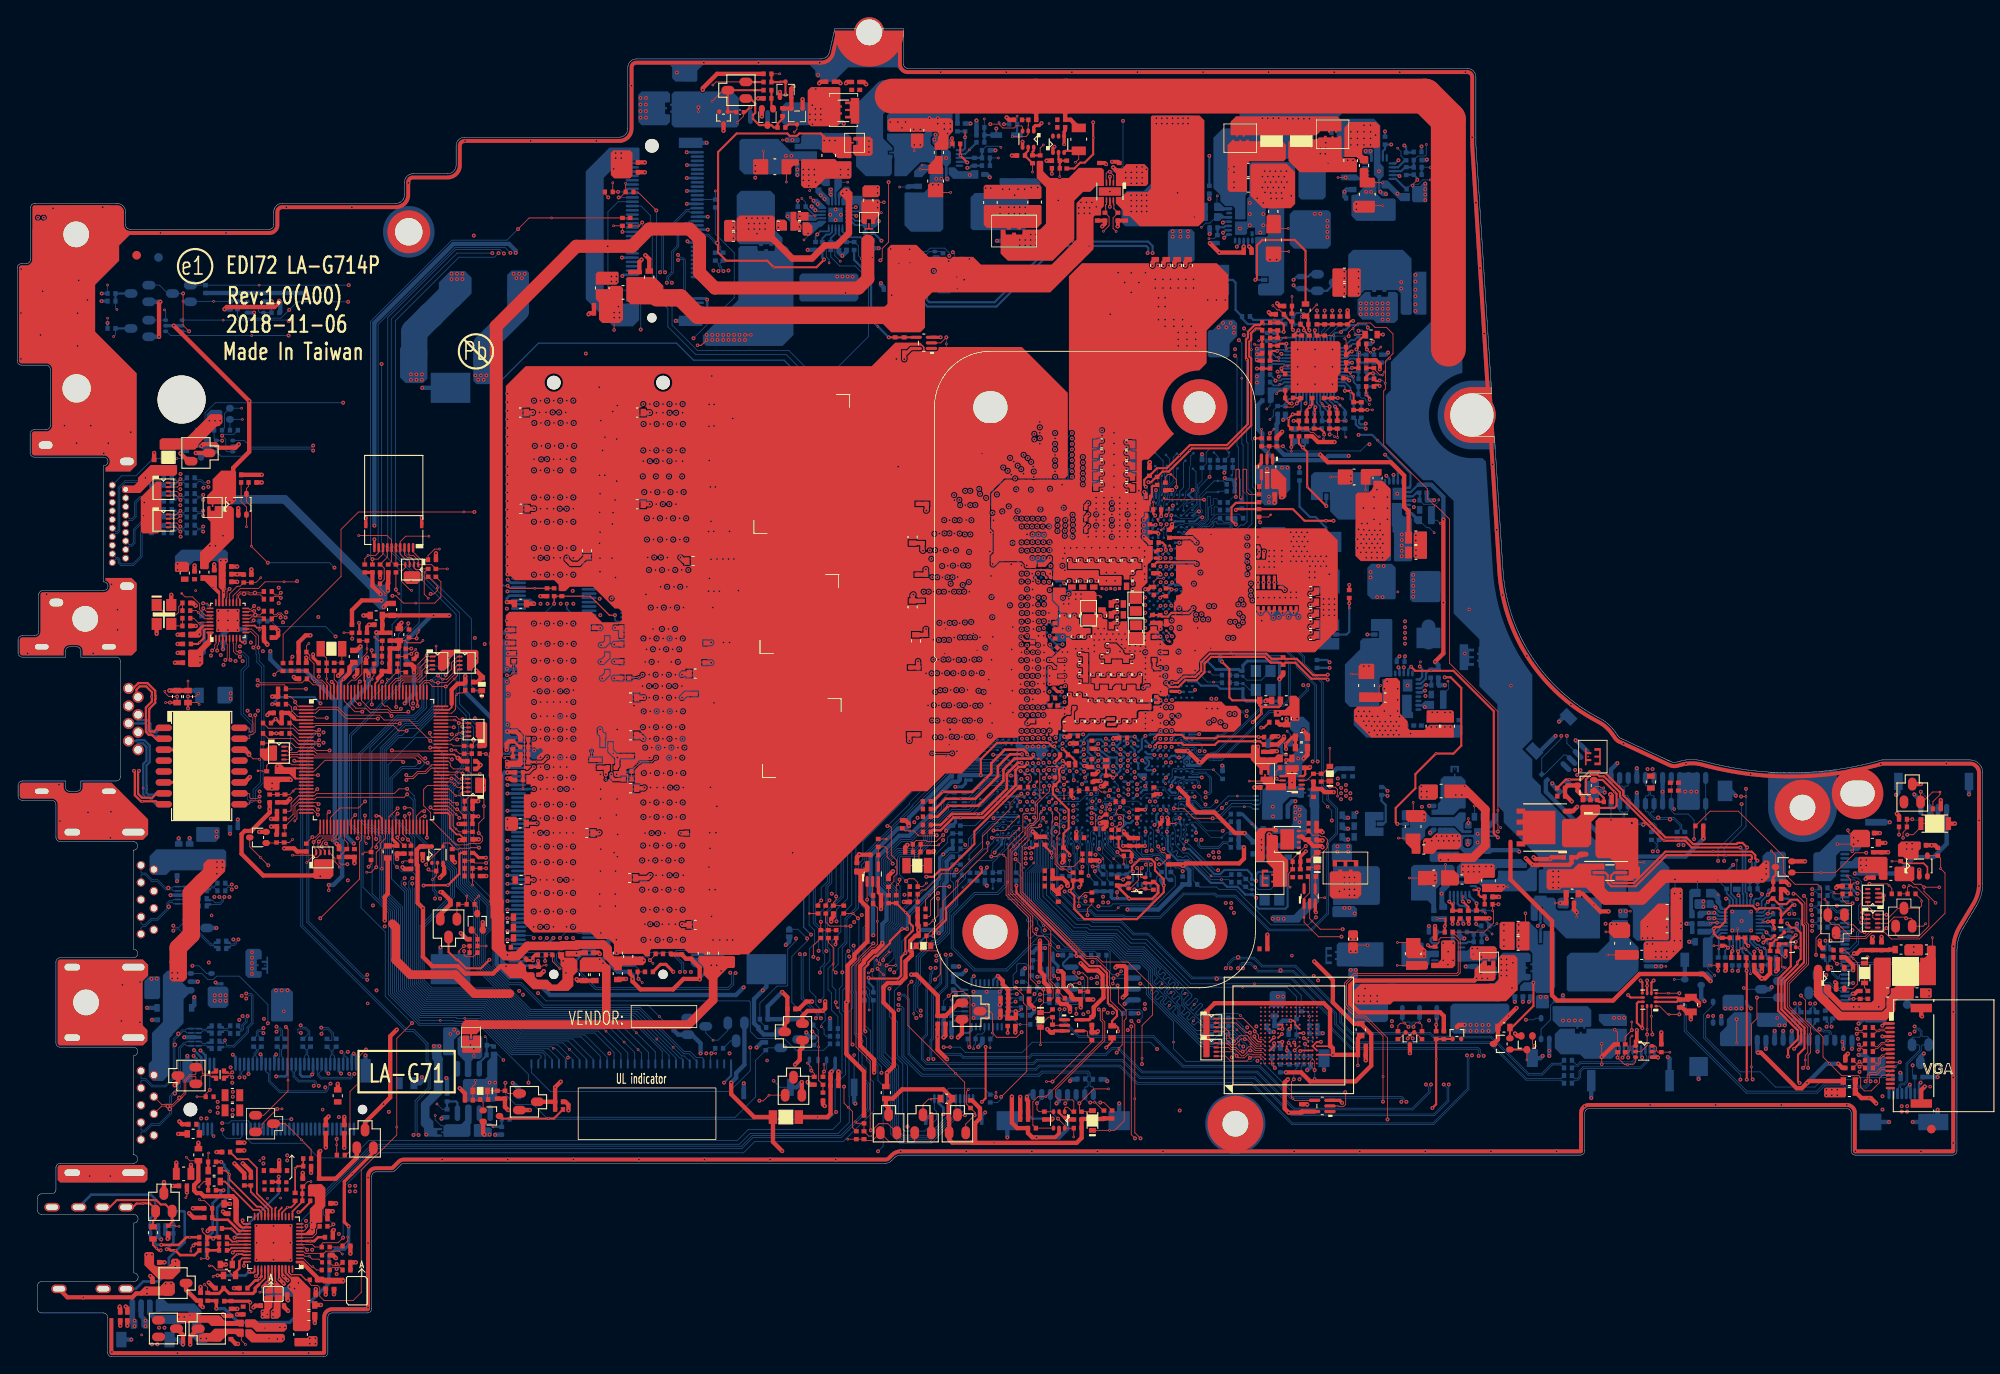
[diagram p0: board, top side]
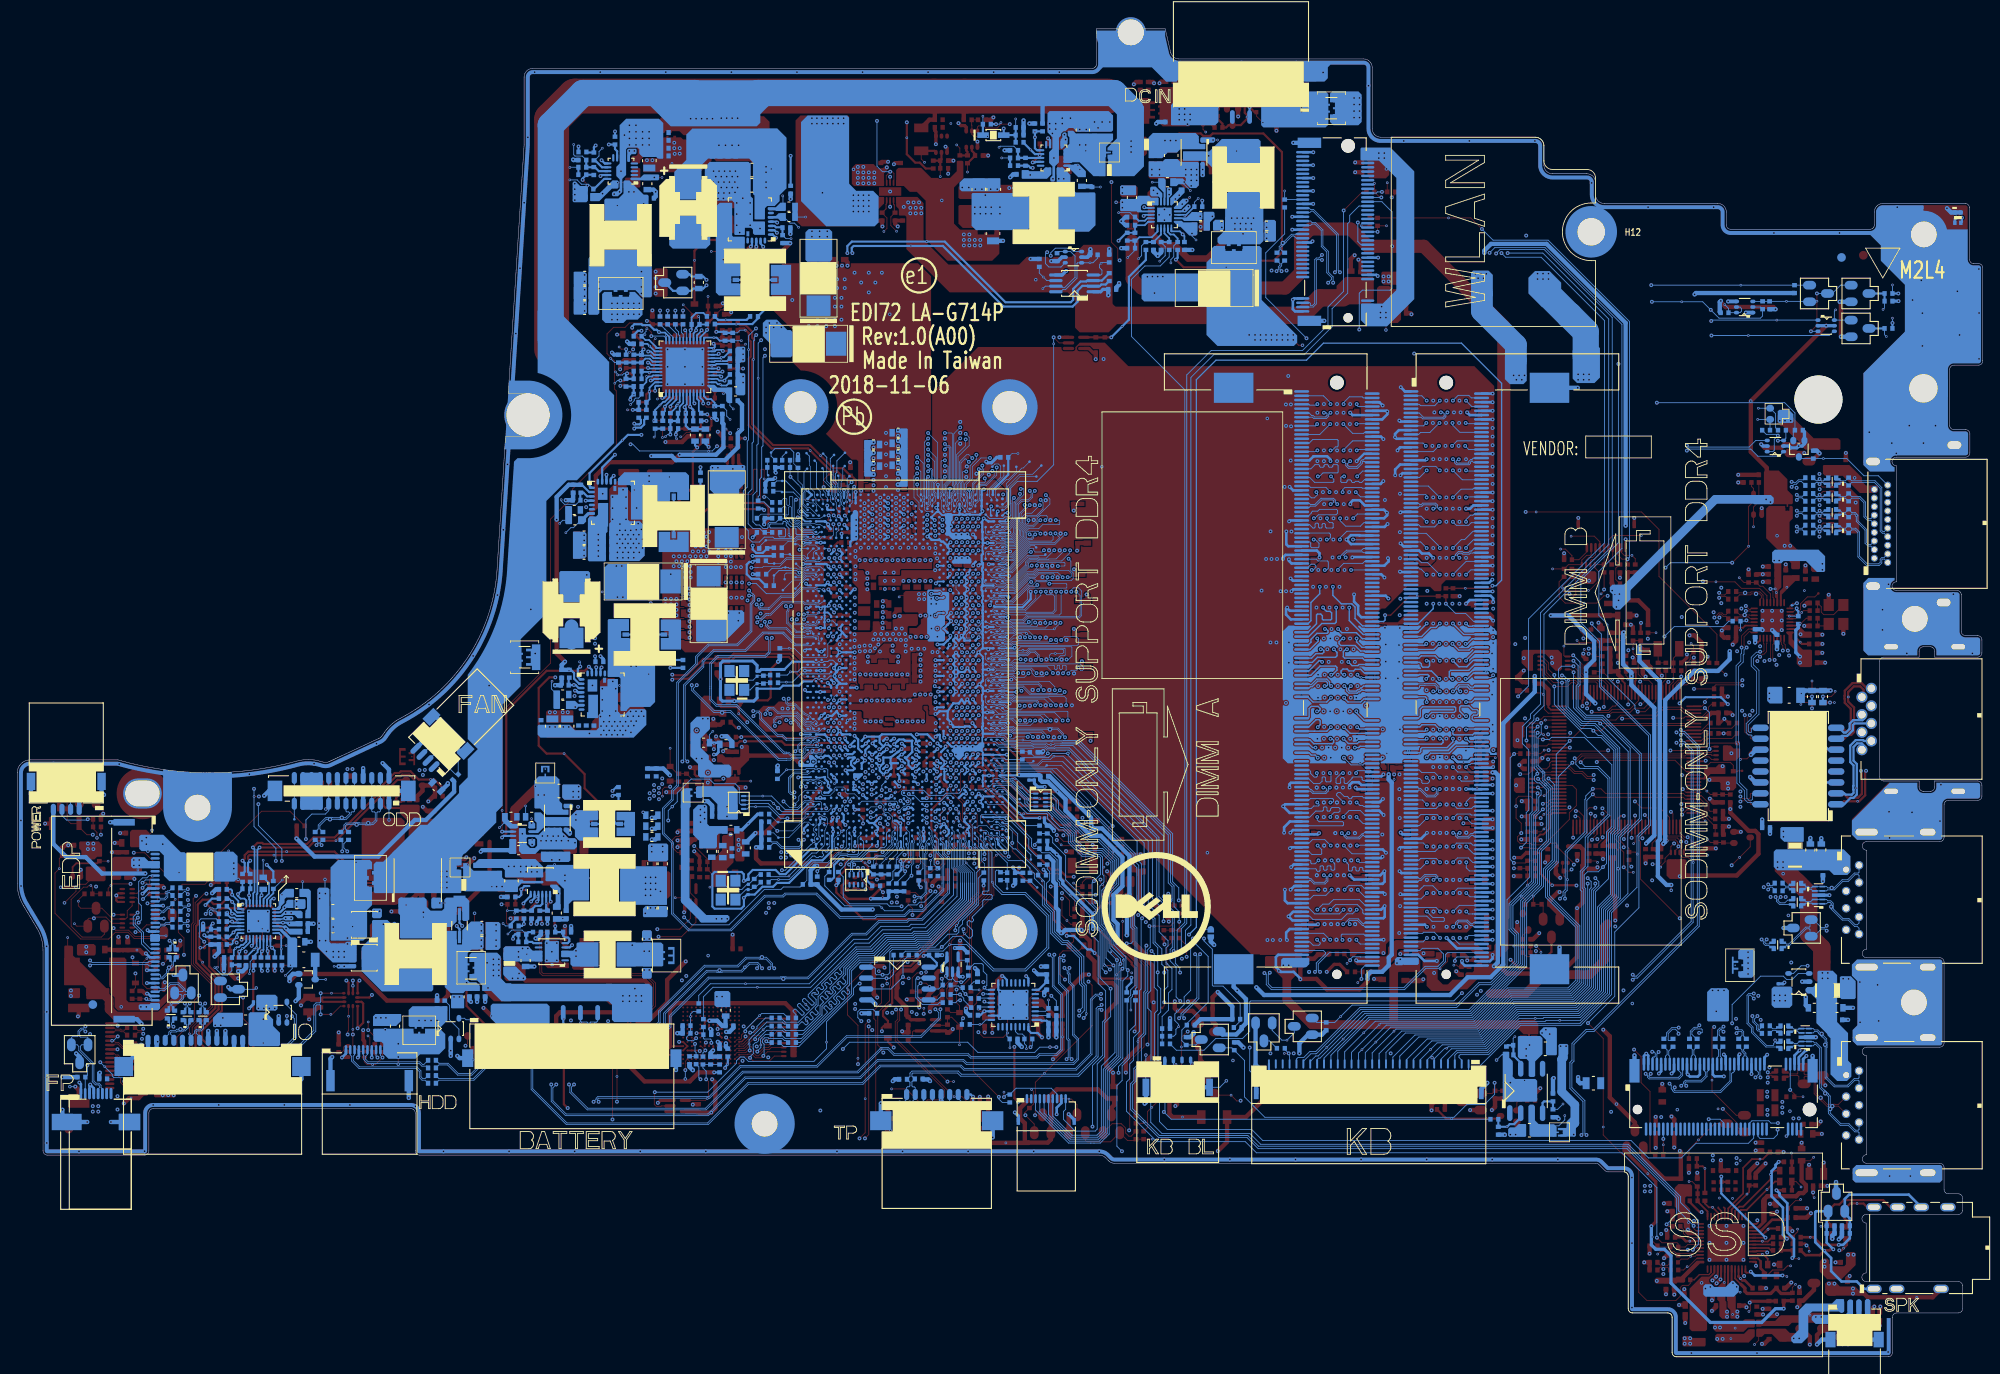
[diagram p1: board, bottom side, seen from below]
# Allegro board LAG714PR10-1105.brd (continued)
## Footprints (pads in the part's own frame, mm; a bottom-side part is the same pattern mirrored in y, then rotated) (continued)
SN74AHC1G08DCKR_SC70-5
  oval 0.381x1.295 smd: 1(0,0.15) 2(0.65,0.15) 3(1.3,0.15) 4(1.3,1.89) 5(0,1.89)
SOLDER_PREFORMS_0603-NPM
  rect 1.118x1.397 smd: 1(0,0) 2(1.422,0)
SW_TST71-N-220-T170-S017_2P
  rect 0.61x1.499 smd: 1(0,0) 2(3.2,0)
SY6288C20AAC_SOT23-5
  oval 0.559x0.787 smd: 1(0,0) 2(0.95,0) 3(1.9,0) 4(1.9,2.4) 5(0,2.4)
SY6288D20AAC_SOT23-5
  oval 0.559x0.787 smd: 1(0,0) 2(0.95,0) 3(1.9,0) 4(1.9,2.4) 5(0,2.4)
SY8286BRAC_QFN20_3X3
  oval 0.889x0.254 smd: 1(0,0) 2(0,-0.45) 3(0,-0.9) 4(0,-1.35) 5(0,-1.8) 11(3.1,-1.8) 12(3.1,-1.35) 13(3.1,-0.9) 14(3.1,-0.45) 15(3.1,0)
  oval 0.254x0.889 smd: 6(0.65,-2.45) 7(1.1,-2.45) 8(1.55,-2.45) 9(2,-2.45) 10(2.45,-2.45) 16(2.45,0.65) 17(2,0.65) 18(1.55,0.65) 19(1.1,0.65) 20(0.65,0.65)
  rect 0.991x0.991 smd: 21(1.55,-0.9)
SY8288CRAC_QFN20_3X3
  oval 0.889x0.254 smd: 1(0,0) 2(0,-0.45) 3(0,-0.9) 4(0,-1.35) 5(0,-1.8) 11(3.1,-1.8) 12(3.1,-1.35) 13(3.1,-0.9) 14(3.1,-0.45) 15(3.1,0)
  oval 0.254x0.889 smd: 6(0.65,-2.45) 7(1.1,-2.45) 8(1.55,-2.45) 9(2,-2.45) 10(2.45,-2.45) 16(2.45,0.65) 17(2,0.65) 18(1.55,0.65) 19(1.1,0.65) 20(0.65,0.65)
  rect 0.991x0.991 smd: 21(1.55,-0.9)
TAI-T_HCB2012KF-121T50_2P
  rect 0.813x1.397 smd: 1(0,0) 2(1.702,0)
THGBMBG8D4KBAIRNHDI_VFBGA_153P
  round 0.229 smd: A1(0,0) A2(0.5,0) A3(1,0) A4(1.5,0) A5(2.001,0) A6(2.501,0) A7(3.001,0) A8(3.501,0) A9(4.001,0) A10(4.501,0) A11(5.001,0) A12(5.501,0) A13(6.002,0) A14(6.502,0) B1(0,-0.5) B2(0.5,-0.5) B3(1,-0.5) B4(1.5,-0.5) B5(2.001,-0.5) B6(2.501,-0.5) B7(3.001,-0.5) B8(3.501,-0.5) B9(4.001,-0.5) B10(4.501,-0.5) B11(5.001,-0.5) B12(5.501,-0.5) B13(6.002,-0.5) B14(6.502,-0.5) C1(0,-1) C2(0.5,-1) C3(1,-1) C4(1.5,-1) C5(2.001,-1) C6(2.501,-1) C7(3.001,-1) C8(3.501,-1) C9(4.001,-1) C10(4.501,-1) C11(5.001,-1) C12(5.501,-1) C13(6.002,-1) C14(6.502,-1) D1(0,-1.5) D2(0.5,-1.5) D3(1,-1.5) D4(1.5,-1.5) D12(5.501,-1.5) D13(6.002,-1.5) D14(6.502,-1.5) E1(0,-2.001) E2(0.5,-2.001) E3(1,-2.001) E5(2.001,-2.001) E6(2.501,-2.001) E7(3.001,-2.001) E8(3.501,-2.001) E9(4.001,-2.001) E10(4.501,-2.001) E12(5.501,-2.001) E13(6.002,-2.001) E14(6.502,-2.001) F1(0,-2.501) F2(0.5,-2.501) F3(1,-2.501) F5(2.001,-2.501) F10(4.501,-2.501) F12(5.501,-2.501) F13(6.002,-2.501) F14(6.502,-2.501) G1(0,-3.001) G2(0.5,-3.001) G3(1,-3.001) G5(2.001,-3.001) G10(4.501,-3.001) G12(5.501,-3.001) G13(6.002,-3.001) G14(6.502,-3.001) H1(0,-3.501) H2(0.5,-3.501) H3(1,-3.501) H5(2.001,-3.501) H10(4.501,-3.501) H12(5.501,-3.501) H13(6.002,-3.501) H14(6.502,-3.501) J1(0,-4.001) J2(0.5,-4.001) J3(1,-4.001) J5(2.001,-4.001) J10(4.501,-4.001) J12(5.501,-4.001) J13(6.002,-4.001) J14(6.502,-4.001) K1(0,-4.501) K2(0.5,-4.501) K3(1,-4.501) K5(2.001,-4.501) K6(2.501,-4.501) K7(3.001,-4.501) K8(3.501,-4.501) K9(4.001,-4.501) K10(4.501,-4.501) K12(5.501,-4.501) K13(6.002,-4.501) K14(6.502,-4.501) L1(0,-5.001) L2(0.5,-5.001) L3(1,-5.001) L12(5.501,-5.001) L13(6.002,-5.001) L14(6.502,-5.001) M1(0,-5.501) M2(0.5,-5.501) M3(1,-5.501) M4(1.5,-5.501) M5(2.001,-5.501) M6(2.501,-5.501) M7(3.001,-5.501) M8(3.501,-5.501) M9(4.001,-5.501) M10(4.501,-5.501) M11(5.001,-5.501) M12(5.501,-5.501) M13(6.002,-5.501) M14(6.502,-5.501) N1(0,-6.002) N2(0.5,-6.002) N3(1,-6.002) N4(1.5,-6.002) N5(2.001,-6.002) N6(2.501,-6.002) N7(3.001,-6.002) N8(3.501,-6.002) N9(4.001,-6.002) N10(4.501,-6.002) N11(5.001,-6.002) N12(5.501,-6.002) N13(6.002,-6.002) N14(6.502,-6.002) P1(0,-6.502) P2(0.5,-6.502) P3(1,-6.502) P4(1.5,-6.502) P5(2.001,-6.502) P6(2.501,-6.502) P7(3.001,-6.502) P8(3.501,-6.502) P9(4.001,-6.502) P10(4.501,-6.502) P11(5.001,-6.502) P12(5.501,-6.502) P13(6.002,-6.502) P14(6.502,-6.502)
TPC12
  round 0.305 smd: 1(0,0)
TPCA8059-H_PPAK56-8-5
  oval 0.61x1.27 smd: 1(0,0) 2(1.27,0) 3(2.54,0) 4(3.81,0)
  custom 1.105x1.105 smd: 5(1.905,3.715)
TPS22961DNYR_WSON8
  oval 0.305x0.508 smd: 1(0,0) 2(0.65,0) 3(1.3,0) 4(1.95,0) 5(1.95,2.7)
  oval 1.6x0.508 smd: 6(0.65,2.7)
  rect 2.388x1.6 smd: 7(0.975,1.35)
TPS22967DSGR_SON8_2X2-S
  oval 0.254x0.787 smd: 1(0,0) 2(0.5,0) 3(1,0) 4(1.5,0) 5(1.5,2.2) 6(1,2.2) 7(0.5,2.2) 8(0,2.2)
  rect 1.6x0.889 smd: 9(0.75,1.1)
TVNST52302AB0_SOT523-3
  oval 0.508x0.559 smd: 1(0,0) 2(-0.5,-1.4) 3(0.5,-1.4)
W25Q128FVSIQ_SO8
  oval 0.635x1.676 smd: 1(0,0) 2(1.27,0) 3(2.54,0) 4(3.81,0) 5(3.81,7.25) 6(2.54,7.25) 7(1.27,7.25) 8(0,7.25)
Y_7V25000014_4P
  rect 1.397x1.194 smd: 1(0,0) 2(2.2,0) 3(2.2,1.7) 4(0,1.7)
Y_X1A000141000200_2P
  rect 0.991x1.803 smd: 1(0,0) 2(2.5,0)
Y_X3G024000DC1H_4P
  rect 1.397x1.194 smd: 1(0,0) 2(2.2,0) 3(2.2,1.7) 4(0,1.7)
YUQIU_PJ753-F07J1BE-B_7P-T
  oval 0.991x1.803 hole 0.61x1.397: 1(0,0) 2(9.5,-5.5) 3(9.5,-8.6) 4(0,-7.8) 5(9.5,0) 6(9.5,-2.75) 7(0,-2.65)

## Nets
0.6V_DDR_VTT_ON: CC90.1 PRM09.1 RC9.2 UC2.4
1.0V_VCCST_EN: CZ1.1 DZ5.2 RZ1.2 UZ1.3
1.2V_VTT_PWRGD: PRM06.2 PUM01.10 RC106.1
2.5V_VIN: PC2501.1 PJP2501.2 PU2501.3
3.3V_TS_EN: R72.1 U3.4 UC1.AP5
3V_FB: PC315.1 PR307.2 PR308.1 PU301.13
3V_SN: PC309.1 PR305.2
3V_VIN: PC301.1 PC302.1 PC303.1 PC304.1 PC305.1 PC306.1 PJP301.2 PL311.2 PU301.2 PU301.3 PU301.4 PU301.5
5V_FB: PC517.1 PR510.2 PR511.1 PU501.13
5V_SN: PC509.1 PR505.2
5V_VIN: PC501.1 PC502.1 PC503.1 PC504.1 PC505.1 PC506.1 PJP501.2 PL511.2 PU501.2 PU501.3 PU501.4 PU501.5
+0.6V_DDR_VTT: CD5.1 CD6.1 CD7.1 CD8.1 CD31.1 CD32.1 CD33.1 CD34.1 JDIMM1.258 JDIMM2.258 PJPM03.2
+0.6VSP: PCM20.1 PCM21.1 PJPM03.1 PUM01.2 PUM01.20
+1.0V_AMPHYPLL: CC75.1 RC169.2 UC1.K15 UC1.L15
+1.0V_APLL: CC82.1 L1.2 UC1.V15
+1.0V_CLK2: CC76.1 RC170.2 UC1.K19
+1.0V_CLK4: CC84.1 RC173.2 UC1.N20
+1.0V_CLK5: CC77.1 RC76.2 RC171.2 UC1.L19
+1.0V_MPHYGT: CC59.1 CC60.1 CC73.1 RC169.1 RC174.2 UC1.N15 UC1.N16 UC1.N17 UC1.P15 UC1.P16
+1.0V_PRIM: CC55.1 CC57.1 CC58.1 CC62.1 CC63.1 CC72.1 CC83.1 CC87.1 CE17.1 CZ4.1 CZ21.1 L1.1 PJPH02.2 RC149.1 RC170.1 RC171.1 RC173.1 RC174.1 UC1.A10 UC1.A14 UC1.AB17 UC1.AB19 UC1.AB20 UC1.AF18 UC1.AF19 UC1.AF20 UC1.AF21 UC1.AK20 UC1.K17 UC1.L1 UC1.L21 UC1.N18 UC1.P18 UC1.T1 UC1.T19 UC1.T20 UC1.V20 UC1.V21 UC1.Y18 UE1.95 UZ1.1 UZ1.2 UZ2.1 UZ2.2 UZ2.7
+1.0V_VCCST: CC41.1 CC44.1 JP2.1 PCZ24.1 PRZ40.1 PRZ41.1 PRZ42.1 PRZ43.1 RC104.2 RC111.1 RC112.1 RC138.2 RC152.1 RC154.1 RZ4.2 UC1.A18 UC1.K20 UC1.K21
+1.0V_VCCST_C: CZ2.1 JP2.2 UZ1.7 UZ1.8
+1.0V_VCCSTG: CC42.1 CZ6.1 JP1.1 RC113.1 RC140.2 RC141.2 RC142.2 RZ4.1 UC1.A22 UC1.G20 UZ2.6
+1.0V_XDP: RC143.1 RC149.2
+1.0VS_VCCIO: CC45.1 CC46.1 CC47.1 CC48.1 CC49.1 CC50.1 CC51.1 CC52.1 CC53.1 CC54.1 CZ8.1 JP1.2 RC4.1 UC1.AK28 UC1.AK30 UC1.AL30 UC1.AL42 UC1.AM28 UC1.AM30 UC1.AM42
+1.2V_DDR: CC1.1 CC26.1 CC27.1 CC28.1 CC29.1 CC30.1 CC31.1 CC32.1 CC33.1 CC34.1 CC35.1 CC36.1 CC37.1 CC38.1 CC39.1 CC40.1 CC43.1 CD11.1 CD12.1 CD13.1 CD14.1 CD15.1 CD16.1 CD17.1 CD18.1 CD19.1 CD20.1 CD21.1 CD22.1 CD23.1 CD24.1 CD25.1 CD26.1 CD27.1 CD41.1 CD42.1 CD43.1 CD44.1 CD45.1 CD46.1 CD47.1 CD48.1 CD49.1 CD50.1 CD51.1 CD52.1 CD53.1 CD54.1 CD55.1 CD56.1 JDIMM1.12 JDIMM1.33 JDIMM1.54 JDIMM1.75 JDIMM1.96 JDIMM1.111 JDIMM1.112 JDIMM1.117 JDIMM1.118 JDIMM1.123 JDIMM1.124 JDIMM1.129 JDIMM1.130 JDIMM1.135 JDIMM1.136 JDIMM1.141 JDIMM1.142 JDIMM1.147 JDIMM1.148 JDIMM1.153 JDIMM1.154 JDIMM1.159 JDIMM1.160 JDIMM1.163 JDIMM1.178 JDIMM1.199 JDIMM1.220 JDIMM1.241 JDIMM2.12 JDIMM2.33 JDIMM2.54 JDIMM2.75 JDIMM2.96 JDIMM2.111 JDIMM2.112 JDIMM2.117 JDIMM2.118 JDIMM2.123 JDIMM2.124 JDIMM2.129 JDIMM2.130 JDIMM2.135 JDIMM2.136 JDIMM2.141 JDIMM2.142 JDIMM2.147 JDIMM2.148 JDIMM2.153 JDIMM2.154 JDIMM2.159 JDIMM2.160 JDIMM2.163 JDIMM2.178 JDIMM2.199 JDIMM2.220 JDIMM2.241 PJPM02.2 RD7.1 RD10.1 RD20.1 RD23.1 RD24.1 UC1.AL23 UC1.AM40 UC1.AU23 UC1.AU28 UC1.AU35 UC1.AU42 UC1.BB23 UC1.BB32 UC1.BB41 UC1.BB47 UC1.BB51 UC2.5
+1.2VP: PCM05.1 PCM06.1 PCM07.1 PCM08.1 PCM09.1 PCM10.1 PCM17.2 PCM18.1 PJPM02.1 PLM01.1 PRM10.2 PUM01.5 PUM01.19
+1.8V_AVDD: CA12.1 RA5.2 UA1.40
+1.8V_CPVDD: CA14.1 RA6.2 UA1.36
+1.8V_EMMC: CM3.1 CM4.1 RM2.2 RM3.1 RPM1.1 RPM1.2 RPM1.3 RPM1.4 RPM2.1 RPM2.2 RPM2.3 RPM2.4 UM1.C6 UM1.M4 UM1.N4 UM1.P3 UM1.P5
+1.8V_PRIM: CC68.1 CC86.1 PJP1802.2 QA1.1 R23.1 RC14.1 RC51.1 RC53.1 RC137.1 RE66.1 RM2.1 RM27.1 UC1.AA1 UC1.AF16 UC1.AK15
+1.8VALW_EC: CE15.1 RE66.2 UE1.54
+1.8VALWP: PC1802.1 PC1803.1 PC1804.1 PC1807.1 PJP1802.1 PL1801.2 PR1807.1
+1VALWP: PCH05.1 PCH06.1 PCH07.1 PCH08.1 PCH14.1 PJPH02.1 PLH01.2 PRH08.2
+2.5V_MEM: CD1.1 CD2.1 CD3.1 CD4.1 CD35.1 CD36.1 CD37.1 CD38.1 JDIMM1.257 JDIMM1.259 JDIMM2.257 JDIMM2.259 PJP2502.2
+2.5VP: PC2502.1 PC2505.1 PJP2502.1 PR2502.1 PU2501.6
+3.3V_ALW_DSW: Q15.1 RC85.1 RC89.2 RC90.2 RC93.1 RC163.2 RE12.1 UC1.AD17 UC1.AD18 UC1.AJ17
+3.3V_HDA: CC61.1 L2.2 UC1.AJ19
+3.3V_SPI: CC3.1 RC17.2 RC18.1 RC19.1 RC20.1 RC139.1 RX4.1 RX7.1 UC1.AJ16 UC3.8
+3.3V_WLAN: CW6.1 CW7.1 CW8.1 CW9.1 JWLAN1.2 JWLAN1.4 JWLAN1.72 JWLAN1.74 RW3.1 RW5.2
+3V_DVDD: CA5.1 CA6.1 CA15.1 CA16.1 CA17.1 RA2.2 RA3.2 RA8.1 UA1.1 UA1.9
+3V_EMMC: CM1.1 CM2.1 CM7.1 RM1.2 UM1.E6 UM1.F5 UM1.J10 UM1.K9 UM2.5
+3VALW: CC11.1 CC12.1 CC13.1 CC85.1 CL9.1 CX1.1 CX2.1 CZ25.1 JP4.1 JP11.2 JPWR1.4 PJP302.2 PJP1801.1 PJP2501.1 PL1811.1 PR5.2 PR33.1 PR41.2 PR1803.1 PRB30.1 PRB42.2 PRH03.1 PRH05.1 PRM06.1 Q15.3 Q17.2 Q17.5 R35.1 R43.1 R65.1 R66.1 RA11.2 RC63.1 RC88.2 RC92.2 RC163.1 RE2.1 RE15.2 RE17.2 RE18.2 RE21.2 RE25.1 RE40.2 RE46.1 RE49.1 RE55.1 RE56.1 RE57.1 RE58.1 RE59.1 RL7.1 RM1.1 RPE1.5 RPE1.6 RPE1.7 RPE1.8 RPE2.5 RPE2.6 RPE2.7 RPE2.8 RPE3.1 RPE3.2 RPE3.3 RPE3.4 RPE4.1 RPE4.2 RPE4.3 RPE4.4 RPE5.1 RPE5.2 RPE5.3 RPE5.4 RPE6.1 RPE6.2 RPE6.3 RPE6.4 RPE7.5 RPE7.6 RPE7.7 RPE7.8 RW5.1 UC5.5 UC6.5 UC7.5 UC9.5 UL2.5 UX1.1 UZ3.6 UZ3.7
+3VALW_EC: CE5.1 CE6.1 CE7.2 CE8.2 CE9.1 CE10.1 CE11.1 CE12.1 CE13.1 CE20.1 CE21.1 JESPI1.1 JESPI1.2 RE1.1 RE2.2 RE3.1 RE8.2 RE9.2 RE10.2 RE11.2 RE14.2 UE1.5 UE1.19 UE1.22 UE1.43 UE1.65 UE1.82 UE1.103 UE1.115
+3VALW_PCH: CC67.1 CC78.1 CC79.1 JP4.2 L2.1 RC17.1 RC33.2 RC34.2 RC37.2 RC38.2 RC39.2 RC44.1 RC45.2 RC46.2 RC47.2 RC128.1 RC129.1 RPC1.5 RPC1.6 RPC1.7 RPC1.8 RPC3.5 RPC3.6 RPC3.7 RPC3.8 UC1.AD15 UC1.AG15 UC1.AJ21 UC1.AK17 UC1.T16 UC1.V19 UC1.Y15 UC1.Y16
+3VALWP: PC310.1 PC311.1 PC312.1 PC313.1 PC314.1 PJP302.1 PL301.2 PR304.1 PR306.2 PR307.1 PR504.1 PU301.14
+3VLP: D1.2 PC308.1 PU301.16 PU301.17 R42.1 RE29.2
+3VS: C17.1 C21.1 CD9.1 CD10.1 CD39.1 CD40.1 CE22.1 CS29.1 CS30.1 CW3.1 CW4.1 CW5.1 CX3.1 CX4.1 CZ12.1 JDIMM1.255 JDIMM2.255 JIOB1.12 JP10.2 JVGA.14 JVGA.15 PRZ16.1 Q6.2 Q10.2 Q10.5 Q11.2 Q11.5 QA1.2 QC1.2 QC1.5 QI2.2 QI2.5 QI3.2 R5.1 R7.1 R11.1 R16.1 R24.1 R28.1 R29.1 R33.1 R34.1 R36.1 R48.1 R49.1 R50.2 R57.1 R79.1 R80.1 RA2.1 RC1.2 RC2.2 RC3.2 RC9.1 RC27.1 RC28.1 RC35.1 RC36.1 RC42.1 RC55.1 RC57.1 RC69.2 RC72.1 RC73.1 RC86.1 RC105.1 RC114.1 RC115.1 RC181.1 RC188.1 RC194.2 RC195.1 RC205.2 RC207.2 RC209.1 RC212.2 RC213.2 RD1.1 RD2.1 RD3.1 RD13.1 RD14.1 RD15.1 RE13.2 RI15.1 RL3.1 RS3.1 RW3.2 RX6.1 U1.5 U2.1 UC4.5 UE2.5 US1.2 US1.3 US1.9 US1.10 UX1.8 UZ3.8 UZ3.9
+3VS_CAM: C14.1 C15.1 JEDP1.29 R16.2
+3VS_SSD: CS24.1 CS25.1 CS26.1 CS27.1 CS33.1 CS34.1 CS35.1 CS36.1 JP10.1 JSSD1.2 JSSD1.4 JSSD1.12 JSSD1.14 JSSD1.16 JSSD1.18 JSSD1.70 JSSD1.72 JSSD1.74 RS2.2
+5V_AVDD: CA10.1 CA11.1 RA4.2 UA1.26
+5V_HDD: CS5.1 CS6.1 CS7.1 JHDD1.10 JHDD1.11 JHDD1.12 JP5.2 RS4.1 US2.1
+5V_HDMI: CI9.1 FI1.1 JHDMI1.18
+5V_KB_BL: C34.1 EC3002.1 F3.1 JKBBL1.1
+5V_PVDD: CA1.1 CA2.1 CA3.1 CA4.1 RA1.2 UA1.41 UA1.46
+5VALW: CU5.1 CU16.1 CZ5.1 CZ22.1 CZ23.1 PCA08.1 PCG11.1 PCI11.1 PCI31.1 PD2.3 PD3.3 PJP502.2 PR4.1 PR2504.1 PRG02.1 PRH11.1 PRI02.1 PRI22.1 PRM04.1 PRM05.2 PRZ39.1 PRZ57.1 PUA01.4 PUG01.15 PUI01.2 PUI01.15 PUI02.2 PUI02.15 Q18.3 Q19.3 UU1.5 UU3.5 UZ1.4 UZ2.3 UZ3.1 UZ3.2 UZ3.4
+5VALWP: PC510.1 PC511.1 PC512.1 PC513.1 PC514.1 PJP502.1 PL501.2 PR509.2 PR510.1 PU501.14
+5VS: C30.1 CS8.1 CZ9.1 DI1.1 F3.2 FI1.2 JFAN1.1 JP5.1 JP6.1 JVGA.16 Q7.3 QI1.2 R4.1 R12.1 RA1.1 RA4.1 RS5.2 US2.5 UZ3.13 UZ3.14
+5VS_ODD: CS13.1 CS14.1 CS15.1 JODD1.17 JODD1.18 JODD1.19 JODD1.20 JODD1.21 JODD1.22 JP6.2
+17.4V_BATT+: PC11.1 PCB19.1 PCB20.1 PCB21.1 PCB22.1 PCB23.1 PCB24.1 PJP3.1 PL4.1 PQB08.3 PRB01.4 PRB10.1 PRB28.2
+17.4V_BATT++: PBATT1.8 PBATT1.9 PBATT1.10 PC12.1 PJP3.2 PL4.2
+19V_ADPIN: PC1.1 PC2.1 PC15.1 PJP1.1 PJPDC1.5 PJPDC1.6 PL1.1
+19VB: F1.1 PJP301.1 PJP501.1 PJPB01.1 PJPG01.1 PJPH01.1 PJPI01.1 PJPM01.1 PL311.1 PL511.1 PLB02.1 PLG11.1 PLH11.1 PLI11.1 PLM11.1 PQB13.5 PR302.2 PRB02.4
+19VB_1.2V: PCM01.1 PCM02.1 PCM03.1 PCM04.1 PCM22.1 PCM23.1 PJPM01.2 PLM11.2 PQM01.2 PQM01.3 PQM01.4 PQM01.10 PRM07.1
+19VB_+1VALW: PCH01.1 PCH02.1 PCH03.1 PCH04.1 PCH15.1 PCH16.1 PJPH01.2 PLH11.2 PUH01.5
+19VB_CPU: PCI01.1 PCI02.1 PCI03.1 PCI04.1 PCI05.1 PCI06.1 PCI07.1 PCI08.1 PCI13.1 PCI14.1 PCI21.1 PCI22.1 PCI23.1 PCI24.1 PCI25.1 PCI26.1 PCI27.1 PCI28.1 PJPA01.1 PJPI01.2 PLI11.2 PRZ35.1 PUI01.8 PUI01.9 PUI02.8 PUI02.9
+VCC_CORE: PCI101.1 PCI102.1 PCI103.1 PCI104.1 PCI105.1 PCI106.1 PCI107.1 PCI108.1 PCI109.1 PCI110.1 PCI111.1 PCI112.1 PCI113.1 PCI114.1 PCI115.1 PCI116.1 PCI117.1 PCI118.1 PCI119.1 PCI120.1 PCI121.1 PCI122.1 PCI123.1 PCI124.1 PCI125.1 PCI126.1 PCI127.1 PCI128.1 PCI129.1 PCI130.1 PCI131.1 PCI132.1 PCI133.1 PCI134.1 PCI135.1 PCI136.1 PCI137.1 PCI138.1 PCI139.1 PCI140.1 PCI141.1 PCI142.1 PCI143.1 PCI144.1 PCI145.1 PCI146.1 PCI147.1 PCI148.1 PCI149.1 PCI150.1 PCI151.1 PCI152.1 PCI153.1 PCI154.1 PCI155.1 PCI156.1 PCI157.1 PCI158.1 PCI159.1 PCI160.1 PCI161.1 PCI162.1 PCI163.1 PCI164.1 PCI165.1 PCI171.1 PCI172.1 PCI173.1 PLI01.4 PLI02.4 PRC01.1 PRC03.1 PRC04.1 PRC06.1 RC150.1 UC1.A30 UC1.A34 UC1.A39 UC1.A44 UC1.AK33 UC1.AK35 UC1.AK37 UC1.AK38 UC1.AK40 UC1.AL33 UC1.AL37 UC1.AL40 UC1.AM32 UC1.AM33 UC1.AM35 UC1.AM37 UC1.AM38 UC1.G30 UC1.G32 UC1.G33 UC1.G35 UC1.G37 UC1.G38 UC1.G40 UC1.G42 UC1.J30 UC1.J33 UC1.J37 UC1.J40 UC1.K33 UC1.K35 UC1.K37 UC1.K38 UC1.K40 UC1.K42 UC1.K43
+VCC_CORE_42: PCC01.1 PCC02.1 PRC01.2 PRC04.2 PRC7.2 UC1.AK42 UC1.AK43 UC1.AK45 UC1.AK46 UC1.AK48 UC1.AK50 UC1.AL43 UC1.AL46 UC1.AL50 UC1.AM48 UC1.AM50 UC1.AM52
+VCC_CORE_G0: TP32.1(TP-1) UC1.K32
+VCC_CORE_G1: TP33.1(TP-1) UC1.AK32
+VCC_GT: PCG101.1 PCG102.1 PCG103.1 PCG104.1 PCG105.1 PCG106.1 PCG107.1 PCG108.1 PCG109.1 PCG110.1 PCG111.1 PCG112.1 PCG113.1 PCG114.1 PCG115.1 PCG116.1 PCG117.1 PCG118.1 PCG119.1 PCG120.1 PCG121.1 PCG122.1 PCG123.1 PCG124.1 PCG125.1 PCG126.1 PCG127.1 PCG128.1 PCG129.1 PCG130.1 PCG131.1 PCG132.1 PCG133.1 PCG134.1 PCG135.1 PCG136.1 PCG137.1 PCG138.1 PCG139.1 PCG140.1 PCG141.1 PCG142.1 PCG143.1 PCG144.1 PCG145.1 PCG146.1 PCG147.1 PCG148.1 PCG171.1 PCG172.1 PLG01.4 PRC02.1 PRC05.1 PRC7.1 RC155.1 RC443.1 UC1.A58 UC1.A62 UC1.A66 UC1.AA63 UC1.AA64 UC1.AA66 UC1.AA67 UC1.AA69 UC1.AA70 UC1.AA71 UC1.AC64 UC1.AC65 UC1.AC66 UC1.AC67 UC1.AC68 UC1.AC69 UC1.AC70 UC1.AC71 UC1.AK53 UC1.AK55 UC1.AK56 UC1.AK58 UC1.AK60 UC1.AK70 UC1.AL53 UC1.AL56 UC1.AL60 UC1.AM53 UC1.AM56 UC1.AM58 UC1.AU58 UC1.AU63 UC1.BB57 UC1.BB66 UC1.J53 UC1.J55 UC1.J56 UC1.J58 UC1.J60 UC1.K53 UC1.K55 UC1.K56 UC1.K58 UC1.K60 UC1.L62 UC1.L63 UC1.L64 UC1.L65 UC1.L66 UC1.L67 UC1.L68 UC1.L69 UC1.L70 UC1.L71 UC1.M62 UC1.N63 UC1.N64 UC1.N66 UC1.N67 UC1.N69 UC1.N70 UC1.N71 UC1.R63 UC1.R64 UC1.R65 UC1.R66 UC1.R67 UC1.R68 UC1.R69 UC1.R70 UC1.R71 UC1.T62 UC1.U65 UC1.U68 UC1.U71 UC1.W63 UC1.W64 UC1.W65 UC1.W66 UC1.W67 UC1.W68 UC1.W69 UC1.W70 UC1.W71 UC1.Y62
+VCC_GT_42: PCC03.1 PCC04.1 PCC05.1 PCC6.1 PRC02.2 PRC03.2 PRC05.2 PRC06.2 RC157.1 UC1.A48 UC1.A53 UC1.J43 UC1.J45 UC1.J46 UC1.J48 UC1.J50 UC1.J52 UC1.K48 UC1.K50
+VCC_GT_AK52: RC443.2 UC1.AK52
+VCC_GT_K52: RC157.2 UC1.K52
+VCC_SA: PCA101.1 PCA102.1 PCA103.1 PCA104.1 PCA105.1 PCA106.1 PCA107.1 PCA108.1 PCA109.1 PCA110.1 PCA111.1 PCA112.1 PCA113.1 PCA114.1 PCA115.1 PCA116.1 PCA117.1 PCA118.1 PLA01.4 RC159.1 UC1.AK23 UC1.AK25 UC1.G23 UC1.G25 UC1.G27 UC1.G28 UC1.J22 UC1.J23 UC1.J27 UC1.K23 UC1.K25 UC1.K27 UC1.K28 UC1.K30
GND: C1.2 C2.2 C3.2 C4.2 C5.2 C12.2 C14.2 C15.2 C16.2 C17.2 C19.2 C21.2 C26.2 C27.2 C30.2 C31.2 C34.2 C35.2 C36.2 C37.2 C38.2 C39.2 C40.2 C41.2 CA1.2 CA2.2 CA3.2 CA4.2 CA5.2 CA6.2 CA9.2 CA13.2 CA14.2 CA15.2 CA16.2 CA17.2 CA22.1 CA25.1 CA27.2 CA28.2 CA29.2 CA30.2 CA38.1 CA40.2 CC1.2 CC2.1 CC3.2 CC4.2 CC5.2 CC6.2 CC7.2 CC8.2 CC9.2 CC10.2 CC11.2 CC12.2 CC13.2 CC14.2 CC15.2 CC17.2 CC18.2 CC26.2 CC27.2 CC28.2 CC29.2 CC30.2 CC31.2 CC32.2 CC33.2 CC34.2 CC35.2 CC36.2 CC37.2 CC38.2 CC39.2 CC40.2 CC41.2 CC42.2 CC43.2 CC44.2 CC45.2 CC46.2 CC47.2 CC48.2 CC49.2 CC50.2 CC51.2 CC52.2 CC53.2 CC54.2 CC55.2 CC56.2 CC57.2 CC58.2 CC59.2 CC60.2 CC61.2 CC62.2 CC63.2 CC67.2 CC68.2 CC69.2 CC70.2 CC71.2 CC72.2 CC73.2 CC75.2 CC76.2 CC77.2 CC78.2 CC79.2 CC82.2 CC83.2 CC84.2 CC85.2 CC86.2 CC87.2 CC88.2 CC90.2 CC91.2 CD1.2 CD2.2 CD3.2 CD4.2 CD5.2 CD6.2 CD7.2 CD8.2 CD9.2 CD10.2 CD11.2 CD12.2 CD13.2 CD14.2 CD15.2 CD16.2 CD17.2 CD18.2 CD19.2 CD20.2 CD21.2 CD22.2 CD23.2 CD24.2 CD25.2 CD26.2 CD27.2 CD28.2 CD29.2 CD31.2 CD32.2 CD33.2 CD34.2 CD35.2 CD36.2 CD37.2 CD38.2 CD39.2 CD40.2 CD41.2 CD42.2 CD43.2 CD44.2 CD45.2 CD46.2 CD47.2 CD48.2 CD49.2 CD50.2 CD51.2 CD52.2 CD53.2 CD54.2 CD55.2 CD56.2 CD58.2 CE3.2 CE4.2 CE5.2 CE6.2 CE7.1 CE8.1 CE9.2 CE10.2 CE11.2 CE12.2 CE13.2 CE14.2 CE15.2 CE16.2 CE17.2 CE19.2 CE20.2 CE22.2 CE23.2 CE24.2 CE26.2 CE28.2 CE31.2 CE32.1 CE33.2 CE35.1 CI9.2 CL5.2 CL6.2 CL7.2 CL8.2 CL9.2 CL10.2 CL11.2 CL12.2 CL13.2 CL15.2 CL18.2 CL19.2 CL20.2 CL22.2 CL23.2 CL24.2 CL25.2 CM1.2 CM2.2 CM3.2 CM4.2 CM5.2 CM6.2 CM7.2 CM8.1 CS5.2 CS6.2 CS7.2 CS8.2 CS13.2 CS14.2 CS15.2 CS24.2 CS25.2 CS26.2 CS27.2 CS29.2 CS30.2 CS33.2 CS34.2 CS35.2 CS36.2 CU5.2 CU6.2 CU8.2 CU9.2 CU10.2 CU11.2 CU13.2 CU14.2 CU15.2 CU16.2 CU17.2 CW3.2 CW4.2 CW5.2 CW6.2 CW7.2 CW8.2 CW9.2 CX1.2 CX2.2 CX3.2 CX4.2 CX5.2 CX6.2 CX7.2 CZ1.2 CZ2.2 CZ3.2 CZ4.2 CZ5.2 CZ6.2 CZ7.2 CZ8.2 CZ9.2 CZ10.2 CZ11.2 CZ12.2 CZ21.2 CZ22.2 CZ23.2 CZ25.2 DA1.1 DA2.1 DA4.1 DA5.1 DA6.1 DA7.1 DE1.2 EC2301.2 EC2302.2 EC2901.2 EC2902.2 EC3001.2 EC3002.2 EC3003.2 ED2901.1 EU2601.3 EU2602.1 EU2603.3 EU2604.1 EU2701.1 EU4012.1 H1.1(TP-1) H2.1(TP-1) H3.1(TP-1) H4.1(TP-1) H5.1(TP-1) H6.1(TP-1) H7.1(TP-1) H8.1(TP-1) H12.1(TP-1) H13.1(TP-1) HCPU1.1(TP-1) HCPU2.1(TP-1) HCPU3.1(TP-1) HCPU4.1(TP-1) JCMOS1.2 JDEG1.10 JDEG1.11 JDEG1.12 JDIMM1.1 JDIMM1.2 JDIMM1.5 JDIMM1.6 JDIMM1.9 JDIMM1.10 JDIMM1.14 JDIMM1.15 JDIMM1.18 JDIMM1.19 JDIMM1.22 JDIMM1.23 JDIMM1.26 JDIMM1.27 JDIMM1.30 JDIMM1.31 JDIMM1.35 JDIMM1.36 JDIMM1.39 JDIMM1.40 JDIMM1.43 JDIMM1.44 JDIMM1.47 JDIMM1.48 JDIMM1.51 JDIMM1.52 JDIMM1.56 JDIMM1.57 JDIMM1.60 JDIMM1.61 JDIMM1.64 JDIMM1.65 JDIMM1.68 JDIMM1.69 JDIMM1.72 JDIMM1.73 JDIMM1.77 JDIMM1.78 JDIMM1.81 JDIMM1.82 JDIMM1.85 JDIMM1.86 JDIMM1.89 JDIMM1.90 JDIMM1.93 JDIMM1.94 JDIMM1.98 JDIMM1.99 JDIMM1.102 JDIMM1.103 JDIMM1.106 JDIMM1.107 JDIMM1.167 JDIMM1.168 JDIMM1.171 JDIMM1.172 JDIMM1.175 JDIMM1.176 JDIMM1.180 JDIMM1.181 JDIMM1.184 JDIMM1.185 JDIMM1.188 JDIMM1.189 JDIMM1.192 JDIMM1.193 JDIMM1.196 JDIMM1.197 JDIMM1.201 JDIMM1.202 JDIMM1.205 JDIMM1.206 JDIMM1.209 JDIMM1.210 JDIMM1.213 JDIMM1.214 JDIMM1.217 JDIMM1.218 JDIMM1.222 JDIMM1.223 JDIMM1.226 JDIMM1.227 JDIMM1.230 JDIMM1.231 JDIMM1.234 JDIMM1.235 JDIMM1.238 JDIMM1.239 JDIMM1.243 JDIMM1.244 JDIMM1.247 JDIMM1.248 JDIMM1.251 JDIMM1.252 JDIMM1.261 JDIMM1.262 JDIMM2.1 JDIMM2.2 JDIMM2.5 JDIMM2.6 JDIMM2.9 JDIMM2.10 JDIMM2.14 JDIMM2.15 JDIMM2.18 JDIMM2.19 JDIMM2.22 JDIMM2.23 JDIMM2.26 JDIMM2.27 JDIMM2.30 JDIMM2.31 JDIMM2.35 JDIMM2.36 JDIMM2.39 JDIMM2.40 JDIMM2.43 JDIMM2.44 JDIMM2.47 JDIMM2.48 JDIMM2.51 JDIMM2.52 JDIMM2.56 JDIMM2.57 JDIMM2.60 JDIMM2.61 JDIMM2.64 JDIMM2.65 JDIMM2.68 JDIMM2.69 JDIMM2.72 JDIMM2.73 JDIMM2.77 JDIMM2.78 JDIMM2.81 JDIMM2.82 JDIMM2.85 JDIMM2.86 JDIMM2.89 JDIMM2.90 JDIMM2.93 JDIMM2.94 JDIMM2.98 JDIMM2.99 JDIMM2.102 JDIMM2.103 JDIMM2.106 JDIMM2.107 JDIMM2.167 JDIMM2.168 JDIMM2.171 JDIMM2.172 JDIMM2.175 JDIMM2.176 JDIMM2.180 JDIMM2.181 JDIMM2.184 JDIMM2.185 JDIMM2.188 JDIMM2.189 JDIMM2.192 JDIMM2.193 JDIMM2.196 JDIMM2.197 JDIMM2.201 JDIMM2.202 JDIMM2.205 JDIMM2.206 JDIMM2.209 JDIMM2.210 JDIMM2.213 JDIMM2.214 JDIMM2.217 JDIMM2.218 JDIMM2.222 JDIMM2.223 JDIMM2.226 JDIMM2.227 JDIMM2.230 JDIMM2.231 JDIMM2.234 JDIMM2.235 JDIMM2.238 JDIMM2.239 JDIMM2.243 JDIMM2.244 JDIMM2.247 JDIMM2.248 JDIMM2.251 JDIMM2.252 JDIMM2.261 JDIMM2.262 JEDP1.13 JEDP1.17 JEDP1.20 JEDP1.23 JEDP1.32 JEDP1.35 JEDP1.38 JEDP1.41 JEDP1.42 JESPI1.9 JESPI1.11 JESPI1.12 JFAN1.4 JFAN1.5 JFAN1.6 JFP.1 JFP.2 JFP.7 JFP.8 JFP1.1 JFP1.3 JFP1.4 JFP1.9 JFP1.10 JHDD1.1 JHDD1.4 JHDD1.7 JHDD1.13 JHDD1.14 JHDMI1.2 JHDMI1.5 JHDMI1.8 JHDMI1.11 JHDMI1.17 JHDMI1.20 JHDMI1.21 JHDMI1.22 JHDMI1.23 JIOB1.1 JIOB1.2 JIOB1.5 JIOB1.8 JIOB1.9 JIOB1.10 JIOB1.17 JIOB1.18 JKB1.30 JKB1.31 JKB1.32 JKBBL1.5 JKBBL1.6 JLAN1.9 JLAN1.10 JLAN1.11 JLAN1.12 JODD1.1 JODD1.2 JODD1.7 JODD1.8 JODD1.13 JODD1.14 JODD1.25 JODD1.26 JPWR1.1 JPWR1.5 JPWR1.6 JSPK1.5 JSPK1.6 JSSD1.1 JSSD1.3 JSSD1.9 JSSD1.15 JSSD1.21 JSSD1.27 JSSD1.33 JSSD1.39 JSSD1.45 JSSD1.51 JSSD1.57 JSSD1.71 JSSD1.73 JSSD1.75 JSSD1.76 JSSD1.77 JTP1.5 JTP1.9 JTP1.10 JUSB1.4 JUSB1.7 JUSB1.10 JUSB1.11 JUSB1.12 JUSB1.13 JUSB2.4 JUSB2.7 JUSB2.10 JUSB2.11 JUSB2.12 JUSB2.13 JVGA.1 JVGA.4 JVGA.7 JVGA.17 JVGA.18 JWLAN1.1 JWLAN1.7 JWLAN1.18 JWLAN1.26 JWLAN1.33 JWLAN1.39 JWLAN1.45 JWLAN1.51 JWLAN1.57 JWLAN1.63 JWLAN1.69 JWLAN1.75 JWLAN1.76 JWLAN1.77 LED1.1 LED1.3 PBATT1.1 PBATT1.2 PBATT1.3 PBATT1.4 PBATT1.11 PBATT1.12 PC1.2 PC2.2 PC3.2 PC4.2 PC11.2 PC12.2 PC15.2 PC301.2 PC302.2 PC303.2 PC304.2 PC305.2 PC306.2 PC308.2 PC309.2 PC310.2 PC311.2 PC312.2 PC313.2 PC314.2 PC501.2 PC502.2 PC503.2 PC504.2 PC505.2 PC506.2 PC508.2 PC509.2 PC510.2 PC511.2 PC512.2 PC513.2 PC514.2 PC515.2 PC516.2 PC1801.2 PC1802.2 PC1803.2 PC1804.2 PC1805.2 PC1806.2 PC2501.2 PC2502.2 PC2503.2 PC2504.2 PCA01.2 PCA02.2 PCA03.2 PCA04.2 PCA05.2 PCA06.2 PCA08.2 PCA09.2 PCA101.2 PCA102.2 PCA103.2 PCA104.2 PCA105.2 PCA106.2 PCA107.2 PCA108.2 PCA109.2 PCA110.2 PCA111.2 PCA112.2 PCA113.2 PCA114.2 PCA115.2 PCA116.2 PCA117.2 PCA118.2 PCB03.2 PCB04.2 PCB05.2 PCB06.2 PCB07.2 PCB08.2 PCB09.2 PCB10.2 PCB12.2 PCB16.2 PCB17.2 PCB18.2 PCB19.2 PCB20.2 PCB21.2 PCB22.2 PCB23.2 PCB24.2 PCB25.2 PCB26.2 PCB27.2 PCB28.2 PCB29.2 PCB30.2 PCB31.2 PCC01.2 PCC02.2 PCC03.2 PCC04.2 PCC05.2 PCC6.2 PCG01.2 PCG02.2 PCG03.2 PCG04.2 PCG05.2 PCG06.2 PCG07.2 PCG08.2 PCG10.2 PCG11.2 PCG12.2 PCG13.2 PCG14.2 PCG101.2 PCG102.2 PCG103.2 PCG104.2 PCG105.2 PCG106.2 PCG107.2 PCG108.2 PCG109.2 PCG110.2 PCG111.2 PCG112.2 PCG113.2 PCG114.2 PCG115.2 PCG116.2 PCG117.2 PCG118.2 PCG119.2 PCG120.2 PCG121.2 PCG122.2 PCG123.2 PCG124.2 PCG125.2 PCG126.2 PCG127.2 PCG128.2 PCG129.2 PCG130.2 PCG131.2 PCG132.2 PCG133.2 PCG134.2 PCG135.2 PCG136.2 PCG137.2 PCG138.2 PCG139.2 PCG140.2 PCG141.2 PCG142.2 PCG143.2 PCG144.2 PCG145.2 PCG146.2 PCG147.2 PCG148.2 PCG171.2 PCG172.2 PCH01.2 PCH02.2 PCH03.2 PCH04.2 PCH05.2 PCH06.2 PCH07.2 PCH08.2 PCH09.2 PCH10.2 PCH11.2 PCH13.2 PCH15.2 PCH16.2 PCI01.2 PCI02.2 PCI03.2 PCI04.2 PCI05.2 PCI06.2 PCI07.2 PCI08.2 PCI10.2 PCI11.2 PCI12.2 PCI13.2 PCI14.2 PCI21.2 PCI22.2 PCI23.2 PCI24.2 PCI25.2 PCI26.2 PCI27.2 PCI28.2 PCI30.2 PCI31.2 PCI32.2 PCI101.2 PCI102.2 PCI103.2 PCI104.2 PCI105.2 PCI106.2 PCI107.2 PCI108.2 PCI109.2 PCI110.2 PCI111.2 PCI112.2 PCI113.2 PCI114.2 PCI115.2 PCI116.2 PCI117.2 PCI118.2 PCI119.2 PCI120.2 PCI121.2 PCI122.2 PCI123.2 PCI124.2 PCI125.2 PCI126.2 PCI127.2 PCI128.2 PCI129.2 PCI130.2 PCI131.2 PCI132.2 PCI133.2 PCI134.2 PCI135.2 PCI136.2 PCI137.2 PCI138.2 PCI139.2 PCI140.2 PCI141.2 PCI142.2 PCI143.2 PCI144.2 PCI145.2 PCI146.2 PCI147.2 PCI148.2 PCI149.2 PCI150.2 PCI151.2 PCI152.2 PCI153.2 PCI154.2 PCI155.2 PCI156.2 PCI157.2 PCI158.2 PCI159.2 PCI160.2 PCI161.2 PCI162.2 PCI163.2 PCI164.2 PCI165.2 PCI171.2 PCI172.2 PCI173.2 PCM01.2 PCM02.2 PCM03.2 PCM04.2 PCM05.2 PCM06.2 PCM07.2 PCM08.2 PCM09.2 PCM10.2 PCM11.2 PCM13.2 PCM14.2 PCM15.2 PCM16.2 PCM18.2 PCM19.2 PCM20.2 PCM21.2 PCM22.2 PCM23.2 PCZ02.2 PCZ03.2 PCZ05.2 PCZ12.2 PCZ14.2 PCZ19.2 PCZ22.2 PCZ23.2 PCZ24.2 PCZ25.2 PCZ30.2 PCZ32.2 PCZ33.2 PCZ34.2 PCZ36.2 PD1.1 PD2.2 PD3.2 PD5.1 PD6.1 PHZ04.2 PHZ05.2 PJP2.2 PJPDC1.7 PJPDC1.8 PL2.2 PQ2.3 PQ11.3 PQ12.1 PQ12.4 PQ13.1 PQ13.4 PQA01.5 PQA01.6 PQA01.7 PQB02.1 PQB02.2 PQB02.3 PQB04.3 PQB05.3 PQB06.3 PQB07.3 PQM01.5 PQM01.6 PQM01.7 PR6.2 PR38.2 PR40.2 PR43.2 PR44.1 PR45.2 PR303.2 PR308.2 PR508.2 PR511.2 PR1802.2 PR1805.2 PR2503.2 PRB11.2 PRB14.2 PRB24.2 PRB26.2 PRB35.2 PRB36.2 PRB37.2 PRB39.2 PRB43.2 PRH02.2 PRH04.2 PRH09.2 PRM11.2 PRZ01.2 PRZ05.2 PRZ11.1 PRZ15.2 PRZ23.2 PRZ36.2 PRZ50.2 PRZ55.2 PRZ56.2 PRZ60.2 PRZ64.2 PRZ65.2 PRZ66.2 PRZ67.2 PRZ68.2 PRZ69.2 PU301.7 PU301.8 PU301.18 PU301.21 PU501.7 PU501.8 PU501.18 PU501.21 PU1801.11 PU2501.8 PU2501.9 PUA01.6 PUA01.9 PUB01.33 PUG01.2 PUG01.4 PUG01.10 PUG01.14 PUG01.18 PUH01.4 PUH01.8 PUI01.4 PUI01.10 PUI01.14 PUI01.18 PUI02.4 PUI02.10 PUI02.14 PUI02.18 PUM01.1 PUM01.3 PUM01.14 PUM01.21 PUZ01.49 Q1.3 Q4.3 Q8.3 Q13.3 Q24.3 Q25.1 Q25.4 QC2.3 QI1.3 QS1.1 QS1.4 R2.2 R10.2 R27.2 R40.2 R45.2 R72.2 R75.2 RA9.2 RA17.2 RA18.2 RA22.2 RA24.2 RC5.1 RC6.1 RC7.2 RC8.2 RC10.2 RC11.2 RC12.2 RC52.2 RC54.2 RC56.2 RC58.2 RC64.2 RC66.2 RC67.2 RC68.2 RC87.2 RC94.1 RC102.2 RC109.2 RC110.2 RC119.2 RC120.2 RC121.2 RC122.2 RC130.2 RC131.1 RC132.1 RC133.1 RC134.2 RC136.1 RC144.2 RC145.2 RC146.2 RC147.2 RC151.2 RC156.2 RC160.2 RC164.2 RC182.2 RC196.1 RC197.2 RC198.2 RC211.2 RC224.1 RD4.2 RD5.2 RD6.2 RD11.2 RD12.2 RD16.2 RD17.2 RD18.2 RD21.2 RD22.2 RE16.2 RE19.2 RE20.2 RE32.2 RE48.2 RE50.1 RE53.1 RE62.2 RE68.2 RI16.2 RL2.1 RL4.2 RL6.1 RM12.1 RM13.1 RP1.1 RP1.2 RP1.3 RX5.2 RX8.2 SW1.2 U1.2 U2.5 U3.2 UA1.49 UC1.A5 UC1.A67 UC1.A70 UC1.AA2 UC1.AA4 UC1.AA65 UC1.AA68 UC1.AB8 UC1.AB15 UC1.AB16 UC1.AB18 UC1.AB21 UC1.AD8 UC1.AD13 UC1.AD16 UC1.AD19 UC1.AD20 UC1.AD21 UC1.AD62 UC1.AE64 UC1.AE65 UC1.AE66 UC1.AE67 UC1.AE68 UC1.AE69 UC1.AF1 UC1.AF2 UC1.AF4 UC1.AF10 UC1.AF15 UC1.AF17 UC1.AF63 UC1.AG16 UC1.AG17 UC1.AG18 UC1.AG19 UC1.AG20 UC1.AG21 UC1.AG71 UC1.AH6 UC1.AH13 UC1.AH63 UC1.AH64 UC1.AH67 UC1.AJ4 UC1.AJ15 UC1.AJ18 UC1.AJ20 UC1.AK8 UC1.AK11 UC1.AK16 UC1.AK18 UC1.AK21 UC1.AK22 UC1.AK27 UC1.AK63 UC1.AK68 UC1.AK69 UC1.AL2 UC1.AL4 UC1.AL28 UC1.AL32 UC1.AL35 UC1.AL38 UC1.AL45 UC1.AL48 UC1.AL52 UC1.AL55 UC1.AL58 UC1.AL64 UC1.AL65 UC1.AL66 UC1.AM8 UC1.AM13 UC1.AM21 UC1.AM25 UC1.AM27 UC1.AM43 UC1.AM45 UC1.AM46 UC1.AM55 UC1.AM60 UC1.AM61 UC1.AM68 UC1.AM71 UC1.AN20 UC1.AN23 UC1.AN28 UC1.AN30 UC1.AN32 UC1.AN33 UC1.AN35 UC1.AN37 UC1.AN38 UC1.AN40 UC1.AN42 UC1.AN58 UC1.AN63 UC1.AP10 UC1.AP18 UC1.AP20 UC1.AP23 UC1.AP28 UC1.AP32 UC1.AP35 UC1.AP38 UC1.AP42 UC1.AP58 UC1.AP63 UC1.AP68 UC1.AP70 UC1.AR5 UC1.AR8 UC1.AR11 UC1.AR15 UC1.AR16 UC1.AR20 UC1.AR23 UC1.AR28 UC1.AR35 UC1.AR42 UC1.AR43 UC1.AR45 UC1.AR46 UC1.AR48 UC1.AR50 UC1.AR52 UC1.AR53 UC1.AR55 UC1.AR58 UC1.AR63 UC1.AT2 UC1.AT4 UC1.AT20 UC1.AT23 UC1.AT28 UC1.AT35 UC1.AT42 UC1.AT56 UC1.AT58 UC1.AT63 UC1.AT68 UC1.AT71 UC1.AU10 UC1.AU15 UC1.AU20 UC1.AU32 UC1.AU38 UC1.AV1 UC1.AV68 UC1.AV69 UC1.AV70 UC1.AV71 UC1.AW6 UC1.AW8 UC1.AW10 UC1.AW12 UC1.AW14 UC1.AW16 UC1.AW18 UC1.AW21 UC1.AW23 UC1.AW26 UC1.AW28 UC1.AW30 UC1.AW32 UC1.AW34 UC1.AW36 UC1.AW38 UC1.AW41 UC1.AW43 UC1.AW45 UC1.AW47 UC1.AW49 UC1.AW51 UC1.AW53 UC1.AW55 UC1.AW57 UC1.AW60 UC1.AW62 UC1.AW64 UC1.AW66 UC1.AY66 UC1.B10 UC1.B14 UC1.B18 UC1.B22 UC1.B30 UC1.B34 UC1.B39 UC1.B44 UC1.B48 UC1.B53 UC1.B58 UC1.B62 UC1.B66 UC1.B71 UC1.BA1 UC1.BA2 UC1.BA6 UC1.BA10 UC1.BA14 UC1.BA18 UC1.BA23 UC1.BA28 UC1.BA32 UC1.BA36 UC1.BA41 UC1.BA45 UC1.BA49 UC1.BA53 UC1.BA57 UC1.BA62 UC1.BA66 UC1.BA71 UC1.BB6 UC1.BB18 UC1.BB26 UC1.BB30 UC1.BB34 UC1.BB38 UC1.BB43 UC1.BB55 UC1.BB60 UC1.BB64 UC1.BB67 UC1.BB70 UC1.C1 UC1.C5 UC1.C25 UC1.D6 UC1.D10 UC1.D11 UC1.D14 UC1.D18 UC1.D22 UC1.D25 UC1.D26 UC1.D30 UC1.D34 UC1.D39 UC1.D44 UC1.D45 UC1.D47 UC1.D48 UC1.D53 UC1.D58 UC1.D62 UC1.D66 UC1.D69 UC1.E6 UC1.E11 UC1.E15 UC1.E18 UC1.E21 UC1.E46 UC1.E50 UC1.E53 UC1.E56 UC1.E65 UC1.E71 UC1.F1 UC1.F2 UC1.F4 UC1.F8 UC1.F13 UC1.F22 UC1.F23 UC1.F27 UC1.F28 UC1.F32 UC1.F33 UC1.F35 UC1.F37 UC1.F38 UC1.F40 UC1.F42 UC1.F68 UC1.G5 UC1.G6 UC1.G10 UC1.G22 UC1.G43 UC1.G45 UC1.G48 UC1.G52 UC1.G55 UC1.G58 UC1.G60 UC1.G63 UC1.G66 UC1.H15 UC1.H18 UC1.H71 UC1.J8 UC1.J11 UC1.J13 UC1.J25 UC1.J28 UC1.J32 UC1.J35 UC1.J38 UC1.J42 UC1.K16 UC1.K18 UC1.K22 UC1.K61 UC1.K63 UC1.K64 UC1.K65 UC1.K66 UC1.K67 UC1.K68 UC1.K70 UC1.K71 UC1.L2 UC1.L4 UC1.L8 UC1.L11 UC1.L16 UC1.L17 UC1.L18 UC1.L20 UC1.N6 UC1.N10 UC1.N13 UC1.N19 UC1.N21 UC1.N65 UC1.N68 UC1.P17 UC1.P19 UC1.P20 UC1.P21 UC1.R6 UC1.R13 UC1.T2 UC1.T4 UC1.T15 UC1.T17 UC1.T18 UC1.T21 UC1.U10 UC1.U63 UC1.U64 UC1.U66 UC1.U67 UC1.U69 UC1.U70 UC1.V16 UC1.V17 UC1.V18 UC1.W6 UC1.W9 UC1.W13 UC1.Y17 UC1.Y19 UC1.Y20 UC1.Y21 UC2.3 UC3.4 UC4.3 UC5.3 UC6.3 UC7.3 UC9.3 UE1.17 UE1.51 UE1.64 UE1.84 UE1.100 UE1.124 UE2.3 UL1.33 UL2.2 UM1.A6 UM1.C4 UM1.E7 UM1.E9 UM1.E10 UM1.F10 UM1.G5 UM1.H10 UM1.J5 UM1.K8 UM1.N2 UM1.N5 UM1.P4 UM1.P6 UM2.3 US1.5 US1.6 US1.7 US1.8 US2.2 UU1.2 UU3.2 UX1.9 UX1.16 UX1.23 UX1.32 UX1.33 UZ1.5 UZ1.9 UZ2.5 UZ3.11 UZ3.15 YL1.2 YL1.4
V3D3_STB: RA11.1 RA12.1 UA1.20
VCC_CPU: PCZ34.1 PRZ57.2 PUZ01.13
VCC_GT_SENSE: PRZ59.1 RC155.2 UC1.J70
VCC_VCORE1: PCI10.1 PRI02.2 PUI01.3
VCC_VCORE2: PCI30.1 PRI22.2 PUI02.3
VCC_VGT1: PCG10.1 PRG02.2 PUG01.3
VCCDSW_ON: Q4.2 R66.2 RE91.1
VCCGT_B+: PCG01.1 PCG02.1 PCG03.1 PCG04.1 PCG05.1 PCG06.1 PCG07.1 PCG08.1 PCG13.1 PCG14.1 PJPG01.2 PLG11.2 PUG01.8 PUG01.9
VCCIO_SENSE: TP38.1(TP-1) UC1.AM23
VCCSA_B+: PCA01.1 PCA02.1 PCA03.1 PCA04.1 PCA05.1 PCA06.1 PJPA01.2 PQA01.2 PQA01.3 PQA01.4 PQA01.10
VCCSENSE: PRZ14.1 RC150.2 UC1.E32
VCCST_PWRGD: RC96.2 UC1.B65
VCCSTG_EN: DZ2.1 RZ2.2 RZ3.1 UC9.4
VCCSTG_EN_R: CZ7.1 DZ2.2 RZ3.2 UZ2.4
VDD10: CL5.1 CL6.1 CL18.1 CL19.1 CL22.1 CL23.1 RL1.2 UL1.3 UL1.8 UL1.22 UL1.30
VDD_1.2V: PCM14.1 PRM03.2 PRM04.2 PUM01.11
VDD_CHG: PCB16.1 PRB13.1 PRB21.1 PRB29.1 PRB32.1 PRB33.1 PUB01.19
VDDP_CHG: PCB17.1 PRB21.2 PUB01.20
VDDREG: CL8.1 RL5.2 UL1.23
VSS_GT_SENSE: PRZ53.2 RC156.1 UC1.J69
VSSIO_SENSE: TP39.1(TP-1) UC1.AM22
VSSSENSE: PRZ18.1 RC151.1 UC1.E33
+DC_IN: PC3.1 PC4.1 PCB01.1 PDB01.2 PJP1.2 PL1.2 PQB11.5 PR32.1 PR34.1 PR36.1 PRB09.1
+DCBAT_LCD: C4.1 C5.1 F1.2 JEDP1.1 JEDP1.2 JEDP1.3 JEDP1.4
+EMMC_VDDI: CM5.1 UM1.C2
+FP_VCC: C37.1 JFP.5 JFP.6 JFP1.7 JFP1.8 R4.2 R7.2
+LAN_VDD33: CL7.1 CL20.1 CL24.1 CL25.1 JP11.1 RL5.1 RL17.1 UL1.11 UL1.32 UL2.1
+LCDVDD: R3.2 U1.1
+LCDVDD_LCD: C2.1 C3.1 C12.1 JEDP1.7 JEDP1.8 R3.1
+LINE1_VREFO_L: RA29.1 UA1.31
+LINE1_VREFO_R: RA33.1 UA1.30
+MIC2-VREFO: RA25.1 RA26.1 UA1.29
+RTC_CELL: C1.1 D1.1 Q23.3 RA12.2 RC77.2 RC78.2 RC91.2 RC199.2 RE7.1 RE41.1 RE70.2
+RTC_CELL_PCH: C38.1 CC70.1 CC71.1 Q23.1 R74.1 RC199.1 UC1.AK19 UC1.BB14
+RTC_CELL_VBAT: CE14.1 RE7.2 UE1.122
+RTC_VCC: JIOB1.11 R1.2
+TP_VDD: C19.1 JTP1.8 Q9.2 Q12.1 R31.1 R32.1 R36.2 R37.2 R39.1 R40.1 R41.1 R46.1 R47.1
+TPAN_VDD: F2.2 JEDP1.40 R13.2 U3.1
+TPAN_VDD_F: C31.1 F2.1 R11.2 R12.2 R13.1 R30.2 U3.5
+V_DDR_REFA: CD28.1 JDIMM1.164 RD9.2 RD10.2 RD12.1
+V_DDR_REFA_R: CD30.1 RD9.1 UC1.AY67
+V_DDR_REFB: CD58.1 JDIMM2.164 RD19.2 RD20.2 RD21.1
+V_DDR_REFB_R: CD59.1 RD19.1 UC1.BA67
AC_DIS: PQB04.2 UE1.69
AC_PRESENT: RC90.1 RC211.1 UC1.AY15
ACIN_CHG: PCB12.1 PQB04.1 PRB09.2 PRB11.1 PUB01.1
ACLIM: PRB32.2 PRB35.1 PUB01.16
ADDR_VBOOT_CPU: PRZ69.1 PUZ01.21
ADJ_2.5V: PC2505.2 PR2502.2 PR2503.1 PU2501.7
ALERT#: R28.2 U2.6
ALERT#_CPU: PRZ47.1 PUZ01.33
ALL_SYS_PWRGD: C35.1 RC105.2 RC106.2 RC107.1 RE42.1 UC6.4 UC7.2
ALWON: PR506.1 UE1.121
AMBER_LED_BAT: Q18.1 R68.2
ASGATE: PRB07.2 PUB01.30
AUD_AGND: CA7.2 CA10.2 CA11.2 CA12.2 CA20.1 CA21.1 CA23.2 CA26.2 CA34.2 CA35.2 CA36.2 CA37.2 CA41.2 CA42.2 EC2301.1 EC2302.1 EC3003.1 JHP1.7 RA17.1 RA18.1 RA22.1 RA30.2 RA34.2 RA40.2 RA41.1 UA1.25 UA1.38
AUD_HP1_JACK_L: RA27.1 UA1.32
AUD_HP1_JACK_L1: RA27.2 RA28.2 RA29.2 RA36.1
AUD_HP1_JACK_R: RA31.1 UA1.33
AUD_HP1_JACK_R1: RA31.2 RA32.2 RA33.2 RA37.1
AUD_PC_BEEP: CA31.2 UA1.16
AUD_PC_BEEP_C: DA3.1 RA23.1
AUD_SENSE: RA10.1 RA39.1
AUD_SENSE_A: CA7.1 RA3.1 RA10.2 UA1.13
AUD_SPK_L+: RA15.1 UA1.42
AUD_SPK_L+_C: CA28.1 DA1.2 JSPK1.3 RA15.2
AUD_SPK_L-: RA16.1 UA1.43
AUD_SPK_L-_C: CA27.1 DA1.3 JSPK1.4 RA16.2
AUD_SPK_R+: RA13.1 UA1.45
AUD_SPK_R+_C: CA30.1 DA2.2 JSPK1.1 RA13.2
AUD_SPK_R-: RA14.1 UA1.44
AUD_SPK_R-_C: CA29.1 DA2.3 JSPK1.2 RA14.2
AUD_VREF: CA23.1 UA1.28
AUX_ON: RL6.2 UE1.3 UL2.4
BA: PDB01.3 PQB08.1 PRB28.1
BAT1_LED#: Q17.1 RE18.1 UE1.106
BAT2_LED#: Q17.4 RE21.1 UE1.1
BATT_WHITE_LED_R#: Q17.3 Q19.2 Q22.1
BEEP: DA3.2 UE1.45
BKLT_CTRL: D3.1 R9.1 RP1.8 RP2.7
BKLT_IN_EC: RC6.2 UC1.R12 UE1.67
BLON_OUT_C: JEDP1.28 RP1.7 RP2.1
BLUETOOTH_EN: RC42.2 RW12.1 UC1.AB2
BOARD_ID: CE2.1 RE1.2 RE6.2 UE1.111
BOARD_ID1: RC57.2 RC58.1 UC1.AC1
BOARD_ID2: RC55.2 RC56.1 UC1.AB3
BST_1.2V: PRM02.1 PUM01.18
BST_1.2V_R: PCM12.1 PRM02.2
BST_3V: PR301.1 PU301.1
BST_5V: PR501.1 PU501.1
BST_+1VALW: PRH06.1 PUH01.1
BST_+1VALW_R: PCH12.1 PRH06.2
BST_VCCSA: PRA01.1 PUA01.1
BST_VCCSA_R: PCA07.1 PRA01.2
BST_VCORE1: PRI01.1 PUI01.5
BST_VCORE1_R: PCI09.1 PRI01.2
BST_VCORE2: PRI21.1 PUI02.5
BST_VCORE2_R: PCI29.1 PRI21.2
BST_VGT1: PRG01.1 PUG01.5
BST_VGT1_R: PCG09.1 PRG01.2
CAP_LED: JKB1.27 R25.2
CAP_LED#: Q6.3 R24.2 UE1.93
CAP_LED_Q: Q7.1 R25.1
CAP_LED_R#: Q6.1 Q7.2
CBN: CA24.1 UA1.35
CBP: CA24.2 UA1.37
CCLIM: PRB33.2 PRB36.1 PUB01.11
CFG0: RC131.2 TPC10.1(TP-1) UC1.E68
CFG1: RC132.2 TPC11.1(TP-1) UC1.B67
CFG2: TPC12.1(TP-1) UC1.D65
CFG3: RC133.2 RC175.1 TPC13.1(TP-1) UC1.D67
CFG4: RC136.2 TPC14.1(TP-1) UC1.E70
CFG5: TPC15.1(TP-1) UC1.C68
CFG6: TPC16.1(TP-1) UC1.D68
CFG7: TPC17.1(TP-1) UC1.C67
CFG8: TPC20.1(TP-1) UC1.F71
CFG9: TPC21.1(TP-1) UC1.G69
CFG10: TPC22.1(TP-1) UC1.F70
CFG11: TPC23.1(TP-1) UC1.G68
CFG12: TPC24.1(TP-1) UC1.H70
CFG13: TPC25.1(TP-1) UC1.G71
CFG14: TPC26.1(TP-1) UC1.H69
CFG15: TPC27.1(TP-1) UC1.G70
CFG16: TPC19.1(TP-1) UC1.E63
CFG17: TPC18.1(TP-1) UC1.F63
CFG18: TPC29.1(TP-1) UC1.E66
CFG19: TPC28.1(TP-1) UC1.F66
CFG_RCOMP: RC134.1 UC1.E60
CHG_AMBER_LED_R#: Q17.6 Q18.2
CLK_ITPXDP_N: TP8.1(TP-1) UC1.F43
CLK_ITPXDP_P: TP9.1(TP-1) UC1.E43
CLK_PCIE_LAN_N2: UC1.D41 UL1.16
CLK_PCIE_LAN_P2: UC1.C41 UL1.15
CLK_PCIE_LAN_REQ#: RC73.2 RL13.1 UC1.AT8
CLK_PCIE_LAN_REQ#_R: RL13.2 UL1.12
CLK_PCIE_NVME_N4: JSSD1.53 UC1.B40
CLK_PCIE_NVME_P4: JSSD1.55 UC1.A40
CLK_PCIE_NVME_REQ#: JSSD1.52 RC188.2 UC1.AU8
CLK_PCIE_WLAN_N1: JWLAN1.49 UC1.B42
CLK_PCIE_WLAN_P1: JWLAN1.47 UC1.A42
CLK_PCIE_WLAN_REQ#: RC72.2 RW9.1 UC1.AT7
CLK_PCIE_WLAN_REQ#_R: JWLAN1.53 RW9.2
CLK_SMB: PBATT1.7 PR42.1
CLK_TP_SIO: C27.1 JTP1.1 R32.2 UE1.78
CMP_STRAP0: RE40.1 UE1.118
CMP_VIN0: RE37.1 RE52.1 UE1.20
CMP_VOUT0: PR507.1 RE49.2 RE52.2 UE1.85
CMSRC: PRB08.2 PUB01.29
COMP: PCB29.1 PRB38.1 PUB01.10
COMP_1A_CPU: PCZ30.1 PCZ31.1 PUZ01.26
COMP_1B_CPU: PCZ01.1 PCZ03.1 PUZ01.43
COMP_2PH_CPU: PCZ15.2 PCZ16.2 PUZ01.4
CPU_DP1_CTRL_CLK: QI2.1 RC1.1 UC1.L13
CPU_DP1_CTRL_DATA: QI2.4 RC2.1 UC1.L12
CPU_DP1_HPD: QI3.3 RI15.2 UC1.L9
CPU_DP2_AUXN: CT60.1 RC195.2 UC1.E48
CPU_DP2_AUXN_C: CT60.2 JVGA.9
CPU_DP2_AUXP: CT59.1 RC196.2 UC1.F48
CPU_DP2_AUXP_C: CT59.2 JVGA.8
CPU_DP2_CTRL_DATA: RC212.1 UC1.N8
CPU_DP2_HPD: JVGA.13 RC5.2 UC1.L7
CPU_DP2_N0: CT56.1 UC1.C50
CPU_DP2_N0_C: CT56.2 JVGA.3
CPU_DP2_N1: CT58.1 UC1.C52
CPU_DP2_N1_C: CT58.2 JVGA.6
CPU_DP2_P0: CT55.1 UC1.D50
CPU_DP2_P0_C: CT55.2 JVGA.2
CPU_DP2_P1: CT57.1 UC1.D52
CPU_DP2_P1_C: CT57.2 JVGA.5
CPU_POPIRCOMP: RC119.1 UC1.AT16
CPU_XDP_TCK0: RC146.1 TPC2.1(TP-1) UC1.A59 UC1.B61
CPVEE: CA25.2 UA1.34
CS_1.2V: PRM03.1 PUM01.13
CSCOMP_2PH_CPU: PCZ17.1 PCZ18.1 PHZ02.2 PRZ27.2 PRZ28.1 PUZ01.6
CSCOMP_2PH_CPU_R: PHZ02.1 PRZ26.2 PRZ27.1
CSI2_COMP: RC7.1 UC1.E13
CSN1_VCORE1: PLI01.3 PRZ31.1
CSN2_VCORE2: PLI02.3 PRZ30.1
CSN_1A_VGT: PHZ03.2 PLG01.3 PRZ51.1
CSN_1A_VGT_NTC: PHZ03.1 PRZ45.1
CSN_1B_VCCSA: PHZ01.1 PLA01.3 PRZ06.1
CSP1_2PH_CPU: PCZ20.2 PRZ32.2 PRZ37.2 PUZ01.10
CSP1_VCORE1: PLI01.2 PRZ25.1 PRZ37.1
CSP2_2PH_CPU: PCZ21.2 PRZ33.2 PRZ38.2 PRZ39.2 PUZ01.9
CSP2_VCORE2: PLI02.2 PRZ29.1 PRZ38.1
CSP_1A_VCORE: PCZ26.1 PCZ27.1 PRZ44.2 PRZ45.2 PUZ01.29
CSP_1A_VGT_R: PLG01.2 PRZ44.1
CSP_1B_VCCSA: PCZ08.2 PCZ09.2 PRZ10.2 PRZ13.2 PUZ01.40
CSP_1B_VCCSA_R: PLA01.2 PRZ13.1
CSREF_2PH_CPU: PCZ19.1 PCZ20.1 PCZ21.1 PRZ30.2 PRZ31.2 PRZ32.1 PRZ33.1 PUZ01.8
CSSUM_2PH_CPU: PCZ17.2 PCZ18.2 PRZ25.2 PRZ26.1 PRZ29.2 PUZ01.7
DAT_SMB: PBATT1.6 PR37.1
DAT_TP_SIO: C26.1 JTP1.2 R31.2 UE1.79
DBC_PANEL_EN: R6.2 UC1.AM5
DBC_PANEL_EN_R: JEDP1.11 R5.2 R6.1
DCPDSW_1P0: CC56.1 UC1.AL1
DCPRTC: CC69.1 UC1.BB10
DDC_CLK_HDMI: JHDMI1.15 QI2.6 RI13.1
DDC_DATA_HDMI: JHDMI1.16 QI2.3 RI14.1
DDR4_DRAMRST#: CD29.1 JDIMM1.108 JDIMM2.108 RD8.2
DDR_A_ACT#: JDIMM1.114 UC1.BA55
DDR_A_ALERT#: JDIMM1.116 UC1.AW50
DDR_A_BG0: JDIMM1.115 UC1.AY55
DDR_A_BG1: JDIMM1.113 UC1.AY54
DDR_A_BS0: JDIMM1.150 UC1.AU52
DDR_A_BS1: JDIMM1.145 UC1.AT48
DDR_A_CAS#: JDIMM1.156 UC1.AU48
DDR_A_CKE0: JDIMM1.109 UC1.BA56
DDR_A_CKE1: JDIMM1.110 UC1.BB56
DDR_A_CKE2: TP3.1(TP-1) UC1.AW56
DDR_A_CKE3: TP4.1(TP-1) UC1.AY56
DDR_A_CLK0: JDIMM1.137 UC1.AT53
DDR_A_CLK1: JDIMM1.138 UC1.AT55
DDR_A_CLK#0: JDIMM1.139 UC1.AU53
DDR_A_CLK#1: JDIMM1.140 UC1.AU55
DDR_A_CS#0: JDIMM1.149 UC1.AU45
DDR_A_CS#1: JDIMM1.157 UC1.AU43
DDR_A_D0: JDIMM1.4 UC1.AL71
DDR_A_D1: JDIMM1.3 UC1.AL68
DDR_A_D2: JDIMM1.20 UC1.AN68
DDR_A_D3: JDIMM1.21 UC1.AN69
DDR_A_D4: JDIMM1.8 UC1.AL70
DDR_A_D5: JDIMM1.7 UC1.AL69
DDR_A_D6: JDIMM1.16 UC1.AN70
DDR_A_D7: JDIMM1.17 UC1.AN71
DDR_A_D8: JDIMM1.29 UC1.AR70
DDR_A_D9: JDIMM1.25 UC1.AR68
DDR_A_D10: JDIMM1.37 UC1.AU71
DDR_A_D11: JDIMM1.41 UC1.AU68
DDR_A_D12: JDIMM1.24 UC1.AR71
DDR_A_D13: JDIMM1.28 UC1.AR69
DDR_A_D14: JDIMM1.42 UC1.AU70
DDR_A_D15: JDIMM1.38 UC1.AU69
DDR_A_D16: JDIMM1.45 UC1.BB65
DDR_A_D17: JDIMM1.49 UC1.AW65
DDR_A_D18: JDIMM1.63 UC1.AW63
DDR_A_D19: JDIMM1.58 UC1.AY63
DDR_A_D20: JDIMM1.50 UC1.BA65
DDR_A_D21: JDIMM1.46 UC1.AY65
DDR_A_D22: JDIMM1.59 UC1.BA63
DDR_A_D23: JDIMM1.62 UC1.BB63
DDR_A_D24: JDIMM1.67 UC1.BA61
DDR_A_D25: JDIMM1.70 UC1.AW61
DDR_A_D26: JDIMM1.79 UC1.BB59
DDR_A_D27: JDIMM1.84 UC1.AW59
DDR_A_D28: JDIMM1.66 UC1.BB61
DDR_A_D29: JDIMM1.71 UC1.AY61
DDR_A_D30: JDIMM1.83 UC1.BA59
DDR_A_D31: JDIMM1.80 UC1.AY59
DDR_A_D32: JDIMM1.174 UC1.AY39
DDR_A_D33: JDIMM1.170 UC1.AW39
DDR_A_D34: JDIMM1.187 UC1.AY37
DDR_A_D35: JDIMM1.186 UC1.AW37
DDR_A_D36: JDIMM1.169 UC1.BB39
DDR_A_D37: JDIMM1.173 UC1.BA39
DDR_A_D38: JDIMM1.182 UC1.BA37
DDR_A_D39: JDIMM1.183 UC1.BB37
DDR_A_D40: JDIMM1.195 UC1.AY35
DDR_A_D41: JDIMM1.191 UC1.AW35
DDR_A_D42: JDIMM1.207 UC1.AY33
DDR_A_D43: JDIMM1.203 UC1.AW33
DDR_A_D44: JDIMM1.194 UC1.BB35
DDR_A_D45: JDIMM1.190 UC1.BA35
DDR_A_D46: JDIMM1.208 UC1.BA33
DDR_A_D47: JDIMM1.204 UC1.BB33
DDR_A_D48: JDIMM1.211 UC1.AY31
DDR_A_D49: JDIMM1.216 UC1.AW31
DDR_A_D50: JDIMM1.229 UC1.AY29
DDR_A_D51: JDIMM1.228 UC1.AW29
DDR_A_D52: JDIMM1.215 UC1.BB31
DDR_A_D53: JDIMM1.212 UC1.BA31
DDR_A_D54: JDIMM1.224 UC1.BA29
DDR_A_D55: JDIMM1.225 UC1.BB29
DDR_A_D56: JDIMM1.237 UC1.AY27
DDR_A_D57: JDIMM1.233 UC1.AW27
DDR_A_D58: JDIMM1.236 UC1.AY25
DDR_A_D59: JDIMM1.232 UC1.AW25
DDR_A_D60: JDIMM1.245 UC1.BB27
DDR_A_D61: JDIMM1.249 UC1.BA27
DDR_A_D62: JDIMM1.246 UC1.BA25
DDR_A_D63: JDIMM1.250 UC1.BB25
DDR_A_DQS0: JDIMM1.13 UC1.AM69
DDR_A_DQS1: JDIMM1.34 UC1.AT70
DDR_A_DQS2: JDIMM1.55 UC1.AY64
DDR_A_DQS3: JDIMM1.76 UC1.BA60
DDR_A_DQS4: JDIMM1.179 UC1.AY38
DDR_A_DQS5: JDIMM1.200 UC1.BA34
DDR_A_DQS6: JDIMM1.221 UC1.AY30
DDR_A_DQS7: JDIMM1.242 UC1.BA26
DDR_A_DQS#0: JDIMM1.11 UC1.AM70
DDR_A_DQS#1: JDIMM1.32 UC1.AT69
DDR_A_DQS#2: JDIMM1.53 UC1.BA64
DDR_A_DQS#3: JDIMM1.74 UC1.AY60
DDR_A_DQS#4: JDIMM1.177 UC1.BA38
DDR_A_DQS#5: JDIMM1.198 UC1.AY34
DDR_A_DQS#6: JDIMM1.219 UC1.BA30
DDR_A_DQS#7: JDIMM1.240 UC1.AY26
DDR_A_MA0: JDIMM1.144 UC1.AY50
DDR_A_MA1: JDIMM1.133 UC1.BB50
DDR_A_MA2: JDIMM1.132 UC1.AY51
DDR_A_MA3: JDIMM1.131 UC1.BA50
DDR_A_MA4: JDIMM1.128 UC1.BB52
DDR_A_MA5: JDIMM1.126 UC1.BA51
DDR_A_MA6: JDIMM1.127 UC1.BA52
DDR_A_MA7: JDIMM1.122 UC1.AW52
DDR_A_MA8: JDIMM1.125 UC1.AY52
DDR_A_MA9: JDIMM1.121 UC1.BB54
DDR_A_MA10: JDIMM1.146 UC1.AT50
DDR_A_MA11: JDIMM1.120 UC1.BA54
DDR_A_MA12: JDIMM1.119 UC1.AW54
DDR_A_MA13: JDIMM1.158 UC1.AU46
DDR_A_ODT0: JDIMM1.155 UC1.AT45
DDR_A_ODT1: JDIMM1.161 UC1.AT43
DDR_A_PAR: JDIMM1.143 UC1.AT52
DDR_A_RAS#: JDIMM1.152 UC1.AU50
DDR_A_WE#: JDIMM1.151 UC1.AT46
DDR_B_ACT#: JDIMM2.114 UC1.AN53
DDR_B_ALERT#: JDIMM2.116 UC1.AN43
DDR_B_BG0: JDIMM2.115 UC1.AP52
DDR_B_BG1: JDIMM2.113 UC1.AN52
DDR_B_BS0: JDIMM2.150 UC1.BB44
DDR_B_BS1: JDIMM2.145 UC1.BA44
DDR_B_CAS#: JDIMM2.156 UC1.AY43
DDR_B_CKE0: JDIMM2.109 UC1.AN56
DDR_B_CKE1: JDIMM2.110 UC1.AP55
DDR_B_CKE2: TP5.1(TP-1) UC1.AN55
DDR_B_CKE3: TP6.1(TP-1) UC1.AP53
DDR_B_CLK0: JDIMM2.137 UC1.AP45
DDR_B_CLK1: JDIMM2.138 UC1.AP46
DDR_B_CLK#0: JDIMM2.139 UC1.AN45
DDR_B_CLK#1: JDIMM2.140 UC1.AN46
DDR_B_CS#0: JDIMM2.149 UC1.BB42
DDR_B_CS#1: JDIMM2.157 UC1.AY42
DDR_B_D0: JDIMM2.28 UC1.AF65
DDR_B_D1: JDIMM2.25 UC1.AF64
DDR_B_D2: JDIMM2.42 UC1.AK65
DDR_B_D3: JDIMM2.38 UC1.AK64
DDR_B_D4: JDIMM2.24 UC1.AF66
DDR_B_D5: JDIMM2.29 UC1.AF67
DDR_B_D6: JDIMM2.41 UC1.AK67
DDR_B_D7: JDIMM2.37 UC1.AK66
DDR_B_D8: JDIMM2.8 UC1.AF70
DDR_B_D9: JDIMM2.4 UC1.AF68
DDR_B_D10: JDIMM2.21 UC1.AH71
DDR_B_D11: JDIMM2.20 UC1.AH68
DDR_B_D12: JDIMM2.7 UC1.AF71
DDR_B_D13: JDIMM2.3 UC1.AF69
DDR_B_D14: JDIMM2.16 UC1.AH70
DDR_B_D15: JDIMM2.17 UC1.AH69
DDR_B_D16: JDIMM2.45 UC1.AT66
DDR_B_D17: JDIMM2.49 UC1.AU66
DDR_B_D18: JDIMM2.62 UC1.AP65
DDR_B_D19: JDIMM2.59 UC1.AN65
DDR_B_D20: JDIMM2.50 UC1.AN66
DDR_B_D21: JDIMM2.46 UC1.AP66
DDR_B_D22: JDIMM2.63 UC1.AT65
DDR_B_D23: JDIMM2.58 UC1.AU65
DDR_B_D24: JDIMM2.71 UC1.AT61
DDR_B_D25: JDIMM2.66 UC1.AU61
DDR_B_D26: JDIMM2.79 UC1.AP60
DDR_B_D27: JDIMM2.84 UC1.AN60
DDR_B_D28: JDIMM2.70 UC1.AN61
DDR_B_D29: JDIMM2.67 UC1.AP61
DDR_B_D30: JDIMM2.83 UC1.AT60
DDR_B_D31: JDIMM2.80 UC1.AU60
DDR_B_D32: JDIMM2.169 UC1.AU40
DDR_B_D33: JDIMM2.173 UC1.AT40
DDR_B_D34: JDIMM2.183 UC1.AT37
DDR_B_D35: JDIMM2.187 UC1.AU37
DDR_B_D36: JDIMM2.170 UC1.AR40
DDR_B_D37: JDIMM2.174 UC1.AP40
DDR_B_D38: JDIMM2.186 UC1.AP37
DDR_B_D39: JDIMM2.182 UC1.AR37
DDR_B_D40: JDIMM2.190 UC1.AT33
DDR_B_D41: JDIMM2.194 UC1.AU33
DDR_B_D42: JDIMM2.207 UC1.AU30
DDR_B_D43: JDIMM2.203 UC1.AT30
DDR_B_D44: JDIMM2.191 UC1.AR33
DDR_B_D45: JDIMM2.195 UC1.AP33
DDR_B_D46: JDIMM2.204 UC1.AR30
DDR_B_D47: JDIMM2.208 UC1.AP30
DDR_B_D48: JDIMM2.216 UC1.AU27
DDR_B_D49: JDIMM2.212 UC1.AT27
DDR_B_D50: JDIMM2.225 UC1.AT25
DDR_B_D51: JDIMM2.229 UC1.AU25
DDR_B_D52: JDIMM2.211 UC1.AP27
DDR_B_D53: JDIMM2.215 UC1.AN27
DDR_B_D54: JDIMM2.228 UC1.AN25
DDR_B_D55: JDIMM2.224 UC1.AP25
DDR_B_D56: JDIMM2.232 UC1.AT22
DDR_B_D57: JDIMM2.236 UC1.AU22
DDR_B_D58: JDIMM2.249 UC1.AU21
DDR_B_D59: JDIMM2.245 UC1.AT21
DDR_B_D60: JDIMM2.237 UC1.AN22
DDR_B_D61: JDIMM2.233 UC1.AP22
DDR_B_D62: JDIMM2.250 UC1.AP21
DDR_B_D63: JDIMM2.246 UC1.AN21
DDR_B_DQS0: JDIMM2.34 UC1.AH65
DDR_B_DQS1: JDIMM2.13 UC1.AG70
DDR_B_DQS2: JDIMM2.55 UC1.AR65
DDR_B_DQS3: JDIMM2.76 UC1.AR60
DDR_B_DQS4: JDIMM2.179 UC1.AR38
DDR_B_DQS5: JDIMM2.200 UC1.AR32
DDR_B_DQS6: JDIMM2.221 UC1.AR27
DDR_B_DQS7: JDIMM2.242 UC1.AR21
DDR_B_DQS#0: JDIMM2.32 UC1.AH66
DDR_B_DQS#1: JDIMM2.11 UC1.AG69
DDR_B_DQS#2: JDIMM2.53 UC1.AR66
DDR_B_DQS#3: JDIMM2.74 UC1.AR61
DDR_B_DQS#4: JDIMM2.177 UC1.AT38
DDR_B_DQS#5: JDIMM2.198 UC1.AT32
DDR_B_DQS#6: JDIMM2.219 UC1.AR25
DDR_B_DQS#7: JDIMM2.240 UC1.AR22
DDR_B_MA0: JDIMM2.144 UC1.BA46
DDR_B_MA1: JDIMM2.133 UC1.AY46
DDR_B_MA2: JDIMM2.132 UC1.AY47
DDR_B_MA3: JDIMM2.131 UC1.BB46
DDR_B_MA4: JDIMM2.128 UC1.BA47
DDR_B_MA5: JDIMM2.126 UC1.AY48
DDR_B_MA6: JDIMM2.127 UC1.BA48
DDR_B_MA7: JDIMM2.122 UC1.AP48
DDR_B_MA8: JDIMM2.125 UC1.BB48
DDR_B_MA9: JDIMM2.121 UC1.AP50
DDR_B_MA10: JDIMM2.146 UC1.AW46
DDR_B_MA11: JDIMM2.120 UC1.AN48
DDR_B_MA12: JDIMM2.119 UC1.AN50
DDR_B_MA13: JDIMM2.158 UC1.BA43
DDR_B_ODT0: JDIMM2.155 UC1.BA42
DDR_B_ODT1: JDIMM2.161 UC1.AW42
DDR_B_PAR: JDIMM2.143 UC1.AP43
DDR_B_RAS#: JDIMM2.152 UC1.AW44
DDR_B_WE#: JDIMM2.151 UC1.AY44
DDR_VTT_CNTL: UC1.AW67 UC2.2
DIFFOUT_2PH_CPU: PRZ20.1 PRZ21.1 PUZ01.2
DIMM_CHA_SA0: JDIMM1.256 RD1.2 RD4.1
DIMM_CHA_SA1: JDIMM1.260 RD2.2 RD5.1
DIMM_CHA_SA2: JDIMM1.166 RD3.2 RD6.1
DIMM_CHB_SA0: JDIMM2.256 RD13.2 RD16.1
DIMM_CHB_SA1: JDIMM2.260 RD14.2 RD17.1
DIMM_CHB_SA2: JDIMM2.166 RD15.2 RD18.1
DMIC_CLK: L5.2 UA1.3
DMIC_CLK_EDP: CA9.1 JEDP1.31 L5.1
DMIC_DATA: RA42.2 UA1.2
DMIC_DATA_EDP: CA40.1 JEDP1.30 RA42.1
DRVON: PUA01.3 PUG01.16 PUI01.16 PUI02.16 PUZ01.35
EC_AGND: CE1.2 CE2.2 CE21.2 CE25.2 CE30.2 RE4.1 RE6.1 RE50.2 UE1.112
EC_MUTE#: RA8.2 RE28.2 UA1.47
EDP_AUX: C11.2 JEDP1.15
EDP_AUX#: C10.2 JEDP1.16
EDP_AUX_DN: C10.1 UC1.E45
EDP_AUX_DP: C11.1 UC1.F45
EDP_BKLT_CTRL: D3.2 R8.2 R9.2
EDP_COMP: RC4.2 UC1.E52
EDP_HPD: JEDP1.12 RP1.6 UC1.L10
EDP_TX0: C7.2 JEDP1.19
EDP_TX0#: C6.2 JEDP1.18
EDP_TX0_DN: C6.1 UC1.C47
EDP_TX0_DP: C7.1 UC1.C46
EDP_TX1: C9.2 JEDP1.22
EDP_TX1#: C8.2 JEDP1.21
EDP_TX1_DN: C8.1 UC1.D46
EDP_TX1_DP: C9.1 UC1.C45
EDP_VDD_EN: D4.2 UC1.U13
EDRAM_OPIO_RCOMP: RC121.1 UC1.H66
EMMC_CLK: RM14.1 UC1.AM3
EMMC_CLK_R: CM8.2 RM13.2 RM14.2 UM1.M6
EMMC_CMD: RM15.1 UC1.AP4
EMMC_CMD_R: RM3.2 RM15.2 UM1.M5
EMMC_D0_R: RM16.2 RPM1.6 UM1.A3
EMMC_D1_R: RM17.2 RPM1.8 UM1.A4
EMMC_D2_R: RM18.2 RPM2.6 UM1.A5
EMMC_D3_R: RM19.2 RPM1.5 UM1.B2
EMMC_D4_R: RM20.2 RPM1.7 UM1.B3
EMMC_D5_R: RM21.2 RPM2.5 UM1.B4
EMMC_D6_R: RM22.2 RPM2.7 UM1.B5
EMMC_D7_R: RM23.2 RPM2.8 UM1.B6
EMMC_DATA0: RM16.1 UC1.AP2
EMMC_DATA1: RM17.1 UC1.AP1
EMMC_DATA2: RM18.1 UC1.AP3
EMMC_DATA3: RM19.1 UC1.AN3
EMMC_DATA4: RM20.1 UC1.AN1
EMMC_DATA5: RM21.1 UC1.AN2
EMMC_DATA6: RM22.1 UC1.AM4
EMMC_DATA7: RM23.1 UC1.AM1
EMMC_RCLK: RM24.1 UC1.AM2
EMMC_RCLK_R: RM12.2 RM24.2 UM1.H5
EMMC_RCOMP: RC8.1 UC1.AT1
EMMC_RST#: CM6.1 RM25.1 RM27.2 UM2.4
EMMC_RST#_R: RM25.2 UM1.K5
EN_0.6VSP: PCM16.1 PRM09.2 PUM01.7
EN_1.2V: PCM15.1 PRM08.2 PUM01.8
EN_1.8VALW: PC1805.1 PR1801.2 PR1802.1 PU1801.5
EN_2.5V: PC2503.1 PR2501.2 PU2501.2
EN_3V: PR502.1 PU301.12
EN_5V: PR503.1 PU501.12
EN_+1VALW: PCH09.1 PRH01.2 PRH02.1 PUH01.6
EN_CPU: PRZ22.1 PUZ01.37
ENLDO_3V5V: PR302.1 PR303.1 PU301.11 PU501.11
EOPIO_RCOMP: RC122.1 UC1.H65
ESPI_ALERT#: RC14.2 UC1.AY11 UE1.55
ESPI_CLK: CC88.1 JESPI1.10 RC15.2 RE67.2 UE1.57
ESPI_CS#: JESPI1.7 UC1.BA12 UE1.58
ESPI_IO0: JESPI1.3 RPC2.8 UE1.59
ESPI_IO1: JESPI1.4 RPC2.7 UE1.60
ESPI_IO2: JESPI1.5 RPC2.6 UE1.61
ESPI_IO3: JESPI1.6 RPC2.5 UE1.62
ESPI_RESET#: UC1.BA11 UE1.53
EXT_PWR_GATE#: TP13.1(TP-1) UC1.AM10
FAN1_PWM: JFAN1.2 R50.1 UE1.47
FAN1_TACH: CE28.1 JFAN1.3 RE13.1 UE1.40
FB_1.2V: PCM17.1 PRM10.1 PRM11.1 PUM01.6
FB_1.8VALW: PC1807.2 PR1805.1 PR1807.2 PU1801.6
FB_2PH_CPU: PCZ13.2 PCZ15.1 PRZ21.2 PRZ24.1 PUZ01.3
FB_+1VALW: PRH08.1 PRH09.1 PRH12.2 PUH01.10
FFS_INT1: RC35.2 UC1.M3 US1.12
FFS_INT2: QS1.2 RC36.2 UC1.AC2 US1.11
FFS_INT2_Q: JHDD1.9 QS1.3 RS4.2
FPR_SCAN#: EU4012.3 JFP1.2 RC213.1 UE1.42
GPP_B23: RC39.1 UC1.AM7
GPP_C5: RC38.1 UC1.W1
H_CATERR#: RC111.2 UC1.D63
H_CPU_SVIDALRT#: RC153.1 UC1.B63
H_CPUPWRGD: CC15.1 RC95.2 UC1.A68
H_CPUPWRGD_R: RC95.1 TP7.1(TP-1)
H_DRAMRST#: RD7.2 RD8.1 UC1.AT13
H_PECI: RE23.1 UE1.94
H_PROCHOT#: CE26.1 PQ11.1 PQ12.3 PQB06.1 PRB19.1 PRZ43.2 PRZ49.2 RC113.2 RC117.1 UE2.4
H_PROCHOT#_R: RC117.2 UC1.C65
H_THERMTRIP#: RC112.2 TP14.1(TP-1) UC1.C63
H_VCCST_PWRGD: C36.1 RC96.1 RC104.1 UC7.4
HDA_BIT_CLK: CC91.1 RC124.2 UC1.AY22
HDA_CODEC_BITCLK: RA43.2 RC124.1 UA1.6
HDA_CODEC_RST#: RC127.1 TP74.1(TP-1)
HDA_CODEC_SDIN0: RA7.2 UA1.8
HDA_CODEC_SDOUT: RC125.1 UA1.5
HDA_CODEC_SYNC: RC123.1 UA1.10
HDA_RST#: RC127.2 UC1.AW22
HDA_SDIN0: RA7.1 UC1.BA21
HDA_SDOUT: RC125.2 RC126.2 RC129.2 UC1.BB22
HDA_SYNC: RC123.2 UC1.BA22
HDD_DEVSLP: RS1.2 UC1.J1
HDD_DEVSLP_R: JHDD1.8 RS1.1
HDD_EN_PCH: RC209.2 UC1.J4 US2.4
HDMI_CLK: CI2.1 UC1.G56
HDMI_CLK#: CI1.1 UC1.F56
HDMI_CLK#_R: CI1.2 LI1.3 RI2.1 RPI2.6
HDMI_CLK#_R_C: JHDMI1.12 LI1.4 RI2.2 RI3.1
HDMI_CLK_R: CI2.2 LI1.2 RI1.1 RPI2.5
HDMI_CLK_R_C: JHDMI1.10 LI1.1 RI1.2 RI3.2
HDMI_DATA0: CI4.1 UC1.G53
HDMI_DATA0#: CI3.1 UC1.F53
HDMI_DATA0#_R: CI3.2 LI2.3 RI4.1 RPI2.8
HDMI_DATA0#_R_C: JHDMI1.9 LI2.4 RI4.2 RI6.1
HDMI_DATA0_R: CI4.2 LI2.2 RI5.1 RPI2.7
HDMI_DATA0_R_C: JHDMI1.7 LI2.1 RI5.2 RI6.2
HDMI_DATA1: CI6.1 UC1.F58
HDMI_DATA1#: CI5.1 UC1.E58
HDMI_DATA1#_R: CI5.2 LI4.3 RI11.1 RPI1.8
HDMI_DATA1#_R_C: JHDMI1.6 LI4.4 RI11.2 RI12.1
HDMI_DATA1_R: CI6.2 LI4.2 RI10.1 RPI1.7
HDMI_DATA1_R_C: JHDMI1.4 LI4.1 RI10.2 RI12.2
HDMI_DATA2: CI8.1 UC1.F55
HDMI_DATA2#: CI7.1 UC1.E55
HDMI_DATA2#_R: CI7.2 LI3.3 RI8.1 RPI1.6
HDMI_DATA2#_R_C: JHDMI1.3 LI3.4 RI8.2 RI9.1
HDMI_DATA2_R: CI8.2 LI3.2 RI7.1 RPI1.5
HDMI_DATA2_R_C: JHDMI1.1 LI3.1 RI7.2 RI9.2
HDMI_HPD_B: JHDMI1.19 QI3.1 RI16.1
HDMI_PLL_GND: QI1.1 RPI1.1 RPI1.2 RPI1.3 RPI1.4 RPI2.1 RPI2.2 RPI2.3 RPI2.4
HOST_DEBUG_TX: JDEG1.8 RE57.2 RW6.1 RW10.1 UE1.81
HPOUT_L: CA35.1 DA4.2 JHP1.1 RA30.1 RA36.2
HPOUT_R: CA34.1 DA4.3 JHP1.2 RA34.1 RA37.2
HW_ACAV_IN: CE32.2 PR31.1 PRB13.2 PRB14.1 PUB01.2 UE1.128
I2C0_SCL_TCH_PAD: Q10.1 R34.2 UC1.U6
I2C0_SDA_TCH_PAD: Q10.4 R33.2 UC1.U7
I2C_SCL_TP: JTP1.6 Q10.6 R46.2
I2C_SDA_TP: JTP1.7 Q10.3 R47.2
I_ADP: CE25.1 RE51.1 UE1.110
I_ADP_R: PCB25.1 PRB20.1 RE51.2
I_BATT: CE30.1 RE54.1 UE1.114
I_BATT_R: PCB26.1 PRB23.1 RE54.2
I_SYS: PRB24.1 PRZ11.2 PUB01.8 PUZ01.46
ICCMAX_1A_CPU: PRZ67.1 PUZ01.19
ICCMAX_1B_CPU: PRZ68.1 PUZ01.20
ICCMAX_2PH_CPU: PRZ66.1 PUZ01.18
ICSP_CLK: RE60.2 UE1.101
ICSP_CLR: RE61.2 UE1.87
ICSP_DAT: RE63.2 UE1.102
ILIM_1A_CPU: PCZ32.1 PRZ56.1 PUZ01.27
ILIM_1B_CPU: PCZ05.1 PRZ05.1 PUZ01.42
ILIM_2PH_CPU: PRZ28.2 PUZ01.5
ILMT_+1VALW: PRH03.2 PRH04.1 PUH01.12
IMVP_VR_ON: PRZ22.2 RC107.2
INT_TP#: JTP1.4 Q9.3 R39.2
INTRUDER#: RC91.1 UC1.AP16
IOUT_1A_CPU: PCZ25.1 PRZ50.1 PUZ01.30
IOUT_1B_CPU: PCZ12.1 PRZ15.1 PUZ01.39
IOUT_2PH_CPU: PCZ14.1 PRZ23.1 PUZ01.1
IR_GND: JEDP1.24 JEDP1.25
ISOLATE#: RL3.2 RL4.1 UL1.20
JACK_PLUG: DA7.2 JHP1.5 RA39.2
JACK_PLUG_DET: DA7.3 JHP1.6 RA40.1
JTAG_CLK: JDEG1.4 RPE7.3
JTAG_TDI: JDEG1.2 RE60.1 RPE7.1
JTAG_TDO: JDEG1.5 RE63.1 RPE7.4
JTAG_TMS: JDEG1.3 RE61.1 RPE7.2
KB_BL_CTRL#: EC3001.1 JKBBL1.4 Q8.1
KB_DET#: JKB1.1 RC45.1 UC1.AD4
KB_LED_BL_DET: R26.1 R27.1 UC1.W8
KB_LED_DET_C: JKBBL1.2 R26.2
KB_LED_PWM: Q8.2 UE1.44
KBLR_XTAL_IN: RC25.1 UC1.E3
KBLR_XTAL_IN_R: CC17.1 RC22.2 RC25.2 YC3.3
KBLR_XTAL_OUT: RC26.1 UC1.C7
KBLR_XTAL_OUT_R: CC18.1 RC22.1 RC26.2 YC3.1
KSI0: JKB1.9 RPE1.4 UE1.98
KSI1: JKB1.7 RPE1.3 UE1.99
KSI2: JKB1.5 RPE1.2 UE1.6
KSI3: JKB1.8 RPE1.1 UE1.7
KSI4: JKB1.4 RPE2.4 UE1.104
KSI5: JKB1.6 RPE2.3 UE1.105
KSI6: JKB1.3 RPE2.2 UE1.107
KSI7: JKB1.2 RPE2.1 UE1.108
KSO0: JKB1.18 RPE3.8 UE1.2
KSO1: JKB1.16 RPE3.7 UE1.14
KSO2: JKB1.17 RPE3.6 UE1.15
KSO3: JKB1.15 RPE3.5 UE1.16
KSO4: JKB1.11 RPE4.8 UE1.37
KSO5: JKB1.10 RPE4.7 UE1.38
KSO6: JKB1.13 RPE4.6 UE1.39
KSO7: JKB1.12 RPE4.5 UE1.50
KSO8: JKB1.14 RPE6.8 UE1.46
KSO9: JKB1.24 RE15.1 UE1.68
KSO10: JKB1.26 RPE5.8 UE1.72
KSO11: JKB1.25 RPE5.7 UE1.74
KSO12: JKB1.19 RPE5.6 UE1.75
KSO13: JKB1.22 RPE5.5 UE1.76
KSO14: JKB1.23 RPE6.6 UE1.77
KSO15: JKB1.21 RPE6.7 UE1.86
KSO16: JKB1.20 RPE6.5 UE1.92
L_BKLT_CTRL: R8.1 UC1.R11
LAN_MDI0N: TL1.15 UL1.2
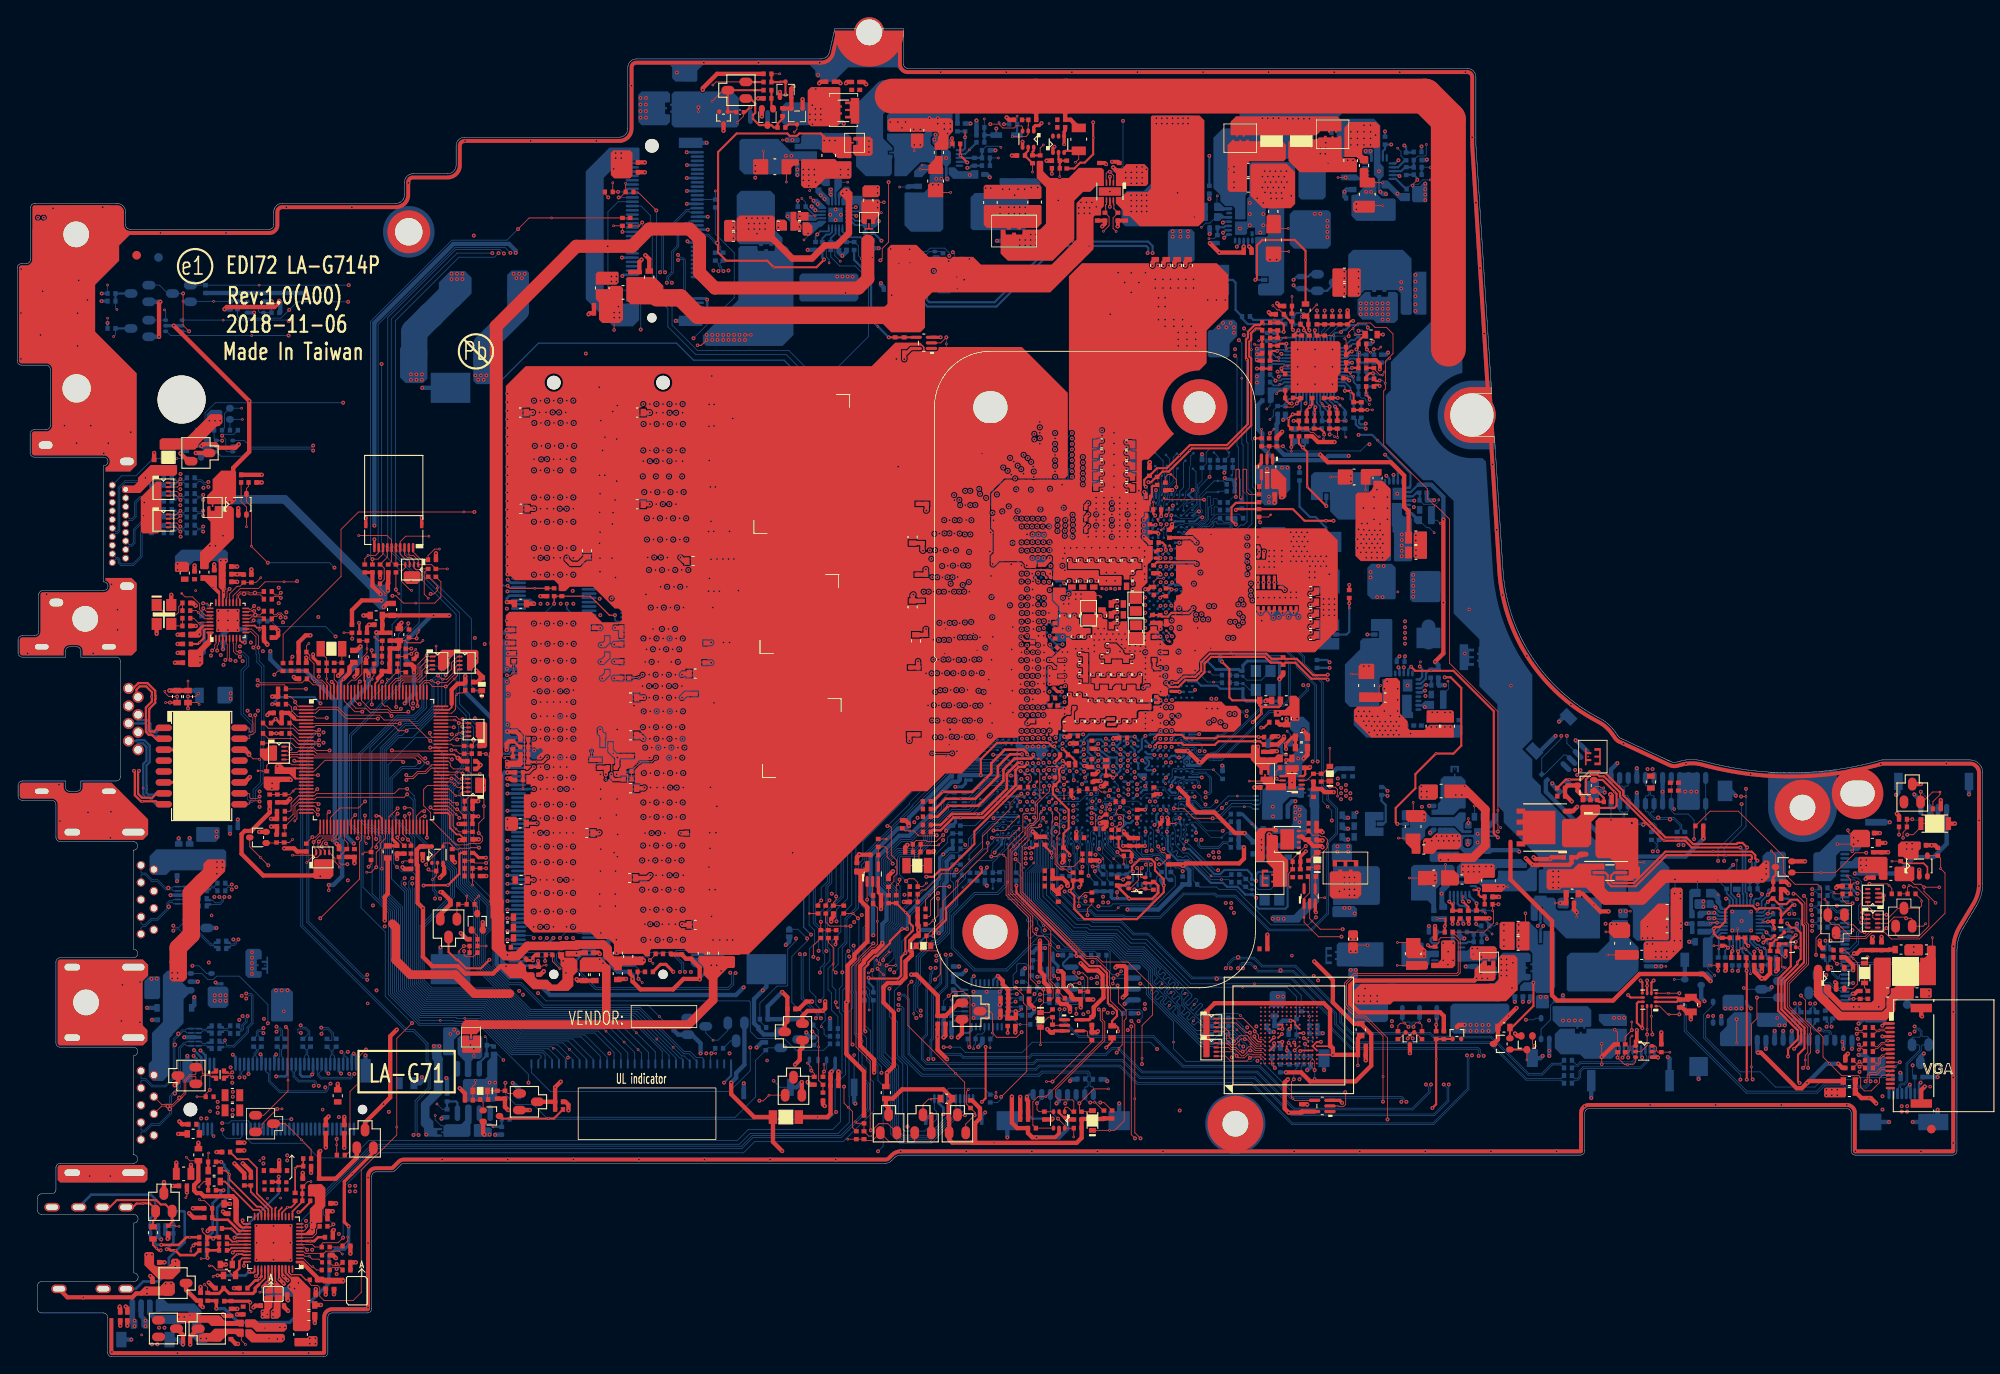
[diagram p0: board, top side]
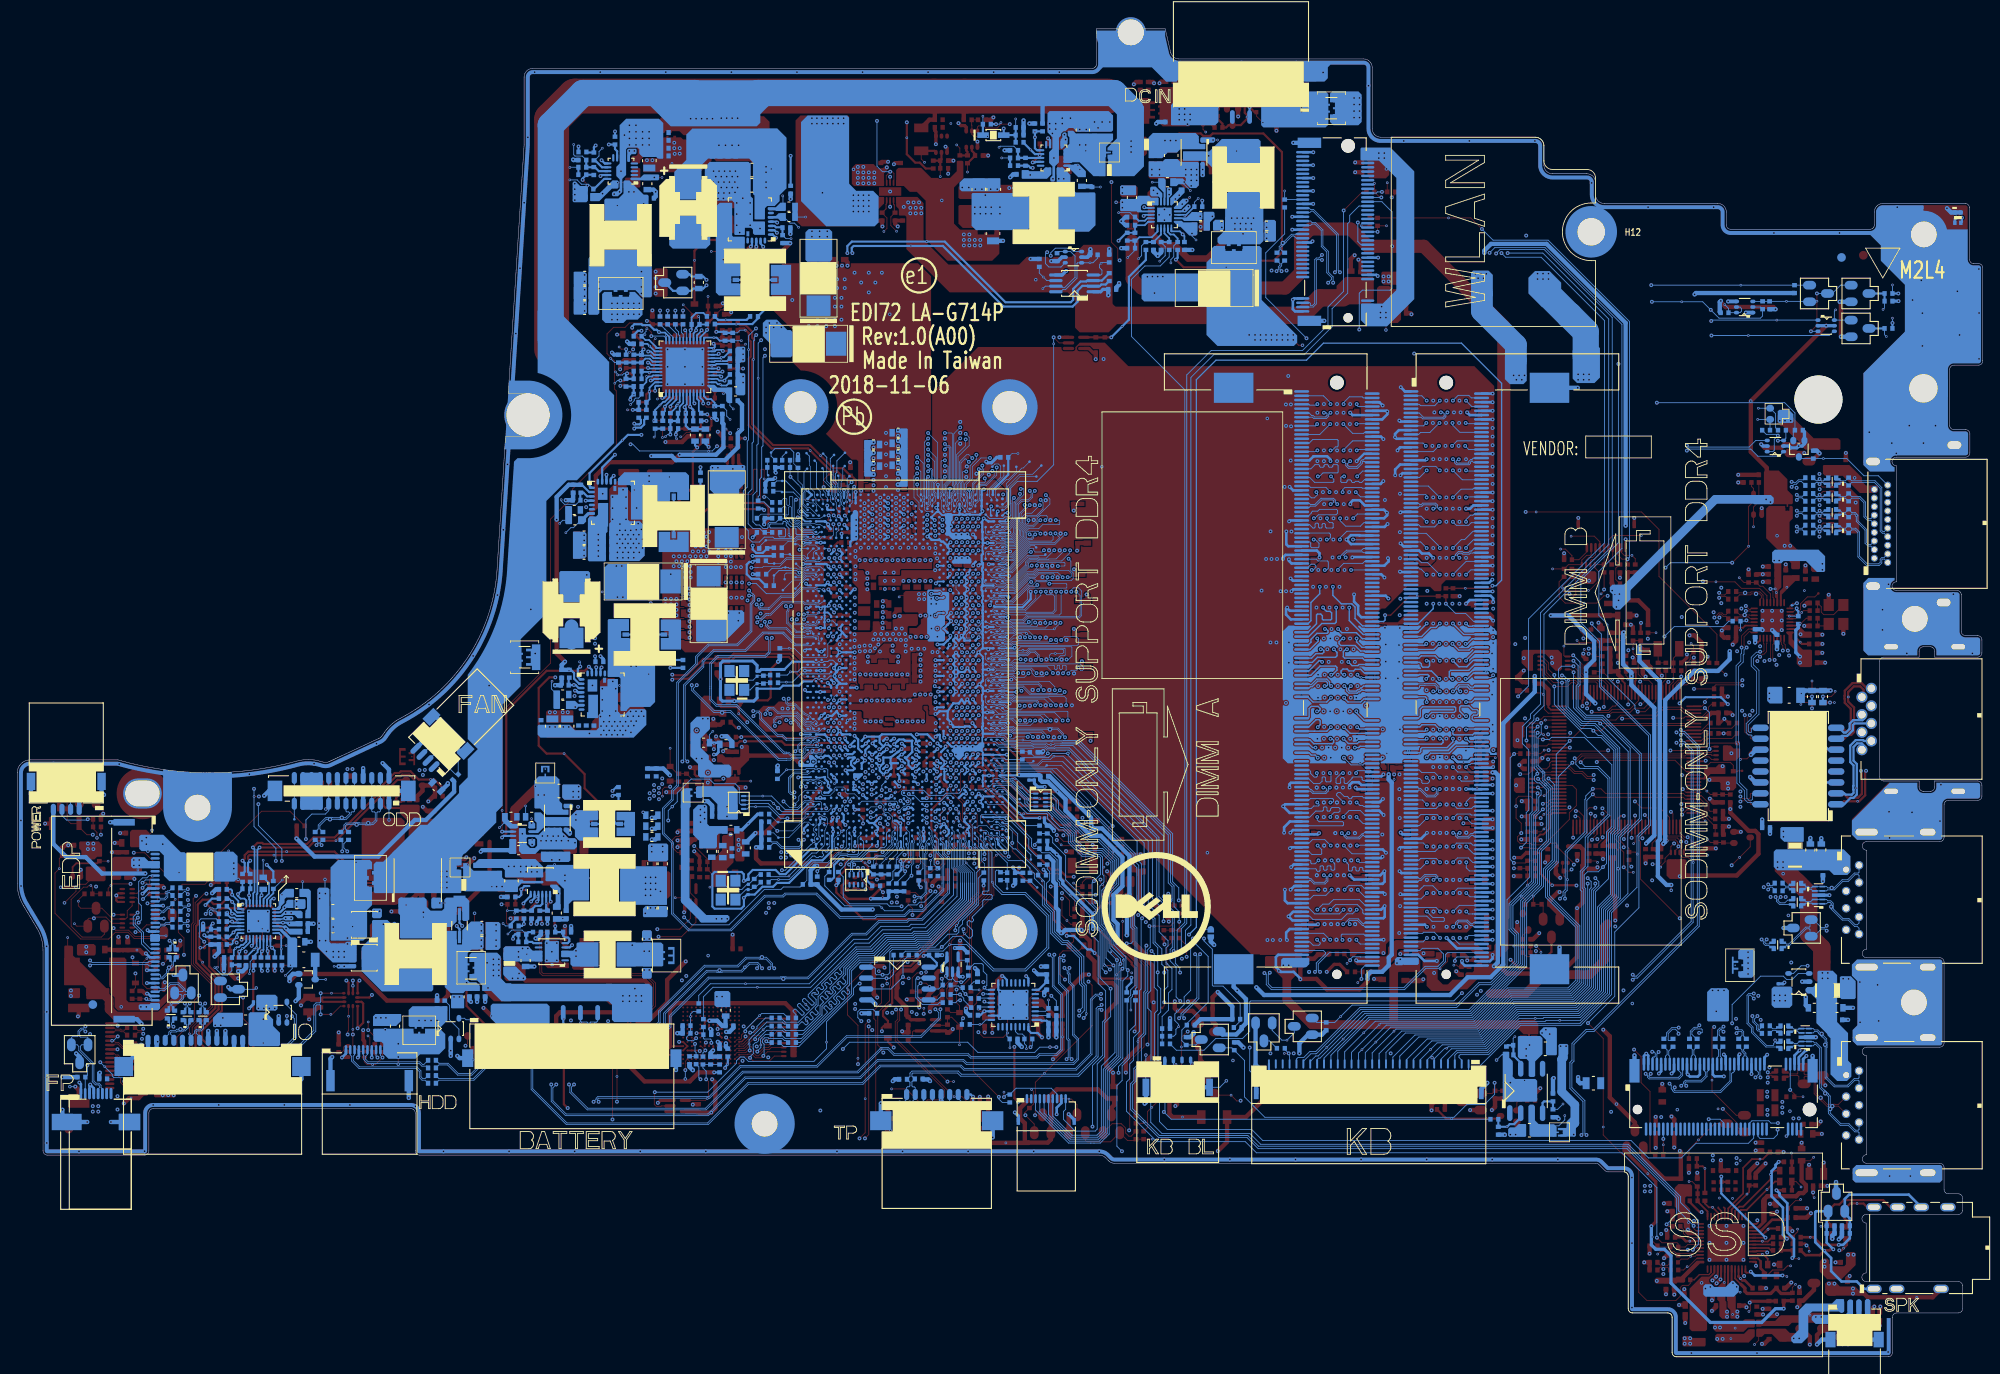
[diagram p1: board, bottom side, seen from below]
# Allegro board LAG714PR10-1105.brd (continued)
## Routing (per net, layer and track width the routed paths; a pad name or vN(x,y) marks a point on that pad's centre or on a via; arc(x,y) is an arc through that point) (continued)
V3D3_STB: length 5.2
  TOP w0.203: UA1.20 29.18,17.14 v1(27.4,18.92) 27.15,19.17 RA11.1 RA12.1
VCC_CPU: length 1.1
  BOTTOM w0.102: v1(145.2,110.21) 145.59,110.6 PRZ57.2
VCC_GT_SENSE: length 29.6
  TOP w0.254: v2(131.45,101.69) 131.75,101.69 132.36,102.3 RC155.2 133.1,102.93 133.81,102.93 v1(136.25,105.37) 136.5,105.62 140.72,105.62 143.39,108.29 143.39,116.07 143.16,116.29 143.16,118.04 143.39,118.27 143.39,119.03 143.93,119.57 144.47,119.57 PRZ59.1
  BOTTOM w0.076: v2(131.45,101.69) 131.76,101.37 131.76,100.58 131.79,100.55 131.79,100.54 131.93,100.41 131.93,100.12 131.88,99.98 131.88,99.8 UC1.J70
VCC_VCORE1: length 2.6
  BOTTOM w0.254: PRI02.2 164.32,78.88 PCI10.1 163.74,78.09 v2(163.71,78.11) 163.52,78.11 163.16,77.75 PUI01.3
VCC_VCORE2: length 5.1
  BOTTOM w0.102: PCI30.1 163.43,99.12 164.8,99.12 165.18,99.5 v1(165.18,99.65)
  BOTTOM w0.254: PUI02.3 162.17,100.04 162.6,100.47 PRI22.2 162.98,100.41 162.98,99.62 PCI30.1
VCC_VGT1: length 3.5
  BOTTOM w0.102: PRG02.2 139.06,130.01 v1(138.48,130.01)
  BOTTOM w0.254: PRG02.2 139.47,130.42 PCG10.1 139.52,131.33 140.24,131.33 140.4,131.48 PUG01.3
VCCDSW_ON: length 3.2
  TOP w0.102: v1(54.49,47.76) RE91.1 R66.2 53.48,48.95 Q4.2
VCCGT_B+:
  vias: v1(140.78,138.11) v2(141.39,138.36) v2(141.39,137.73) v2(141.39,136.58) v2(141.39,135.95) v2(144.57,140.86) v2(145.33,140.86) v2(146.1,140.86) v2(146.86,140.86)
VCCIO_SENSE: length 1.2
  TOP w0.102: v2(119.96,72.81) 119.66,72.51 TP38.1
  BOTTOM w0.076: UC1.AM23 120.29,73.14 v2(119.96,72.81)
VCCSA_B+: length 10.7
  TOP w1.016: 167.23,58.03 169.17,58.03 170.6,59.46 170.6,63.62 168.75,65.46
  vias: v1(168.19,66.33) v2(165.39,57.78) v2(166.28,57.78) v2(167.17,65.32) v2(167.86,65.32)
VCCSENSE: length 89.3
  TOP w0.254: v2(134.21,78.36) 134.85,78.36 135.57,79.08 136.91,79.08 137.58,79.75 137.58,80.75 138.59,81.76 145.14,81.76 145.75,81.15 146.92,81.15 RC150.2 147.28,81.15 148.69,81.15 150.59,79.24 152.22,79.24 v2(152.28,79.31)
  IN1 w0.254: v2(156.7,107.92) 159.77,107.92 167.46,100.22 167.46,72.36 166.09,70.99 154.11,70.99 153.2,71.91 153.2,78.77 152.77,79.19 152.4,79.19 v2(152.28,79.31)
  BOTTOM w0.254: v2(156.7,107.92) 156.59,108.03 155.92,108.03 155.55,108.41 155.55,108.93 PRZ14.1 ; UC1.E32 133.82,77.97 v2(134.21,78.36)
VCCST_PWRGD: length 8.7
  BOTTOM w0.076: RC96.2 139.36,99.8 139.05,99.8 138.97,99.73 138.97,99.08 138.9,99 138.74,99 138.67,99.08 138.67,99.97 138.59,100.04 138.37,100.04 138.27,99.95 138.27,97.4 137.93,97.06 137.57,97.06 137.22,96.71 136.18,96.71 135.92,96.46 UC1.B65
VCCSTG_EN: length 5.6
  TOP w0.102: RZ3.1 150.19,56.92 DZ2.1 151.07,56.02 RZ2.2 150.83,55.78 UC9.4 150.83,53.77 151.23,53.37 v1(151.94,53.37)
VCCSTG_EN_R: length 7.5
  TOP w0.102: RZ3.2 150.98,58.62 DZ2.2 151.67,58.62 152.25,59.2 v1(152.25,59.61) 152.25,60.12 151.87,60.5 151.51,60.5 151.37,60.64 150.57,60.64 CZ7.1 150.06,61.14 UZ2.4
VDD10: length 3.6
  TOP w0.203: UL1.3 23.88,82.32 ; v2(26.45,83.05) 26.13,83.05 25.88,83.3 UL1.8
  TOP w0.254: 23.88,82.32 v2(23.92,82.28)
  BOTTOM w0.508: v2(23.92,82.28) 23.91,82.29 CL18.1 ; CL6.1 v2(26.45,83.05)
  vias: v1(24,88.86) v2(18.64,92.2) v2(18.64,91.5) v2(21.18,84.01) v2(23.66,92.58) v2(24.24,92.58)
VDD_1.2V: length 6
  IN1 w0.254: v2(91.89,130.6) 91.89,133.23 v2(90.7,134.42)
  BOTTOM w0.102: v1(91.42,129.85) 91.89,130.32 v2(91.89,130.6)
  BOTTOM w0.254: PRM03.2 v2(90.7,134.42)
VDD_CHG: length 18
  TOP w0.254: v2(206.52,52.52) 206.26,52.52 204.96,51.22 ; PRB33.1 PRB32.1 197.63,48.71 197.14,49.21 197.14,49.77 v2(197.16,49.79) 197.32,49.94 197.81,49.94 198.47,50.6 198.47,51.93 198.99,52.45 201.65,52.45 v1(202.17,51.93) 202.4,52.16 204.68,52.16 204.96,51.87 204.96,51.22 ; 204.96,51.22 PRB29.1
  BOTTOM w0.254: v2(206.52,52.52) 205.77,53.27 PRB13.1
VDDP_CHG: length 0.8
  TOP w0.102: v2(197.52,50.48) 196.83,50.48 v1(196.76,50.4)
VDDREG:
  vias: v1(22.77,89.47)
VSS_GT_SENSE: length 31.1
  TOP w0.254: PRZ53.2 144.37,119.95 143.77,119.95 143.01,119.19 143.01,118.5 142.78,118.27 142.78,116.14 143.01,115.91 143.01,108.45 140.56,106 136.26,106 v1(135.04,104.78) 133.58,103.32 132.45,103.32 RC156.1 131.45,102.44 130.96,101.95 130.96,101.36 131.14,101.18 v2(131.14,101.16)
  BOTTOM w0.076: UC1.J69 131.66,99.01 131.37,99.3 131.37,100.93 v2(131.14,101.16)
VSSIO_SENSE: length 1.5
  TOP w0.102: v2(119.96,71.87) 120.38,71.45 TP39.1
  BOTTOM w0.076: UC1.AM22 119.96,71.99 v2(119.96,71.87)
VSSSENSE: length 90.8
  TOP w0.254: v2(152.28,78.72) 152.17,78.84 150.37,78.84 148.5,80.7 147.34,80.7 RC151.1 146.86,80.7 145.66,80.7 144.99,81.38 138.75,81.38 137.96,80.59 137.96,79.59 137.05,78.67 135.73,78.67 134.94,77.87 133.97,77.87 v2(133.5,78.34)
  IN1 w0.254: v2(156.7,108.5) 159.72,108.5 167.84,100.38 167.84,72.2 166.25,70.61 153.95,70.61 152.82,71.75 152.82,78.61 152.61,78.81 152.37,78.81 v2(152.28,78.72)
  BOTTOM w0.254: PRZ18.1 155.93,108.93 155.93,108.56 156.08,108.41 156.61,108.41 v2(156.7,108.5) ; UC1.E33 133.5,78.39 v2(133.5,78.34)
+DC_IN: length 160.7
  TOP w0.508: 118.31,146.57 118.41,146.47 PR36.1 ; v2(196.76,43.68) 195.93,44.51 188.53,44.51 185.44,41.42 178.95,41.42 178.34,42.03 178.34,50.67 173.52,55.49 173.52,59.88 ; PR32.1 122.4,143.84 PR34.1 121.78,146.5 121.85,146.57 ; v2(205.9,54.86) 205.52,55.24 PRB09.1
  TOP w4.064: 166.3,117.16 166.3,143.86 163.58,146.57 101.68,146.57
  IN1 w0.508: v2(205.9,54.86) 205.55,54.86 205.04,54.35 205.04,48.09 202.12,45.17 202.12,44.58 201.22,43.68 v2(196.76,43.68)
  BOTTOM w0.508: v2(196.76,43.68) 196.76,44.13 196.36,44.52 PDB01.2
  vias: v4(168.21,81.77) v4(168.72,86.9) v4(173.57,78.04)
+DCBAT_LCD: length 3.9
  TOP w0.102: v2(213.39,60.37) 212.73,61.03 v4(212.73,61.22) ; v4(211.49,59.6) v2(213.39,59.6) 213.39,58.96 v4(213.22,58.78)
  vias: v2(213.9,59.99)
+EMMC_VDDI: length 2.7
  TOP w0.076: 145.77,33.96 145.77,34.36 UM1.C2
  TOP w0.102: 145.77,33.96 v2(146.14,33.58)
  BOTTOM w0.254: v2(146.14,33.58) 146.14,33.7 v1(145.83,34.02) CM5.1
+FP_VCC: length 4.2
  TOP w0.508: R7.2 R4.2 214.3,30.08 v1(215.17,30.08) 215.39,30.08 v2(216.01,29.46)
+LAN_VDD33: length 17.3
  TOP w0.203: CL20.1 27.85,84.77 27.6,85.01 UL1.11
  TOP w0.508: v2(29.05,82.8) 29.05,82.86 28.67,83.24 CL25.1 28.67,84.76 CL20.1
  IN2 w0.762: v2(29.05,82.8) 27.85,84.01 26.32,84.01 26.04,83.73 22.93,83.73 21.43,82.23
  BOTTOM w0.381: RL17.1 21.43,84.77 21.73,84.48 21.73,81.89 v2(21.24,81.4)
  vias: v2(21.24,80.7) v2(22.39,94.29) v2(23.02,94.29) v4(23.91,95.46)
+LCDVDD: length 6.5
  TOP w0.102: v4(222.91,52.78) 221.57,54.11 v4(221.57,54.59) ; v4(221.57,54.59) v4(223.35,54.59) ; v4(221.57,54.59) 221.23,54.94 220.44,54.94 220.06,55.31 U1.1
+LCDVDD_LCD:
  vias: v1(214.37,56.61) v2(214.22,57.76) v2(214.22,57.13) v2(214.85,57.76) v2(214.85,57.13)
+LINE1_VREFO_L: length 2.4
  TOP w0.203: UA1.31 24.46,13.05 RA29.1
+LINE1_VREFO_R: length 2.6
  TOP w0.203: UA1.30 25.62,13.45 v1(25.61,13.44) 25.56,13.39 24.99,13.39 24.48,13.9 RA33.1
+MIC2-VREFO: length 12.1
  TOP w0.203: UA1.29 v2(25.25,13.85)
  TOP w0.254: v2(30.39,20.95) RA25.1 RA26.1
  BOTTOM w0.254: v2(30.39,20.95) 30.39,18.99 v2(25.25,13.85)
+RTC_CELL: length 277.9
  TOP w0.127: v2(36.2,54.86) v4(36.2,54.24)
  TOP w0.508: v2(34.07,83.88) 33.51,83.88 32.69,83.06 RE70.2 32.7,81.93 RE41.1 ; RA12.2 26.39,21.33 v2(25.24,22.47) ; Q23.3 v2(59.57,28.68) ; v2(39.89,82.59) 39.43,82.13 RE7.1 ; RC91.2 103.21,62.37 103.62,61.96 v2(103.62,61.73) ; D1.1 89.16,38.67 89.49,39 C1.1 89.49,41.81 v2(88.89,42.41)
  IN1 w0.508: v2(99.48,49.02) 98.21,47.75 98.21,46.65 97.24,45.68 92.15,45.68 v2(88.89,42.41) 88.79,42.41 88.22,41.84 67.92,41.84 67.66,42.1 61.57,42.1 57.65,46.02 56.8,46.02 55.92,46.91 55.92,58.32 55.07,59.17 55.07,70.35 54.68,70.73 54.68,80.75 53.18,82.25 v2(53.18,83.58) ; v2(59.57,28.68) 58.81,28.68 56.91,30.59 54.36,30.59 49.66,35.29 45.23,35.29 38.97,41.55 38.97,52.1 v2(36.2,54.86)
  IN2 w0.508: v2(34.07,83.88) 34.83,84.64 38.77,84.64 39.53,83.88 39.53,82.95 v2(39.89,82.59) 40.16,82.86 41.26,82.86 42.73,84.34 52.43,84.34 v2(53.18,83.58) ; v2(36.2,54.86) 34.71,54.86 33.96,55.6 22.82,55.6 20.82,53.6 20.82,47.03 20.96,46.88 20.96,44.46 18.8,42.29 18.8,34.67 21.31,32.16 22.36,32.16 24.42,30.1 24.42,26.99 25.12,26.29 25.12,22.6 v2(25.24,22.47)
  BOTTOM w0.508: v2(36.2,54.86) 36.74,54.86 37.76,55.88 37.76,59.92 37.54,60.14 37.54,78.54 39.89,80.89 v2(39.89,82.59) ; RC199.2 108.43,67.5 103.62,62.68 v2(103.62,61.73) 103.32,61.43 102.35,61.43 99.16,58.24 99.16,53.74 99.44,53.46 99.44,49.05 v2(99.48,49.02) ; RC78.2 90.89,39.25 RC77.2 87.21,40.73 v2(88.89,42.41)
+RTC_CELL_PCH: length 102.3
  TOP w0.254: v2(120.52,70.97) 120.26,70.97 119.84,71.38 119.56,71.38 119.52,71.42 119.12,71.42 119.08,71.38 118.92,71.38 118.87,71.43 118.47,71.43 118.42,71.38 118.23,71.38 118.2,71.41 117.82,71.41 117.8,71.38 113.86,71.38 111.97,69.49 v2(111.97,67.64)
  TOP w0.508: v2(100.54,48.11) 100.54,47.94 99.73,47.13 99.47,47.13 98.39,46.04 98.39,45.84 97.94,45.39 97.94,36.18 99.58,34.54 v2(99.58,33.05) ; Q23.1 C38.1 ; C38.1 v1(62.51,31.34) v2(63.15,31.99) ; C38.1 R74.1
  IN1 w0.508: v2(99.58,33.05) 99.04,32.52 96.39,32.52 95.91,32.04 92.87,32.04 92.06,31.22 85.2,31.22 85.05,31.07 65.95,31.07 65.03,31.99 v2(63.15,31.99)
  BOTTOM w0.254: v2(111.97,67.64) 112,67.6 114.1,67.6 114.13,67.59 114.22,67.59 UC1.BB14 ; v2(120.52,70.97) 120.52,70.85 UC1.AK19
  BOTTOM w0.508: v2(111.97,67.64) CC71.1 CC70.1 109.66,67.64 RC199.1 109.52,67.08 109.3,66.86 108.64,66.86 106.58,64.81 106.58,63.51 103.66,60.58 102.49,60.58 99.97,58.06 99.97,54.73 101.02,53.68 101.02,50.79 100.54,50.31 v2(100.54,48.11)
+RTC_CELL_VBAT: length 4.1
  TOP w0.203: v1(37.91,78.79) 37.6,78.48 UE1.122
  TOP w0.457: v1(37.91,78.79) 38.6,79.48 CE14.1 38.6,80.21 RE7.2
+RTC_VCC: length 107.7
  TOP w0.508: R1.2 106.97,38.08 106.94,38.06 v1(106.94,37.19) 106.94,35.7 v2(108.05,34.6)
  IN1 w0.508: v2(108.05,34.6) 108.23,34.41 129.15,34.41 134.99,40.25 150.74,40.25 154.42,36.58 157.9,36.58 161.44,33.03 179.62,33.03 180.77,34.18 192.19,34.18 193.84,35.83 201.64,35.83 202.04,36.24 202.76,36.24 v2(203.2,35.8)
  BOTTOM w0.508: JIOB1.11 v2(203.2,35.8)
+TP_VDD: length 58.1
  TOP w0.508: R32.1 R31.1 126.21,27.65 v2(124.91,27.65) 123.73,27.65 R41.1 123.68,27.58 R46.1 123.68,25.45 123.1,24.87 v1(113.52,24.87) 110.92,24.87 110.89,24.9 ; R39.1 110.94,29.84 111.87,28.9 111.87,27.72 111.31,27.16 111.31,24.9 110.89,24.9 ; Q12.1 101.25,28.95 100.94,29.27 R36.2 101.76,30.03 102.82,31.09 107.6,31.09 R37.2 108.24,29.57 108.24,27.73 108.29,27.68 Q9.2 108.29,25.26 108.65,24.9 110.89,24.9 ; R47.1 120.2,27.59 v2(120.3,27.69) ; R40.1 C19.1 117.46,29.75 117.33,29.88 v2(117.33,30.24)
  IN1 w0.254: v2(124.91,27.65) 124.53,27.65 124.02,27.15 120.67,27.15 120.3,27.52 v2(120.3,27.69)
  BOTTOM w0.254: JTP1.8 117.6,30.5 v2(117.33,30.24) 117.33,28.32 117.96,27.69 v2(120.3,27.69)
+TPAN_VDD:
  vias: v2(213.39,40.68) v2(214.03,40.68) v4(216.32,40.69)
+TPAN_VDD_F: length 14.8
  TOP w0.102: R11.2 v1(222.54,48.74)
  TOP w1.016: 209.27,45.08 209.27,42.16 211.81,39.62 216.95,39.62 217.72,40.39 217.72,41.08
+V_DDR_REFA: length 6.1
  TOP w0.508: CD28.1 RD12.1 69.91,69.85 v2(69.73,69.67) ; RD9.2 69.73,68.69 v2(69.73,69.67) ; v2(69.73,69.67) v1(69.25,70.15) 68.94,70.46 RD10.2
  BOTTOM w0.305: v2(69.73,69.67) 69.92,69.49 JDIMM1.164
+V_DDR_REFA_R: length 135.8
  TOP w0.102: v2(68.4,67.72) v1(68.4,67.13)
  TOP w0.508: v2(68.4,67.72) 68.4,68.08 68.63,68.3 RD9.1 68.62,68.49 CD30.1
  VCC w0.508: v2(66.07,116.64) 66.07,70.67 68.4,68.34 v2(68.4,67.72)
  IN1 w0.381: v2(115.22,98.88) 116.54,100.2 121.77,100.2 123.16,101.6 123.16,105.28 123.29,105.41
  IN1 w0.508: 123.29,105.41 123.29,113.41 117,119.69 73.25,119.69 72.87,120.07 69.5,120.07 v2(66.07,116.64)
  BOTTOM w0.152: UC1.AY67 115.29,97.88 115.29,98.81 v2(115.22,98.88)
+V_DDR_REFB: length 8.8
  TOP w0.305: RD20.2 RD19.2 RD21.1 CD58.1 59.39,69.15 v1(60.35,69.15) 61.02,69.15 v2(61.57,69.7)
  BOTTOM w0.305: JDIMM2.164 59.41,69.49 59.72,69.18 61.05,69.18 v2(61.57,69.7)
+V_DDR_REFB_R: length 147.5
  TOP w0.305: RD19.1 58.36,70.92 57.71,71.57 CD59.1
  TOP w0.508: v2(56.87,70.54) 56.87,71.28 57.15,71.57 CD59.1
  IN1 w0.381: v2(114.46,98.3) 115.43,98.3 116.55,99.41 122.67,99.41 124.47,101.21 124.47,107.42
  IN1 w0.508: 124.47,107.42 124.47,113.49 116.85,121.12 77.22,121.12 75.6,122.74 63.03,122.74 56.04,115.76 56.04,71.37 v2(56.87,70.54)
  BOTTOM w0.254: UC1.BA67 114.57,98.19 v2(114.46,98.3)
AC_DIS: length 224.4
  TOP w0.102: v2(51.12,64.29) 50.99,64.42 50.6,64.42 50.2,64.83 UE1.69 ; PQB04.2 v1(209.6,56.3) 211.28,56.3 213.58,58.61 v2(214.85,58.61)
  IN1 w0.127: v2(51.12,64.29) 52.43,62.98 52.43,55.88 51.05,54.5 51.05,45.86 58.71,38.2 62.01,38.2 62.39,37.82 89.85,37.82 90.77,38.74 95.93,38.74 96.25,39.06 102.48,39.06 103.81,40.39 103.81,41.24 104.85,42.29 107.01,42.29 108.34,40.95 110.12,40.95 110.57,41.4 114.72,41.4 115.35,40.76 116.43,40.76 116.62,40.95 119.47,40.95 119.85,41.34 124.23,41.34 125.13,40.44 125.13,39.81 125.51,39.43 128.84,39.43 130.86,41.45 133.76,41.45 134.86,42.55 147.4,42.55 147.98,41.97 151.53,41.97 155.2,38.29 158.61,38.29 161,35.9 171.12,35.9 171.52,35.49 176.23,35.49 176.64,35.9 182.77,35.9 183.42,36.55 191.86,36.55 192.87,37.55 200.93,37.55 208.19,44.81 212.6,44.81 213.98,46.19 213.98,49.51 213.61,49.88 213.61,51.8 214.26,52.45 214.26,55.72 215.36,56.83 215.36,58.1 v2(214.85,58.61)
AC_PRESENT: length 26.2
  TOP w0.102: RC90.1 RC211.1 101.25,54.67 101.88,55.29 101.88,55.84 102.21,56.17 102.21,56.85 v1(102.13,56.93) 102.21,57.01 102.21,57.72 101.57,58.35 101.57,61.53 101.39,61.7 v2(101.11,61.7)
  BOTTOM w0.076: UC1.AY15 114.91,68.2 114.7,68.41 107.63,68.41 103.67,64.45
  BOTTOM w0.102: v2(101.11,61.7) 101.61,62.21 101.61,62.21 103.67,64.27 103.67,64.45
ACIN_CHG: length 9
  TOP w0.102: PQB04.1 204.32,58.34 v1(203.83,58.82)
  TOP w0.254: v2(203.42,53.72) 203.42,53.73 PCB12.1 PRB09.2 204.05,55.74 204.32,56 PQB04.1
  BOTTOM w0.203: PUB01.1 202.53,52.06 202.7,52.23 202.7,52.99 v2(203.42,53.72) 203.42,54.21 203.56,54.35 PCB12.1
ACLIM: length 4.1
  TOP w0.102: PRB32.2 v1(197.15,47.8)
  TOP w0.254: PRB32.2 198.55,47.8 v2(198.79,47.56)
  BOTTOM w0.203: PUB01.16 198.98,47.75 v2(198.79,47.56) 198.47,47.24 PRB35.1
ADDR_VBOOT_CPU: length 2.5
  BOTTOM w0.203: PUZ01.21 146.68,116.1 v1(146.57,116.21) 146.29,116.21 145.59,116.91 PRZ69.1
ADJ_2.5V: length 5
  BOTTOM w0.102: v1(54.38,37.22) 54.57,37.03 PR2502.2
  BOTTOM w0.254: PR2503.1 55.2,36.22 PR2502.2 54.54,36.2 PC2505.2 54.54,35.03 53.69,34.18 PU2501.7
ALERT#: length 3
  BOTTOM w0.102: R28.2 109.64,126 v1(109.17,125.54) 108.76,125.13 U2.6
ALERT#_CPU: length 2.3
  BOTTOM w0.102: PUZ01.33 151.81,118.99 152.82,119.99 PRZ47.1
ALL_SYS_PWRGD: length 338.1
  TOP w0.102: RC106.2 RC107.1 ; RC107.1 145.48,105.37 145.23,105.12 UC7.2 ; RC107.1 RC105.2 v2(147.08,105.87) ; v1(119.59,32) v2(120.3,32) 124.88,36.57 C35.1 124.37,37.32 124.37,37.78 124.26,37.89 UC6.4 ; v2(40.83,56.99) 41.12,57.27 RE42.1
  IN1 w0.127: v2(40.83,56.99) 40.83,55.42 45.11,51.14 45.11,44.8 56.03,33.88 60.04,33.88 62.82,31.1 64.93,31.1 65.97,30.06 85.28,30.06 85.69,30.46 92.32,30.46 92.85,30.99 96.25,30.99 97.26,32 v2(120.3,32) 120.9,31.4 135.13,31.4 136.33,32.6 143.9,32.6 146.01,30.49 153.22,30.49 154.05,31.32 161.93,31.32 162.52,30.74 179.91,30.74 181.59,32.41 192.95,32.41 194.22,33.68 206.29,33.68 209.18,36.57 209.18,38.15 210.78,39.75 215.29,39.75 218.79,43.26 218.79,54.22 v2(219.24,54.67)
  IN2 w0.127: v2(157.13,106.1) 160.42,106.1 166.14,100.38 166.14,81.83 165.2,80.89 165.2,77.82 170.15,72.87 180.91,72.87 187.17,66.61 199.49,66.61 200.69,65.4 201.89,65.4 206.47,60.83 213.97,60.83 216.63,58.16 216.63,57.27 v2(219.24,54.67)
  BOTTOM w0.102: v2(147.08,105.87) 147.63,105.32 156.09,105.32 156.87,106.1 v2(157.13,106.1)
ALWON: length 188.9
  TOP w0.102: v2(40.09,75.01) 39.23,75.01 38,76.24 UE1.121
  IN1 w0.127: v2(163.18,140.72) 163.15,140.72 158.56,145.32 152.79,145.32 150.36,142.9 119.93,142.9 114.49,142.9 111.53,145.85 92.21,145.85 91.25,144.89 82,144.89 70.36,133.25 62.14,133.25 57.31,128.43 v2(57.31,128.35)
  BOTTOM w0.102: v2(40.09,75.01) 40.42,75.33 40.42,75.75 43.56,78.89 43.56,85.15 44.61,86.2 44.61,91.31 41.93,93.99 41.93,120.03 50.86,128.96 56.7,128.96 v2(57.31,128.35)
  BOTTOM w0.254: PR506.1 v2(163.18,140.72)
AMBER_LED_BAT: length 2.8
  BOTTOM w0.102: R68.2 11.41,118.83 v1(11.21,118.63)
  BOTTOM w0.254: Q18.1 R68.2
ASGATE: length 33.6
  TOP w0.254: PRB07.2 179.93,67.11 v1(180.36,67.11) 181.74,67.11 182.69,68.07 183.82,68.07 184.01,67.88 184.54,67.88 186.62,65.79 186.62,65.28 191.52,60.38 193.96,60.38 194.73,59.62 199.81,59.62 199.93,59.75 200.48,59.75 v2(201.01,59.22)
  BOTTOM w0.203: PUB01.30 200.98,53.88 200.82,54.03 200.82,59.03 v2(201.01,59.22)
AUD_AGND: length 32
  TOP w0.102: v1(19.59,18.5) 19.72,18.63 v2(19.72,19.11)
  TOP w0.203: v2(26.2,15.87) 26.13,15.81 26.13,15.62 26.3,15.45 UA1.25 ; v2(27.73,9.39) 27.98,9.64 UA1.38
  TOP w0.508: v2(22.13,14.61) 22.44,14.92 CA23.2 ; v2(11.91,5.84) 11.91,5.65 11.97,5.58 RA18.1 ; CA26.2 v2(23.15,23.81) ; RA40.2 17.56,13.79 v2(17.48,13.71) ; EC2302.1 v2(26.39,23.99) ; v2(22.26,8.63) 22.91,7.98 CA12.2 ; RA22.1 v2(20.19,22.32) ; CA37.2 v2(17.12,10.98) ; EC3003.1 v2(21.31,8.12) ; CA7.2 v2(33.18,21.39) ; RA41.1 v2(20.42,17.27) ; CA20.1 20.48,16.19 v2(19.97,16.7) ; CA11.2 v2(24.74,17.78) ; CA41.2 CA42.2 v2(30.44,22.86) ; EC2301.1 v2(19.72,19.11) ; CA10.2 24.16,16.63 v2(23.91,16.89) ; RA17.1 12.8,5.65 v2(12.61,5.84) ; v2(25.18,7.98) CA21.1 ; CA36.2 15.73,9.13 v2(15.47,9.39)
  VCC w0.203: JHP1.7 11.08,7.23 ; JHP1.7 8.92,7.23 ; JHP1.7 10,7.23
  GND w0.203: JHP1.7 11.08,7.23 ; JHP1.7 8.92,7.23 ; JHP1.7 11.08,7.9 ; JHP1.7 8.92,7.9 ; JHP1.7 10,7.23
  BOTTOM w0.508: v2(16.73,13.65) 16.37,14.02 RA34.2 CA34.2 ; CA35.2 RA30.2 17.48,14.09 v2(17.48,13.71)
AUD_HP1_JACK_L: length 2.5
  TOP w0.203: RA27.1 24.61,12.38 24.88,12.65 UA1.32
AUD_HP1_JACK_L1: length 13.5
  TOP w0.102: v2(22.13,11.49) 22.06,11.41 v1(21.37,11.41)
  TOP w0.305: RA29.2 RA27.2 RA36.1 22.08,11.54 v2(22.13,11.49) ; RA28.2 v2(23.97,19.36)
  BOTTOM w0.305: v2(23.97,19.36) 23.61,19 23.61,18.75 22.72,17.85 22.72,14.46 21.94,13.69 21.94,11.68 v2(22.13,11.49)
AUD_HP1_JACK_R: length 8.3
  TOP w0.127: v2(20.48,12.95) 20.18,12.64 v1(20.18,12.28)
  TOP w0.203: v2(25.05,12.12) 25.23,12.3 26.25,12.3 26.3,12.25 UA1.33
  TOP w0.305: RA31.1 20.67,13.14 v2(20.48,12.95)
  IN2 w0.305: v2(20.48,12.95) 21.31,12.12 v2(25.05,12.12)
AUD_HP1_JACK_R1: length 14.1
  TOP w0.127: v1(21.52,14.84) 21.52,14.54 22.08,13.98 RA37.1
  TOP w0.305: RA33.2 22.94,13.9 v2(22.77,13.72) 22.59,13.9 RA37.1 RA31.2 ; RA32.2 v2(23.72,22.66)
  BOTTOM w0.305: v2(22.77,13.72) 23.22,14.18 23.22,17.34 24.55,18.66 24.55,21.59 24.08,22.05 24.08,22.31 v2(23.72,22.66)
AUD_PC_BEEP: length 2.7
  TOP w0.203: UA1.16 30.78,16.76 v1(31.4,17.38) 31.83,17.38 32.29,17.84 CA31.2
AUD_PC_BEEP_C: length 6.7
  TOP w0.102: DA3.1 31.15,27.11 v1(33.04,25.22) 34.15,24.11 RA23.1
AUD_SENSE: length 22.1
  TOP w0.254: v2(32.67,16.82) 32.89,16.82 34.05,17.99 RA10.1 ; RA39.1 15.78,13.01 v1(16.17,12.63) 16.42,12.38 v2(16.67,12.38)
  IN1 w0.381: v2(16.67,12.38) 17.09,11.96 17.65,11.96 22.03,16.34 24.7,16.34 25.18,16.82 v2(32.67,16.82)
AUD_SENSE_A: length 5.2
  TOP w0.102: CA7.1 33.77,20.38 v1(34.13,20.38)
  TOP w0.203: CA7.1 33.14,19.75 RA3.1 RA10.2 33.14,18.05 31.98,16.9 UA1.13
AUD_SPK_L+: length 1.1
  TOP w0.102: v1(28.19,7.51) 29.11,7.51 RA15.1
AUD_SPK_L+_C: length 10.3
  IN2 w1.016: 27.59,4.63 27.02,4.06 23.47,4.06 23.02,4.5 20.51,4.5 19.7,3.7 18.07,3.7
  vias: v1(29.07,4.92) v2(14.9,4.2) v2(14.9,3.56) v2(16.48,3.38) v2(17.12,3.38) v2(28.53,5.25) v2(28.53,4.66)
AUD_SPK_L-:
  vias: v1(30.04,8.64)
AUD_SPK_L-_C: length 13.9
  IN2 w1.016: 29.43,3.42 28.48,2.47 23.07,2.47 22.44,3.11 21.09,3.11 20.28,2.3 16.54,2.3
  vias: v1(14.46,2.55) v2(13.63,4.21) v2(13.63,3.57) v2(15.66,1.45) v2(16.29,1.45) v2(29.72,5.24) v2(29.72,4.65)
AUD_SPK_R+: length 7.7
  IN2 w1.016: 32.27,9.16 33.09,8.34 33.09,3.34 31.97,2.22
  vias: v1(29.27,2.12) v2(30.23,2.07) v2(30.86,2.07) v2(30.99,9.31) v2(31.41,8.88)
AUD_SPK_R+_C: length 1.5
  TOP w0.102: v1(26.53,1.43) 26.04,1.91 RA13.2
  vias: v2(21.34,2.14) v2(21.97,2.14)
AUD_SPK_R-: length 3.5
  IN2 w1.016: 30.61,7.73 30.61,4.27
  vias: v1(28.77,3.34) v2(30.48,9) v2(30.53,3.41) v2(30.93,8.55) v2(31.12,3.41)
AUD_SPK_R-_C:
  vias: v1(20.07,4.83) v2(18.77,4.63) v2(19.4,4.63)
AUD_VREF: length 3.2
  TOP w0.203: UA1.28 25.53,14.25 25.26,14.52
  TOP w0.254: 25.26,14.52 v1(24.96,14.82) 24.86,14.92 CA23.1
AUX_ON: length 47.1
  TOP w0.102: v2(29.12,92.32) 27.21,94.23 v1(27.21,94.24) 27.21,98.86 26.64,99.44 UL2.4 26.64,100.96 26.88,101.2 RL6.2 ; UE1.3 34.68,74.83 35.12,75.27 37.15,75.27 38.23,74.19 v2(41.91,74.19)
  IN1 w0.127: v2(41.91,74.19) 41.91,82.51 36.86,87.56 v2(36.86,91.75)
  BOTTOM w0.102: v2(36.86,91.75) 36.29,92.32 v2(29.12,92.32)
BA: length 30.3
  TOP w0.508: PQB08.1 172.06,36.89 PRB28.1 172.06,38.4 v1(173.29,39.63) v2(174.21,40.56)
  IN1 w0.508: v2(174.21,40.56) 176.35,40.56 176.5,40.41 188.16,40.41 188.28,40.53 193.9,40.53 194.24,40.19 195.68,40.19 196.06,40.57 v2(196.06,41.35)
  BOTTOM w0.508: v2(196.06,41.35) 195.67,41.73 PDB01.3
BAT1_LED#: length 77.3
  TOP w0.102: UE1.106 44,75.59 v2(44.04,75.56) ; v2(27.94,78.06) 28.01,78.13 31.02,78.13 31.23,77.93 RE18.1 v2(33.56,77.66)
  IN1 w0.127: v2(31.56,120.43) 28,116.87 28,92.45 28.36,92.1 28.36,89.66 29.83,88.18 29.83,84.2 30.36,83.66 30.36,80.5 27.94,78.08 v2(27.94,78.06)
  IN2 w0.127: v2(33.56,77.66) 34.39,76.82 41.31,76.82 42.58,75.56 v2(44.04,75.56)
  BOTTOM w0.102: v2(31.56,120.43) 31.45,120.53 v1(23.94,120.53) Q17.1
BAT2_LED#: length 62.4
  TOP w0.102: RE21.1 31.78,76.77 32.29,76.26 v2(32.29,76.13) 32.29,76 32.67,75.63 UE1.1
  IN1 w0.127: v2(32.29,76.13) 32.29,76.32 30.62,78 30.62,83.73 33.03,86.14 33.03,117.24 v2(31.53,118.74)
  BOTTOM w0.102: Q17.4 17.34,119.23 17.83,118.74 v1(27.25,118.74) v2(31.53,118.74)
BATT_WHITE_LED_R#: length 9.9
  TOP w0.102: v2(19.27,123.63) v1(19.27,122.73) 19.27,119.93 v2(19.97,119.23)
  BOTTOM w0.102: Q17.3 v2(19.97,119.23) ; Q19.2 16.53,124.6 17.5,123.63 Q22.1 v2(19.27,123.63)
BEEP: length 39.4
  TOP w0.102: DA3.2 28.64,28.08 31.47,30.9 v1(31.47,32.16) 31.47,38.1 v2(31.21,38.35) ; UE1.45 40,60.09 39.77,59.86 39.77,55.55 v2(35.21,50.99)
  IN1 w0.127: v2(35.21,50.99) 35.21,42.35 v2(31.21,38.35)
BKLT_CTRL: length 10.1
  TOP w0.102: RP1.8 215.04,52.43 215.62,51.86 215.62,51.1 215.81,50.9 RP2.7 217.31,50.9 218.56,52.15 D3.1 221.01,52.15 221.29,52.43 v1(221.29,52.97) 221.29,53.12 R9.1
BKLT_IN_EC: length 144.5
  TOP w0.102: UE1.67 50.04,64.03 v1(51,63.08) 51.37,62.7 v2(51.37,62.64)
  IN1 w0.127: v2(130.31,39.02) 129.87,39.47 129.28,39.47 128.99,39.17 125.38,39.17 124.88,39.68 124.88,40.34 124.13,41.09 120.03,41.09 118.73,39.78 118.32,39.78 118.29,39.75 115.43,39.75 114.68,40.5 108.44,40.5 106.9,42.03 104.96,42.03 104.06,41.14 104.06,40.28 102.59,38.81 96.36,38.81 96.04,38.49 90.88,38.49 89.96,37.57 62.28,37.57 61.9,37.94 58.61,37.94 50.8,45.75 50.8,54.61 52.17,55.99 52.17,61.9 51.44,62.64 v2(51.37,62.64)
  IN2 w0.127: v2(129.11,65.95) 129.57,65.49 129.57,65.21 130.74,64.04 131.23,64.04 131.48,63.8 131.48,63.18 131.74,62.92 131.74,61.66 132.41,61 132.77,61 134.32,59.45 134.32,54.82 131.49,51.99 131.49,40.2 130.31,39.02 v2(130.31,39.02)
  BOTTOM w0.102: UC1.R12 128.84,65.95 v2(129.11,65.95) ; v2(130.31,39.02) 130.72,39.44 130.72,40.12 130.45,40.39 128.94,40.39 RC6.2
BLON_OUT_C: length 9.4
  TOP w0.102: RP1.7 214.54,53.39 214.3,53.14 214.3,51.76 v2(214.41,51.65) 214.66,51.4 RP2.1
  BOTTOM w0.102: v2(214.41,51.65) 214.92,51.14 214.92,50.22 213.96,49.26 213.96,48.02 212.89,46.95 JEDP1.28
BLUETOOTH_EN: length 148
  TOP w0.102: v2(74.27,133.28) 72.11,135.44 RW12.1
  IN1 w0.127: v2(93.13,47.2) 94.3,48.37 97.47,48.37 101.49,52.38 101.49,53.87 102.01,54.39 106.21,54.39 107.88,56.07 114.24,56.07 115.93,54.37 118.16,54.37 120.36,56.57 123.03,56.57 123.05,56.55 123.92,56.55 123.99,56.61 124.78,56.61 124.93,56.46 v2(125.22,56.46)
  BOTTOM w0.076: UC1.AB2 124.82,59.68 124.82,58.06
  BOTTOM w0.102: RC42.2 126.24,55.12 125.22,56.14 v2(125.22,56.46) 125.4,56.63 125.4,57.48 124.82,58.06 ; v2(93.13,47.2) 93.13,49.78 92.5,50.4 92.5,114.16 89.66,117 79.05,117 76.09,119.96 76.09,122.06 74.28,123.87 74.28,133.27 v2(74.27,133.28)
BOARD_ID: length 7.3
  TOP w0.102: UE1.111 42,78.11 v2(42.41,78.51) ; v2(42.41,80.68) 42.38,80.71 CE2.1 RE6.2 42.42,82.39 RE1.2 41.95,83.26 v1(41.54,83.68)
  IN1 w0.127: v2(42.41,80.68) v2(42.41,78.51)
BOARD_ID1: length 21.6
  TOP w0.102: v2(124.98,57.01) v1(125.61,57.01) ; v2(123.35,44.64) 123.83,44.64 124.4,44.07 RC58.1 123.57,42.46 RC57.2
  IN2 w0.127: v2(123.35,44.64) 122.39,45.59 122.39,50.14 124.92,52.66 124.92,56.15 124.75,56.32 124.75,56.78 v2(124.98,57.01)
  BOTTOM w0.076: v2(124.98,57.01) 124.97,57.01 124.81,57.01 124.42,57.39 124.42,58.01 124.42,58.02 UC1.AC1
BOARD_ID2: length 6.8
  BOTTOM w0.102: RC55.2 126.65,55.51 126.65,56.42 126.18,56.89 RC56.1 126.25,57.07 126.25,57.82 v1(126.15,57.92) 126.15,58.08 125.34,58.89 125.34,59.25 125.42,59.33 125.42,60.55 UC1.AB3
BST_1.2V: length 1
  BOTTOM w0.102: PRM02.1 v1(96.51,136.57)
BST_1.2V_R: length 1.5
  BOTTOM w0.102: PCM12.1 93.09,136.6 v1(92.08,135.59)
BST_3V:
  vias: v1(105.15,138.55)
BST_5V: length 0.9
  TOP w0.102: v2(154.36,137.12) v1(153.48,137.12)
BST_+1VALW:
  vias: v2(165.52,53.86)
BST_VCCSA: length 1
  BOTTOM w0.102: 171.66,62.24 v1(172.37,61.53)
BST_VCCSA_R: length 1.3
  BOTTOM w0.102: PCA07.1 v1(169.33,64.04)
BST_VCORE1:
  vias: v2(163.64,76.83)
BST_VCORE1_R: length 1.8
  BOTTOM w0.102: v1(166.25,78.54) 166.33,78.47 166.33,77.66 165.71,77.03 PRI01.2
BST_VCORE2:
  vias: v2(162.29,98.79)
BST_VCORE2_R: length 1.2
  BOTTOM w0.102: PCI29.1 165.01,97.26 v1(165.36,96.91)
BST_VGT1: length 2.3
  BOTTOM w0.102: PRG01.1 139.3,132.52 138.59,131.81 138.08,131.81 v1(137.6,131.33)
BST_VGT1_R: length 1.2
  BOTTOM w0.102: PRG01.2 v1(136.79,132.52)
CAP_LED: length 2.6
  TOP w0.102: v2(80.65,35.28) v1(81.16,35.28)
  BOTTOM w0.102: R25.2 81.11,35.74 v2(80.65,35.28) 80.55,35.18 JKB1.27
CAP_LED#: length 58.4
  TOP w0.102: v2(51.75,74.13) 51.31,74.13 51.01,74.43 UE1.93
  BOTTOM w0.102: v2(51.75,74.13) 52.36,73.52 52.36,63.38 52.64,63.1 52.64,55.79 55.29,53.14 55.29,45.42 57.21,43.49 58.58,43.49 61.18,40.9 73.28,40.9 v1(74.61,39.56) 75.3,38.88 R24.2 77.42,38.88 Q6.3
CAP_LED_Q: length 1.9
  BOTTOM w0.102: R25.1 82.89,36.73 Q7.1
CAP_LED_R#: length 5
  BOTTOM w0.102: Q6.1 80.01,37.66 v1(80.86,36.81) 81.44,36.81 82.57,37.94 Q7.2
CBN: length 6.4
  TOP w0.127: CA24.1 25.05,9.46 24.42,10.09 23.17,10.09 22.69,10.57 v1(22.34,10.57)
  TOP w0.203: 25.82,11.12 26.14,11.45 UA1.35
  TOP w0.305: 25.82,11.12 25.82,10.28 25.37,9.84 CA24.1
CBP: length 6.2
  TOP w0.102: v2(23.28,9.46) 22.89,9.46 v1(22.77,9.33)
  TOP w0.203: v2(26.96,9.9) 27.09,9.77 27.47,9.77 27.58,9.89 UA1.37
  TOP w0.305: CA24.2 v2(23.28,9.46)
  BOTTOM w0.305: v2(26.96,9.9) 26.51,9.46 v2(23.28,9.46)
CCLIM: length 3.9
  TOP w0.102: PRB33.2 v1(199.92,49.77)
  TOP w0.254: v2(201.15,47.78) 200.77,48.16 PRB36.1 PRB33.2
  BOTTOM w0.203: PUB01.11 200.98,47.95 v2(201.15,47.78)
CFG0: length 8.6
  BOTTOM w0.076: 138.05,100.36 137.52,99.84 137.52,98.79 137.5,98.76 137.5,98.63 137.69,98.44 137.69,98.14 137.4,97.85 137,97.85 136.6,97.46 135.16,97.46 134.87,97.62 UC1.E68
  BOTTOM w0.102: RC131.2 139.63,100.64 TPC10.1 138.23,100.54 138.05,100.36
CFG1: length 7.2
  BOTTOM w0.076: UC1.B67 136.22,98.14 136.64,98.14 137.36,98.86 137.36,100.11 138.08,100.83
  BOTTOM w0.102: RC132.2 140.14,101.84 TPC11.1 139.09,101.84 138.08,100.83
CFG2: length 10.9
  TOP w0.102: v2(137.91,99.65) 133.43,99.65 TPC12.1
  BOTTOM w0.076: v2(137.91,99.65) 138.11,99.45 138.11,97.47 137.86,97.22 137.5,97.22 137.16,96.88 135.79,96.88 135.48,96.77 135.11,96.77 UC1.D65
CFG3: length 12.9
  BOTTOM w0.076: 138.17,104.1 138.17,103.85 RC133.2 137.68,101.89 137.16,101.37 137.16,101.04 137.14,101.03 137.14,100.59 137.03,100.47 137.03,99.18 136.62,98.77 136.34,98.77 135.38,97.81 UC1.D67
  BOTTOM w0.102: 138.17,104.1 138.17,105.17 138.59,105.6 140.34,105.6 TPC13.1 140.8,104.72 RC175.1
CFG4: length 4.9
  TOP w0.102: v2(134.69,101.12) 134.69,101.98 TPC14.1 133.73,102.6 133.42,102.29 RC136.2
  BOTTOM w0.076: v2(134.69,101.12) 134.74,101.08 134.74,100.7 134.44,100.4 134.44,100.05 134.24,99.85 UC1.E70
CFG5: length 7.3
  BOTTOM w0.076: 136.36,104.1 136.36,103.64 136.24,103.53 136.24,101.02 135.77,100.55 135.77,99.97 135.58,99.78 135.58,99.26 UC1.C68
  BOTTOM w0.102: TPC15.1 136.36,104.73 136.36,104.1
CFG6: length 5.4
  BOTTOM w0.076: UC1.D68 134.77,99.68 135.09,100 135.09,100.09
  BOTTOM w0.102: TPC16.1 135.52,103.97 135.52,101.06 135.09,100.63 135.09,100.09
CFG7: length 6
  BOTTOM w0.076: 136.98,101.12 136.96,101.1 136.96,100.64 136.86,100.54 136.86,99.61 136.69,99.44 136.44,99.44 136.28,99.28 135.84,99.28 135.53,98.97 UC1.C67
  BOTTOM w0.102: 136.98,101.12 136.98,102.89 TPC17.1
CFG8: length 5.8
  BOTTOM w0.076: UC1.F71 133.68,99.84 133.68,100.1 133.63,100.15 133.63,101.14 134.33,101.83 134.33,104.1
  BOTTOM w0.102: TPC20.1 134.33,104.59 134.33,104.1
CFG9: length 3.7
  BOTTOM w0.076: 132.92,101.07 132.92,102.37 TPC21.1 ; UC1.G69 132.79,99.02 132.79,99.28 132.72,99.49 132.72,99.63 132.78,99.86 132.78,99.99 132.72,100.11 132.72,100.38 132.92,100.58 132.92,100.92
  BOTTOM w0.089: 132.92,100.92 132.92,101.07
CFG10: length 4.8
  BOTTOM w0.076: 133.55,99.12 133.88,99.45 133.88,99.92 133.87,99.94 133.87,100.15 133.8,100.22 133.8,100.98 134.72,101.9 134.72,103.19 TPC22.1
CFG11: length 7.2
  BOTTOM w0.076: UC1.G68 133.23,98.6 133.23,99.33 133.35,99.45 133.35,99.92 133.47,100.04 133.47,101.22 133.92,101.67 133.92,104.1
  BOTTOM w0.102: 133.92,104.1 133.92,104.43 TPC23.1
CFG12: length 3.4
  BOTTOM w0.076: TPC24.1 131.96,102.12 131.96,100.61 132.1,100.48 132.1,100.09 132.04,99.95 132.04,99.84 132.1,99.71 132.1,99.48 UC1.H70
CFG13: length 5.5
  BOTTOM w0.076: UC1.G71 132.99,100.29 133.14,100.43 133.14,101.15 133.1,101.19 133.1,101.56
  BOTTOM w0.102: 133.1,101.56 133.33,101.79 133.33,102.65 133.16,102.83 133.16,104.17 TPC25.1
CFG14: length 5.4
  BOTTOM w0.076: UC1.H69 132.33,98.8 132.6,99.07 132.6,99.33 132.54,99.49 132.54,99.63 132.6,99.85 132.6,99.97 132.57,100.05 132.56,100.08 132.56,100.44 132.72,100.61 132.72,101.03 132.66,101.09 132.66,101.75 132.47,101.94 132.47,103.34 TPC26.1
CFG15: length 4.3
  BOTTOM w0.076: UC1.G70 133.18,99.76 133.18,99.99 133.3,100.11 133.3,101.26 133.29,101.28 133.29,101.42
  BOTTOM w0.102: 133.29,101.42 133.59,101.72 TPC27.1
CFG16: length 2.7
  TOP w0.102: TPC19.1 133.56,96.76 v2(133.56,96.8)
  BOTTOM w0.076: v2(133.56,96.8) 133.56,95.55 UC1.E63
CFG17: length 2.5
  TOP w0.102: v2(132.9,96.8) 132.52,97.18 TPC18.1
  BOTTOM w0.076: UC1.F63 133.24,95.82 132.94,96.12 132.94,96.76 v2(132.9,96.8)
CFG18: length 1.2
  TOP w0.102: v2(134.11,97.83) 134.12,97.82 TPC29.1
  BOTTOM w0.076: v2(134.11,97.83) 133.89,97.61 UC1.E66
CFG19: length 1.7
  TOP w0.102: TPC28.1 133.84,98.15 v2(133.53,97.83)
  BOTTOM w0.076: v2(133.53,97.83) 133.24,97.54 UC1.F66
CFG_RCOMP: length 2.8
  TOP w0.102: v1(133.1,93.3) 133.49,93.68 v2(133.49,93.82)
  TOP w0.254: v2(133.49,93.82) 133.42,93.88 133.42,94.32 133.07,94.67 RC134.1
  BOTTOM w0.254: v2(133.49,93.82) 133.49,93.68 UC1.E60
CHG_AMBER_LED_R#: length 3.2
  BOTTOM w0.102: v1(17.1,121.72) 17.25,121.58 Q17.6 15.3,120.53 Q18.2
CLK_ITPXDP_N: length 1.5
  TOP w0.097: v2(133.6,83.74) 133.51,83.65 133.51,83.37 133.73,83.16 TP8.1
  BOTTOM w0.097: UC1.F43 133.17,84.17 v2(133.6,83.74)
CLK_ITPXDP_P: length 1.5
  TOP w0.097: v2(134.18,83.77) 133.87,84.09 133.87,84.1 TP9.1
  BOTTOM w0.097: v2(134.18,83.77) 134.12,83.77 133.82,84.08 UC1.E43
CLK_PCIE_LAN_N2: length 194.9
  TOP w0.097: v2(27.53,87.3) 27.12,86.89 27.02,86.89 26.89,87.01 UL1.16
  IN2 w0.122: v2(27.53,87.3) 27.47,87.24 27.15,87.24 26.07,88.32 24.77,88.32 21.68,91.41 21.68,92.01 19.72,93.98 19.72,100.89 23.23,104.4 23.72,104.4 25.26,105.94 25.26,106.2 42.87,123.81 62.7,123.81 65.79,126.9 73.84,126.9 74.27,127.33 76.04,127.33 76.51,126.86 87.16,126.86 89.2,124.83 99.76,124.83 100.4,125.47 104.86,125.47 105.5,124.83 112.69,124.83 113.33,125.47 119.86,125.47 130.84,114.48 139.07,114.48 141.48,112.07 141.48,101.84 142.12,101.21 142.12,96.62 141.52,96.02 141.52,89.86 141.2,89.54 141.2,85.71 v2(140.95,85.45)
  BOTTOM w0.076: 141.1,84.92 140.96,84.79 138.99,84.79 138.03,83.82 136.89,83.82 136.81,83.75 135.92,83.75 135.86,83.81 135.4,83.81 135.29,83.7 135.29,83.27 135.24,83.22 135,83.22 134.92,83.3 UC1.D41
  BOTTOM w0.097: v2(140.95,85.45) 140.96,85.45 141.25,85.17 141.25,85.07 141.1,84.92
CLK_PCIE_LAN_P2: length 194.9
  TOP w0.097: v2(27.53,86.71) 27.46,86.79 27.29,86.79 27.2,86.7 26.96,86.7 26.88,86.61 UL1.15
  IN2 w0.122: v2(27.53,86.71) 27.5,86.71 27.22,86.99 27.05,86.99 25.97,88.07 24.67,88.07 21.43,91.3 21.43,91.91 19.47,93.87 19.47,100.99 23.13,104.65 23.61,104.65 25.01,106.05 25.01,106.31 42.77,124.06 62.6,124.06 65.68,127.15 73.74,127.15 74.17,127.58 76.15,127.58 76.61,127.11 87.27,127.11 89.3,125.08 99.65,125.08 100.29,125.72 104.96,125.72 105.6,125.08 112.59,125.08 113.23,125.72 119.96,125.72 130.94,114.73 139.17,114.73 141.73,112.17 141.73,101.94 142.37,101.31 142.37,96.51 141.77,95.92 141.77,89.76 141.45,89.43 141.45,85.54 v2(141.53,85.45)
  BOTTOM w0.076: UC1.C41 135.57,83.57 135.65,83.64 135.8,83.64 135.86,83.59 136.88,83.59 136.95,83.66 138.1,83.66 139.06,84.62 141.06,84.62 141.1,84.66
  BOTTOM w0.097: v2(141.53,85.45) 141.44,85.36 141.44,85 141.1,84.66
CLK_PCIE_LAN_REQ#: length 137.6
  TOP w0.102: v2(107,53.92) 106.13,53.05 106.13,51.33 105.98,51.18 RC73.2
  IN2 w0.127: v2(36.99,83.75) 38.08,83.75 38.45,83.38 38.45,81.33 39.51,80.27 44.84,80.27 45.93,79.17 47.52,79.17 49.17,77.52 50.38,77.52 50.83,77.97 53.85,77.97 57.38,74.44 57.38,55.51 58.45,54.44 58.45,47.95 58.89,47.51 58.89,46.5 61.9,43.48 83.28,43.48 83.79,43.99 83.79,44 84.16,44.37 89.3,44.37 90.66,45.73 91.48,45.73 91.96,46.21 91.96,47.16 92.43,47.62 93.37,47.62 94.3,48.55 96.06,48.55 96.66,49.15 97.4,49.15 98.45,50.19 102.8,50.19 106.52,53.92 v2(107,53.92) 107,54.8 108.61,56.42 108.61,56.7 109.21,57.3 109.67,57.3 111.01,58.63 111.54,58.63 112.23,59.32 112.23,59.91 113.08,60.76 113.68,60.76 114.34,61.43 114.34,62.04 116.4,64.1 116.9,64.1 v2(117.34,64.54)
  BOTTOM w0.097: UC1.AT8 117.68,64.19 v2(117.34,64.54)
  BOTTOM w0.102: RL13.1 29.5,85.53 30.13,84.89 35.85,84.89 v2(36.99,83.75)
CLK_PCIE_LAN_REQ#_R: length 2.8
  TOP w0.102: v2(27.47,85.62) 27.26,85.41 UL1.12
  BOTTOM w0.102: v1(28.15,84.49) RL13.2 27.56,85.53 v2(27.47,85.62)
CLK_PCIE_NVME_N4: length 194.3
  IN2 w0.122: v2(150.52,69.22) 150.69,69.05 150.69,67.03 151.58,66.14 151.58,61.78 152.31,61.05 152.31,58.61 152.79,58.12 152.79,50.12 149.46,46.79 149.46,42.37 146.24,39.15 142.82,39.15 141.82,38.15 141.82,36.56 140.85,35.59 140.61,35.59 131.96,26.94 127.12,26.94 126.61,26.44 119.9,26.44 119.4,26.94 113.93,26.94 113.19,26.2 100.99,26.2 100.7,25.9 88.13,25.9 87.47,25.25 49.76,25.25 48.27,26.74 45.41,26.74 45.07,26.39 30.9,26.39 26.08,31.21 26.08,32.15 26.42,32.48 v2(26.42,32.49)
  BOTTOM w0.097: UC1.B40 136.16,82.68 138.03,82.68 139.43,84.07 141.1,84.07 141.1,84.07 141.69,84.07 143.75,82.01 147.43,82.01 148.63,80.82 148.63,80.19 150.78,78.04 150.78,69.48 v2(150.52,69.22) ; JSSD1.53 26.37,33.39 26.08,33.09 26.08,32.82 v2(26.42,32.49)
CLK_PCIE_NVME_P4: length 194.3
  IN2 w0.122: v2(151.11,69.22) 150.94,69.05 150.94,67.13 151.83,66.24 151.83,61.88 152.56,61.15 152.56,58.71 153.04,58.23 153.04,50.02 149.71,46.69 149.71,42.27 146.34,38.9 142.92,38.9 142.07,38.05 142.07,36.46 140.96,35.34 140.71,35.34 132.06,26.69 127.22,26.69 126.72,26.19 119.8,26.19 119.3,26.69 114.04,26.69 113.29,25.95 101.09,25.95 100.8,25.66 88.23,25.66 87.57,25 49.66,25 48.17,26.49 45.52,26.49 45.17,26.14 30.8,26.14 25.83,31.11 v2(25.83,32.49)
  BOTTOM w0.097: UC1.A40 136.62,82.86 137.95,82.86 139.35,84.26 141.77,84.26 143.83,82.2 147.51,82.2 148.81,80.89 148.81,80.27 150.97,78.12 150.97,69.35 v2(151.11,69.22) ; v2(25.83,32.49) 25.89,32.55 25.89,33.35 25.87,33.37 JSSD1.55
CLK_PCIE_NVME_REQ#: length 125.8
  TOP w0.102: v2(107,53.27) 107,51.3 v1(106.42,50.73) 105.98,50.29 RC188.2
  IN2 w0.127: v2(96.59,47.18) 97.28,47.18 98.7,48.6 103.04,48.6 104.95,50.5 104.95,51.22 v2(107,53.27) 107.52,53.79 107.52,54.6 109.08,56.16 109.26,56.16 111.22,58.12 111.75,58.12 115.67,62.04 115.67,62.36 116.66,63.36 v2(116.66,63.59)
  BOTTOM w0.076: v2(116.66,63.59) 117.03,63.96 UC1.AU8
  BOTTOM w0.102: JSSD1.52 26.62,25.43 27.24,24.82 33.33,24.82 35.03,23.12 38.85,23.12 40.86,25.14 83.66,25.14 84.96,26.44 94.76,26.44 95.67,27.35 95.67,32.25 96.25,32.83 96.25,39.94 95.93,40.25 95.93,42.63 96.28,42.97 96.28,46.86 v2(96.59,47.18)
CLK_PCIE_WLAN_N1: length 105.6
  IN2 w0.122: v2(138.49,87.28) 138.65,87.45 138.65,90.07 139.29,90.71 139.29,100.39 133.74,105.93 133.74,107.96 119.05,122.65 88.29,122.65 86.91,124.03 80.73,124.03 79.47,125.29 75.2,125.29 74.84,125.65 74.84,125.95 v2(74.7,126.1)
  BOTTOM w0.076: v2(138.49,87.28) 138.73,87.04 138.73,86.72 138.83,86.62 138.83,85.37 137.82,84.36 136.99,84.36 136.65,84.53 136.5,84.53 136.31,84.48 136.17,84.48 136.03,84.33 136.03,84.2 135.9,84.07 UC1.B42
  BOTTOM w0.097: JWLAN1.49 78.27,133.55 78.12,133.39 77.76,133.39 74.9,130.53 74.9,126.3 v2(74.7,126.1)
CLK_PCIE_WLAN_P1: length 105.6
  IN2 w0.122: v2(139.08,87.28) 138.9,87.46 138.9,89.97 139.54,90.6 139.54,100.49 133.99,106.04 133.99,108.06 119.15,122.9 88.4,122.9 87.01,124.28 80.84,124.28 79.58,125.54 75.3,125.54 75.09,125.75 75.09,125.91 v2(75.28,126.1)
  BOTTOM w0.076: UC1.A42 136.23,84.07 136.19,84.1 136.19,84.26 136.24,84.31 136.33,84.31 136.52,84.37 136.61,84.37 136.95,84.2 137.89,84.2 139,85.3 139,86.69 138.9,86.79 138.9,87.1 v2(139.08,87.28)
  BOTTOM w0.097: v2(75.28,126.1) 75.09,126.29 75.09,130.46 77.84,133.21 78.03,133.21 78.19,133.05 JWLAN1.47
CLK_PCIE_WLAN_REQ#: length 223.6
  TOP w0.102: v2(108.31,54.67) 107.04,54.67 v1(106.04,53.68) 105.55,53.18 RC72.2
  IN2 w0.127: v2(117.35,63.59) 117.35,63.39 116.43,62.47 116.43,62.08 111.96,57.62 111.43,57.62 109.47,55.65 109.29,55.65 v2(108.31,54.67) 108.31,53.77 106.51,51.98 106.51,50.97 105.19,49.65 105.19,49.49 104.45,48.75 103.81,48.75 102.63,47.56 98.53,47.56 97.08,46.11 94.12,46.11 93.87,45.86 92.38,45.86 91.82,45.3 90.84,45.3 89.4,43.86 84.41,43.86 83.6,43.05 61.72,43.05 58.38,46.39 58.38,47.3 57.95,47.73 57.95,53.78 57.32,54.41 56.9,54.41 56.36,54.95 56.36,74.56 54.73,76.19 54,76.19 52.72,77.47 51.04,77.47 50.59,77.01 48.96,77.01 47.31,78.66 45.72,78.66 44.63,79.76 38.39,79.76 37.36,80.79 33.5,80.79 33.16,81.12 33.16,85.05 35.42,87.3 35.42,106.05 46.33,116.96 64.74,116.96 66.65,118.87 78.14,118.87 v2(78.58,118.42)
  BOTTOM w0.076: v2(117.35,63.59) 117.35,63.5 UC1.AT7
  BOTTOM w0.102: RW9.1 81.12,130.55 83.32,128.36 83.32,123.16 v2(78.58,118.42)
CLK_PCIE_WLAN_REQ#_R: length 3.1
  BOTTOM w0.102: JWLAN1.53 RW9.2 v1(81.12,135.56)
CLK_SMB: length 4.7
  TOP w0.102: v2(161.66,38.36) v1(161.24,38.78) 160.71,38.78 160.44,38.5 PR42.1
  BOTTOM w0.102: PBATT1.7 160.95,39.04 161.07,38.92 161.78,38.92 161.84,38.86 161.84,38.54 v2(161.66,38.36)
CLK_TP_SIO: length 123.4
  TOP w0.102: UE1.78 48.09,68.43 47.47,67.81 46.59,67.81 46.02,67.24 45.39,67.24 v2(45.21,67.06) ; R32.2 126.29,29.56 v2(125.86,29.56)
  IN2 w0.127: v2(45.21,67.06) 45.05,67.23 44.17,67.23 43.4,66.46 43.4,60.57 44.74,59.24 47.23,59.24 49.31,57.16 49.31,56.87 49.95,56.23 49.95,45.4 56.43,38.92 89.72,38.92 91.59,40.79 101.92,40.79 101.95,40.76 102.24,40.76 v2(102.4,40.91)
  BOTTOM w0.102: v2(125.86,29.56) 125.42,29.56 125.05,29.94 JTP1.1 125.05,31.3 124.95,31.4 124.77,31.4 124.66,31.5 124.66,31.93 C27.1 124.66,32.61 124.66,32.98 124.43,33.22 119.04,33.22 118.67,32.85 105.15,32.85 103.03,34.97 103.03,40.51 102.8,40.74 102.57,40.74 v2(102.4,40.91)
CMP_STRAP0: length 12.4
  TOP w0.102: v1(37.97,84.18) RE40.1 38.9,83.51 v2(38.92,83.49) ; v2(39.79,75.88) 39.61,75.88 39.2,76.29 UE1.118
  IN1 w0.127: v2(39.79,75.88) 39.79,76.89 40.26,77.36 40.26,78.77 39.98,79.05 39.98,81.55 40.33,81.91 40.33,82.78 39.62,83.49 v2(38.92,83.49)
CMP_VIN0: length 20.6
  TOP w0.102: RE37.1 52.81,70.12 RE52.1 51.39,70.12 v1(50.97,70.54) v2(50.45,70.54) ; UE1.20 34.44,68.03 35.77,69.36 44.66,69.36 v2(44.86,69.15)
  IN2 w0.127: v2(50.45,70.54) 50.21,70.3 46,70.3 v2(44.86,69.15)
CMP_VOUT0: length 142.6
  TOP w0.102: v2(53.02,71.65) 53.02,71.22 RE49.2 51.96,71.02 RE52.2 50.66,71.03 50.46,71.23 UE1.85
  IN1 w0.127: v2(56.55,128.28) 56.57,128.28 61.8,133.51 70.23,133.51 82.52,145.79 91.79,145.79 92.11,146.11 111.87,146.11 v2(114.66,143.31)
  BOTTOM w0.102: v2(56.55,128.28) 56.1,128.73 50.96,128.73 43.06,120.84 43.06,94.26 50.99,86.33 50.99,75.71 52.16,74.54 52.16,74.05 53.02,73.18 v2(53.02,71.65) ; v1(114.09,143.51) 114.28,143.31 v2(114.66,143.31)
  BOTTOM w0.254: PR507.1 v2(114.66,143.31)
CMSRC: length 31.3
  TOP w0.254: v2(200.24,59.22) 194.59,59.22 193.81,60 v1(191.36,60) 186.24,65.12 186.24,65.63 184.38,67.5 183.85,67.5 183.66,67.69 182.85,67.69 182.28,67.11 182.28,65.59 182.81,65.05 PRB08.2
  BOTTOM w0.203: v2(200.24,59.22) 200.49,58.96 200.49,53.86 200.58,53.77 PUB01.29
COMP: length 4
  TOP w0.102: v2(202.6,47.11) v1(202.23,47.48)
  TOP w0.254: PCB29.1 202.73,46.99 v2(202.6,47.11)
  BOTTOM w0.203: PRB38.1 v2(202.6,47.11) 202.18,47.53 202.05,47.53 201.38,48.2 PUB01.10
COMP_1A_CPU: length 5.6
  TOP w0.102: v1(145.91,122.23) 146.41,121.72 146.67,121.72 PCZ30.1
  TOP w0.254: v2(148.24,119.4) 148.12,119.53 PCZ31.1 147.94,120.38 147.18,121.14 PCZ30.1
  BOTTOM w0.203: v2(148.24,119.4) 148.24,119.33 149.01,118.56 PUZ01.26
COMP_1B_CPU: length 3.9
  TOP w0.102: PCZ03.1 155.85,116.63 v1(155.99,116.77)
  TOP w0.254: PCZ03.1 PCZ01.1 v2(155.1,114.98)
  BOTTOM w0.203: PUZ01.43 155.03,114.9 v2(155.1,114.98)
COMP_2PH_CPU: length 4.3
  TOP w0.102: v1(151.72,110.6) 151.85,110.47 v2(152.5,110.47)
  TOP w0.254: PCZ16.2 152.48,108.84 PCZ15.2 152.48,110.46 v2(152.5,110.47)
  BOTTOM w0.203: v2(152.5,110.47) 152.5,110.6 151.81,111.28 PUZ01.4
CPU_DP1_CTRL_CLK: length 201.7
  IN2 w0.076: 132.72,66.23 132.71,66.23 132.68,66.2 132.11,66.2 131.91,66 130.91,66 130.86,66.05 130.84,66.05 130.53,66.36 130.36,66.36 v2(130.13,66.59) 129.95,66.59 129.37,67.17 128.83,67.17 128.22,66.56 126.72,66.56 126.1,65.94 125.67,65.94 125.4,66.21 124.06,66.21 123.09,65.23 123.09,61.89 122.25,61.06 122.25,60.71 122.08,60.54
  IN2 w0.127: 122.08,60.54 120.88,59.34 119.77,59.34 119.17,58.74 119.17,57.61 117.24,55.68 116.05,55.68 113.49,53.13 111.57,53.13 109.27,50.83 109.27,46.74 107.33,44.79 105.71,44.79 104.4,46.1 103.43,46.1 102.48,47.05 98.74,47.05 97.29,45.6 94.35,45.6 94.09,45.35 92.63,45.35 92.07,44.79 91.05,44.79 89.62,43.35 86.17,43.35 85.36,42.54 61.41,42.54 57.63,46.31 57.63,47.22 56.22,48.64 56.22,54.34 55.85,54.71 55.85,74.35 54.52,75.68 53.79,75.68 53.28,76.19 49.06,76.19 47.16,78.09 39.34,78.09 37.42,80.01 33.55,80.01 32.65,80.91 32.65,85.26 33.92,86.52 33.92,105.4 34.04,105.53 34.22,105.53 v2(34.39,105.36) ; 132.72,66.23 133.49,66.23 134,65.72 135.35,65.72 136.11,64.96 136.11,63.96 137.65,62.43 137.65,60.15 v2(137.61,60.11)
  BOTTOM w0.076: UC1.L13 130.29,66.59 v2(130.13,66.59)
  BOTTOM w0.102: v2(34.39,105.36) 34.21,105.54 26.97,105.54 26.13,104.71 23.68,104.71 QI2.1 ; v2(137.61,60.11) 137.38,59.88 137.38,59.5 137.58,59.3 139.54,59.3 140.11,59.87 140.77,59.87 RC1.1
CPU_DP1_CTRL_DATA: length 200.8
  IN2 w0.076: 132.72,65.97 132.72,65.97 132.69,66 132.2,66 132,65.8 130.82,65.8 130.78,65.84 130.76,65.84 130.45,66.16 130.31,66.16 v2(130.13,65.98) 129.74,66.37 129.74,66.51 129.28,66.97 128.92,66.97 128.3,66.35 126.8,66.35 126.18,65.73 125.59,65.73 125.3,66.03 124.12,66.03 123.29,65.2 123.29,61.81 122.45,60.97 122.45,60.58
  IN2 w0.127: v2(34.39,105.95) 34.22,105.78 33.94,105.78 33.66,105.5 33.66,86.63 32.4,85.36 32.4,80.8 33.45,79.76 37.31,79.76 39.23,77.84 47.05,77.84 48.96,75.93 53.18,75.93 53.69,75.43 54.41,75.43 55.6,74.24 55.6,54.6 55.96,54.23 55.96,48.53 57.38,47.12 57.38,46.2 61.3,42.28 85.46,42.28 86.28,43.1 89.72,43.1 91.16,44.53 92.18,44.53 92.74,45.1 94.2,45.1 94.45,45.35 97.4,45.35 98.84,46.8 102.37,46.8 103.32,45.84 104.3,45.84 105.6,44.54 107.43,44.54 109.53,46.63 109.53,50.72 111.68,52.87 113.59,52.87 116.15,55.43 117.35,55.43 119.42,57.5 119.42,58.63 119.87,59.09 120.99,59.09 122.45,60.55 122.45,60.58 ; v2(136.99,60.12) 137.4,60.53 137.4,62.32 135.86,63.86 135.86,64.85 135.25,65.46 133.89,65.46 133.38,65.97 132.72,65.97
  BOTTOM w0.076: v2(130.13,65.98) 130.32,65.98 UC1.L12
  BOTTOM w0.102: v2(34.39,105.95) 34.21,105.77 27.15,105.77 26.38,106.54 QI2.4 ; v2(136.99,60.12) 137.19,59.91 137.19,59.42 137.5,59.11 139.62,59.11 140.19,59.68 140.58,59.68 RC2.1
CPU_DP1_HPD: length 196
  IN2 w0.127: v2(126.07,63.95) 126.21,64.08 126.21,64.83 125.89,65.15 125.13,65.15 125,65.02 124.62,65.02 124.49,65.15 124.01,65.15 123.6,64.73 123.6,60.96 123.29,60.66 122.97,60.66 114.93,52.62 111.78,52.62 109.78,50.61 109.78,46.42 107.64,44.29 105.49,44.29 104.88,44.9 103.04,44.9 101.4,46.54 99.08,46.54 96.8,44.26 91.24,44.26 89.81,42.83 88.46,42.83 87.34,41.71 60.24,41.71 58.08,43.86 56.22,43.86 53.68,46.4 53.68,54.3 53.25,54.73 53.25,58.92 48.63,63.54 48.63,66.57 47,68.2 44.39,68.2 37.2,75.39 35.21,75.39 31.4,79.21 31.4,84.72 32.97,86.29 32.97,106.02 v2(37.87,110.93)
  BOTTOM w0.089: UC1.L9 130.25,64.6 126.23,64.6 126.08,64.45 126.08,63.95 v2(126.07,63.95)
  BOTTOM w0.102: QI3.3 22.02,107.54 RI15.2 21.83,109.74 23.02,110.93 v2(37.87,110.93)
CPU_DP2_AUXN: length 120.7
  TOP w0.097: RC195.2 213.69,33.94 213.87,33.94 v2(214.08,33.73) 214.28,33.92 214.38,33.92 CT60.1
  IN2 w0.076: v2(133.48,86.55) 133.48,86.64 133.57,86.74 134.04,86.74 134.44,86.34 134.98,86.34 135.01,86.31
  IN2 w0.122: v2(214.08,33.73) 213.88,33.92 213.1,33.92 211.47,35.55 211.47,40.46 210.66,41.26 210.66,41.97 210.34,42.3 210.34,43.85 210.66,44.18 210.66,46.41 211.19,46.94 211.19,50.08 210.67,50.6 210.67,54.8 209.33,56.14 208.21,56.14 202.8,61.54 199.63,61.54 198.27,62.9 183.84,62.9 177,69.74 156.84,69.74 148.52,78.06 148.52,80.61 147,82.13 139.93,82.13 138.85,83.2 138.85,85.96 137.31,87.5 136.54,87.5 135.33,86.3 135.02,86.3 135.01,86.31
  BOTTOM w0.097: v2(133.48,86.55) 133.48,86.6 UC1.E48
CPU_DP2_AUXN_C: length 2.9
  TOP w0.097: JVGA.9 217.08,34.75 216.93,34.91 216.76,34.91 216.49,34.64 216.49,34.15 216.25,33.91 215.95,33.91 CT60.2
CPU_DP2_AUXP: length 120.7
  TOP w0.097: CT59.1 214.35,34.11 214.28,34.11 v2(214.08,34.31) 213.89,34.13 213.69,34.13 RC196.2
  IN2 w0.076: 135.01,86.54 134.98,86.5 134.51,86.5 134.11,86.9 133.85,86.9 133.44,87.32 v2(133.44,87.35)
  IN2 w0.122: 135.01,86.54 135.02,86.55 135.23,86.55 136.43,87.75 137.41,87.75 139.1,86.06 139.1,83.3 140.03,82.38 147.11,82.38 147.14,82.35 148.77,80.71 148.77,78.16 156.94,69.99 177.11,69.99 183.95,63.15 198.37,63.15 199.73,61.79 202.9,61.79 208.31,56.39 209.43,56.39 210.92,54.9 210.92,50.7 211.44,50.18 211.44,46.84 210.91,46.31 210.91,44.07 210.59,43.75 210.59,42.4 210.91,42.08 210.91,41.36 211.72,40.56 211.72,35.65 213.2,34.17 213.94,34.17 v2(214.08,34.31)
  BOTTOM w0.097: v2(133.44,87.35) 133.44,87.21 UC1.F48
CPU_DP2_AUXP_C: length 2.9
  TOP w0.097: CT59.2 216.01,34.09 216.18,34.09 216.3,34.22 216.3,34.72 216.68,35.09 216.96,35.09 217.11,35.25 JVGA.8
CPU_DP2_CTRL_DATA: length 5.4
  TOP w0.102: v2(128.15,63.94) 127.72,63.51 v1(127.72,63.1) 127.8,63.03 128.35,63.03 128.56,62.82 128.56,61.86 RC212.1
  BOTTOM w0.076: UC1.N8 129.51,63.62 129.19,63.94 v2(128.15,63.94)
CPU_DP2_HPD: length 133.6
  TOP w0.102: JVGA.13 216.75,32.75 216.39,32.39 216.39,31.89 215.43,30.92 214.64,30.92 214.21,31.35 214.21,32.45 213.98,32.69 212.01,32.69 v1(210.57,34.13) 209.84,34.86 209.84,37.17 207.81,39.2 207.81,41.46 v2(207.27,42) ; RC5.2 130.14,62.03 v2(130.11,62)
  IN1 w0.127: v2(207.27,42) 206.46,42 201.25,36.79 193.19,36.79 192.18,35.78 183.74,35.78 183.09,35.14 180.38,35.14 179.48,34.24 161.58,34.24 158.29,37.53 154.89,37.53 152.79,39.63 151.21,41.21 134.59,41.21 131.36,37.97 129.07,37.97 v2(129.05,37.99)
  IN2 w0.127: v2(130.11,62) 130.11,61.5 130.3,61.31 130.3,58.92 131.45,57.77 131.91,57.77 132.24,57.44 132.24,55.68 131.92,55.37 131.92,54.22 130.22,52.52 130.22,49.96 129.2,48.94 129.2,40.14 128.81,39.75 128.81,38.22 v2(129.05,37.99)
  BOTTOM w0.102: UC1.L7 130.11,62.51 v2(130.11,62)
CPU_DP2_N0: length 113.5
  TOP w0.097: v2(213.76,37.55) 213.96,37.75 214.36,37.75 CT56.1
  IN2 w0.122: v2(213.76,37.55) 213.93,37.73 214.5,37.73 214.98,38.2 214.98,41.88 214.18,42.68 214.18,48.04 212.12,50.1 212.12,54.73 208.57,58.27 207.46,58.27 203.26,62.47 200.12,62.47 198.71,63.88 184.18,63.88 177.39,70.67 157.22,70.67 150.73,77.16 150.73,80.9 147.22,84.42 144.47,84.42 143.04,85.85 142.54,85.85 v2(142.41,85.98)
  BOTTOM w0.076: UC1.C50 135.25,87.74 135.29,87.7 135.62,87.7 135.62,87.69 135.63,87.69 135.79,87.64 136.83,87.64 137.01,87.82 139.48,87.82 140.9,86.39 141.07,86.39 141.08,86.41 141.1,86.41
  BOTTOM w0.097: 141.1,86.41 141.42,86.41 141.98,85.85 142.28,85.85 v2(142.41,85.98)
CPU_DP2_N0_C: length 2.3
  TOP w0.097: JVGA.3 217.17,37.75 217.02,37.91 216.45,37.91 216.34,37.79 216.03,37.79 CT56.2
CPU_DP2_N1: length 117.8
  TOP w0.097: CT58.1 214.3,35.91 214.2,35.91 v2(214,35.71)
  IN2 w0.122: v2(214,35.71) 214.17,35.88 215.29,35.88 215.67,36.26 215.67,47.5 213.98,49.19 213.98,49.86 212.79,51.04 212.79,55.01 208.85,58.95 207.74,58.95 203.54,63.14 200.4,63.14 198.95,64.6 187.52,64.6 182.03,70.08 180.17,70.08 178.91,71.34 157.5,71.34 151.41,77.44 151.41,81.18 147.89,84.7 147.5,85.09 144.84,85.09 142.99,86.94 142.61,86.94 142.35,87.2 142.35,87.35 v2(142.48,87.48)
  BOTTOM w0.076: 141.1,86.88 141.08,86.88 141.07,86.89 141,86.89 139.59,88.3 138.07,88.3 137.09,89.28 135.76,89.28 135.5,89.15 135.37,89.15 135.32,89.1 135.32,89.1 135.25,89.02 UC1.C52
  BOTTOM w0.097: v2(142.48,87.48) 142.28,87.29 142.28,87.09 142.07,86.88 141.1,86.88
CPU_DP2_N1_C: length 2.4
  TOP w0.097: CT58.2 216,35.86 216.2,35.86 216.7,36.36 217.04,36.36 217.16,36.25 JVGA.6
CPU_DP2_P0: length 113.4
  TOP w0.097: CT55.1 214.37,37.94 213.96,37.94 v2(213.76,38.14)
  IN2 w0.122: v2(213.76,38.14) 213.92,37.98 214.4,37.98 214.73,38.31 214.73,41.78 213.93,42.58 213.93,47.93 211.87,49.99 211.87,54.63 208.47,58.02 207.36,58.02 203.16,62.22 200.02,62.22 198.61,63.63 184.08,63.63 177.28,70.42 157.12,70.42 150.48,77.05 150.48,80.8 147.11,84.17 144.36,84.17 142.93,85.6 142.61,85.6 v2(142.41,85.4)
  BOTTOM w0.076: UC1.D50 135.15,87.53 135.22,87.53 135.59,87.53 135.59,87.53 135.6,87.53 135.76,87.47 136.9,87.47 137.08,87.65 139.41,87.65 140.83,86.23 141.07,86.23 141.08,86.22 141.1,86.22
  BOTTOM w0.097: 141.1,86.22 141.34,86.22 141.9,85.66 142.15,85.66 v2(142.41,85.4)
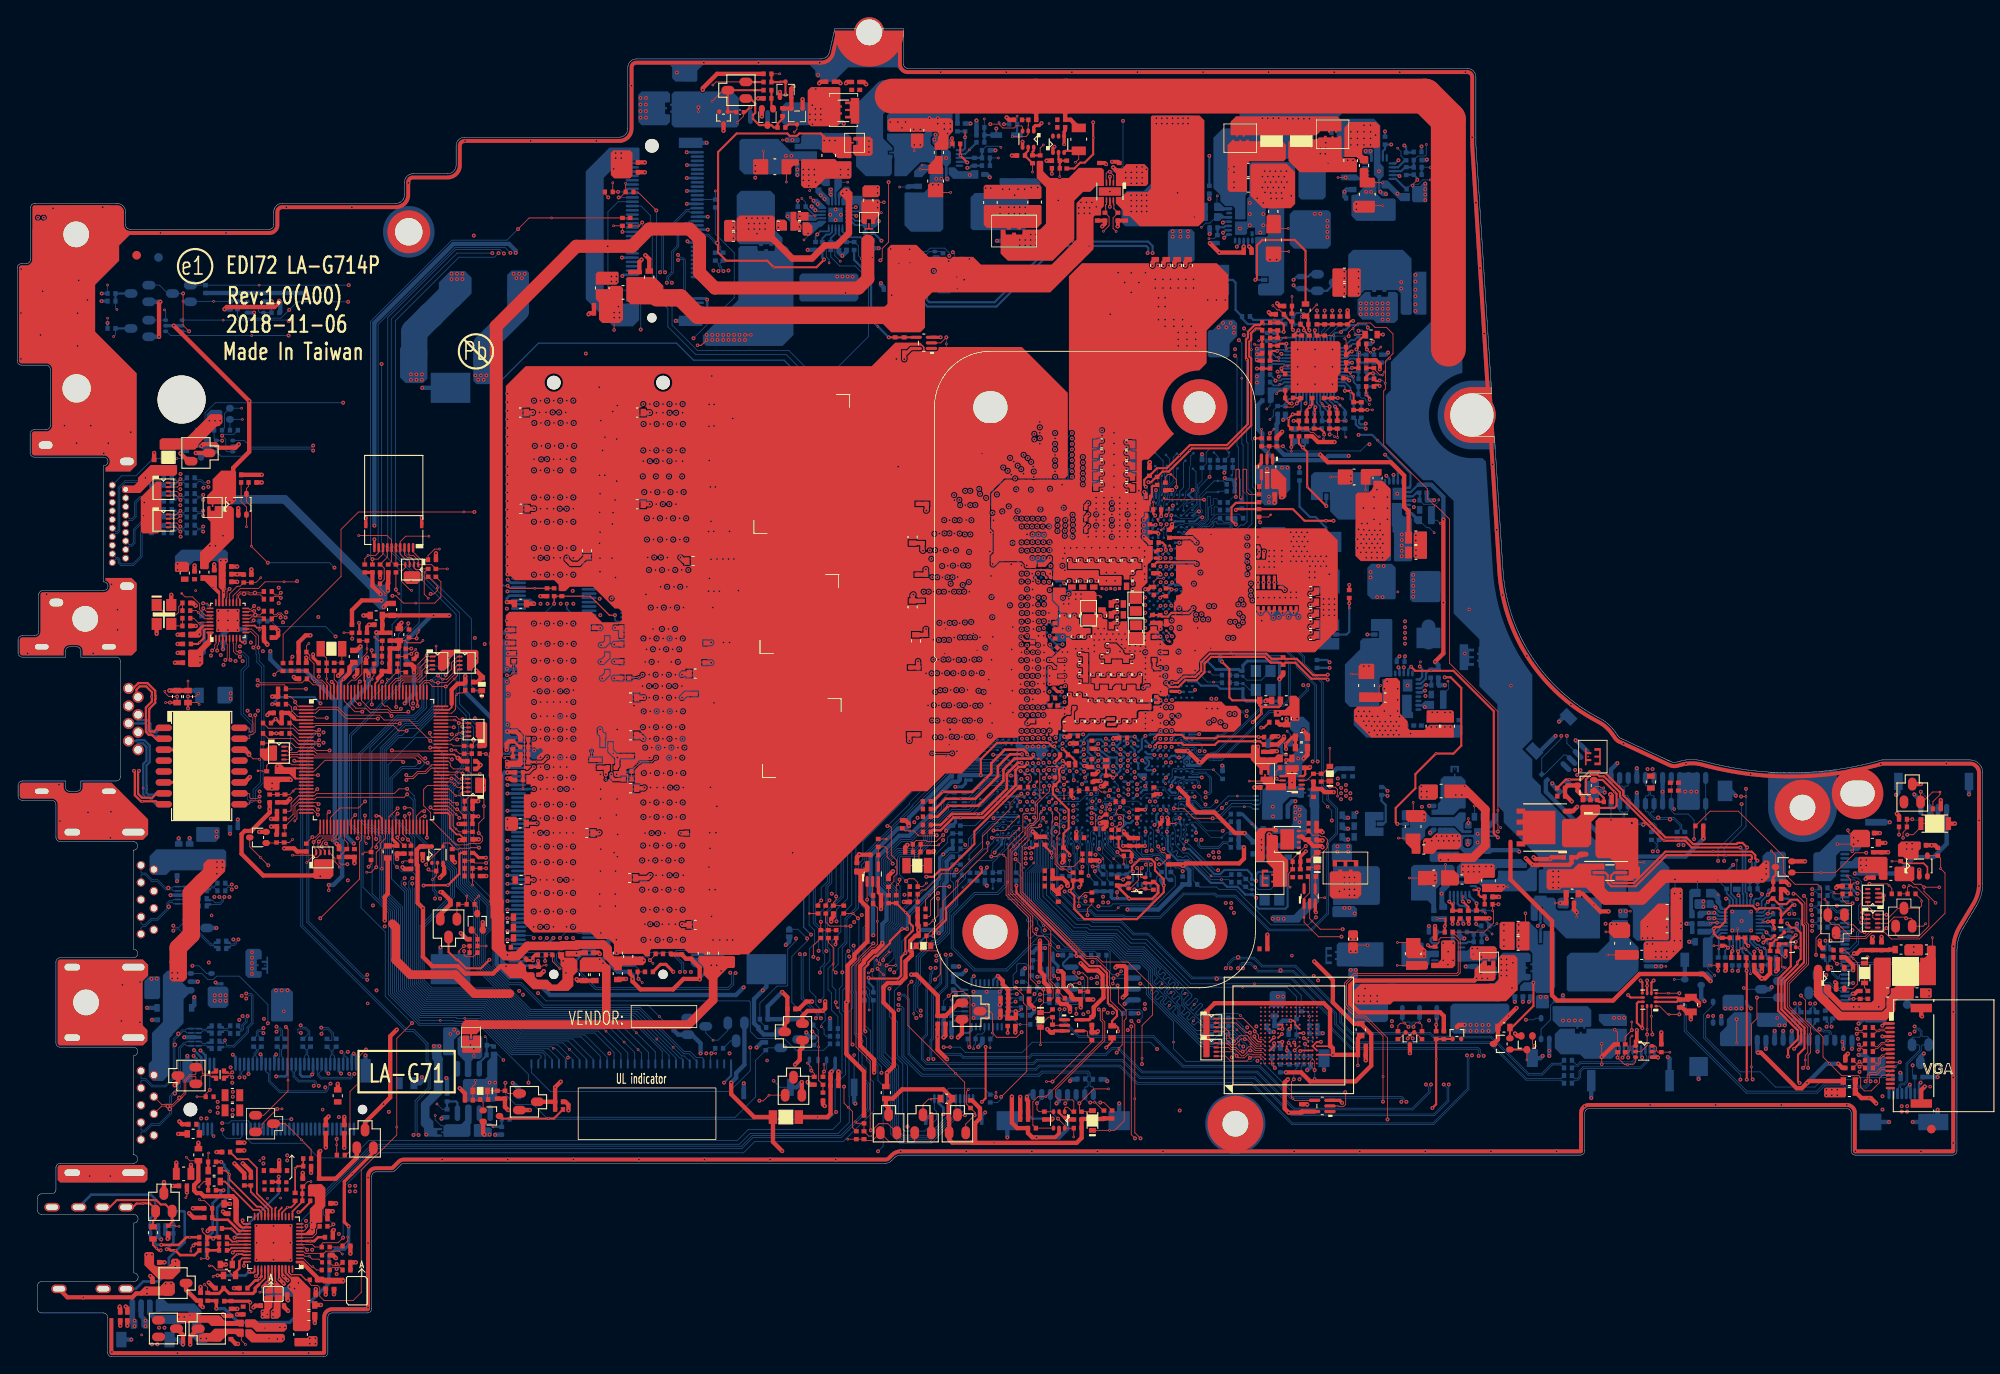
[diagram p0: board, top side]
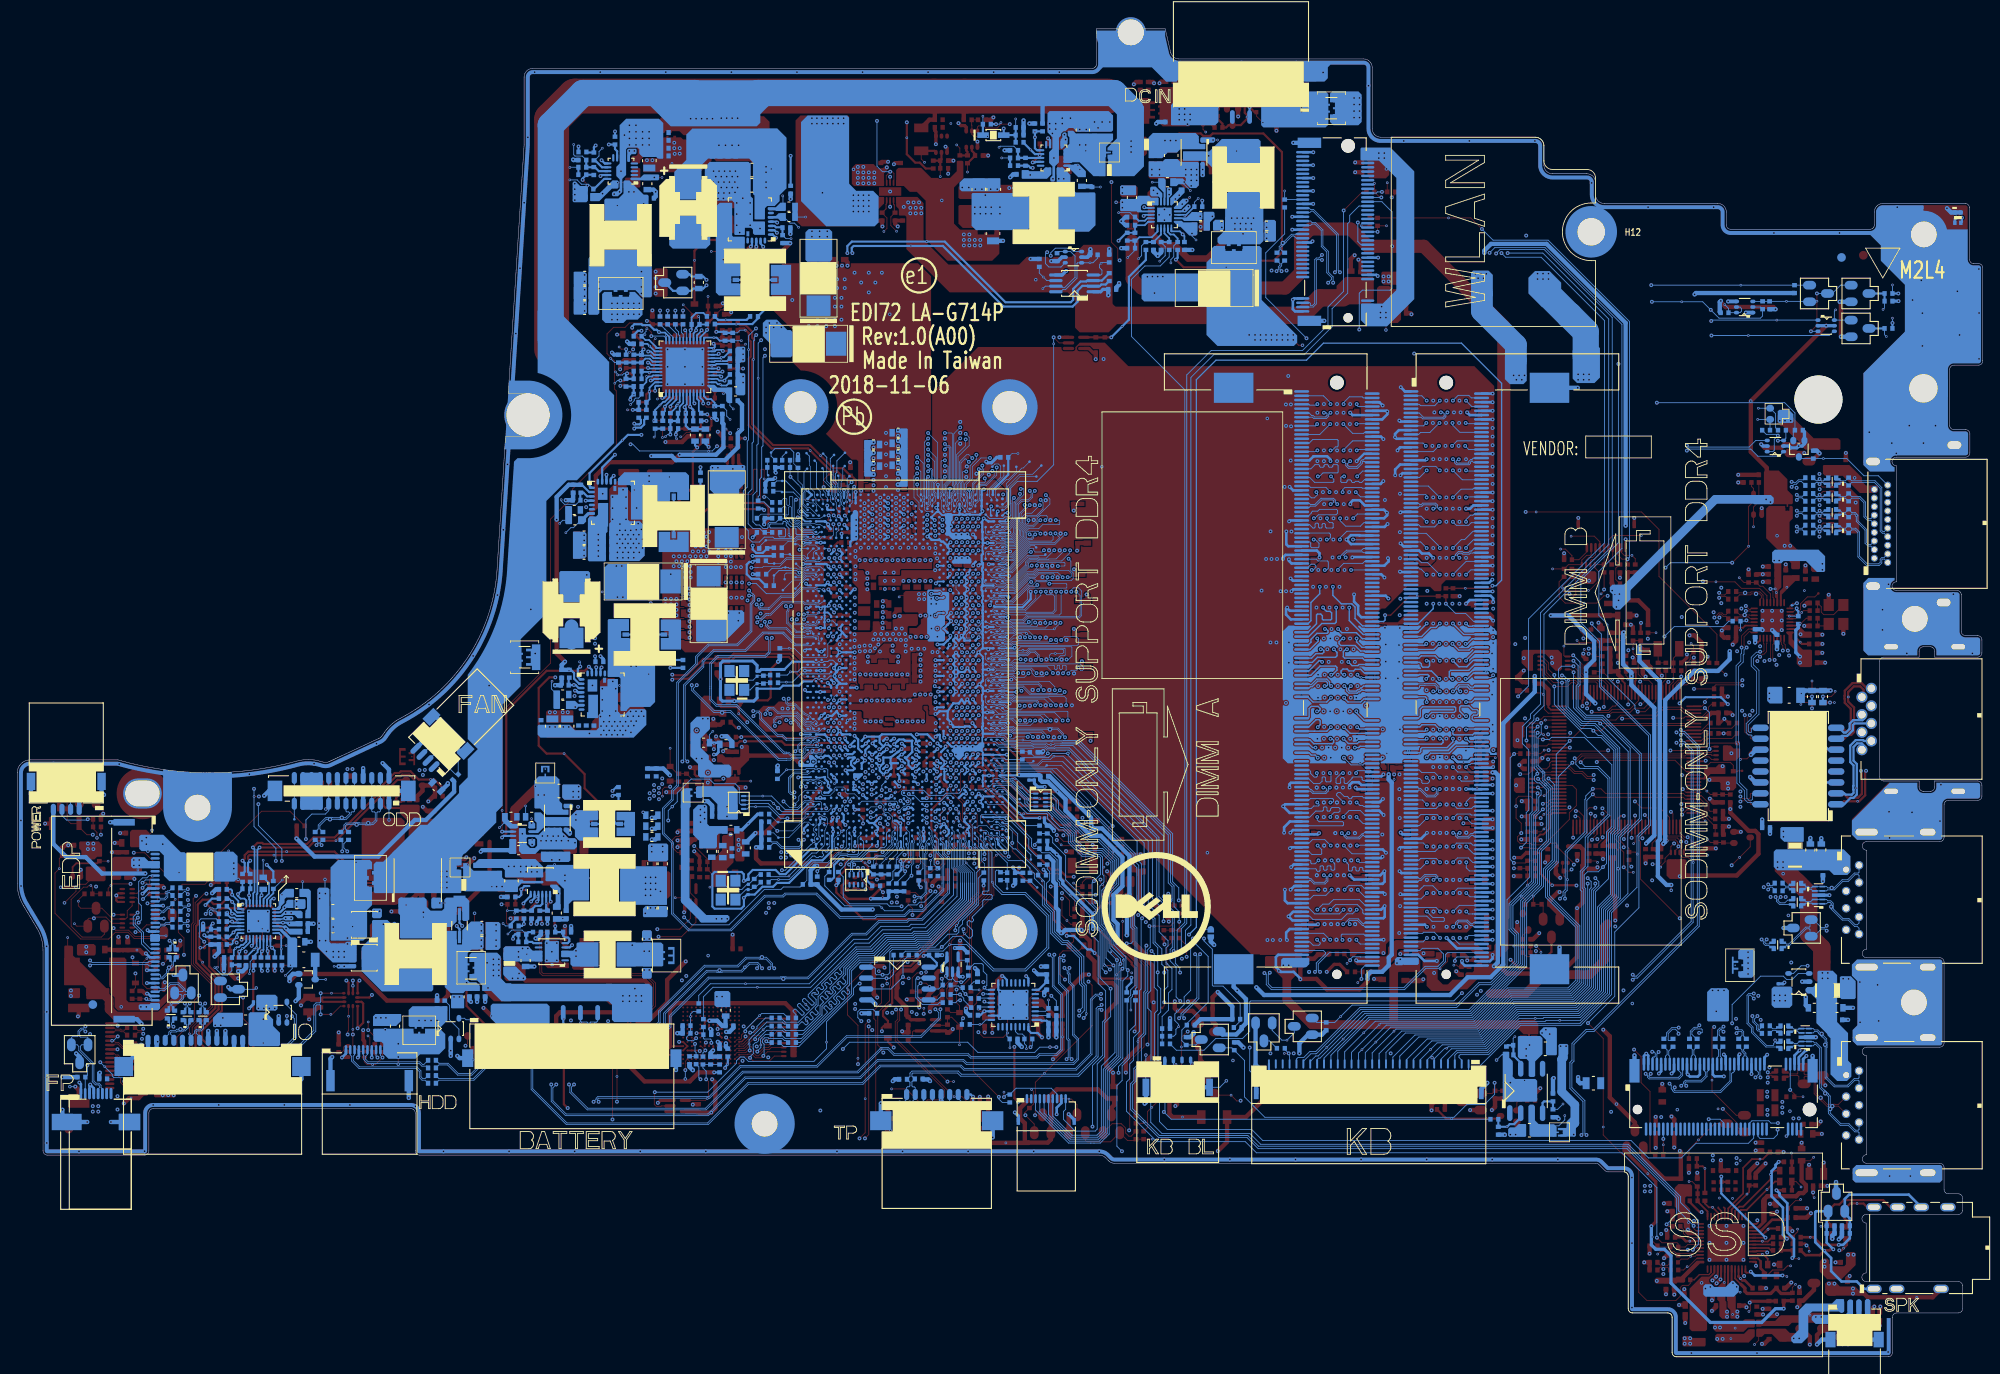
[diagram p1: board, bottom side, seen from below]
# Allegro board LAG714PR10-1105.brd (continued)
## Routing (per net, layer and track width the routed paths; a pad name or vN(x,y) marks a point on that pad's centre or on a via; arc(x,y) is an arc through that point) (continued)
CPU_DP2_P0_C: length 2.3
  TOP w0.097: CT55.2 215.93,37.98 216.26,37.98 216.37,38.09 216.99,38.09 217.15,38.25 JVGA.2
CPU_DP2_P1: length 117.8
  TOP w0.097: CT57.1 214.43,36.09 214.2,36.09 v2(214,36.29)
  IN2 w0.122: v2(214,36.29) 214.17,36.12 215.18,36.12 215.42,36.36 215.42,47.4 213.73,49.09 213.73,49.76 212.54,50.94 212.54,54.91 208.75,58.7 207.64,58.7 203.44,62.9 200.3,62.9 198.84,64.35 187.41,64.35 181.93,69.83 180.07,69.83 178.81,71.1 157.4,71.1 151.16,77.33 151.16,81.08 147.79,84.45 147.39,84.84 144.74,84.84 142.89,86.69 142.51,86.69 142.1,87.1 142.1,87.28 v2(141.9,87.48)
  BOTTOM w0.076: 141.1,87.07 141.08,87.07 141.07,87.05 139.66,88.46 138.14,88.46 137.16,89.44 135.76,89.44 135.75,89.44 135.69,89.44 135.43,89.32 135.06,89.32 134.76,89.02 UC1.D52
  BOTTOM w0.097: v2(141.9,87.48) 142.1,87.29 142.1,87.17 141.99,87.07 141.1,87.07
CPU_DP2_P1_C: length 2.4
  TOP w0.097: CT57.2 215.96,36.05 216.13,36.05 216.63,36.55 216.99,36.55 217.19,36.75 JVGA.5
CPU_POPIRCOMP: length 16.1
  TOP w0.305: RC119.1 106.36,61.22 107.3,61.22 108.78,62.7 v1(109.58,62.7) 112.25,62.7 116,66.45 116,68.21 116.38,68.59 117.02,68.59 117.38,68.94 v2(117.38,69.03)
  BOTTOM w0.254: v2(117.38,69.03) 117.38,69.03 117.38,68.96 UC1.AT16
CPU_XDP_TCK0: length 4.7
  BOTTOM w0.076: RC146.1 139.44,93.31 TPC2.1 138.46,93.15 136.94,93.15 136.64,92.85 UC1.A59 136.55,93.33 UC1.B61
CPVEE: length 2.7
  TOP w0.203: CA25.2 24.99,11.4 25.51,11.92 v1(25.61,11.92) 25.64,11.95 26.15,11.95 26.24,11.85 UA1.34
CS_1.2V: length 3.5
  BOTTOM w0.102: PRM03.1 91.61,134.23 v1(91.17,134.68)
  BOTTOM w0.203: PUM01.13 92.57,132.77 PRM03.1
CSCOMP_2PH_CPU: length 39
  IN1 w0.254: v2(152.5,80.1) 152.64,80.24 153.39,80.24 156.4,83.25 156.4,89.36 154.49,91.27 154.49,103.7 152.37,105.82 152.37,107.09 v2(152.51,107.23)
  BOTTOM w0.102: v1(153.08,106.98) 152.83,107.23 v2(152.51,107.23)
  BOTTOM w0.203: PUZ01.6 151.01,110.89 151.42,110.49 151.42,109.91 PCZ17.1
  BOTTOM w0.254: PCZ17.1 PCZ18.1 151.63,108.8 PRZ28.1 152.5,107.94 PRZ27.2 v2(152.51,107.23) ; PHZ02.2 v2(152.5,80.1)
CSCOMP_2PH_CPU_R: length 34.8
  TOP w0.254: PRZ26.2 151.43,107.92 151.86,107.48 v2(151.86,107.23)
  IN1 w0.254: v2(151.86,107.23) 151.99,107.1 151.99,105.66 154.11,103.54 154.11,91.11 156.02,89.21 156.02,83.41 153.23,80.62 152.62,80.62 v2(152.5,80.75)
  BOTTOM w0.102: v2(151.86,107.23) 151.86,106.82 v1(151.77,106.73)
  BOTTOM w0.254: v2(152.5,80.75) 152.23,81.02 PHZ02.1 ; v2(151.86,107.23) 151.86,107.48 151.6,107.75 PRZ27.1
CSI2_COMP: length 8.1
  BOTTOM w0.102: RC7.1 v1(139,68.26) 136.84,68.26 136.71,68.38 135.77,68.38 135.71,68.32 135.43,68.32 135.37,68.38 135.12,68.38 135.06,68.32 134.78,68.32 134.72,68.38 134.36,68.38 134.21,68.24 134.21,67.39 133.82,67.01 UC1.E13
CSN1_VCORE1: length 6.2
  TOP w0.102: v2(154.78,87.61) v1(154.78,87.05)
  TOP w0.254: PRZ31.1 v2(154.78,87.61)
  BOTTOM w0.254: v2(154.78,87.61) 154.78,84.29 154.47,83.98 PLI01.3
CSN2_VCORE2: length 8
  BOTTOM w0.254: PLI02.3 152.12,96.39 150.86,97.64 150.21,97.64 149.01,98.85 PRZ30.1
CSN_1A_VGT: length 11
  BOTTOM w0.254: PRZ51.1 v1(144.86,120.07) 142.99,120.07 142.32,120.73 PHZ03.2 141.58,121.71 141.58,124.89 141.26,125.21 PLG01.3
CSN_1A_VGT_NTC: length 4.4
  BOTTOM w0.254: PRZ45.1 146.93,120.56 v1(146.07,120.56) 143.65,120.56 PHZ03.1
CSN_1B_VCCSA: length 71.4
  TOP w0.102: v2(157.64,117.15) 158.2,117.15 v1(158.45,117.41)
  IN1 w0.254: v2(157.64,117.15) 157.64,116.85 159.93,114.56 159.93,110.54 169.58,100.88 169.58,71.43 166.85,68.7 161.39,68.7 160.82,68.13 160.82,65.72 160.31,65.21 v2(159.23,65.21)
  BOTTOM w0.254: PLA01.3 158.77,61.95 159.02,62.21 159.02,64.15 158.53,64.64 PHZ01.1 159.11,65.32 v2(159.23,65.21) ; PRZ06.1 v2(157.64,117.15)
CSP1_2PH_CPU: length 6
  TOP w0.254: PRZ37.2 147.74,108.26 v1(147.74,109.1) v2(148.22,109.58) 148.8,109.58 PCZ20.2
  BOTTOM w0.203: PCZ20.2 149.2,109.97 149.2,111.17 149.41,111.38 PUZ01.10
  BOTTOM w0.254: v2(148.22,109.58) 148.8,109.58 PCZ20.2
CSP1_VCORE1: length 30.1
  TOP w0.102: v2(148.05,105.79) v1(148.05,105.28)
  TOP w0.254: v2(148.05,105.79) PRZ37.1
  IN2 w0.254: v2(148.05,105.79) 150.91,102.93 153.07,102.93 154.97,101.02 154.97,91.63 156.88,89.72 v2(156.88,83.98)
  BOTTOM w0.254: PRZ25.1 148.43,106.17 v2(148.05,105.79) ; v2(156.88,83.98) PLI01.2
CSP2_2PH_CPU: length 9.1
  TOP w0.102: PRZ39.2 150.29,107.48 150.64,107.48 151.15,106.97 v1(151.3,106.97)
  TOP w0.254: v2(148.31,108.82) PRZ33.2 148.94,108.8 PRZ38.2 PRZ39.2
  IN1 w0.254: v2(149.7,110.85) 149.68,110.85 149.39,110.56 149.39,109.29 148.92,108.82 v2(148.31,108.82)
  BOTTOM w0.203: PUZ01.9 149.81,110.95 v2(149.7,110.85)
  BOTTOM w0.254: PRZ33.2 v2(148.31,108.82)
CSP2_VCORE2: length 11.4
  TOP w0.254: PRZ38.1 148.94,106.17 v2(149.39,105.72) 149.89,105.21 v1(149.89,101.13) v2(152.12,98.91)
  BOTTOM w0.254: v2(149.39,105.72) 149.64,105.98 PRZ29.1 ; PLI02.2 v2(152.12,98.91)
CSP_1A_VCORE: length 8.6
  TOP w0.102: v1(151.01,122.31) PRZ44.2
  TOP w0.254: PRZ44.2 150.03,120.68 PCZ26.1 150.03,119.47 v2(150.15,119.36)
  BOTTOM w0.203: PUZ01.29 150.21,119.3 v2(150.15,119.36) 150.03,119.47 PCZ27.1 150.03,120.85 149.51,121.37 148.66,121.37 PRZ45.2
CSP_1A_VGT_R: length 17.7
  TOP w0.254: PRZ44.1 v1(149.7,127.49) 149.7,128.58 148.43,129.85 144.69,129.85 144.05,129.22 144.05,125.4 v2(143.86,125.21)
  BOTTOM w0.254: PLG01.2 v2(143.86,125.21)
CSP_1B_VCCSA: length 7.1
  TOP w0.102: v1(155.46,118.85) 156.63,118.85
  TOP w0.254: 156.63,118.85 155.85,118.08 PRZ10.2 155.77,117.69 155.77,117.29 v2(155.61,117.13)
  BOTTOM w0.203: PUZ01.40 154.48,116.1 154.8,116.42 155.77,116.42 PCZ08.2
  BOTTOM w0.254: v2(155.61,117.13) 155.77,116.96 155.77,116.6 PCZ08.2 PCZ09.2
CSP_1B_VCCSA_R: length 67.6
  TOP w0.254: v2(160.37,61.95) 160.18,62.14 160.18,63.81 162.47,66.1 162.47,67.75 v1(164.85,70.14) 166.88,70.14 167.8,71.05 167.8,77.77 166.57,79 v2(165.88,79) ; PRZ13.1 v2(158.7,118.85)
  IN2 w0.254: v2(158.7,118.85) 160.69,116.86 160.69,106.62 166.45,100.86 166.45,81.42 165.88,80.85 v2(165.88,79)
  BOTTOM w0.254: PLA01.2 v2(160.37,61.95)
CSREF_2PH_CPU: length 35.6
  TOP w0.254: PRZ33.1 PCZ20.1 149.84,110.1 v2(150.21,110.47) 150.47,110.72 PCZ19.1 ; PRZ31.2 v2(154.78,89.75)
  IN1 w0.254: v2(150.21,110.47) 150.21,110.23 150.62,109.83 150.62,105.05 v2(149.01,103.44)
  IN2 w0.254: v2(154.78,89.75) 154.56,89.97 149.64,89.97 147.48,92.13 147.48,101.91 v2(149.01,103.44)
  BOTTOM w0.203: v2(150.21,110.47) 150.21,110.47 PUZ01.8
  BOTTOM w0.254: PRZ33.1 PCZ20.1 149.84,110.1 v2(150.21,110.47) ; PRZ30.2 v2(149.01,103.44)
CSSUM_2PH_CPU: length 8
  TOP w0.254: v2(150.85,110.4) 150.77,110.33 v1(150.77,109.76) 150.77,108.88 PRZ26.1
  BOTTOM w0.203: v2(150.85,110.4) 150.85,110.51 150.61,110.75 PUZ01.7
  BOTTOM w0.254: PRZ25.2 PRZ29.2 150.34,107.86 150.71,108.23 PCZ18.2 PCZ17.2 150.71,110.2 150.85,110.34 v2(150.85,110.4)
DAT_SMB: length 4.6
  TOP w0.102: v2(162.25,38.36) 162.25,38.54 162.54,38.84 v1(162.97,38.84) 163.23,38.58 PR37.1
  BOTTOM w0.102: PBATT1.6 162.95,39.03 162.85,38.92 162.19,38.92 162.07,38.79 162.07,38.54 v2(162.25,38.36)
DAT_TP_SIO: length 123.9
  TOP w0.102: v2(124.68,29.56) 124.71,29.59 v1(125.19,29.59) 125.24,29.59 126.2,28.63 R31.2 ; UE1.79 48.17,68.83 47.38,68.04 46.5,68.04 45.92,67.47 45.39,67.47 v2(45.21,67.65)
  IN2 w0.127: v2(102.4,40.33) 102.22,40.51 101.85,40.51 101.82,40.54 91.7,40.54 89.82,38.66 56.32,38.66 49.69,45.29 49.69,56.13 49.06,56.76 49.06,57.06 47.13,58.99 44.63,58.99 43.15,60.47 43.15,66.57 44.07,67.48 45.05,67.48 v2(45.21,67.65)
  BOTTOM w0.102: v2(124.68,29.56) 124.53,29.56 124.05,30.04 JTP1.2 124.05,31.28 124.15,31.38 124.31,31.38 124.44,31.5 124.44,31.97 C26.1 124.43,32.63 124.43,32.89 124.33,32.99 119.13,32.99 118.77,32.62 105.05,32.62 102.8,34.88 102.8,40.41 102.71,40.51 102.57,40.51 v2(102.4,40.33)
DBC_PANEL_EN: length 122.7
  TOP w0.102: v2(213.27,52.72) 212.53,52.72 212.11,53.14 R6.2 211.26,53.83 v1(211.11,53.98)
  IN1 w0.127: v2(120.73,62.61) 120.24,62.13 120.24,60.89 120.77,60.36 134.29,60.36 135.37,61.44 137.75,61.44 139.14,60.05 140.87,60.05 143.42,57.5 148.69,57.5 149.98,56.21 149.98,48.43 151.9,46.51 151.9,46.14 154.72,43.32 158.63,43.32 160.28,41.68 170.04,41.68 172.95,38.77 174.42,38.77 175.08,38.11 178.16,38.11 178.47,38.41 186.68,38.41 187.46,39.2 191.59,39.2 192.22,38.57 200.51,38.57 207.81,45.86 207.81,46.83 208.68,47.7 211.42,47.7 212.44,48.72 212.44,51.9 v2(213.27,52.72)
  BOTTOM w0.076: UC1.AM5 120.65,62.61 v2(120.73,62.61)
DBC_PANEL_EN_R: length 4.8
  TOP w0.102: v2(213.84,55.11) 213.42,55.11 R5.2 ; R6.1 R5.2 ; R5.2 213.03,55.51 v1(212.64,55.89)
  BOTTOM w0.102: v2(213.84,55.11) 213.5,55.45 JEDP1.11
DCPDSW_1P0: length 3.2
  TOP w0.102: v2(120.19,58.6) v1(120.19,58.06)
  TOP w0.254: CC56.1 119.41,59.38 v2(120.19,58.6)
  BOTTOM w0.203: UC1.AL1 120.44,59 120.19,58.75 v2(120.19,58.6)
DCPRTC: length 5.7
  BOTTOM w0.203: UC1.BB10 113.9,65.15 v1(111.91,63.17) 111.38,62.64 CC69.1
DDC_CLK_HDMI: length 21.6
  IN2 w0.127: JHDMI1.15 11.7,100 11.7,101.4 12.25,101.95 13.56,101.95 18.53,106.93 23.64,106.93 v2(23.81,107.1)
  BOTTOM w0.102: RI13.1 25.15,107.25 23.96,107.25 v2(23.81,107.1) 24.23,106.68 24.23,105.41 24.39,105.24 QI2.6
DDC_DATA_HDMI: length 18.1
  IN2 w0.127: JHDMI1.16 12.2,99.85 11.95,100.09 11.95,101.29 12.36,101.7 13.66,101.7 18.64,106.68 23.65,106.68 v2(23.81,106.51)
  BOTTOM w0.102: RI14.1 22.88,106.81 QI2.3 23.78,106.54 v2(23.81,106.51)
DDR4_DRAMRST#: length 16
  TOP w0.15: v2(69.46,86.23) 68.8,86.23 66.59,88.44 v1(65.73,88.44) CD29.1 RD8.2 v2(62.39,87.56)
  BOTTOM w0.102: JDIMM2.108 59.15,85.49 60.09,86.43 61.26,86.43 v2(62.39,87.56)
  BOTTOM w0.163: JDIMM1.108 69.63,85.49 69.46,85.66 v2(69.46,86.23)
DDR_A_ACT#: length 51.5
  VCC w0.076: 104.73,94.72 104.86,94.59 107.09,94.59 v2(107.9,93.78)
  VCC w0.102: v2(73.62,87.11) 73.62,87.92 74.28,88.58 84.15,88.58 90.29,94.72 104.73,94.72
  BOTTOM w0.076: UC1.BA55 114.67,91.07 114.45,91.07 114.44,91.07 114.43,91.08 114.43,91.08 114.34,91.11 114.14,91.11 114.05,91.08 114.05,91.08 113.69,91.08 113.62,91.15 112.8,91.15 110.95,93.01 109.75,93.01 109.6,92.86 108.82,92.86 v2(107.9,93.78)
  BOTTOM w0.163: JDIMM1.114 72,83.99 73.62,85.61 v2(73.62,87.11)
DDR_A_ALERT#: length 54.1
  VCC w0.076: v2(106.23,92.78) 103.15,92.78 103,92.93 102.24,92.93
  VCC w0.102: 102.24,92.93 91.27,92.93 84.52,86.19 75.22,86.19 74.92,85.89 v2(74.92,84.62)
  BOTTOM w0.076: v2(106.23,92.78) 105.97,92.52 105.97,91.41 105.7,91.14 105.7,90.47 105.91,90.26 108.17,90.26 108.18,90.27 108.61,90.27 108.77,90.11 110.04,90.11 110.43,89.72 110.86,89.72 112.78,87.8 113.48,87.8 113.67,87.98 113.77,88.08 113.93,88.08 113.94,88.1 114.03,88.1 114.1,88.06 114.11,88.05 114.14,88.04 114.28,88.04 114.44,88.08 114.68,88.08 114.72,88.06 115.01,88.06 115.17,88.11 115.2,88.14 115.39,88.14 115.64,87.89 UC1.AW50
  BOTTOM w0.163: JDIMM1.116 72.09,83.49 72.79,84.19 74.48,84.19 v2(74.92,84.62)
DDR_A_BG0: length 52.5
  VCC w0.076: 104.42,94.34 106.12,94.34 v2(106.67,93.78)
  VCC w0.102: v2(75.14,87.11) 75.14,87.88 75.23,87.97 84.22,87.97 90.59,94.34 104.42,94.34
  BOTTOM w0.076: UC1.AY55 115.44,90.95 115.15,90.65 115,90.58 114.81,90.58 114.65,90.63 114.51,90.63 114.29,90.57 114.17,90.57 114.09,90.6 114.06,90.62 113.71,90.62 113.51,90.42 112.88,90.42 111.23,92.06 111.23,92.41 110.8,92.84 109.82,92.84 109.67,92.7 108.59,92.7 108.52,92.76 107.69,92.76 v2(106.67,93.78)
  BOTTOM w0.163: v2(75.14,87.11) 75.13,87.1 75.13,85.42 75.3,85.26 76.81,85.26 78.33,83.74 JDIMM1.115
DDR_A_BG1: length 53.2
  VCC w0.076: 102.24,93.7 103.72,93.7 104.16,94.14 105.96,94.14 106.05,94.05 v2(106.05,93.77)
  VCC w0.102: v2(76.67,87.11) 76.67,87.42 76.83,87.59 77.81,87.59 77.94,87.46 77.94,87.14 78.04,87.04 78.25,87.04 78.35,87.14 78.35,87.46 78.45,87.56 78.68,87.56 78.78,87.46 78.78,87.14 78.88,87.04 79.08,87.04 79.19,87.14 79.19,87.46 79.29,87.56 84.35,87.56 90.49,93.7 102.24,93.7
  BOTTOM w0.076: UC1.AY54 115.12,90.38 114.86,90.38 114.65,90.46 114.51,90.46 114.28,90.39 114.14,90.39 114.03,90.45 113.78,90.45 113.56,90.23 112.82,90.23 111.06,91.99 111.06,92.35 110.73,92.68 109.89,92.68 109.74,92.53 107.04,92.53 106.15,93.42 106.15,93.67 v2(106.05,93.77)
  BOTTOM w0.163: v2(76.67,87.11) 76.53,86.98 76.53,86.94 76.27,86.67 75.85,86.67 75.66,86.49 75.66,85.79 75.78,85.68 76.65,85.68 76.74,85.77 76.74,86.16 76.93,86.35 77.32,86.35 77.42,86.25 77.42,85.23 78.42,84.24 JDIMM1.113
DDR_A_BS0: length 53.5
  VCC w0.076: v2(116.68,88.28) 116.18,87.77 116.18,87.2 115.12,86.15 113.98,86.15 112.39,84.55 108.21,84.55
  VCC w0.102: v2(72.71,73.21) 74.14,74.64 82.61,74.64 83.79,75.82 86.11,75.82 95.35,85.06 106.34,85.06 106.85,84.55 108.21,84.55
  BOTTOM w0.076: UC1.AU52 116.68,88.42 v2(116.68,88.28)
  BOTTOM w0.163: v2(72.71,73.21) 72.64,73.21 72.42,72.99 JDIMM1.150
DDR_A_BS1: length 54
  VCC w0.076: v2(117.36,87.38) 117.07,87.67 117.07,88.42 116.84,88.65 116.53,88.65 116.01,88.13 116.01,87.27 115.14,86.4 112.75,86.4 111.28,84.93 108.21,84.93
  VCC w0.102: v2(77.36,75.05) 81.59,75.05 81.77,75.22 81.77,75.65 81.88,75.77 82.11,75.77 82.2,75.68 82.2,75.18 82.3,75.07 82.5,75.07 82.61,75.18 82.61,75.91 82.89,76.2 85.95,76.2 95.2,85.44 106.49,85.44 107,84.93 108.21,84.93
  BOTTOM w0.076: UC1.AT48 117.61,86.87 117.5,86.87 117.19,87.18 117.19,87.29 117.28,87.38 v2(117.36,87.38)
  BOTTOM w0.163: v2(77.36,75.05) 77.18,75.05 77,75.23 77,75.37 77.25,75.62 78.02,75.62 78.28,75.37 78.28,74.4 78.44,74.24 JDIMM1.145
DDR_A_CAS#: length 54.6
  VCC w0.076: v2(116.74,86.47) 117.06,86.15 117.06,85.32 116.85,85.11 115.96,85.11 115.84,85.22 115.53,85.22 115.32,85.01 115.32,84.89 113.34,82.91 112.3,82.91 112.03,82.64 104.6,82.64 104.15,83.08 102.93,83.08
  VCC w0.102: v2(74.27,71.86) 74.68,72.26 77.49,72.26 77.73,72.03 83.32,72.03 85.13,73.83 86.93,73.83 96.18,83.08 102.93,83.08
  BOTTOM w0.076: v2(116.74,86.47) 117.03,86.77 UC1.AU48
  BOTTOM w0.163: JDIMM1.156 72.49,71.49 72.68,71.31 73.72,71.31 v2(74.27,71.86)
DDR_A_CKE0: length 54.8
  VCC w0.076: 104.35,95.33 105.06,95.33 105.48,94.91 107.96,94.91 v2(109.09,93.78)
  VCC w0.102: 104.35,95.33 90.04,95.33 84.78,90.07 84.41,90.07 84.31,89.97 84.31,89.6 84.18,89.47 83.98,89.47 83.9,89.55 83.9,89.97 83.8,90.07 83.57,90.07 83.45,89.95 83.45,89.3 83.34,89.19 83.15,89.19 83.05,89.29 83.05,89.97 82.95,90.07 82.75,90.07 82.64,89.97 82.64,89.29 82.54,89.19 82.34,89.19 82.24,89.29 82.24,89.97 82.14,90.07 81.93,90.07 81.83,89.97 81.83,89.84 81.71,89.72 80,89.72 79.94,89.78 79.94,89.89 79.81,90.01 79.6,90.01 79.49,89.9 79.49,89.32 79.36,89.19 79.14,89.19 79.04,89.29 79.04,89.97 78.93,90.07 78.73,90.07 78.63,89.97 78.63,89.29 78.53,89.19 78.3,89.19 78.22,89.27 78.22,89.73 78.03,89.93 77.45,89.93 v2(77.04,89.52)
  BOTTOM w0.076: v2(109.09,93.78) 109.3,93.57 110.11,93.57 110.27,93.74 110.27,93.92 110.36,94.01 110.69,94.01 113.05,91.65 113.65,91.65 113.71,91.71 113.71,91.71 113.78,91.77 114.06,91.77 114.21,91.67 114.41,91.67 UC1.BA56
  BOTTOM w0.163: JDIMM1.109 78.42,85.24 78.07,85.59 78.07,87.7 77.04,88.72 v2(77.04,89.52)
DDR_A_CKE1: length 52.4
  VCC w0.076: 105.22,95.71 105.7,95.23 108.95,95.23 v2(110.6,93.58)
  VCC w0.102: v2(75.52,89.52) 75.32,89.73 75.32,90.35 75.42,90.45 75.64,90.45 75.73,90.36 75.73,90.02 75.83,89.92 76.04,89.92 76.14,90.02 76.14,90.36 76.23,90.45 79.91,90.45 80.27,90.1 81.42,90.1 81.77,90.45 84.62,90.45 89.88,95.71 105.22,95.71
  BOTTOM w0.076: UC1.BB56 113.89,91.48 112.98,91.48 110.93,93.54 110.64,93.54 v2(110.6,93.58)
  BOTTOM w0.163: JDIMM1.110 72.09,84.99 72.94,85.85 72.94,87.17 73.32,87.55 74.54,87.55 75.52,88.52 v2(75.52,89.52)
DDR_A_CKE2: length 7.9
  BOTTOM w0.076: UC1.AW56 115.6,91.24 114.46,91.24 114.37,91.28 114.11,91.28 114.01,91.24 113.76,91.24 113.69,91.32 112.87,91.32 111.02,93.17 109.03,93.17 TP3.1
DDR_A_CKE3: length 6.5
  BOTTOM w0.076: TP4.1 110.2,94.31 110.62,94.31 113.12,91.81 113.58,91.81 113.7,91.93 114.12,91.93 114.24,91.84 114.77,91.84 UC1.AY56
DDR_A_CLK0: length 55.1
  VCC w0.076: 106.32,87.2 106.34,87.2 106.36,87.22 113.29,87.22 115.55,89.48 116.94,89.48 117.25,89.79 117.25,89.94 v2(117.45,90.14)
  VCC w0.109: 106.32,87.2 94.47,87.2 85.22,77.95 80.16,77.95 80.05,77.84 80.05,77.09 79.8,76.84 79.41,76.84 79.21,77.04 79.21,77.84 79.1,77.95 78.79,77.95 78.67,77.83 78.67,77.08 78.43,76.84 77.93,76.84 77.73,77.04 77.73,77.13 77.65,77.2 76.2,77.2 75.92,77.49 75.92,77.79 v2(75.73,77.98)
  BOTTOM w0.076: UC1.AT53 v2(117.45,90.14)
  BOTTOM w0.15: JDIMM1.137 78.25,78.24 78.17,78.15 78.02,78.15 77.38,78.8 76.23,78.8 75.9,78.47 75.9,78.16 v2(75.73,77.98)
DDR_A_CLK1: length 54.2
  VCC w0.076: v2(117.32,91.06) 117.12,91.26 117.12,91.44 116.96,91.6 115.98,91.6 113.62,89.24 111.44,89.24 110.46,88.26 106.39,88.26
  VCC w0.109: v2(73.43,77.98) 73.62,78.18 73.62,78.38 74.1,78.86 84.84,78.86 94.09,88.11 104.28,88.11 104.42,88.26 106.39,88.26
  BOTTOM w0.076: UC1.AT55 117.32,91 v2(117.32,91.06)
  BOTTOM w0.15: v2(73.43,77.98) 73.69,77.72 73.69,77.55 73.54,77.4 72.81,77.4 72.65,77.55 72.49,77.55 72.26,77.78 72.17,77.78 71.96,77.99 JDIMM1.138
DDR_A_CLK#0: length 54.9
  VCC w0.076: v2(116.69,90.14) 116.78,90.23 116.96,90.23 117.09,90.1 117.09,89.86 116.87,89.64 115.48,89.64 113.22,87.39 106.36,87.39 106.35,87.4 106.31,87.4
  VCC w0.109: 106.31,87.4 94.39,87.4 85.14,78.15 80.07,78.15 79.85,77.93 79.85,77.17 79.71,77.04 79.5,77.04 79.41,77.12 79.41,77.93 79.19,78.15 78.71,78.15 78.47,77.91 78.47,77.16 78.35,77.04 78.01,77.04 77.92,77.12 77.92,77.21 77.73,77.4 76.29,77.4 76.11,77.57 76.11,77.86 76.3,78.04 76.42,78.04 v2(76.47,77.98)
  BOTTOM w0.076: v2(116.69,90.14) 116.7,90.14 UC1.AU53
  BOTTOM w0.15: JDIMM1.139 78.31,77.74 78.14,77.91 77.92,77.91 77.28,78.56 76.33,78.56 76.14,78.37 76.14,78.09 76.25,77.98 v2(76.47,77.98)
DDR_A_CLK#1: length 54.3
  VCC w0.076: 106.39,88.06 106.4,88.06 106.41,88.08 106.46,88.08 106.48,88.09 110.53,88.09 111.51,89.07 113.69,89.07 116.05,91.44 116.89,91.44 116.95,91.38 116.95,91.11 116.9,91.06 v2(116.72,91.06)
  VCC w0.109: v2(74.19,77.98) 74.14,77.94 73.98,77.94 73.82,78.1 73.82,78.3 74.18,78.67 84.93,78.67 94.17,87.91 104.36,87.91 104.51,88.06 106.39,88.06
  BOTTOM w0.076: UC1.AU55 117.03,90.76 v2(116.72,91.06)
  BOTTOM w0.15: v2(74.19,77.98) 73.93,77.73 73.93,77.45 73.64,77.16 72.71,77.16 72.55,77.32 72.39,77.32 72.16,77.54 72.06,77.54 72,77.49 JDIMM1.140
DDR_A_CS#0: length 58
  VCC w0.076: v2(116.69,85.48) 116.31,85.86 115.94,85.86 114.2,84.13 114.2,84.01 113.45,83.26 112.24,83.26 111.78,82.8 105.25,82.8 104.48,83.58
  VCC w0.102: 104.48,83.58 104.37,83.69 95.92,83.69 86.68,74.44 84.88,74.44 84.29,73.86 84.2,73.86 84.05,74 83.91,74 83.76,73.85 83.76,73.71 83.88,73.6 83.88,73.45 83.73,73.3 83.6,73.3 83.48,73.42 83.33,73.42 83.18,73.27 83.18,72.75 83.07,72.63 82.88,72.63 82.79,72.72 82.79,73.17 82.69,73.27 82.48,73.27 82.38,73.17 82.38,72.75 82.26,72.63 82.06,72.63 81.97,72.72 81.97,73.17 81.87,73.27 81.67,73.27 81.57,73.17 81.57,72.75 81.45,72.63 81.25,72.63 81.16,72.72 81.16,73.17 81.06,73.27 80.85,73.27 80.75,73.17 80.75,72.75 80.64,72.63 80.44,72.63 80.35,72.72 80.35,73.17 80.24,73.27 80.04,73.27 79.94,73.17 79.94,72.75 79.83,72.63 79.62,72.63 79.53,72.72 79.53,73.17 79.43,73.27 79.23,73.27 79.13,73.17 79.13,72.75 79.01,72.63 78.81,72.63 78.72,72.72 78.72,73.17 78.62,73.27 78.42,73.27 78.31,73.17 78.31,72.75 78.2,72.63 78,72.63 77.91,72.72 77.91,73.14 77.84,73.21 v2(77.28,73.21)
  BOTTOM w0.076: UC1.AU45 116.86,84.94 116.66,84.94 116.49,85.11 116.49,85.27 v2(116.69,85.48)
  BOTTOM w0.163: JDIMM1.149 78.3,73.24 77.47,74.07 77.12,74.07 77,73.94 77,73.49 v2(77.28,73.21)
DDR_A_CS#1: length 58.6
  VCC w0.102: v2(116.72,84.57) 116.27,84.57 113.47,81.77 112.14,81.77 111.83,82.09 96.68,82.09 86.75,72.15 86.25,72.15 85.75,71.65 85.59,71.65 85.09,72.16 84.89,72.16 84.77,72.04 84.77,71.89 85.32,71.34 85.32,71.22 85.17,71.08 85.03,71.08 84.46,71.65 84.35,71.65 84.19,71.49 84.19,71.35 84.77,70.77 84.77,70.67 84.58,70.48 84.48,70.48 83.9,71.06 83.76,71.06 83.65,70.95 83.65,70.42 83.54,70.31 83.36,70.31 83.26,70.41 83.26,70.85 83.16,70.95 82.93,70.95 82.83,70.85 82.83,70.41 82.72,70.31 82.52,70.31 82.42,70.41 82.42,70.85 82.32,70.95 82.11,70.95 82.01,70.85 82.01,70.41 81.91,70.31 81.71,70.31 81.61,70.41 81.61,70.85 81.5,70.95 81.28,70.95 81.17,70.85 81.17,70.41 81.07,70.31 80.87,70.31 80.77,70.41 80.77,70.85 80.67,70.95 80.44,70.95 80.34,70.85 80.34,70.41 80.23,70.31 80.03,70.31 79.93,70.41 79.93,70.85 79.83,70.95 79.63,70.95 79.52,70.85 79.52,70.41 79.42,70.31 79.22,70.31 79.12,70.41 79.12,70.85 79.02,70.95 77.66,70.95 v2(77.54,70.83)
  BOTTOM w0.076: UC1.AU43 117.03,84.12 116.96,84.04 116.57,84.04 116.49,84.12 116.49,84.53 116.57,84.61 116.69,84.61 v2(116.72,84.57)
  BOTTOM w0.163: v2(77.54,70.83) 77.88,70.83 78.28,71.24 JDIMM1.157
DDR_A_D0: length 67.1
  VCC w0.102: v2(74.27,110.77) 75.1,111.59 82.69,111.59 82.72,111.57 102.81,111.57 107.65,116.4 116.02,116.4 121.33,111.1 121.33,104.32 v2(120.6,103.59)
  BOTTOM w0.076: UC1.AL71 120.71,100.26 120.71,101.42 120.23,101.89 120.23,103.52 120.31,103.59 v2(120.6,103.59)
  BOTTOM w0.102: v2(74.27,110.77) 74.27,110.94 73.6,111.61 72.11,111.61 71.99,111.49 JDIMM1.4
DDR_A_D1: length 68.2
  VCC w0.102: v2(120.6,104.23) 121.01,104.64 121.01,110.93 115.85,116.09 107.78,116.09 105.65,113.95 105.65,113.82 106.08,113.38 106.08,113.24 105.94,113.09 105.8,113.09 105.36,113.53 105.22,113.53 102.92,111.23 82.86,111.23 82.84,111.25 76.28,111.25 v2(75.8,110.77)
  BOTTOM w0.076: UC1.AL68 120.74,98.29 120.99,98.55 120.99,99.53 121.08,99.75 121.12,99.88 121.15,100.03 121.16,100.07 121.16,100.46 121.05,100.57 121.05,104.11 120.93,104.23 v2(120.6,104.23)
  BOTTOM w0.102: v2(75.8,110.77) 75.8,110.91 76.62,111.74 JDIMM1.3
DDR_A_D2: length 69.4
  VCC w0.102: v2(74.3,108.45) 74.3,107.55 74.4,107.46 74.62,107.46 74.73,107.56 74.73,107.96 74.81,108.05 75.02,108.05 75.13,107.93 75.13,107.56 75.23,107.46 83.96,107.46 85.38,108.88 104.87,108.88 106.21,110.22 106.39,110.22 107.03,109.58 107.18,109.58 107.34,109.75 107.34,109.89 106.67,110.56 106.67,110.71 106.81,110.85 106.95,110.85 107.63,110.18 107.77,110.18 111.51,113.91 114.71,113.91 117.01,111.61 117.01,108.48 v2(118.19,107.3)
  BOTTOM w0.076: UC1.AN68 119.23,98.79 119.19,98.99 119.22,99.09 119.24,99.21 119.19,99.38 118.98,99.58 118.98,100.36 118.98,100.37 118.98,101.51 119.07,101.61 119.07,104.66 117.78,105.96 117.78,106.9 v2(118.19,107.3)
  BOTTOM w0.102: JDIMM1.20 71.83,107.49 71.95,107.37 73.22,107.37 v2(74.3,108.45)
DDR_A_D3: length 68.1
  VCC w0.102: v2(75.83,108.45) 76.01,108.45 76.69,107.78 83.83,107.78 85.28,109.22 104.73,109.22 106.79,111.29 107.01,111.29 107.65,110.64 107.78,110.64 107.95,110.8 107.95,110.94 107.25,111.64 107.25,111.78 107.4,111.92 107.54,111.92 108.23,111.23 108.38,111.23 108.52,111.38 108.52,111.52 107.83,112.21 107.83,112.36 107.97,112.5 108.12,112.5 108.81,111.81 108.95,111.81 111.38,114.23 114.88,114.23 117.32,111.78 117.32,109.56 v2(118.82,108.07)
  BOTTOM w0.076: UC1.AN69 119.61,99.02 119.61,99.28 119.69,99.49 119.69,99.63 119.62,99.86 119.62,100.02 119.68,100.14 119.68,100.38 119.47,100.58 119.47,101.3 119.57,101.4 119.57,107.32 v2(118.82,108.07)
  BOTTOM w0.102: JDIMM1.21 77.04,107.24 v2(75.83,108.45)
DDR_A_D4: length 68
  VCC w0.102: v2(120.6,102.32) 121.67,103.39 121.67,111.24 116.19,116.72 107.48,116.72 102.67,111.91 82.58,111.91 82.55,111.94 73.91,111.94 v2(72.75,110.77)
  BOTTOM w0.076: UC1.AL70 120.74,99.72 120.91,99.89 120.97,100.02 120.99,100.09 120.99,100.38 120.87,100.5 120.87,102.05 v2(120.6,102.32)
  BOTTOM w0.102: JDIMM1.8 72.59,110.49 72.75,110.65 v2(72.75,110.77)
DDR_A_D5: length 68.9
  VCC w0.102: v2(120.6,107.4) 120.62,107.43 120.62,110.83 115.68,115.77 109.06,115.77 105.94,112.64 105.8,112.64 105.36,113.08 105.22,113.08 105.08,112.93 105.08,112.79 105.51,112.36 105.51,112.21 105.35,112.05 105.2,112.05 104.77,112.48 104.63,112.48 104.48,112.34 104.48,112.19 104.91,111.76 104.91,111.62 104.77,111.48 104.63,111.48 104.2,111.91 104.05,111.91 103.91,111.76 103.91,111.62 104.34,111.19 104.34,111.04 104.18,110.88 104.06,110.88 103.64,111.3 103.44,111.3 103.03,110.88 81.71,110.88 81.15,110.32 77.77,110.32 v2(77.32,110.77)
  BOTTOM w0.076: UC1.AL69 120.74,98.67 120.38,98.32 120.01,98.32 119.86,98.46 119.85,98.59 119.85,99.06 119.81,99.14 119.81,99.33 119.86,99.49 119.86,99.63 119.8,99.85 119.8,99.97 119.83,100.05 119.85,100.08 119.85,100.44 119.64,100.65 119.64,101.24 119.74,101.33 119.74,107.33 119.81,107.4 v2(120.6,107.4)
  BOTTOM w0.102: JDIMM1.7 78.29,110.74 78.2,110.65 77.45,110.65 v2(77.32,110.77)
DDR_A_D6: length 66.7
  VCC w0.102: v2(72.78,108.45) 74.09,107.14 84.1,107.14 85.49,108.54 104.98,108.54 105.62,109.18 105.78,109.18 106.59,108.37 106.74,108.37 106.9,108.53 106.9,108.69 106.09,109.5 106.09,109.64 106.23,109.79 106.38,109.79 107.33,108.83 107.51,108.83 107.65,108.97 107.65,109.11 107.48,109.29 107.48,109.43 111.64,113.59 114.54,113.59 116.69,111.45 116.69,108.17 v2(118.19,106.67)
  BOTTOM w0.076: UC1.AN70 119.15,99.84 119.15,100.39 119.14,100.4 119.14,101.44 119.24,101.54 119.24,104.88 118.19,105.93 v2(118.19,106.67)
  BOTTOM w0.102: v2(72.78,108.45) 72.74,108.49 JDIMM1.16
DDR_A_D7: length 65.9
  VCC w0.102: v2(118.82,106.8) 119.23,107.2 119.23,110.36 115.04,114.55 111.24,114.55 110.77,114.07 110.6,114.07 110.12,114.55 109.98,114.55 109.83,114.4 109.83,114.26 110.31,113.78 110.31,113.61 110.18,113.48 110,113.48 109.33,114.16 109.18,114.16 109.05,114.03 109.05,113.88 109.74,113.19 109.74,113.05 109.6,112.9 109.46,112.9 108.76,113.6 108.62,113.6 108.48,113.45 108.48,113.31 109.17,112.62 109.17,112.47 109.03,112.33 108.88,112.33 108.19,113.02 108.04,113.02 104.59,109.57 85.17,109.57 84.25,108.64 78.59,108.64 78.49,108.54 78.49,108.2 78.38,108.1 78.18,108.1 78.08,108.2 78.08,108.54 77.98,108.64 77.54,108.64 v2(77.35,108.45)
  BOTTOM w0.076: UC1.AN71 119.41,100.32 119.31,100.43 119.31,101.37 119.4,101.47 119.4,106.21 v2(118.82,106.8)
  BOTTOM w0.102: JDIMM1.17 77.57,108.24 77.56,108.25 77.55,108.25 v2(77.35,108.45)
DDR_A_D8: length 56.7
  VCC w0.102: v2(117.82,104.05) 117.87,104.1 117.87,105.02 116.05,106.83 110.95,106.83 110.83,106.95 110.83,107.45 110.74,107.54 110.53,107.54 110.43,107.44 110.43,106.95 110.33,106.85 110.12,106.85 110.03,106.93 110.03,107.44 109.93,107.54 109.72,107.54 109.62,107.44 109.62,106.93 109.52,106.83 109.32,106.83 109.21,106.93 109.21,107.44 109.11,107.54 108.91,107.54 108.81,107.44 108.81,106.93 108.71,106.83 108.48,106.83 108.38,106.93 108.38,107.39 108.25,107.52 85.64,107.52 84.03,105.91 83.57,105.91 83.46,105.8 83.46,105.51 83.34,105.39 83.16,105.39 83.06,105.49 83.06,105.81 82.96,105.91 82.75,105.91 82.65,105.81 82.65,105.49 82.55,105.39 82.32,105.39 82.22,105.49 82.22,105.81 82.12,105.91 81.92,105.91 81.81,105.81 81.81,105.49 81.71,105.39 v2(77.32,105.39)
  BOTTOM w0.076: v2(117.82,104.05) 117.83,104.05 118.17,104.4 118.28,104.4 118.74,103.93 118.74,101.74 118.65,101.65 118.65,100.31 118.65,100.3 118.65,99.99 118.39,99.72 UC1.AR70
  BOTTOM w0.102: v2(77.32,105.39) 77.47,105.24 JDIMM1.29
DDR_A_D9: length 58.4
  VCC w0.102: v2(75.8,105.39) 76.22,104.97 83.54,104.97 85.74,107.17 107.69,107.17 108.37,106.49 115.91,106.49 117.42,104.98 v2(117.42,104.49)
  BOTTOM w0.076: UC1.AR68 118.29,98.47 118.62,98.8 118.62,98.83 118.62,98.92 118.61,98.98 118.56,99.08 118.55,99.15 118.58,99.3 118.82,99.58 118.82,100.33 118.81,100.34 118.81,101.58 118.91,101.67 118.91,104.04 118.04,104.92 117.84,104.92 117.42,104.49 v2(117.42,104.49)
  BOTTOM w0.102: JDIMM1.25 78.26,106.24 77.84,106.65 75.01,106.65 74.91,106.55 74.91,105.9 75.01,105.79 75.2,105.79 75.61,105.39 v2(75.8,105.39)
DDR_A_D10: length 55.3
  VCC w0.102: v2(77.26,102.36) 83.59,102.36 86.41,105.17 102.21,105.17 102.31,105.08 102.31,104.63 102.38,104.55 102.61,104.55 102.71,104.66 102.71,105.1 102.81,105.2 103.01,105.2 103.11,105.1 103.11,104.66 103.22,104.55 103.44,104.55 103.55,104.66 103.55,105.1 103.65,105.2 103.85,105.2 103.95,105.1 103.95,104.66 104.05,104.55 114.51,104.55 115.97,103.1 v2(115.97,102.13)
  BOTTOM w0.076: UC1.AU71 117.03,100.22 116.95,100.31 116.95,101.23 116.56,101.62 116.04,101.62 115.89,101.76 115.89,102.05 v2(115.97,102.13)
  BOTTOM w0.102: JDIMM1.37 78.08,103.24 77.59,103.73 77.16,103.73 77.06,103.63 77.06,103.53 76.96,103.43 76.65,103.43 76.55,103.53 76.55,103.63 76.45,103.73 76.14,103.73 76.04,103.63 76.04,103.53 75.94,103.43 75.63,103.43 75.53,103.53 75.53,103.63 75.43,103.73 75.01,103.73 74.91,103.63 74.91,102.87 75.01,102.77 76.67,102.77 77.08,102.36 v2(77.26,102.36)
DDR_A_D11: length 57.4
  VCC w0.102: v2(115.37,104.51) 115.14,104.51 114.78,104.87 106,104.87 105.9,104.97 105.9,105.39 105.8,105.49 105.59,105.49 105.49,105.39 105.49,104.97 105.39,104.87 105.19,104.87 105.08,104.97 105.08,105.39 104.98,105.49 104.78,105.49 104.68,105.39 104.68,104.97 104.58,104.87 104.36,104.87 104.27,104.96 104.27,105.43 104.19,105.52 86.26,105.52 83.53,102.78 76.16,102.78 v2(75.74,102.36)
  BOTTOM w0.076: UC1.AU68 117.14,98.21 117.4,98.21 117.83,98.23 117.94,98.35 118.06,98.54 118.06,98.62 117.99,98.81 118.01,99.27 117.94,99.49 117.94,99.63 118,99.85 118,99.97 117.97,100.05 117.95,100.08 117.95,100.45 118.15,100.64 118.15,101.01 118.09,101.08 118.09,101.44 117.41,102.11 117.41,103.51 116.41,104.51 v2(115.37,104.51)
  BOTTOM w0.102: JDIMM1.41 78.21,102.24 77.64,101.67 75.51,101.67 75.41,101.77 75.41,102.03 v2(75.74,102.36)
DDR_A_D12: length 55.6
  VCC w0.102: v2(74.27,105.39) 75.12,106.23 83.9,106.23 85.53,107.86 110.98,107.86 111.66,107.18 116.18,107.18 118.53,104.82 118.53,103.34 v2(118.12,102.93)
  BOTTOM w0.076: UC1.AR71 118.48,100.32 118.48,101.72 118.58,101.81 118.58,102.85 118.49,102.93 v2(118.12,102.93)
  BOTTOM w0.102: v2(74.27,105.39) 74.27,105.44 73.22,106.49 JDIMM1.24
DDR_A_D13: length 56.4
  VCC w0.102: v2(116.94,104.86) 115.72,106.09 107.76,106.09 107.66,106.19 107.66,106.75 107.56,106.86 107.35,106.86 107.25,106.75 107.25,106.19 107.15,106.09 106.92,106.09 106.82,106.2 106.82,106.74 106.72,106.83 85.85,106.83 83.64,104.63 75.11,104.63 74.86,104.87 73.26,104.87 v2(72.75,105.39)
  BOTTOM w0.076: UC1.AR69 118.18,99.02 118.18,99.28 118.11,99.49 118.11,99.63 118.17,99.86 118.17,99.96 118.18,99.97 118.12,100.11 118.12,100.38 118.32,100.58 118.32,101.48 117.67,102.13 117.67,103.63 116.94,104.36 v2(116.94,104.86)
  BOTTOM w0.102: v2(72.75,105.39) 72.65,105.49 JDIMM1.28
DDR_A_D14: length 55.6
  VCC w0.102: v2(74.22,102.36) 74.64,101.94 83.66,101.94 86.55,104.83 100.28,104.83 100.38,104.73 100.38,104.32 100.47,104.24 100.67,104.24 100.77,104.34 100.77,104.72 100.86,104.8 101.06,104.8 101.18,104.69 101.18,104.34 101.28,104.24 101.48,104.24 101.58,104.34 101.58,104.72 101.67,104.8 101.87,104.8 101.99,104.69 101.99,104.34 102.09,104.24 114.33,104.24 115.09,103.47 v2(115.09,103.01)
  BOTTOM w0.076: v2(115.09,103.01) 114.95,103.01 114.88,102.93 114.88,102.45 115.87,101.45 116.49,101.45 116.78,101.16 116.78,99.64 116.9,99.52 117.01,99.52 UC1.AU70
  BOTTOM w0.102: JDIMM1.42 71.84,101.99 72.18,101.65 72.41,101.65 72.55,101.79 72.9,101.79 73.04,101.65 73.27,101.65 73.37,101.76 73.37,101.85 73.47,101.95 73.77,101.95 73.88,101.85 73.88,101.76 73.98,101.65 74.49,101.65 74.59,101.76 74.59,102.23 74.46,102.36 v2(74.22,102.36)
DDR_A_D15: length 55.4
  VCC w0.102: v2(72.69,102.36) 73.45,101.6 83.8,101.6 86.69,104.49 99.77,104.49 100.36,103.89 111.11,103.89 111.21,103.79 111.21,103.32 111.31,103.22 111.52,103.22 111.62,103.32 111.62,103.79 111.72,103.89 111.92,103.89 112.03,103.79 112.03,103.32 112.13,103.22 112.33,103.22 112.43,103.32 112.43,103.79 112.53,103.89 112.74,103.89 112.84,103.79 112.84,103.32 112.94,103.22 113.14,103.22 113.24,103.32 113.24,103.79 113.35,103.89 113.55,103.89 113.64,103.8 113.64,103.4 113.72,103.31 114.49,103.31 v2(114.58,103.4)
  BOTTOM w0.076: v2(114.58,103.4) 114.58,102.51 115.81,101.29 116.42,101.29 116.6,101.11 116.6,99.77 116.61,99.76 116.61,99.57 117.06,99.12 UC1.AU69
  BOTTOM w0.102: JDIMM1.38 72.06,102.99 v2(72.69,102.36)
DDR_A_D16: length 50.8
  VCC w0.102: v2(75.91,100.54) 76.4,100.05 77.22,100.05 77.33,99.94 77.33,99.57 77.43,99.46 77.63,99.46 77.73,99.57 77.73,99.92 77.82,100.01 78.02,100.01 78.14,99.9 78.14,99.57 78.24,99.46 78.44,99.46 78.55,99.57 78.55,99.92 78.63,100.01 78.84,100.01 78.95,99.9 78.95,99.57 79.05,99.46 83.29,99.46 87.16,103.34 99.29,103.34 99.88,102.75 110.1,102.75 111.76,101.09 111.76,100.92 v2(111.78,100.9)
  BOTTOM w0.076: UC1.BB65 113.83,96.55 113.16,96.55 112.4,97.31 112.4,99.27 111.44,100.24 111.44,100.9 111.48,100.94 111.74,100.94 v2(111.78,100.9)
  BOTTOM w0.102: JDIMM1.45 78.27,101.24 78.11,101.09 76.33,101.09 75.91,100.67 v2(75.91,100.54)
DDR_A_D17: length 52.2
  VCC w0.102: v2(111.33,99.04) 111.33,99.19 112.29,100.14 112.29,101.05 110.26,103.07 100.02,103.07 99.42,103.66 87.03,103.66 83.76,100.39 80.69,100.39 80.59,100.29 80.59,99.88 80.49,99.78 80.29,99.78 80.18,99.88 80.18,100.29 80.08,100.39 79.88,100.39 79.78,100.29 79.78,99.88 79.68,99.78 79.47,99.78 79.37,99.88 79.37,100.29 79.27,100.39 77.58,100.39 v2(77.43,100.54)
  BOTTOM w0.076: UC1.AW65 115.87,95.75 115.68,95.57 115.08,95.57 115.05,95.53 114.81,95.53 114.65,95.59 114.51,95.59 114.29,95.52 114.17,95.52 114.09,95.56 113.59,95.56 113.52,95.49 112.95,95.49 112.62,95.82 112.62,96.39 111.91,97.1 111.91,98.08 111.33,98.66 v2(111.33,99.04)
  BOTTOM w0.102: JDIMM1.49 78.39,100.24 78.02,99.87 77.66,99.87 77.3,100.23 77.3,100.4 v2(77.43,100.54)
DDR_A_D18: length 53.8
  VCC w0.102: v2(108.87,100.19) 108.48,100.58 98.98,100.58 98.39,101.17 88.07,101.17 83.63,96.73 80.3,96.73 79.95,97.07 76.63,97.07 v2(76.21,97.49)
  BOTTOM w0.076: v2(108.87,100.19) 108.86,100.19 108.4,99.73 108.4,99.15 109.89,97.66 111.01,97.66 111.25,97.42 111.25,96.83 111.96,96.12 111.96,95.55 112.68,94.83 113.59,94.83 113.7,94.72 114.59,94.72 114.8,94.93 114.93,94.94 115.06,94.94 115.19,94.92 115.3,94.92 115.69,95.31 115.8,95.31 UC1.AW63
  BOTTOM w0.102: JDIMM1.63 78.21,96.74 77.83,96.36 77.69,96.36 77.59,96.46 77.59,96.82 77.48,96.92 77.28,96.92 77.18,96.82 77.18,96.46 77.08,96.36 76.88,96.36 76.77,96.46 76.77,96.79 76.67,96.89 76.5,96.89 76.4,96.79 76.4,96.49 76.27,96.36 75.56,96.36 75.48,96.43 75.48,96.89 75.59,96.99 75.9,96.99 76.21,97.29 v2(76.21,97.49)
DDR_A_D19: length 51.9
  VCC w0.102: v2(110.75,99.02) 110.73,99.02 110.73,99.48 109.01,101.21 99.25,101.21 98.65,101.8 87.8,101.8 83.92,97.93 82.65,97.93 82.55,97.82 82.55,97.49 82.45,97.39 82.25,97.39 82.15,97.49 82.15,97.82 82.04,97.93 81.84,97.93 81.74,97.82 81.74,97.49 81.64,97.39 81.43,97.39 81.33,97.49 81.33,97.82 81.23,97.93 73.59,97.93 v2(73.16,97.49)
  BOTTOM w0.076: UC1.AY63 115.12,95.34 114.86,95.34 114.65,95.41 114.51,95.41 114.28,95.35 114.14,95.35 114.05,95.39 113.66,95.39 113.59,95.32 112.88,95.32 112.45,95.75 112.45,96.33 111.74,97.03 111.74,98.01 110.73,99.02 v2(110.75,99.02)
  BOTTOM w0.102: JDIMM1.58 72.67,97.99 v2(73.16,97.49)
DDR_A_D20: length 51
  VCC w0.102: v2(72.86,100.54) 72.86,99.79 72.94,99.71 76.93,99.71 77.01,99.63 77.01,99.24 77.11,99.15 83.42,99.15 87.3,103.03 99.16,103.03 99.75,102.43 109.93,102.43 111.38,100.99 111.38,100.54 111.59,100.33 v2(111.88,100.33)
  BOTTOM w0.076: UC1.BA65 114.42,96.46 114.28,96.61 114.27,96.61 114.27,96.61 114.05,96.72 113.23,96.72 112.57,97.38 112.57,99.34 111.88,100.03 v2(111.88,100.33)
  BOTTOM w0.102: v2(72.86,100.54) 72.32,99.99 JDIMM1.50
DDR_A_D21: length 51.7
  VCC w0.102: v2(112.58,99.86) 112.82,100.11 112.82,101 110.43,103.39 100.15,103.39 99.55,103.98 86.9,103.98 83.66,100.74 77.81,100.74 77.57,100.98 74.83,100.98 v2(74.39,100.54)
  BOTTOM w0.076: v2(112.58,99.86) 112.73,99.71 112.73,97.45 113.3,96.88 114.09,96.88 114.3,96.78 114.33,96.78 114.47,96.73 114.75,96.73 115.01,96.46 UC1.AY65
  BOTTOM w0.102: JDIMM1.46 72.1,100.99 72.18,101.07 74.12,101.07 74.39,100.8 v2(74.39,100.54)
DDR_A_D22: length 52.2
  VCC w0.102: v2(109.48,99.63) 109.62,99.78 109.62,100.15 108.88,100.89 99.11,100.89 98.52,101.49 87.93,101.49 83.52,97.07 81.14,97.07 81.01,97.2 81.01,97.53 80.93,97.61 79.18,97.61 78.96,97.39 77.83,97.39 v2(77.73,97.49)
  BOTTOM w0.076: UC1.BA63 114.36,95.14 114.1,94.88 113.77,94.88 113.66,94.99 112.75,94.99 112.12,95.62 112.12,96.19 111.41,96.9 111.41,97.55 111.14,97.83 109.96,97.83 109.2,98.58 109.2,99.36 v2(109.48,99.63)
  BOTTOM w0.102: JDIMM1.59 78.38,97.74 78.02,98.09 78.02,98.19 77.89,98.32 77.29,98.32 77.08,98.53 75.09,98.53 74.98,98.41 74.98,98.08 75.15,97.9 77.2,97.9 77.61,97.49 v2(77.73,97.49)
DDR_A_D23: length 50.7
  VCC w0.102: v2(74.69,97.49) 74.69,96.81 74.76,96.73 79.81,96.73 80.15,96.39 83.73,96.39 88.2,100.85 97.44,100.85 97.53,100.76 97.53,100.35 97.62,100.26 97.85,100.26 97.95,100.36 97.95,100.75 98.06,100.85 98.26,100.85 98.36,100.75 98.36,100.36 98.46,100.26 107.65,100.26 108.89,99.02 v2(109.57,99.02)
  BOTTOM w0.076: v2(109.57,99.02) 110.51,98.08 111.2,98.08 111.58,97.7 111.58,96.97 112.29,96.26 112.29,95.68 112.82,95.16 113.9,95.16 UC1.BB63
  BOTTOM w0.102: v2(74.69,97.49) 74.69,97.23 74.03,96.57 72.32,96.57 71.91,96.99 JDIMM1.62
DDR_A_D24: length 49.9
  VCC w0.102: v2(76.23,95.02) 76.23,95.44 76.32,95.54 78.59,95.54 79.27,94.86 83.9,94.86 88.74,99.71 96.32,99.71 96.42,99.61 96.42,98.96 96.57,98.81 105.03,98.81 105.33,99.12 107.09,99.12 v2(108.93,97.27)
  BOTTOM w0.076: v2(108.93,97.27) 108.9,97.27 108.72,97.45 108.72,97.73 108.82,97.83 109.48,97.83 109.89,97.43 109.89,97.14 110.34,96.69 110.92,96.69 111.63,95.98 111.63,95.41 112.54,94.5 113.46,94.5 113.56,94.39 114.07,94.39 114.35,94.11 UC1.BA61
  BOTTOM w0.102: JDIMM1.67 78.28,95.74 78.25,95.78 75.95,95.78 75.81,95.64 75.81,95.24 76.03,95.02 v2(76.23,95.02)
DDR_A_D25: length 50.9
  VCC w0.102: v2(73.18,95.02) 74.38,96.22 78.88,96.22 79.55,95.55 83.61,95.55 88.41,100.34 96.82,100.34 97.41,99.75 107.44,99.75 108.8,98.39 108.85,98.39 109.55,97.69 110.51,97.69 110.88,97.31 v2(110.88,97.27)
  BOTTOM w0.076: v2(110.88,97.27) 110.88,96.96 111.79,96.05 111.79,95.48 112.61,94.66 113.52,94.66 113.63,94.55 114.59,94.55 114.83,94.31 114.84,94.31 114.84,94.31 115.06,94.31 115.19,94.33 115.42,94.33 115.74,94.01 UC1.AW61
  BOTTOM w0.102: JDIMM1.70 73.15,94.99 v2(73.18,95.02)
DDR_A_D26: length 50.3
  VCC w0.076: v2(108.33,95.74) 107.76,96.31 106.46,96.31 105.92,96.85
  VCC w0.102: 105.92,96.85 105.81,96.95 93.16,96.95 93.06,97.06 93.06,97.57 92.94,97.69 92.74,97.69 92.65,97.6 92.65,97.06 92.55,96.95 92.35,96.95 92.24,97.06 92.24,97.57 92.13,97.69 91.93,97.69 91.84,97.6 91.84,97.06 91.74,96.95 91.51,96.95 91.42,97.04 91.42,97.71 91.31,97.83 89.52,97.83 83.67,91.97 76.94,91.97 v2(76.46,91.48)
  BOTTOM w0.076: v2(108.33,95.74) 108.02,95.43 108.02,95.04 108.22,94.84 110.8,94.84 112.75,92.89 113.81,92.89 UC1.BB59
  BOTTOM w0.102: v2(76.46,91.48) 76.24,91.48 76.05,91.67 76.05,92.43 76.16,92.53 77.25,92.53 77.45,92.74 JDIMM1.79
DDR_A_D27: length 52.5
  VCC w0.076: 106.16,97.09 106.75,96.5 108.71,96.5 v2(109.5,95.71)
  VCC w0.102: 106.16,97.09 105.98,97.27 94.35,97.27 94.24,97.37 94.24,97.89 94.14,97.99 93.94,97.99 93.84,97.89 93.84,97.37 93.74,97.27 93.51,97.27 93.42,97.36 93.42,98 93.27,98.14 89.39,98.14 83.56,92.31 74.24,92.31 v2(73.41,91.48)
  BOTTOM w0.076: UC1.AW59 115.87,93.49 115.73,93.63 115.12,93.63 115.02,93.7 114.76,93.7 114.67,93.67 114.45,93.67 114.44,93.68 114.43,93.68 114.43,93.68 114.34,93.71 114.15,93.71 114.06,93.68 114.05,93.68 113.71,93.68 113.5,93.89 113.36,93.89 113.25,94 112.34,94 111.13,95.2 111.13,95.78 110.92,95.99 109.78,95.99 v2(109.5,95.71)
  BOTTOM w0.102: JDIMM1.84 70.96,91.48 v2(73.41,91.48)
DDR_A_D28: length 49.1
  VCC w0.102: v2(74.7,95.02) 75.56,95.88 78.74,95.88 79.41,95.21 83.76,95.21 88.58,100.03 96.69,100.03 97.59,99.13 104.89,99.13 105.2,99.43 107.26,99.43 108.64,98.05 108.74,98.05 v2(109.52,97.27)
  BOTTOM w0.076: v2(109.52,97.27) 110.29,96.5 110.88,96.5 111.46,95.91 111.46,95.34 112.47,94.33 113.39,94.33 113.49,94.22 113.8,94.22 UC1.BB61
  BOTTOM w0.102: v2(74.7,95.02) 74.7,95.18 73.89,95.99 JDIMM1.66
DDR_A_D29: length 51.3
  VCC w0.102: v2(107.72,97.27) 107.72,97.34 106.26,98.8 105.46,98.8 105.16,98.49 96.21,98.49 96.11,98.59 96.11,99.29 96,99.39 95.8,99.39 95.7,99.29 95.7,98.59 95.6,98.49 95.37,98.49 95.28,98.58 95.28,99.28 95.2,99.37 88.89,99.37 83.93,94.41 78.67,94.41 78.56,94.51 78.56,95.12 78.46,95.22 78.26,95.22 78.16,95.12 78.16,94.51 78.06,94.41 77.87,94.41 77.75,94.53 v2(77.75,95.02)
  BOTTOM w0.076: UC1.AY61 115.09,93.88 114.77,93.88 114.67,93.84 114.46,93.84 114.37,93.88 114.13,93.88 114.02,93.84 113.78,93.84 113.56,94.06 113.42,94.06 113.32,94.17 112.4,94.17 111.3,95.27 111.3,95.85 110.84,96.31 109.67,96.31 109.23,96.75 107.34,96.75 107.26,96.83 107.26,97.2 107.34,97.27 v2(107.72,97.27)
  BOTTOM w0.102: JDIMM1.71 78.23,94.74 78.1,94.61 78.1,94.17 77.99,94.07 77.24,94.07 77.13,94.17 77.13,94.59 77.56,95.02 v2(77.75,95.02)
DDR_A_D30: length 51.2
  VCC w0.076: 105.67,96.61 106.16,96.12 107.37,96.12 v2(107.75,95.74)
  VCC w0.102: v2(77.98,91.48) 83.63,91.48 85.65,93.51 85.8,93.51 86.02,93.28 86.14,93.28 86.3,93.44 86.3,93.58 86.09,93.8 86.09,93.94 86.23,94.08 86.37,94.08 86.59,93.87 86.73,93.87 86.87,94.01 86.87,94.16 86.66,94.37 86.66,94.51 86.8,94.66 86.95,94.66 87.16,94.45 87.3,94.45 87.45,94.59 87.45,94.73 87.24,94.95 87.24,95.09 87.38,95.23 87.52,95.23 87.74,95.02 87.88,95.02 88.02,95.16 88.02,95.31 87.81,95.52 87.81,95.66 87.95,95.81 88.1,95.81 88.31,95.6 88.45,95.6 88.6,95.74 88.6,95.88 88.39,96.1 88.39,96.24 88.53,96.38 88.67,96.38 88.89,96.17 89.03,96.17 89.5,96.64 89.72,96.64 89.83,96.74 89.83,97.41 89.93,97.51 90.13,97.51 90.23,97.41 90.23,96.74 90.33,96.64 90.54,96.64 90.64,96.74 90.64,97.41 90.74,97.51 90.94,97.51 91.04,97.41 91.04,96.74 91.15,96.64 105.64,96.64 105.67,96.61
  BOTTOM w0.076: v2(107.75,95.74) 107.31,95.3 107.31,95.19 107.85,94.64 110.76,94.64 112.68,92.72 113.58,92.72 113.77,92.53 114.05,92.53 114.55,92.74 114.55,92.74 UC1.BA59
  BOTTOM w0.102: v2(77.98,91.48) 77.79,91.48 77.49,91.79 77.49,91.95 77.69,92.15 78.04,92.15 78.46,91.74 JDIMM1.83
DDR_A_D31: length 52
  VCC w0.076: 105.48,96.32 106.11,95.69 v2(106.58,95.69)
  VCC w0.102: v2(74.93,91.48) 74.73,91.48 74.65,91.4 74.65,91.14 74.73,91.06 83.76,91.06 83.97,91.27 84.12,91.27 84.27,91.11 84.42,91.11 84.55,91.24 84.55,91.39 84.34,91.6 84.34,91.74 84.48,91.89 84.63,91.89 84.84,91.68 84.98,91.68 85.13,91.82 85.13,91.96 84.91,92.18 84.91,92.32 85.06,92.46 85.2,92.46 85.41,92.25 85.56,92.25 85.72,92.41 85.72,92.56 85.51,92.77 85.51,92.91 85.65,93.06 85.8,93.06 86.01,92.84 86.15,92.84 89.63,96.32 105.48,96.32
  BOTTOM w0.076: v2(106.58,95.69) 107.79,94.48 110.69,94.48 112.61,92.56 113.51,92.56 113.7,92.37 114.08,92.37 114.12,92.38 114.55,92.52 114.75,92.52 115.01,92.78 UC1.AY59
  BOTTOM w0.102: JDIMM1.80 71.82,92.49 72.06,92.25 74.26,92.25 74.93,91.58 v2(74.93,91.48)
DDR_A_D32: length 57.8
  VCC w0.076: 102.8,79.94 104.1,81.25 106.28,81.25 v2(106.46,81.07)
  VCC w0.102: v2(74.34,67.87) 74.75,68.27 75.49,68.27 75.81,68.59 77.69,68.59 78.12,68.16 78.13,68.16 78.81,67.49 85.13,67.49 97.58,79.94 102.8,79.94
  BOTTOM w0.076: v2(106.46,81.07) 106.23,81.07 105.84,81.46 105.84,82.48 105.92,82.55 111.8,82.55 112.29,82.07 113.55,82.07 113.66,82.17 114.06,82.17 114.47,82.01 114.75,82.01 115.01,81.74 UC1.AY39
  BOTTOM w0.102: JDIMM1.174 71.99,66.99 72.12,67.12 72.12,67.33 72.21,67.41 73.19,67.41 73.29,67.31 73.29,67.23 73.88,66.65 74.11,66.65 74.21,66.75 74.21,67.24 74.31,67.34 74.51,67.34 74.62,67.24 74.62,66.75 74.72,66.65 75.05,66.65 75.15,66.75 75.15,67.24 74.53,67.87 v2(74.34,67.87)
DDR_A_D33: length 54
  VCC w0.076: v2(111.8,81.1) 111.45,81.45 103.99,81.45 102.8,80.26
  VCC w0.102: 102.8,80.26 97.45,80.26 86.64,69.45 86.51,69.45 86.39,69.57 86.26,69.57 86.12,69.44 86.12,69.29 86.23,69.18 86.23,69.04 86.09,68.89 85.94,68.89 85.83,69.01 85.69,69.01 85.53,68.85 85.53,68.7 85.64,68.59 85.64,68.45 85.5,68.3 85.35,68.3 85.27,68.38 85.18,68.38 84.6,67.81 78.94,67.81 78.26,68.48 78.25,68.48 77.68,69.04 74,69.04 v2(72.82,67.87)
  BOTTOM w0.076: v2(111.8,81.1) 112.52,81.1 112.95,80.67 113.51,80.67 113.67,80.83 114.01,80.83 114.13,80.81 114.34,80.81 114.41,80.83 114.74,80.83 114.79,80.81 115.08,80.8 115.58,80.8 115.87,81.09 UC1.AW39
  BOTTOM w0.102: v2(72.82,67.87) 72.82,68.01 72.69,68.14 71.1,68.14 JDIMM1.170
DDR_A_D34: length 56.3
  VCC w0.076: v2(111.22,81.06) 111.22,80.04 111.1,79.92 108.72,79.92 108.42,79.62 108.42,79.35 107.99,78.92 105.64,78.92 103.85,77.13 103.78,77.13
  VCC w0.102: v2(77.33,64.45) 77.68,64.1 78.12,64.1 78.22,64 78.22,63.63 78.32,63.53 78.53,63.53 78.63,63.63 78.63,64 78.73,64.1 78.94,64.1 79.03,64.01 79.03,63.61 79.11,63.53 79.34,63.53 79.44,63.63 79.44,64 79.54,64.1 79.75,64.1 79.85,64 79.85,63.63 79.95,63.53 80.18,63.53 80.29,63.64 80.29,63.99 80.4,64.1 80.63,64.1 80.73,64 80.73,63.63 80.83,63.53 81.75,63.53 81.81,63.59 81.81,63.96 81.95,64.1 86.21,64.1 97.42,75.31 97.42,75.4 97.27,75.54 97.27,75.66 97.43,75.82 97.58,75.82 97.69,75.71 97.83,75.71 97.98,75.85 97.98,75.99 97.87,76.11 97.87,76.25 98.01,76.39 98.15,76.39 98.27,76.28 98.41,76.28 98.55,76.42 98.55,76.57 98.44,76.68 98.44,76.82 98.59,76.97 98.71,76.97 98.87,76.81 99,76.81 99.32,77.13 99.55,77.13 99.65,77.03 99.65,76.95 99.75,76.85 99.95,76.85 100.05,76.95 100.05,77.03 100.16,77.13 100.36,77.13 100.46,77.03 100.46,76.95 100.56,76.85 100.77,76.85 100.87,76.95 100.87,77.03 100.97,77.13 101.17,77.13 101.27,77.03 101.27,76.95 101.38,76.85 101.58,76.85 101.68,76.95 101.68,77.03 101.78,77.13 101.99,77.13 102.09,77.03 102.09,76.95 102.19,76.85 102.39,76.85 102.49,76.95 102.49,77.03 102.59,77.13 102.78,77.13 102.88,77.03 102.88,76.68 102.98,76.58 103.18,76.58 103.28,76.68 103.28,77.03 103.39,77.13 103.78,77.13
  BOTTOM w0.076: v2(111.22,81.06) 111.22,80.85 111.34,80.73 112.65,80.73 112.88,80.5 113.58,80.5 113.74,80.67 113.99,80.67 114.19,80.63 114.31,80.63 114.47,80.67 114.71,80.67 114.86,80.61 115.12,80.61 UC1.AY37
  BOTTOM w0.102: v2(77.33,64.45) 77.13,64.25 77.13,64.14 77.23,64.04 77.75,64.04 78.05,63.74 JDIMM1.187
DDR_A_D35: length 57
  VCC w0.076: 102.8,78.09 103.47,78.09 105.38,79.99 107.96,79.99 108.05,79.9 v2(108.05,79.5)
  VCC w0.102: 102.8,78.09 98.35,78.09 96.32,76.05 96.32,75.56 86.39,65.63 85.71,65.63 85.61,65.53 85.61,65.17 85.49,65.05 85.31,65.05 85.2,65.17 85.2,65.52 85.09,65.63 84.88,65.63 84.79,65.54 84.79,65.17 84.68,65.05 78.36,65.05 77.64,65.78 73.66,65.78 73.58,65.7 73.58,64.96 73.48,64.86 73.28,64.86 73.18,64.96 73.18,65.66 73.08,65.76 72.85,65.76 72.76,65.67 v2(72.76,64.45)
  BOTTOM w0.076: v2(108.05,79.5) 108.05,79.57 108.71,80.23 112.45,80.23 112.71,79.97 114.63,79.97 114.85,80.19 115.33,80.19 115.65,80.51 UC1.AW37
  BOTTOM w0.102: v2(72.76,64.45) 72.73,64.45 72.36,64.09 72.05,64.09 71.95,63.99 JDIMM1.186
DDR_A_D36: length 55.3
  VCC w0.076: 102.8,79.31 103.91,79.31 105.13,80.54 107.67,80.54 v2(108.21,81.08)
  VCC w0.102: 102.8,79.31 97.85,79.31 95,76.46 95,76.31 95.1,76.21 95.1,76.07 94.95,75.93 94.81,75.93 94.71,76.03 94.57,76.03 94.4,75.86 94.4,75.72 94.5,75.62 94.5,75.48 94.36,75.33 94.22,75.33 94.12,75.43 93.97,75.43 93.83,75.29 93.83,75.15 93.93,75.05 93.93,74.9 93.79,74.76 93.64,74.76 93.54,74.86 93.4,74.86 93.25,74.71 93.25,74.57 93.35,74.47 93.35,74.33 93.21,74.18 93.07,74.18 92.97,74.28 92.82,74.28 92.68,74.14 92.68,74 92.78,73.9 92.78,73.75 92.64,73.61 92.49,73.61 92.39,73.71 92.25,73.71 92.1,73.56 92.1,73.42 92.2,73.32 92.2,73.18 92.06,73.03 91.92,73.03 91.82,73.13 91.67,73.13 91.53,72.99 91.53,72.85 91.63,72.75 91.63,72.6 91.48,72.46 91.34,72.46 91.24,72.56 91.1,72.56 90.95,72.41 90.95,72.27 91.05,72.17 91.05,72.03 90.91,71.88 90.77,71.88 90.67,71.98 90.52,71.98 90.38,71.84 90.38,71.7 90.48,71.59 90.48,71.45 90.33,71.31 90.19,71.31 90.09,71.41 89.95,71.41 89.8,71.26 89.8,71.12 89.9,71.02 89.9,70.88 89.76,70.73 89.62,70.73 89.52,70.83 89.37,70.83 89.23,70.69 89.23,70.55 89.33,70.44 89.33,70.3 89.18,70.16 89.04,70.16 88.94,70.26 88.8,70.26 88.64,70.1 88.64,69.97 88.76,69.85 88.76,69.73 85.88,66.85 78.48,66.85 77.46,67.87 v2(77.39,67.87)
  BOTTOM w0.076: UC1.BB39 113.91,81.74 112.15,81.74 112.04,81.85 111.14,81.85 110.77,82.22 106.87,82.22 106.79,82.15 106.79,81.89 106.92,81.76 v1(107.78,81.76) 108.26,81.76 108.47,81.56 108.47,81.34 v2(108.21,81.08)
  BOTTOM w0.102: v2(77.39,67.87) 77.32,67.8 77.32,67.52 77.44,67.4 77.68,67.4 78.11,67.83 78.11,68.08 78.27,68.24 JDIMM1.169
DDR_A_D37: length 55.9
  VCC w0.076: 102.8,79.63 103.99,79.63 105.06,80.7 107.26,80.7 v2(107.63,81.07)
  VCC w0.102: 102.8,79.63 97.72,79.63 88.23,70.14 88.23,69.99 88.33,69.89 88.33,69.75 88.18,69.61 88.04,69.61 87.94,69.71 87.8,69.71 87.63,69.54 87.63,69.4 87.73,69.3 87.73,69.16 87.59,69.01 87.45,69.01 87.35,69.11 87.2,69.11 87.04,68.95 87.04,68.81 87.09,68.75 87.09,68.61 86.95,68.46 86.81,68.46 86.75,68.52 86.61,68.52 86.47,68.37 86.47,68.23 86.52,68.18 86.52,68.03 86.37,67.89 86.23,67.89 86.18,67.94 86.03,67.94 85.89,67.8 85.89,67.66 85.94,67.6 85.94,67.46 85.8,67.31 85.66,67.31 85.6,67.37 85.46,67.37 85.26,67.17 78.66,67.17 77.99,67.84 77.56,68.27 76.27,68.27 v2(75.87,67.87)
  BOTTOM w0.076: UC1.BA39 114.42,81.74 114.28,81.88 114.27,81.88 114.27,81.89 114.02,82.01 113.73,82.01 113.62,81.9 112.22,81.9 111.98,82.14 v1(111.54,82.14) 111.09,82.14 110.84,82.39 106.7,82.39 106.63,82.31 106.63,81.59 106.7,81.51 107.19,81.51 v2(107.63,81.07)
  BOTTOM w0.102: v2(75.87,67.87) 75.74,67.74 75.74,66.95 75.84,66.85 76.27,66.85 76.37,66.95 76.37,67.32 76.47,67.42 76.67,67.42 76.78,67.32 76.78,66.92 77.04,66.65 77.76,66.65 78.35,67.24 JDIMM1.173
DDR_A_D38: length 57.3
  VCC w0.076: v2(106.88,79.48) 106.54,79.82 105.44,79.82 103.39,77.77 102.8,77.77
  VCC w0.102: v2(74.28,64.45) 74.28,65.16 74.58,65.46 77.5,65.46 78.23,64.74 85.94,64.74 96.64,75.43 96.64,75.92 98.49,77.77 102.8,77.77
  BOTTOM w0.076: v2(106.88,79.48) 106.51,79.85 106.51,80.32 106.59,80.4 106.88,80.4 106.95,80.32 106.95,80 107.03,79.92 107.18,79.92 107.26,80 107.26,80.32 107.33,80.4 107.49,80.4 107.56,80.32 107.56,80 107.66,79.9 107.77,79.9 107.87,80 107.87,80.32 107.94,80.4 112.51,80.4 112.78,80.13 114.08,80.13 114.36,80.41 UC1.BA37
  BOTTOM w0.102: JDIMM1.182 71.95,64.99 72.1,65.14 73.21,65.14 73.31,65.04 73.31,64.99 73.41,64.89 73.62,64.89 73.72,64.99 73.72,65.04 73.82,65.14 74.2,65.14 74.65,65.6 74.92,65.6 75.08,65.44 75.08,65.29 74.28,64.49 v2(74.28,64.45)
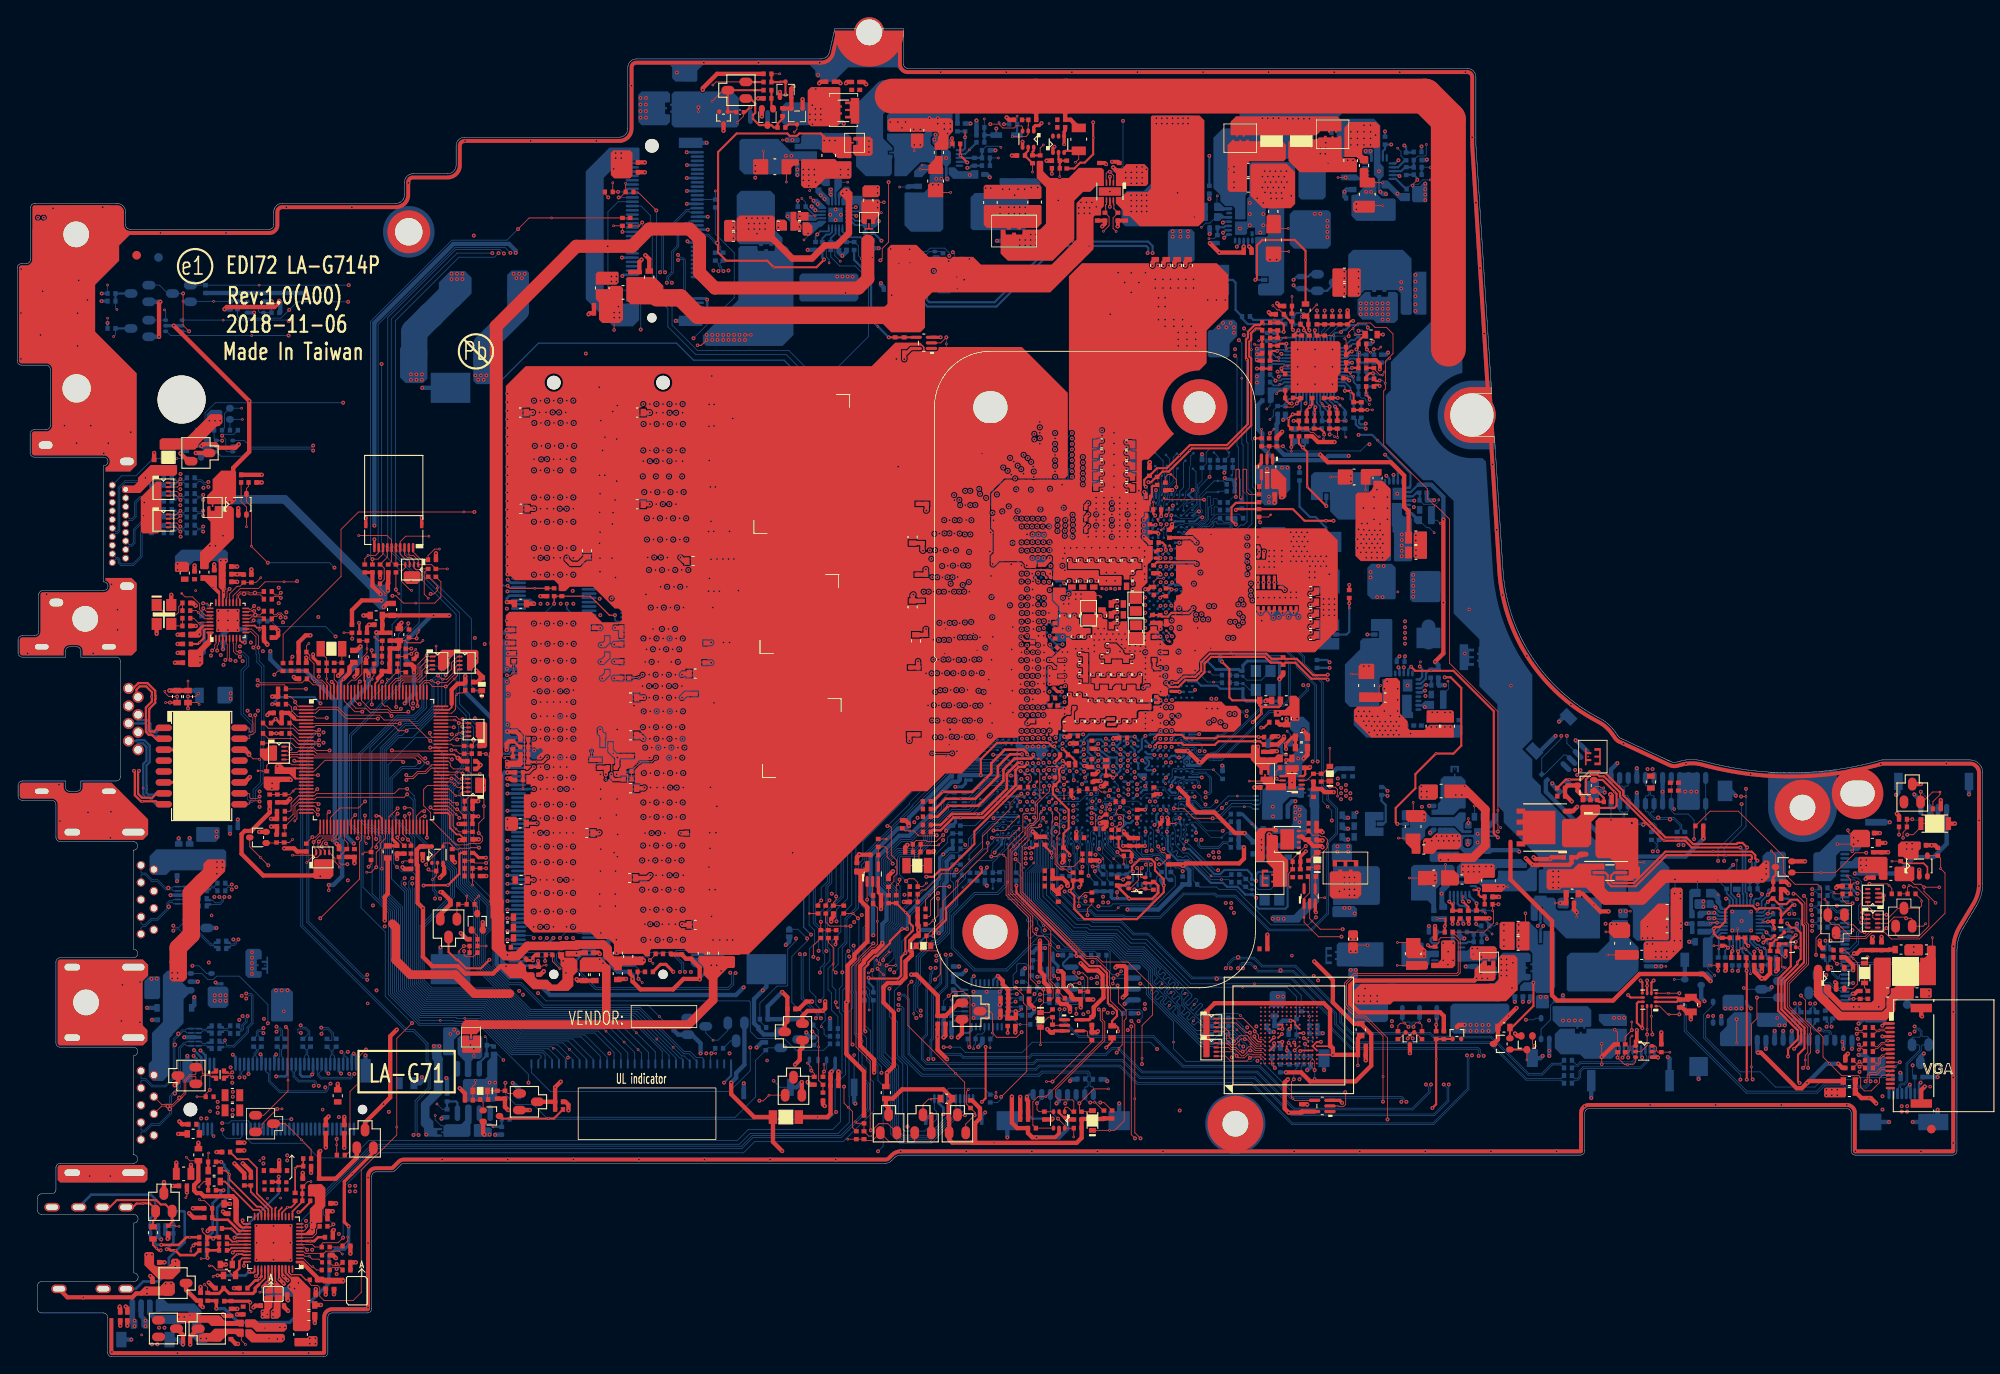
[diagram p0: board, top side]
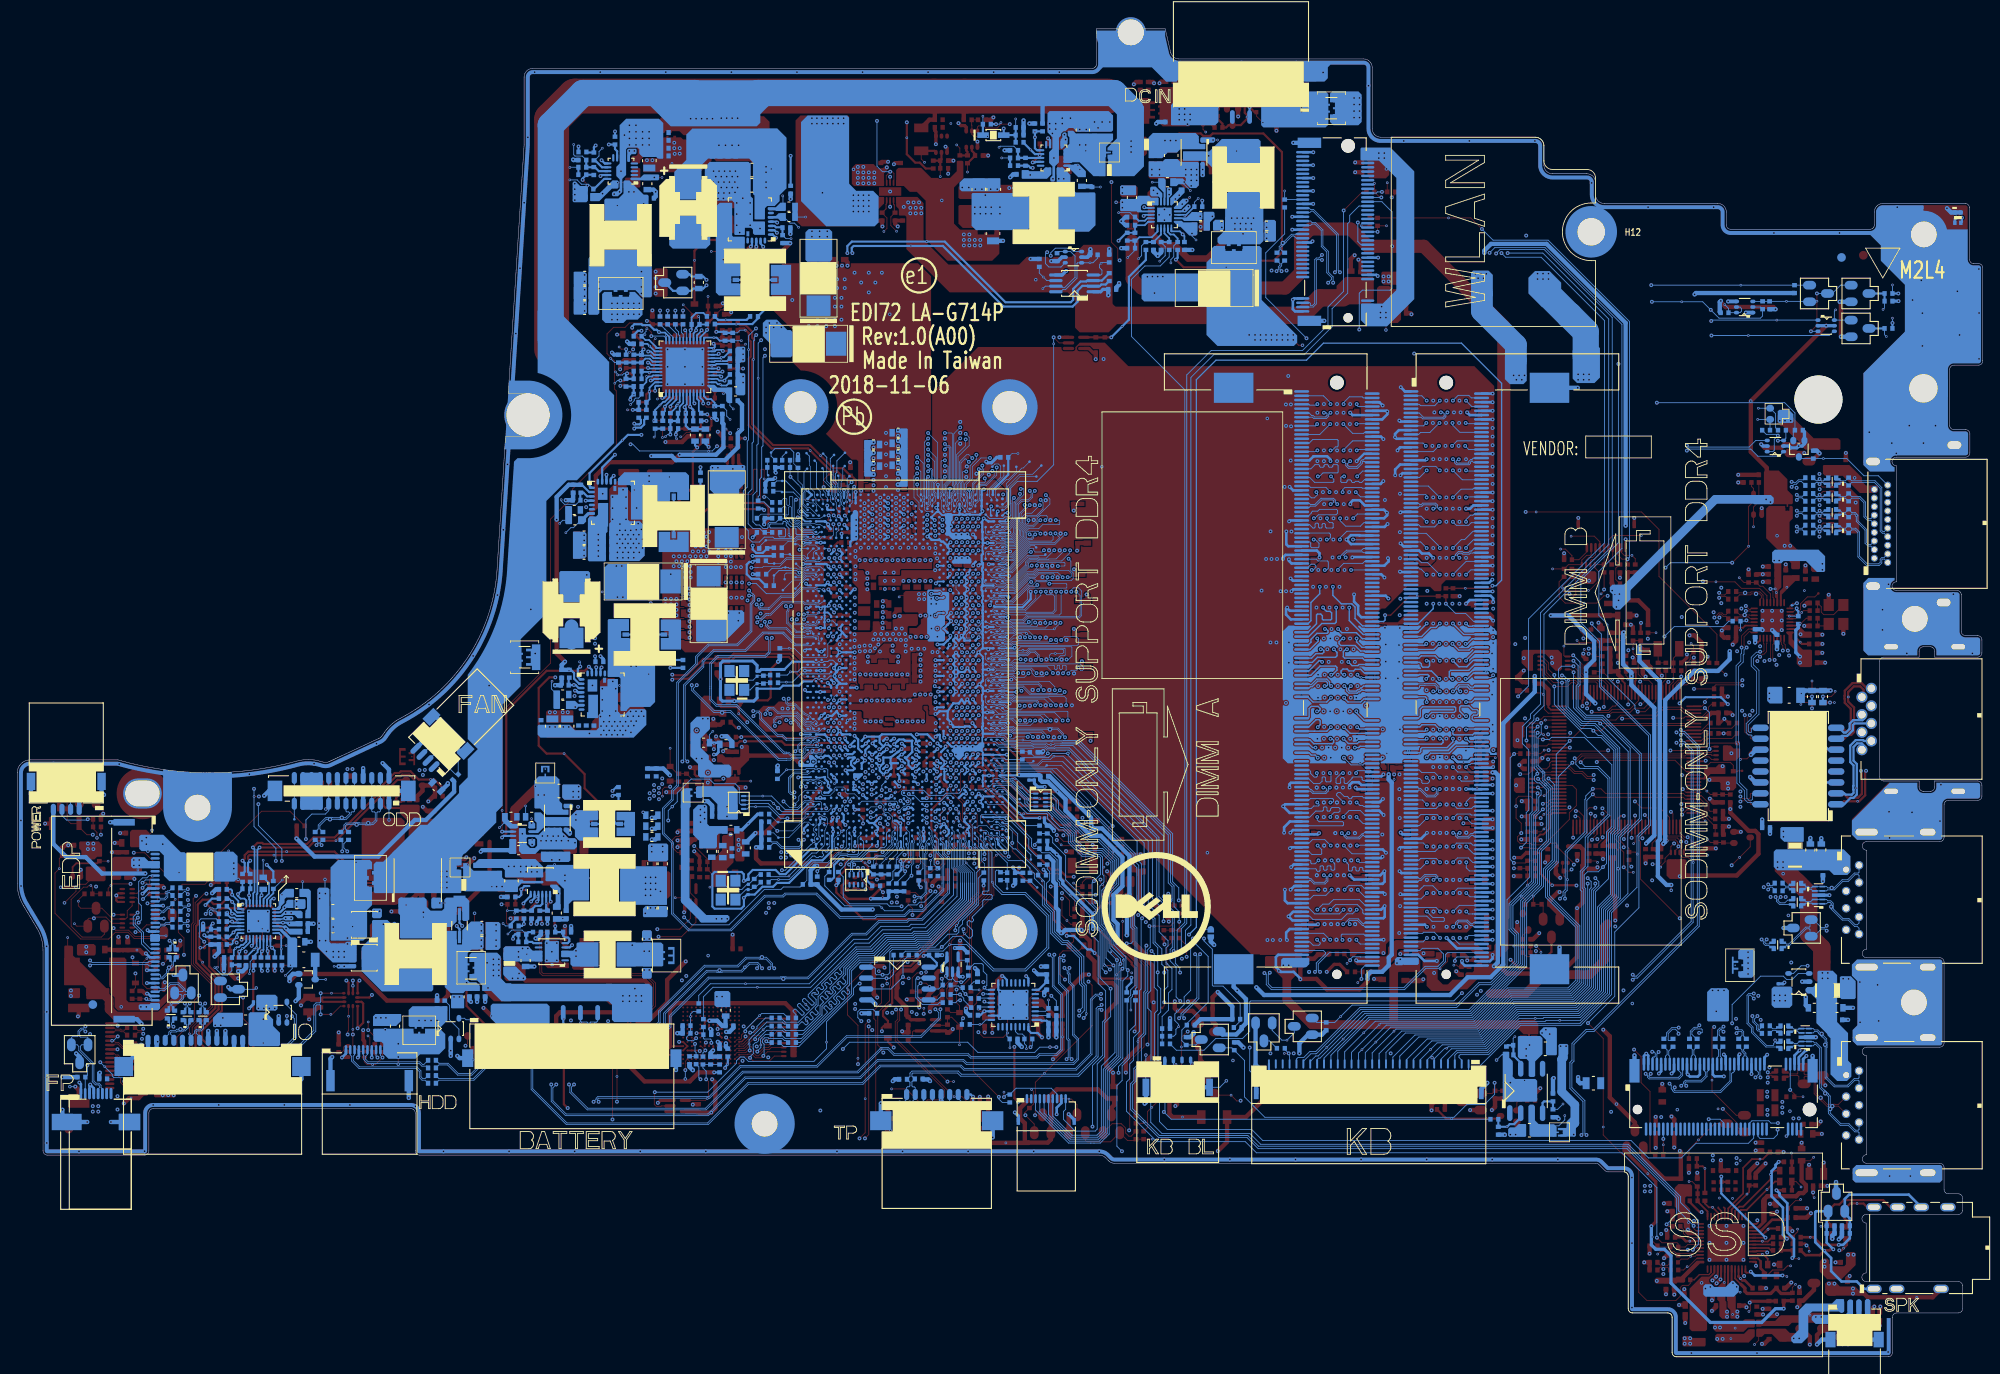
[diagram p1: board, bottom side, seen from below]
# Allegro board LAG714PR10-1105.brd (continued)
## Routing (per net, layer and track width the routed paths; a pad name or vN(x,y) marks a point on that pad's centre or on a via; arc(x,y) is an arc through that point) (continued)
DDR_A_D39: length 55.6
  VCC w0.076: 102.8,77.45 103.82,77.45 105.45,79.09 105.89,79.09 v2(106.26,79.46)
  VCC w0.102: v2(75.81,64.45) 75.57,64.45 75.43,64.59 75.43,64.96 75.61,65.14 77.37,65.14 78.09,64.42 86.07,64.42 96.95,75.3 96.95,75.79 98.62,77.45 102.8,77.45
  BOTTOM w0.076: UC1.BB37 113.72,80.41 113.65,80.34 112.81,80.34 112.58,80.56 104.89,80.56 104.52,80.19 104.52,79.9 104.62,79.8 104.82,79.8 104.92,79.9 104.92,80.16 105,80.24 105.15,80.24 105.23,80.16 105.23,79.9 105.31,79.82 105.92,79.82 106.26,79.48 v2(106.26,79.46)
  BOTTOM w0.102: JDIMM1.183 78.29,64.74 78.13,64.9 75.54,64.9 75.44,64.8 75.44,64.59 75.54,64.48 75.77,64.48 v2(75.81,64.45)
DDR_A_D40: length 55
  VCC w0.076: v2(110.9,79.47) 110.9,78.59 110.74,78.43 105.85,78.43 103.13,75.71 102.29,75.71
  VCC w0.102: v2(77.34,62.76) 77.34,62.48 77.44,62.38 83.29,62.38 83.87,62.96 86.71,62.96 99.45,75.71 102.29,75.71
  BOTTOM w0.076: UC1.AY35 115.12,79.19 114.85,79.19 114.67,79.12 114.46,79.12 114.37,79.15 114.11,79.15 114.02,79.12 113.45,79.12 113.27,79.3 112.7,79.3 112.4,79 111.37,79 v2(110.9,79.47)
  BOTTOM w0.102: v2(77.34,62.76) 77.34,62.43 77.12,62.21 74.38,62.21 74.28,62.11 74.28,61.84 74.38,61.74 JDIMM1.195
DDR_A_D41: length 55.5
  VCC w0.076: 102.29,76.03 103.21,76.03 105.78,78.59 109.06,78.59 v2(109.95,79.49)
  VCC w0.102: 102.29,76.03 99.32,76.03 86.57,63.28 83.73,63.28 83.16,62.7 77.98,62.7 77.47,63.2 76.25,63.2 v2(75.81,62.76)
  BOTTOM w0.076: UC1.AW35 115.63,79.29 115.31,79.61 114.81,79.61 114.61,79.8 112.64,79.8 112.38,80.07 110.53,80.07 v2(109.95,79.49)
  BOTTOM w0.102: JDIMM1.191 78.22,62.74 77.51,63.45 76.73,63.45 76.63,63.55 76.63,63.84 76.52,63.94 76.31,63.94 76.21,63.84 76.21,63.54 76.11,63.44 75.9,63.44 75.8,63.54 75.8,63.69 75.62,63.87 74.84,63.87 74.69,63.72 74.69,63.45 74.84,63.3 75.37,63.3 75.81,62.86 v2(75.81,62.76)
DDR_A_D42: length 54.4
  VCC w0.076: v2(111.7,77.44) 111.7,76.64 111.55,76.48 105.59,76.48 104.72,75.62 104.72,74.97 102.97,73.22
  VCC w0.102: 102.97,73.22 100.49,73.22 87.74,60.47 86.51,60.47 86.41,60.37 86.41,59.63 86.31,59.53 86.11,59.53 86,59.63 86,60.37 85.9,60.47 85.67,60.47 85.57,60.37 85.57,59.63 85.47,59.53 85.27,59.53 85.17,59.63 85.17,60.32 85.04,60.44 84.87,60.44 84.72,60.29 84.72,59.69 84.56,59.53 77.38,59.53 v2(77.29,59.44)
  BOTTOM w0.076: UC1.AY33 115.4,78.06 115.48,77.98 115.48,77.82 115.36,77.7 114.22,77.7 114.06,77.63 113.69,77.63 113.66,77.66 111.93,77.66 v2(111.7,77.44)
  BOTTOM w0.102: v2(77.29,59.44) 76.82,58.96 76.82,58.5 76.92,58.39 77.95,58.39 78.29,58.74 JDIMM1.207
DDR_A_D43: length 53.6
  VCC w0.076: v2(107.83,77.51) 107.03,76.71 105.58,76.71 104.28,75.41 104.28,74.91 102.9,73.53
  VCC w0.102: 102.9,73.53 100.36,73.53 87.61,60.79 84.77,60.79 83.83,59.85 75.87,59.85 75.77,59.74 v2(75.77,59.44)
  BOTTOM w0.076: v2(107.83,77.51) 107.83,77.91 108.45,78.53 112.16,78.53 112.77,79.13 113.2,79.13 113.38,78.95 114.05,78.95 114.05,78.95 114.14,78.99 114.34,78.99 114.43,78.95 114.43,78.95 114.44,78.95 114.45,78.95 114.67,78.95 114.8,78.99 115.05,78.99 115.15,78.92 115.66,78.92 115.87,78.71 UC1.AW33
  BOTTOM w0.102: JDIMM1.203 78.28,59.74 77.89,60.13 76.46,60.13 v2(75.77,59.44)
DDR_A_D44: length 52.5
  VCC w0.076: 102.29,75.39 103.04,75.39 105.91,78.25 110.84,78.25 v2(112.09,79.51)
  VCC w0.102: 102.29,75.39 99.59,75.39 86.84,62.64 84,62.64 83.42,62.06 73.29,62.06 73.17,61.95 73.17,61.45 73.06,61.34 72.88,61.34 72.77,61.45 v2(72.77,62.76)
  BOTTOM w0.076: v2(112.09,79.51) 112.14,79.46 113.84,79.46 UC1.BB35
  BOTTOM w0.102: v2(72.77,62.76) 71.99,61.99 JDIMM1.194
DDR_A_D45: length 53.8
  VCC w0.076: v2(108.78,79.47) 108.07,78.76 105.71,78.76 103.3,76.34 102.29,76.34
  VCC w0.102: v2(74.29,62.76) 74.29,63.32 74.49,63.52 77.6,63.52 78.11,63.02 82.22,63.02 82.3,63.1 82.3,63.47 82.43,63.59 82.62,63.59 82.72,63.49 82.72,63.12 82.82,63.02 83.03,63.02 83.13,63.12 83.13,63.49 83.23,63.59 86.44,63.59 99.19,76.34 102.29,76.34
  BOTTOM w0.076: UC1.BA35 114.35,79.39 114.09,79.64 112.57,79.64 112.31,79.9 110.67,79.9 110.5,79.73 110.5,79.51 110.06,79.07 109.18,79.07 v2(108.78,79.47)
  BOTTOM w0.102: JDIMM1.190 71.81,62.99 72.33,63.51 73.64,63.51 74.29,62.86 v2(74.29,62.76)
DDR_A_D46: length 53.9
  VCC w0.076: v2(106.69,77.3) 105.93,77.3 103.83,75.2 103.83,74.81 102.87,73.85
  VCC w0.102: v2(74.25,59.44) 74.08,59.61 74.08,59.9 74.23,60.06 74.82,60.06 74.92,60.16 81.79,60.16 81.88,60.25 81.88,60.42 81.98,60.53 82.18,60.53 82.29,60.42 82.29,60.23 82.35,60.16 82.6,60.16 82.69,60.25 82.69,60.42 82.79,60.53 83,60.53 83.1,60.42 83.1,60.25 83.18,60.16 83.39,60.16 83.47,60.24 83.47,60.43 83.56,60.53 84.06,60.53 84.64,61.1 87.48,61.1 100.22,73.85 102.87,73.85
  BOTTOM w0.076: UC1.BA33 114.42,78.06 114.28,77.92 114.02,77.79 113.76,77.79 113.73,77.83 111.56,77.83 110.71,76.98 108.46,76.98 108.46,76.97 107.01,76.97 v2(106.69,77.3)
  BOTTOM w0.102: v2(74.25,59.44) 73.29,58.49 JDIMM1.208
DDR_A_D47: length 52.9
  VCC w0.076: v2(107.25,77.5) 107.02,77.73 106.13,77.73 103.45,75.05 103.45,74.77 102.85,74.17
  VCC w0.102: 102.85,74.17 100.09,74.17 87.34,61.42 84.5,61.42 83.93,60.84 81.67,60.84 81.31,60.48 79.92,60.48 79.82,60.58 79.82,60.74 79.72,60.84 79.52,60.84 79.42,60.74 79.42,60.58 79.31,60.48 79.11,60.48 79.01,60.58 79.01,60.74 78.91,60.84 78.7,60.84 78.6,60.74 78.6,60.58 78.5,60.48 78.3,60.48 78.2,60.58 78.2,60.74 78.1,60.84 77.89,60.84 77.79,60.74 77.79,60.58 77.69,60.48 74.79,60.48 74.69,60.38 73.56,60.38 72.72,59.54 v2(72.72,59.44)
  BOTTOM w0.076: UC1.BB33 113.85,78 111.46,78 110.61,77.14 108.39,77.14 107.61,77.14 v2(107.25,77.5)
  BOTTOM w0.102: JDIMM1.204 72.4,59.49 72.45,59.44 v2(72.72,59.44)
DDR_A_D48: length 55.6
  VCC w0.076: v2(106.51,75.76) 106.13,75.38 105.89,75.38 103.51,73.01 103.51,72.95
  VCC w0.102: 103.51,72.95 102.64,72.07 100.96,72.07 87.27,58.39 84.01,58.39 83.91,58.28 83.91,57.84 83.81,57.74 83.61,57.74 83.51,57.84 83.51,58.28 83.4,58.39 83.17,58.39 83.07,58.28 83.07,57.84 82.97,57.74 82.77,57.74 82.67,57.84 82.67,58.28 82.57,58.39 82.35,58.39 82.25,58.28 82.25,57.84 82.15,57.74 81.94,57.74 81.84,57.84 81.84,58.28 81.74,58.39 81.53,58.39 81.43,58.29 81.43,57.84 81.33,57.74 81.12,57.74 81.02,57.84 81.02,57.98 80.91,58.08 80.71,58.08 80.61,57.98 80.61,57.84 80.51,57.74 80.3,57.74 80.2,57.84 80.2,57.98 80.1,58.08 79.87,58.08 79.77,57.98 79.77,57.73 79.67,57.63 79.47,57.63 79.36,57.73 79.36,57.98 79.26,58.08 79.06,58.08 78.96,57.98 78.96,57.73 78.86,57.63 78.65,57.63 78.55,57.73 78.55,57.98 78.45,58.08 78.25,58.08 78.14,57.98 78.14,57.73 78.04,57.63 77.84,57.63 77.74,57.73 77.74,57.98 77.64,58.08 77.3,58.08 77.19,57.98 v2(77.19,57.72)
  BOTTOM w0.076: v2(106.51,75.76) 106.51,76.57 106.75,76.81 108.53,76.81 112.43,76.81 112.64,77.02 113.54,77.02 113.71,77.19 114.05,77.19 114.47,77.03 114.75,77.03 115.01,76.76 UC1.AY31
  BOTTOM w0.102: v2(77.19,57.72) 77.59,57.32 77.99,57.32 78.09,57.42 78.09,57.64 78.19,57.74 JDIMM1.211
DDR_A_D49: length 56.6
  VCC w0.076: 103.13,73.11 103.13,73.15 104.98,74.99 104.98,75.64 105.63,76.29 111.35,76.29 v2(111.92,75.72)
  VCC w0.102: 103.13,73.11 102.73,72.71 100.7,72.71 87.01,59.02 81.13,59.02 80.83,58.72 75.15,58.72 v2(74.15,57.72)
  BOTTOM w0.076: UC1.AW31 115.87,76.07 115.65,75.85 115.09,75.85 115.07,75.83 114.8,75.83 114.65,75.88 114.51,75.88 114.29,75.82 114.17,75.82 114.09,75.85 114.06,75.87 113.68,75.87 113.48,75.66 113.35,75.66 113.07,75.38 112.26,75.38 v2(111.92,75.72)
  BOTTOM w0.102: JDIMM1.216 71.94,56.49 72.04,56.59 72.04,56.8 72.14,56.9 72.34,56.9 72.44,56.8 72.44,56.59 72.55,56.49 72.75,56.49 72.85,56.59 72.85,56.85 72.95,56.95 73.16,56.95 73.26,56.85 73.26,56.59 73.36,56.49 73.61,56.49 73.71,56.59 73.71,57.24 73.86,57.39 73.86,57.43 v2(74.15,57.72)
DDR_A_D50: length 55.2
  VCC w0.076: 102.29,70.53 103.17,70.53 104.34,71.7 104.34,72.63 106.08,74.36 110,74.36 v2(111.33,75.69)
  VCC w0.102: 102.29,70.53 101.6,70.53 87.91,56.85 86.62,56.85 85.34,55.57 77.22,55.57 77.13,55.48 76.63,55.48 76.51,55.36 76.51,54.81 76.41,54.71 76.2,54.71 76.1,54.81 76.1,55.36 75.98,55.48 75.77,55.48 75.67,55.38 v2(75.67,54.31)
  BOTTOM w0.076: v2(111.33,75.69) 111.8,75.22 113.14,75.22 113.42,75.5 113.55,75.5 113.75,75.7 114.03,75.7 114.14,75.64 114.28,75.64 114.51,75.71 114.65,75.71 114.86,75.63 115.12,75.63 UC1.AY29
  BOTTOM w0.102: JDIMM1.229 78.17,53.24 77.76,53.65 76.32,53.65 v2(75.67,54.31)
DDR_A_D51: length 55.6
  VCC w0.076: 103.76,69.73 104.91,70.89 104.91,72.36 106.01,73.46 107.81,73.46 v2(108.33,73.98)
  VCC w0.102: 103.76,69.73 103.61,69.58 101.99,69.58 88.31,55.89 87.02,55.89 85.74,54.61 83.02,54.61 81.86,53.45 73.48,53.45 v2(72.63,54.31)
  BOTTOM w0.076: v2(108.33,73.98) 109.07,74.72 113.34,74.72 113.45,74.82 114.4,74.82 114.77,75.2 115.07,75.2 115.09,75.17 115.37,75.17 115.49,75.29 115.63,75.29 115.87,75.53 UC1.AW29
  BOTTOM w0.102: v2(72.63,54.31) 71.81,53.49 JDIMM1.228
DDR_A_D52: length 54.1
  VCC w0.076: 103.32,73.03 103.32,73.1 105.36,75.13 105.36,75.79 105.7,76.13 107.91,76.13 v2(108.29,75.75)
  VCC w0.102: 103.32,73.03 102.68,72.39 100.83,72.39 87.14,58.7 81.27,58.7 80.96,58.4 75.86,58.4 75.67,58.21 v2(75.67,57.72)
  BOTTOM w0.076: v2(108.29,75.75) 109.02,76.48 112.57,76.48 112.77,76.69 113.85,76.69 UC1.BB31
  BOTTOM w0.102: v2(75.67,57.72) 75.38,57.43 75.38,57.39 75.3,57.31 75.3,56.69 75.41,56.57 75.62,56.57 75.74,56.69 75.74,56.98 75.84,57.08 76.09,57.08 76.19,56.98 76.19,56.68 76.3,56.57 76.5,56.57 76.6,56.68 76.6,56.98 76.7,57.08 76.91,57.08 77.01,56.98 77.01,56.55 77.11,56.45 77.31,56.45 77.41,56.55 77.41,56.64 77.52,56.74 JDIMM1.215
DDR_A_D53: length 54.4
  VCC w0.076: v2(107.7,75.75) 107.17,75.22 105.95,75.22 103.71,72.97 103.71,72.82
  VCC w0.102: v2(72.62,57.72) 72.6,57.7 72.6,57.38 72.68,57.31 79.82,57.31 79.92,57.42 84.09,57.42 84.23,57.56 84.23,57.95 84.35,58.07 84.58,58.07 84.68,57.97 84.68,57.22 84.78,57.11 84.99,57.11 85.09,57.22 85.09,57.97 85.19,58.07 87.41,58.07 101.09,71.76 102.64,71.76 103.71,72.82
  BOTTOM w0.076: v2(107.7,75.75) 108.6,76.65 112.5,76.65 112.71,76.85 113.61,76.85 113.78,77.03 114.02,77.03 114.28,76.9 114.42,76.76 UC1.BA31
  BOTTOM w0.102: v2(72.62,57.72) 72.62,57.68 72.43,57.49 JDIMM1.212
DDR_A_D54: length 54.5
  VCC w0.076: 102.51,69.9 103.62,69.9 104.72,71 104.72,72.41 105.94,73.63 106.57,73.63 v2(106.92,73.98)
  VCC w0.102: v2(74.15,54.31) 74.69,53.77 81.73,53.77 81.92,53.97 81.92,54.83 82.02,54.93 85.61,54.93 86.89,56.21 88.18,56.21 101.86,69.9 102.51,69.9
  BOTTOM w0.076: UC1.BA29 114.34,75.43 113.89,74.99 113.38,74.99 113.28,74.89 107.83,74.89 v2(106.92,73.98)
  BOTTOM w0.102: v2(74.15,54.31) 73.64,54.81 72.21,54.81 71.88,54.49 JDIMM1.224
DDR_A_D55: length 53.3
  VCC w0.076: 102.29,70.22 103.42,70.22 104.53,71.32 104.53,72.58 105.94,73.99 v2(106.31,73.99)
  VCC w0.102: 102.29,70.22 101.73,70.22 88.04,56.53 86.76,56.53 85.48,55.25 81.67,55.25 81.55,55.13 81.55,54.87 81.41,54.73 79.94,54.73 79.83,54.62 79.43,54.62 79.33,54.73 79.33,55.15 79.22,55.25 79.02,55.25 78.92,55.15 78.92,54.72 78.82,54.61 78.61,54.61 78.53,54.69 78.53,55.19 78.47,55.25 78.21,55.25 78.11,55.15 78.11,54.19 78.01,54.09 77.81,54.09 77.71,54.19 77.71,55.15 77.6,55.25 77.35,55.25 77.2,55.09 v2(77.2,54.31)
  BOTTOM w0.076: v2(106.31,73.99) 106.31,74.97 106.39,75.05 113.21,75.05 113.31,75.15 113.64,75.15 UC1.BB29
  BOTTOM w0.102: v2(77.2,54.31) 77.26,54.24 JDIMM1.225
DDR_A_D56: length 60.2
  VCC w0.076: 105.2,72.38 105.2,72.41 106.04,73.26 108.19,73.26 v2(108.91,73.98)
  VCC w0.102: v2(72.75,51.99) 73.71,52.94 82.07,52.94 83.23,54.11 85.95,54.11 87.23,55.39 88.52,55.39 102.21,69.07 103.82,69.07 105.25,70.5 105.25,71.07 105.2,71.12 105.2,72.38
  BOTTOM w0.076: v2(108.91,73.98) 109.49,74.56 113.41,74.56 113.52,74.66 114.8,74.66 115.15,74.31 UC1.AY27
  BOTTOM w0.102: JDIMM1.237 78.22,51.24 77.84,50.86 74.52,50.86 73.87,51.51 73.23,51.51 v2(72.75,51.99)
DDR_A_D57: length 60.5
  VCC w0.076: 105.71,72.65 106.12,73.07 109.2,73.07 v2(110.11,73.98)
  VCC w0.102: 105.71,72.65 105.54,72.48 105.54,71.26 105.59,71.22 105.59,70.4 103.95,68.76 102.34,68.76 88.65,55.07 87.36,55.07 86.08,53.79 84.2,53.79 84.1,53.69 84.1,52.81 84,52.7 83.79,52.7 83.69,52.81 83.69,53.69 83.59,53.79 83.36,53.79 83.24,53.67 83.24,52.76 83.11,52.63 74.92,52.63 v2(74.27,51.99)
  BOTTOM w0.076: UC1.AW27 115.59,74.03 114.18,74.03 114.14,73.99 114.13,73.99 114.13,73.99 113.5,73.99 113.43,74.06 112.81,74.06 112.17,73.42 110.66,73.42 v2(110.11,73.98)
  BOTTOM w0.102: JDIMM1.233 78.38,52.24 77.63,51.49 74.77,51.49 v2(74.27,51.99)
DDR_A_D58: length 59
  VCC w0.102: v2(75.8,51.99) 75.8,51.69 75.91,51.58 79.51,51.58 79.63,51.69 79.63,51.89 79.73,51.99 79.93,51.99 80.03,51.89 80.03,51.64 80.14,51.53 80.33,51.53 80.43,51.62 80.43,51.93 80.49,51.99 80.93,51.99 81.03,51.89 81.03,51.51 81.13,51.41 81.34,51.41 81.44,51.51 81.44,51.89 81.54,51.99 81.77,51.99 81.87,51.89 81.87,51.41 81.97,51.31 82.2,51.31 82.28,51.39 82.28,51.89 82.38,51.99 85.19,51.99 87.63,54.43 88.91,54.43 102.6,68.12 104.21,68.12 106.28,70.18 106.28,71.5 106.23,71.55 106.23,72.2 106.55,72.53 110.07,72.53 110.37,72.23 v2(110.37,72.06)
  BOTTOM w0.076: UC1.AY25 114.97,73.08 114.72,72.82 114.44,72.82 114.04,72.64 112.91,72.64 112.72,72.44 110.75,72.44 v2(110.37,72.06)
  BOTTOM w0.102: v2(75.8,51.99) 75.21,52.57 72.68,52.57 72.04,51.94 72.04,51.62 71.92,51.49 JDIMM1.236
DDR_A_D59: length 60.4
  VCC w0.102: v2(77.32,51.99) 77.41,51.9 77.6,51.9 77.7,52 77.7,52.21 77.8,52.31 78.01,52.31 78.11,52.21 78.11,52 78.21,51.9 78.41,51.9 78.51,52 78.51,52.21 78.62,52.31 78.82,52.31 78.92,52.21 78.92,52 79.02,51.9 79.23,51.9 79.33,52 79.33,52.21 79.43,52.31 84.31,52.31 84.42,52.41 84.42,53.36 84.53,53.47 84.76,53.47 84.86,53.37 84.86,52.52 84.96,52.42 85.16,52.42 85.28,52.54 85.28,53.34 85.41,53.47 86.21,53.47 87.49,54.75 88.78,54.75 102.47,68.44 104.08,68.44 105.93,70.29 105.93,71.36 105.89,71.4 105.89,72.34 106.28,72.74 110.3,72.74 v2(110.97,72.08)
  BOTTOM w0.076: UC1.AW25 115.69,73.08 115.43,72.82 114.95,72.82 114.68,72.55 114.68,72.29 114.57,72.18 114.17,72.18 114.13,72.22 113.68,72.22 113.31,71.84 112.61,71.84 112.38,72.08 v2(110.97,72.08)
  BOTTOM w0.102: v2(77.32,51.99) 76.67,52.64 75.97,52.64 75.46,53.15 72.43,53.15 71.77,52.49 JDIMM1.232
DDR_A_D60: length 57.5
  VCC w0.076: v2(111.87,73.98) 111.87,71.99 111.17,71.29
  VCC w0.102: 111.17,71.29 109.01,69.13 108.32,69.13 105.13,65.95 103.5,65.95 89.81,52.26 88.54,52.26 86.09,49.82 85.62,49.82 85.52,49.72 85.52,48.59 85.42,48.48 85.21,48.48 85.11,48.59 85.11,49.72 85.01,49.82 84.83,49.82 84.72,49.7 84.72,48.66 83.87,47.81 76.02,47.81 75.83,48 v2(75.83,48.49)
  BOTTOM w0.076: UC1.BB27 113.5,74.4 113.48,74.39 112.34,74.39 111.93,73.98 v2(111.87,73.98)
  BOTTOM w0.102: v2(75.83,48.49) 75.88,48.54 75.91,48.54 76.6,49.24 JDIMM1.245
DDR_A_D61: length 58
  VCC w0.076: 111.34,71.92 111.34,73.34 v2(110.69,73.98)
  VCC w0.102: 111.34,71.92 111.34,71.9 108.98,69.55 108.28,69.55 105,66.26 103.37,66.26 89.68,52.58 88.4,52.58 85.96,50.14 84.5,50.14 84.4,50.03 84.4,48.89 84.3,48.79 84.09,48.79 83.99,48.89 83.99,50.03 83.89,50.14 83.66,50.14 83.56,50.04 83.56,49.54 83.43,49.41 80.8,49.41 80.6,49.21 80.6,48.81 80.53,48.74 80.19,48.74 80.09,48.64 80.09,48.3 79.99,48.19 79.79,48.19 79.69,48.3 79.69,48.64 79.59,48.74 79.4,48.74 79.28,48.62 79.28,48.27 79.14,48.13 77.48,48.13 77.35,48.25 v2(77.35,48.49)
  BOTTOM w0.076: v2(110.69,73.98) 111.09,73.59 112.06,73.59 112.7,74.22 113.5,74.22 113.58,74.15 114.07,74.15 114.11,74.19 114.25,74.19 114.46,74.4 UC1.BA27
  BOTTOM w0.102: v2(77.35,48.49) 77,48.13 77,48 77.15,47.85 77.82,47.85 78.21,48.24 JDIMM1.249
DDR_A_D62: length 58.3
  VCC w0.102: v2(109.19,72.07) 109.19,72.04 108.24,71.09 108.24,69.97 104.85,66.58 103.24,66.58 89.55,52.89 88.27,52.89 85.83,50.45 83.52,50.45 82.79,49.73 80.67,49.73 80,49.06 79.06,49.06 78.96,48.96 78.96,48.61 78.86,48.51 78.66,48.51 78.56,48.61 78.56,48.96 78.45,49.06 78.25,49.06 78.15,48.96 78.15,48.61 78.05,48.51 77.84,48.51 77.74,48.61 77.74,48.96 77.64,49.06 74.11,49.06 73.97,48.92 73.97,48.58 74.09,48.47 v2(74.4,48.47)
  BOTTOM w0.076: v2(109.19,72.07) 109.19,72.39 109.41,72.61 112.65,72.61 112.84,72.8 113.65,72.8 114,72.8 114.27,72.93 114.42,73.08 UC1.BA25
  BOTTOM w0.102: JDIMM1.246 71.78,48.99 71.93,49.14 74.45,49.14 74.55,49.04 74.55,48.66 74.4,48.52 v2(74.4,48.47)
DDR_A_D63: length 57
  VCC w0.102: v2(72.78,48.49) 72.78,49.77 72.9,49.9 73.17,49.9 73.25,49.82 73.25,49.54 73.36,49.43 78.99,49.43 79.11,49.54 79.11,50.06 79.22,50.17 79.42,50.17 79.51,50.07 79.51,49.54 79.63,49.43 79.83,49.43 79.93,49.53 79.93,49.97 80.01,50.05 82.66,50.05 83.39,50.77 85.7,50.77 88.14,53.21 89.42,53.21 103.11,66.9 104.72,66.9 107.9,70.08 107.9,71.37 108.59,72.07 v2(108.59,72.1)
  BOTTOM w0.076: UC1.BB25 113.7,73.08 113.58,72.97 112.78,72.97 112.58,72.77 109.27,72.77 v2(108.59,72.1)
  BOTTOM w0.102: v2(72.78,48.49) 72.78,48.44 72.33,47.99 JDIMM1.250
DDR_A_DQS0: length 68.4
  VCC w0.109: v2(75.8,109.76) 76.03,109.53 76.03,109.39 76.26,109.15 81.88,109.15 82.1,109.38 82.1,110.08 82.2,110.17 82.55,110.17 82.65,110.08 82.65,109.38 82.87,109.15 83.35,109.15 83.61,109.41 83.61,110.02 83.71,110.12 104.42,110.12 109.36,115.06 115.29,115.06 119.74,110.61 119.74,105.89 120.03,105.61 120.5,105.61 v2(120.6,105.5)
  BOTTOM w0.076: v2(120.6,105.5) 120.6,105.63 120.47,105.76 120.4,105.76 120.4,105.77 120.16,105.77 120.07,105.67 120.07,101.83 120.54,101.35 120.54,100.44 120.47,100.38 120.47,100.12 120.53,100 120.53,99.79 120.47,99.68 120.47,99.47 120.51,99.39 120.51,99.1 120.41,98.89 120.35,98.83 120.22,98.83 120.18,98.79 UC1.AM69
  BOTTOM w0.102: v2(75.8,109.76) 75.83,109.76 76,109.58 76,109.37 76.28,109.09 77.73,109.09 77.89,109.24 JDIMM1.13
DDR_A_DQS1: length 56.5
  VCC w0.109: v2(116.67,103.2) 116.7,103.23 116.7,104.39 115.5,105.58 106.71,105.58 106.03,106.26 86.01,106.26 83.23,103.49 75.71,103.49 75.36,103.14 74.45,103.14 74.19,103.4 74.19,104.05 v2(74.27,104.14)
  BOTTOM w0.076: v2(116.67,103.2) 116.37,103.2 116.3,103.13 116.3,102.66 117.41,101.55 117.41,100.86 117.4,100.86 117.4,100.66 117.49,100.57 117.49,100.09 117.44,99.95 117.44,99.84 117.49,99.71 117.49,99.43 117.46,99.35 117.46,99.14 117.55,98.95 117.66,98.95 117.72,99.01 117.72,99.04 UC1.AT70
  BOTTOM w0.102: JDIMM1.34 71.73,103.99 71.83,104.09 72.06,104.09 72.1,104.04 72.1,103.87 72.67,103.3 73.71,103.3 74.01,103.61 74.01,103.83 74.02,103.84 74.02,103.89 v2(74.27,104.14)
DDR_A_DQS2: length 51.7
  VCC w0.109: v2(110.74,100.68) 110.58,100.84 110.58,101.05 109.72,101.92 99.54,101.92 98.95,102.51 87.51,102.51 83.63,98.64 75.59,98.64 75.43,98.79 75.43,98.94 75.63,99.14 v2(75.78,99.14)
  BOTTOM w0.076: UC1.AY64 115.33,95.9 115,96.23 114.75,96.23 114.67,96.2 114.46,96.2 114.35,96.25 114.14,96.25 114.02,96.2 113.78,96.2 113.59,96.39 113.09,96.39 112.24,97.24 112.24,99.15 111.75,99.64 110.94,99.64 110.59,99.99 110.59,100.54 v2(110.74,100.68)
  BOTTOM w0.102: JDIMM1.55 78.3,98.74 78.13,98.91 77.53,98.91 76.81,99.63 75.52,99.63 75.42,99.53 75.42,99.39 75.67,99.14 v2(75.78,99.14)
DDR_A_DQS3: length 51.1
  VCC w0.076: v2(110.76,95.62) 110.6,95.62 110.45,95.78 110.45,96.14 109.72,96.86 107.45,96.86 107.09,97.22 107.09,97.24 106.88,97.45
  VCC w0.109: v2(74.03,92.94) 74.28,92.94 74.4,93.06 74.4,93.57 74.58,93.76 84,93.76 89.1,98.85 94.28,98.85 95.16,97.98 106.35,97.98 106.88,97.45
  BOTTOM w0.076: UC1.BA60 114.94,93.4 114.94,93.28 114.87,93.2 114.36,93.2 114.34,93.18 114.32,93.17 114.31,93.16 114.2,93.16 114.05,93.23 112.87,93.23 110.93,95.17 110.56,95.17 110.47,95.26 110.47,95.47 110.62,95.63 110.73,95.63 110.73,95.62 v2(110.76,95.62)
  BOTTOM w0.102: JDIMM1.76 71.97,93.49 72.07,93.59 73.87,93.59 74.27,93.18 v2(74.03,92.94)
DDR_A_DQS4: length 56.1
  VCC w0.076: v2(109.39,81.02) 109.56,80.86 109.56,80.42 109.45,80.32 109.09,80.32 108.86,80.55 108.33,80.55 108.09,80.32 105.15,80.32 103.61,78.78 102.83,78.78 102.82,78.8 102.8,78.8
  VCC w0.109: v2(75.87,66.18) 76.21,66.53 76.21,67.06 76.54,67.38 77.01,67.38 77.22,67.17 77.22,66.9 77.33,66.79 77.65,66.79 78.1,66.34 78.3,66.34 78.53,66.11 78.53,65.88 78.65,65.76 79.02,65.76 79.13,65.87 79.13,66.12 79.36,66.34 79.85,66.34 80.08,66.12 80.08,65.87 80.19,65.76 81.05,65.76 81.16,65.87 81.16,66.12 81.39,66.34 81.88,66.34 82.1,66.12 82.1,65.87 82.21,65.76 82.54,65.76 82.65,65.87 82.65,66.12 82.88,66.34 83.37,66.34 83.59,66.12 83.59,65.87 83.7,65.76 84.05,65.76 84.14,65.86 84.14,66.1 84.38,66.34 86.09,66.34 95.61,75.86 95.61,76.35 98.06,78.8 102.8,78.8
  BOTTOM w0.076: UC1.AY38 115.28,81.38 115.14,81.47 115.03,81.51 114.75,81.51 114.67,81.47 114.46,81.47 114.35,81.53 114.14,81.53 114.02,81.47 113.61,81.47 113.52,81.57 112.08,81.57 111.97,81.68 111.08,81.68 110.7,82.06 110.12,82.06 109.66,81.6 109.66,81.29 v2(109.39,81.02)
  BOTTOM w0.102: v2(75.87,66.18) 75.93,66.18 76.05,66.07 76.05,65.78 76.34,65.48 77.84,65.48 78.12,65.77 78.33,65.77 78.36,65.74 JDIMM1.179
DDR_A_DQS5: length 54.6
  VCC w0.076: v2(109.12,77.51) 109.28,77.51 109.41,77.63 109.41,77.75 109.23,77.92 106.09,77.92 102.88,74.71 102.39,74.71 102.37,74.7 102.32,74.7 102.3,74.68 102.29,74.68
  VCC w0.109: 102.29,74.68 99.88,74.68 87.13,61.93 84.29,61.93 83.72,61.35 74.15,61.35 74.1,61.3 74.1,61.04 74.25,60.89 v2(74.48,60.89)
  BOTTOM w0.076: v2(109.12,77.51) 109.36,77.74 109.36,78.01 109.71,78.36 113.58,78.36 113.7,78.48 114.09,78.48 114.17,78.44 114.3,78.44 114.43,78.49 114.7,78.49 114.78,78.46 115,78.46 115.06,78.48 115.15,78.53 115.17,78.58 115.17,78.66 115.1,78.72 UC1.BA34
  BOTTOM w0.102: v2(74.48,60.89) 74.21,60.62 74.21,60.59 74.21,60.59 74.21,60.5 73.93,60.23 72.43,60.23 72.05,60.6 71.93,60.6 71.82,60.49 JDIMM1.200
DDR_A_DQS6: length 55.2
  VCC w0.076: v2(109.48,75.75) 109.48,74.78 109.4,74.69 105.71,74.69 103.92,72.9 103.92,72.65 102.52,71.24 102.5,71.24
  VCC w0.109: v2(75.8,55.99) 76,56.19 76,56.59 76.21,56.8 79.81,56.8 80.05,56.56 80.05,56.41 80.18,56.28 80.8,56.28 80.91,56.39 80.91,56.69 81.13,56.91 81.67,56.91 81.86,56.71 81.86,56.58 81.92,56.52 85.3,56.52 85.6,56.83 85.6,57.33 85.83,57.56 87.62,57.56 101.31,71.24 102.5,71.24
  BOTTOM w0.076: UC1.AY30 115.34,76.4 115.06,76.53 114.75,76.53 114.67,76.49 114.46,76.49 114.35,76.55 114.14,76.55 114.02,76.49 113.41,76.49 113.38,76.52 112.84,76.52 112.64,76.31 109.87,76.31 109.7,76.14 109.7,75.96 v2(109.48,75.75)
  BOTTOM w0.102: JDIMM1.221 78.39,55.24 78.23,55.39 78.13,55.39 77.71,54.98 76.43,54.98 76.1,55.31 76.1,55.84 75.95,55.99 v2(75.8,55.99)
DDR_A_DQS7: length 59.2
  VCC w0.109: v2(106.65,72.03) 106.98,71.7 106.98,70.16 104.42,67.61 102.81,67.61 89.12,53.92 87.85,53.92 85.4,51.48 83.09,51.48 82.4,50.79 80.19,50.79 79.91,51.07 78.6,51.07 78.4,50.87 78.4,50.22 78.32,50.14 77.99,50.14 77.86,50.27 77.86,50.93 77.72,51.07 75.64,51.07 75.29,51.43 74.39,51.43 74.04,51.08 74.04,50.6 73.74,50.3 v2(73.56,50.3)
  BOTTOM w0.076: v2(106.65,72.03) 106.8,72.18 106.8,72.44 107.46,73.1 108.09,73.1 108.12,73.13 108.66,73.13 108.69,73.1 112.45,73.1 112.64,73.3 113.45,73.3 113.66,73.51 114.05,73.51 114.19,73.46 114.3,73.46 114.43,73.51 114.7,73.51 114.78,73.48 115,73.48 115.06,73.5 115.15,73.55 115.17,73.6 115.17,73.68 115.1,73.74 UC1.BA26
  BOTTOM w0.102: JDIMM1.242 71.81,49.99 71.96,50.14 72.07,50.14 72.66,50.73 73.55,50.73 73.69,50.59 73.69,50.43 v2(73.56,50.3)
DDR_A_DQS#0: length 68.4
  VCC w0.109: v2(76.56,109.76) 76.37,109.76 76.23,109.61 76.23,109.47 76.34,109.35 81.79,109.35 81.9,109.46 81.9,110.16 82.12,110.37 82.64,110.37 82.85,110.16 82.85,109.46 82.95,109.35 83.27,109.35 83.41,109.49 83.41,110.1 83.62,110.32 104.34,110.32 109.28,115.26 115.37,115.26 119.94,110.69 119.94,105.97 120.11,105.8 120.27,105.8 v2(120.6,106.13)
  BOTTOM w0.076: UC1.AM70 120.07,99.08 120.16,98.99 120.28,98.99 120.34,99.14 120.34,99.35 120.31,99.43 120.31,99.71 120.36,99.84 120.36,99.95 120.31,100.09 120.31,100.44 120.38,100.51 120.38,101.28 119.9,101.76 119.9,105.74 120.09,105.93 120.4,105.93 v2(120.6,106.13)
  BOTTOM w0.102: JDIMM1.11 78.28,109.74 77.98,109.43 77.81,109.43 77.65,109.28 76.36,109.28 76.2,109.44 76.2,109.66 76.3,109.76 v2(76.56,109.76)
DDR_A_DQS#1: length 56.4
  VCC w0.109: v2(73.51,104.14) 73.58,104.14 73.99,103.73 73.99,103.32 74.36,102.94 75.44,102.94 75.79,103.29 83.32,103.29 86.09,106.07 105.94,106.07 106.63,105.38 115.42,105.38 116.5,104.31 116.5,103.88 116.25,103.63 v2(116.25,103.62)
  BOTTOM w0.076: v2(116.25,103.62) 116.25,103.32 116.13,103.2 116.13,102.59 117.24,101.48 117.24,100.93 117.24,100.93 117.24,100.59 117.33,100.5 117.33,100.12 117.27,100 117.27,99.79 117.33,99.68 117.33,99.47 117.29,99.39 117.29,99.1 117.51,98.63 117.54,98.6 UC1.AT69
  BOTTOM w0.102: JDIMM1.32 71.76,104.49 71.96,104.28 72.14,104.28 72.3,104.12 72.3,103.95 72.75,103.49 73.63,103.49 73.82,103.69 73.82,103.83 v2(73.51,104.14)
DDR_A_DQS#2: length 51.8
  VCC w0.109: v2(75.01,99.14) 75.24,98.92 75.24,98.71 75.51,98.44 83.71,98.44 87.59,102.32 98.87,102.32 99.46,101.72 109.64,101.72 110.39,100.97 110.39,100.92 v2(110.15,100.68)
  BOTTOM w0.076: UC1.BA64 115,95.8 115.07,95.87 115.07,95.93 114.93,96.07 114.78,96.07 114.7,96.03 114.43,96.03 114.3,96.09 114.17,96.09 114.06,96.03 113.71,96.03 113.52,96.22 113.02,96.22 112.07,97.17 112.07,99.08 111.68,99.47 110.87,99.47 110.43,99.92 110.43,100.41 v2(110.15,100.68)
  BOTTOM w0.102: JDIMM1.53 78.27,99.24 78.13,99.1 77.61,99.1 76.89,99.82 75.44,99.82 75.23,99.61 75.23,99.36 v2(75.01,99.14)
DDR_A_DQS#3: length 51.1
  VCC w0.076: v2(110.11,95.62) 110.28,95.79 110.28,96.07 109.65,96.7 107.38,96.7 106.63,97.44 106.61,97.44
  VCC w0.109: v2(74.79,92.94) 74.6,93.13 74.6,93.49 74.66,93.56 84.09,93.56 89.18,98.66 94.2,98.66 95.07,97.78 106.27,97.78 106.61,97.44
  BOTTOM w0.076: v2(110.11,95.62) 110.3,95.44 110.3,95.19 110.49,95 110.87,95 112.8,93.06 114.02,93.06 114.16,93 114.33,93 114.33,93 114.38,93 114.41,93.03 114.43,93.04 114.94,93.04 115.25,93.35 UC1.AY60
  BOTTOM w0.102: v2(74.79,92.94) 73.95,93.78 72.19,93.78 71.97,93.99 JDIMM1.74
DDR_A_DQS#4: length 56
  VCC w0.076: v2(110.04,81.02) 109.89,81.02 109.72,80.86 109.72,80.36 109.52,80.15 109.02,80.15 108.79,80.39 108.4,80.39 108.16,80.15 105.22,80.15 103.68,78.61 102.84,78.61 102.82,78.6 102.8,78.6
  VCC w0.109: v2(76.63,66.18) 76.41,66.41 76.41,66.97 76.62,67.19 76.93,67.19 77.02,67.09 77.02,66.82 77.25,66.59 77.57,66.59 78.02,66.14 78.22,66.14 78.33,66.03 78.33,65.8 78.57,65.57 79.11,65.57 79.33,65.79 79.33,66.03 79.44,66.14 79.77,66.14 79.88,66.03 79.88,65.79 80.1,65.57 81.14,65.57 81.36,65.79 81.36,66.03 81.47,66.14 81.8,66.14 81.91,66.03 81.91,65.79 82.13,65.57 82.62,65.57 82.85,65.79 82.85,66.03 82.96,66.14 83.29,66.14 83.39,66.03 83.39,65.79 83.62,65.57 84.13,65.57 84.34,65.78 84.34,66.02 84.46,66.14 86.18,66.14 95.81,75.78 95.81,76.26 98.14,78.6 102.8,78.6
  BOTTOM w0.076: UC1.BA38 115.07,80.99 115.18,80.99 115.25,81.03 115.25,81.11 115.25,81.11 115.25,81.18 115.22,81.21 115.15,81.27 115.06,81.32 115,81.34 114.78,81.34 114.7,81.31 114.43,81.31 114.3,81.36 114.19,81.36 114.05,81.31 113.54,81.31 113.45,81.41 112.02,81.41 111.9,81.52 111.01,81.52 110.63,81.89 110.19,81.89 109.82,81.53 109.82,81.24 v2(110.04,81.02)
  BOTTOM w0.102: JDIMM1.177 78.39,66.24 78.12,65.96 78.05,65.96 77.76,65.68 76.42,65.68 76.24,65.86 76.24,66.01 76.41,66.18 v2(76.63,66.18)
DDR_A_DQS#5: length 54.4
  VCC w0.076: 102.29,74.88 102.81,74.88 106.02,78.09 109.3,78.09 109.57,77.81 109.57,77.71 v2(109.77,77.51)
  VCC w0.109: 102.29,74.88 99.8,74.88 87.05,62.13 84.21,62.13 83.63,61.55 74.07,61.55 73.9,61.38 73.9,61.07 v2(73.72,60.89)
  BOTTOM w0.076: UC1.AY34 115.41,78.62 115.33,78.54 115.28,78.42 115.14,78.33 115.03,78.29 114.75,78.29 114.67,78.33 114.46,78.33 114.35,78.27 114.14,78.27 114.05,78.31 113.77,78.31 113.65,78.2 109.78,78.2 109.52,77.94 109.52,77.76 v2(109.77,77.51)
  BOTTOM w0.102: JDIMM1.198 71.82,60.99 72.02,60.79 72.03,60.79 72.04,60.79 72.13,60.79 72.51,60.42 73.85,60.42 74.02,60.58 74.02,60.73 73.86,60.89 v2(73.72,60.89)
DDR_A_DQS#6: length 55.2
  VCC w0.076: v2(110.14,75.75) 110.01,75.75 109.65,75.39 109.65,74.71 109.47,74.53 105.78,74.53 104.09,72.83 104.09,72.58 102.56,71.05
  VCC w0.109: 102.56,71.05 101.39,71.05 87.7,57.36 85.91,57.36 85.8,57.25 85.8,56.75 85.38,56.33 81.84,56.33 81.67,56.5 81.67,56.63 81.58,56.71 81.21,56.71 81.11,56.61 81.11,56.31 80.88,56.08 80.1,56.08 79.82,56.36 79.82,56.51 79.73,56.6 76.29,56.6 76.2,56.51 76.2,56.09 76.3,55.99 v2(76.56,55.99)
  BOTTOM w0.076: v2(110.14,75.75) 110,75.75 109.86,75.89 109.86,76.07 109.94,76.15 112.7,76.15 112.91,76.36 113.31,76.36 113.34,76.33 114.06,76.33 114.17,76.38 114.19,76.38 114.3,76.38 114.43,76.33 114.7,76.33 114.78,76.36 115,76.36 115.06,76.34 115.18,76.26 115.23,76.22 115.23,76.14 115.14,76.05 115.07,76.05 UC1.BA30
  BOTTOM w0.102: JDIMM1.219 78.37,55.74 78.22,55.58 78.18,55.58 78.17,55.59 78.05,55.59 77.63,55.17 76.51,55.17 76.29,55.39 76.29,55.62 76.29,55.62 76.29,55.85 76.43,55.99 v2(76.56,55.99)
DDR_A_DQS#7: length 59.3
  VCC w0.109: v2(107.3,72.03) 107.17,71.9 107.17,70.08 104.51,67.41 102.89,67.41 89.21,53.72 87.93,53.72 85.49,51.28 83.17,51.28 82.49,50.59 80.11,50.59 79.83,50.87 78.68,50.87 78.6,50.79 78.6,50.14 78.4,49.94 77.91,49.94 77.66,50.19 77.66,50.85 77.64,50.87 75.56,50.87 75.2,51.23 74.47,51.23 74.24,51 74.24,50.38 v2(74.32,50.3)
  BOTTOM w0.076: UC1.AY26 115.35,73.64 115.33,73.62 115.33,73.56 115.28,73.44 115.28,73.44 115.14,73.35 115.03,73.31 114.75,73.31 114.67,73.35 114.46,73.35 114.35,73.29 114.14,73.29 114.02,73.35 113.73,73.35 113.51,73.13 112.71,73.13 112.51,72.94 v3(108.39,72.94) 107.53,72.94 106.97,72.38 106.97,72.26 107.2,72.03 v2(107.3,72.03)
  BOTTOM w0.102: v2(74.32,50.3) 74.25,50.3 73.63,50.92 72.58,50.92 71.99,50.33 71.93,50.33 71.78,50.49 JDIMM1.240
DDR_A_MA0: length 50.4
  VCC w0.076: 107.54,86.74 107.56,86.76 114.74,86.76 v2(115.36,87.38)
  VCC w0.102: v2(74.21,76.63) 75,75.85 80.21,75.85 81.32,76.96 85.63,76.96 94.88,86.2 107.01,86.2 107.54,86.74
  BOTTOM w0.076: UC1.AY50 115.22,87.57 115.36,87.43 v2(115.36,87.38)
  BOTTOM w0.163: JDIMM1.144 71.92,76.49 72.28,76.13 73.76,76.13 74.21,76.59 v2(74.21,76.63)
DDR_A_MA1: length 51.3
  VCC w0.076: v2(109.87,89.74) 109.46,89.33 104.18,89.33 104.1,89.24
  VCC w0.102: v2(75.71,79.3) 75.71,79.55 75.9,79.74 81.37,79.74 81.47,79.84 81.47,80.21 81.57,80.31 81.77,80.31 81.87,80.21 81.87,79.84 81.98,79.74 82.18,79.74 82.28,79.84 82.28,80.21 82.38,80.31 82.59,80.31 82.69,80.21 82.69,79.84 82.79,79.74 84.85,79.74 93.9,88.79 103.35,88.79 103.81,89.24 104.1,89.24
  BOTTOM w0.076: UC1.BB50 113.93,87.82 113.93,87.71 113.85,87.63 112.71,87.63 110.79,89.55 110.05,89.55 v2(109.87,89.74)
  BOTTOM w0.163: JDIMM1.133 78.08,79.24 77.01,80.31 75.21,80.31 75.04,80.15 75.04,79.83 75.57,79.3 v2(75.71,79.3)
DDR_A_MA2: length 52.8
  VCC w0.076: v2(110.58,90.09) 110.56,90.11 109.72,90.11 109.13,89.52 103.11,89.52
  VCC w0.102: v2(74.19,79.3) 75.01,80.12 80.97,80.12 81.09,80.25 81.09,80.5 81.31,80.72 82.98,80.72 83.08,80.62 83.08,80.22 83.18,80.12 83.4,80.12 83.49,80.21 83.49,80.62 83.59,80.72 85.29,80.72 93.91,89.34 102.93,89.34 103.11,89.52
  BOTTOM w0.076: UC1.AY51 115.4,88.31 115.13,88.31 115.08,88.25 114.99,88.22 114.77,88.22 114.73,88.25 114.37,88.25 114.35,88.23 114.33,88.22 114.15,88.22 114.06,88.26 113.71,88.26 113.42,87.96 112.85,87.96 110.73,90.09 v2(110.58,90.09)
  BOTTOM w0.163: v2(74.19,79.3) 74.36,79.3 74.57,79.51 74.57,79.74 74.34,79.97 73.87,79.97 73.64,79.74 73.11,79.74 72.92,79.94 72.29,79.94 71.84,79.49 JDIMM1.132
DDR_A_MA3: length 52.1
  VCC w0.076: 102.74,89.89 v2(108.47,89.89)
  VCC w0.102: 102.74,89.89 102.57,89.72 93.6,89.72 84.98,81.1 80.47,81.1 79.88,80.5 78.65,80.5 78.55,80.61 78.55,80.72 78.45,80.82 78.24,80.82 78.14,80.72 78.14,80.61 78.04,80.5 77.84,80.5 77.73,80.61 77.73,80.72 77.63,80.82 77.43,80.82 77.33,80.72 77.33,80.61 77.23,80.5 76.83,80.5 76.77,80.56 v2(76.77,80.79)
  BOTTOM w0.076: v2(108.47,89.89) 106.51,89.89 106.44,89.81 106.44,89.44 106.51,89.37 110.74,89.37 111.01,89.11 111.01,88.07 111.62,87.46 114.63,87.46 114.71,87.53 114.71,87.75 114.63,87.83 UC1.BA50
  BOTTOM w0.163: v2(76.77,80.79) 76.9,80.92 77.13,80.92 78.31,79.74 JDIMM1.131
DDR_A_MA4: length 51.6
  VCC w0.076: 102.37,90.26 106.54,90.26 v2(106.92,90.63)
  VCC w0.102: v2(73.72,80.79) 73.2,80.27 72.83,80.27 72.42,80.68 72.42,80.91 72.71,81.2 79.95,81.2 80.24,81.48 84.67,81.48 93.44,90.26 102.37,90.26
  BOTTOM w0.076: UC1.BB52 113.87,89.11 112.55,89.11 110.87,90.78 110.16,90.78 109.75,91.2 107.48,91.2 v2(106.92,90.63)
  BOTTOM w0.163: JDIMM1.128 72.49,80.49 72.62,80.36 73.29,80.36 v2(73.72,80.79)
DDR_A_MA5: length 53
  VCC w0.076: 105.23,91.41 105.44,91.2 108.13,91.2 v2(108.68,90.64)
  VCC w0.102: v2(73.88,82.26) 74.6,82.98 77.37,82.98 77.94,83.55 80.23,83.55 80.33,83.65 80.33,84.57 80.43,84.67 80.63,84.67 80.73,84.56 80.73,83.65 80.84,83.55 84.65,83.55 92.51,91.41 105.23,91.41
  BOTTOM w0.076: UC1.BA51 114.89,88.64 114.82,88.72 114.45,88.72 114.44,88.72 114.43,88.72 114.43,88.72 114.34,88.76 114.14,88.76 114.05,88.72 114.04,88.72 112.47,88.72 110.73,90.45 110.17,90.45 109.99,90.27 108.84,90.27 108.68,90.43 v2(108.68,90.64)
  BOTTOM w0.163: v2(73.88,82.26) 74.03,82.26 74.31,81.98 74.31,81.39 74.15,81.23 72.07,81.23 71.83,80.99 JDIMM1.126
DDR_A_MA6: length 52.1
  VCC w0.076: 102.34,90.65 v2(106.33,90.65)
  VCC w0.102: 102.34,90.65 93.14,90.65 84.35,81.86 80.08,81.86 79.8,81.58 75.09,81.58 74.96,81.71 74.96,82.01 75.22,82.26 v2(75.41,82.26)
  BOTTOM w0.076: v2(106.33,90.65) 106,90.65 105.93,90.72 105.93,91.14 106.2,91.42 109.76,91.42 110.23,90.95 110.94,90.95 112.62,89.27 113.62,89.27 113.76,89.41 114.41,89.41 114.57,89.25 UC1.BA52
  BOTTOM w0.163: JDIMM1.127 77.9,80.74 77.3,81.34 75.2,81.34 75.04,81.5 75.04,81.9 v2(75.41,82.26)
DDR_A_MA7: length 53.7
  VCC w0.076: v2(108.73,91.99) 108.73,92.42 108.56,92.6 107.63,92.6 107.19,92.17 102.24,92.17
  VCC w0.102: 102.24,92.17 91.89,92.17 85.15,85.43 77.87,85.43 77.73,85.29 77.73,84.45 77.41,84.13 74.41,84.13 74.29,84.02 v2(74.29,83.52)
  BOTTOM w0.076: v2(108.73,91.99) 108.54,91.79 108.53,91.79 108.53,91.66 108.61,91.58 109.83,91.58 110.3,91.11 111.01,91.11 112.68,89.44 113.55,89.44 113.69,89.57 114.67,89.57 114.86,89.39 115.79,89.39 115.87,89.31 UC1.AW52
  BOTTOM w0.163: v2(74.29,83.52) 74.29,83.49 74.43,83.49 74.81,83.12 74.81,82.91 74.59,82.7 72.94,82.7 72.3,82.06 71.86,82.06 71.78,81.99 JDIMM1.122
DDR_A_MA8: length 52.4
  VCC w0.076: 103.37,91.02 107.98,91.02 108.1,90.9 v2(108.1,90.63)
  VCC w0.102: 103.37,91.02 103.36,91.03 92.83,91.03 84.04,82.24 79.36,82.24 79.26,82.34 79.26,83.05 79.14,83.17 78.93,83.17 78.8,83.04 78.8,82.02 78.74,81.96 78.48,81.96 78.4,82.04 78.4,83.07 78.3,83.17 78.1,83.17 78,83.07 78,82.09 77.86,81.96 77.67,81.96 77.56,82.08 77.56,82.53 77.49,82.6 77.05,82.6 76.93,82.48 v2(76.93,82.26)
  BOTTOM w0.076: v2(108.1,90.63) 107.88,90.85 107.88,90.96 107.96,91.03 109.68,91.03 110.09,90.62 110.8,90.62 112.54,88.89 114.01,88.89 114.11,88.92 114.13,88.92 114.37,88.92 114.47,88.88 114.94,88.88 115.01,88.81 115.19,88.81 115.26,88.89 115.26,89.01 UC1.AY52
  BOTTOM w0.163: JDIMM1.125 77.99,81.24 77.48,81.76 76.74,81.76 76.58,81.92 76.58,82.11 76.73,82.26 v2(76.93,82.26)
DDR_A_MA9: length 51
  VCC w0.076: 102.24,91.79 104.99,91.79 105.13,91.94 105.81,91.94 106.29,91.45 106.99,91.45 v2(107.48,91.94)
  VCC w0.102: v2(77.34,83.52) 77.75,83.93 78.11,83.93 78.23,84.04 78.23,84.95 78.33,85.05 78.53,85.05 78.63,84.95 78.63,84.04 78.75,83.93 78.99,83.93 79.08,84.02 79.08,84.93 79.2,85.05 79.42,85.05 79.53,84.95 79.53,84.03 79.63,83.93 79.83,83.93 79.93,84.03 79.93,84.95 80.03,85.05 85.46,85.05 92.2,91.79 102.24,91.79
  BOTTOM w0.076: v2(107.48,91.94) 106.73,91.94 106.65,92.01 106.65,92.27 106.75,92.37 109.81,92.37 109.95,92.51 110.67,92.51 110.9,92.28 110.9,91.92 112.75,90.07 113.84,90.07 113.92,90.15 UC1.BB54
  BOTTOM w0.163: v2(77.34,83.52) 77.34,83.49 77.23,83.39 77.23,83.19 78.18,82.24 JDIMM1.121
DDR_A_MA10: length 54
  VCC w0.076: 108.13,86.13 112.24,86.13 112.7,86.59 115.1,86.59 115.85,87.34 115.85,88.2 116.46,88.82 116.91,88.82 v2(117.44,88.28)
  VCC w0.102: v2(72.79,75.05) 73.2,75.45 80.98,75.45 82.1,76.58 85.79,76.58 95.04,85.82 107.24,85.82 107.54,86.13 108.13,86.13
  BOTTOM w0.076: v2(117.44,88.28) 117.48,88.28 117.68,88.07 UC1.AT50
  BOTTOM w0.163: JDIMM1.146 71.87,73.99 72.79,74.91 v2(72.79,75.05)
DDR_A_MA11: length 51.4
  VCC w0.076: v2(110.51,91.99) 109.17,93.33 104.03,93.33 104.02,93.32
  VCC w0.102: v2(72.76,83.52) 72.76,85.83 73.59,86.66 84.3,86.66 90.95,93.32 104.02,93.32
  BOTTOM w0.076: v2(110.51,91.99) 110.6,91.99 112.82,89.77 113.42,89.77 113.55,89.9 114.08,89.9 114.36,90.18 UC1.BA54
  BOTTOM w0.163: v2(72.76,83.52) 72.76,83.12 72.14,82.49 JDIMM1.120
DDR_A_MA12: length 52.8
  VCC w0.076: v2(109.92,92.01) 109.92,92.35 109.28,92.98 106.95,92.98 106.38,92.41 103.03,92.41 102.89,92.55 102.24,92.55
  VCC w0.102: 102.24,92.55 91.58,92.55 84.84,85.81 77.18,85.81 77.07,85.7 77.07,84.97 76.97,84.87 76.77,84.87 76.66,84.97 76.66,85.7 76.55,85.81 76.19,85.81 76.12,85.75 76.12,84.72 76.21,84.62 v2(76.44,84.62)
  BOTTOM w0.076: v2(109.92,92.01) 109.92,91.73 110.37,91.28 111.08,91.28 112.75,89.6 113.49,89.6 113.62,89.74 114.56,89.74 114.77,89.95 115.91,89.95 115.98,90.02 115.98,90.21 115.91,90.28 UC1.AW54
  BOTTOM w0.163: v2(76.44,84.62) 76.3,84.62 76.08,84.4 76.08,84.23 76.19,84.12 77.36,84.12 78.07,83.41 78.07,83.09 78.42,82.74 JDIMM1.119
DDR_A_MA13: length 55.4
  VCC w0.076: 102.8,81.48 102.93,81.48 103.23,81.78 111.88,81.78 112.07,81.58 113.6,81.58 116.22,84.21 117.43,84.21 117.69,84.46 117.69,85.28 v2(117.43,85.54)
  VCC w0.102: 102.8,81.48 96.94,81.48 87,71.55 86.51,71.55 84.66,69.7 78.75,69.7 78.19,70.26 73.54,70.26 v2(72.97,70.83)
  BOTTOM w0.076: v2(117.43,85.54) 117.43,85.63 UC1.AU46
  BOTTOM w0.163: v2(72.97,70.83) 72.52,70.83 72.36,70.99 JDIMM1.158
DDR_A_ODT0: length 57.5
  VCC w0.076: 103.07,82.47 103.07,82.47 111.7,82.47 112.17,82 112.66,82 115.15,84.49 115.87,84.49 116.32,84.94 117.05,84.94 117.09,84.98 117.32,84.98 117.45,84.86 117.45,84.74 v2(117.32,84.61)
  VCC w0.102: 103.07,82.47 96.43,82.47 87.18,73.22 87.04,73.22 86.94,73.12 86.94,72.88 86.83,72.78 86.63,72.78 86.53,72.87 86.53,73.12 86.43,73.22 86.23,73.22 86.12,73.12 86.12,72.64 86.02,72.54 85.82,72.54 85.72,72.64 85.72,73.12 85.62,73.22 85.38,73.22 85.28,73.12 85.28,72.65 85.16,72.54 84.7,72.54 83.57,71.42 77.11,71.42 76.93,71.24 75.35,71.24 75.27,71.32 75.27,71.51 75.36,71.61 75.75,71.61 75.8,71.65 v2(75.8,71.86)
  BOTTOM w0.076: UC1.AT45 117.68,85.11 117.79,85.11 117.88,85.03 117.88,84.92 117.72,84.77 117.72,84.65 117.59,84.51 117.39,84.51 117.32,84.59 v2(117.32,84.61)
  BOTTOM w0.163: v2(75.8,71.86) 75.62,71.86 75.43,71.66 75.43,71.43 75.58,71.28 77.74,71.28 78.19,71.74 JDIMM1.155
DDR_A_ODT1: length 59.3
  VCC w0.076: v2(117.36,83.81) 117.13,84.04 116.31,84.04 114.8,82.53 114.8,82.15 114.07,81.42 111.99,81.42 111.8,81.62 103.82,81.62 103.07,80.87 102.8,80.87
  VCC w0.102: v2(77.28,69.65) 77.94,69.65 78.5,69.09 79.02,69.09 79.12,68.99 79.12,68.5 79.21,68.41 79.41,68.41 79.53,68.53 79.53,68.99 79.63,69.09 79.86,69.09 79.96,68.99 79.96,68.52 80.06,68.41 80.26,68.41 80.36,68.52 80.36,68.99 80.47,69.09 80.67,69.09 80.77,68.99 80.77,68.52 80.87,68.41 81.08,68.41 81.18,68.52 81.18,68.99 81.28,69.09 81.48,69.09 81.58,68.99 81.58,68.52 81.69,68.41 81.89,68.41 81.99,68.52 81.99,68.99 82.09,69.09 82.32,69.09 82.42,68.99 82.42,68.52 82.52,68.42 82.73,68.42 82.83,68.52 82.83,68.99 82.93,69.09 83.13,69.09 83.23,68.99 83.23,68.52 83.34,68.41 83.54,68.41 83.64,68.52 83.64,68.99 83.74,69.09 83.95,69.09 84.05,68.99 84.05,68.52 84.15,68.41 84.35,68.41 84.45,68.52 84.45,68.99 84.56,69.09 84.91,69.09 86.17,70.34 86.31,70.34 86.42,70.23 86.56,70.23 86.71,70.38 86.71,70.52 86.6,70.63 86.6,70.77 86.73,70.91 86.9,70.91 87,70.81 87.13,70.81 97.19,80.87 102.8,80.87
  BOTTOM w0.076: UC1.AT43 117.72,84.24 117.83,84.24 118.13,83.94 118.13,83.64 118.05,83.56 117.42,83.56 117.34,83.64 117.34,83.8 v2(117.36,83.81)
  BOTTOM w0.163: JDIMM1.161 78.3,70.24 78.03,69.96 77.59,69.96 v2(77.28,69.65)
DDR_A_PAR: length 51.6
  VCC w0.076: v2(117.34,89.23) 115.53,89.23 113.3,87 107.27,87
  VCC w0.102: 107.27,87 106.85,86.59 94.72,86.59 85.48,77.34 81.16,77.34 80.05,76.23 76.14,76.23 v2(75.74,76.63)
  BOTTOM w0.076: UC1.AT52 v2(117.34,89.23)
  BOTTOM w0.163: JDIMM1.143 78.44,76.74 77.84,76.13 76.24,76.13 v2(75.74,76.63)
DDR_A_RAS#: length 52.9
  VCC w0.076: v2(116.66,87.38) 116.59,87.38 115.1,85.89 114.81,85.89 113.09,84.17 108.21,84.17
  VCC w0.102: v2(74.23,73.21) 75.28,74.26 82.77,74.26 83.94,75.43 86.27,75.43 95.51,84.68 104.97,84.68 105.48,84.17 108.21,84.17
  BOTTOM w0.076: UC1.AU50 116.66,87.49 v2(116.66,87.38)
  BOTTOM w0.163: v2(74.23,73.21) 73.51,72.49 JDIMM1.152
DDR_A_WE#: length 52.6
  VCC w0.076: v2(117.35,86.47) 116.98,86.84 116.28,86.84 115.08,85.64 114.79,85.64 112.8,83.65 112.39,83.65 111.71,82.97 106.15,82.97 105.53,83.58
  VCC w0.102: v2(75.75,73.21) 76.43,73.88 82.93,73.88 84.1,75.05 86.42,75.05 95.67,84.3 104.82,84.3 105.53,83.58
  BOTTOM w0.076: UC1.AT46 v2(117.35,86.47)
  BOTTOM w0.163: JDIMM1.151 77.69,72.74 77.69,72.74 76.22,72.74 v2(75.75,73.21)
DDR_B_ACT#: length 70.1
  IN2 w0.076: v2(119.9,90.1) 119.33,90.67 118.99,90.67 118.97,90.69 115.41,90.69 113.45,92.65 112.55,92.65 110.7,94.51 103.32,94.51 102.88,94.95
  IN2 w0.18: v2(61.57,85.26) 61.57,86.25 61.73,86.41 65.17,86.41 67.37,88.61 69.79,88.61 72.14,90.96 78.68,90.96 80,92.29 85.04,92.29 88.74,95.98 101.85,95.98 102.88,94.95
  BOTTOM w0.076: v2(119.9,90.1) 119.9,89.95 UC1.AN53
  BOTTOM w0.163: JDIMM2.114 60.3,83.99 v2(61.57,85.26)
DDR_B_ALERT#: length 74.8
  IN2 w0.076: 101.9,93.98 102.52,93.36 108.94,93.36 109.09,93.21 111.3,93.21 114.91,89.6 118.14,89.6 118.97,88.76 119.51,88.76 119.85,88.43 119.85,87.27 120.27,86.85 120.27,85.4 119.6,84.73 v2(119.29,84.73)
  IN2 w0.18: 101.9,93.98 101.28,94.6 89.31,94.6 84.26,89.55 80.04,89.55 79.5,89.01 74.63,89.01 74.09,89.55 72.68,89.55 69.86,86.74 67.45,86.74 65.51,84.8 62,84.8 v2(60.1,82.9)
  BOTTOM w0.102: v2(119.29,84.73) UC1.AN43
  BOTTOM w0.163: v2(60.1,82.9) 59.91,82.9 59.32,83.49 JDIMM2.116
DDR_B_BG0: length 70
  IN2 w0.076: 102.55,94.63 102.83,94.35 110.63,94.35 115,89.97 115.92,89.97 116.47,90.52 118.91,90.52 118.96,90.47 119.29,90.47 119.35,90.41 119.35,90.15 v2(119.31,90.11)
  IN2 w0.18: v2(63.1,85.26) 62.86,85.49 62.86,85.8 63.01,85.95 65.36,85.95 67.07,87.66 69.48,87.66 72.33,90.5 79.85,90.5 80.02,90.67 80.02,91.55 80.3,91.83 85.24,91.83 88.93,95.52 101.66,95.52 102.55,94.63
  BOTTOM w0.076: v2(119.31,90.11) 119.31,89.24 118.98,88.91 UC1.AP52
  BOTTOM w0.163: v2(63.1,85.26) 63.56,84.8 64.15,84.8 65.21,83.74 JDIMM2.115
DDR_B_BG1: length 70
  IN2 w0.076: 104.93,94 105.11,94.18 110.56,94.18 114.98,89.76 118.87,89.76 119.48,89.14 v2(119.98,89.14)
  IN2 w0.18: 104.93,94 104.62,93.7 102.83,93.7 101.47,95.06 89.12,95.06 85.31,91.24 84.43,91.24 84.26,91.08 84.26,90.2 84.1,90.04 83.71,90.04 83.53,90.22 83.53,91.13 83.34,91.31 82.98,91.31 82.8,91.13 82.8,90.22 82.62,90.04 82.25,90.04 82.13,90.16 82.13,91.19 81.95,91.37 81.59,91.37 81.41,91.19 81.41,90.2 81.25,90.04 72.52,90.04 69.67,87.2 67.26,87.2 65.32,85.26 v2(64.62,85.26)
  BOTTOM w0.076: v2(119.98,89.14) 119.64,88.8 UC1.AN52
  BOTTOM w0.163: JDIMM2.113 65.92,84.24 65.91,84.24 65.62,84.24 64.62,85.23 v2(64.62,85.26)
DDR_B_BS0: length 69
  IN2 w0.18: v2(60.05,72.93) 60.05,72.94 59.94,73.05 59.94,73.78 60.18,74.02 65.26,74.02 65.44,74.2 66.44,74.2 66.84,74.6 81.55,74.6 81.7,74.75 81.7,75.47 81.88,75.66 82.26,75.66 82.44,75.48 82.44,74.78 82.62,74.6 82.93,74.6 83.11,74.78 83.11,75.01 83.21,75.11 83.56,75.11 83.94,74.73 84.2,74.73 84.49,75.02 84.49,75.18 83.94,75.73 83.94,75.92 84.2,76.17 84.45,76.17 84.92,75.7 85.17,75.7 85.43,75.96 85.43,76.22 84.96,76.68 84.96,76.94 85.22,77.19 85.47,77.19 85.94,76.73 86.19,76.73 86.45,76.98 86.45,77.24 85.98,77.7 85.98,77.96 86.25,78.23 86.46,78.23 86.97,77.72 87.19,77.72 94.55,85.08 106.91,85.08 v2(107.17,85.34)
  BOTTOM w0.076: v2(107.17,85.34) v1(107.88,84.63) 107.94,84.57 112.5,84.57 112.67,84.4 113.86,84.4 UC1.BB44
  BOTTOM w0.163: v2(60.05,72.93) 59.99,72.99 JDIMM2.150
DDR_B_BS1: length 70
  IN2 w0.18: v2(108.34,85.32) 108.34,85.37 107.94,85.78 106.76,85.78 106.52,85.54 94.36,85.54 89.27,80.45 89.06,80.45 88.58,80.93 88.3,80.93 88.08,80.71 88.08,80.46 88.55,79.99 88.55,79.73 88.3,79.48 88.04,79.48 87.57,79.95 87.32,79.95 87.09,79.72 87.09,79.46 87.56,78.99 87.56,78.74 87.3,78.48 87.05,78.48 86.58,78.95 86.33,78.95 83.49,76.12 81.69,76.12 81.24,75.66 81.24,75.21 81.08,75.06 78.33,75.06 77.66,75.73 72.31,75.73 71.75,75.17 66.76,75.17 66.25,74.66 64.8,74.66 v2(64.62,74.49)
  BOTTOM w0.076: v2(108.34,85.32) 108.53,85.13 108.53,85.13 108.93,84.74 112.57,84.74 112.7,84.61 114.07,84.61 114.34,84.34 UC1.BA44
  BOTTOM w0.163: v2(64.62,74.49) 64.48,74.49 64.04,74.92 61.42,74.92 61.26,75.09 61.26,75.45 61.37,75.57 65.1,75.57 65.36,75.3 65.36,74.48 65.6,74.24 66.45,74.24 JDIMM2.145
DDR_B_CAS#: length 70.3
  IN2 w0.18: v2(60.05,71.87) 60.05,72.37 59.93,72.5 58.67,72.5 58.5,72.32 58.5,71.37 58.67,71.19 60.24,71.19 60.51,70.92 60.51,70.4 60.64,70.27 66.21,70.27 66.32,70.16 69.88,70.16 70.34,69.7 72,69.7 72.49,69.21 77.51,69.21 78.13,69.83 86.64,69.83 98.22,81.4 101.06,81.4 101.33,81.67 109.4,81.67 110.71,82.98 v2(110.71,83.65)
  BOTTOM w0.076: v2(110.71,83.65) 110.71,83.7 v1(111.12,84.1) 111.26,84.24 112.36,84.24 112.53,84.07 113.53,84.07 113.69,83.91 114.06,83.91 114.17,83.96 114.29,83.96 114.51,83.89 114.65,83.89 114.81,83.95 115,83.95 115.15,83.87 115.25,83.87 UC1.AY43
  BOTTOM w0.163: JDIMM2.156 59.63,71.49 60.01,71.87 v2(60.05,71.87)
DDR_B_CKE0: length 66.8
  IN2 w0.076: v2(120.08,91.96) 119.54,92.5 117.56,92.5 117.29,92.77 113.97,92.77 113.56,93.18 112.71,93.18 110.99,94.91 104.54,94.91 104.24,95.21
  IN2 w0.18: 104.24,95.21 102.33,97.12 88.26,97.12 84.8,93.67 79.76,93.67 78.48,92.39 71.94,92.39 69.31,89.76 66.9,89.76 65.43,88.3 64.59,88.3 63.86,87.57 v2(63.86,87.56)
  BOTTOM w0.076: UC1.AN56 v2(120.08,91.96)
  BOTTOM w0.163: JDIMM2.109 65.61,85.24 63.86,86.99 v2(63.86,87.56)
DDR_B_CKE1: length 68.7
  IN2 w0.076: v2(118.62,91.07) 118.55,91.07 118.1,91.51 114.84,91.51 113.51,92.85 112.6,92.85 110.76,94.68 104.13,94.68 103.59,95.21
  IN2 w0.18: v2(60.05,85.26) 60.05,86.22 60.92,87.1 64.88,87.1 67.09,89.3 69.5,89.3 72.13,91.93 78.67,91.93 79.95,93.21 84.99,93.21 88.45,96.66 102.14,96.66 103.59,95.21
  BOTTOM w0.076: v2(118.62,91.07) 118.62,90.97 UC1.AP55
  BOTTOM w0.163: JDIMM2.110 59.26,84.99 59.31,84.94 59.73,84.94 v2(60.05,85.26)
DDR_B_CKE2: length 1.2
  TOP w0.163: TP5.1 v2(119.2,91.04)
  BOTTOM w0.076: v2(119.2,91.04) 119.22,91.04 119.3,90.96 119.3,90.94 UC1.AN55
DDR_B_CKE3: length 1.1
  TOP w0.163: TP6.1 v2(118.65,90.14)
  BOTTOM w0.076: UC1.AP53 v2(118.65,90.14)
DDR_B_CLK0: length 71.4
  IN2 w0.076: v2(118.71,85.51) 118.71,85.53 118.93,85.74 118.93,85.84 118.85,85.92 116.39,85.92 116.26,86.05 116.26,86.22 116.12,86.36 115.9,86.36 115.8,86.26 115.8,85.95 115.81,85.95
  IN2 w0.168: 115.81,85.95 115.81,85.53 115.5,85.23 114.88,85.23 114.63,85.47 114.63,86.11 114.48,86.27 114.13,86.27 113.98,86.12 113.98,84.93 113.63,84.59 112.31,84.59 111.96,84.94 111.96,87.1 111.46,87.6 93.5,87.6 88.9,82.99 87.36,82.99 83.98,79.61 81.71,79.61 81.25,79.14 78.1,79.14 77.56,78.61 71.65,78.61 70.28,77.23 65.9,77.23 65.46,76.78 63.82,76.78 63.54,77.07 63.24,77.37 v2(63.1,77.37)
  BOTTOM w0.076: v2(118.71,85.51) 118.98,85.24 UC1.AP45
  BOTTOM w0.102: v2(63.1,77.37) 63.31,77.58 63.31,77.96 63.63,78.28 64.88,78.28 64.92,78.24 JDIMM2.137
DDR_B_CLK1: length 70.4
  IN2 w0.076: 103.52,88.61 103.92,89.01 104.47,89.01 105.13,88.35 111.22,88.35 111.39,88.51 111.39,89.09 111.46,89.16 111.7,89.16 111.78,89.08 111.78,88.29 113.22,86.84 116.59,86.84 116.59,86.85 118.24,86.85 118.3,86.91 118.85,86.91 118.9,86.87 118.9,86.61 118.78,86.5 v2(118.66,86.5)
  IN2 w0.168: v2(61.57,77.37) 61.43,77.37 61.25,77.55 61.25,77.89 61.42,78.06 69.93,78.06 71.87,80 80.93,80 81.37,80.44 83.63,80.44 87.01,83.82 88.55,83.82 93.24,88.51 103.42,88.51 103.52,88.61
  BOTTOM w0.076: v2(118.66,86.5) 118.98,86.17 UC1.AP46
  BOTTOM w0.15: v2(61.57,77.37) 61.48,77.37 61.2,77.66 61.2,77.81 60.88,78.13 59.79,78.13 59.52,77.86 59.17,77.86 59.04,77.99 JDIMM2.138
DDR_B_CLK#0: length 71.3
  IN2 w0.076: 115.55,85.95 115.55,86.03 115.64,86.12 115.64,86.33 115.83,86.52 116.19,86.52 116.42,86.29 116.42,86.12 116.46,86.09 118.92,86.09 119.09,85.91 119.09,85.74 v2(119.3,85.53)
  IN2 w0.168: v2(63.86,77.37) 63.8,77.31 63.8,77.17 63.93,77.04 65.35,77.04 65.8,77.49 70.17,77.49 70.41,77.73 71.54,78.86 77.46,78.86 77.99,79.4 81.14,79.4 81.61,79.86 83.87,79.86 87.25,83.25 88.79,83.25 93.39,87.85 111.57,87.85 112.21,87.21 112.21,85.04 112.41,84.84 113.53,84.84 113.72,85.04 113.72,86.22 114.02,86.53 114.58,86.53 114.89,86.22 114.89,85.58 114.99,85.48 115.39,85.48 115.55,85.64 115.55,85.95
  BOTTOM w0.076: UC1.AN45 119.35,85.11 119.24,85.22 119.24,85.47 v2(119.3,85.53)
  BOTTOM w0.102: v2(63.86,77.37) 63.79,77.3 63.65,77.3 63.5,77.45 63.5,77.88 63.7,78.09 64.8,78.09 64.84,78.05 65.39,78.05 65.46,77.97 65.46,77.81 65.54,77.74 JDIMM2.139
DDR_B_CLK#1: length 70.5
  IN2 w0.076: v2(119.24,86.48) 119.06,86.67 119.06,86.94 118.92,87.08 118.24,87.08 118.17,87.01 116.53,87.01 116.52,87.01 113.29,87.01 111.95,88.35 111.95,89.15 111.77,89.33 111.4,89.33 111.22,89.15 111.22,88.58 111.15,88.51 105.2,88.51 104.54,89.17 103.85,89.17 103.5,88.82 103.37,88.82
  IN2 w0.168: 103.37,88.82 103.31,88.77 93.13,88.77 88.44,84.08 86.91,84.08 83.52,80.7 81.26,80.7 80.82,80.25 71.76,80.25 69.83,78.32 61.31,78.32 60.99,78 60.99,77.66 v2(60.71,77.37)
  BOTTOM w0.076: UC1.AN46 119.64,86.09 v2(119.24,86.48)
  BOTTOM w0.15: JDIMM2.140 59.11,77.49 59.24,77.62 59.62,77.62 59.89,77.89 60.78,77.89 60.96,77.71 60.96,77.56 60.77,77.37 v2(60.71,77.37)
DDR_B_CS#0: length 68
  IN2 w0.076: v2(108.28,83.35) 108.34,83.35 108.51,83.51 108.51,84.07 108.44,84.13 106.42,84.13 105.76,83.47 105.62,83.47
  IN2 w0.18: 105.62,83.47 97.36,83.47 90.26,76.37 88.12,76.37 84.74,72.99 83.73,72.99 83.55,72.81 83.55,72.05 83.4,71.89 83.03,71.89 82.83,72.1 82.83,72.81 82.65,72.99 82.29,72.99 82.11,72.81 82.11,72.05 81.95,71.89 81.59,71.89 81.39,72.1 81.39,72.81 81.21,72.99 80.85,72.99 80.67,72.81 80.67,72.05 80.51,71.89 80.15,71.89 79.94,72.1 79.94,72.81 79.76,72.99 79.4,72.99 79.22,72.81 79.22,72.05 79.07,71.89 78.71,71.89 78.5,72.1 78.5,72.6 78.33,72.76 70.17,72.76 69.84,72.44 66.02,72.44 65.92,72.33 63.27,72.33 63.1,72.5 v2(63.1,72.93)
  BOTTOM w0.076: UC1.BB42 113.86,82.96 112.98,82.96 112.77,83.18 112.17,83.18 112.09,83.1 108.52,83.1 v2(108.28,83.35)
  BOTTOM w0.163: JDIMM2.149 65.4,73.24 65.16,73.48 63.66,73.48 v2(63.1,72.93)
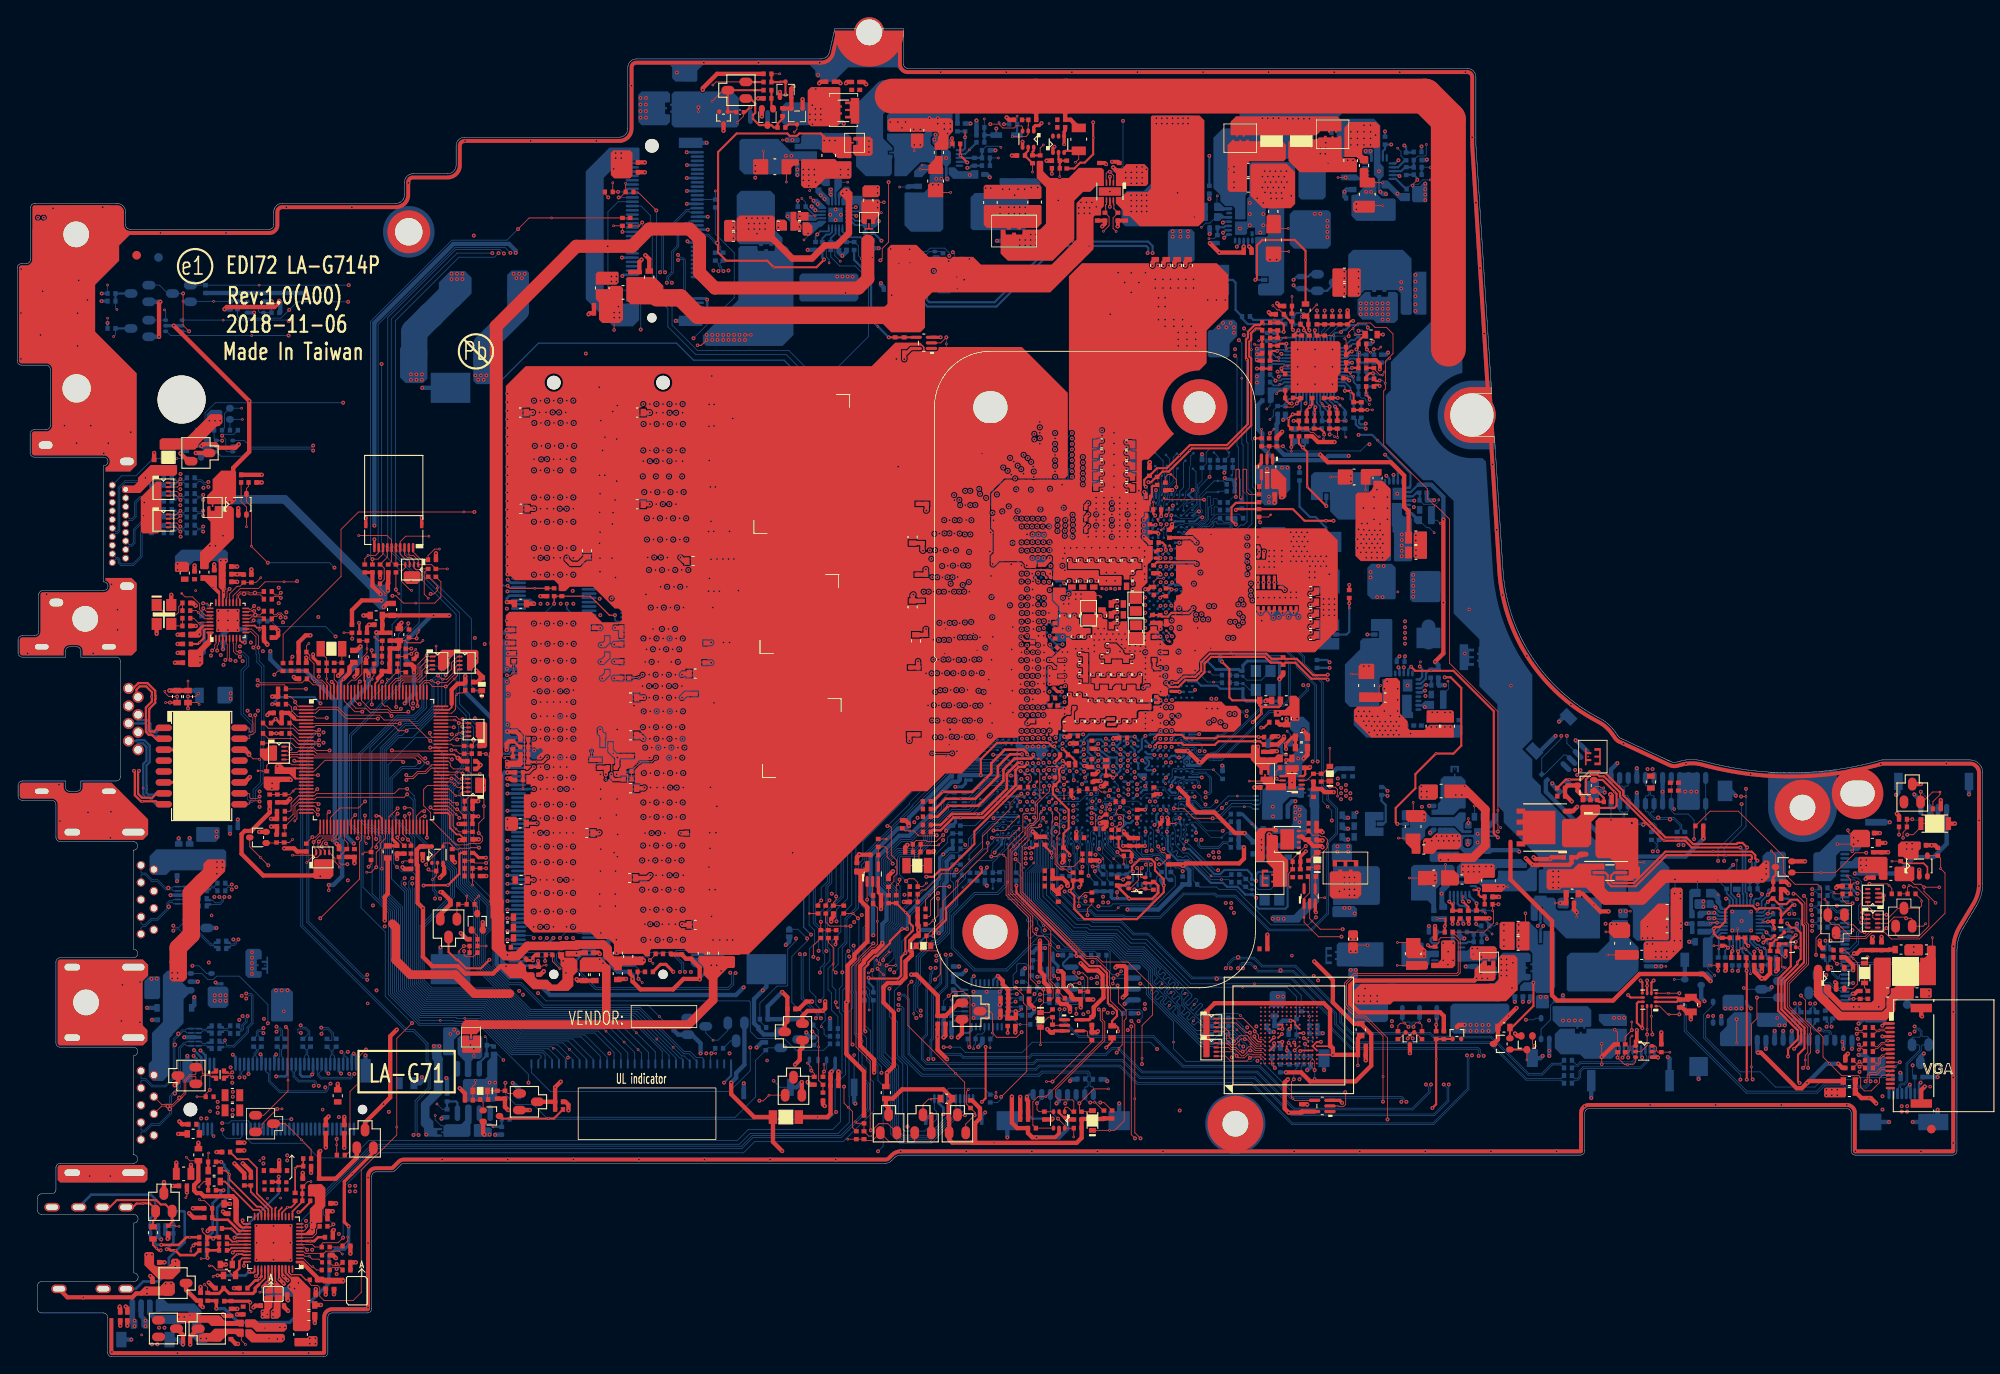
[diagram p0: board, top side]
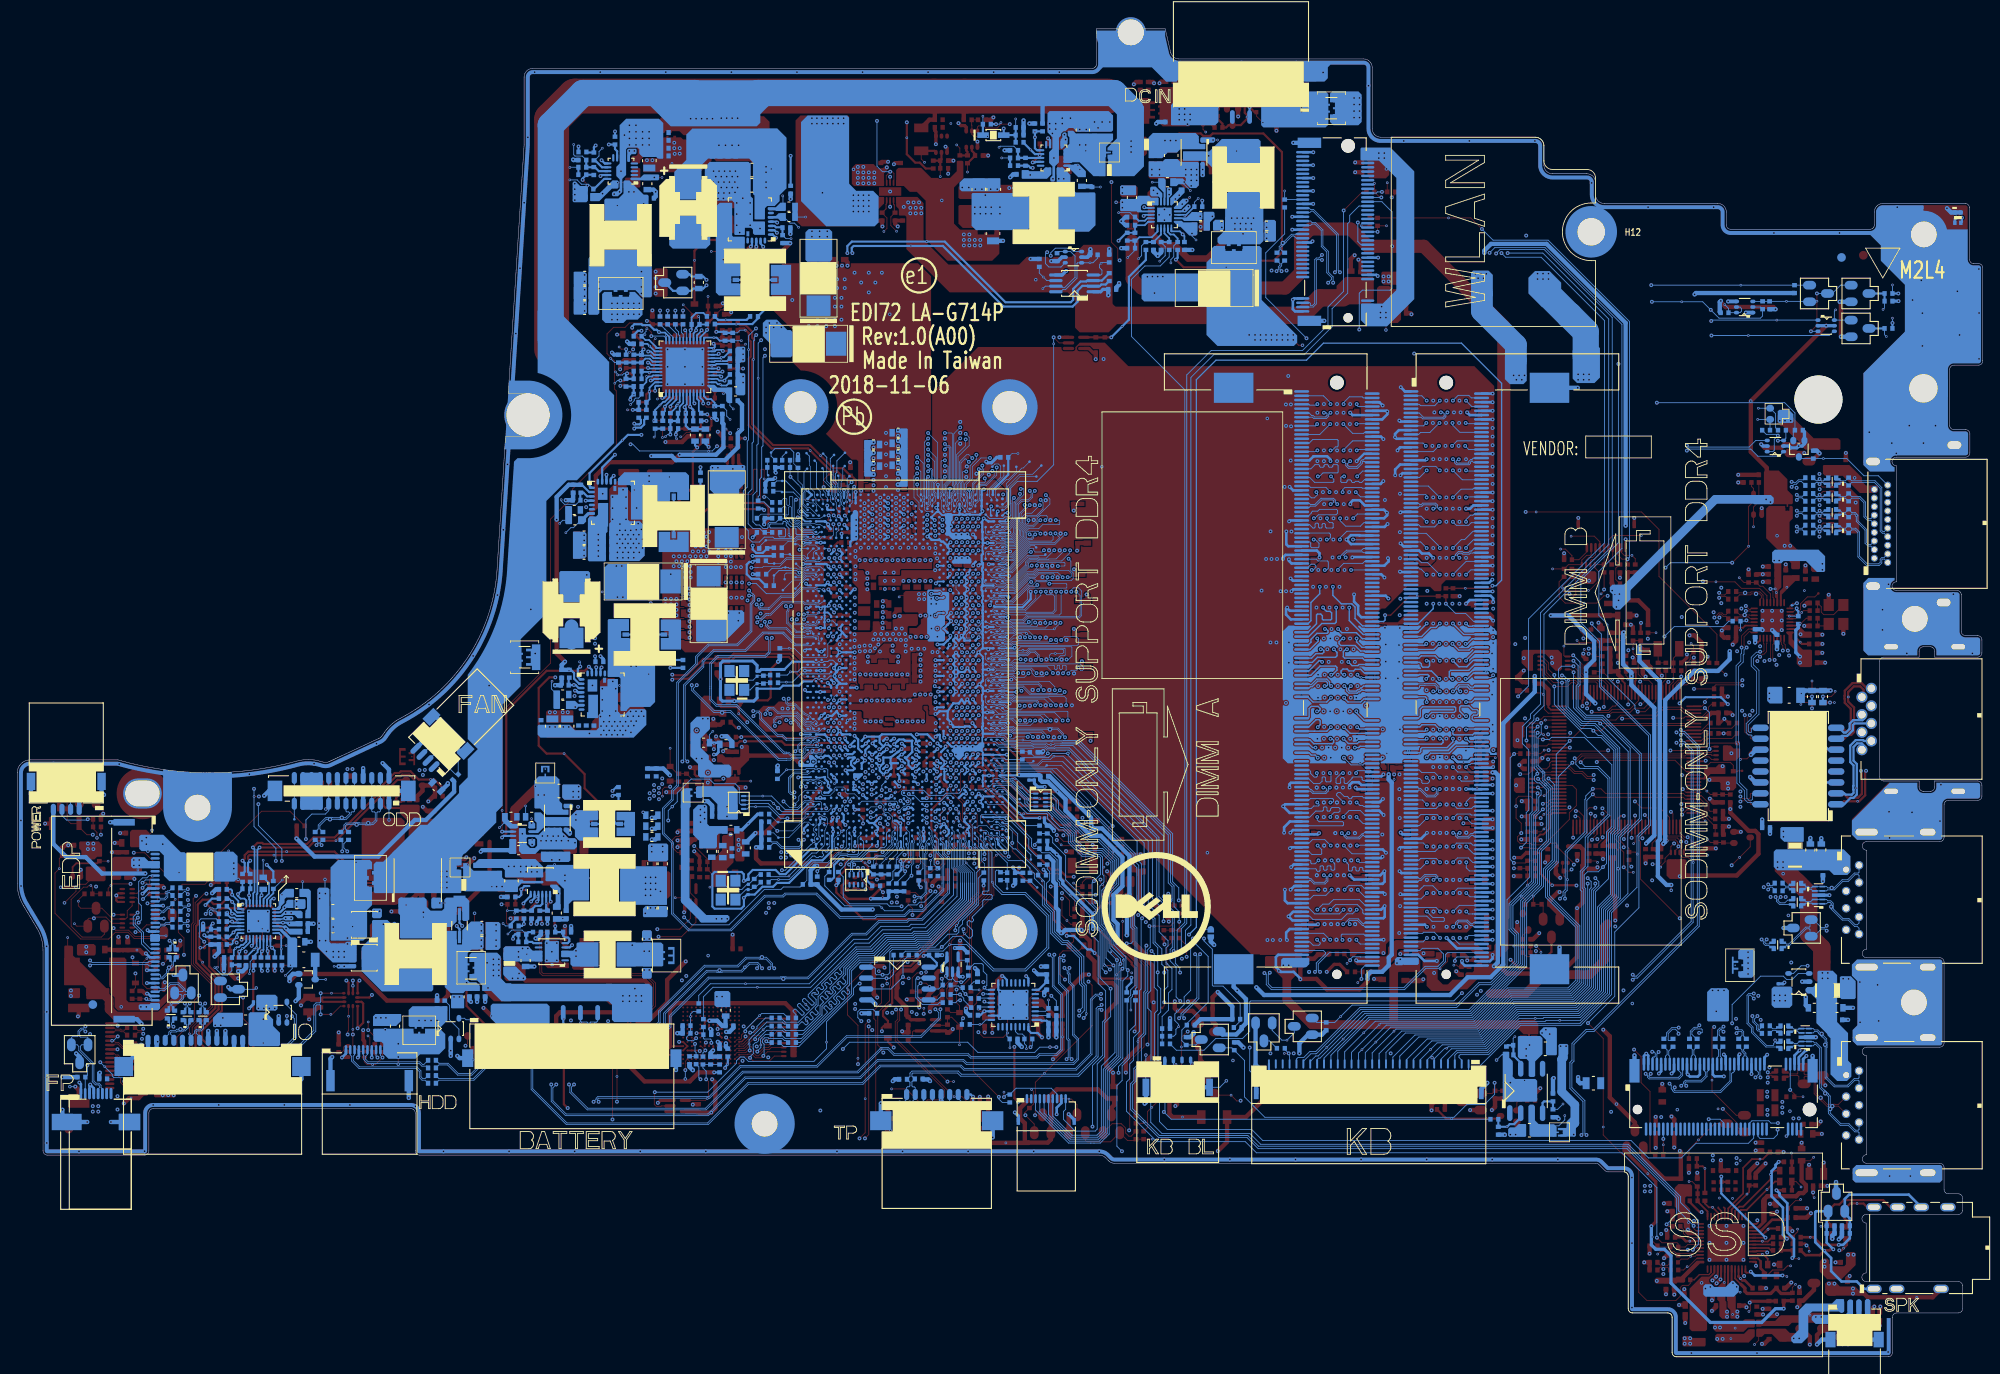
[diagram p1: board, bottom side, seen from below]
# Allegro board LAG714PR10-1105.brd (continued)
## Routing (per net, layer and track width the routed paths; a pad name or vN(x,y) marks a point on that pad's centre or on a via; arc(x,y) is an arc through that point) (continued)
DDR_B_CS#1: length 70.6
  IN2 w0.18: v2(107.09,83.34) 107.12,83.34 107.48,82.97 107.48,82.73 107.29,82.55 97.74,82.55 86.16,70.97 78.03,70.97 77.7,71.31 72.61,71.31 72.49,71.18 72.49,70.98 72.35,70.85 72.05,70.85 71.87,71.03 71.87,71.66 71.69,71.84 71.33,71.84 71.15,71.66 71.15,71.03 70.97,70.85 70.81,70.85 70.35,71.31 66.8,71.31 66.69,71.41 63.2,71.41 63.1,71.51 v2(63.1,71.87)
  BOTTOM w0.076: v2(107.09,83.34) 106.68,83.75 105.32,83.75 105.06,83.5 105.06,82.86 105.21,82.72 112.25,82.72 112.35,82.82 112.66,82.82 112.85,82.63 113.52,82.63 113.57,82.58 114.06,82.58 114.09,82.6 114.47,82.75 114.95,82.75 UC1.AY42
  BOTTOM w0.163: v2(63.1,71.87) 62.93,71.87 62.72,71.66 62.72,71.42 62.9,71.24 JDIMM2.157
DDR_B_D0: length 77.4
  IN2 w0.076: v2(122.67,96.72) 123.17,97.22 123.17,99.09 119.93,102.33 119.93,103.34
  IN2 w0.18: v2(60.15,105.91) 61.39,107.15 65.25,107.15 70.17,112.07 81.68,112.07 81.79,111.96 106.85,111.96 111.61,107.19 117.03,107.19 119.93,104.3 119.93,103.34
  BOTTOM w0.076: UC1.AF65 122.93,96.35 v2(122.67,96.72)
  BOTTOM w0.102: v2(60.15,105.91) 59.73,105.49 JDIMM2.28
DDR_B_D1: length 75.6
  IN2 w0.076: 118.74,103.34 118.74,101.64 120.57,99.81 121.15,99.81 122.16,98.8 122.16,96.58 v2(122.66,96.08)
  IN2 w0.18: 118.74,103.34 118.74,103.8 116.54,106 111.12,106 106.35,110.77 92.49,110.77 92.38,110.65 92.38,110.45 92.19,110.26 91.83,110.26 91.65,110.44 91.65,110.59 91.47,110.77 91.11,110.77 90.93,110.59 90.93,110.44 90.75,110.26 90.39,110.26 90.21,110.44 90.21,110.59 90.03,110.77 89.67,110.77 89.48,110.59 89.48,110.44 89.3,110.26 88.85,110.26 88.67,110.44 88.67,110.59 88.49,110.77 88.13,110.77 87.95,110.59 87.95,110.44 87.77,110.26 87.41,110.26 87.23,110.44 87.23,110.59 87.05,110.77 86.69,110.77 86.5,110.59 86.5,110.44 86.32,110.26 85.96,110.26 85.78,110.44 85.78,110.59 85.6,110.77 85.24,110.77 85.06,110.59 85.06,110.44 84.88,110.26 84.52,110.26 84.34,110.44 84.34,110.59 84.16,110.77 83.8,110.77 83.62,110.59 83.62,110.44 83.44,110.26 72.79,110.26 72.61,110.08 72.61,109.91 72.43,109.73 72.07,109.73 71.89,109.91 71.89,110.08 71.71,110.26 71.3,110.26 71.14,110.09 71.14,109.84 71.02,109.72 70.77,109.72 68.41,107.37 67.15,107.37 65.7,105.91 v2(64.72,105.91)
  BOTTOM w0.076: UC1.AF64 122.91,95.71 v2(122.66,96.08)
  BOTTOM w0.102: v2(64.72,105.91) 65.05,106.24 JDIMM2.25
DDR_B_D2: length 75.8
  IN2 w0.076: 115.06,101.05 115.06,100.83 115.72,100.17 116.59,100.17 117.53,99.24 118.93,99.24 120.35,97.83 120.35,96.87 120.51,96.7 120.51,96.38 v2(120.88,96.01)
  IN2 w0.18: 115.06,101.05 115.06,101.54 113.16,103.44 110.53,103.44 108.49,105.49 105.93,108.05 86.6,108.05 86.46,107.91 86.46,107.36 86.31,107.21 85.95,107.21 85.77,107.39 85.77,107.87 85.59,108.05 85.23,108.05 85.05,107.87 85.05,107.39 84.87,107.21 84.51,107.21 84.33,107.39 84.33,107.87 84.15,108.05 83.79,108.05 83.61,107.87 83.61,107.39 83.43,107.21 71.91,107.21 68.63,103.93 66.84,103.93 65.06,102.14 61.72,102.14 61.57,102.29 v2(61.57,103.07)
  BOTTOM w0.076: v2(120.88,96.01) 121.18,96.32 UC1.AK65
  BOTTOM w0.102: v2(61.57,103.07) 60.48,101.97 58.82,101.97 58.8,101.99 JDIMM2.42
DDR_B_D3: length 76.8
  IN2 w0.076: 114.66,101.05 114.66,100.77 115.51,99.92 116.33,99.92 117.18,99.07 118.87,99.07 120.18,97.76 120.18,96.8 120.35,96.63 120.35,96.02 120.91,95.46 v2(121.72,95.46)
  IN2 w0.18: v2(60.05,103.07) 60.05,102.01 60.31,101.74 65.22,101.74 67,103.53 68.79,103.53 72.08,106.82 86.68,106.82 86.86,107 86.86,107.47 87.04,107.65 87.4,107.65 87.58,107.47 87.58,107 87.76,106.82 88.12,106.82 88.3,107 88.3,107.47 88.48,107.65 88.84,107.65 89.02,107.47 89.02,107 89.2,106.82 89.56,106.82 89.72,106.98 89.72,107.48 89.9,107.65 105.76,107.65 108.32,105.09 110.37,103.05 112.99,103.05 114.66,101.38 114.66,101.05
  BOTTOM w0.076: UC1.AK64 121.51,95.67 v2(121.72,95.46)
  BOTTOM w0.102: v2(60.05,103.07) 59.97,102.99 JDIMM2.38
DDR_B_D4: length 76.9
  IN2 w0.076: 119.53,103.34 119.53,102.4 123,98.94 123,97.65 v2(122.66,97.32)
  IN2 w0.18: 119.53,103.34 119.53,104.13 116.87,106.8 111.45,106.8 106.68,111.56 81.63,111.56 81.52,111.67 70.82,111.67 70.18,111.03 70.18,110.25 68.08,108.16 66.83,108.16 65.42,106.75 61.83,106.75 61.67,106.59 v2(61.67,105.91)
  BOTTOM w0.076: UC1.AF66 123.08,97 122.76,97.32 v2(122.66,97.32)
  BOTTOM w0.102: v2(61.67,105.91) 61.09,106.49 JDIMM2.24
DDR_B_D5: length 75.7
  IN2 w0.076: 119.13,103.34 119.13,102.39 122.63,98.9 v2(122.63,97.9)
  IN2 w0.18: 119.13,103.34 119.13,103.97 116.7,106.4 111.28,106.4 106.52,111.16 82.88,111.16 82.7,110.98 82.7,110.84 82.52,110.66 82.16,110.66 81.98,110.84 81.98,110.98 81.8,111.16 81.46,111.16 81.35,111.27 80.14,111.27 79.96,111.09 79.96,110.84 79.78,110.66 79.41,110.66 79.23,110.84 79.23,111.09 79.05,111.27 78.64,111.27 78.48,111.12 78.48,110.86 78.3,110.68 77.94,110.68 77.76,110.86 77.76,111.12 77.6,111.27 70.98,111.27 70.57,110.87 70.57,110.09 68.25,107.76 66.99,107.76 65.58,106.35 63.31,106.35 63.2,106.24 v2(63.2,105.91)
  BOTTOM w0.076: v2(122.63,97.9) 122.8,97.9 UC1.AF67
  BOTTOM w0.102: v2(63.2,105.91) 63.86,105.24 JDIMM2.29
DDR_B_D6: length 74.5
  IN2 w0.076: 117.22,101.05 117.22,100.85 118.39,99.68 118.96,99.68 120.88,97.76 v2(120.88,97.32)
  IN2 w0.18: v2(64.62,103.07) 64.59,103.09 64.18,103.09 64.06,103.21 64.06,103.59 64.2,103.73 65.53,103.73 66.51,104.72 66.79,104.72 66.9,104.83 66.9,105.11 67.06,105.27 67.36,105.27 67.56,105.07 67.56,104.83 67.68,104.72 68.3,104.72 71.58,108 78.64,108 78.82,108.19 78.82,108.7 78.96,108.84 93,108.84 93.18,109.02 93.18,109.17 93.36,109.35 93.72,109.35 93.9,109.17 93.9,109.02 94.08,108.84 94.44,108.84 94.62,109.02 94.62,109.17 94.8,109.35 95.16,109.35 95.34,109.17 95.34,109.02 95.52,108.84 95.89,108.84 96.07,109.02 96.07,109.17 96.25,109.35 96.61,109.35 96.79,109.17 96.79,109.02 96.97,108.84 97.29,108.84 97.47,109.02 97.47,109.17 97.65,109.35 98.01,109.35 98.19,109.17 98.19,109.02 98.37,108.84 98.73,108.84 98.91,109.02 98.91,109.17 99.09,109.35 99.45,109.35 99.63,109.17 99.63,109.02 99.81,108.84 100.17,108.84 100.35,109.02 100.35,109.17 100.53,109.35 100.89,109.35 101.07,109.17 101.07,109.02 101.26,108.84 101.62,108.84 101.8,109.02 101.8,109.17 101.98,109.35 102.34,109.35 102.52,109.17 102.52,109.02 102.7,108.84 103.06,108.84 103.24,109.02 103.24,109.17 103.42,109.35 103.78,109.35 103.96,109.17 103.96,109.02 104.14,108.84 104.5,108.84 104.68,109.02 104.68,109.17 104.86,109.35 105.22,109.35 105.4,109.17 105.4,109.02 105.58,108.84 106.25,108.84 110.86,104.23 113.49,104.23 113.87,103.85 114.88,103.85 116.59,102.13 116.59,101.68 117.22,101.05
  BOTTOM w0.076: UC1.AK67 121.18,97.62 v2(120.88,97.32)
  BOTTOM w0.102: JDIMM2.41 66.45,102.24 65.45,102.24 v2(64.62,103.07)
DDR_B_D7: length 75
  IN2 w0.076: v2(120.88,96.65) 120.79,96.65 120.51,96.94 120.51,97.89 118.89,99.52 118.02,99.52 116.49,101.05
  IN2 w0.18: 116.49,101.05 116.25,101.28 115.87,101.28 113.32,103.84 110.7,103.84 106.09,108.45 83.34,108.45 83.21,108.32 83.21,107.79 83.03,107.61 83.03,107.61 82.67,107.61 82.5,107.78 82.5,108.25 82.32,108.43 81.96,108.43 81.78,108.25 81.78,107.78 81.61,107.61 80.14,107.61 79.94,107.81 79.94,108.16 79.75,108.35 79.39,108.35 79.22,108.17 79.22,107.81 79.01,107.61 71.75,107.61 68.46,104.32 66.68,104.32 64.89,102.54 63.8,102.54 63.66,102.67 63.66,103.77 63.51,103.92 62.87,103.92 62.76,103.81 62.76,103.2 62.9,103.07 v2(63.1,103.07)
  BOTTOM w0.076: UC1.AK66 121.25,96.92 v2(120.88,96.65)
  BOTTOM w0.102: JDIMM2.37 65.35,103.24 65.06,103.53 63.56,103.53 v2(63.1,103.07)
DDR_B_D8: length 84.9
  IN2 w0.18: v2(123.83,101.44) 125.61,103.22 125.61,108.76 116.85,117.52 110.14,117.52 109.71,117.09 100.19,117.09 99.57,117.71 77.59,117.71 77.1,118.2 68.91,118.2 62.82,112.12 61,112.12 v2(60.05,111.17)
  BOTTOM w0.076: v2(123.83,101.44) 123.83,100.22 123.39,99.79 UC1.AF70
  BOTTOM w0.102: v2(60.05,111.17) 59.37,110.49 JDIMM2.8
DDR_B_D9: length 87
  IN2 w0.18: v2(61.57,111.17) 62.13,111.72 62.99,111.72 69.07,117.81 76.93,117.81 77.43,117.31 89.2,117.31 89.38,117.13 89.38,116.87 89.56,116.69 89.92,116.69 90.1,116.87 90.1,117.13 90.28,117.31 99.41,117.31 100.03,116.69 109.87,116.69 110.3,117.12 116.69,117.12 125.21,108.6 125.21,103.2 124.72,102.71 v2(123.83,102.71)
  BOTTOM w0.076: UC1.AF68 123.61,98.59 123.61,99.33 124.2,99.91 124.2,102.34 v2(123.83,102.71)
  BOTTOM w0.102: JDIMM2.4 59.43,111.49 59.72,111.78 60.96,111.78 v2(61.57,111.17)
DDR_B_D10: length 84.2
  IN2 w0.18: v2(63.14,108.58) 63.14,109.1 63.4,109.36 64.89,109.36 71.12,115.6 76.02,115.6 77.13,114.48 77.9,114.48 78.08,114.3 78.08,114.08 78.26,113.9 78.62,113.9 78.8,114.08 78.8,114.3 78.98,114.48 79.37,114.48 79.55,114.3 79.55,114.08 79.73,113.9 80.09,113.9 80.27,114.08 80.27,114.3 80.45,114.48 100.49,114.48 101.24,113.73 104.01,113.73 104.76,114.48 105.9,114.48 106.08,114.3 106.08,113.91 106.26,113.73 106.62,113.73 106.8,113.91 106.8,114.3 106.98,114.48 107.34,114.48 107.52,114.3 107.52,113.91 107.7,113.73 108.06,113.73 108.24,113.91 108.24,114.3 108.42,114.48 108.78,114.48 108.96,114.3 108.96,113.91 109.14,113.73 109.5,113.73 109.68,113.91 109.68,114.3 109.86,114.48 110.79,114.48 111.22,114.91 115.68,114.91 123,107.59 123,105.04 122.82,104.86 v2(122.56,104.86)
  BOTTOM w0.076: v2(122.56,104.86) 121.79,104.1 121.79,102.05 122.12,101.72 122.12,100.27 UC1.AH71
  BOTTOM w0.102: JDIMM2.21 65.56,107.24 65.32,107.47 64.24,107.47 v2(63.14,108.58)
DDR_B_D11: length 86.9
  IN2 w0.18: v2(122.56,106.77) 115.31,114.02 111.45,114.02 110.37,112.94 100.21,112.94 100.03,113.12 100.03,113.52 99.86,113.69 99.5,113.69 99.31,113.5 99.31,113.12 99.13,112.94 98.77,112.94 98.59,113.12 98.59,113.52 98.42,113.69 98.06,113.69 97.87,113.5 97.87,113.12 97.68,112.94 97.32,112.94 97.14,113.12 97.14,113.52 96.97,113.69 96.61,113.69 96.42,113.5 96.42,113.12 96.24,112.94 95.88,112.94 95.7,113.12 95.7,113.52 95.53,113.69 95.17,113.69 94.98,113.5 94.98,113.12 94.8,112.94 94.49,112.94 94.31,113.12 94.31,113.51 94.13,113.69 93.77,113.69 93.59,113.51 93.59,113.12 93.41,112.94 82.2,112.94 82.09,113.05 77.44,113.05 75.69,114.8 71.52,114.8 64.85,108.13 62.06,108.13 v2(61.61,108.58)
  BOTTOM w0.076: UC1.AH68 122.75,98.27 122.95,98.46 122.95,98.72 122.96,98.73 122.96,98.99 122.98,99 122.98,99.05 123,99.07 123,99.34 122.95,99.46 122.95,99.69 122.96,99.7 122.96,99.71 122.96,99.71 123,99.8 123,100 122.96,100.09 122.96,100.09 122.96,106.37 v2(122.56,106.77)
  BOTTOM w0.102: JDIMM2.20 60.76,107.49 61.61,108.34 v2(61.61,108.58)
DDR_B_D12: length 84.6
  IN2 w0.18: v2(123.83,103.34) 124.82,104.33 124.82,108.43 116.52,116.73 110.47,116.73 110.04,116.3 104.01,116.3 103.26,115.55 102,115.55 101.25,116.3 99.86,116.3 99.24,116.92 95.33,116.92 95.12,116.7 95.12,116.44 94.97,116.3 94.54,116.3 94.36,116.48 94.36,116.74 94.18,116.92 93.82,116.92 93.64,116.74 93.64,116.48 93.46,116.3 93.09,116.3 92.91,116.48 92.91,116.74 92.73,116.92 92.37,116.92 92.19,116.74 92.19,116.48 92.01,116.3 91.65,116.3 91.47,116.48 91.47,116.74 91.29,116.92 90.93,116.92 90.75,116.74 90.75,116.48 90.57,116.3 77.88,116.3 76.77,117.41 69.34,117.41 v2(63.1,111.17)
  BOTTOM w0.076: UC1.AF71 123.39,102.93 123.42,102.93 v2(123.83,103.34)
  BOTTOM w0.102: JDIMM2.7 65.47,110.74 65.32,110.59 63.68,110.59 v2(63.1,111.17)
DDR_B_D13: length 85.7
  IN2 w0.18: v2(64.62,111.17) 65.17,111.72 65.17,111.88 64.9,112.15 64.9,112.42 65.16,112.67 65.42,112.67 65.7,112.39 65.91,112.39 66.19,112.67 66.19,112.96 65.91,113.24 65.91,113.42 67.43,114.94 67.69,114.94 67.94,114.69 68.21,114.69 68.47,114.95 68.47,115.2 68.21,115.46 68.21,115.72 68.46,115.97 68.72,115.97 68.98,115.71 69.23,115.71 69.45,115.93 69.45,116.19 69.17,116.46 69.17,116.69 69.45,116.96 69.69,116.96 69.96,116.7 70.21,116.7 70.53,117.01 76.61,117.01 77.72,115.9 95.32,115.9 95.5,116.08 95.5,116.34 95.68,116.52 96.04,116.52 96.22,116.34 96.22,116.08 96.4,115.9 96.76,115.9 96.94,116.08 96.94,116.37 97.09,116.52 97.47,116.52 97.66,116.32 97.66,116.08 97.84,115.9 98.2,115.9 98.38,116.08 98.38,116.36 98.54,116.52 98.9,116.52 99.1,116.31 99.1,116.08 99.28,115.9 101.08,115.9 101.83,115.15 103.43,115.15 104.18,115.9 110.2,115.9 110.63,116.33 116.36,116.33 124.42,108.27 124.42,104.81 124.22,104.61 v2(123.83,104.61)
  BOTTOM w0.076: UC1.AF69 123.19,99.02 123.19,99.28 123.12,99.47 123.12,99.68 123.16,99.76 123.16,100.01 123.16,100.03 123.12,100.12 123.12,103.91 v2(123.83,104.61)
  BOTTOM w0.102: JDIMM2.3 65.19,111.74 v2(64.62,111.17)
DDR_B_D14: length 85.2
  IN2 w0.18: v2(122.56,105.5) 121.74,106.31 121.74,107.02 115.15,113.62 111.61,113.62 110.53,112.54 82.04,112.54 81.92,112.65 77.28,112.65 75.52,114.41 74.04,114.41 73.86,114.23 73.86,112.85 73.67,112.65 73.31,112.65 73.14,112.82 73.14,114.2 72.93,114.41 72.59,114.41 72.41,114.23 72.41,112.87 72.19,112.65 71.86,112.65 71.68,112.83 71.68,113.66 71.49,113.85 71.13,113.85 70.96,113.68 70.96,112.83 70.78,112.65 69.93,112.65 65.01,107.73 60.49,107.73 60.09,108.13 v2(60.09,108.58)
  BOTTOM w0.076: v2(122.56,105.5) 121.62,104.57 121.62,101.97 121.95,101.65 121.95,100.51 121.8,100.36 121.8,100.12 121.92,99.87 121.92,99.87 121.92,99.86 122.07,99.72 UC1.AH70
  BOTTOM w0.102: v2(60.09,108.58) 60,108.49 JDIMM2.16
DDR_B_D15: length 86.3
  IN2 w0.18: v2(122.56,107.4) 115.5,114.47 111.33,114.47 110.2,113.34 105.63,113.34 105.42,113.54 105.42,113.86 105.24,114.04 104.88,114.04 104.7,113.86 104.7,113.54 104.5,113.34 101.08,113.34 100.33,114.09 93.25,114.09 93.11,113.95 93.11,113.51 92.94,113.34 92.54,113.34 92.36,113.52 92.36,113.91 92.18,114.09 91.82,114.09 91.64,113.91 91.64,113.52 91.46,113.34 91.1,113.34 90.92,113.52 90.92,113.91 90.74,114.09 90.38,114.09 90.2,113.91 90.2,113.52 90.02,113.34 89.71,113.34 89.53,113.52 89.53,113.91 89.35,114.09 88.99,114.09 88.81,113.91 88.81,113.52 88.63,113.34 88.27,113.34 88.09,113.52 88.09,113.91 87.91,114.09 87.55,114.09 87.37,113.91 87.37,113.52 87.19,113.34 86.83,113.34 86.64,113.52 86.64,113.91 86.46,114.09 86.1,114.09 85.92,113.91 85.92,113.52 85.74,113.34 85.38,113.34 85.2,113.52 85.2,113.91 85.02,114.09 84.66,114.09 84.48,113.91 84.48,113.52 84.3,113.34 83.94,113.34 83.76,113.52 83.76,113.91 83.58,114.09 83.22,114.09 83.04,113.91 83.04,113.52 82.85,113.34 82.5,113.34 82.32,113.52 82.32,113.91 82.14,114.09 81.78,114.09 81.6,113.91 81.6,113.68 81.42,113.5 77.55,113.5 75.85,115.2 71.36,115.2 64.73,108.58 v2(64.66,108.58)
  BOTTOM w0.076: UC1.AH69 122.07,99.12 121.67,99.52 121.67,100 121.63,100.08 121.63,100.43 121.79,100.58 121.79,101.56 121.46,101.89 121.46,106.31 v2(122.56,107.4)
  BOTTOM w0.102: JDIMM2.17 65.99,108.24 65.99,108.24 65,108.24 v2(64.66,108.58)
DDR_B_D16: length 66.9
  IN2 w0.076: v2(117.34,97.46) 117.34,98.03 115.95,99.41 114.77,99.41 114.34,99.84 113.73,99.84 111.91,101.67 111.39,101.67
  IN2 w0.18: 111.39,101.67 109.8,101.67 105.19,106.27 92.4,106.27 92.22,106.09 92.22,105.61 92.05,105.44 91.67,105.44 91.5,105.6 91.5,106.08 91.32,106.26 90.96,106.26 90.78,106.08 90.78,105.6 90.61,105.44 78,105.44 77.15,104.58 72.05,104.58 70,102.53 69.74,102.53 68.87,101.65 67.08,101.65 65.79,100.37 63.54,100.37 v2(63.1,99.92)
  BOTTOM w0.076: v2(117.34,97.46) 117.68,97.11 UC1.AT66
  BOTTOM w0.102: v2(63.1,99.92) 64.42,101.24 JDIMM2.45
DDR_B_D17: length 65.9
  IN2 w0.076: 111.39,101.27 111.93,101.27 113.53,99.68 114.27,99.68 114.7,99.25 115.88,99.25 116.95,98.18 116.95,97.7 v2(116.71,97.46)
  IN2 w0.18: 111.39,101.27 109.63,101.27 105.03,105.88 97.08,105.88 96.9,105.7 96.9,105.23 96.71,105.04 96.41,105.04 96.22,105.22 96.22,105.7 96.04,105.88 95.68,105.88 95.5,105.7 95.5,105.22 95.32,105.04 94.96,105.04 94.78,105.22 94.78,105.7 94.6,105.88 94.24,105.88 94.06,105.7 94.06,105.22 93.88,105.04 93.52,105.04 93.34,105.22 93.34,105.7 93.16,105.88 92.8,105.88 92.62,105.7 92.62,105.22 92.44,105.04 78.17,105.04 77.77,104.64 77.77,103.95 77.45,103.64 72.11,103.64 69.73,101.26 67.24,101.26 65.91,99.92 v2(64.62,99.92)
  BOTTOM w0.076: v2(116.71,97.46) 117.03,97.14 UC1.AU66
  BOTTOM w0.102: JDIMM2.49 65.74,100.24 65.74,100.24 64.73,100.24 64.62,100.13 v2(64.62,99.92)
DDR_B_D18: length 69.6
  IN2 w0.076: v2(118.51,96.55) 118.87,96.91 119.3,96.91 119.52,96.69 119.52,96.39 119.12,95.98 117.16,95.98 117.02,95.84 114.57,95.84 113.53,96.88 113.13,96.88 111.86,98.16 108.45,98.16 107.24,99.37 107.24,99.91
  IN2 w0.18: v2(61.57,97.08) 62.14,96.52 66.9,96.52 67.33,96.94 68.5,96.94 68.87,97.3 69.59,97.3 70.72,98.43 72.07,98.43 73.23,99.58 77.11,99.58 78.53,101 79.77,101 80.36,101.59 81.34,101.59 81.95,102.19 104.97,102.19 107.24,99.93 107.24,99.91
  BOTTOM w0.076: UC1.AP65 118.9,96.09 118.52,96.47 118.52,96.55 v2(118.51,96.55)
  BOTTOM w0.102: v2(61.57,97.08) 61.17,96.68 59.74,96.68 59.44,96.98 58.85,96.98 58.84,96.99 JDIMM2.62
DDR_B_D19: length 69.8
  IN2 w0.076: v2(119.15,96.54) 119.15,96.37 118.93,96.15 117.09,96.15 116.95,96.01 115.54,96.01 113.69,97.86 113.69,98.28 113.3,98.67 112.18,98.67 111.83,98.32 108.52,98.32 107.64,99.21 107.64,99.91
  IN2 w0.18: v2(64.62,97.08) 64.79,96.91 66.74,96.91 67.16,97.34 68.34,97.34 68.7,97.7 69.42,97.7 70.55,98.82 71.91,98.82 72.42,99.33 72.42,100.72 72.82,101.12 78.09,101.12 78.36,101.4 79.61,101.4 80.19,101.98 81.18,101.98 81.78,102.59 99.82,102.59 100,102.77 100,103.5 100.17,103.67 100.53,103.67 100.73,103.47 100.73,102.77 100.91,102.59 101.27,102.59 101.45,102.77 101.45,103.5 101.62,103.67 101.98,103.67 102.17,103.47 102.17,102.77 102.35,102.59 102.71,102.59 102.89,102.77 102.89,103.5 103.06,103.67 103.42,103.67 103.61,103.47 103.61,102.77 103.79,102.59 105.14,102.59 107.64,100.09 107.64,99.91
  BOTTOM w0.076: UC1.AN65 119.6,96.09 v2(119.15,96.54)
  BOTTOM w0.102: v2(64.62,97.08) 65.28,97.74 JDIMM2.59
DDR_B_D20: length 69.1
  IN2 w0.076: 110.87,102.46 112.23,102.46 113.9,100.79 114.33,100.79 115.37,99.76 116.26,99.76 117.86,98.16 118.14,98.16 118.49,97.81 118.77,97.81 119.14,97.44 v2(119.26,97.44)
  IN2 w0.18: 110.87,102.46 110.13,102.46 108.08,104.51 105.52,107.07 90.64,107.07 89.81,106.23 72.32,106.23 69.03,102.94 67.25,102.94 65.46,101.16 60.44,101.16 60.05,100.77 v2(60.05,99.92)
  BOTTOM w0.076: v2(119.26,97.44) 119.64,97.07 UC1.AN66
  BOTTOM w0.102: JDIMM2.50 58.97,99.99 58.98,99.98 59.99,99.98 v2(60.05,99.92)
DDR_B_D21: length 68.4
  IN2 w0.076: 111.27,102.06 112.2,102.06 113.63,100.63 113.99,100.63 115.03,99.59 116.12,99.59 117.77,97.94 118.12,97.94 v2(118.62,97.44)
  IN2 w0.18: 111.27,102.06 109.96,102.06 105.35,106.67 90.81,106.67 89.97,105.83 72.48,105.83 68.7,102.05 66.92,102.05 65.63,100.76 61.67,100.76 61.57,100.66 v2(61.57,99.92)
  BOTTOM w0.076: UC1.AP66 v2(118.62,97.44)
  BOTTOM w0.102: JDIMM2.46 59.15,100.99 59.27,100.88 60.62,100.88 v2(61.57,99.92)
DDR_B_D22: length 68.3
  IN2 w0.076: 108.03,99.91 108.03,99.04 108.59,98.49 111.76,98.49 112.15,98.87 113.37,98.87 113.85,98.38 113.85,97.97 115.65,96.17 116.88,96.17 117.25,96.54 v2(117.34,96.54)
  IN2 w0.18: v2(63.1,97.08) 63.54,97.53 66.8,97.53 67,97.73 68.06,97.73 68.92,98.59 69.73,98.59 72.65,101.52 77.93,101.52 78.2,101.79 79.44,101.79 80.03,102.38 81.01,102.38 81.62,102.99 98.04,102.99 98.22,103.17 98.22,103.88 98.4,104.06 98.76,104.06 98.94,103.88 98.94,103.17 99.12,102.99 99.42,102.99 99.61,103.17 99.61,103.89 99.78,104.06 104.22,104.06 108.03,100.26 108.03,99.91
  BOTTOM w0.076: UC1.AT65 117.68,96.19 v2(117.34,96.54)
  BOTTOM w0.102: v2(63.1,97.08) 63.68,96.49 65.31,96.49 65.56,96.74 JDIMM2.63
DDR_B_D23: length 67.4
  IN2 w0.076: v2(116.73,96.54) 115.51,96.54 114.02,98.04 114.02,98.5 113.48,99.04 112.08,99.04 111.69,98.65 108.66,98.65 108.43,98.88 108.43,99.91
  IN2 w0.18: v2(60.05,97.08) 60.89,97.92 66.63,97.92 67.33,98.62 68.39,98.62 68.75,98.99 69.56,98.99 72.49,101.91 77.76,101.91 78.04,102.19 79.28,102.19 79.86,102.78 80.85,102.78 81.45,103.38 97.06,103.38 98.14,104.46 104.43,104.46 108.43,100.46 108.43,99.91
  BOTTOM w0.076: UC1.AU65 117.03,96.24 v2(116.73,96.54)
  BOTTOM w0.102: v2(60.05,97.08) 60.05,97.34 59.54,97.84 59.25,97.84 59.1,97.99 JDIMM2.58
DDR_B_D24: length 66.1
  IN2 w0.076: 106.56,98.65 107.55,97.66 111.65,97.66 112.92,96.39 113.33,96.39 114.56,95.16 116.75,95.16 117.2,94.71 v2(117.34,94.71)
  IN2 w0.18: v2(64.62,94.03) 65.95,94.03 66.94,95.03 69.27,95.03 71.29,97.05 77.92,97.05 78.65,97.78 78.65,99.17 78.85,99.37 79.22,99.37 79.41,99.18 79.41,98.94 79.54,98.81 79.94,98.81 80.11,98.98 80.11,99.44 80.29,99.62 80.71,99.62 80.89,99.44 80.89,98.99 81.07,98.81 81.43,98.81 81.61,98.99 81.61,99.88 81.82,100.08 82.13,100.08 82.33,99.88 82.33,99.12 82.52,98.93 82.84,98.93 83.03,99.12 83.03,100.39 83.45,100.81 104.4,100.81 106.56,98.65
  BOTTOM w0.076: UC1.AT61 117.68,94.37 v2(117.34,94.71)
  BOTTOM w0.102: v2(64.62,94.03) 65.33,94.74 JDIMM2.71
DDR_B_D25: length 65.6
  IN2 w0.076: 106.56,98.09 107.03,97.62 107.03,97.17 107.44,96.76 112.31,96.76 112.86,96.22 113.26,96.22 114.49,94.99 116.4,94.99 v2(116.7,94.69)
  IN2 w0.18: 106.56,98.09 104.24,100.42 84.89,100.42 82.88,98.41 79.84,98.41 78.08,96.65 71.45,96.65 68.94,94.13 66.61,94.13 65.91,93.43 62.18,93.43 v2(61.57,94.03)
  BOTTOM w0.076: UC1.AU61 116.7,94.59 v2(116.7,94.69)
  BOTTOM w0.102: v2(61.57,94.03) 60.6,95.01 60.2,95.01 59.22,95.99 JDIMM2.66
DDR_B_D26: length 68.9
  IN2 w0.076: 105.52,95.46 105.74,95.25 111.86,95.25 112.9,94.21 113.36,94.21 114.34,93.23 117.45,93.23 117.65,93.43 118.23,93.43 v2(118.61,93.8)
  IN2 w0.18: v2(63.1,90.93) 63.1,90.62 62.97,90.49 62.14,90.49 62.01,90.36 62.01,90.04 62.16,89.89 65.49,89.89 66.45,90.84 68.57,90.84 69.18,91.45 69.46,91.45 71.8,93.78 78.34,93.78 79.31,94.75 84.35,94.75 87.81,98.21 102.78,98.21 105.52,95.46
  BOTTOM w0.076: UC1.AP60 118.98,93.42 v2(118.61,93.8)
  BOTTOM w0.102: v2(63.1,90.93) 64.49,92.33 65.24,92.33 65.65,92.74 JDIMM2.79
DDR_B_D27: length 69.5
  IN2 w0.076: v2(119.24,93.8) 118.7,93.25 117.74,93.25 117.55,93.06 114.12,93.06 113.18,94 112.88,94 111.81,95.07 105.35,95.07 104.96,95.46
  IN2 w0.18: v2(60.05,90.93) 60.05,89.97 60.23,89.78 60.54,89.78 60.72,89.96 60.72,90.13 60.9,90.31 61.26,90.31 61.44,90.13 61.44,89.65 61.6,89.5 65.66,89.5 66.61,90.45 68.74,90.45 69.34,91.05 69.63,91.05 71.96,93.38 78.5,93.38 79.47,94.35 84.52,94.35 87.97,97.81 102.61,97.81 104.96,95.46
  BOTTOM w0.076: v2(119.24,93.8) 119.64,93.41 UC1.AN60
  BOTTOM w0.102: v2(60.05,90.93) 59.5,91.49 JDIMM2.84
DDR_B_D28: length 68.1
  IN2 w0.076: 106.75,99.59 108.34,97.99 111.79,97.99 113.06,96.72 113.46,96.72 114.69,95.49 116.89,95.49 117.13,95.25 118.71,95.25 v2(119.24,94.71)
  IN2 w0.18: 106.75,99.59 104.73,101.61 82.22,101.61 81.03,100.41 78.77,100.41 77.05,98.69 73.17,98.69 72.32,97.84 70.96,97.84 69.47,96.35 67.57,96.35 67.04,95.82 64.79,95.82 64.36,95.38 61.4,95.38 v2(60.05,94.03)
  BOTTOM w0.076: UC1.AN61 119.64,94.32 v2(119.24,94.71)
  BOTTOM w0.102: JDIMM2.70 59.19,94.99 60.05,94.13 v2(60.05,94.03)
DDR_B_D29: length 67.6
  IN2 w0.076: 106.56,99.21 107.95,97.83 111.72,97.83 112.99,96.55 113.39,96.55 114.63,95.32 116.82,95.32 117.06,95.08 118.5,95.08 118.61,94.97 v2(118.61,94.71)
  IN2 w0.18: v2(63.1,94.03) 63.1,94.42 63.26,94.57 64.46,94.57 64.6,94.72 64.6,95.07 64.81,95.28 65.17,95.28 65.38,95.08 65.38,94.74 65.54,94.57 65.93,94.57 66.11,94.76 66.11,95.25 66.29,95.42 69.1,95.42 71.12,97.44 72.48,97.44 73.33,98.3 77.22,98.3 78.94,100.02 81.19,100.02 82.39,101.21 104.56,101.21 106.56,99.21
  BOTTOM w0.076: v2(118.61,94.71) 118.98,94.34 UC1.AP61
  BOTTOM w0.102: JDIMM2.67 64.68,95.74 63.1,94.16 v2(63.1,94.03)
DDR_B_D30: length 68.1
  IN2 w0.076: 106.56,96.13 106.59,96.1 111.24,96.1 112.88,94.46 113.42,94.46 114.49,93.39 117.03,93.39 v2(117.35,93.71)
  IN2 w0.18: 106.56,96.13 105.42,96.13 102.94,98.6 87.65,98.6 86.92,97.88 86.62,97.88 85.89,98.6 85.64,98.6 85.38,98.34 85.38,98.09 86.13,97.34 86.13,97.09 85.84,96.8 85.58,96.8 84.83,97.54 84.58,97.54 84.36,97.33 84.36,97.02 85.06,96.32 85.06,96.08 84.6,95.63 84.3,95.63 84,95.92 84,96.42 83.82,96.6 83.46,96.6 83.28,96.42 83.28,95.69 82.73,95.15 79.14,95.15 78.17,94.18 71.63,94.18 69.3,91.84 66.88,91.84 65.33,90.29 64.68,90.29 64.49,90.48 64.49,90.8 v2(64.62,90.93)
  BOTTOM w0.076: UC1.AT60 117.68,93.38 v2(117.35,93.71)
  BOTTOM w0.102: JDIMM2.83 65.58,91.74 65.43,91.59 65.27,91.59 v2(64.62,90.93)
DDR_B_D31: length 67.6
  IN2 w0.076: v2(116.7,93.76) 116.5,93.56 114.77,93.56 113.61,94.72 112.86,94.72 111.31,96.27 106.98,96.27 106.73,96.53 106.56,96.53
  IN2 w0.18: 106.56,96.53 105.58,96.53 103.11,99 85.48,99 83.47,97 82.49,97 82.31,96.82 82.31,96.09 82.13,95.91 81.77,95.91 81.59,96.09 81.59,96.82 81.41,97 81.1,97 80.8,96.69 80.13,96.69 78.01,94.57 72.99,94.57 72.58,94.99 71.89,94.99 69.13,92.24 66.72,92.24 65.86,91.38 61.7,91.38 61.57,91.25 v2(61.57,90.93)
  BOTTOM w0.076: UC1.AU60 117.03,93.4 116.7,93.74 v2(116.7,93.76)
  BOTTOM w0.102: JDIMM2.80 58.72,92.49 58.73,92.48 60.02,92.48 v2(61.57,90.93)
DDR_B_D32: length 67.7
  IN2 w0.076: 104.26,80.12 104.92,80.12 105.17,80.37 113.07,80.37 114.58,81.88 114.58,82.02 115.38,82.81 v2(116.69,82.81)
  IN2 w0.18: 104.26,80.12 104.06,80.32 101.99,80.32 101.52,79.86 98.86,79.86 87.28,68.28 78.99,68.28 77.74,67.03 70.61,67.03 70.36,67.27 67.58,67.27 67.32,67.53 67.32,68.43 67.14,68.61 64.39,68.61 64.31,68.52 64.31,68.38 64.04,68.12 62.71,68.12 62.58,67.99 62.58,67.72 62.97,67.34 v2(63.1,67.34)
  BOTTOM w0.076: v2(116.69,82.81) 116.69,82.6 116.92,82.37 UC1.AU40
  BOTTOM w0.102: v2(63.1,67.34) 63.7,67.94 65.2,67.94 65.5,68.24 JDIMM2.169
DDR_B_D33: length 68.3
  IN2 w0.076: 103.9,79.92 104.04,79.78 104.96,79.78 105.29,80.11 113.05,80.11 114.75,81.81 114.75,81.95 115.41,82.61 116.37,82.61 116.53,82.45 116.84,82.45 117.12,82.73 v2(117.36,82.73)
  IN2 w0.18: 103.9,79.92 102.15,79.92 101.69,79.46 99.02,79.46 87.44,67.89 79.16,67.89 77.9,66.63 70.45,66.63 70.2,66.88 67.11,66.88 66.93,67.06 66.93,68.03 66.75,68.21 66.39,68.21 66.21,68.03 66.21,67.06 66.03,66.88 65.42,66.88 65.31,66.99 65.31,67.37 65.5,67.56 65.5,68.07 65.36,68.21 64.7,68.21 64.32,67.84 64.32,67.63 v2(64.62,67.34)
  BOTTOM w0.076: UC1.AT40 117.68,82.4 v2(117.36,82.73)
  BOTTOM w0.102: JDIMM2.173 66.04,67.24 66.04,67.24 65.44,67.24 65.19,66.99 65.19,66.76 65.09,66.67 64.49,66.67 64.3,66.86 64.3,67.01 v2(64.62,67.34)
DDR_B_D34: length 68.8
  IN2 w0.076: 116.28,80.61 116.82,80.61 117.22,81.01 v2(117.33,81.01)
  IN2 w0.18: 116.28,80.61 115.3,80.61 114.83,80.14 114.83,79.79 115.01,79.61 115.01,79.35 114.76,79.1 114.5,79.1 114.26,79.35 114.04,79.35 113.78,79.08 113.78,78.86 114.03,78.61 114.03,78.37 113.82,78.16 113.56,78.16 113.42,78.3 113.05,78.3 106.1,78.3 105.93,78.13 105.93,77.6 105.73,77.41 105.44,77.41 105.25,77.6 105.25,78.1 105.05,78.29 104.69,78.29 104.53,78.12 104.53,77.6 104.33,77.41 103.57,77.41 103.41,77.25 99.94,77.25 88.36,65.68 81.46,65.68 81.16,65.37 80.62,65.37 80.46,65.22 80.46,63.95 80.12,63.61 79.79,63.61 79.66,63.74 79.66,64.51 79.51,64.66 79.07,64.66 78.9,64.49 78.9,63.75 78.76,63.61 70.2,63.61 69.8,64.01 67.45,64.01 67.25,64.22 v2(64.59,64.22)
  BOTTOM w0.076: UC1.AT37 v2(117.33,81.01)
  BOTTOM w0.102: JDIMM2.183 65.11,64.74 v2(64.59,64.22)
DDR_B_D35: length 68.4
  IN2 w0.076: 103.9,78.11 104.21,78.11 104.7,78.61 112.24,78.61 112.95,79.31 113.7,79.31 115.36,80.98 v2(116.67,80.98)
  IN2 w0.18: v2(63.07,64.22) 62.94,64.22 62.45,64.7 62.14,64.7 62.01,64.83 62.01,65.28 62.19,65.46 62.52,65.46 63.26,64.72 67.3,64.72 67.61,64.41 69.96,64.41 70.37,64.01 77.85,64.01 79.62,65.77 80.99,65.77 81.3,66.07 88.2,66.07 99.77,77.65 102.52,77.65 102.98,78.11 103.9,78.11
  BOTTOM w0.076: UC1.AU37 117.03,80.73 116.78,80.98 v2(116.67,80.98)
  BOTTOM w0.102: v2(63.07,64.22) 63.54,63.74 JDIMM2.187
DDR_B_D36: length 68.9
  IN2 w0.076: v2(118.63,82.75) 118.2,83.18 114.84,83.18 112.29,80.63 104.99,80.63 104.82,80.46 104.48,80.46
  IN2 w0.18: 104.48,80.46 104.19,80.75 101.94,80.75 101.44,80.25 98.69,80.25 87.12,68.68 78.83,68.68 77.57,67.42 70.78,67.42 69.66,68.54 69.26,68.54 68.8,69 64.95,69 64.94,69.01 62.02,69.01 v2(61.57,68.57)
  BOTTOM w0.076: UC1.AR40 118.33,82.42 118.63,82.72 v2(118.63,82.75)
  BOTTOM w0.102: v2(61.57,68.57) 61,67.99 JDIMM2.170
DDR_B_D37: length 69.3
  IN2 w0.076: 103.9,79.53 105.09,79.53 105.43,79.87 113.39,79.87 115.39,81.88 115.72,81.88 116.12,82.28 116.91,82.28 116.97,82.34 118.18,82.34 v2(118.61,81.91)
  IN2 w0.18: v2(60.81,67.34) 60.81,66.79 61.01,66.59 64.69,66.59 64.8,66.48 70.04,66.48 70.28,66.23 72.2,66.23 72.71,65.73 77.57,65.73 79.33,67.49 87.61,67.49 99.18,79.06 101.85,79.06 102.32,79.53 103.9,79.53
  BOTTOM w0.076: UC1.AP40 v2(118.61,81.91)
  BOTTOM w0.102: v2(60.81,67.34) 60.81,67.16 60.58,66.93 59.21,66.93 59.15,66.99 JDIMM2.174
DDR_B_D38: length 70.4
  IN2 w0.076: v2(118.61,81) 118.22,80.61 117.09,80.61 116.82,80.34 115.47,80.34 115.11,79.98 115.11,79.82 115.4,79.53 115.4,79.43 113.78,77.81 112.49,77.81 112.22,78.08 106.72,78.08 105.64,77.01 103.9,77.01
  IN2 w0.18: 103.9,77.01 103.73,77.01 103.58,76.85 100.1,76.85 88.53,65.28 81.63,65.28 80.86,64.51 80.86,63.79 80.28,63.21 70.04,63.21 69.63,63.62 67.28,63.62 67.28,63.62 62.13,63.62 v2(61.54,64.22)
  BOTTOM w0.076: UC1.AP37 v2(118.61,81)
  BOTTOM w0.102: JDIMM2.186 59.17,63.99 59.39,63.77 61.09,63.77 v2(61.54,64.22)
DDR_B_D39: length 70.3
  IN2 w0.076: v2(118.64,80.09) 118.29,80.45 117.16,80.45 116.83,80.12 116.33,80.12 113.85,77.64 112.43,77.64 112.16,77.91 106.78,77.91 105.46,76.59 103.9,76.59
  IN2 w0.18: v2(60.02,64.22) 61.01,63.23 67.11,63.23 67.12,63.22 68.77,63.22 69.44,62.55 69.81,62.55 70,62.75 71.89,62.75 72.32,62.32 78.54,62.32 78.98,62.76 80.69,62.76 82.81,64.88 88.69,64.88 100.26,76.46 103.74,76.46 103.87,76.59 103.9,76.59
  BOTTOM w0.076: UC1.AR37 v2(118.64,80.09)
  BOTTOM w0.102: JDIMM2.182 59.57,64.99 60.02,64.55 v2(60.02,64.22)
DDR_B_D40: length 70.9
  IN2 w0.076: 104.4,75.28 104.74,75.62 105.19,75.62 105.9,76.33 113.49,76.33 114.38,77.22 114.38,77.47 116.44,79.52 116.85,79.52 117.2,79.17 v2(117.34,79.17)
  IN2 w0.18: v2(61.54,62.64) 61.39,62.64 61.16,62.41 61.16,61.91 61.31,61.76 61.91,61.76 62.09,61.94 62.09,62.01 62.27,62.19 62.63,62.19 62.81,62.01 62.81,61.94 62.99,61.76 64.93,61.76 65.29,61.4 68.08,61.4 68.31,61.17 69.16,61.17 69.31,61.02 69.31,60.56 69.59,60.28 71.06,60.28 71.06,60.28 77.15,60.28 77.81,60.94 79.11,60.94 79.55,61.38 84.22,61.38 86.34,63.5 89.26,63.5 100.84,75.08 104.2,75.08 104.4,75.28
  BOTTOM w0.076: v2(117.34,79.17) 117.47,78.99 UC1.AT33
  BOTTOM w0.102: JDIMM2.190 59.44,62.99 59.56,63.11 61.08,63.11 v2(61.54,62.64)
DDR_B_D41: length 70.1
  IN2 w0.076: v2(116.69,79.16) 116.3,79.16 114.54,77.4 114.54,76.91 113.23,75.6 112.63,75.6 112.35,75.32 105,75.32 104.68,75
  IN2 w0.18: 104.68,75 104.36,74.68 101,74.68 89.43,63.11 86.51,63.11 84.38,60.98 81.89,60.98 81.39,60.49 77.91,60.49 77.31,59.89 71.23,59.89 71.22,59.88 69.43,59.88 69.03,60.28 68.93,60.38 67.4,60.38 66.78,61 65.13,61 64.77,61.36 61.12,61.36 60.97,61.51 59.75,61.51 59.51,61.76 59.51,62.35 59.8,62.64 v2(60.02,62.64)
  BOTTOM w0.076: UC1.AU33 117.03,78.81 v2(116.69,79.16)
  BOTTOM w0.102: JDIMM2.194 59.37,61.99 v2(60.02,62.64)
DDR_B_D42: length 69.5
  IN2 w0.076: v2(116.73,77.37) 116.73,76.85 116.62,76.74 115.54,76.74 113.42,74.63 113,74.63 112.42,74.05 112.42,73.78 111.95,73.31 111.13,73.31
  IN2 w0.18: v2(63.07,59.32) 63.07,59.01 63.2,58.88 66.34,58.88 67.12,58.1 67.12,57.94 67.35,57.7 67.58,57.7 67.73,57.84 67.73,58.03 67.85,58.16 68.17,58.16 68.3,58.03 68.3,57.84 68.44,57.7 68.9,57.7 69.29,57.3 70.53,57.3 70.71,57.48 70.71,57.88 70.91,58.07 71.27,58.07 71.44,57.9 71.44,57.43 71.6,57.27 77.52,57.27 78.02,57.78 83.98,57.78 87.49,61.29 90.18,61.29 101.75,72.87 105.12,72.87 105.56,73.31 111.13,73.31
  BOTTOM w0.076: v2(116.73,77.37) 116.73,77.3 UC1.AU30
  BOTTOM w0.102: JDIMM2.207 63.65,58.74 v2(63.07,59.32)
DDR_B_D43: length 70
  IN2 w0.076: v2(117.34,77.37) 116.97,77.73 116.44,77.73 115.61,76.9 115.47,76.9 113.36,74.79 112.93,74.79 112.62,74.48 106.17,74.48 106.07,74.38
  IN2 w0.18: 106.07,74.38 104.95,73.27 101.59,73.27 90.01,61.69 87.1,61.69 84.97,59.56 84.55,59.56 84.4,59.41 84.4,58.76 84.24,58.61 83.88,58.61 83.68,58.81 83.68,59.37 83.49,59.56 83.17,59.56 82.99,59.38 82.99,58.4 82.81,58.22 82.45,58.22 82.27,58.4 82.27,58.8 82.09,58.98 81.65,58.98 81.49,58.82 81.49,58.37 81.34,58.22 80.83,58.22 80.7,58.34 80.7,58.5 80.52,58.68 80.16,58.68 79.98,58.5 79.98,58.34 79.81,58.17 79.43,58.17 79.26,58.34 79.26,58.8 79.08,58.98 78.72,58.98 78.54,58.8 78.54,58.29 78.43,58.17 77.83,58.17 77.82,58.16 72.19,58.16 71.89,58.47 70.37,58.47 70.19,58.29 70.19,57.88 70.01,57.7 69.46,57.7 68.58,58.58 67.2,58.58 66.45,59.32 v2(64.59,59.32)
  BOTTOM w0.076: v2(117.34,77.37) 117.68,76.91 UC1.AT30
  BOTTOM w0.102: v2(64.59,59.32) 65.01,59.74 JDIMM2.203
DDR_B_D44: length 72.1
  IN2 w0.076: v2(117.97,79.17) 117.6,79.54 117.06,79.54 116.91,79.69 116.37,79.69 113.32,76.64 105.98,76.64 105.35,76.02 104.86,76.02 104.4,75.56 104.12,75.56
  IN2 w0.18: v2(63.07,62.64) 63.07,62.35 63.26,62.16 65.1,62.16 65.46,61.8 68.24,61.8 68.47,61.57 69.6,61.57 69.69,61.47 69.69,61.34 69.88,61.16 70.2,61.16 70.35,61.32 70.35,61.68 70.44,61.76 70.87,61.76 71.05,61.59 71.05,60.78 71.15,60.68 72.26,60.68 72.51,60.93 72.51,61.22 72.63,61.33 75.69,61.33 75.87,61.15 75.87,60.85 76.04,60.68 76.4,60.68 76.59,60.87 76.59,61.15 76.77,61.33 78.94,61.33 79.38,61.77 84.05,61.77 84.9,62.62 84.9,62.87 84.47,63.31 84.47,63.56 84.72,63.82 84.98,63.82 85.41,63.38 85.66,63.38 86.18,63.9 89.1,63.9 100.67,75.48 104.03,75.48 104.12,75.56
  BOTTOM w0.076: v2(117.97,79.17) 118.11,78.99 UC1.AR33
  BOTTOM w0.102: JDIMM2.191 65.6,62.74 65.3,63.05 63.41,63.05 63.07,62.7 v2(63.07,62.64)
DDR_B_D45: length 72.4
  IN2 w0.076: v2(118.61,79.17) 118.83,79.17 118.92,79.26 118.92,79.57 118.78,79.71 117.13,79.71 116.98,79.85 116.3,79.85 113.37,76.93 106.03,76.93 105.3,76.2 104.44,76.2 104.14,75.89 103.9,75.89
  IN2 w0.18: v2(64.59,62.64) 65.42,62.64 65.53,62.53 65.53,62.35 65.68,62.19 66.09,62.19 66.27,62.37 66.27,62.46 66.45,62.64 66.81,62.64 66.99,62.46 66.99,62.37 67.17,62.19 67.93,62.19 68.25,62.52 68.64,62.52 69.2,61.96 70.05,61.96 70.25,62.16 71.12,62.16 71.45,61.84 71.45,61.42 71.63,61.24 71.99,61.24 72.17,61.42 72.17,61.61 72.28,61.73 78.78,61.73 79.22,62.17 81,62.17 81.18,62.35 81.18,62.43 81.36,62.61 81.72,62.61 81.91,62.43 81.91,62.35 82.09,62.17 82.45,62.17 82.63,62.35 82.63,63.87 82.81,64.05 83.17,64.05 83.35,63.87 83.35,62.35 83.53,62.17 83.89,62.17 84.07,62.35 84.07,64.12 84.25,64.3 88.93,64.3 100.51,75.87 103.87,75.87 103.9,75.89
  BOTTOM w0.076: UC1.AP33 118.75,78.99 v2(118.61,79.17)
  BOTTOM w0.102: v2(64.59,62.64) 65.46,61.78 65.55,61.78 65.59,61.74 JDIMM2.195
DDR_B_D46: length 70.6
  IN2 w0.076: v2(117.97,77.37) 117.6,76.99 117.14,76.99 116.72,76.57 115.6,76.57 113.49,74.46 113.06,74.46 112.58,73.98 112.58,73.71 111.79,72.91 111.13,72.91
  IN2 w0.18: v2(61.54,59.32) 61.54,58.68 61.74,58.48 66.01,58.48 67.19,57.3 68.73,57.3 69.13,56.91 71.44,56.91 71.47,56.88 77.68,56.88 78.19,57.38 84.14,57.38 87.66,60.9 90.34,60.9 101.92,72.47 105.28,72.47 105.72,72.91 111.13,72.91
  BOTTOM w0.076: v2(117.97,77.37) 118.33,76.91 UC1.AR30
  BOTTOM w0.102: v2(61.54,59.32) 61.14,59.73 59.5,59.73 59.26,59.49 JDIMM2.204
DDR_B_D47: length 71.7
  IN2 w0.076: v2(118.61,77.37) 118.07,76.83 117.2,76.83 116.78,76.41 115.67,76.41 113.56,74.3 113.13,74.3 112.75,73.91 112.75,73.64 111.62,72.52 110.79,72.52
  IN2 w0.18: 110.79,72.52 105.88,72.52 105.44,72.08 102.08,72.08 90.51,60.5 87.82,60.5 84.31,56.99 81.07,56.99 80.57,56.48 71.31,56.48 71.28,56.51 70.21,56.51 69.72,56.02 69.35,56.02 68.46,56.91 67.02,56.91 65.85,58.09 61.26,58.09 v2(60.02,59.32)
  BOTTOM w0.076: v2(118.61,77.37) 118.98,76.91 UC1.AP30
  BOTTOM w0.102: JDIMM2.208 59.18,58.49 v2(60.02,59.32)
DDR_B_D48: length 70.9
  IN2 w0.076: 108.22,70.32 108.72,70.82 111.83,70.82 112.7,71.69 113.01,71.69 113.39,72.08 113.39,72.81 114.72,74.14 114.72,74.46 115.76,75.5 v2(116.71,75.5)
  IN2 w0.18: v2(60.02,57.5) 60.02,57.46 61.45,56.03 65.39,56.03 67.18,54.24 71.96,54.24 72.34,53.86 77.38,53.86 77.39,53.86 81.33,53.86 82.17,54.7 85.62,54.7 89.64,58.73 91.24,58.73 102.51,69.99 104.75,69.99 105.06,70.3 108.2,70.3 108.22,70.32
  BOTTOM w0.076: UC1.AU27 116.7,75.5 116.7,75.5 v2(116.71,75.5)
  BOTTOM w0.102: JDIMM2.216 58.9,56.49 58.9,56.49 59.66,56.49 60.02,56.85 v2(60.02,57.5)
DDR_B_D49: length 72.4
  IN2 w0.076: 108.21,70.7 108.57,71.05 111.33,71.05 112.98,72.7 113.05,72.7 114.55,74.2 114.55,74.53 115.89,75.87 116.88,75.87 117.24,75.51 v2(117.34,75.51)
  IN2 w0.18: v2(61.54,57.5) 62.61,56.43 65.55,56.43 67.34,54.64 72.33,54.64 72.44,54.75 77.54,54.75 77.72,54.57 77.72,54.44 77.9,54.26 78.26,54.26 78.44,54.44 78.44,54.92 78.62,55.1 78.98,55.1 79.16,54.92 79.16,54.44 79.34,54.26 79.7,54.26 79.88,54.44 79.88,54.87 80.11,55.1 85.45,55.1 89.47,59.12 91.08,59.12 102.34,70.39 104.59,70.39 104.9,70.7 108.21,70.7
  BOTTOM w0.076: v2(117.34,75.51) UC1.AT27
  BOTTOM w0.102: v2(61.54,57.5) 61.04,58 59.77,58 59.27,57.49 58.25,57.49 JDIMM2.212
DDR_B_D50: length 70.1
  IN2 w0.076: v2(117.34,74.59) 117.18,74.59 116.59,74 115.55,74 114.05,72.5 114.05,71.8 113.29,71.03 112.98,71.03 111.94,70 110.68,70 110.53,69.84
  IN2 w0.18: v2(63.07,53.93) 63.07,53.3 63.21,53.15 65.71,53.15 67.31,51.54 71.4,51.54 71.41,51.54 77.63,51.54 78.13,52.05 84.03,52.05 84.87,52.89 86.37,52.89 90.39,56.91 91.99,56.91 103.07,67.99 107.29,67.99 107.78,68.49 109.17,68.49 110.53,69.84
  BOTTOM w0.076: v2(117.34,74.59) 117.34,74.59 UC1.AT25
  BOTTOM w0.102: JDIMM2.225 65.87,54.24 65.86,54.23 65.48,54.23 64.95,54.77 63.9,54.77 v2(63.07,53.93)
DDR_B_D51: length 69.4
  IN2 w0.076: v2(116.66,74.6) 116.23,74.17 115.49,74.17 113.89,72.57 113.89,71.87 113.22,71.2 112.91,71.2 112.04,70.33 110.45,70.33 109.9,69.77
  IN2 w0.18: 109.9,69.77 109.01,68.88 107.09,68.88 106.97,68.77 106.97,68.51 106.84,68.39 106.4,68.39 106.24,68.54 106.24,68.74 106.09,68.88 105.65,68.88 105.49,68.72 105.49,68.5 105.38,68.39 102.91,68.39 91.83,57.31 90.23,57.31 86.2,53.29 84.21,53.29 84.02,53.11 84.02,52.62 83.84,52.44 83.48,52.44 83.3,52.62 83.3,53.11 83.12,53.29 82.76,53.29 82.58,53.11 82.58,52.62 82.4,52.44 72.58,52.44 72.09,51.96 70.85,51.96 70.67,52.14 70.67,52.46 70.49,52.64 70.13,52.64 69.95,52.46 69.95,52.14 69.77,51.96 69.16,51.96 68.98,52.14 68.98,52.34 68.8,52.52 68.44,52.52 68.26,52.34 68.26,52.14 68.08,51.96 67.46,51.96 65.49,53.93 v2(64.59,53.93)
  BOTTOM w0.076: UC1.AU25 117.03,74.2 116.66,74.57 v2(116.66,74.6)
  BOTTOM w0.102: v2(64.59,53.93) 65.28,53.24 JDIMM2.229
DDR_B_D52: length 72.8
  IN2 w0.076: 108.21,71.09 108.43,71.31 111.35,71.31 112.91,72.86 112.98,72.86 114.39,74.27 114.39,74.6 115.83,76.04 116.98,76.04 117.12,75.89 118.23,75.89 v2(118.61,75.51)
  IN2 w0.18: 108.21,71.09 104.73,71.09 104.42,70.78 102.18,70.78 90.91,59.52 89.31,59.52 88.94,59.15 88.69,59.15 88.4,59.44 88.15,59.44 87.89,59.18 87.89,58.93 88.18,58.64 88.18,58.39 87.92,58.13 87.67,58.13 87.38,58.42 87.13,58.42 86.87,58.16 86.87,57.91 87.16,57.62 87.16,57.37 85.29,55.5 78.09,55.5 77.74,55.15 72.28,55.15 72.16,55.03 67.51,55.03 65.72,56.82 62.96,56.82 62.77,57.01 62.77,57.2 v2(63.07,57.5)
  BOTTOM w0.076: v2(118.61,75.51) UC1.AP27
  BOTTOM w0.102: JDIMM2.211 66.09,57.74 66.09,57.74 65.52,57.74 65.31,57.95 63.51,57.95 v2(63.07,57.5)
DDR_B_D53: length 72.6
  IN2 w0.076: v2(119.24,75.51) 118.67,76.08 117.19,76.08 117.07,76.2 115.7,76.2 113.63,74.13 113.2,74.13 112.91,73.84 112.91,73.18
  IN2 w0.18: v2(64.59,57.5) 65.6,57.5 66.78,56.32 67.22,56.32 67.34,56.19 67.34,55.76 67.67,55.43 67.85,55.43 67.98,55.56 67.98,55.78 68.13,55.94 68.49,55.94 68.61,55.81 68.61,55.56 68.74,55.43 70.18,55.43 70.36,55.61 70.36,55.74 70.54,55.93 70.91,55.93 71.09,55.74 71.09,55.61 71.27,55.43 72,55.43 72.11,55.54 77.57,55.54 77.92,55.89 80.81,55.89 81.31,56.4 81.66,56.4 81.84,56.22 81.84,56.07 82.02,55.89 82.38,55.89 82.56,56.07 82.56,56.22 82.74,56.4 83.1,56.4 83.28,56.22 83.28,56.07 83.46,55.89 83.82,55.89 84,56.07 84,56.22 84.18,56.4 84.5,56.4 84.95,55.95 85.18,55.95 85.46,56.23 85.46,56.46 85.16,56.76 85.16,57.01 85.42,57.27 85.67,57.27 85.97,56.97 86.2,56.97 86.48,57.25 86.48,57.48 86.18,57.78 86.18,58.03 88.07,59.92 90.75,59.92 102.01,71.18 104.26,71.18 104.57,71.49 108.12,71.49 108.15,71.52 111.26,71.52 112.91,73.18
  BOTTOM w0.076: v2(119.24,75.51) UC1.AN27
  BOTTOM w0.102: v2(64.59,57.5) 65.35,56.74 JDIMM2.215
DDR_B_D54: length 72.8
  IN2 w0.076: v2(119.24,74.6) 118.53,74.06 117.12,74.06 116.73,73.67 116.37,73.67 114.38,71.68 114.38,71.66 113.42,70.7 113.12,70.7 112.07,69.65 111.72,69.65 110.18,68.11 110.01,68.11
  IN2 w0.18: 110.01,68.11 109.97,68.11 109.55,67.7 108.38,67.7 107.88,67.2 103.4,67.2 92.32,56.12 90.72,56.12 86.7,52.1 85.2,52.1 84.35,51.25 81.84,51.25 81.33,50.75 66.99,50.75 65.38,52.35 62.01,52.35 v2(60.02,53.93)
  BOTTOM w0.076: v2(119.24,74.6) UC1.AN25
  BOTTOM w0.102: JDIMM2.228 59.58,53.49 v2(60.02,53.93)
DDR_B_D55: length 72.1
  IN2 w0.076: v2(118.63,74.62) 118.23,74.23 117.05,74.23 116.66,73.84 116.3,73.84 114.22,71.75 114.22,71.73 113.35,70.87 113.05,70.87 112.01,69.83 111.67,69.83 110.3,68.46 109.76,68.46 109.71,68.41
  IN2 w0.18: v2(61.54,53.93) 62.72,52.75 65.54,52.75 67.15,51.15 71.24,51.15 71.24,51.14 79.57,51.14 80.07,51.65 84.19,51.65 85.03,52.49 86.53,52.49 90.56,56.52 92.16,56.52 103.24,67.6 107.45,67.6 107.94,68.09 109.39,68.09 109.71,68.41
  BOTTOM w0.076: v2(118.63,74.62) 118.98,74.27 UC1.AP25
  BOTTOM w0.102: v2(61.54,53.93) 60.98,54.49 JDIMM2.224
DDR_B_D56: length 75.3
  IN2 w0.076: v2(117.34,72.77) 117.22,72.77 116.85,73.14 116.54,73.14 116.3,72.9 116.3,72.64 115.89,72.23 115.89,71.96 113.4,69.47 112.67,69.47 111.27,68.08 111.27,67.42 110.99,67.13
  IN2 w0.18: v2(61.54,51.77) 61.41,51.77 60.99,51.35 60.99,51.11 61.14,50.97 61.86,50.97 62.22,51.32 62.58,51.32 62.74,51.16 62.74,50.99 62.9,50.83 64.95,50.83 67.24,48.54 68.36,48.54 69.12,47.78 70,47.78 70.3,47.48 70.99,47.48 71.42,47.91 71.42,48.62 71.6,48.8 71.82,48.8 71.96,48.94 77.72,48.94 78.08,49.3 85.85,49.3 91.29,54.74 92.9,54.74 103.97,65.82 109.67,65.82 110.99,67.13
  BOTTOM w0.076: v2(117.34,72.77) 117.34,72.77 UC1.AT22
  BOTTOM w0.102: v2(61.54,51.77) 60.82,52.49 58.83,52.49 58.83,52.49 JDIMM2.232
DDR_B_D57: length 74.4
  IN2 w0.076: 111.01,66.59 111.53,67.11 111.53,68.05 112.79,69.31 113.47,69.31 116.05,71.9 116.05,72.16 116.66,72.77 v2(116.7,72.77)
  IN2 w0.18: 111.01,66.59 109.84,65.42 104.2,65.42 93.12,54.35 91.46,54.35 86.01,48.9 78.4,48.9 77.52,48.02 72.09,48.02 71.15,47.08 70.14,47.08 69.83,47.39 68.95,47.39 68.19,48.15 67.07,48.15 64.79,50.44 62.24,50.44 62.11,50.57 59.5,50.57 59.28,50.8 59.28,51.62 59.43,51.77 v2(60.02,51.77)
  BOTTOM w0.076: v2(116.7,72.77) 116.7,72.75 117.03,72.41 UC1.AU22
  BOTTOM w0.102: JDIMM2.236 59.26,51.49 59.26,51.49 59.74,51.49 v2(60.02,51.77)
DDR_B_D58: length 74
  IN2 w0.076: 109.86,64.01 113.52,67.66 113.52,68.35 116.75,71.58 v2(116.75,71.87)
  IN2 w0.18: 109.86,64.01 106.88,64.01 106.12,63.24 105.76,63.24 105,64.01 104.79,64.01 102.95,62.17 102.95,61.66 95.7,54.41 95.7,53.05 95.24,52.58 91.7,52.58 86.3,47.18 78.68,47.18 78.1,46.6 72.68,46.6 71.74,45.67 68.6,45.67 68.26,45.33 67.89,45.33 67.6,45.62 67.35,45.62 67.06,45.33 66.8,45.33 66.55,45.58 66.55,45.84 66.93,46.22 66.93,46.48 66.68,46.73 66.42,46.73 65.9,46.21 65.64,46.21 65.39,46.46 65.39,46.72 65.82,47.15 65.82,47.4 65.43,47.79 65.17,47.79 64.71,47.33 64.45,47.33 64.2,47.58 64.2,47.84 64.59,48.23 v2(64.59,48.7)
  BOTTOM w0.076: v2(116.75,71.87) 116.75,71.78 UC1.AU21
  BOTTOM w0.102: JDIMM2.249 65.05,48.24 v2(64.59,48.7)
DDR_B_D59: length 75
  IN2 w0.076: v2(117.34,71.87) 117.27,71.87 113.69,68.29 113.69,67.43 109.86,63.61
  IN2 w0.18: 109.86,63.61 107.05,63.61 104.72,61.28 103.14,61.28 98.02,56.16 98.02,55.91 98.13,55.8 98.13,55.54 97.87,55.29 97.62,55.29 97.51,55.4 97.25,55.4 96.99,55.13 96.99,54.88 97.41,54.45 97.41,54.2 97.16,53.94 96.9,53.94 96.61,54.24 96.35,54.24 96.1,53.98 96.1,53.73 96.39,53.43 96.39,53.18 95.4,52.18 91.86,52.18 86.46,46.79 78.85,46.79 78.27,46.21 74.35,46.21 73.41,45.27 68.76,45.27 68.42,44.93 66.29,44.93 64.45,46.77 63.07,48.15 v2(63.07,48.7)
  BOTTOM w0.076: UC1.AT21 117.34,71.85 v2(117.34,71.87)
  BOTTOM w0.102: JDIMM2.245 66.15,49.24 66.14,49.23 65.09,49.23 64.96,49.36 63.74,49.36 v2(63.07,48.7)
DDR_B_D60: length 76.9
  IN2 w0.076: v2(119.24,72.77) 118.69,73.32 117.59,73.32 117.58,73.31 117.15,73.31 116.99,73.47 116.41,73.47 114.55,71.62 114.55,71.6 113.49,70.54 113.18,70.54 110.72,68.07 110.72,67.98
  IN2 w0.18: 110.72,67.98 109.84,67.11 108.62,67.11 108.13,66.61 103.65,66.61 92.57,55.53 90.96,55.53 86.94,51.51 86.45,51.51 86.27,51.33 86.27,50.84 85.9,50.47 85.65,50.47 85.51,50.6 85.51,51.17 85.4,51.28 85.21,51.28 84.79,50.86 84.79,50.27 84.61,50.09 84.25,50.09 84.07,50.27 84.07,50.49 83.89,50.67 83.52,50.67 83.34,50.49 83.34,50.27 83.16,50.09 82.8,50.09 82.62,50.27 82.62,50.49 82.44,50.67 82.08,50.67 81.9,50.49 81.9,50.27 81.72,50.09 77.75,50.09 77.39,49.73 72.87,49.73 72.44,50.16 71.85,50.16 71.67,49.98 71.67,49.77 71.49,49.59 71.13,49.59 70.95,49.77 70.95,49.98 70.77,50.16 66.74,50.16 65.14,51.77 v2(64.59,51.77)
  BOTTOM w0.076: UC1.AN22 v2(119.24,72.77)
  BOTTOM w0.102: JDIMM2.237 64.61,51.24 64,50.63 62.65,50.63 62.57,50.71 62.57,50.97 62.67,51.07 63.89,51.07 v2(64.59,51.77)
DDR_B_D61: length 76.3
  IN2 w0.076: v2(118.61,72.77) 118.22,73.16 117.66,73.16 117.65,73.15 117.08,73.15 116.92,73.31 116.48,73.31 116.11,72.94 116.11,72.69 115.72,72.3 115.72,72.03 114.06,70.37 113.25,70.37 110.93,68.05 110.93,67.64
  IN2 w0.18: 110.93,67.64 110,66.71 108.79,66.71 108.29,66.22 103.81,66.22 92.73,55.14 91.13,55.14 85.69,49.7 77.92,49.7 77.55,49.33 71.8,49.33 71.66,49.19 71.28,49.19 71.03,48.94 71.03,48.08 70.82,47.88 70.47,47.88 70.07,48.27 70.07,48.7 70.27,48.89 70.27,49.65 70.15,49.76 69.67,49.76 69.49,49.58 69.49,48.98 69.31,48.8 68.95,48.8 68.77,48.98 68.77,49.58 68.59,49.76 67.68,49.76 67.25,49.33 67.01,49.33 65.12,51.23 63.23,51.23 63.07,51.39 v2(63.07,51.77)
  BOTTOM w0.076: UC1.AP22 v2(118.61,72.77)
  BOTTOM w0.102: v2(63.07,51.77) 63.54,52.24 66.45,52.24 JDIMM2.233
DDR_B_D62: length 75.9
  IN2 w0.076: 109.86,63.21 110.04,63.21 113.85,67.03 113.85,68.22 117.14,71.5 117.28,71.5 117.82,71.5 117.82,71.51 118.25,71.51 v2(118.66,71.92)
  IN2 w0.18: 109.86,63.21 107.21,63.21 104.89,60.89 103.3,60.89 98.67,56.25 98.67,54.89 95.52,51.75 91.98,51.75 86.63,46.39 79.01,46.39 78.43,45.81 74.51,45.81 73.58,44.87 68.93,44.87 68.59,44.54 66.12,44.54 63.12,47.54 62.7,47.54 v2(61.54,48.7)
  BOTTOM w0.076: UC1.AP21 119,71.52 v2(118.66,71.92)
  BOTTOM w0.102: v2(61.54,48.7) 60.84,47.99 JDIMM2.250
DDR_B_D63: length 76.8
  IN2 w0.076: 109.86,62.82 109.97,62.82 114.02,66.86 114.02,68.15 117.21,71.34 117.88,71.34 117.89,71.34 118.69,71.34 v2(119.28,71.93)
  IN2 w0.18: v2(60.02,48.7) 61.57,47.14 62.95,47.14 65.96,44.14 68.75,44.14 69.09,44.48 73.74,44.48 74.68,45.42 78.6,45.42 79.18,45.99 86.79,45.99 92.1,51.3 95.73,51.3 99.06,54.64 99.06,56.09 103.47,60.49 105.05,60.49 107.38,62.82 109.86,62.82
  BOTTOM w0.076: UC1.AN21 119.27,71.82 v2(119.28,71.93)
  BOTTOM w0.102: JDIMM2.246 59.73,48.99 v2(60.02,48.7)
DDR_B_DQS0: length 75.8
  IN2 w0.076: v2(121.73,96.04) 121.73,96.17 121.55,96.34 121.42,96.34 121.25,96.52 121.25,98.05 118.71,100.6 118.64,100.6 118.63,100.61
  IN2 w0.168: v2(61.57,104.37) 61.44,104.37 61.3,104.5 61.3,104.68 61.43,104.81 65.78,104.81 67.11,106.14 67.56,106.14 67.67,106.03 68.39,106.03 69,106.63 69,106.67 71.22,108.89 77.43,108.89 77.97,109.42 92.61,109.42 93.12,109.93 106.01,109.93 110.77,105.17 113.37,105.17 113.92,104.62 114.5,104.62 115.06,105.17 115.51,105.17 117.38,103.3 117.38,101.86 118.05,101.19 118.63,100.61
  BOTTOM w0.076: v2(121.73,96.04) 122.14,96.33 UC1.AH65
  BOTTOM w0.102: JDIMM2.34 59.17,103.99 59.32,104.14 59.41,104.14 59.53,104.02 59.53,103.87 59.68,103.72 61.16,103.72 61.38,103.93 61.38,104.17 v2(61.57,104.37)
DDR_B_DQS1: length 85.3
  IN2 w0.076: v2(122.56,102.96) 122.73,103.13 123.3,103.13 123.45,103.28 123.45,104.89 123.84,105.28 123.84,106.39
  IN2 w0.168: v2(62.21,109.81) 62.34,109.94 62.34,110.4 62.67,110.73 65.07,110.73 66.93,112.59 66.93,113.25 67.76,114.07 68.41,114.07 70.77,116.43 76.36,116.43 77.48,115.32 100.84,115.32 101.59,114.57 103.67,114.57 104.42,115.32 110.44,115.32 110.87,115.75 116.12,115.75 123.84,108.03 123.84,106.39
  BOTTOM w0.076: UC1.AG70 122.73,99.24 122.73,99.11 122.66,99.04 122.56,99.04 122.46,99.14 122.46,99.35 122.5,99.43 122.5,99.71 122.44,99.84 122.44,99.97 122.52,100.12 122.52,101.82 122.18,102.16 122.18,103.06 122.25,103.13 122.44,103.13 122.56,103.01 v2(122.56,102.96)
  BOTTOM w0.102: v2(62.21,109.81) 62.39,109.62 62.39,109.29 62.63,109.05 65.07,109.05 65.26,109.24 JDIMM2.13
DDR_B_DQS2: length 68.4
  IN2 w0.076: 111.12,99.89 111.13,99.89 111.18,99.94 111.48,99.94 112.13,99.29 114,99.29 114.83,98.46 114.83,97.77 115.69,96.91 117.66,96.91 117.71,96.96 117.95,96.96 118.04,96.87 118.04,96.66 v2(117.92,96.54)
  IN2 w0.168: v2(63.86,98.61) 63.6,98.61 63.47,98.74 63.47,98.85 63.71,99.08 65.04,99.08 65.14,98.97 65.14,98.79 65.43,98.5 66.15,98.5 66.46,98.81 66.46,99.29 66.82,99.65 68.55,99.65 69.09,100.2 69.85,100.2 72.46,102.8 78.36,102.8 78.6,103.04 78.6,104.04 78.77,104.2 79.33,104.2 79.44,104.09 79.44,103.84 79.8,103.49 80.74,103.49 81.45,104.2 97.06,104.2 97.9,105.04 104.67,105.04 109.82,99.89 111.12,99.89
  BOTTOM w0.076: UC1.AR65 118.33,96.13 v2(117.92,96.54)
  BOTTOM w0.102: JDIMM2.55 66.15,98.74 66.14,98.73 65.61,98.73 65.45,98.89 65.18,98.89 65.02,99.05 63.65,99.05 63.54,98.95 63.54,98.7 63.64,98.61 v2(63.86,98.61)
DDR_B_DQS3: length 67.5
  IN2 w0.076: 106.56,97.11 106.63,97.11 107.3,96.43 111.64,96.43 113.08,94.99 113.75,94.99 114.81,93.93 116.13,93.93 116.34,94.14 117.77,94.14 117.97,93.93 v2(117.97,93.8)
  IN2 w0.168: v2(60.81,92.89) 60.99,92.71 60.99,92.44 61.33,92.1 65.75,92.1 66.96,93.3 69.28,93.3 71.58,95.59 78.21,95.59 80.19,97.58 83.23,97.58 85.24,99.58 103.35,99.58 105.82,97.11 106.56,97.11
  BOTTOM w0.076: v2(117.97,93.8) 118.33,93.44 UC1.AR60
  BOTTOM w0.102: JDIMM2.76 59.2,93.49 59.23,93.45 59.53,93.45 59.66,93.32 60.43,93.32 60.55,93.43 60.86,93.43 61.08,93.22 61.08,93.16 v2(60.81,92.89)
DDR_B_DQS4: length 69
  IN2 w0.076: v2(118.02,81.91) 117.81,81.71 117.81,81.55 117.63,81.37 115.42,81.37 113.53,79.48 112.82,79.48 112.25,78.91 104.66,78.91 104.54,78.78 104.03,78.78 103.98,78.74 103.95,78.74 103.91,78.69 103.9,78.69
  IN2 w0.168: v2(63.1,66.01) 63.26,65.85 63.26,65.54 63.5,65.3 64.89,65.3 65.24,65.64 65.97,65.64 66.32,65.3 68.08,65.3 68.18,65.4 70.24,65.4 70.34,65.3 70.34,64.85 70.61,64.59 71.27,64.59 71.54,64.86 71.54,65.14 71.63,65.23 72.02,65.23 72.36,64.89 77.92,64.89 79.68,66.65 87.96,66.65 99.53,78.23 102.28,78.23 102.74,78.69 103.9,78.69
  BOTTOM w0.076: v2(118.02,81.91) 118.02,81.87 118.33,81.55 UC1.AR38
  BOTTOM w0.102: v2(63.1,66.01) 63.21,66.01 63.31,65.91 63.31,65.42 63.63,65.1 64.62,65.1 65.41,65.89 65.56,65.89 65.71,65.74 JDIMM2.179
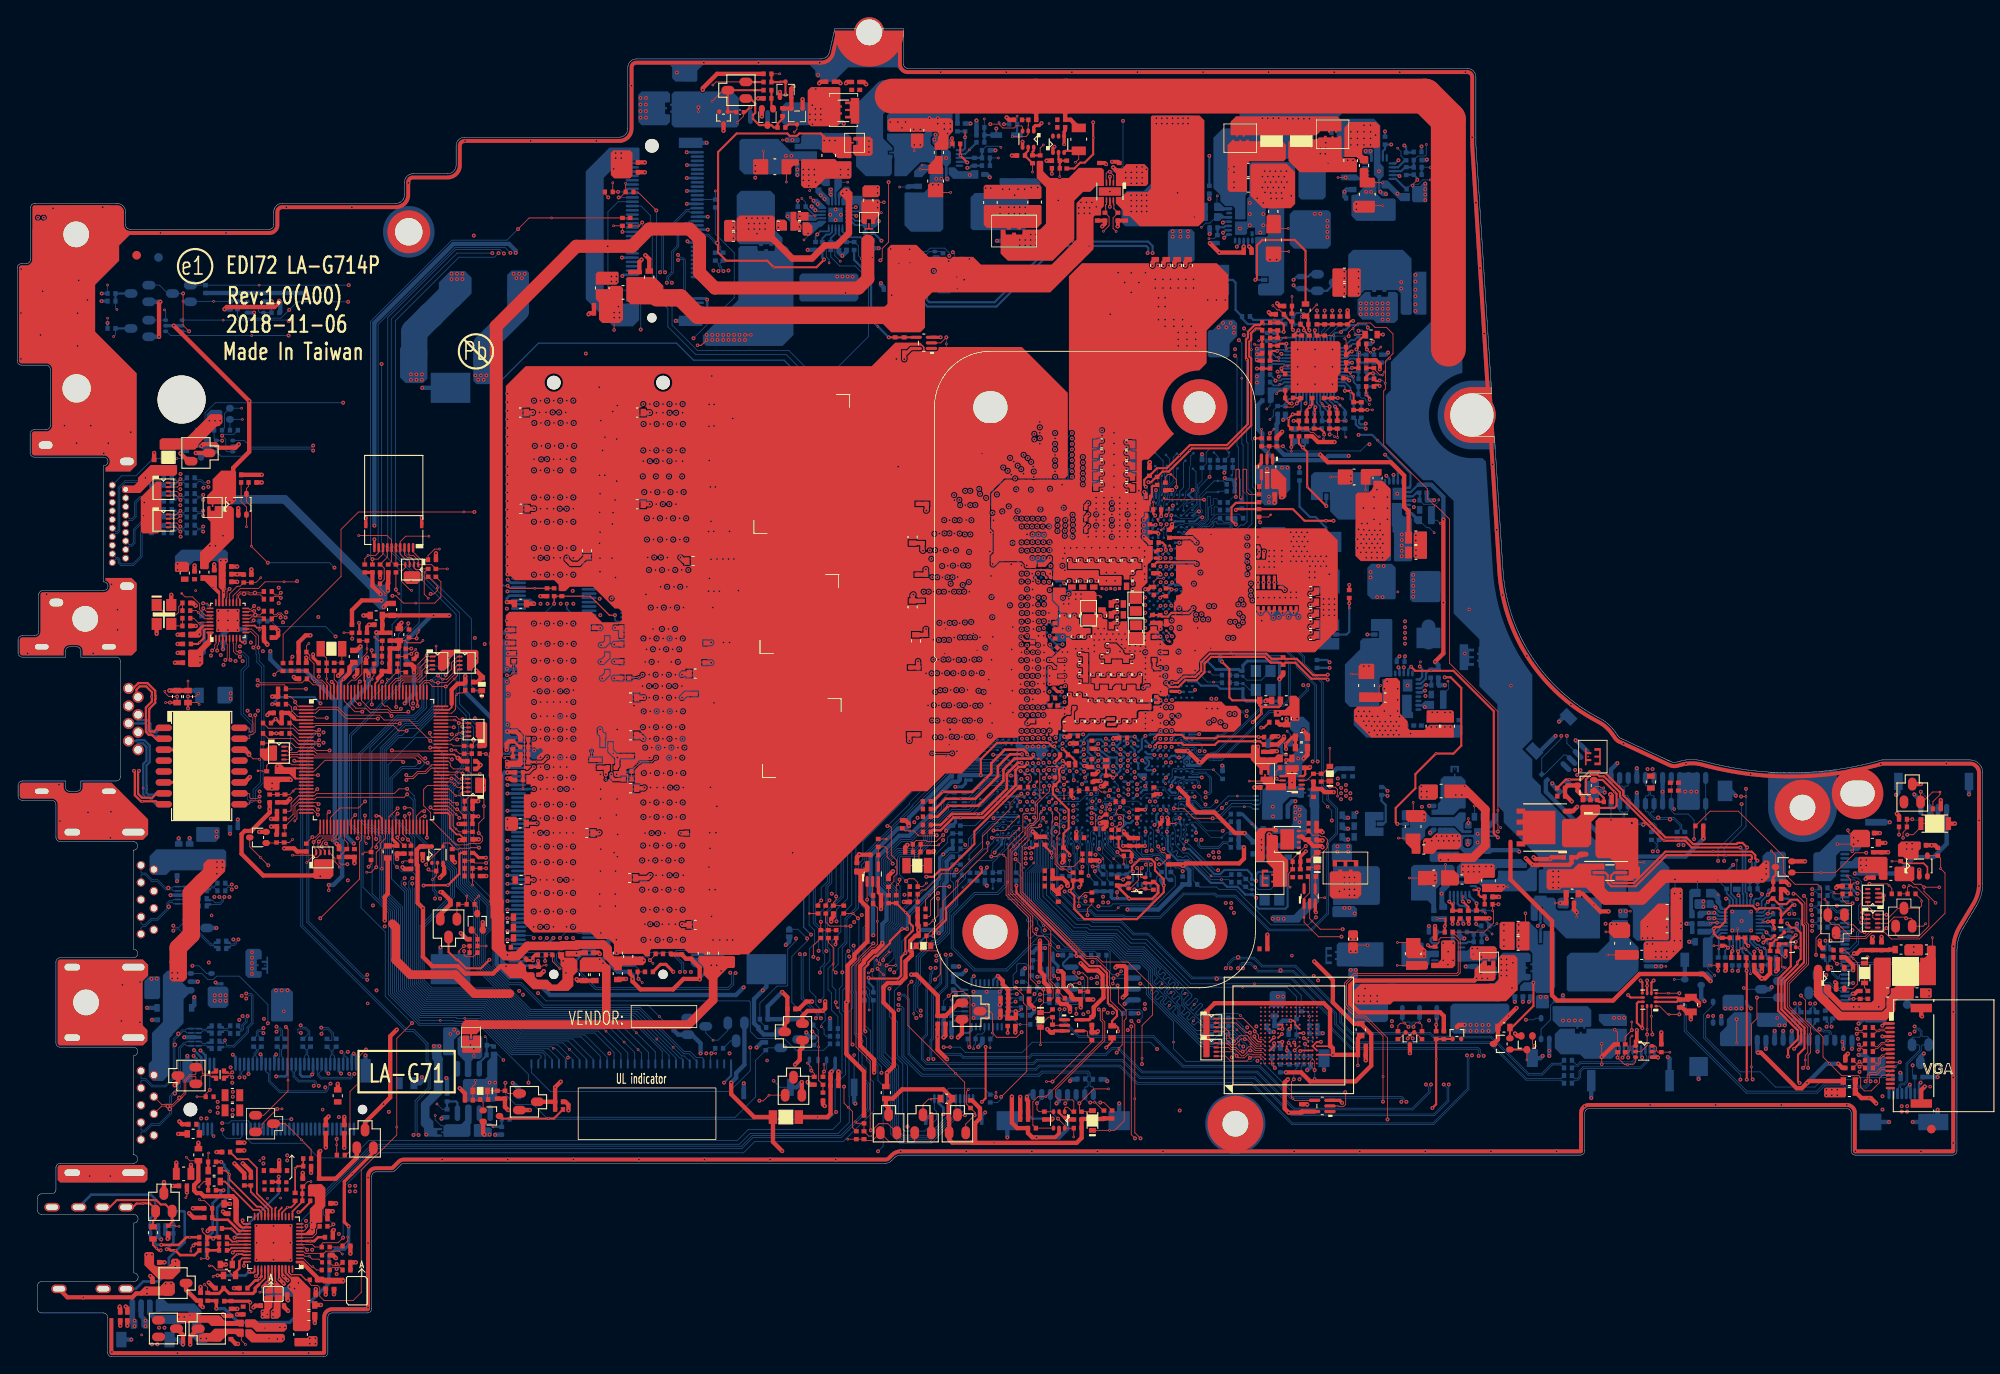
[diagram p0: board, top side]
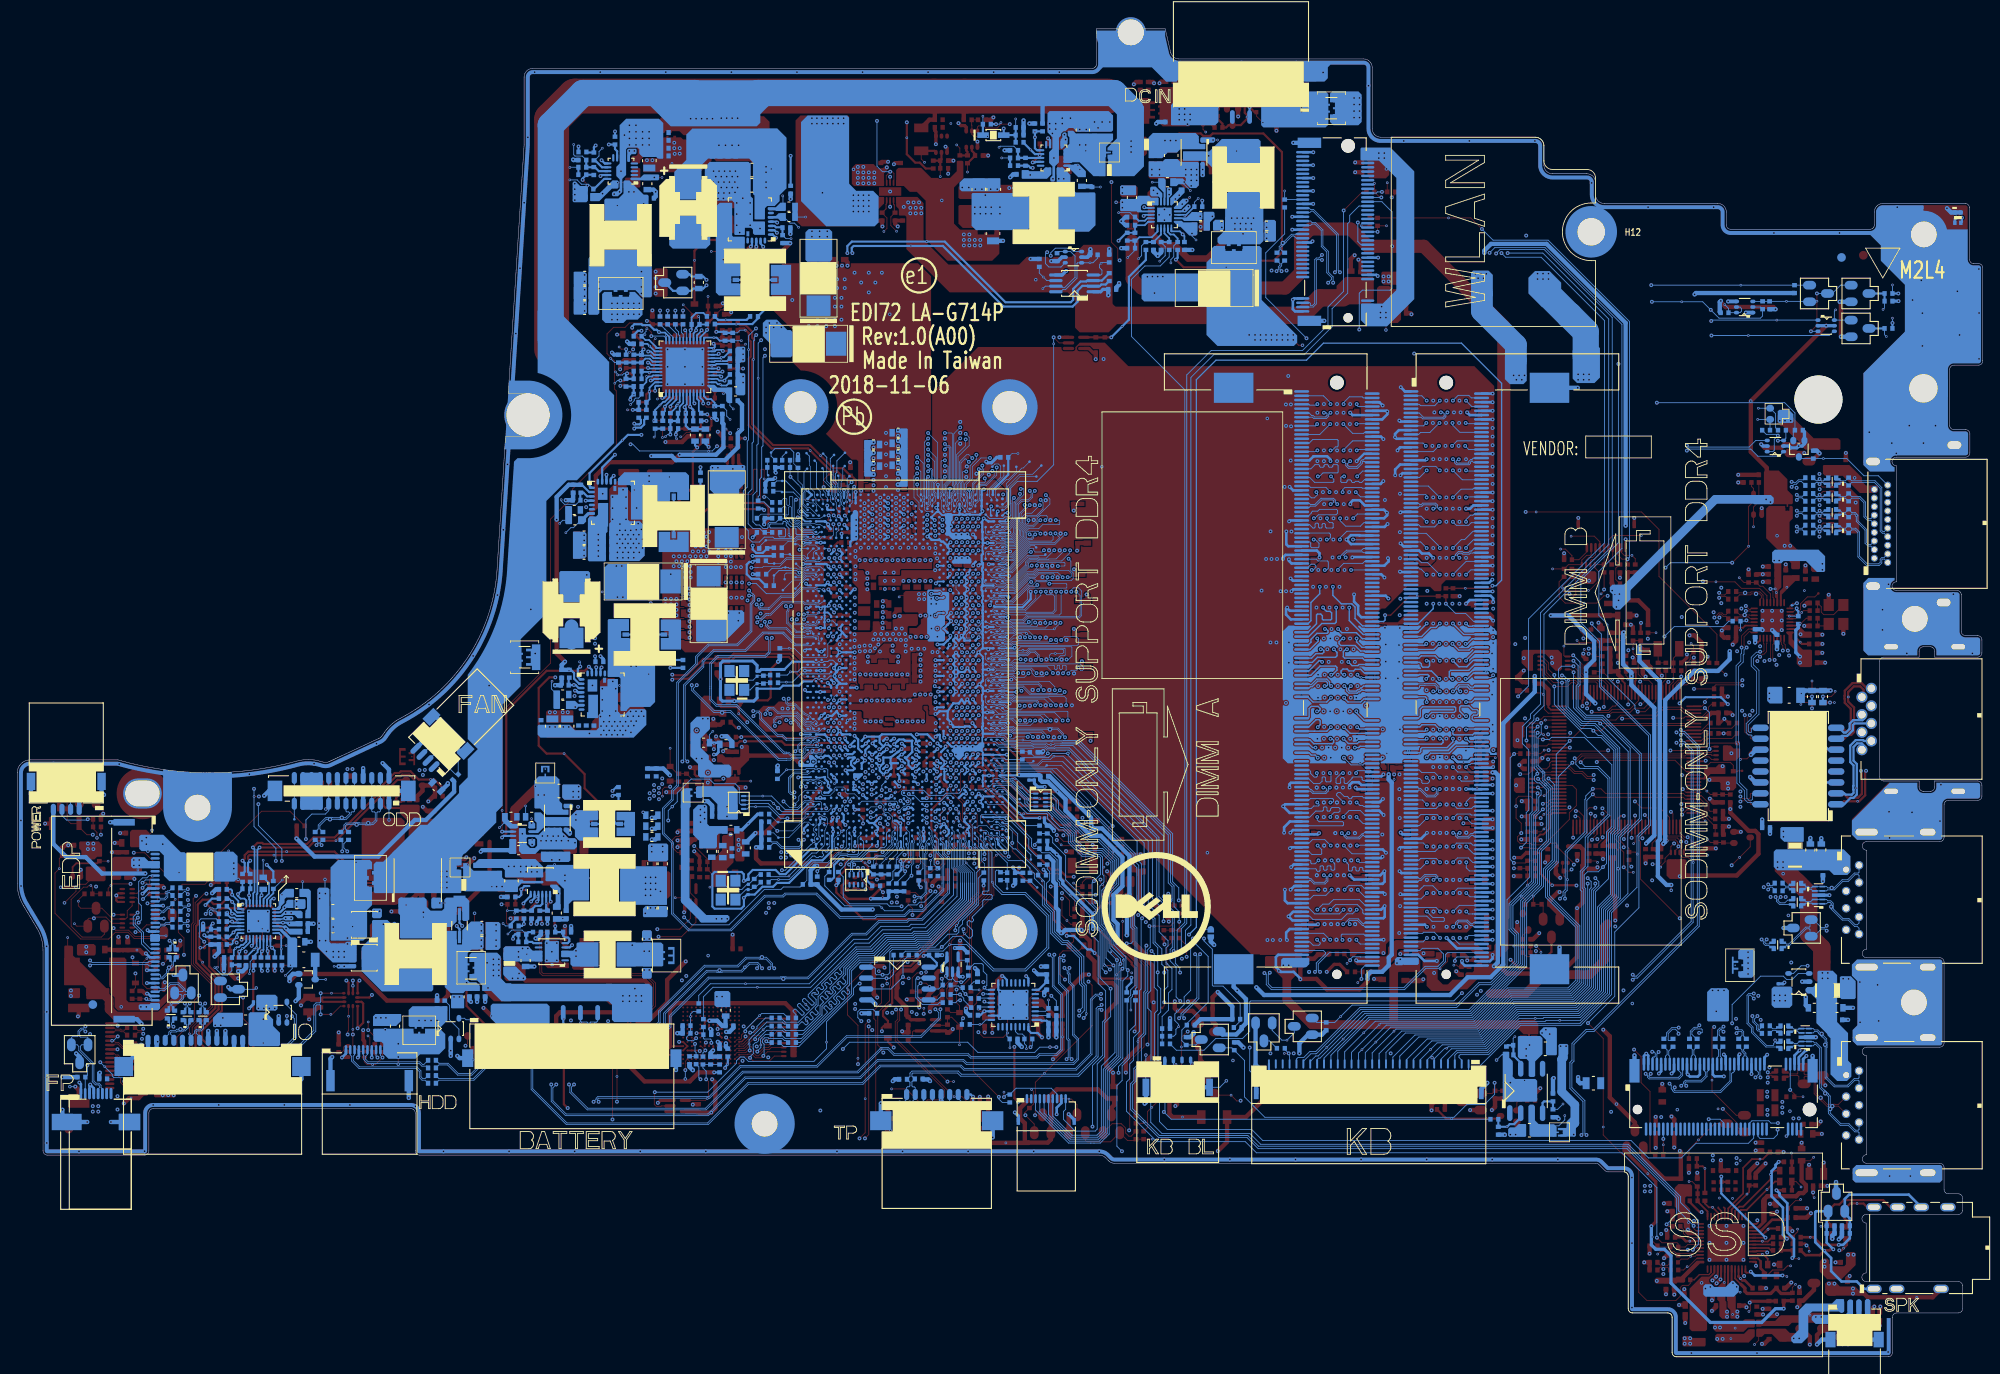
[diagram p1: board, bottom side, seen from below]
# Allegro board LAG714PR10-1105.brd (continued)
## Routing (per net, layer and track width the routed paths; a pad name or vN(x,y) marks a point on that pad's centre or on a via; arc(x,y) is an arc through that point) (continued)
DDR_B_DQS5: length 71
  IN2 w0.076: 105.16,74.66 105.18,74.68 105.25,74.68 105.56,74.99 112.41,74.99 112.81,75.4 113.26,75.4 115.03,77.16 115.03,77.6 116.21,78.79 116.96,78.79 117.49,78.79 117.74,78.54 117.74,78.49 v2(117.97,78.25)
  IN2 w0.168: v2(61.54,60.92) 61.39,60.76 61.39,60.35 61.53,60.21 66.75,60.21 67.16,59.8 68.69,59.8 69.19,59.3 72.24,59.3 72.54,59 77.48,59 78.29,59.82 81.54,59.82 82.13,60.4 84.62,60.4 86.75,62.53 89.67,62.53 101.24,74.1 104.6,74.1 105.16,74.66
  BOTTOM w0.076: v2(117.97,78.25) UC1.AR32
  BOTTOM w0.102: JDIMM2.200 59.11,60.49 59.26,60.64 59.41,60.64 59.73,60.32 61.03,60.32 61.25,60.53 61.25,60.81 61.37,60.94 61.52,60.94 v2(61.54,60.92)
DDR_B_DQS6: length 71.4
  IN2 w0.076: v2(117.97,75.51) 118.18,75.3 118.18,75.15 118.1,75.07 117.6,75.07 117.54,75.13 116.43,75.13 115.84,74.54 115.35,74.54 113.56,72.74 113.56,72.01 113.08,71.53 112.77,71.53 111.9,70.66 109.95,70.66 109.29,69.99 109.2,69.99 108.96,69.75 108.76,69.75 108.73,69.72 108.66,69.72
  IN2 w0.168: v2(63.83,55.45) 63.68,55.45 63.47,55.24 63.47,54.92 63.59,54.8 65.8,54.8 67.24,53.36 69.66,53.36 69.97,53.66 70.96,53.66 71.29,53.34 71.29,53.02 71.48,52.83 71.78,52.83 72.23,53.28 81.57,53.28 82.42,54.12 85.86,54.12 89.88,58.15 91.48,58.15 102.75,69.41 104.99,69.41 105.3,69.72 106.44,69.72 106.5,69.66 106.68,69.66 106.74,69.72 108.66,69.72 108.66,69.72
  BOTTOM w0.076: v2(117.97,75.51) 118.33,75.15 UC1.AR27
  BOTTOM w0.102: JDIMM2.221 66.22,55.24 66.22,55.24 65.65,55.24 65.49,55.39 65.26,55.39 64.77,55.88 63.62,55.88 63.52,55.78 63.52,55.65 63.72,55.45 v2(63.83,55.45)
DDR_B_DQS7: length 75.2
  IN2 w0.076: v2(118,71.94) 118,72.15 117.91,72.24 116.6,72.24 116.38,72.02 116.38,71.45 113.36,68.42 113.36,67.9 110.14,64.68 110,64.68 109.95,64.63 109.92,64.63 109.88,64.59 109.86,64.59
  IN2 w0.168: v2(60.78,49.99) 60.8,49.99 60.95,49.83 60.95,49.55 61.21,49.29 64.74,49.29 66.73,47.31 67.85,47.31 68.91,46.25 71.5,46.25 72.44,47.18 77.86,47.18 78.44,47.76 86.06,47.76 91.8,53.51 93.69,53.51 97.2,57.02 97.49,57.02 102.08,61.61 102.08,62.12 104.55,64.59 109.86,64.59
  BOTTOM w0.076: UC1.AR21 117.99,71.83 117.99,71.94 v2(118,71.94)
  BOTTOM w0.102: v2(60.78,49.99) 61.08,50.29 61.08,50.39 60.9,50.58 59.96,50.58 59.52,50.14 59.28,50.14 59.13,49.99 JDIMM2.242
DDR_B_DQS#0: length 75.9
  IN2 w0.076: v2(121.79,96.66) 121.64,96.51 121.49,96.51 121.42,96.59 121.42,98.12 118.82,100.71 118.82,100.78
  IN2 w0.168: v2(60.89,104.34) 61.04,104.5 61.04,104.78 61.32,105.06 65.67,105.06 67.01,106.4 67.66,106.4 67.77,106.28 68.28,106.28 68.74,106.74 68.74,106.77 71.11,109.15 77.33,109.15 77.86,109.68 92.5,109.68 93.01,110.19 106.11,110.19 110.88,105.42 113.48,105.42 114.03,104.87 114.4,104.87 114.95,105.42 115.62,105.42 117.64,103.41 117.64,101.96 118.82,100.78
  BOTTOM w0.076: v2(121.79,96.66) 122.16,96.92 UC1.AH66
  BOTTOM w0.102: JDIMM2.32 59.21,104.49 59.36,104.33 59.49,104.33 59.72,104.1 59.72,103.94 59.76,103.91 61.08,103.91 61.18,104.01 61.18,104.15 61,104.34 v2(60.89,104.34)
DDR_B_DQS#1: length 85.4
  IN2 w0.076: v2(122.56,103.59) 122.56,103.44 122.7,103.3 123.23,103.3 123.29,103.35 123.29,104.96 123.67,105.35 123.67,106.25 123.63,106.3 123.63,106.33 123.58,106.37 123.58,106.39
  IN2 w0.168: v2(62.97,109.81) 62.8,109.81 62.6,110.01 62.6,110.3 62.77,110.47 65.18,110.47 67.19,112.48 67.19,113.14 67.86,113.81 68.52,113.81 70.88,116.18 76.26,116.18 77.37,115.06 100.73,115.06 101.48,114.31 103.77,114.31 104.52,115.06 110.55,115.06 110.98,115.49 116.01,115.49 123.58,107.92 123.58,106.39
  BOTTOM w0.076: v2(122.56,103.59) 122.56,103.45 122.41,103.3 122.18,103.3 122.01,103.13 122.01,102.1 122.35,101.75 122.35,100.16 122.28,100 122.28,99.81 122.33,99.68 122.33,99.47 122.29,99.38 122.29,99.08 122.49,98.88 122.63,98.88 122.7,98.8 122.7,98.67 UC1.AG69
  BOTTOM w0.102: v2(62.97,109.81) 62.91,109.86 62.8,109.86 62.58,109.65 62.58,109.37 62.71,109.24 64.99,109.24 65.49,109.74 JDIMM2.11
DDR_B_DQS#2: length 68.6
  IN2 w0.076: v2(117.97,97.46) 117.59,97.08 115.75,97.08 115,97.84 115,98.53 114.07,99.45 112.19,99.45 111.55,100.1 111.16,100.1 111.12,100.15
  IN2 w0.168: 111.12,100.15 109.92,100.15 104.77,105.3 97.79,105.3 96.95,104.46 81.35,104.46 80.63,103.74 79.9,103.74 79.7,103.94 79.7,104.2 79.44,104.46 78.67,104.46 78.35,104.14 78.35,103.15 78.25,103.06 72.35,103.06 69.75,100.45 68.99,100.45 68.44,99.91 66.72,99.91 66.2,99.4 66.2,98.92 66.05,98.76 65.54,98.76 65.4,98.9 65.4,99.08 65.14,99.34 63.6,99.34 63.21,98.95 63.21,98.77 v2(63.05,98.61)
  BOTTOM w0.076: UC1.AR66 118.33,97.09 v2(117.97,97.46)
  BOTTOM w0.102: v2(63.05,98.61) 63.25,98.61 63.35,98.7 63.35,99.03 63.57,99.25 65.1,99.25 65.26,99.09 65.41,99.09 65.56,99.24 65.97,99.24 65.97,99.24 JDIMM2.53
DDR_B_DQS#3: length 67.6
  IN2 w0.076: 106.56,97.36 106.57,97.36 106.62,97.32 106.65,97.32 107.37,96.6 111.71,96.6 113.15,95.16 113.82,95.16 114.88,94.09 116.06,94.09 116.27,94.3 117.56,94.3 v2(117.97,94.71)
  IN2 w0.168: 106.56,97.36 105.93,97.36 103.45,99.84 85.13,99.84 83.12,97.83 80.09,97.83 78.1,95.85 71.47,95.85 69.18,93.55 66.85,93.55 65.65,92.35 61.44,92.35 61.25,92.54 61.25,92.67 61.47,92.89 v2(61.57,92.89)
  BOTTOM w0.076: UC1.AR61 118.33,94.35 v2(117.97,94.71)
  BOTTOM w0.102: v2(61.57,92.89) 61.27,93.19 61.27,93.3 60.94,93.63 60.47,93.63 60.35,93.51 59.74,93.51 59.57,93.68 59.42,93.68 59.12,93.99 JDIMM2.74
DDR_B_DQS#4: length 69
  IN2 w0.076: v2(117.31,81.97) 117.37,82.04 117.58,82.04 117.65,81.97 117.65,81.62 117.56,81.54 115.35,81.54 113.46,79.64 112.75,79.64 112.18,79.07 104.59,79.07 104.47,78.95 103.9,78.95
  IN2 w0.168: 103.9,78.95 102.63,78.95 102.17,78.48 99.42,78.48 87.85,66.91 79.57,66.91 77.81,65.15 72.47,65.15 72.13,65.49 71.52,65.49 71.28,65.25 71.28,64.96 71.16,64.84 70.71,64.84 70.59,64.96 70.59,65.4 70.34,65.65 68.08,65.65 67.98,65.55 66.42,65.55 66.08,65.9 65.13,65.9 64.78,65.55 63.61,65.55 63.52,65.64 63.52,65.89 63.64,66.01 v2(63.86,66.01)
  BOTTOM w0.076: UC1.AT38 117.68,81.76 117.44,82 117.33,82 v2(117.31,81.97)
  BOTTOM w0.102: JDIMM2.177 65.68,66.24 65.53,66.09 65.33,66.09 64.54,65.29 63.71,65.29 63.5,65.5 63.5,65.99 63.52,66 63.52,66.01 63.62,66.11 63.76,66.11 v2(63.86,66.01)
DDR_B_DQS#5: length 70.9
  IN2 w0.076: v2(117.34,78.25) 117.51,78.43 117.51,78.49 117.51,78.53 117.42,78.62 117.08,78.62 117.08,78.62 116.28,78.62 115.19,77.53 115.19,77.09 113.33,75.23 112.88,75.23 112.47,74.82 105.62,74.82 105.36,74.56 105.36,74.5 105.27,74.41
  IN2 w0.168: 105.27,74.41 104.71,73.85 101.35,73.85 89.77,62.27 86.86,62.27 84.73,60.14 82.23,60.14 81.65,59.56 78.4,59.56 77.58,58.74 72.43,58.74 72.13,59.05 69.08,59.05 68.59,59.54 67.06,59.54 66.64,59.95 61.42,59.95 61.13,60.25 61.13,60.51 60.78,60.86 v2(60.78,60.92)
  BOTTOM w0.076: v2(117.34,78.25) UC1.AT32
  BOTTOM w0.102: v2(60.78,60.92) 60.8,60.94 60.95,60.94 61.05,60.84 61.05,60.61 60.95,60.51 59.81,60.51 59.49,60.83 59.25,60.83 59.1,60.99 JDIMM2.198
DDR_B_DQS#6: length 71.4
  IN2 w0.076: v2(118.02,74.62) 117.73,74.91 117.53,74.91 117.47,74.96 116.5,74.96 115.91,74.38 115.42,74.38 113.72,72.68 113.72,71.94 113.15,71.36 112.84,71.36 111.97,70.49 110.02,70.49 109.36,69.83 109.26,69.83 109.01,69.58 108.96,69.58 108.92,69.54 108.85,69.54
  IN2 w0.168: v2(63.07,55.45) 63.21,55.3 63.21,54.82 63.49,54.54 65.69,54.54 67.14,53.1 69.77,53.1 70.08,53.4 70.86,53.4 71.03,53.23 71.03,52.92 71.37,52.57 71.89,52.57 72.34,53.02 81.68,53.02 82.52,53.87 85.96,53.87 89.99,57.89 91.59,57.89 102.85,69.15 105.1,69.15 105.41,69.46 106.34,69.46 106.4,69.4 106.78,69.4 106.85,69.46 108.77,69.46 108.85,69.54
  BOTTOM w0.076: UC1.AR25 118.33,74.31 v2(118.02,74.62)
  BOTTOM w0.102: v2(63.07,55.45) 63.13,55.45 63.33,55.65 63.33,55.86 63.54,56.07 64.85,56.07 65.34,55.58 65.48,55.58 65.63,55.74 66.45,55.74 JDIMM2.219
DDR_B_DQS#7: length 75.3
  IN2 w0.076: 109.86,64.84 110.07,64.84 113.19,67.97 113.19,68.49 116.22,71.52 116.22,72.09 116.53,72.41 117.9,72.41 117.97,72.47 v2(117.97,72.79)
  IN2 w0.168: v2(61.54,49.99) 61.37,49.99 61.21,49.83 61.21,49.65 61.31,49.55 64.85,49.55 66.83,47.57 67.95,47.57 69.02,46.5 71.39,46.5 72.33,47.44 77.76,47.44 78.34,48.02 85.95,48.02 91.7,53.76 93.59,53.76 97.09,57.27 97.38,57.27 101.82,61.71 101.82,62.23 104.44,64.84 109.86,64.84
  BOTTOM w0.076: UC1.AR22 117.97,72.77 v2(117.97,72.79)
  BOTTOM w0.102: v2(61.54,49.99) 61.27,50.26 61.27,50.47 60.98,50.77 59.88,50.77 59.44,50.33 59.3,50.33 59.14,50.49 JDIMM2.240
DDR_B_MA0: length 68.1
  IN2 w0.18: v2(110.85,85.44) 110.85,86.37 110.46,86.76 106.44,86.76 106.14,86.46 93.97,86.46 89.37,81.85 87.92,81.85 83.15,77.08 79.41,77.08 79.41,77.08 71.74,77.08 70.75,76.09 66.38,76.09 65.93,75.64 58.38,75.64 58.2,75.83 58.2,76.78 58.35,76.93 59.98,76.93 60.17,76.74 60.17,76.25 v2(60.05,76.13)
  BOTTOM w0.076: v2(110.85,85.44) 111.06,85.23 112.78,85.23 112.91,85.1 114.3,85.1 UC1.BA46
  BOTTOM w0.163: v2(60.05,76.13) 59.4,76.13 59.05,76.48 58.78,76.48 58.77,76.49 JDIMM2.144
DDR_B_MA1: length 70.1
  IN2 w0.18: v2(64.67,78.82) 64.94,79.09 67.22,79.09 67.48,79.36 69.9,79.36 71.83,81.28 80.89,81.28 81.16,81.56 83.43,81.56 87.12,85.26 87.43,85.26 87.93,84.76 88.16,84.76 88.46,85.05 88.46,85.31 87.94,85.82 87.94,86.08 88.23,86.36 88.48,86.36 89,85.85 89.25,85.85 89.5,86.1 89.5,86.36 88.99,86.87 88.99,87.13 89.24,87.38 89.5,87.38 90.01,86.87 90.27,86.87 90.52,87.12 90.52,87.37 90.01,87.89 90.01,88.14 90.29,88.43 90.55,88.43 91.06,87.91 91.31,87.91 91.6,88.2 91.6,88.45 91.07,88.99 91.07,89.2 91.34,89.48 91.64,89.48 92.13,88.98 92.38,88.98 92.85,89.45 104.76,89.45 105.1,89.78 105.37,89.78 105.6,89.56 105.6,89.23 105.33,88.96 v2(105.33,88.95)
  BOTTOM w0.076: v2(105.33,88.95) 104.89,88.51 104.89,86.24 105.04,86.08 110.97,86.08 111.49,85.56 112.92,85.56 113.02,85.46 113.58,85.46 113.76,85.64 114.03,85.64 114.14,85.58 114.28,85.58 114.51,85.65 114.65,85.65 114.86,85.57 114.96,85.47 UC1.AY46
  BOTTOM w0.163: v2(64.67,78.82) 64.33,79.16 64.5,79.32 65.47,79.32 65.57,79.23 66.22,79.23 66.23,79.24 JDIMM2.133
DDR_B_MA2: length 69.7
  IN2 w0.076: 100.34,90.92 105.02,90.92 105.28,90.66 105.57,90.66 106.13,90.09 106.92,90.09 107.69,89.32 v2(107.69,88.95)
  IN2 w0.18: 100.34,90.92 90.83,90.92 83.41,83.5 77.99,83.5 77.52,83.97 72.56,83.97 69.9,81.31 67.4,81.31 66.56,80.47 59.19,80.47 58.9,80.18 58.9,79.05 59.14,78.81 60.09,78.81 v2(60.1,78.82)
  BOTTOM w0.076: v2(107.69,88.95) 107.69,86.74 108.02,86.41 111.11,86.41 111.25,86.26 113.06,86.26 113.15,86.36 113.46,86.36 113.55,86.26 114.05,86.26 114.05,86.26 114.14,86.3 114.34,86.3 114.37,86.29 114.39,86.26 114.43,86.26 114.44,86.26 114.45,86.26 114.58,86.26 114.59,86.26 114.7,86.26 114.78,86.29 115.15,86.29 115.2,86.25 115.37,86.25 115.54,86.08 UC1.AY47
  BOTTOM w0.163: v2(60.1,78.82) 59.87,78.82 59.2,79.49 JDIMM2.132
DDR_B_MA3: length 69.6
  IN2 w0.18: v2(105.92,88.96) 106.14,89.18 106.14,89.4 105.39,90.15 104.97,90.15 104.76,89.94 91.15,89.94 83.24,82.02 80.97,82.02 80.7,81.74 79.7,81.74 79.5,81.95 79.5,82.39 79.31,82.58 78.94,82.58 78.78,82.41 78.78,81.95 78.58,81.74 78.28,81.74 78.1,81.92 78.1,82.4 77.92,82.58 77.56,82.58 77.38,82.4 77.38,81.92 77.2,81.74 71.64,81.74 69.74,79.85 67.32,79.85 67.02,79.55 62.95,79.55 62.81,79.41 62.81,79.16 v2(63.15,78.82)
  BOTTOM w0.076: v2(105.92,88.96) 105.92,89.14 105.64,89.41 105.09,89.41 104.72,89.05 104.72,86.17 104.98,85.91 110.91,85.91 111.42,85.4 112.85,85.4 112.95,85.29 113.84,85.29 UC1.BB46
  BOTTOM w0.163: JDIMM2.131 64.06,79.74 v2(63.15,78.82)
DDR_B_MA4: length 70.5
  IN2 w0.18: v2(107.1,88.95) 107.1,89.16 106.4,89.86 106.06,89.86 105.49,90.43 90.99,90.43 83.05,82.48 80.78,82.48 80.51,82.2 80.21,82.2 80.01,82.41 80.01,82.9 79.87,83.04 72.28,83.04 69.58,80.34 67.12,80.34 66.79,80.01 60.71,80.01 60.56,79.87 60.56,79.47 60.74,79.29 61.48,79.29 61.62,79.15 v2(61.62,78.82)
  BOTTOM w0.076: v2(107.1,88.95) 107.1,86.44 107.29,86.24 111.04,86.24 111.56,85.73 112.98,85.73 113.09,85.62 113.52,85.62 113.69,85.8 114.06,85.8 114.09,85.79 114.17,85.76 114.29,85.76 114.51,85.82 114.68,85.82 UC1.BA47
  BOTTOM w0.163: JDIMM2.128 59.05,80.49 59.73,79.81 61.83,79.81 62,79.65 62,79.05 61.77,78.82 v2(61.62,78.82)
DDR_B_MA5: length 69.6
  IN2 w0.076: v2(110.04,88.95) 110.41,89.32 110.96,89.32 111.06,89.42 111.06,90.13 109.99,91.2 105.44,91.2 104.99,91.65 101.08,91.65 100.43,92.3 100.34,92.3
  IN2 w0.18: 100.34,92.3 90.26,92.3 83.49,85.53 80.91,85.53 80.73,85.35 80.73,85.03 80.58,84.88 80.2,84.88 80.04,85.03 80.04,85.4 79.92,85.53 77.91,85.53 77.37,86.06 72.71,86.06 69.9,83.26 67.27,83.26 65.99,81.99 61.76,81.99 61.36,81.59 61.36,81.14 v2(61.57,80.93)
  BOTTOM w0.076: v2(110.04,88.95) 110.04,88.18 111.34,86.88 113.67,86.88 113.74,86.95 114.96,86.95 UC1.AY48
  BOTTOM w0.163: JDIMM2.126 59.2,80.99 59.96,80.23 60.87,80.23 v2(61.57,80.93)
DDR_B_MA6: length 68.6
  IN2 w0.076: 100.34,91.38 100.43,91.38 100.63,91.18 104.99,91.18 105.35,90.82 105.64,90.82 106.2,90.26 107.7,90.26 107.78,90.18 107.78,89.51 107.87,89.42 108.02,89.42 108.1,89.49 108.1,90.19 108.16,90.26 109.51,90.26 109.58,90.19 109.58,89.96 109.5,89.89 108.98,89.89 108.64,89.55 108.64,89.05 108.73,88.96 v2(108.87,88.96)
  IN2 w0.18: 100.34,91.38 90.64,91.38 83.22,83.96 78.18,83.96 77.05,85.08 73.03,85.08 69.74,81.8 67.19,81.8 66.32,80.93 v2(64.62,80.93)
  BOTTOM w0.076: v2(108.87,88.96) 108.87,88.71 108.76,88.59 108.04,88.59 107.85,88.41 107.85,86.83 108.11,86.57 111.18,86.57 111.2,86.55 113.53,86.55 113.65,86.43 114.02,86.43 114.11,86.46 114.13,86.46 114.37,86.46 114.46,86.43 114.67,86.43 114.75,86.46 114.86,86.5 114.93,86.64 114.87,86.78 114.64,86.78 114.57,86.71 UC1.BA48
  BOTTOM w0.163: v2(64.62,80.93) 64.38,80.93 64.29,80.84 64.29,80.74 64.28,80.74 64.28,80.35 64.45,80.18 65.07,80.18 65.24,80.35 65.24,80.55 65.43,80.74 JDIMM2.127
DDR_B_MA7: length 72.1
  IN2 w0.076: 100.6,92.68 101.16,92.12 105.57,92.12 106.32,91.36 110.06,91.36 112.34,89.08 112.34,88.42 113.01,87.75 118.36,87.75 v2(118.63,87.48)
  IN2 w0.18: v2(60.05,80.93) 59.39,80.93 59.29,81.03 59.29,82.22 59.53,82.45 65.76,82.45 67.06,83.75 69.74,83.75 72.55,86.55 77.53,86.55 78.1,85.99 81.04,85.99 81.21,86.17 81.21,86.88 81.44,87.11 84.42,87.11 90.07,92.76 100.52,92.76 100.6,92.68
  BOTTOM w0.076: UC1.AP48 118.98,86.95 118.62,87.39 118.63,87.48 v2(118.63,87.48)
  BOTTOM w0.163: JDIMM2.122 59.04,81.99 60.05,80.98 v2(60.05,80.93)
DDR_B_MA8: length 66.4
  IN2 w0.076: 100.34,91.84 100.4,91.84 100.82,91.42 104.99,91.42 105.38,91.03 109.92,91.03 110.21,90.74 110.21,89.93 110.32,89.82 110.32,89.47 110.17,89.32 109.54,89.32 109.45,89.24 v2(109.45,88.96)
  IN2 w0.18: v2(63.1,80.93) 62.94,81.09 62.94,81.39 63.08,81.53 66.23,81.53 66.99,82.29 69.58,82.29 72.87,85.57 77.21,85.57 77.72,85.07 78,85.07 78.13,84.95 78.13,84.68 78.32,84.48 78.71,84.48 78.89,84.65 78.89,84.89 79.07,85.07 79.43,85.07 79.61,84.89 79.61,84.57 79.76,84.42 83.03,84.42 90.45,91.84 100.34,91.84
  BOTTOM w0.076: UC1.BB48 113.88,86.66 113.66,86.66 113.6,86.72 111.27,86.72 109.45,88.53 v2(109.45,88.96)
  BOTTOM w0.163: JDIMM2.125 65.5,81.24 65.25,81.49 63.66,81.49 v2(63.1,80.93)
DDR_B_MA9: length 67.5
  IN2 w0.076: v2(118.67,88.28) 118.31,88.65 114.53,88.65 112.28,90.9 112.28,91.4 110.9,92.78 106.82,92.78 106.45,92.41 106.08,92.41 105.65,92.84 101.73,92.84 101.25,93.33
  IN2 w0.18: v2(63.14,82.9) 63.14,83.77 63.25,83.88 65.89,83.88 67.22,85.21 69.9,85.21 72.75,88.06 84.07,88.06 89.69,93.68 100.9,93.68 101.25,93.33
  BOTTOM w0.076: v2(118.67,88.28) 118.67,88.27 118.99,87.89 UC1.AP50
  BOTTOM w0.163: v2(63.14,82.9) 63.8,82.24 65.99,82.24 65.99,82.24 JDIMM2.121
DDR_B_MA10: length 70.4
  IN2 w0.18: v2(60.05,74.49) 60.75,75.18 66.12,75.18 66.57,75.63 70.94,75.63 71.5,76.19 77.43,76.19 77.82,76.58 78.53,76.58 78.71,76.4 78.71,75.7 78.89,75.52 79.25,75.52 79.43,75.7 79.43,76.4 79.61,76.58 83.3,76.58 88.11,81.39 89.56,81.39 94.16,86 106.33,86 106.6,86.27 108.01,86.27 v2(108.94,85.34)
  BOTTOM w0.076: v2(108.94,85.34) 108.94,85.67 109.01,85.75 110.41,85.75 110.48,85.67 110.48,85.2 110.62,85.07 112.71,85.07 112.84,84.94 114.56,84.94 114.8,85.18 115.26,85.18 115.85,85.47 UC1.AW46
  BOTTOM w0.163: v2(60.05,74.49) 60.19,74.49 60.79,75.08 60.79,75.53 60.63,75.69 59.72,75.69 59.28,75.25 58.79,75.25 58.63,75.09 58.63,74.77 58.79,74.6 59.17,74.6 59.33,74.44 59.33,74.15 59.17,73.99 JDIMM2.146
DDR_B_MA11: length 71.8
  IN2 w0.076: 101.58,93.65 102.07,93.16 108.49,93.16 108.68,92.97 110.94,92.97 112.44,91.47 112.44,90.97 114.6,88.82 118.68,88.82 118.9,88.6 119.44,88.6 119.66,88.38 119.66,87.85 v2(119.31,87.5)
  IN2 w0.18: v2(61.62,82.9) 61.62,83.26 62.69,84.34 65.7,84.34 67.03,85.67 69.71,85.67 72.59,88.55 72.59,88.82 72.87,89.09 73.9,89.09 74.44,88.55 83.91,88.55 89.5,94.14 101.09,94.14 101.58,93.65
  BOTTOM w0.076: v2(119.31,87.5) 119.27,87.5 119.26,87.34 119.6,86.94 UC1.AN48
  BOTTOM w0.163: JDIMM2.120 59.38,82.49 59.7,82.17 60.89,82.17 v2(61.62,82.9)
DDR_B_MA12: length 71.1
  IN2 w0.076: v2(119.29,88.23) 119.22,88.3 119.11,88.3 119.04,88.23 119.04,87.88 118.96,87.8 118.8,87.8 118.69,87.91 113.09,87.91 112.65,88.35 112.65,88.78
  IN2 w0.18: 112.65,88.78 112.65,89.88 112.14,90.39 111.36,90.39 111.18,90.57 111.18,90.89 111.35,91.05 111.58,91.05 111.77,91.24 111.77,91.55 111.58,91.74 111.15,91.74 110.93,91.95 110.93,92.27 110.77,92.43 107.38,92.43 106.65,91.7 106.31,91.7 105.51,92.5 101.43,92.5 100.71,93.22 89.88,93.22 84.23,87.57 80.48,87.57 80.3,87.39 80.3,86.63 80.12,86.45 79.81,86.45 79.63,86.63 79.63,87.39 79.45,87.57 79.11,87.57 78.9,87.37 78.9,86.6 78.75,86.45 78.39,86.45 78.2,86.64 78.2,87.43 78.05,87.57 72.91,87.57 69.58,84.24 66.9,84.24 66.08,83.42 64.81,83.42 64.67,83.27 v2(64.67,82.9)
  BOTTOM w0.076: v2(119.29,88.23) 119.61,87.86 UC1.AN50
  BOTTOM w0.163: JDIMM2.119 64.82,82.74 v2(64.67,82.9)
DDR_B_MA13: length 67
  IN2 w0.076: 105.93,81.39 106.17,81.39 106.23,81.45 109.75,81.45 111.3,83 v2(111.3,83.65)
  IN2 w0.18: 105.93,81.39 101.82,81.39 101.38,80.94 98.41,80.94 86.83,69.37 78.32,69.37 77.6,68.65 72.66,68.65 72.54,68.53 72.54,68.26 72.39,68.11 72.05,68.11 71.9,68.26 71.9,69.05 71.72,69.23 71.38,69.23 71.2,69.05 71.2,68.64 71.05,68.49 70.69,68.49 70.48,68.69 70.48,69.05 70.3,69.23 69.55,69.23 69.08,69.69 65.26,69.69 65.26,69.7 v2(64.62,69.7)
  BOTTOM w0.076: v2(111.3,83.65) 111.73,84.08 112.29,84.08 112.47,83.91 112.56,83.91 113.14,83.33 113.58,83.33 113.69,83.45 113.79,83.45 113.8,83.45 114.05,83.45 114.19,83.39 114.3,83.39 114.39,83.43 114.42,83.45 114.66,83.45 UC1.BA43
  BOTTOM w0.163: JDIMM2.158 61.17,70.99 61.99,70.18 64.14,70.18 v2(64.62,69.7)
DDR_B_ODT0: length 69.6
  IN2 w0.076: v2(107.69,83.35) 107.69,83.5 107.37,83.82 106.41,83.82 105.6,83.01
  IN2 w0.18: v2(64.62,71.87) 66.11,71.87 66.21,71.98 70.03,71.98 70.36,72.3 77.83,72.3 77.94,72.19 77.94,71.72 78.22,71.43 83.98,71.43 84.16,71.61 84.16,72.35 84.34,72.54 84.7,72.54 84.88,72.35 84.88,71.61 85.06,71.43 85.63,71.43 85.82,71.62 85.82,71.9 85.49,72.24 85.49,72.49 85.74,72.75 86,72.75 86.52,72.23 86.77,72.23 86.99,72.45 86.99,72.7 86.14,73.55 86.14,73.75 86.43,74.04 86.68,74.04 87.5,73.22 87.76,73.22 88.01,73.47 88.01,73.73 87.19,74.54 87.19,74.8 87.45,75.05 87.7,75.05 88.52,74.24 88.78,74.24 89.03,74.49 89.03,74.75 88.31,75.46 88.31,75.66 88.57,75.91 88.88,75.91 89.54,75.26 89.8,75.26 97.55,83.01 105.6,83.01
  BOTTOM w0.076: v2(107.69,83.35) 107.51,83.17 107.51,83.01 107.58,82.94 112.16,82.94 112.2,82.98 112.73,82.98 112.91,82.8 113.65,82.8 113.69,82.75 114.02,82.75 114.28,82.87 114.42,83.02 UC1.BA42
  BOTTOM w0.163: JDIMM2.155 64.76,71.74 v2(64.62,71.87)
DDR_B_ODT1: length 70.8
  IN2 w0.18: v2(61.57,71.87) 61.37,71.87 61.24,71.74 61.24,71.07 61.35,70.95 66.5,70.95 66.61,70.85 70.16,70.85 70.62,70.39 77.73,70.39 77.86,70.51 86.36,70.51 97.93,82.09 108.42,82.09 108.5,82.17 108.5,82.98 108.68,83.16 108.98,83.16 109.16,82.98 109.16,82.53 109.36,82.33 109.68,82.33 109.83,82.47 109.83,83.12 109.54,83.4 v2(109.54,83.64)
  BOTTOM w0.076: v2(109.54,83.64) 109.54,83.34 109.61,83.27 112.01,83.27 112.3,83.56 112.64,83.56 113.07,83.13 113.61,83.13 113.76,83.28 113.82,83.28 113.82,83.28 114.02,83.28 114.11,83.25 114.13,83.23 114.35,83.23 114.46,83.28 114.67,83.28 114.75,83.25 115.03,83.25 115.06,83.28 115.44,83.28 115.71,83.02 UC1.AW42
  BOTTOM w0.163: JDIMM2.161 65.43,70.24 65.31,70.35 65.31,70.67 65.16,70.82 62.25,70.82 61.57,71.5 v2(61.57,71.87)
DDR_B_PAR: length 72.1
  IN2 w0.076: 117.02,84.18 118.55,84.18 118.72,84.35 v2(118.72,84.63)
  IN2 w0.18: 117.02,84.18 116.98,84.13 113.98,84.13 113.79,83.94 113.79,83.02 113.64,82.86 113.13,82.86 112.95,83.04 112.95,83.88 112.7,84.13 111.67,84.13 111.48,84.32 111.48,86.56 110.88,87.16 106.19,87.16 105.95,86.92 93.78,86.92 89.18,82.31 87.64,82.31 84.26,78.93 83.32,78.93 83.14,78.75 83.14,77.72 82.96,77.54 82.6,77.54 82.42,77.72 82.42,78.63 82.24,78.81 81.88,78.81 81.7,78.63 81.7,77.72 81.52,77.54 81.16,77.54 80.98,77.72 80.98,78.28 80.8,78.46 80.44,78.46 80.26,78.28 80.26,77.72 80.08,77.54 79.71,77.54 79.53,77.72 79.53,78.28 79.35,78.46 78.99,78.46 78.81,78.28 78.81,77.72 78.63,77.54 71.55,77.54 70.56,76.55 66.19,76.55 65.74,76.1 64.65,76.1 v2(64.62,76.13)
  BOTTOM w0.076: v2(118.72,84.63) 118.72,84.62 118.98,84.3 UC1.AP43
  BOTTOM w0.163: JDIMM2.143 64.78,76.74 64.62,76.58 v2(64.62,76.13)
DDR_B_RAS#: length 68.9
  IN2 w0.18: v2(61.57,72.93) 61.44,73.06 61.44,73.46 61.54,73.57 65.45,73.57 65.63,73.74 66.63,73.74 67.03,74.14 84.26,74.14 93.74,83.62 93.99,83.62 94.81,82.8 95.07,82.8 95.32,83.06 95.32,83.31 94.51,84.13 94.51,84.39 94.74,84.62 94.99,84.62 95.79,83.82 96.08,83.82 96.88,84.62 104.99,84.62 105.4,84.2 105.78,84.2 106.3,84.72 109.97,84.72 110.12,84.87 v2(110.12,85.38)
  BOTTOM w0.076: v2(110.12,85.38) 110.09,85.38 109.85,85.14 109.85,84.98 109.93,84.9 112.64,84.9 112.77,84.77 114.14,84.77 114.31,84.61 114.72,84.61 114.8,84.53 115.34,84.53 115.47,84.4 115.54,84.4 115.71,84.24 UC1.AW44
  BOTTOM w0.163: JDIMM2.152 59.1,72.49 59.28,72.31 61.45,72.31 61.57,72.43 v2(61.57,72.93)
DDR_B_WE#: length 72
  IN2 w0.18: v2(64.62,72.93) 64.72,73.02 65.63,73.02 65.74,73.13 66.72,73.13 67.27,73.68 84.45,73.68 88.65,77.88 88.9,77.88 89.72,77.06 89.98,77.06 90.23,77.32 90.23,77.57 89.41,78.39 89.41,78.64 89.67,78.9 89.92,78.9 90.74,78.08 91,78.08 91.25,78.34 91.25,78.59 90.43,79.41 90.43,79.66 90.67,79.9 90.93,79.9 91.74,79.08 92,79.08 92.25,79.34 92.25,79.59 91.44,80.41 91.44,80.67 91.69,80.92 91.95,80.92 92.77,80.1 93.02,80.1 93.28,80.36 93.28,80.62 92.46,81.43 92.46,81.69 92.71,81.94 92.97,81.94 93.79,81.13 94.04,81.13 94.3,81.38 94.3,81.64 93.48,82.45 93.48,82.71 93.7,82.93 94.04,82.93 94.8,82.16 95.08,82.16 97.07,84.16 104.45,84.16 104.68,83.93 105.91,83.93 106.43,84.45 109.33,84.45 110.13,83.65 v2(110.13,83.64)
  BOTTOM w0.076: v2(110.13,83.64) 110.9,84.41 112.43,84.41 112.6,84.24 113.59,84.24 113.75,84.07 114.03,84.07 114.14,84.13 114.28,84.13 114.51,84.07 114.65,84.07 114.86,84.14 114.87,84.14 114.97,84.24 UC1.AY44
  BOTTOM w0.163: v2(64.62,72.93) 64.81,72.74 JDIMM2.151
DDR_VTT_CNTL: length 29.4
  TOP w0.102: v2(107.97,118.53) 107.32,117.88 UC2.2
  BOTTOM w0.102: v2(107.97,118.53) v1(107.97,117.78) 107.97,103.71 109.89,101.79 112.18,101.79 112.96,101 112.96,99.25 112.94,99.22 112.94,97.82 113.1,97.66 113.64,97.66 113.83,97.46 115.4,97.46 UC1.AW67
DIFFOUT_2PH_CPU: length 4
  BOTTOM w0.203: PRZ21.1 154.29,110.07 v1(153.71,110.65) 153.32,111.04 153.13,111.04 152.61,111.56 PUZ01.2
  BOTTOM w0.254: PRZ20.1 154.28,109.69 PRZ21.1
DIMM_CHA_SA0: length 5.2
  TOP w0.102: v1(73.87,45.74) 73.51,46.1 v2(73.51,46.11) 74.18,46.78 RD4.1 RD1.2
  BOTTOM w0.102: JDIMM1.256 72.33,46.49 72.35,46.51 73.22,46.51 73.51,46.22 v2(73.51,46.11)
DIMM_CHA_SA1: length 4.9
  TOP w0.102: RD5.1 RD2.2 72.09,44.05 v2(72.2,43.93) v1(72.63,43.51)
  BOTTOM w0.102: v2(72.2,43.93) 72.2,45.08 71.79,45.49 JDIMM1.260
DIMM_CHA_SA2: length 8.1
  TOP w0.102: v2(74.24,69.65) 73.78,69.19 72.46,69.19 v1(72.35,69.08) 71.39,68.12 RD6.1 RD3.2
  BOTTOM w0.102: v2(74.24,69.65) 73.4,68.82 72.04,68.82 71.87,68.99 JDIMM1.166
DIMM_CHB_SA0: length 6.9
  TOP w0.102: v1(63.06,45.11) 62.19,45.98 RD13.2 RD16.1 61.34,46.65 v2(61.34,46.03)
  BOTTOM w0.102: JDIMM2.256 61.1,46.49 61.34,46.24 v2(61.34,46.03)
DIMM_CHB_SA1: length 5.2
  TOP w0.102: RD17.1 60.94,45.34 61.13,45.54 61.46,45.54 v1(61.46,45.53)
  TOP w0.305: v2(60.52,46.03) 60.58,45.96 RD17.1 RD14.2
  BOTTOM w0.305: JDIMM2.260 60.2,45.49 60.52,45.81 v2(60.52,46.03)
DIMM_CHB_SA2: length 5.4
  TOP w0.102: RD18.1 v1(58.77,66.05)
  TOP w0.305: RD18.1 RD15.2 59.43,67.94 v2(60.05,68.57)
  BOTTOM w0.102: JDIMM2.166 59.44,68.99 59.58,68.85 59.77,68.85 v2(60.05,68.57)
DMIC_CLK: length 2.9
  TOP w0.102: UA1.3 33.26,11.85 33.42,11.69 v1(33.94,11.69) 34.27,11.36 35.04,11.36 L5.2
DMIC_CLK_EDP: length 219.4
  TOP w0.102: CA9.1 37.47,10.65 37.26,10.65 v2(37.12,10.79) 36.97,10.64 36.62,10.64 L5.1
  IN2 w0.127: v2(219.93,45.5) 219.77,45.66 219.61,45.66 218.56,44.62 218.56,36.25 216.9,34.59 216.56,34.59 214.39,32.42 213.56,32.42 212.59,33.4 210.81,33.4 209.97,34.23 207.28,34.23 206.31,33.27 197.31,33.27 195.59,31.55 177.24,31.55 176.52,30.83 157.08,30.83 156.33,30.08 139.7,30.08 134.3,24.68 101.62,24.68 101.32,24.39 88.76,24.39 88.1,23.73 41.79,23.73 39.97,21.91 39.97,14.36 37.86,12.25 37.16,12.25 36.62,11.71 36.62,10.78 36.74,10.66 36.99,10.66 v2(37.12,10.79)
  BOTTOM w0.102: JEDP1.31 213.07,45.45 213.23,45.61 219.82,45.61 v2(219.93,45.5)
DMIC_DATA: length 3.1
  TOP w0.102: RA42.2 34.77,10.09 34.39,10.47 v1(34.35,10.47) 34.19,10.47 33.22,11.45 UA1.2
DMIC_DATA_EDP: length 220.3
  TOP w0.102: CA40.1 37.47,10.42 37.33,10.42 v2(37.12,10.21) 36.91,10.41 36.62,10.41 RA42.1
  IN2 w0.127: v2(37.12,10.21) 36.91,10.41 36.63,10.41 36.36,10.68 36.36,11.81 37.05,12.5 37.75,12.5 39.71,14.47 39.71,22.01 41.69,23.99 87.99,23.99 88.65,24.64 101.22,24.64 101.51,24.94 134.19,24.94 139.59,30.34 156.23,30.34 156.98,31.09 176.41,31.09 177.14,31.81 195.49,31.81 197.2,33.52 206.21,33.52 207.17,34.49 210.08,34.49 210.92,33.65 212.69,33.65 213.67,32.67 214.28,32.67 216.45,34.84 216.79,34.84 218.31,36.36 218.31,44.73 219.5,45.92 219.77,45.92 v2(219.93,46.08)
  BOTTOM w0.102: JEDP1.30 213.1,45.95 213.2,45.84 219.69,45.84 v2(219.93,46.08)
DRVON: length 104.5
  TOP w0.254: v2(161.97,80.23) 162.44,79.76 v1(164.28,79.76) 166.89,79.76 171.57,75.07 171.57,60.86 172.05,60.38 v2(172.06,60.38)
  IN1 w0.254: v2(153.83,119.15) 153.76,119.08 152.92,119.08 149.39,122.61 149.39,128.01 147.61,129.79 142.26,129.79 141.72,129.24 v2(141.72,129.07) ; v2(158.94,104.88) 158.94,106.01 157.58,107.37 156.56,107.37 156.22,107.72 156.22,112.96 154.47,114.71 154.47,117 155.87,118.4 156.35,118.4 156.94,118.99 v2(156.94,119.65)
  IN2 w0.254: v2(158.94,104.88) 163.01,100.81 163.01,81.27 v2(161.97,80.23)
  BOTTOM w0.203: v2(153.83,119.15) 153.76,119.08 153.12,119.08 152.61,118.56 PUZ01.35
  BOTTOM w0.254: v2(153.83,119.15) 154.1,119.41 154.39,119.41 154.92,119.95 155.75,119.95 155.86,120.06 156.69,120.06 156.94,119.8 v2(156.94,119.65) ; v2(141.72,129.07) 141.72,129.12 142.02,129.42 PUG01.16 ; v2(161.97,80.23) 161.62,79.88 161.62,79.73 PUI01.16 ; v2(172.06,60.38) 171.88,60.56 PUA01.3 ; PUI02.16 160.43,103.4 v2(158.94,104.88)
EC_AGND: length 12.3
  TOP w0.127: RE50.2 45.06,83.27 45.32,83.02 46.87,83.02 v1(47.15,83.29)
  TOP w0.203: 41.89,78.87 41.89,78.6 41.6,78.31 UE1.112
  TOP w0.508: 41.89,78.87 42.37,79.35 CE30.2 42.39,79.69 CE1.2 RE4.1 43.3,80.61 CE2.2 RE6.1 44.22,82.35 CE25.2 44.39,82.51 RE50.2 43.32,83.27 CE21.2
EC_MUTE#: length 98.3
  TOP w0.102: v2(45.88,38.79) 44.1,37.02 v1(44.1,26.72) 44.1,25.78 41.67,23.35 41.62,23.35 39.98,21.71 39.98,7.49 39.02,6.54 35.66,6.54 35.15,7.04 35.15,8.06 34.91,8.3 34.21,8.3 33.99,8.52 RA8.2 ; v2(45.44,85.28) 45.44,84.65 RE28.2
  TOP w0.152: RA8.2 33.54,8.95 32.93,9.55 31.83,9.55 31.58,9.8 UA1.47
  BOTTOM w0.102: v2(45.44,85.28) 45.44,85.15 44.33,84.04 44.33,78 38.6,72.28 38.6,61.81 39.96,60.46 39.96,52.21 42.77,49.39 42.77,41.91 v2(45.88,38.79)
EDP_AUX: length 2.9
  BOTTOM w0.097: C11.2 210.71,54.17 210.91,54.17 211.1,53.99 211.1,53.51 211.29,53.31 211.81,53.31 211.95,53.45 JEDP1.15
EDP_AUX#: length 2.9
  BOTTOM w0.097: C10.2 210.71,53.99 210.83,53.99 210.91,53.91 210.91,53.43 211.21,53.13 211.77,53.13 211.95,52.95 JEDP1.16
EDP_AUX_DN: length 92.4
  IN2 w0.122: v2(134.07,84.69) 134.07,84.9 134.33,85.16 135.34,85.16 135.74,84.76 135.74,81.68 138,79.42 141.85,79.42 142.78,78.49 142.78,76.62 143.07,76.33 143.76,76.33 145.02,75.07 146.26,75.07 146.64,74.69 148.83,74.69 155.87,67.64 175.34,67.64 182.11,60.88 197.19,60.88 199.51,58.55 202.87,58.55 207.32,54.1 208.26,54.1 208.57,53.79 v2(208.58,53.79)
  BOTTOM w0.097: C10.1 208.98,54.1 208.87,54.1 208.58,53.8 v2(208.58,53.79) ; UC1.E45 134.07,84.86 134.07,84.7 v2(134.07,84.69)
EDP_AUX_DP: length 92.5
  IN2 w0.122: v2(208.58,54.37) 208.55,54.35 207.42,54.35 202.97,58.8 199.62,58.8 197.29,61.13 182.21,61.13 175.45,67.89 155.98,67.89 148.93,74.94 146.74,74.94 146.36,75.31 145.12,75.31 143.86,76.58 143.18,76.58 143.03,76.72 143.03,78.6 141.96,79.67 138.1,79.67 135.99,81.78 135.99,84.87 135.45,85.41 135.01,85.41 134.97,85.37 134.39,85.37 v2(134.15,85.61)
  BOTTOM w0.097: C11.1 209.21,54.29 208.66,54.29 v2(208.58,54.37) ; UC1.F45 133.62,85.56 134.1,85.56 v2(134.15,85.61)
EDP_BKLT_CTRL: length 13.5
  TOP w0.102: R8.2 R9.2 219.67,54.62 v1(219.85,54.8) 220.07,54.8 220.26,54.61 220.7,54.61 222.13,53.17 222.13,50.07 220.86,48.8 218.6,48.8 218.27,49.13 D3.2
EDP_COMP: length 1.9
  TOP w0.102: v2(134.15,89.22) v1(134.72,89.22)
  TOP w0.254: v2(134.15,89.22) 134.02,89.35 RC4.2
  BOTTOM w0.254: v2(134.15,89.22) 134.15,89.18 133.82,88.86 UC1.E52
EDP_HPD: length 115
  TOP w0.102: v2(213.83,54.53) 214.47,53.89 RP1.6
  IN1 w0.127: v2(213.83,54.53) 212.19,52.88 212.19,48.83 211.32,47.96 208.58,47.96 207.55,46.93 207.55,45.97 201.67,40.09 196.2,40.09 195.86,39.75 194.24,39.75 193.57,39.07 192.43,39.07 191.55,39.96 178.91,39.96 177.56,38.62 175.29,38.62 174.63,39.28 173.16,39.28 170.25,42.18 160.49,42.18 158.84,43.83 154.93,43.83 152.41,46.35 152.41,46.72 150.49,48.64 150.49,56.94 149.21,58.22 144.66,58.22 142.48,60.39 141.9,60.39 v2(138.08,64.21)
  BOTTOM w0.076: UC1.L10 131.1,65.45 131.95,65.45 132.19,65.69 132.19,66.06 132.37,66.24 133.28,66.24 133.47,66.05 133.47,65.73 133.93,65.27 134.76,65.27 134.92,65.44 134.92,65.71 135.09,65.87 136.85,65.87 137.58,65.15 137.58,64.72 v2(138.08,64.21)
  BOTTOM w0.102: v2(213.83,54.53) 213.41,54.95 JEDP1.12
EDP_TX0: length 2.4
  BOTTOM w0.097: C7.2 210.67,52.11 210.9,52.11 211.38,51.63 211.68,51.63 211.86,51.45 JEDP1.19
EDP_TX0#: length 2.4
  BOTTOM w0.097: C6.2 210.75,52.29 210.98,52.29 211.46,51.82 211.68,51.82 211.81,51.95 JEDP1.18
EDP_TX0_DN: length 96.6
  IN2 w0.122: v2(136.98,86.31) 136.77,86.1 136.4,86.1 136.18,85.89 136.18,85.49 136.5,85.17 136.5,83.14 137.77,81.88 137.77,80.72 138.38,80.1 141.92,80.1 142.45,80.63 146.38,80.63 147.1,79.91 147.1,77.47 156.25,68.32 175.73,68.32 182.5,61.55 197.65,61.55 199.01,60.19 202.18,60.19 207.59,54.79 208.77,54.79 209.14,54.41 209.14,52.53 209.06,52.45 208.53,52.45 v2(208.45,52.53)
  BOTTOM w0.076: UC1.C47 135.5,86.29 136.96,86.29 v2(136.98,86.31)
  BOTTOM w0.097: C6.1 209.17,52.41 208.57,52.41 v2(208.45,52.53)
EDP_TX0_DP: length 96.6
  IN2 w0.122: v2(208.45,51.95) 208.7,52.2 209.16,52.2 209.39,52.43 209.39,54.52 208.87,55.04 207.69,55.04 202.29,60.44 199.11,60.44 197.75,61.8 182.6,61.8 175.84,68.57 156.35,68.57 147.35,77.57 147.35,80.01 146.48,80.87 142.35,80.87 141.82,80.35 138.49,80.35 138.01,80.82 138.01,81.98 136.75,83.24 136.75,85.28 136.43,85.59 136.43,85.78 136.5,85.85 136.86,85.85 v2(136.98,85.73)
  BOTTOM w0.076: UC1.C46 135.57,86.07 135.63,86.13 136.59,86.13 136.69,86.02 136.69,86.02 v2(136.98,85.73)
  BOTTOM w0.097: C7.1 209.02,52.22 208.72,52.22 v2(208.45,51.95)
EDP_TX1: length 2.3
  BOTTOM w0.097: JEDP1.22 211.92,49.95 211.76,50.11 211.25,50.11 211.07,50.29 210.69,50.29 C9.2
EDP_TX1#: length 2.3
  BOTTOM w0.097: C8.2 210.73,50.47 211.14,50.47 211.32,50.29 211.76,50.29 211.91,50.45 JEDP1.21
EDP_TX1_DN: length 98.7
  IN2 w0.122: v2(208.58,50.69) 208.7,50.57 209.5,50.57 209.89,50.96 209.89,54.62 209.05,55.46 207.93,55.46 202.52,60.87 199.29,60.87 197.93,62.23 183.56,62.23 176.8,68.99 156.53,68.99 147.77,77.75 147.77,80.3 146.69,81.38 139.33,81.38 138.06,82.65 138.06,85.49 v2(137.8,85.74)
  BOTTOM w0.076: UC1.D46 134.92,85.77 135,85.7 135.36,85.7 135.54,85.51 135.54,85.32 135.64,85.22 135.7,85.2 135.84,85.15 135.98,85.15 136.17,85.21 136.32,85.21 136.45,85.14 136.7,85.14 136.83,85.28 137.94,85.28 138.01,85.35 138.01,85.53 v2(137.8,85.74)
  BOTTOM w0.097: C8.1 209.09,50.49 208.77,50.49 v2(208.58,50.69)
EDP_TX1_DP: length 98.6
  IN2 w0.122: v2(208.58,50.11) 208.79,50.32 209.6,50.32 210.14,50.85 210.14,54.72 209.15,55.71 208.03,55.71 202.62,61.12 199.39,61.12 198.03,62.48 183.67,62.48 176.9,69.24 156.63,69.24 148.02,77.85 148.02,80.4 146.8,81.63 139.43,81.63 138.31,82.75 138.31,85.66 v2(138.39,85.74)
  BOTTOM w0.076: UC1.C45 135.25,85.36 135.52,85.08 135.64,85.04 135.64,85.04 135.81,84.99 136,84.99 136.2,85.04 136.28,85.04 136.41,84.98 136.77,84.98 136.9,85.11 138.01,85.11 138.18,85.28 138.18,85.53 v2(138.39,85.74)
  BOTTOM w0.097: C9.1 209.09,50.3 208.77,50.3 v2(208.58,50.11)
EDP_VDD_EN: length 131
  TOP w0.102: D4.2 212.33,50.64 212.75,50.22 213.37,50.22 214.25,49.34 214.61,49.34 v2(214.66,49.38)
  IN1 w0.127: v2(131.04,40.44) 133.47,40.44 134.49,41.46 151.32,41.46 154.99,37.78 158.4,37.78 161.68,34.5 179.38,34.5 180.27,35.39 182.98,35.39 183.63,36.04 192.08,36.04 193.08,37.04 201.14,37.04 207.68,43.58 210.49,43.58 211.03,44.12 213.47,44.12 214.58,45.24 214.58,49.31 v2(214.66,49.38)
  IN2 w0.127: v2(131.04,40.44) 130.97,40.44 130.61,40.8 130.61,42.31 130.98,42.68 130.98,52.2 132.81,54.02 132.81,55 133.81,56.01 133.81,59.24 132.73,60.32 131.27,60.32 130.71,60.89 130.71,61.23 131.23,61.75 131.23,62.31 129.96,63.58 129.96,63.87 v2(127.94,65.89)
  BOTTOM w0.102: v2(127.94,65.89) 127.94,66.44 UC1.U13
EDRAM_OPIO_RCOMP: length 2.4
  TOP w0.102: RC121.1 v1(132.01,99.39)
  TOP w0.254: v2(132.23,97.81) 132.01,98.03 RC121.1
  BOTTOM w0.076: v2(132.23,97.81) 131.94,97.51 UC1.H66
EMMC_CLK: length 43
  BOTTOM w0.076: UC1.AM3 119.78,60.71 120.12,60.36 120.12,59.96 120.19,59.78 120.19,59.12 119.83,58.75 119.83,56.83 119.6,56.6 119.6,55.08
  BOTTOM w0.102: RM14.1 149.21,42.02 147.86,43.37 v1(143.77,43.37) 136.37,43.37 131.2,48.54 129.54,48.54 128.03,50.05 124.77,50.05 124.53,50.29 123.02,50.29 119.6,53.7 119.6,55.08
EMMC_CLK_R: length 6.3
  TOP w0.102: v2(149.51,37.05) 149.73,37.05 150.02,36.75 UM1.M6
  BOTTOM w0.102: v2(149.51,37.05) 149.81,36.75 150.43,36.75 150.63,36.95 150.63,37.15 CM8.2 RM13.2 v1(150.17,39.56) 150.17,39.84 149.84,40.17 RM14.2
EMMC_CMD: length 60.3
  TOP w0.102: v2(118.87,61.77) 118.65,61.55 117.86,61.55 117.57,61.26 117.57,60.12 116.78,59.32 116.78,54.04 124.27,46.54 125.48,46.54 126.12,45.91 129.07,45.91 131.92,43.05 131.92,39.75 130.71,38.53 v1(130.71,34.7) v2(130.71,34.03)
  IN1 w0.127: v2(149.01,32.27) 148.4,31.66 146.67,31.66 144.66,33.66 131.07,33.66 v2(130.71,34.03)
  BOTTOM w0.076: v2(118.87,61.77) 118.64,61.54 UC1.AP4
  BOTTOM w0.102: RM15.1 149.2,33.7 149.2,32.46 v2(149.01,32.27)
EMMC_CMD_R: length 2.8
  TOP w0.102: v2(149.64,36.38) 149.91,36.11 UM1.M5
  BOTTOM w0.102: v2(149.64,36.38) 149.64,35.49 149.51,35.36 RM15.2 RM3.2
EMMC_D0_R: length 10.9
  TOP w0.102: RPM1.6 141.22,35.46 v2(141.7,34.98) 141.92,34.77 142.62,34.77 143.04,35.19 143.49,35.19 143.57,35.11 UM1.A3
  BOTTOM w0.102: RM16.2 139.05,36.77 139.24,36.77 139.49,37.02 141.05,37.02 141.13,37.09 141.54,37.09 141.79,36.84 141.79,36.53 141.61,36.36 141.61,35.07 v2(141.7,34.98)
EMMC_D1_R: length 9.2
  TOP w0.102: UM1.A4 143.86,35.61 143.42,36.05 143.1,36.05 142.53,35.48 v2(142.4,35.48) 142.1,35.48 141.62,35.97 141.09,35.97 140.59,36.46 RPM1.8
  BOTTOM w0.102: v2(142.4,35.48) 142.4,35.54 141.99,35.96 v1(141.99,36.25) 141.99,36.28 142.02,36.31 142.02,36.94 141.46,37.49 RM17.2
EMMC_D2_R: length 7.8
  TOP w0.102: RPM2.6 140.27,38.32 140.81,37.78 140.81,37.19 141.32,36.69 v2(141.36,36.69) 141.44,36.69 142.08,37.33 142.95,37.33 143.13,37.15 143.13,36.99 144,36.11 UM1.A5
  BOTTOM w0.102: v2(141.36,36.69) 141.36,36.67 141.23,36.54 RM18.2
EMMC_D3_R: length 13
  TOP w0.089: 144.27,34.86 144.77,34.86 UM1.B2
  TOP w0.102: RPM1.5 140.41,34.96 140.99,34.39 142.87,34.39 v2(143.24,34.76) 143.35,34.86 144.27,34.86
  BOTTOM w0.102: v2(143.24,34.76) 143.24,34.88 142.86,35.26 142.86,35.8 142.88,35.82 142.88,36.28 142.64,36.52 142.49,36.52 142.25,36.76 142.25,37.03 141.32,37.96 139.49,37.96 139.24,37.72 139.05,37.72 RM19.2
EMMC_D4_R: length 13.4
  TOP w0.089: UM1.B3 144.77,35.36 144.28,35.36
  TOP w0.102: RPM1.7 140.77,35.96 141,35.74 141.52,35.74 142.26,35 142.52,35 143.14,35.62 v2(143.28,35.62) 143.5,35.62 143.75,35.36 144.28,35.36
  BOTTOM w0.102: v2(143.28,35.62) 143.28,36.28 v1(143.36,36.36) 143.36,36.86 141.29,38.92 139.49,38.92 139.24,38.67 139.05,38.67 RM20.2
EMMC_D5_R: length 10.1
  TOP w0.089: UM1.B4 144.77,35.86 144.28,35.86
  TOP w0.102: RPM2.5 140.13,37.82 140.53,37.43 140.53,36.85 141.1,36.28 141.54,36.28 142.21,36.95 142.63,36.95 v2(142.66,36.93) 142.87,36.93 143.93,35.86 144.28,35.86
  BOTTOM w0.102: RM21.2 141.3,38.44 v1(141.73,38.02) 142.66,37.09 v2(142.66,36.93)
EMMC_D6_R: length 10.4
  TOP w0.089: UM1.B5 144.77,36.36 144.28,36.36
  TOP w0.102: 144.28,36.36 144.08,36.36 143.36,37.08 143.36,37.56 v2(143.23,37.69) 142.78,37.69 141.65,38.82 RPM2.7
  BOTTOM w0.102: RM22.2 141.46,39.4 142.44,38.41 142.44,38.2 142.95,37.69 v2(143.23,37.69)
EMMC_D7_R: length 13.3
  TOP w0.089: 144.41,36.86 144.77,36.86 UM1.B6
  TOP w0.102: 144.41,36.86 144.23,37.04 144.23,37.41 v2(143.8,37.84) 143.8,38.01 142.48,39.32 RPM2.8
  BOTTOM w0.102: v2(143.8,37.84) 143.8,38.01 v1(142.13,39.67) 141.9,39.9 139.33,39.9 RM23.2
EMMC_DATA0: length 39.5
  BOTTOM w0.076: 117.41,55.08 117.41,56.29 118.42,57.29 118.42,59.22 118.19,59.45 118.19,59.71 UC1.AP2
  BOTTOM w0.102: 117.41,55.08 117.41,52.8 122.13,48.08 123.65,48.08 123.89,47.84 126.86,47.84 128.57,46.13 130.52,46.13 131.67,44.98 131.67,43.25 132.01,42.9 132.01,42.82 v1(131.85,42.66) 131.67,42.48 131.67,42.3 131.81,42.16 131.95,42.16 132.32,42.53 132.45,42.53 132.59,42.39 132.59,42.23 132.24,41.88 132.24,41.73 132.4,41.57 132.54,41.57 132.9,41.93 133.05,41.93 133.2,41.78 133.2,41.65 132.83,41.28 132.83,41.14 137.43,36.54 RM16.1
EMMC_DATA1: length 40.4
  BOTTOM w0.076: UC1.AP1 118.58,59.46 118.58,57.22 117.64,56.28 117.64,55.08
  BOTTOM w0.102: 117.64,55.08 117.64,52.89 122.22,48.31 123.74,48.31 123.98,48.07 127.01,48.07 128.7,46.38 130.59,46.38 131.66,45.31 131.9,45.07 131.9,43.4 133.51,41.79 133.51,41.64 133.16,41.29 133.16,41.13 133.31,40.98 133.44,40.98 133.81,41.35 133.95,41.35 134.09,41.22 134.09,41.07 v1(133.89,40.87) 133.72,40.7 133.72,40.58 133.87,40.42 133.99,40.42 134.38,40.81 134.5,40.81 134.65,40.65 134.65,40.52 134.29,40.15 134.29,40.01 137.3,37 139.15,37 139.65,37.49 RM17.1
EMMC_DATA2: length 40.1
  BOTTOM w0.076: 117.18,55.08 117.18,56.48 v1(118.12,57.42) 118.25,57.55 118.25,59.15 118.02,59.39 118.02,59.74 118.17,60.04 118.17,60.48 UC1.AP3
  BOTTOM w0.102: 117.18,55.08 117.18,52.7 122.03,47.85 123.55,47.85 123.79,47.61 126.76,47.61 128.5,45.87 130.45,45.87 131.44,44.88 131.44,42.21 137.56,36.08 139.36,36.08 RM18.1
EMMC_DATA3: length 39.2
  BOTTOM w0.076: UC1.AN3 118.86,60.85 118.86,60.36 118.68,60.07 118.68,59.75 118.75,59.64 118.75,57.15 117.87,56.28 117.87,55.08
  BOTTOM w0.102: 117.87,55.08 117.87,52.99 122.31,48.55 123.83,48.55 124.07,48.3 127.16,48.3 128.83,46.64 130.66,46.64 132.13,45.17 132.13,44.44 132.44,44.12 132.44,43.99 132.13,43.67 132.13,43.5 132.29,43.34 132.43,43.34 132.76,43.66 132.9,43.66 133.03,43.53 v1(133.03,43.36) 132.72,43.05 132.72,42.91 132.86,42.76 133.01,42.76 133.33,43.09 133.48,43.09 133.62,42.94 133.62,42.8 133.29,42.47 133.29,42.33 134.88,40.74 134.88,39.73 137.13,37.49 RM19.1
EMMC_DATA4: length 39.6
  BOTTOM w0.076: 118.33,55.08 118.33,56.27 119.11,57.05 UC1.AN1
  BOTTOM w0.102: 118.33,55.08 118.33,53.18 122.5,49.01 124.02,49.01 124.26,48.77 127.4,48.77 129.02,47.14 130.8,47.14 132.81,45.13 132.81,44.99 132.58,44.76 132.58,44.63 132.75,44.47 132.89,44.47 133.11,44.69 133.25,44.69 133.4,44.54 133.4,44.4 133.18,44.18 133.18,44.04 133.32,43.89 133.46,43.89 133.68,44.11 133.83,44.11 133.97,43.97 133.97,43.82 133.75,43.6 133.75,43.46 133.9,43.32 134.04,43.32 134.26,43.54 134.4,43.54 134.55,43.39 134.55,43.25 134.33,43.03 134.33,42.89 135.34,41.87 135.34,40.86 135.66,40.54 135.66,40.39 135.34,40.06 135.34,39.92 135.5,39.76 135.65,39.76 135.97,40.09 136.11,40.09 136.26,39.94 136.26,39.8 135.93,39.47 135.93,39.33 136.08,39.19 136.22,39.19 136.55,39.51 136.69,39.51 136.83,39.37 136.83,39.22 v1(136.67,39.06) 136.51,38.9 136.51,38.76 136.66,38.6 136.8,38.6 137.13,38.93 137.27,38.93 137.76,38.44 RM20.1
EMMC_DATA5: length 40.1
  BOTTOM w0.076: UC1.AN2 119.03,60.31 118.86,60.03 118.86,59.78 118.91,59.7 118.91,57.08 118.1,56.27 118.1,55.08
  BOTTOM w0.102: RM21.1 139.65,38.44 139.15,37.95 136.99,37.95 135.11,39.83 135.11,40.84 134.74,41.21 134.74,41.32 135.09,41.66 135.09,41.8 134.95,41.94 134.81,41.94 134.48,41.61 134.34,41.61 134.19,41.76 134.19,41.9 134.52,42.23 134.52,42.37 134.38,42.51 134.23,42.51 v1(134.08,42.36) 133.91,42.19 133.76,42.19 133.62,42.33 133.62,42.47 133.94,42.8 133.94,42.94 132.35,44.53 132.35,45.26 130.73,46.89 128.9,46.89 127.25,48.54 124.16,48.54 123.92,48.78 122.4,48.78 118.1,53.08 118.1,55.08
EMMC_DATA6: length 39.2
  BOTTOM w0.076: UC1.AM4 119.78,61.3 119.52,61.04 119.52,59.36 119.29,59.13 119.29,57 118.56,56.26 118.56,55.08
  BOTTOM w0.102: 118.56,55.08 118.56,53.27 122.59,49.24 124.11,49.24 124.35,49 127.55,49 129.15,47.4 130.87,47.4 134.92,43.35 134.92,43.2 134.7,42.98 134.7,42.84 134.84,42.7 134.98,42.7 135.2,42.92 135.35,42.92 135.5,42.76 135.5,42.63 135.29,42.41 135.29,42.25 135.42,42.12 135.57,42.12 v1(135.7,42.25) 135.79,42.34 135.92,42.34 136.06,42.2 136.06,42.03 135.57,41.54 135.57,40.95 137.62,38.9 139.15,38.9 139.65,39.4 RM22.1
EMMC_DATA7: length 39.3
  BOTTOM w0.076: UC1.AM1 119.78,59.36 119.49,59.08 119.49,56.97 118.79,56.26 118.79,55.08
  BOTTOM w0.102: RM23.1 137.91,39.8 138.24,40.13 138.24,40.27 138.09,40.41 137.93,40.41 137.24,39.72 137.13,39.72 136.97,39.88 136.97,40.02 137.73,40.79 137.73,40.93 137.58,41.07 137.44,41.07 136.68,40.31 136.53,40.31 136.39,40.46 136.39,40.6 v1(136.76,40.97) 137.15,41.36 137.15,41.5 137.01,41.65 136.86,41.65 136.1,40.89 135.96,40.89 135.8,41.05 135.8,41.18 136.48,41.87 136.48,42.1 135.08,43.51 135.08,43.51 130.94,47.65 129.28,47.65 127.7,49.23 124.44,49.23 124.2,49.47 122.68,49.47 118.79,53.37 118.79,55.08
EMMC_RCLK: length 44
  BOTTOM w0.076: 119.19,55.08 119.19,56.43 119.66,56.9 119.66,58.89 120.03,59.26 120.03,59.7 UC1.AM2
  BOTTOM w0.102: RM24.1 148.67,41.85 147.55,42.96 v1(142.4,42.96) 136.2,42.96 131.07,48.1 129.41,48.1 127.87,49.64 124.61,49.64 124.36,49.88 122.85,49.88 119.19,53.54 119.19,55.08
EMMC_RCLK_R: length 3.2
  TOP w0.102: v2(147.74,36.5) 148.02,36.23 UM1.H5
  BOTTOM w0.102: RM24.2 RM12.2 148.67,37.03 148.58,36.95 147.85,36.95 147.74,36.83 v2(147.74,36.5)
EMMC_RCOMP: length 2.3
  TOP w0.102: v2(117.65,59.16) 117.18,59.16 v1(117.13,59.11)
  TOP w0.254: v2(117.65,59.16) 118.08,59.16 RC8.1
  BOTTOM w0.203: v2(117.65,59.16) 117.79,59.3 UC1.AT1
EMMC_RST#: length 8.8
  TOP w0.102: UM2.4 148.43,29.82 v1(148.22,30.03) 148.07,30.18 148.07,31.99 v2(148.34,32.27)
  BOTTOM w0.102: v2(148.34,32.27) 148.34,33.21 148.72,33.58 RM25.1 CM6.1 RM27.2
EMMC_RST#_R: length 1.6
  TOP w0.102: v2(148.44,35.63) 148.93,36.11 UM1.K5
  BOTTOM w0.102: RM25.2 148.72,35.34 v2(148.44,35.63)
EN_0.6VSP: length 5.2
  BOTTOM w0.102: PRM09.2 97.3,129.61 97.75,129.17 97.75,128.02 v1(98.1,127.67)
  BOTTOM w0.203: PUM01.7 95.49,130.48 PCM16.1 PRM09.2
EN_1.2V: length 5.5
  BOTTOM w0.102: v1(95.64,127.39) 95,128.02 95,129.09 95.47,129.56 PCM15.1
  BOTTOM w0.203: PCM15.1 PRM08.2 94.53,130.06 95.09,130.61 PUM01.8
EN_1.8VALW: length 6.3
  TOP w0.102: 165.96,50.96 v1(165,50.96)
  TOP w0.254: PR1801.2 v2(165.88,50.07) 165.96,50.14 165.96,50.96
  BOTTOM w0.254: PU1801.5 164.45,48.1 164.25,48.3 164.25,48.59 164.4,48.75 164.75,48.75 164.96,48.95 PC1805.1 PR1801.2 v2(165.88,50.07)
EN_2.5V: length 4.4
  BOTTOM w0.254: 56.3,27.62 PC2503.1 v1(55.29,26.74) 55.28,26.74 54.97,27.05 54.45,27.05 53.69,27.81 PU2501.2
EN_3V: length 2.6
  BOTTOM w0.254: PU301.12 110.14,139.84 v1(110.64,140.33) 111.46,141.16 PR502.1
EN_5V: length 3.7
  BOTTOM w0.102: 161.3,139.11 160.79,139.62 160.79,140.14 v1(160.41,140.52)
  BOTTOM w0.254: PR503.1 161.24,139.11 160.44,138.3 PU501.12
EN_+1VALW: length 5.1
  TOP w0.254: v1(169.26,54.28) 169.76,54.28 v2(169.83,54.35) 169.83,53.72 170.07,53.48 PCH09.1 170.51,52.62 PRH01.2
  BOTTOM w0.254: PUH01.6 169.45,54.73 v2(169.83,54.35) 169.83,53.72 170.09,53.46 PRH02.1
EN_CPU: length 3.7
  BOTTOM w0.102: PRZ22.1 155.85,118.69 155.33,119.21 155.33,119.44 v1(155.23,119.54)
  BOTTOM w0.203: PUZ01.37 154.06,117.3 154.97,118.22 155.41,118.22 PRZ22.1
ENLDO_3V5V: length 60.7
  TOP w0.102: v2(110.14,141.79) v1(110.14,142.43)
  IN1 w0.254: v2(160.5,139.12) 160.5,142.13 157.92,144.71 153.01,144.71 150.53,142.24 110.59,142.24 v2(110.14,141.79)
  BOTTOM w0.254: PU501.11 160.12,138.75 v2(160.5,139.12) ; PR302.1 PR303.1 v2(110.14,141.79) 110.14,140.52 109.91,140.29 PU301.11
EOPIO_RCOMP: length 1.3
  TOP w0.254: RC122.1 131.66,96.73 v2(132.28,96.73)
  BOTTOM w0.254: v2(132.28,96.73) 131.94,96.38 UC1.H65
ESPI_ALERT#: length 112
  TOP w0.102: v2(103.29,55.31) 103.56,55.58 104.21,55.58 104.63,55.16 RC14.2 105.24,54.67 v1(105.65,55.08) ; v2(44.2,63.15) 44,62.96 UE1.55
  IN2 w0.127: v2(44.2,63.15) 44.2,62.77 45.81,61.15 47.49,61.15 50.45,58.2 50.45,57.31 51.11,56.64 51.11,46.45 57.62,39.93 89.43,39.93 91.98,42.48 99.69,42.48 v2(101.91,44.7)
  BOTTOM w0.076: UC1.AY11 114.87,65.43 113.46,65.43
  BOTTOM w0.102: 113.46,65.43 112.08,64.05 111.93,64.05 111.04,63.17 108.79,63.17 108.66,63.04 108.66,62.55 107.37,61.26 106.88,61.26 106.26,60.63 106.26,59.77 104.67,58.19 102.69,58.19 102.52,58.02 102.52,56.07 v2(103.29,55.31) 103.5,55.09 103.5,52.71 102.82,52.03 102.82,50.04 102.34,49.56 102.34,45.13 v2(101.91,44.7)
ESPI_CLK: length 120.7
  TOP w0.102: RE67.2 45.75,59.78 v2(45.41,60.12) 45.41,60.18 44.8,60.79 UE1.57
  IN2 w0.127: v2(101.34,42.8) 100.32,41.78 91.84,41.78 89.49,39.43 57.41,39.43 50.6,46.24 50.6,56.43 49.94,57.09 49.94,57.25 47.08,60.12 v2(45.41,60.12)
  BOTTOM w0.102: JESPI1.10 106.57,28.78 106.83,28.52 106.83,27.62 105.45,26.24 103.14,26.24 102.9,26.48 102.9,34.04 102.04,34.91 102.04,38.85 101.34,39.55 v2(101.34,42.8) 102.57,44.03 102.57,49.47 103.05,49.95 103.05,51.94 106.57,55.46 106.57,58.27 108.08,59.77 108.08,60.35 108.57,60.85 CC88.1 RC15.2
ESPI_CS#: length 136.1
  TOP w0.102: v2(45.04,62.88) 45.04,62.6 45.2,62.43 UE1.58 ; v1(102.07,45.5) 102.05,45.49 101.87,45.49 101.86,45.5 v2(101.02,45.5)
  IN2 w0.127: v2(101.02,45.5) 98.5,42.99 91.77,42.99 89.22,40.44 57.83,40.44 52.41,45.87 52.41,53.78 51.72,54.46 51.72,57.64 47.7,61.66 46.26,61.66 v2(45.04,62.88)
  BOTTOM w0.089: UC1.BA12 114.8,66.43 112.92,66.43
  BOTTOM w0.102: 112.92,66.43 111.32,64.83 111.32,64.35 110.59,63.62 108.6,63.62 105.8,60.82 105.8,59.96 104.49,58.65 102.46,58.65 101.32,57.5 101.32,55.29 102.36,54.24 102.36,50.23 101.88,49.75 101.88,46.37 v2(101.02,45.5) 100.85,45.33 100.85,35.37 102.42,33.79 102.42,26.27 102.94,25.76 105.84,25.76 108.07,27.99 JESPI1.7
ESPI_IO0: length 131.8
  TOP w0.102: v1(98.89,44.64) 99.03,44.64 v2(99.35,44.96) ; UE1.59 45.6,63.1 v2(45.55,63.15)
  IN2 w0.127: v2(45.55,63.15) 45.73,63.15 46.96,61.92 47.81,61.92 51.97,57.75 51.97,54.57 52.66,53.88 52.66,45.97 57.94,40.7 89.11,40.7 91.66,43.24 97.45,43.24 99.17,44.96 v2(99.35,44.96)
  BOTTOM w0.102: RPC2.8 108.19,65.48 107.41,64.7 107.41,63.72 103.84,60.15 102.67,60.15 100.4,57.88 100.4,54.91 101.45,53.86 101.45,50.61 100.97,50.13 100.97,47.89 99.57,46.5 99.57,45.17 v2(99.35,44.96) 99.35,44.29 99.93,43.71 99.93,34.73 101.51,33.15 101.51,25.9 102.56,24.84 103.27,24.84 103.28,24.84 103.65,24.84 103.65,24.85 106.22,24.85 110.07,28.7 JESPI1.3
ESPI_IO1: length 133.8
  TOP w0.102: v1(100.67,44.41) 99.98,45.1 v2(99.98,45.12) ; UE1.60 46,63.56 45.73,63.83 v2(45.02,63.83)
  IN2 w0.127: v2(45.02,63.83) 45.6,63.83 46.19,63.25 46.19,63.04 47.07,62.17 47.91,62.17 52.23,57.86 52.23,54.68 52.92,53.99 52.92,46.08 58.04,40.95 89.01,40.95 91.55,43.5 97.11,43.5 99,45.38 99.72,45.38 v2(99.98,45.12)
  BOTTOM w0.102: JESPI1.4 109.57,28.52 106.13,25.07 102.65,25.07 101.74,25.99 101.74,33.25 100.16,34.82 100.16,43.76 100.15,43.76 100.15,44.95 v2(99.98,45.12) 99.8,45.3 99.8,46.28 101.2,47.68 101.2,50.04 101.68,50.52 101.68,53.96 100.63,55.01 100.63,57.79 102.76,59.92 103.93,59.92 107.68,63.67 107.68,64.65 108.02,64.98 RPC2.7
ESPI_IO2: length 129.9
  TOP w0.102: v1(99.88,46.11) 100.21,45.79 v2(100.21,45.68) ; UE1.61 46.4,62.88 46.98,63.45 v2(47.28,63.45)
  IN2 w0.127: v2(100.21,45.68) 100.2,45.67 98.93,45.67 97.01,43.75 91.45,43.75 88.9,41.2 58.16,41.2 53.17,46.19 53.17,54.09 52.48,54.78 52.48,57.96 48.02,62.42 47.17,62.42 46.93,62.67 46.93,63.09 v2(47.28,63.45)
  BOTTOM w0.102: RPC2.6 108.25,64.48 107.96,64.19 107.96,63.62 105.34,61.01 105.34,60.15 104.3,59.11 102.27,59.11 100.86,57.69 100.86,55.1 101.91,54.05 101.91,50.42 101.42,49.94 101.42,47.51 100.21,46.29 v2(100.21,45.68) 100.38,45.5 100.38,43.86 100.39,43.85 100.39,34.92 101.96,33.34 101.96,26.09 102.75,25.3 106.03,25.3 109.07,28.34 JESPI1.5
ESPI_IO3: length 127.3
  TOP w0.102: UE1.62 46.8,62.62 47.02,62.84 v2(47.35,62.84) ; v2(100.61,46.12) 100.61,46.38 v1(101.32,47.09)
  IN2 w0.127: v2(47.35,62.84) 47.96,62.84 52.74,58.06 52.74,54.88 53.42,54.2 53.42,46.3 56.12,43.61 57.98,43.61 60.13,41.46 88.8,41.46 91.34,44 96.9,44 99.02,46.12 v2(100.61,46.12)
  BOTTOM w0.102: RPC2.5 108.38,63.98 108.19,63.79 108.19,63.53 105.57,60.91 105.57,60.06 104.39,58.88 102.37,58.88 101.09,57.6 101.09,55.2 102.14,54.15 102.14,50.33 101.65,49.85 101.65,47.16 v2(100.61,46.12) 100.61,43.95 100.62,43.95 100.62,35.01 102.19,33.44 102.19,26.18 102.84,25.53 105.94,25.53 108.57,28.17 JESPI1.6
ESPI_RESET#: length 109.2
  TOP w0.102: UE1.53 43.2,62.77 v2(44.2,63.77)
  IN2 w0.127: v2(44.2,63.77) 44.62,63.35 44.62,62.71 45.92,61.41 47.6,61.41 51.47,57.54 51.47,54.36 52.15,53.67 52.15,48.98 51.44,48.27 51.44,46.47 57.73,40.19 89.32,40.19 91.87,42.73 99.13,42.73 v2(101.42,45.03)
  BOTTOM w0.076: UC1.BA11 114.31,65.97 113.73,65.97 113.57,65.81
  BOTTOM w0.102: 113.57,65.81 112.25,64.49 111.83,64.49 110.74,63.39 108.7,63.39 108.14,62.84 v1(108.14,62.67) 108.14,62.52 107.16,61.54 106.85,61.54 106.03,60.72 106.03,59.87 104.58,58.42 102.6,58.42 102.29,58.12 102.29,56.09 102.12,55.92 102.12,55.19 102.59,54.72 102.59,50.14 102.11,49.66 102.11,45.71 v2(101.42,45.03)
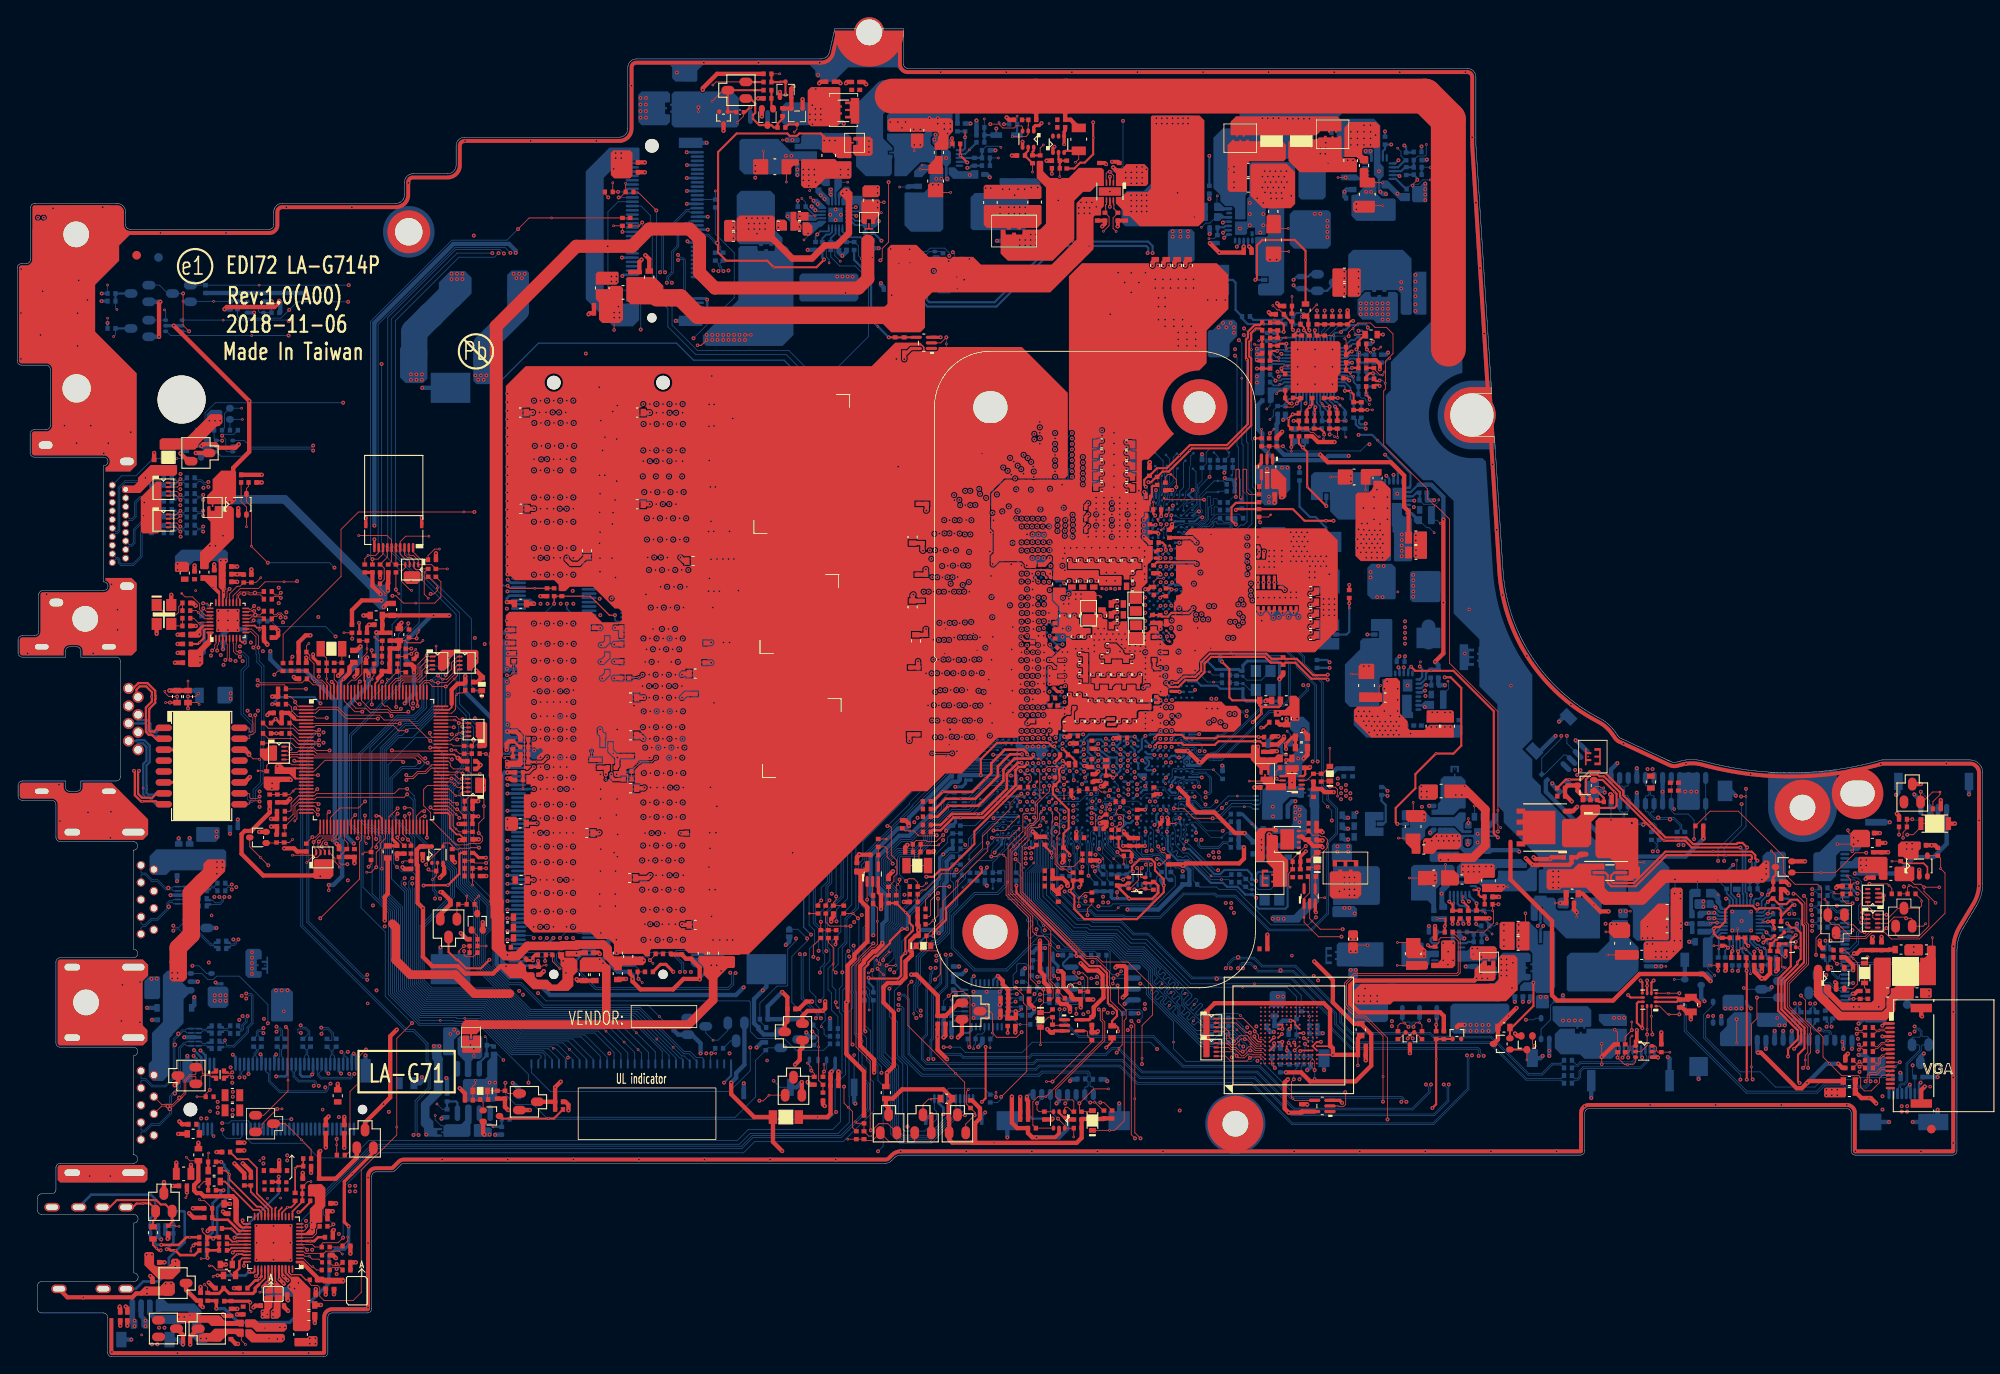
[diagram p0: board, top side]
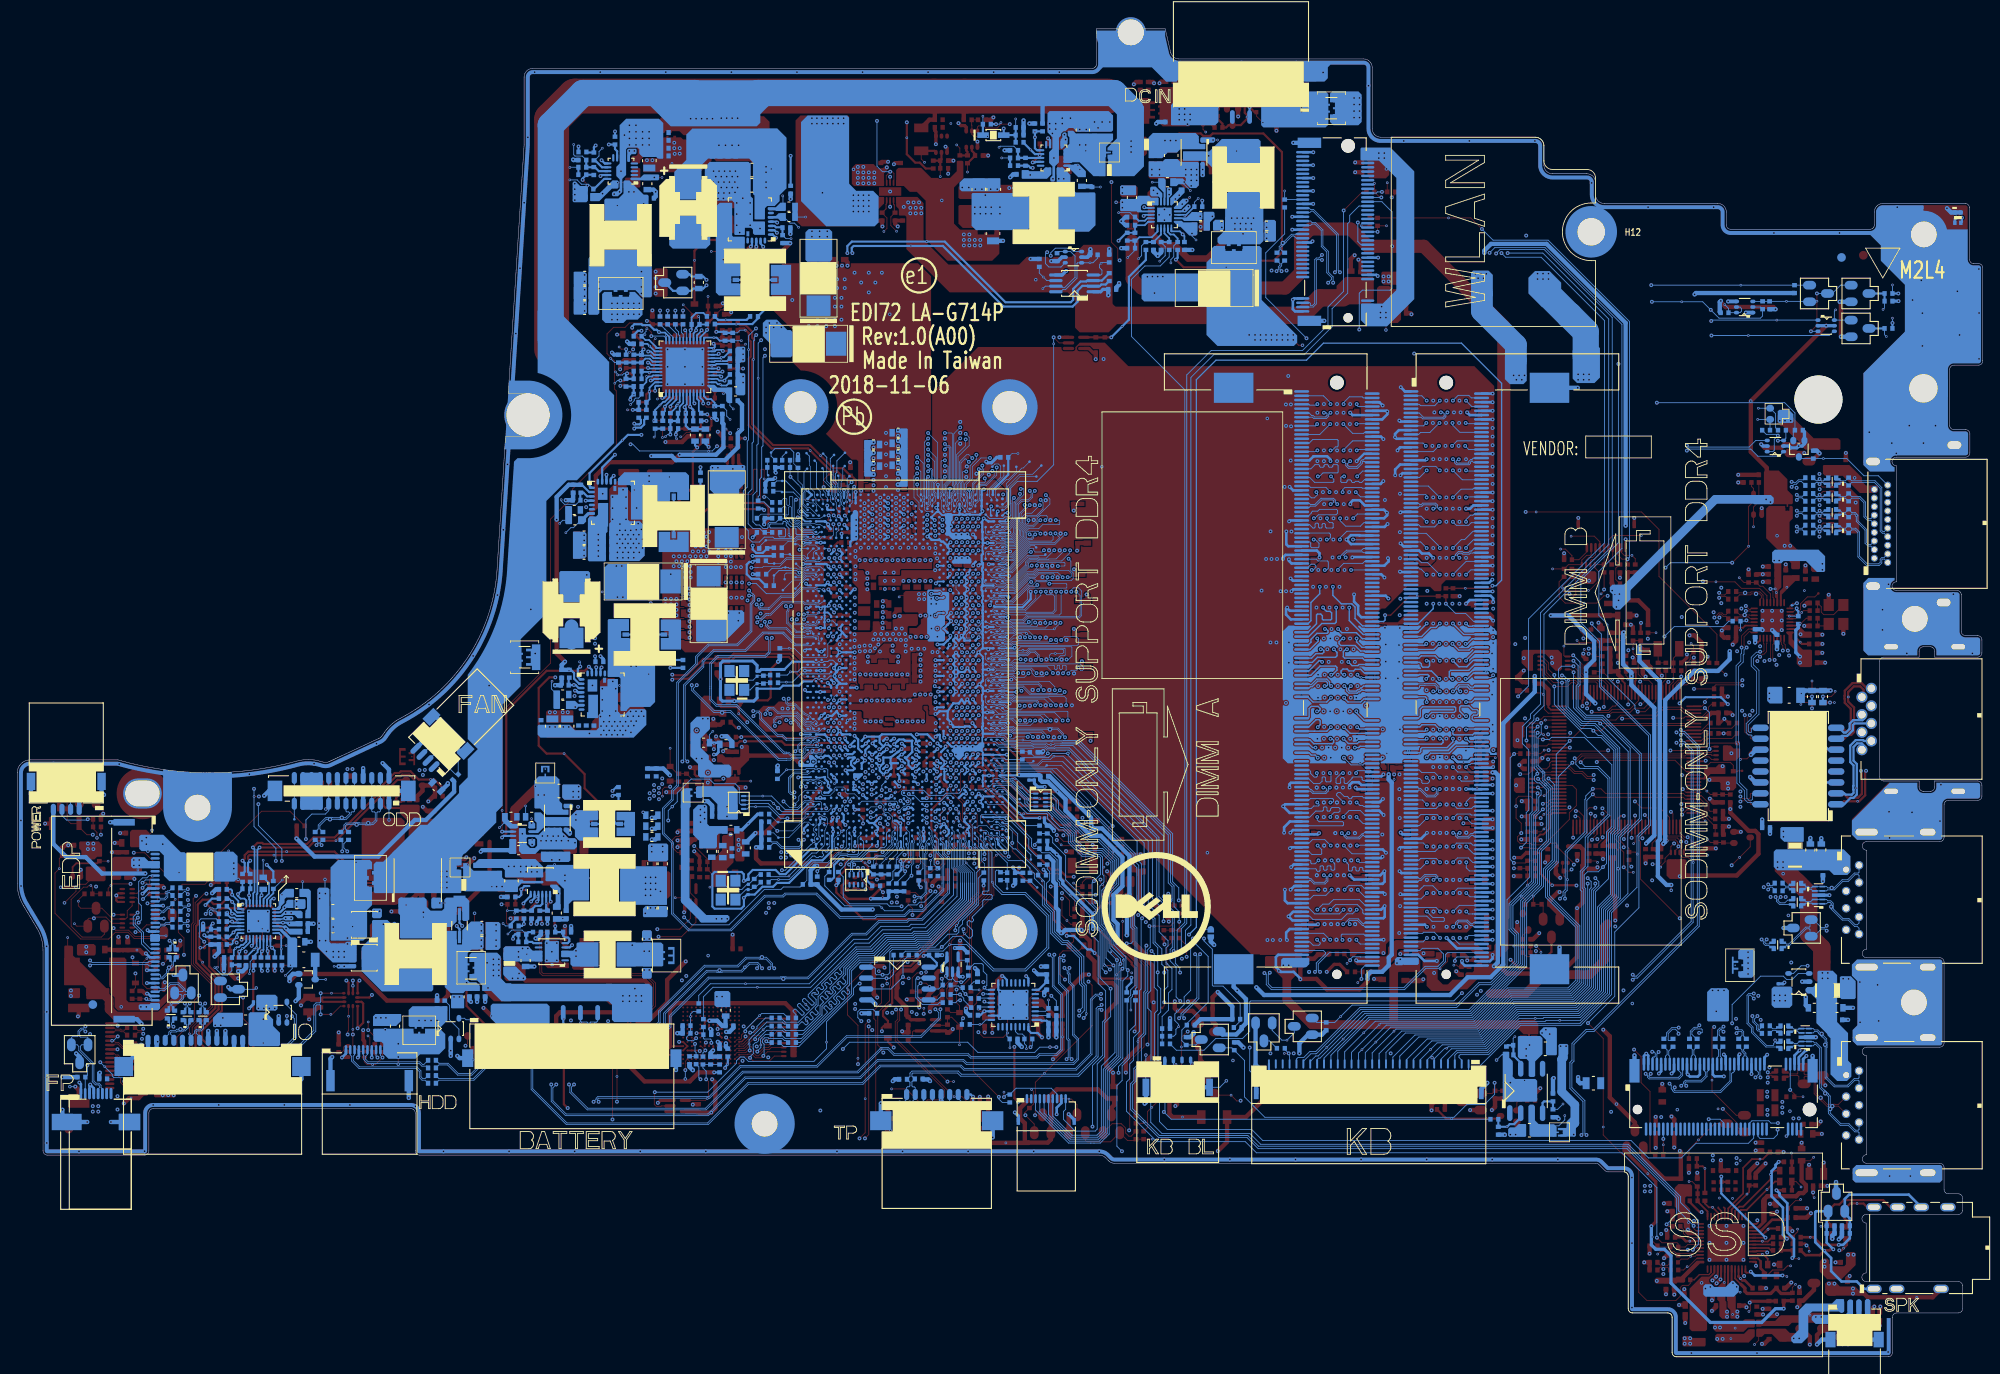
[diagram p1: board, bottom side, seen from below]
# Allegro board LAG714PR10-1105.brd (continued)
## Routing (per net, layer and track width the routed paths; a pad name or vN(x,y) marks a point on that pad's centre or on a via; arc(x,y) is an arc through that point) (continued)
EXT_PWR_GATE#: length 1.2
  TOP w0.076: TP13.1 120.23,64.83 v2(119.9,64.49)
  BOTTOM w0.076: v2(119.9,64.49) 119.9,64.61 UC1.AM10
FAN1_PWM: length 266.4
  TOP w0.102: v2(207.62,53.59) 207.95,53.26 207.95,50.49 208.16,50.28 208.16,45.64 205.91,43.39 205.91,40.77 208.39,38.3 v1(208.39,37.55) 208.39,35.36 208.1,35.07 v2(208.1,33.59) ; UE1.47 v2(40.8,60.34)
  IN1 w0.127: v2(207.62,53.59) 206.73,54.48 206.73,59.69 203.3,63.11 203.3,64.64 201.13,66.8 192.72,66.8 192.07,67.46 188.5,67.46 182.85,73.11 179.7,73.11 179.42,72.83 v2(179.42,72.19) ; v2(40.8,60.34) 40.8,59.5 40.32,59.02 40.32,55.57 44.86,51.04 44.86,44.66 55.89,33.63 59.94,33.63 62.72,30.85 64.82,30.85 65.87,29.8 85.38,29.8 85.79,30.21 92.43,30.21 92.96,30.74 96.36,30.74 97.36,31.75 118.5,31.75 119.09,31.15 135.24,31.15 136.44,32.35 143.79,32.35 145.91,30.23 157.1,30.23 157.91,31.05 161.7,31.05 162.26,30.48 180.02,30.48 181.7,32.16 193.57,32.16 194.57,33.16 206.49,33.16 207.34,34.01 207.69,34.01 208.1,33.6 v2(208.1,33.59)
  BOTTOM w0.102: JFAN1.2 180.03,69.96 179.71,69.96 177.47,67.72 R50.1 177.16,69.61 179.42,71.88 v2(179.42,72.19)
FAN1_TACH: length 260.3
  TOP w0.102: UE1.40 38,60.13 38.43,59.71 38.43,59.17 CE28.1 RE13.1 37.4,57.43 37.56,57.27 v2(38.37,57.27) ; v2(207.51,33.59) 207.77,33.84 v1(207.77,34.5) 207.77,35.06 208.06,35.35 208.06,38.3 205.69,40.68 205.69,43.48 207.92,45.72 207.92,50.2 207.72,50.39 207.72,52.78 206.66,53.84 v2(206.41,53.84)
  IN1 w0.127: v2(180.07,72.19) 180.54,72.66 182.93,72.66 188.39,67.2 191.97,67.2 192.62,66.55 201,66.55 202.98,64.57 202.98,63.07 206.41,59.64 v2(206.41,53.84) ; v2(207.51,33.59) 206.83,32.9 194.67,32.9 193.68,31.9 181.8,31.9 180.12,30.23 162.16,30.23 161.59,30.79 158.01,30.79 157.2,29.98 145.8,29.98 143.69,32.09 136.54,32.09 135.34,30.89 118.99,30.89 118.39,31.49 97.47,31.49 96.46,30.49 93.06,30.49 91.77,29.19 65.76,29.19 64.61,30.34 62.51,30.34 59.73,33.12 54.45,33.12 44.35,43.22 44.35,50.82 38.37,56.8 v2(38.37,57.27)
  BOTTOM w0.102: JFAN1.3 180.07,71.33 v2(180.07,72.19)
FB_1.2V: length 6.7
  BOTTOM w0.102: PRM11.1 98.51,128.66 v1(99.36,127.81)
  BOTTOM w0.203: PCM17.1 PRM10.1 ; PCM17.1 98.52,128.91 PRM11.1 ; PCM17.1 98.4,129.78 98,130.17 96.55,130.17 95.89,130.83 PUM01.6
FB_1.8VALW: length 5.8
  BOTTOM w0.102: PC1807.2 169.74,49.61 170.93,49.61 v1(171.38,49.16)
  BOTTOM w0.254: PR1805.1 168.99,49.38 PC1807.2 PR1807.2 168.56,48.24 168.42,48.1 PU1801.6
FB_2PH_CPU: length 6.5
  TOP w0.102: v1(154.43,108.83) PRZ24.1
  TOP w0.254: PRZ24.1 153.39,109.69 PCZ15.1 153.4,110.2 v2(153.13,110.47)
  BOTTOM w0.203: PUZ01.3 152.21,111.46 153.13,110.53 v2(153.13,110.47) 153.13,109.95 PRZ21.2
  BOTTOM w0.254: PRZ21.2 153.39,109.69 PRZ24.1
FB_+1VALW: length 5.6
  BOTTOM w0.102: v1(171.45,51.87) PRH12.2
  BOTTOM w0.254: PRH12.2 PRH08.1 PRH09.1 168.63,51.98 168.18,52.43 167.61,52.43 167.39,52.65 PUH01.10
FFS_INT1: length 78.3
  TOP w0.102: US1.12 v1(189.89,39.59) 189.89,37.92 190,37.82 v2(190,37.47)
  IN1 w0.127: v2(190,37.47) 189.33,36.8 183.31,36.8 183.1,36.58 176.14,36.58 175.56,36 171.73,36 171.29,36.44 168.16,36.44 164.45,40.15 155.73,40.15 150.84,45.04 150.29,45.04 148.41,46.93 148.41,51.14 147.79,51.76 144.01,51.76 140.39,55.38 138.58,55.38 137.5,56.46 v2(135.43,56.46)
  BOTTOM w0.076: UC1.M3 130.38,60.72 130.71,60.39 130.71,59.57 130.65,59.51 130.65,58.9
  BOTTOM w0.102: RC35.2 v2(135.43,56.46) 135.06,56.83 134.6,56.83 132.97,58.46 131.9,58.46 131.83,58.39 130.82,58.39 130.65,58.56 130.65,58.9
FFS_INT2: length 90.4
  TOP w0.102: US1.11 v1(189.4,38.07) v2(189.4,37.47) 189.4,36.19 188.69,35.49 QS1.2
  IN1 w0.127: v2(189.4,37.47) 188.98,37.05 183.21,37.05 182.99,36.84 176.03,36.84 175.45,36.25 171.84,36.25 171.39,36.7 168.27,36.7 164.56,40.41 155.84,40.41 150.95,45.3 150.4,45.3 148.66,47.03 148.66,51.24 147.89,52.01 144.12,52.01 140.47,55.66 138.9,55.66 137.03,57.53 134.03,57.53 132.16,55.66 129.36,55.66 128.72,55.02 127.76,55.02 127.04,55.74 124.71,55.74 124.51,55.94 v2(124.49,55.94)
  BOTTOM w0.076: 124.49,57.08 124.22,57.35 124.22,59.7 124.16,59.78 124.16,60.01 124.42,60.56 UC1.AC2
  BOTTOM w0.102: RC36.2 124.8,55.58 124.8,55.62 v2(124.49,55.94) 124.49,57.08
FFS_INT2_Q: length 4.8
  TOP w0.102: QS1.3 188.06,34.29 187.74,33.97 v1(187.11,33.97) 186.77,33.97 v2(185.95,34.79) 185.96,34.81 RS4.2
  BOTTOM w0.102: JHDD1.9 186.2,35.04 v2(185.95,34.79)
FPR_SCAN#: length 236
  TOP w0.102: v2(201.66,32.25) 201.52,32.39 v1(201.52,33.71) 201.52,38.69 202.15,39.33 v2(202.15,41.77) ; v2(39.28,62.99) 38.8,62.51 UE1.42
  IN1 w0.127: v2(39.28,62.99) 37.95,61.66 37.95,56.86 44.09,50.71 44.09,43.11 54.37,32.84 59.65,32.84 62.4,30.09 64.51,30.09 65.65,28.94 91.87,28.94 93.17,30.23 96.57,30.23 97.57,31.24 118.29,31.24 118.88,30.64 135.45,30.64 136.65,31.84 143.58,31.84 146.56,28.86 156.44,28.86 158.12,30.54 161.49,30.54 162.05,29.97 180.27,29.97 181.95,31.65 198.89,31.65 199.88,32.65 201.27,32.65 v2(201.66,32.25) 202,32.6 207.7,32.6 209.91,34.81 209.91,36.87 212.54,39.5 217.84,39.5 219.21,38.13 219.21,34.93 v2(220.25,33.89)
  BOTTOM w0.102: JFP1.2 220.5,32.5 RC213.1 220.25,32.75 v2(220.25,33.89) ; EU4012.3 v2(202.15,41.77)
GPP_B23: length 9.9
  TOP w0.102: v2(119.98,63.7) 119.98,63.66 120.29,63.35 120.29,62.12 120.23,62.06 120.23,59.44 120.6,59.07 120.6,57.29 121.2,56.69 v1(121.51,56.69) 121.84,56.69 122.23,56.3 RC39.1
  BOTTOM w0.076: UC1.AM7 119.95,63.51 119.95,63.67 v2(119.98,63.7)
GPP_C5: length 5.3
  BOTTOM w0.076: v1(129.88,57.44) 129.44,57 RC38.1 128.91,57.71 128.48,58.14 127.63,58.14 126.41,59.36 UC1.W1
H_CATERR#: length 5.6
  BOTTOM w0.076: RC111.2 138.84,94.8 137.92,94.8 137.68,95.05 136.9,95.05 136.76,94.91 136.36,94.91 136.34,94.93 136.19,94.93 136.09,94.9 135.81,94.9 135.63,94.96 135.42,95.05 135.13,95.05 134.85,95.33 UC1.D63
H_CPU_SVIDALRT#: length 12.9
  BOTTOM w0.102: UC1.B63 135.9,95.5 136,95.6 137.81,95.6 137.91,95.7 137.91,96.26 138.01,96.36 138.21,96.36 138.31,96.26 138.31,95.43 138.42,95.33 138.62,95.33 138.72,95.43 138.72,95.61 v1(138.72,95.61) 138.72,95.61 138.72,96.33 139.04,96.64 139.04,97.01 139.15,97.13 139.33,97.13 139.42,97.05 139.42,96.91 139.5,96.83 140.85,96.83 140.97,96.71 140.97,96.48 140.86,96.37 139.26,96.37 139.13,96.24 139.13,95.43 139.23,95.33 139.79,95.33 139.9,95.43 139.9,95.71 RC153.1
H_CPUPWRGD: length 6.6
  BOTTOM w0.076: UC1.A68 136.55,98.46 137.19,99.11 137.19,100.4 137.31,100.52 137.31,100.96 137.32,100.97 137.32,101.08 137.64,101.4
  BOTTOM w0.102: 137.64,101.4 v2(138.55,102.31) 138.6,102.36 CC15.1 RC95.2
H_CPUPWRGD_R: length 1.1
  BOTTOM w0.102: TP7.1 139.51,104.68 RC95.1
H_DRAMRST#: length 168.8
  TOP w0.15: v2(56.98,89.65) 57.28,89.35 v1(60.13,89.35) RD7.2 RD8.1
  IN1 w0.193: v2(98.14,51.37) 98.01,51.49 97.06,51.49 95.6,50.03 93.19,50.03 v2(92.24,49.09)
  IN2 w0.076: 114.24,64.35 114.27,64.38 115.52,64.38 115.83,64.69 115.83,65.44 117.38,67 v2(117.38,67.26)
  IN2 w0.193: 114.24,64.35 112.99,63.11 112.99,62.36 110.6,59.96 109.87,59.96 109.39,59.49 109.39,59.15 107.44,57.19 107.44,56.9 104.77,54.24 104.77,53.83 102.31,51.37 v2(98.14,51.37)
  BOTTOM w0.15: v2(56.98,89.65) 56.56,89.65 55.91,90.29 55.91,113.19 60.57,117.85 76.61,117.85 78.59,115.88 89.1,115.88 91.39,113.6 91.39,49.94 v2(92.24,49.09) ; UC1.AT13 117.38,67.13 v2(117.38,67.26)
H_PECI: length 4.9
  TOP w0.102: UE1.94 50.49,74.83 50.93,75.27 50.93,76.86 v1(51.08,77.01) 51.25,77.18 51.74,77.18 RE23.1
H_PROCHOT#: length 406
  TOP w0.102: PQB06.1 v2(206.67,48.26) ; v2(53.66,59.2) 52.64,59.2 52.57,59.12 51.38,59.12 51.29,59.03 CE26.1 50.55,59.4 50.22,59.73 49.59,59.73 49.48,59.63 UE2.4 47.52,57.37 v2(47.52,57.22) ; v2(100.3,127.48) 100.52,127.7 100.52,128.86 101.25,129.6 v2(101.25,136.58) ; PQ12.3 116.82,142.99 116.68,143.12 116.11,143.12 115.86,142.87 114.52,142.87 114.08,143.31 v2(113.06,143.31) ; v2(29.18,57.15) v1(28.26,58.07) 27.02,59.3 PQ11.1 ; PRZ43.2 v2(151.04,121.64)
  IN2 w0.127: v2(141.51,116.39) 141.51,115.5 142.62,114.4 144.78,114.4 144.95,114.22 144.95,111.76 144.33,111.14 144.33,109.27 146.53,107.07 146.53,91.59 149.51,88.6 149.51,83.68 151.84,81.36 151.84,77.62 157.68,71.77 180.34,71.77 181.5,70.61 182.19,70.61 187.77,65.03 199.17,65.03 199.94,64.26 v2(200.38,64.26) ; v2(141.51,116.39) 142.53,116.39 143.76,117.62 145.03,117.62 147.23,119.82 148.43,119.82 150.26,121.64 v2(151.04,121.64) ; v2(141.51,116.39) 141.41,116.5 131.68,116.5 120.57,127.61 112.59,127.61 111.83,126.84 107.33,126.84 106.69,127.48 v2(100.3,127.48) 94.79,127.48 94.15,126.84 90.03,126.84 87.94,128.94 78.88,128.94 78.6,129.22 72.47,129.22 72.04,128.79 63.26,128.79 62.77,129.28 56.16,129.28 v2(55.21,128.33) ; v2(47.52,57.22) 47.14,57.22 46.64,56.72 46.64,54.73 46.33,54.41 43.34,54.41 41.19,56.57 40.29,56.57 40.2,56.66 37.29,56.66 36.41,57.53 29.57,57.53 v2(29.18,57.15) ; v2(101.25,136.58) 100.55,137.28 100.55,144.2 101.32,144.97 111.41,144.97 v2(113.06,143.31) ; v2(206.67,48.26) 206.67,48.26 207.22,48.81 207.22,52.65 206.66,53.21 205.75,53.21 203.54,55.42 201.91,55.42 199.23,58.1 198.18,58.1 197.73,57.65 v2(197.65,57.65)
  BOTTOM w0.102: v2(53.66,59.2) 53.05,59.81 53.05,63.27 52.77,63.55 52.77,70.57 53.5,71.31 53.5,73.28 52.57,74.22 52.57,74.71 51.4,75.88 51.4,86.5 43.47,94.43 43.47,120.67 51.13,128.33 v2(55.21,128.33) ; PRZ43.2 v2(151.04,121.64) ; v2(200.38,64.26) 200.38,61.78 197.65,59.05 v2(197.65,57.65) ; PRB19.1 205.28,50.92 207.04,50.92 207.23,50.73 207.23,48.82 v2(206.67,48.26) ; RC117.1 141.62,99.4 142.17,99.4 RC113.2 142.31,100.01 142.15,100.17 142.15,102.02 141.89,102.27 141.89,105.77 141.74,105.92 141.74,116.16 v2(141.51,116.39)
H_PROCHOT#_R: length 8.4
  BOTTOM w0.076: UC1.C65 135.49,96.46 135.75,96.2 136.95,96.2 137.64,96.89 138,96.89 138.44,97.33 138.44,98.76 138.52,98.84 138.69,98.84 138.77,98.76 138.77,97.95 138.85,97.87 139,97.87 139.07,97.95 139.07,98.76 139.15,98.83 139.37,98.83 RC117.2
H_THERMTRIP#: length 7.7
  BOTTOM w0.076: UC1.C63 135.48,95.33 135.57,95.24 135.57,95.17 135.69,95.11 135.84,95.06 135.98,95.06 136.17,95.12 136.32,95.12 136.41,95.08 136.7,95.08 136.83,95.21 137.74,95.21 137.99,94.96 141.38,94.96 TP14.1 142.17,94.17 RC112.2
H_VCCST_PWRGD: length 18.8
  TOP w0.102: UC7.4 144.58,101.43 C36.1 144.31,101.16 RC104.1 143.15,100.27 142.86,100.57 142.86,103.11 142.77,103.2 142.52,103.2 142.44,103.12 142.44,99.87 142.32,99.75 142.12,99.75 142.03,99.84 142.03,103.11 141.94,103.2 141.69,103.2 141.61,103.11 v1(141.61,102.07) v2(141.61,99.98)
  BOTTOM w0.076: RC96.1 141.29,99.97 v2(141.61,99.98)
HDA_BIT_CLK: length 34.4
  TOP w0.102: RC124.2 CC91.1 94.84,52.83 95.16,53.14 v2(95.16,53.53)
  BOTTOM w0.076: UC1.AY22 114.99,71.52 114.72,71.52 114.37,71.18 112.39,71.18 112.29,71.08 110.47,71.08 110.37,71.18 108.91,71.18 108.6,70.87 107.96,70.87 107.74,71.09 107.17,71.09 107.15,71.07
  BOTTOM w0.102: v2(95.16,53.53) 95.16,60.51 105.72,71.07 107.15,71.07
HDA_CODEC_BITCLK: length 102
  TOP w0.102: UA1.6 34.29,13.05 34.58,12.76 RA43.2 35.39,13.13 35.53,13.27 37.29,13.27 v2(37.87,13.85) ; v2(97.7,50.99) v1(97.14,51.54) RC124.1
  BOTTOM w0.102: v2(37.87,13.85) 37.87,19.67 41.92,23.72 84.4,23.72 85.7,25.01 95.97,25.01 99.5,28.55 99.5,31.95 99.13,32.32 99.13,34.04 98.69,34.48 98.69,37.13 97.98,37.84 97.98,42.59 97.8,42.77 97.8,50.88 v2(97.7,50.99)
HDA_CODEC_RST#: length 1
  TOP w0.102: TP74.1 RC127.1
HDA_CODEC_SDIN0: length 3.1
  TOP w0.102: RA7.2 34.78,14.82 34.78,14.33 34.3,13.85 UA1.8
HDA_CODEC_SDOUT: length 99.9
  TOP w0.102: v2(92.51,46.5) 92.51,47.82 RC125.1
  TOP w0.112: v2(33.69,12.44) 33.48,12.65 UA1.5
  IN2 w0.127: v2(92.51,46.5) 92.77,46.76 96.47,46.76 v2(96.69,46.54)
  BOTTOM w0.102: v2(33.69,12.44) 33.05,13.08 33.05,15.87 35.11,17.93 35.11,18.62 41.21,24.71 83.91,24.71 85.16,25.95 95.37,25.95 96.68,27.26 96.68,30.26 96.66,30.28 96.66,40.16 97.04,40.54 97.04,42.2 96.69,42.56 v2(96.69,46.54)
HDA_CODEC_SYNC: length 99.1
  TOP w0.102: RC123.1 93.95,50.54 94.42,50.07 v1(96.29,50.07) v2(96.83,50.07)
  TOP w0.112: v2(33.6,15.22) 33.6,14.93 33.32,14.65 UA1.10
  BOTTOM w0.102: v2(96.83,50.07) 96.74,49.98 96.74,47.62 97.09,47.27 97.09,42.47 97.27,42.3 97.27,37.54 97.77,37.04 97.77,34.07 98.42,33.42 98.42,32.03 98.79,31.66 98.79,28.84 95.67,25.73 85.4,25.73 84.16,24.48 41.3,24.48 35.34,18.52 35.34,16.96 v2(33.6,15.22)
HDA_RST#: length 35.3
  TOP w0.102: v2(93.43,53.07) 93.06,52.7 RC127.2
  BOTTOM w0.076: 106.84,71.65 106.85,71.66 108.08,71.66 108.1,71.68 111.51,71.68 v1(111.54,71.71) 112.24,71.71 112.28,71.68 113.44,71.68 113.78,72.02 114.09,72.02 114.1,72.01 115.61,72.01 UC1.AW22
  BOTTOM w0.102: v2(93.43,53.07) 93.43,54.53 94.14,55.24 94.14,60.82 104.97,71.65 106.84,71.65
HDA_SDIN0: length 133
  TOP w0.102: v2(36.74,15.4) 36.51,15.17 RA7.1
  IN2 w0.127: v2(94.02,47.18) 94.34,47.49 96.3,47.49 96.43,47.62 97,47.62 v2(97.19,47.81)
  BOTTOM w0.076: 107.86,70.72 107.87,70.71 108.67,70.71 108.97,71.01 110.3,71.01 110.39,70.91 112.36,70.91 112.45,71.01 114.5,71.01 114.68,71.18 UC1.BA21
  BOTTOM w0.102: 107.86,70.72 107.78,70.8 106.13,70.8 96.45,61.12 96.45,61.11 95.73,60.38 95.73,53.52 93.95,51.74 93.95,47.25 v2(94.02,47.18) ; v2(97.19,47.81) 97.32,47.68 97.32,42.57 97.49,42.39 97.49,37.64 98.17,36.97 v1(98.17,36.67) 98.17,34 98.65,33.52 98.65,32.12 99.02,31.75 99.02,28.75 95.77,25.5 85.5,25.5 84.2,24.2 41.34,24.2 35.57,18.43 35.57,16.57 v2(36.74,15.4)
HDA_SDOUT: length 37.5
  TOP w0.102: RC129.2 RC126.2 RC125.2 v2(93.38,50.58)
  BOTTOM w0.076: 106.97,71.45 107.01,71.49 108.15,71.49 108.17,71.51 110.55,71.51 110.66,71.41 112.15,71.41 112.26,71.51 113.68,71.51 UC1.BB22
  BOTTOM w0.102: 106.97,71.45 105.1,71.45 94.4,60.75 94.4,55.17 93.98,54.75 93.98,52.34 93.38,51.75 v2(93.38,50.58)
HDA_SYNC: length 33.3
  TOP w0.102: RC123.2 93.95,52.64 v2(94.38,53.07)
  BOTTOM w0.076: UC1.BA22 114.36,71.75 113.96,71.35 112.33,71.35 112.22,71.24 110.55,71.24 110.45,71.35 108.79,71.35 108.62,71.18 v1(108.29,71.18) 107.95,71.18 107.87,71.26 107.11,71.26
  BOTTOM w0.102: v2(94.38,53.07) 94.2,53.25 94.2,54.66 94.65,55.1 94.65,60.68 105.23,71.26 107.11,71.26
HDD_DEVSLP: length 73.7
  TOP w0.102: v1(187.62,38.93) v2(187.62,37.98) 186.85,37.22 RS1.2
  IN1 w0.127: v2(131.83,58.89) 132.03,58.89 132.15,58.76 132.85,58.76 133.23,58.38 137.73,58.38 138.7,57.41 140.85,57.41 141.55,56.71 148.26,56.71 149.21,55.77 149.21,48.07 151.14,46.14 151.14,45.82 154.42,42.54 158.33,42.54 159.96,40.91 169.72,40.91 173.79,36.85 175.33,36.85 175.82,37.34 182.78,37.34 183,37.56 187.2,37.56 v2(187.62,37.98)
  BOTTOM w0.076: UC1.J1 131.71,59.21 131.83,59.08 v2(131.83,58.89)
HDD_DEVSLP_R: length 4.2
  TOP w0.102: v2(186.53,34.79) 186.85,35.11 RS1.1 187.22,35.42 187.42,35.62 187.42,37.09 v1(187.64,37.31)
  BOTTOM w0.102: v2(186.53,34.79) 186.7,34.96 JHDD1.8
HDD_EN_PCH: length 59
  IN1 w0.127: v2(150.91,51.1) 150.91,48.58 152.66,46.83 152.66,46.46 155.04,44.08 158.95,44.08 160.59,42.44 170.36,42.44 173.26,39.53 174.97,39.53 v2(175.31,39.19)
  BOTTOM w0.076: UC1.J4 132.05,61.2 132.05,59.28 132.66,58.67 133.01,58.67 134.22,57.46 135.92,57.46 136.64,56.75 136.64,55.4 136.84,55.21
  BOTTOM w0.102: US2.4 176.42,39.36 176.25,39.19 v2(175.31,39.19) ; v2(150.91,51.1) 150.89,51.1 v1(150.44,50.65) 150.01,50.22 145.69,50.22 141.57,54.34 139.65,54.34 139.37,54.62 137.42,54.62 RC209.2 136.84,55.21
HDMI_CLK: length 147.4
  IN2 w0.076: 134.83,92.78 134.82,92.77 134.82,92.71 134.57,92.46 133.87,92.46 133.83,92.5 133.36,92.5 133.16,92.3 133.16,91.91 133.04,91.79 132.94,91.79 v2(132.84,91.89)
  IN2 w0.122: v2(21.61,99.63) 21.86,99.88 22.54,99.88 44.14,121.48 63.95,121.48 65.68,123.21 74.74,123.21 75.2,122.75 76.74,122.75 78,121.48 86.16,121.48 87.17,120.47 118.15,120.47 131.57,107.05 131.57,104.94 135.17,101.34 135.17,100.15 135.94,99.37 135.94,95.74 135.71,95.5 135.71,93.66 134.83,92.78
  BOTTOM w0.076: UC1.G56 132.52,91.56 v2(132.84,91.89)
  BOTTOM w0.097: CI2.1 21.01,99.87 21.37,99.87 v2(21.61,99.63)
HDMI_CLK#: length 147.5
  IN2 w0.076: 135.01,92.61 135,92.6 134.94,92.6 134.64,92.3 133.8,92.3 133.77,92.34 133.43,92.34 133.32,92.23 133.32,92.1 v2(133.53,91.89)
  IN2 w0.122: 135.01,92.61 135.95,93.55 135.95,95.4 136.19,95.64 136.19,99.47 135.42,100.25 135.42,101.44 131.81,105.04 131.81,107.15 118.25,120.72 87.27,120.72 86.26,121.73 78.11,121.73 76.84,123 75.31,123 74.85,123.46 65.58,123.46 63.85,121.73 44.04,121.73 22.44,100.13 21.69,100.13 v2(21.61,100.21)
  BOTTOM w0.076: UC1.F56 133.17,91.54 v2(133.53,91.89)
  BOTTOM w0.097: CI1.1 20.93,100.06 21.46,100.06 v2(21.61,100.21)
HDMI_CLK#_R: length 3.8
  TOP w0.097: v2(18.96,100.21) 18.55,100.62 RPI2.6
  BOTTOM w0.097: CI1.2 19.36,100.02 19.16,100.02 v2(18.96,100.21) 18.74,99.99 18.53,99.99 18.35,100.17 LI1.3 17.95,100.34 RI2.1
HDMI_CLK#_R_C: length 7.1
  BOTTOM w0.097: JHDMI1.12 13.01,97.44 13.33,97.44 13.62,97.73 13.62,99.37 14.27,100.02 15.23,100.02 RI3.1 15.96,100.02 16.51,100.02 16.67,100.17 LI1.4 17.04,100.34 RI2.2
HDMI_CLK_R: length 3.8
  TOP w0.097: RPI2.5 18.47,100.12 v2(18.96,99.63)
  BOTTOM w0.097: RI1.1 17.95,99.5 LI1.2 18.44,99.67 18.58,99.8 18.79,99.8 v2(18.96,99.63) 19.16,99.83 19.36,99.83 CI2.2
HDMI_CLK_R_C: length 7.1
  BOTTOM w0.097: RI1.2 17.04,99.5 LI1.1 16.67,99.67 16.51,99.83 15.95,99.83 RI3.2 15.23,99.83 14.34,99.83 13.81,99.29 13.81,97.66 13.41,97.26 13.01,97.26 JHDMI1.10
HDMI_DATA0: length 150.3
  IN2 w0.076: 134.83,91.72 134.82,91.71 134.82,91.65 134.69,91.52 134.69,90.84 134.43,90.57 133.85,90.57 133.81,90.61 133.38,90.61 133.17,90.39 133.17,90.2 133.03,90.07 v2(132.87,90.07)
  IN2 w0.122: v2(22.21,101.14) 22.47,101.4 23.1,101.4 43.86,122.15 63.67,122.15 65.4,123.88 75.15,123.88 75.61,123.42 77.02,123.42 78.28,122.15 86.5,122.15 87.51,121.15 118.43,121.15 132.24,107.33 132.24,105.31 135.93,101.62 135.93,100.34 136.62,99.65 136.62,95.37 136.38,95.13 136.38,93.27 134.83,91.72
  BOTTOM w0.076: v2(132.87,90.07) 132.87,90.03 UC1.G53
  BOTTOM w0.097: v2(22.21,101.14) 21.9,101.45 21.67,101.45 21.35,101.78 21.08,101.78 CI4.1
HDMI_DATA0#: length 150.3
  IN2 w0.076: 135.01,91.55 135,91.53 134.94,91.53 134.85,91.45 134.85,90.77 134.49,90.41 133.78,90.41 133.74,90.44 133.45,90.44 133.33,90.32 133.33,90.23 v2(133.5,90.05)
  IN2 w0.122: 135.01,91.55 136.63,93.17 136.63,95.03 136.87,95.27 136.87,99.75 136.18,100.44 136.18,101.72 132.49,105.41 132.49,107.43 118.53,121.39 87.61,121.39 86.6,122.4 78.39,122.4 77.12,123.67 75.72,123.67 75.25,124.13 65.3,124.13 63.57,122.4 43.76,122.4 23,101.64 22.29,101.64 v2(22.21,101.73)
  BOTTOM w0.076: v2(133.5,90.05) 133.17,89.72 UC1.F53
  BOTTOM w0.097: v2(22.21,101.73) 22.13,101.64 21.74,101.64 21.42,101.96 20.87,101.96 CI3.1
HDMI_DATA0#_R: length 3.8
  TOP w0.097: v2(18.96,102.06) 18.53,101.62 RPI2.8
  BOTTOM w0.097: CI3.2 19.36,101.86 19.16,101.86 v2(18.96,102.06) 18.74,101.83 18.53,101.83 18.35,102.01 LI2.3 17.95,102.18 RI4.1
HDMI_DATA0#_R_C: length 12
  BOTTOM w0.097: RI4.2 17.04,102.18 LI2.4 16.67,102.01 16.51,101.86 15.96,101.86 RI6.1 15.23,101.86 12.52,101.86 11.73,101.07 11.73,96.08 11.59,95.94 11.46,95.94 JHDMI1.9
HDMI_DATA0_R: length 3.7
  TOP w0.097: RPI2.7 18.62,101.12 v2(18.96,101.47)
  BOTTOM w0.097: CI4.2 19.36,101.67 19.16,101.67 v2(18.96,101.47) 18.79,101.65 18.58,101.65 18.44,101.51 LI2.2 17.95,101.35 RI5.1
HDMI_DATA0_R_C: length 12
  BOTTOM w0.097: JHDMI1.7 11.46,95.76 11.67,95.76 11.92,96.01 11.92,100.99 12.6,101.67 15.23,101.67 RI6.2 15.95,101.67 16.51,101.67 16.67,101.51 LI2.1 17.04,101.35 RI5.2
HDMI_DATA1: length 145
  IN2 w0.076: v2(133.42,92.87) 133.61,92.87 133.7,92.96 133.7,93.28 133.87,93.45 134.24,93.45 134.44,93.65 134.44,94.08 134.38,94.13
  IN2 w0.122: 134.38,94.13 134.37,94.14 134.37,95.19 135.27,96.09 135.27,98.78 133.55,100.5 133.55,101.13 130.89,103.79 130.89,106.77 117.87,119.79 86.89,119.79 85.88,120.8 77.71,120.8 76.45,122.07 74.92,122.07 74.46,122.53 65.96,122.53 64.23,120.8 44.42,120.8 22.44,98.83 22.44,98.38 22.19,98.12 21.95,98.12 21.62,97.79 v2(21.61,97.79)
  BOTTOM w0.076: UC1.F58 133.42,92.68 v2(133.42,92.87)
  BOTTOM w0.097: CI6.1 21.03,98.04 21.38,98.04 21.61,97.81 v2(21.61,97.79)
HDMI_DATA1#: length 145
  IN2 w0.076: 134.62,94.13 134.62,94.13 134.6,94.11 134.6,93.58 134.31,93.28 133.94,93.28 133.87,93.21 133.87,93.06 v2(134.06,92.87)
  IN2 w0.122: 134.62,94.13 134.62,95.09 135.52,95.98 135.52,98.89 133.8,100.6 133.8,101.23 131.14,103.9 131.14,106.87 117.97,120.04 86.99,120.04 85.98,121.05 77.82,121.05 76.55,122.32 75.03,122.32 74.57,122.78 65.86,122.78 64.13,121.05 44.32,121.05 22.2,98.93 22.2,98.48 22.08,98.37 v2(21.61,98.37)
  BOTTOM w0.076: UC1.E58 134.06,92.66 v2(134.06,92.87)
  BOTTOM w0.097: CI5.1 20.92,98.23 21.47,98.23 v2(21.61,98.37)
HDMI_DATA1#_R: length 3.8
  TOP w0.097: RPI1.8 18.53,97.94 v2(18.96,98.37)
  BOTTOM w0.097: CI5.2 19.36,98.17 19.16,98.17 v2(18.96,98.37) 18.77,98.18 18.63,98.18 18.41,98.39 LI4.3 18.08,98.39 RI11.1
HDMI_DATA1#_R_C: length 7.9
  BOTTOM w0.097: RI11.2 16.91,98.39 LI4.4 16.58,98.39 16.36,98.17 15.96,98.17 RI12.1 15.23,98.17 14.84,98.17 14.51,97.85 14.51,97.21 13.5,96.2 13.5,94.67 13.27,94.44 13.01,94.44 JHDMI1.6
HDMI_DATA1_R: length 3.8
  TOP w0.097: RPI1.7 18.62,97.44 v2(18.96,97.79)
  BOTTOM w0.097: CI6.2 19.36,97.99 19.16,97.99 v2(18.96,97.79) 18.76,97.99 18.53,97.99 18.43,97.89 LI4.2 17.95,97.73 RI10.1
HDMI_DATA1_R_C: length 7.9
  BOTTOM w0.097: RI10.2 17.04,97.73 LI4.1 16.5,97.89 16.41,97.99 15.95,97.99 RI12.2 15.23,97.99 14.92,97.99 14.7,97.77 14.7,97.14 13.68,96.12 13.68,94.6 13.34,94.26 13.01,94.26 JHDMI1.4
HDMI_DATA2: length 148.2
  IN2 w0.076: 132.92,94.76 132.91,94.74 132.91,94.68 132.23,94 132.23,91.75 132.63,91.35 133.7,91.35 133.83,91.21 133.83,91.07 133.74,90.98 v2(133.5,90.98)
  IN2 w0.122: 132.92,94.76 134.59,96.42 134.59,98 134.3,98.29 134.02,98.29 132.75,99.56 132.75,100.97 130.21,103.51 130.21,106.32 117.41,119.12 86.61,119.12 85.6,120.13 77.43,120.13 76.17,121.4 74.64,121.4 74.18,121.86 66.3,121.86 64.57,120.13 44.7,120.13 23.21,98.63 23.21,97.39 22.1,96.28 21.95,96.28 21.62,95.95 v2(21.61,95.95)
  BOTTOM w0.076: v2(133.5,90.98) 133.5,90.74 133.36,90.6 UC1.F55
  BOTTOM w0.097: CI8.1 20.97,96.14 21.41,96.14 v2(21.61,95.95)
HDMI_DATA2#: length 148.3
  IN2 w0.076: v2(134.18,90.96) 134.18,90.98 134,91.17 134,91.28 133.76,91.51 132.7,91.51 132.39,91.81 132.39,93.93 133.03,94.57 133.09,94.57 133.1,94.58
  IN2 w0.122: 133.1,94.58 134.84,96.32 134.84,98.11 134.41,98.54 134.12,98.54 133,99.66 133,101.08 130.46,103.62 130.46,106.42 117.51,119.37 86.71,119.37 85.7,120.38 77.54,120.38 76.27,121.65 74.75,121.65 74.29,122.11 66.2,122.11 64.47,120.38 44.6,120.38 22.96,98.74 22.96,97.49 22,96.53 v2(21.61,96.53)
  BOTTOM w0.076: v2(134.18,90.96) 133.82,90.6 UC1.E55
  BOTTOM w0.097: v2(21.61,96.53) 21.41,96.33 20.97,96.33 CI7.1
HDMI_DATA2#_R: length 3.8
  TOP w0.097: v2(18.96,96.53) 18.55,96.94 RPI1.6
  BOTTOM w0.097: CI7.2 19.36,96.33 19.16,96.33 v2(18.96,96.53) 18.77,96.34 18.63,96.34 18.41,96.55 LI3.3 18.08,96.55 RI8.1
HDMI_DATA2#_R_C: length 10.5
  BOTTOM w0.097: RI8.2 17,96.68 LI3.4 16.52,96.55 16.3,96.33 15.96,96.33 RI9.1 15.23,96.33 14.76,96.33 14.32,95.89 14.32,93.09 13.43,92.2 12.1,92.2 11.92,92.37 11.92,92.74 11.71,92.94 11.46,92.94 JHDMI1.3
HDMI_DATA2_R: length 3.9
  TOP w0.097: v2(18.96,95.95) 18.47,96.44 RPI1.5
  BOTTOM w0.097: RI7.1 17.95,95.88 LI3.2 18.43,96.05 18.53,96.15 18.76,96.15 v2(18.96,95.95) 19.16,96.14 19.36,96.14 CI8.2
HDMI_DATA2_R_C: length 10.5
  BOTTOM w0.097: JHDMI1.1 11.46,92.76 11.64,92.76 11.74,92.66 11.74,92.3 12.02,92.01 13.51,92.01 14.51,93.01 14.51,95.82 14.84,96.14 15.23,96.14 RI9.2 15.95,96.14 16.34,96.14 16.44,96.05 LI3.1 17.04,95.88 RI7.2
HDMI_HPD_B: length 11.7
  BOTTOM w0.102: QI3.1 21.19,104.44 RI16.1 v1(18.53,104.44) 15.8,104.44 13.8,102.44 12.14,102.44 JHDMI1.19
HDMI_PLL_GND: length 10.6
  TOP w0.508: v2(20.75,105.08) 20.76,105.09 QI1.1
  IN2 w0.508: v2(14.77,99.32) 14.77,100.47 18.73,104.43 20.1,104.43 v2(20.75,105.08)
  vias: v1(14.69,97.8)
HOST_DEBUG_TX: length 98.5
  TOP w0.102: RE57.2 v2(41.28,92.74) 41.91,92.74 42.5,93.33 JDEG1.8 ; v2(50.52,69.46) 50.39,69.46 50.22,69.63 UE1.81 ; v2(58.2,131.12) 59.49,132.41 v1(62.09,132.41) RW6.1 RW10.1
  IN1 w0.127: v2(41.28,92.74) 41.28,87.74 42.28,86.73 45.08,86.73 46.88,84.93 46.88,78.34 45.5,76.96 45.5,75.75 44.99,75.24 44.99,74.54 46.64,72.89 46.64,71.43 48.61,69.46 v2(50.52,69.46)
  BOTTOM w0.102: v2(41.28,92.74) 41.06,92.96 41.06,120.38 50.5,129.82 56.9,129.82 v2(58.2,131.12)
HPOUT_L: length 24.1
  TOP w0.305: RA36.2 20.61,11.82 18.93,11.82 v1(18.37,12.38) 17.81,12.38 17.69,12.5 v2(17.37,12.5)
  BOTTOM w0.305: JHP1.1 13.78,7.9 14.64,8.76 16.42,8.76 17.62,9.96 17.62,11.49 19.47,13.33 19.47,16.82 19.36,16.92 DA4.2 17.97,16.04 18.14,15.86 CA35.1 RA30.1 18.14,13.28 v2(17.37,12.5)
HPOUT_R: length 20.9
  TOP w0.305: v2(16.73,13.01) 18.78,13.01 19.67,13.9 v1(20.05,13.9) RA37.2
  BOTTOM w0.305: JHP1.2 8.6,18.85 15.53,18.85 16.04,18.35 DA4.3 16.04,16.67 15.45,16.09 CA34.1 RA34.1 15.45,13.79 16.23,13.01 v2(16.73,13.01)
HW_ACAV_IN: length 426.8
  TOP w0.102: v2(27.94,78.67) 28.25,78.36 33.08,78.36 33.55,78.83 CE32.2 34.37,78.13 34.99,78.13 35.2,77.92 UE1.128
  TOP w0.254: v2(207.11,31.83) 206.93,32.01 206.93,35.12 207.68,35.87 207.68,38.25 205.38,40.55 205.38,43.61 207.62,45.84 207.62,50.07 207.42,50.27 207.42,52.58 206.85,53.14 206.09,53.14 205.58,52.64 204.68,52.64 PRB14.1 203.81,53.27 v2(203.42,52.89) ; PR31.1 122.83,138.16 123.52,138.84 124.05,138.84 125.03,139.82 v1(125.03,141.74) v2(125.03,143.53)
  IN1 w0.127: v2(207.11,31.83) 205.91,30.63 182.38,30.63 179.83,28.09 158.75,28.09 158.23,27.57 145.67,27.57 143.05,30.19 140.27,30.19 136.43,26.35 119.55,26.35 118.85,27.05 114.39,27.05 113.38,26.04 105.76,26.04 104.12,27.69 101.95,27.69 101.01,26.75 99.02,26.75 97.96,25.68 58.49,25.68 55.13,29.04 54.2,29.04 49.21,34.03 44.52,34.03 36.83,41.72 36.83,52.5 28.91,60.42 28.91,66.44 28.56,66.78 28.56,75.8 27.52,76.84 27.52,78.25 v2(27.94,78.67) 28.02,78.67 30.11,80.76 30.11,83.56 29.57,84.09 29.57,88.08 28.1,89.55 28.1,91.99 27.75,92.35 27.75,117.25 32.88,122.39 32.88,123.6 36.14,126.87 52.44,126.87 59.58,134.01 69.85,134.01 84.11,148.27 90.71,148.27 91.6,147.38 96.6,147.38 97.95,148.73 99.87,148.73 100.64,147.95 122.44,147.95 125.03,145.36 v2(125.03,143.53)
  BOTTOM w0.203: PUB01.2 202.84,51.66 203.13,51.95 203.13,52.6 v2(203.42,52.89) 203.81,53.27 PRB14.1
I2C0_SCL_TCH_PAD: length 41
  TOP w0.102: Q10.1 121.72,28.9 121.83,29.01 122.08,29.01 122.59,28.5 R34.2 122.78,29.71 122.63,29.87 v1(121.08,29.87) 121.04,29.87 120.68,30.23 120.68,31.07 126.37,36.77 126.37,38.95 126.08,39.24 126.08,40.18 v2(126.28,40.38)
  IN2 w0.127: v2(127.24,61.91) 127.1,61.77 127.1,60.98 126.91,60.79 126.91,55.41 127.1,55.22 127.1,53.5 127.14,53.46 127.16,53.46 127.45,53.17 127.45,51.41 126.16,50.12 126.16,42.33 126.17,42.32 126.17,40.49 v2(126.28,40.38)
  BOTTOM w0.076: UC1.U6 127.24,62.06 v2(127.24,61.91)
I2C0_SDA_TCH_PAD: length 43.9
  TOP w0.102: v2(125.7,40.38) 125.86,40.22 125.86,39.14 126.15,38.85 126.15,36.86 v1(119.53,30.25) 118.61,30.25 118.02,29.65 118.02,26.93 R33.2 118.37,26.59 Q10.4
  IN2 w0.127: v2(125.7,40.38) 125.92,40.6 125.92,42.21 125.91,42.22 125.91,50.22 127.2,51.51 127.2,53.06 127.05,53.21 127.03,53.21 126.84,53.4 126.84,55.11 126.65,55.3 126.65,60.84 126.83,61.02 126.83,62.33 127.13,62.63 v2(127.13,62.63)
  BOTTOM w0.076: v2(127.13,62.63) 127.13,62.63 127.47,62.97 UC1.U7
I2C_SCL_TP: length 6.7
  TOP w0.102: v2(120.94,27.69) 121.72,26.91 Q10.6 121.72,26.58 R46.2 v1(122.77,25.56)
  BOTTOM w0.102: JTP1.6 120.05,28.58 v2(120.94,27.69)
I2C_SDA_TP: length 4
  TOP w0.102: v2(118.5,29.49) 118.5,28.74 118.73,28.5 R47.2 119.37,28.49 Q10.3
  BOTTOM w0.102: JTP1.7 119.05,30.04 v2(118.5,29.49)
I_ADP: length 13.4
  TOP w0.102: v1(46.31,82.25) 45.8,81.74 v2(45.8,81.74) 45.79,81.75 45.53,81.75 45.2,81.42 RE51.1 44.26,81.42 CE25.1 ; UE1.110 42.4,75.95 42.7,75.65 43.01,75.65 43.51,75.15 44.39,75.15 v2(44.58,75.34)
  IN1 w0.127: v2(44.58,75.34) 44.46,75.46 44.46,80.42 45.77,81.74 v2(45.8,81.74)
I_ADP_R: length 230.9
  TOP w0.102: RE51.2 v2(45.79,82.34)
  TOP w0.254: v2(206.47,35.81) 207.3,36.63 207.3,38.1 205,40.39 205,43.77 206.87,45.63 v1(206.87,45.88) 206.87,45.91 207.23,46.27 207.23,49.28 206.62,49.89 206.16,49.89 v2(205.67,50.38)
  IN1 w0.127: v2(45.79,82.34) 45.26,82.34 43.75,80.82 43.75,77.78 43.37,77.39 43.37,75.24 43.96,74.65 43.96,65.85 46.26,63.55 46.26,62.3 48.21,60.35 48.21,54.91 47.87,54.58 47.87,52.99 48.51,52.36 48.51,44.82 57.03,36.29 61.2,36.29 63.08,34.41 89.72,34.41 90.17,34.86 103.85,34.86 104.83,33.87 129.24,33.87 135.17,39.81 150.46,39.81 154.4,35.87 157.11,35.87 160.4,32.59 179.81,32.59 180.9,33.68 192.31,33.68 193.58,34.95 203.2,34.95 204.06,35.81 v2(206.47,35.81)
  BOTTOM w0.203: PRB20.1 PCB25.1 205.89,50.16 v2(205.67,50.38)
I_BATT: length 3.6
  TOP w0.102: RE54.1 41.45,80.58 CE30.1 41.45,79.2 41.25,78.99 v1(41.25,78.79) 40.8,78.34 UE1.114
I_BATT_R: length 226
  TOP w0.102: RE54.2 41.19,81.79 v2(41.19,82.15)
  TOP w0.254: v2(205.77,34.92) v1(205.77,35.79) 206.92,36.94 206.92,37.94 204.62,40.24 204.62,43.92 206.09,45.4 206.09,48.45 v2(206.66,49.02)
  IN1 w0.127: v2(41.19,82.15) 41.19,81.43 41.34,81.28 41.34,78.45 40.77,77.88 40.77,65.88 42.29,64.35 42.29,61.43 42.9,60.82 42.9,55.25 46.38,51.77 46.38,45.33 56.56,35.15 60.57,35.15 62.45,33.27 90.95,33.27 92.03,34.35 101.56,34.35 102.54,33.36 144.36,33.36 146.48,31.25 152.76,31.25 153.6,32.08 180.02,32.08 181.11,33.17 192.52,33.17 193.79,34.44 203.41,34.44 203.89,34.92 v2(205.77,34.92)
  BOTTOM w0.254: PRB23.1 204.97,48.84 PCB26.1 206.49,48.84 v2(206.66,49.02)
I_SYS: length 106.8
  TOP w0.102: v2(200.31,65.15) v1(200.87,65.15)
  TOP w0.254: v2(154.78,113.52) 154.53,113.77 PRZ11.2
  IN1 w0.127: v2(200.31,65.15) 198.79,63.62 198.79,57.13 201.89,54.03 201.89,53.68 202.83,52.74 202.83,48.84 v2(202.87,48.8)
  IN2 w0.127: v2(154.78,113.52) 154.78,107.02 156.13,105.68 160.48,105.68 164.22,101.93 164.22,78.44 170.05,72.61 180.8,72.61 187.09,66.33 199.3,66.33 200.31,65.31 v2(200.31,65.15)
  BOTTOM w0.203: PRB24.1 203.49,47.94 203.36,48.06 203.36,48.34 202.9,48.8 v2(202.87,48.8) 202.83,48.84 202.83,49.14 202.71,49.26 PUB01.8 ; PUZ01.46 154.38,113.7 154.57,113.52 v2(154.78,113.52)
ICCMAX_1A_CPU: length 2.3
  BOTTOM w0.203: PRZ67.1 145.86,115.43 147.15,115.43 147.28,115.3 PUZ01.19
ICCMAX_1B_CPU: length 2.3
  BOTTOM w0.203: PRZ68.1 145.64,116.06 145.93,115.76 147.3,115.76 147.36,115.7 PUZ01.20
ICCMAX_2PH_CPU: length 2.6
  TOP w0.102: v2(146.9,114.93) 147.17,115.2 v1(147.68,115.2)
  TOP w0.254: PRZ66.1 146.9,114.72 v2(146.9,114.93)
  BOTTOM w0.203: v2(146.9,114.93) 146.92,114.9 PUZ01.18
ICSP_CLK: length 24.7
  TOP w0.102: UE1.101 v2(46,75.97) ; v2(43.6,88.48) 44.03,88.48 44.87,87.63 v1(46.33,87.63) 48.52,87.63 49.23,88.35 49.23,90.1 RE60.2
  IN1 w0.127: v2(43.6,88.48) 43.69,88.48 47.13,85.04 47.13,78.23 46,77.11 v2(46,75.97)
ICSP_CLR: length 21
  TOP w0.102: RE61.2 48.83,89.62 v1(48.83,89.39) 48.83,89.11 48.42,88.7 v2(48.04,88.7) ; UE1.87 48.23,72.03 47.94,72.31 v2(47.94,72.54)
  IN1 w0.127: v2(47.94,72.54) 48.22,72.82 48.22,79.49 48.26,79.53 48.26,88.48 v2(48.04,88.7)
ICSP_DAT: length 21.7
  TOP w0.102: UE1.102 45.6,76.3 45.6,76.29 45.6,75.77 v2(45.98,75.39) ; RE63.2 v2(44.01,89.21) 44.01,89.05 v1(44.36,88.7)
  IN1 w0.127: v2(45.98,75.39) 46.17,75.2 46.76,75.2 47.14,75.58 47.14,77.72 47.97,78.54 47.97,79.6 48.01,79.64 48.01,84.52 44.67,87.85 44.67,88.55 v2(44.01,89.21)
ILIM_1A_CPU: length 3.1
  TOP w0.203: PCZ32.1 PRZ56.1 148.37,118.85 v2(148.88,119.36)
  BOTTOM w0.203: PUZ01.27 149.41,118.76 148.88,119.29 v2(148.88,119.36)
ILIM_1B_CPU: length 4.1
  TOP w0.102: PRZ05.1 155.16,113.98 v1(155.28,113.98)
  TOP w0.254: PRZ05.1 PCZ05.1 155.08,115.61 v2(155.1,115.59)
  BOTTOM w0.203: v2(155.1,115.59) 154.97,115.59 154.69,115.3 PUZ01.42
ILIM_2PH_CPU: length 2.8
  BOTTOM w0.203: PUZ01.5 151.41,111.04 v1(151.62,110.83) 151.86,110.58 151.86,110.35 PRZ28.2
ILMT_+1VALW: length 3
  TOP w0.254: PRH03.2 PRH04.1 166.79,52.54 v2(166.4,52.92)
  BOTTOM w0.254: v2(166.4,52.92) 166.49,53.01 PUH01.12
IMVP_VR_ON: length 22.7
  TOP w0.102: v1(146.03,107.87) v2(145.56,107.39) 145.48,107.32 RC107.2
  IN1 w0.254: v2(145.56,107.39) 145.56,108.9 146.49,109.83 146.49,111.34 145.6,112.23 145.6,114.38 146.63,115.41 148.41,115.41 150.61,117.61 154.41,117.61 155.86,119.06 v2(155.86,119.29)
  BOTTOM w0.254: PRZ22.2 156.76,118.8 156.27,119.29 v2(155.86,119.29)
INT_TP#: length 18.9
  TOP w0.102: Q9.3 110.22,27.06 v2(111.25,28.09) 111.34,28.18 111.34,28.36 R39.2 110.32,29.38 110.32,30.87 v1(110.52,31.07)
  IN1 w0.127: v2(111.25,28.09) 111.41,27.92 113.11,27.92 114.48,29.29 117.26,29.29 118,30.04 121.2,30.04 v2(121.78,29.46)
  BOTTOM w0.102: JTP1.4 122.05,29.73 v2(121.78,29.46)
INTRUDER#: length 22.1
  TOP w0.102: RC91.1 103.15,61.15 v1(103.72,61.15) 104.19,61.15 104.77,60.56 106.76,60.56 v2(106.84,60.64)
  IN2 w0.127: v2(106.84,60.64) 106.84,60.13 107.39,59.58 107.82,59.58 108.99,60.74 109.38,61.14 110.11,61.14 115.87,66.89 115.89,66.89 115.89,68.21 116.27,68.59 118.24,68.59 v2(118.66,69.01)
  BOTTOM w0.102: v2(118.66,69.01) 118.95,68.66 UC1.AP16
IOUT_1A_CPU: length 4
  TOP w0.102: PRZ50.1 v1(152.98,118.74)
  TOP w0.203: PRZ50.1 PCZ25.1 150.78,118.99 v2(150.78,119.36)
  BOTTOM w0.102: PUZ01.30 150.61,119.18 v2(150.78,119.36)
IOUT_1B_CPU: length 4.1
  TOP w0.102: PRZ15.1 154.42,118.22 v1(154.26,118.38)
  TOP w0.254: v2(155.08,116.88) 154.91,116.88 154.53,116.5 PCZ12.1 PRZ15.1
  BOTTOM w0.203: v2(155.08,116.88) 154.77,116.88 154.39,116.5 PUZ01.39
IOUT_2PH_CPU: length 3.1
  TOP w0.102: v2(153.45,111.48) 153.89,111.48 v1(154.01,111.36)
  TOP w0.254: v2(153.45,111.48) 153.44,111.47 PRZ23.1 PCZ14.1
  BOTTOM w0.203: PUZ01.1 153.01,111.74 153.26,111.48 v2(153.45,111.48)
IR_GND: length 1.3
  BOTTOM w0.102: JEDP1.24 v1(211.11,48.95)
ISOLATE#: length 5.4
  TOP w0.102: UL1.20 24.68,88.71 25.56,89.59 25.89,89.59 RL4.1 RL3.2 27.75,90.03 v1(28.3,90.58)
JACK_PLUG: length 6.1
  TOP w0.254: JHP1.5 13.44,17.4 13.85,17.81 v1(14.61,17.81) 14.64,17.84 15.4,17.84 16.09,17.15 DA7.2 16.09,16.11 15.78,15.81 RA39.2
JACK_PLUG_DET: length 12.1
  TOP w0.102: v1(18.8,15.17) 18.45,15.17 18.37,15.25 RA40.1
  TOP w0.254: JHP1.6 10.66,17.4 10.66,17.41 10.76,17.41 11.58,18.22 16.16,18.22 16.67,17.71 17.23,17.71 DA7.3 18.02,15.71 RA40.1
JTAG_CLK: length 6.9
  TOP w0.102: RPE7.3 45.6,92.54 45.47,92.67 45.12,92.67 44.5,93.3 JDEG1.4 44.5,94.77 45.14,95.41 v1(47.84,95.41)
JTAG_TDI: length 6.3
  TOP w0.102: v1(49.99,91.61) RE60.1 48.14,92.11 RPE7.1 46.6,92.62 46.04,93.18 45.63,93.18 45.5,93.31 JDEG1.2
JTAG_TDO: length 6.8
  TOP w0.102: v1(45.83,89.11) 45.7,89.11 44.66,90.15 44.66,91.32 45.1,91.76 RPE7.4 44.02,92.11 RE63.1 44,92.12 JDEG1.5
JTAG_TMS: length 8.6
  TOP w0.102: v1(47.76,88.2) 47.3,88.66 47.3,91.19 47.72,91.61 ; RE61.1 47.72,91.61 ; 47.72,91.61 47.11,91.61 47.03,91.53 46.29,91.53 46.1,91.73 RPE7.2 46.1,92.61 45.79,92.93 45.34,92.93 45,93.27 JDEG1.3
KB_BL_CTRL#: length 5.7
  TOP w0.102: Q8.1 90.31,32.6 92.57,32.6 EC3001.1 92.62,32.93 v2(92.27,33.28) 92.27,33.68 v1(91.8,34.15)
  BOTTOM w0.102: v2(92.27,33.28) 92.05,33.5 JKBBL1.4
KB_DET#: length 116.7
  TOP w0.102: v2(127.76,35.36) 128.02,35.63 v1(128.02,35.87) 128.41,36.25 128.41,40.02 127.03,41.39 127.03,43.11 126.93,43.21 126.93,44.77 125.39,46.31 124.18,46.31 116.55,53.94 116.55,57.32 v2(116,57.87)
  IN1 w0.127: v2(116,57.87) 116.07,57.87 116.54,58.33 116.54,58.89 117.33,59.69 122.73,59.69 v2(123.2,59.21) ; v2(127.76,35.36) 127.57,35.17 109.99,35.17 109.8,35.37 85.78,35.37 v2(85.18,35.96)
  BOTTOM w0.076: UC1.AD4 123.5,61.17 123.5,60.69 123.32,60.39 123.32,60.08 123.37,59.98 123.37,59.85 123.2,59.53 v2(123.2,59.21)
  BOTTOM w0.102: v2(123.2,59.21) 123.2,58.91 123.16,58.86 123.16,56.78 RC45.1 ; v2(85.18,35.96) 85.18,33.27 82.77,30.86 61.95,30.86 59.75,33.05 JKB1.1
KB_LED_BL_DET: length 68.4
  TOP w0.102: v2(92.39,37.81) 92.45,37.81 93.13,37.14 v1(93.13,36.03) 93.13,32.15 R26.1 R27.1
  IN1 w0.127: v2(92.39,37.81) 96.08,37.81 96.55,38.29 102.78,38.29 104.57,40.07 104.57,40.93 105.11,41.46 106.76,41.46 108.23,39.99 114.48,39.99 115.77,38.69 122.74,38.69 v2(123.88,39.84)
  IN2 w0.127: v2(126.99,63.64) 126.61,63.27 126.61,61.69 126.4,61.47 126.4,57.04 125.17,55.81 125.17,51.28 124.19,50.3 124.19,43.65 124.01,43.47 124.01,39.96 v2(123.88,39.84)
  BOTTOM w0.102: UC1.W8 126.97,63.62 v2(126.99,63.64)
KB_LED_DET_C: length 3
  TOP w0.102: R26.2 93.63,33.03 v2(93.76,33.16) v1(93.76,34.02)
  BOTTOM w0.102: v2(93.76,33.16) 94.05,33.45 JKBBL1.2
KB_LED_PWM: length 71.2
  TOP w0.102: UE1.44 39.6,60.34 v2(39.55,60.29) ; Q8.2 v1(87.35,30.42) 86.69,29.75 86.27,29.75 v2(86.24,29.78)
  IN1 w0.127: v2(86.24,29.78) 86.22,29.75 85.76,29.75 85.45,29.45 65.86,29.45 64.72,30.59 62.61,30.59 59.83,33.37 54.55,33.37 44.6,43.32 44.6,50.92 39.8,55.72 39.8,60.03 v2(39.55,60.29)
KBLR_XTAL_IN: length 11.6
  BOTTOM w0.076: 134.03,59.33 133.98,59.38 133.98,60.6 UC1.E3
  BOTTOM w0.102: 134.03,59.33 134.21,59.15 134.21,59.03 134.15,58.96 134.15,58.84 134.3,58.68 134.43,58.68 134.58,58.84 134.75,58.84 134.85,58.74 134.85,58.57 134.69,58.42 134.69,58.29 134.87,58.11 135,58.11 135.06,58.18 135.18,58.18 135.31,58.05 135.54,58.05 135.72,58.22 135.96,58.22 138.7,55.48 v1(139.94,55.48) 140.79,55.48 RC25.1
KBLR_XTAL_IN_R: length 3.8
  BOTTOM w0.102: RC25.2 142.54,54.64 RC22.2 143.07,54.33 CC17.1 143.72,54.33 144.89,53.16 YC3.3
KBLR_XTAL_OUT: length 12.4
  BOTTOM w0.076: 134.67,59.42 134.56,59.68 134.56,61.17 134.27,61.88 134.27,62.53 134.33,62.69 134.38,62.74 134.6,62.83 134.66,62.83 134.79,62.88 134.87,62.96 UC1.C7
  BOTTOM w0.102: RC26.1 140.83,55.82 138.81,55.82 v1(138.72,55.91) 136.06,58.57 135.51,58.57 134.67,59.42
KBLR_XTAL_OUT_R: length 5.8
  BOTTOM w0.102: YC3.1 145.63,54.34 144.19,54.34 143.59,54.94 CC18.1 143.38,54.94 RC22.1 142.24,56.07 RC26.2
KSI0: length 71.5
  TOP w0.102: RPE1.4 51.32,79.92 51.18,79.78 51.18,79.21 v1(50.78,78.81) 49.91,77.94 v2(49.79,77.94) 48.26,77.94 47.82,78.39 47.41,78.39 47.2,78.18 UE1.98
  BOTTOM w0.102: JKB1.9 66.15,34.6 64.02,36.73 58.11,36.73 54.25,40.59 47.25,40.59 44.99,42.84 44.99,54.08 43.5,55.57 43.5,60.92 42.87,61.55 42.87,70.51 44.36,72 45.94,72 49.79,75.84 v2(49.79,77.94)
KSI1: length 71.2
  TOP w0.102: UE1.99 46.8,78.1 47.34,78.64 v1(48.12,78.64) 48.22,78.64 48.48,78.39 v2(48.9,78.39) 49.89,78.39 50.9,79.4 50.9,80.18 51.15,80.42 RPE1.3
  BOTTOM w0.102: v2(48.9,78.39) 48.9,75.6 46.7,73.4 45.12,73.4 42.42,70.7 42.42,61.36 43.04,60.73 43.04,53.69 44.54,52.19 44.54,42.65 47.06,40.13 54.05,40.13 57.91,36.27 62.81,36.27 64.55,34.53 JKB1.7
KSI2: length 80
  TOP w0.102: RPE1.2 51.12,80.92 50.68,80.48 50.68,79.53 49.93,78.78 v1(49.44,78.78) 49.33,78.78 v2(48.9,79.21) ; UE1.6 v2(44.45,73.63)
  BOTTOM w0.102: JKB1.5 62.95,34.61 61.74,35.82 57.72,35.82 53.86,39.68 46.87,39.68 44.08,42.46 44.08,52 42.59,53.5 42.59,60.54 41.21,61.92 41.21,70.38 v2(44.45,73.63) 44.68,73.86 46.51,73.86 48.2,75.55 48.2,78.7 48.71,79.21 v2(48.9,79.21)
KSI3: length 80.7
  TOP w0.102: UE1.7 34.53,73.23 34.71,73.4 43.72,73.4 44.32,72.8 v2(45.25,72.8) ; RPE1.1 51.18,81.42 50.45,80.68 50.45,79.93 v2(49.79,79.27)
  BOTTOM w0.102: v2(49.79,79.27) 49.79,79.02 49.34,78.58 49.34,75.72 46.67,73.05 45.51,73.05 v2(45.25,72.8) 44.68,72.23 44.27,72.23 42.65,70.6 42.65,61.45 43.27,60.83 43.27,53.78 44.76,52.29 44.76,42.75 47.15,40.36 54.15,40.36 58.01,36.5 63.41,36.5 v1(64.17,35.74) 65.35,34.56 JKB1.8
KSI4: length 69.7
  TOP w0.102: RPE2.4 47.88,79.92 v2(47.55,79.59) 47.56,79.58 47.56,79.26 46.76,78.46 44.97,78.46 44.8,78.29 UE1.104
  BOTTOM w0.102: JKB1.4 62.15,34.58 61.15,35.59 57.63,35.59 53.87,39.35 v1(52,39.35) 51.09,39.35 50.99,39.45 46.77,39.45 43.85,42.37 43.85,51.91 42.36,53.4 42.36,60.45 40.98,61.83 40.98,70.77 44.34,74.13 46.24,74.13 47.56,75.45 47.56,79.58 v2(47.55,79.59)
KSI5: length 73.7
  TOP w0.102: UE1.105 44.4,78.29 44.81,78.69 46.53,78.69 47.03,79.19 47.03,79.76 v2(47.56,80.29) 47.69,80.42 RPE2.3
  BOTTOM w0.102: v2(47.56,80.29) 48.96,80.29 49.31,79.94 49.31,79.05 49.05,78.79 48.61,78.79 48.43,78.61 48.43,75.45 46.6,73.63 45.03,73.63 42.19,70.79 42.19,61.26 42.81,60.64 42.81,53.59 44.31,52.1 44.31,42.56 46.96,39.91 53.95,39.91 57.82,36.04 62.12,36.04 v1(62.29,35.87) 62.51,35.87 63.75,34.63 JKB1.6
KSI6: length 73.6
  TOP w0.102: UE1.107 43.6,78.11 44.15,78.65 44.45,78.65 44.71,78.92 46.41,78.92 46.8,79.31 46.8,80.16 v2(47.57,80.93) 47.57,80.92 RPE2.2
  BOTTOM w0.102: v2(47.57,80.93) 47.02,80.38 47.02,78.23 47.25,78 47.25,75.47 46.15,74.36 44.24,74.36 39.91,70.03 39.91,62.57 42.13,60.35 42.13,53.29 43.61,51.81 43.61,42.29 46.78,39.12 v1(49.16,39.12) 50.74,39.12 50.86,39 53.89,39 57.53,35.36 61.05,35.36 61.35,35.06 JKB1.3
KSI7: length 76.6
  TOP w0.102: UE1.108 43.2,78.09 43.99,78.88 44.35,78.88 44.62,79.15 46.27,79.15 46.57,79.45 46.57,80.54 v2(47.59,81.56) 47.73,81.42 RPE2.1 48.55,81.42 48.68,81.54 v1(48.68,82.63)
  BOTTOM w0.102: v2(47.59,81.56) 46.8,80.77 46.8,78.13 47.02,77.9 47.02,75.56 46.05,74.59 44.15,74.59 39.68,70.12 39.68,62.45 41.24,60.9 41.24,53.86 43.38,51.71 43.38,42.19 46.8,38.77 53.8,38.77 57.44,35.13 60.72,35.13 60.87,34.98 60.87,34.8 60.55,34.49 JKB1.2
KSO0: length 84.9
  TOP w0.102: v2(48,71.62) 45.58,74.04 42.64,74.04 42.08,74.6 38.2,74.6 37.28,75.53 34.99,75.53 34.69,75.23 UE1.2 32.49,75.23 v2(32.29,75.43) ; v2(31.75,70.67) 31.48,70.94 RPE3.8
  BOTTOM w0.102: v2(32.29,75.43) 31.75,74.89 v2(31.75,70.67) ; JKB1.18 73.35,35.4 v1(70.15,38.6) 69.96,38.79 59,38.79 55.12,42.66 48.09,42.66 47.06,43.69 47.06,50.03 50.59,53.56 50.59,56.54 49.56,57.56 49.56,70.05 v2(48,71.62)
KSO1: length 77
  TOP w0.102: v2(47.42,69.59) 47.17,69.59 46.66,70.09 34.84,70.09 34.5,70.43 UE1.14 32.69,70.43 32.52,70.26 31.56,70.26 31.38,70.44 RPE3.7
  BOTTOM w0.102: v2(47.42,69.59) 47.29,69.46 47.29,68.9 46.8,68.41 46.33,68.41 46.33,68.41 44.77,68.41 43.56,67.2 43.56,63.04 46.2,60.4 46.2,57.03 46.78,56.45 46.78,54.29 46.6,54.12 46.6,43.5 47.9,42.2 54.93,42.2 58.8,38.33 68.79,38.33 v1(70.53,36.59) 71.75,35.37 JKB1.16
KSO2: length 75.6
  TOP w0.102: v2(47.7,69.07) 47.36,69.07 46.57,69.86 34.6,69.86 34.43,70.03 UE1.15 31.59,70.03 31.5,69.94 RPE3.6
  BOTTOM w0.102: JKB1.17 72.55,35.31 v1(72.14,35.72) 69.3,38.56 58.89,38.56 55.47,41.99 55.47,41.99 55.03,42.43 47.99,42.43 46.83,43.6 46.83,50.12 50.36,53.65 50.36,56.44 49.33,57.47 49.33,67.43 v2(47.7,69.07)
KSO3: length 74.8
  TOP w0.102: RPE3.5 31.51,69.44 31.82,69.75 32.58,69.75 32.7,69.63 UE1.16 46.22,69.63 v2(46.73,69.13)
  BOTTOM w0.102: v2(46.73,69.13) 46.24,68.64 44.67,68.64 43.33,67.3 43.33,62.94 45.88,60.39 45.88,57.02 46.55,56.35 46.55,54.5 46.37,54.33 46.37,43.41 47.81,41.97 54.83,41.97 58.7,38.1 68.18,38.1 v1(68.42,37.86) 70.95,35.33 JKB1.15
KSO4: length 59.9
  TOP w0.102: UE1.37 36.8,60.7 36.65,60.55 35.13,60.55 34.45,59.87 v2(34.45,59.85) 34.45,59.24 34.75,58.94 RPE4.8 34.75,58.45 34.61,58.32 v1(31.99,58.32)
  IN2 w0.127: v2(45.02,55.02) 44.22,55.02 41.27,57.96 35.28,57.96 34.45,58.8 v2(34.45,59.85)
  BOTTOM w0.102: v2(45.02,55.02) 45.02,54.7 45.45,54.27 45.45,43.03 47.44,41.05 54.44,41.05 58.3,37.19 65.52,37.19 67.75,34.96 JKB1.11
KSO5: length 58.2
  TOP w0.102: v1(33.64,57.46) 34.22,58.04 34.85,58.04 35.25,58.44 RPE4.7 35.25,58.89 34.95,59.19 34.95,59.79 v2(35.06,59.9) 35.06,59.9 35.48,60.32 36.83,60.32 37.2,60.69 UE1.38
  IN2 w0.127: v2(35.06,59.9) 34.95,59.79 34.95,59.12 35.85,58.22 41.38,58.22 43.94,55.65 v2(45.02,55.65)
  BOTTOM w0.102: v2(45.02,55.65) 44.62,55.25 44.62,54.78 45.22,54.17 45.22,42.94 47.34,40.82 54.35,40.82 58.21,36.96 64.55,36.96 66.95,34.56 JKB1.10
KSO6: length 57.4
  TOP w0.102: UE1.39 37.59,61.59 37.59,60.52 37.26,60.18 37.02,60.18 36.83,59.99 v1(36.66,59.99) 36.56,60.09 35.71,60.09 35.47,59.85 35.47,59.74 35.37,59.64 v2(35.37,59.34) 35.37,59.21 35.75,58.83 RPE4.6
  IN2 w0.127: v2(45.91,55.02) 45.47,55.46 45.47,55.84 45.15,56.16 43.8,56.16 41.48,58.47 36.24,58.47 v2(35.37,59.34)
  BOTTOM w0.102: v2(45.91,55.02) 45.91,43.22 47.62,41.51 54.63,41.51 58.5,37.64 67.1,37.64 69.35,35.39 JKB1.13
KSO7: length 58.4
  TOP w0.102: v2(41.72,59.25) 41.72,59.59 42.17,60.03 42.17,60.52 42,60.68 UE1.50 ; v1(37.42,56.93) 37.42,57.06 36.92,57.56 36.92,57.97 RPE4.5 36.25,59.31 v2(35.87,59.69)
  IN2 w0.127: v2(35.87,59.69) 36.8,58.76 40.59,58.76 41.07,59.25 v2(41.72,59.25) 41.72,58.59 43.84,56.48 45.21,56.48 45.91,55.78 v2(45.91,55.65)
  BOTTOM w0.102: v2(45.91,55.65) 45.51,55.25 45.51,54.54 45.68,54.36 45.68,43.12 47.53,41.28 54.53,41.28 58.4,37.42 65.97,37.42 68.55,34.84 JKB1.12
KSO8: length 78.2
  TOP w0.102: v2(51.12,71.78) 51.23,71.89 51.73,71.89 52.02,72.17 RPE6.8 ; v2(40.4,62.92) UE1.46 40.4,60.52 40.4,60.51 40.4,59.85 v1(40.57,59.67)
  IN2 w0.127: v2(40.4,62.92) 42.64,60.69 42.64,58.03 43.28,57.4 43.67,57.4 v2(44.13,56.94)
  BOTTOM w0.102: JKB1.14 70.15,35.24 67.52,37.87 58.6,37.87 54.74,41.74 47.71,41.74 46.14,43.31 46.14,54.42 46.32,54.6 46.32,56.01 45.93,56.4 44.67,56.4 v2(44.13,56.94) 43.73,57.34 43.73,61.02 43.1,61.64 43.1,68.83 46.29,72.02 50.12,72.02 50.36,71.78 v2(51.12,71.78)
KSO9: length 52.3
  TOP w0.102: UE1.68 50.19,64.43 50.97,63.65 v2(51.12,63.65) 51.17,63.65 RE15.1
  BOTTOM w0.102: JKB1.24 78.15,34.33 77.5,34.98 77.23,34.98 v1(76.22,35.99) 72.05,40.16 59.58,40.16 53.92,45.81 53.92,49.17 54.6,49.85 54.6,52.47 51.96,55.12 51.96,62.82 v2(51.12,63.65)
KSO10: length 55.5
  TOP w0.102: RPE5.8 51.91,65.7 v2(51.73,65.51) 51.45,65.24 v1(50.97,65.24) 50.18,66.03 UE1.72
  BOTTOM w0.102: JKB1.26 79.75,34.62 79.56,34.81 78.89,34.81 78.22,35.49 77.51,35.49 72.38,40.62 61.13,40.62 58.49,43.26 57.12,43.26 54.38,46 54.38,48.98 55.06,49.66 55.06,52.66 52.41,55.3 52.41,63 51.82,63.59 51.82,65.42 v2(51.73,65.51)
KSO11: length 55.5
  TOP w0.102: UE1.74 50.29,66.83 50.29,66.83 50.53,66.83 v1(50.8,66.55) 51.15,66.2 51.7,66.2 v2(51.7,66.2) 51.7,66.2 RPE5.7
  BOTTOM w0.102: JKB1.25 78.95,34.36 78.08,35.23 77.49,35.23 77.46,35.26 77.42,35.26 72.29,40.39 59.67,40.39 54.15,45.91 54.15,49.08 54.83,49.75 54.83,52.57 52.19,55.21 52.19,62.91 51.6,63.5 51.6,65.07 51.32,65.35 51.32,65.82 v2(51.7,66.2)
KSO12: length 60.7
  TOP w0.102: UE1.75 v2(50.46,67.23) 50.72,67.23 51.25,66.7 RPE5.6
  BOTTOM w0.102: JKB1.19 74.15,35.46 v1(71.94,37.67) 70.6,39.02 59.1,39.02 55.23,42.89 48.18,42.89 47.28,43.79 47.28,49.93 50.81,53.46 50.81,56.63 49.79,57.66 49.79,66.56 v2(50.46,67.23)
KSO13: length 55
  TOP w0.102: RPE5.5 v2(51.68,67.2) 51.33,67.2 50.86,67.66 50.15,67.67 50.12,67.63 UE1.76
  BOTTOM w0.102: JKB1.22 76.55,34.72 v1(74.33,36.94) 71.57,39.7 59.39,39.7 53.47,45.62 53.47,52.94 51.5,54.9 51.5,58.88 50.48,59.89 50.48,66.03 51.65,67.2 v2(51.68,67.2)
KSO14: length 62.2
  TOP w0.102: UE1.77 50.11,68.03 50.17,67.97 v1(51.09,67.97) 51.58,67.97 v2(51.76,67.79) ; v2(51.72,73.27) 51.81,73.17 RPE6.6
  BOTTOM w0.102: v2(51.72,73.27) 51.72,73.22 52.13,72.81 52.13,68.48 51.76,68.1 v2(51.76,67.79) 52.1,67.45 52.1,67.05 51.79,66.73 51.51,66.73 50.71,65.94 50.71,59.99 51.73,58.97 51.73,55.02 53.69,53.06 53.69,45.72 59.48,39.93 71.81,39.93 77.02,34.72 77.19,34.72 77.35,34.56 JKB1.23
KSO15: length 60.5
  TOP w0.102: UE1.86 50.34,71.63 v1(51.03,72.33) 51.26,72.56 v2(51.73,72.56) 51.84,72.67 RPE6.7
  BOTTOM w0.102: v2(51.73,72.56) 51.9,72.38 51.9,68.63 51.13,67.86 51.13,67 50.26,66.13 50.26,59.8 51.27,58.78 51.27,54.81 53.24,52.84 53.24,45.53 59.29,39.47 71.33,39.47 75.75,35.05 JKB1.21
KSO16: length 61.2
  TOP w0.102: RPE6.5 51.32,73.67 v2(51.31,73.69) 50.96,74.03 v1(50.83,74.03) UE1.92
  BOTTOM w0.102: v2(51.31,73.69) 51.31,72.4 51.68,72.03 51.68,68.73 50.9,67.95 50.9,67.09 50.03,66.22 50.03,57.74 51.04,56.73 51.04,54.71 53.01,52.74 53.01,45.43 59.2,39.24 71.24,39.24 74.95,35.53 JKB1.20
L_BKLT_CTRL: length 133.9
  TOP w0.102: v2(215.24,54.99) 217.32,54.99 v1(217.51,54.8) 217.83,54.48 R8.1
  IN1 w0.127: v2(131.03,41.03) 133.7,41.03 134.97,42.3 147.29,42.3 147.87,41.71 151.42,41.71 155.1,38.04 158.5,38.04 161.79,34.75 164.43,34.75 165.32,35.64 171.01,35.64 171.42,35.24 176.34,35.24 176.75,35.64 182.88,35.64 183.53,36.29 191.97,36.29 192.97,37.3 201.04,37.3 207.58,43.84 210.38,43.84 210.94,44.39 213.38,44.39 214.24,45.25 214.24,49.61 213.86,49.99 213.86,51.69 214.51,52.34 214.51,54.26 v2(215.24,54.99)
  IN2 w0.127: v2(131.03,41.03) 131.24,41.23 131.24,52.09 134.07,54.92 134.07,59.34 132.67,60.74 132.3,60.74 131.49,61.56 131.49,62.41 130.31,63.58 130.31,64.17 v2(129.11,65.37)
  BOTTOM w0.102: v2(129.11,65.37) 128.77,65.37 UC1.R11
LAN_MDI0N: length 15.2
  TOP w0.089: v2(23.24,82.12) 23.24,82.67 23.4,82.84 23.4,83.05 23.48,83.13 UL1.2 ; TL1.15 26.93,71.86 27.02,71.95 27.02,72.27 27.11,72.35 27.37,72.35 27.66,72.64 v2(27.66,74.61)
  IN2 w0.089: v2(23.24,82.12) 23.24,80.1 27.56,75.78 27.56,74.71 v2(27.66,74.61)
LAN_MDI0P: length 15.1
  TOP w0.089: UL1.1 23.08,83.12 23.12,83.08 23.12,82.95 22.95,82.79 22.95,82.42 v2(22.65,82.12) ; v2(27.07,74.61) 27.38,74.3 27.38,72.76 27.25,72.64 27.11,72.64 27.02,72.73 27.02,73.04 26.93,73.13 TL1.16
  IN2 w0.089: v2(27.07,74.61) 27.31,74.84 27.31,75.68 22.99,80 22.99,81.78 v2(22.65,82.12)
LAN_MDI1N: length 25.5
  TOP w0.089: TL1.9 26.93,64.24 27.02,64.33 27.02,64.56 27.1,64.65 28.08,64.65 v2(28.16,64.56) ; UL1.5 24.68,81.13 24.72,81.09 24.72,81.07 v2(24.77,81.02)
  IN2 w0.089: v2(24.77,81.02) 24.76,81.01 24.76,80.44 24.85,80.35 26.67,80.35 27.08,79.95 27.08,77.81 28.66,76.23 28.66,73.28 28.15,72.77 28.15,68.17 29.05,67.28 29.05,65.17 28.65,64.78 28.38,64.78 v2(28.16,64.56)
LAN_MDI1P: length 25.5
  TOP w0.089: UL1.4 24.28,82.94 24.4,82.83 24.4,81.23 v2(24.19,81.02) ; TL1.10 26.93,65.51 27.02,65.42 27.02,65.02 27.11,64.93 27.95,64.93 v2(28.16,65.15)
  IN2 w0.089: v2(28.16,65.15) 28.29,65.02 28.55,65.02 28.8,65.27 28.8,67.18 27.91,68.07 27.91,72.88 28.41,73.38 28.41,76.13 26.83,77.71 26.83,79.85 26.57,80.11 24.75,80.11 24.51,80.34 24.51,80.7 v2(24.19,81.02)
LAN_MDI2N: length 14.8
  TOP w0.089: UL1.7 25.48,82.94 25.42,82.89 25.42,82.09 25.54,81.98 v2(25.88,81.98)
  BOTTOM w0.089: TL2.10 26.61,71.86 26.82,72.07 26.82,72.21 26.91,72.3 27.2,72.3 27.49,72.59 27.49,73.62 26.29,74.83 26.29,79.7 26.91,80.32 26.91,81.32 26.31,81.92 25.93,81.92 v2(25.88,81.98)
LAN_MDI2P: length 14.7
  TOP w0.089: v2(25.88,81.39) 25.58,81.7 25.42,81.7 25.14,81.97 25.14,82.89 25.08,82.94 UL1.6
  BOTTOM w0.089: v2(25.88,81.39) 26.13,81.64 26.19,81.64 26.63,81.21 26.63,80.44 26.01,79.81 26.01,74.71 27.21,73.5 27.21,72.7 27.09,72.58 26.94,72.58 26.88,72.64 26.88,73.02 26.77,73.13 TL2.9
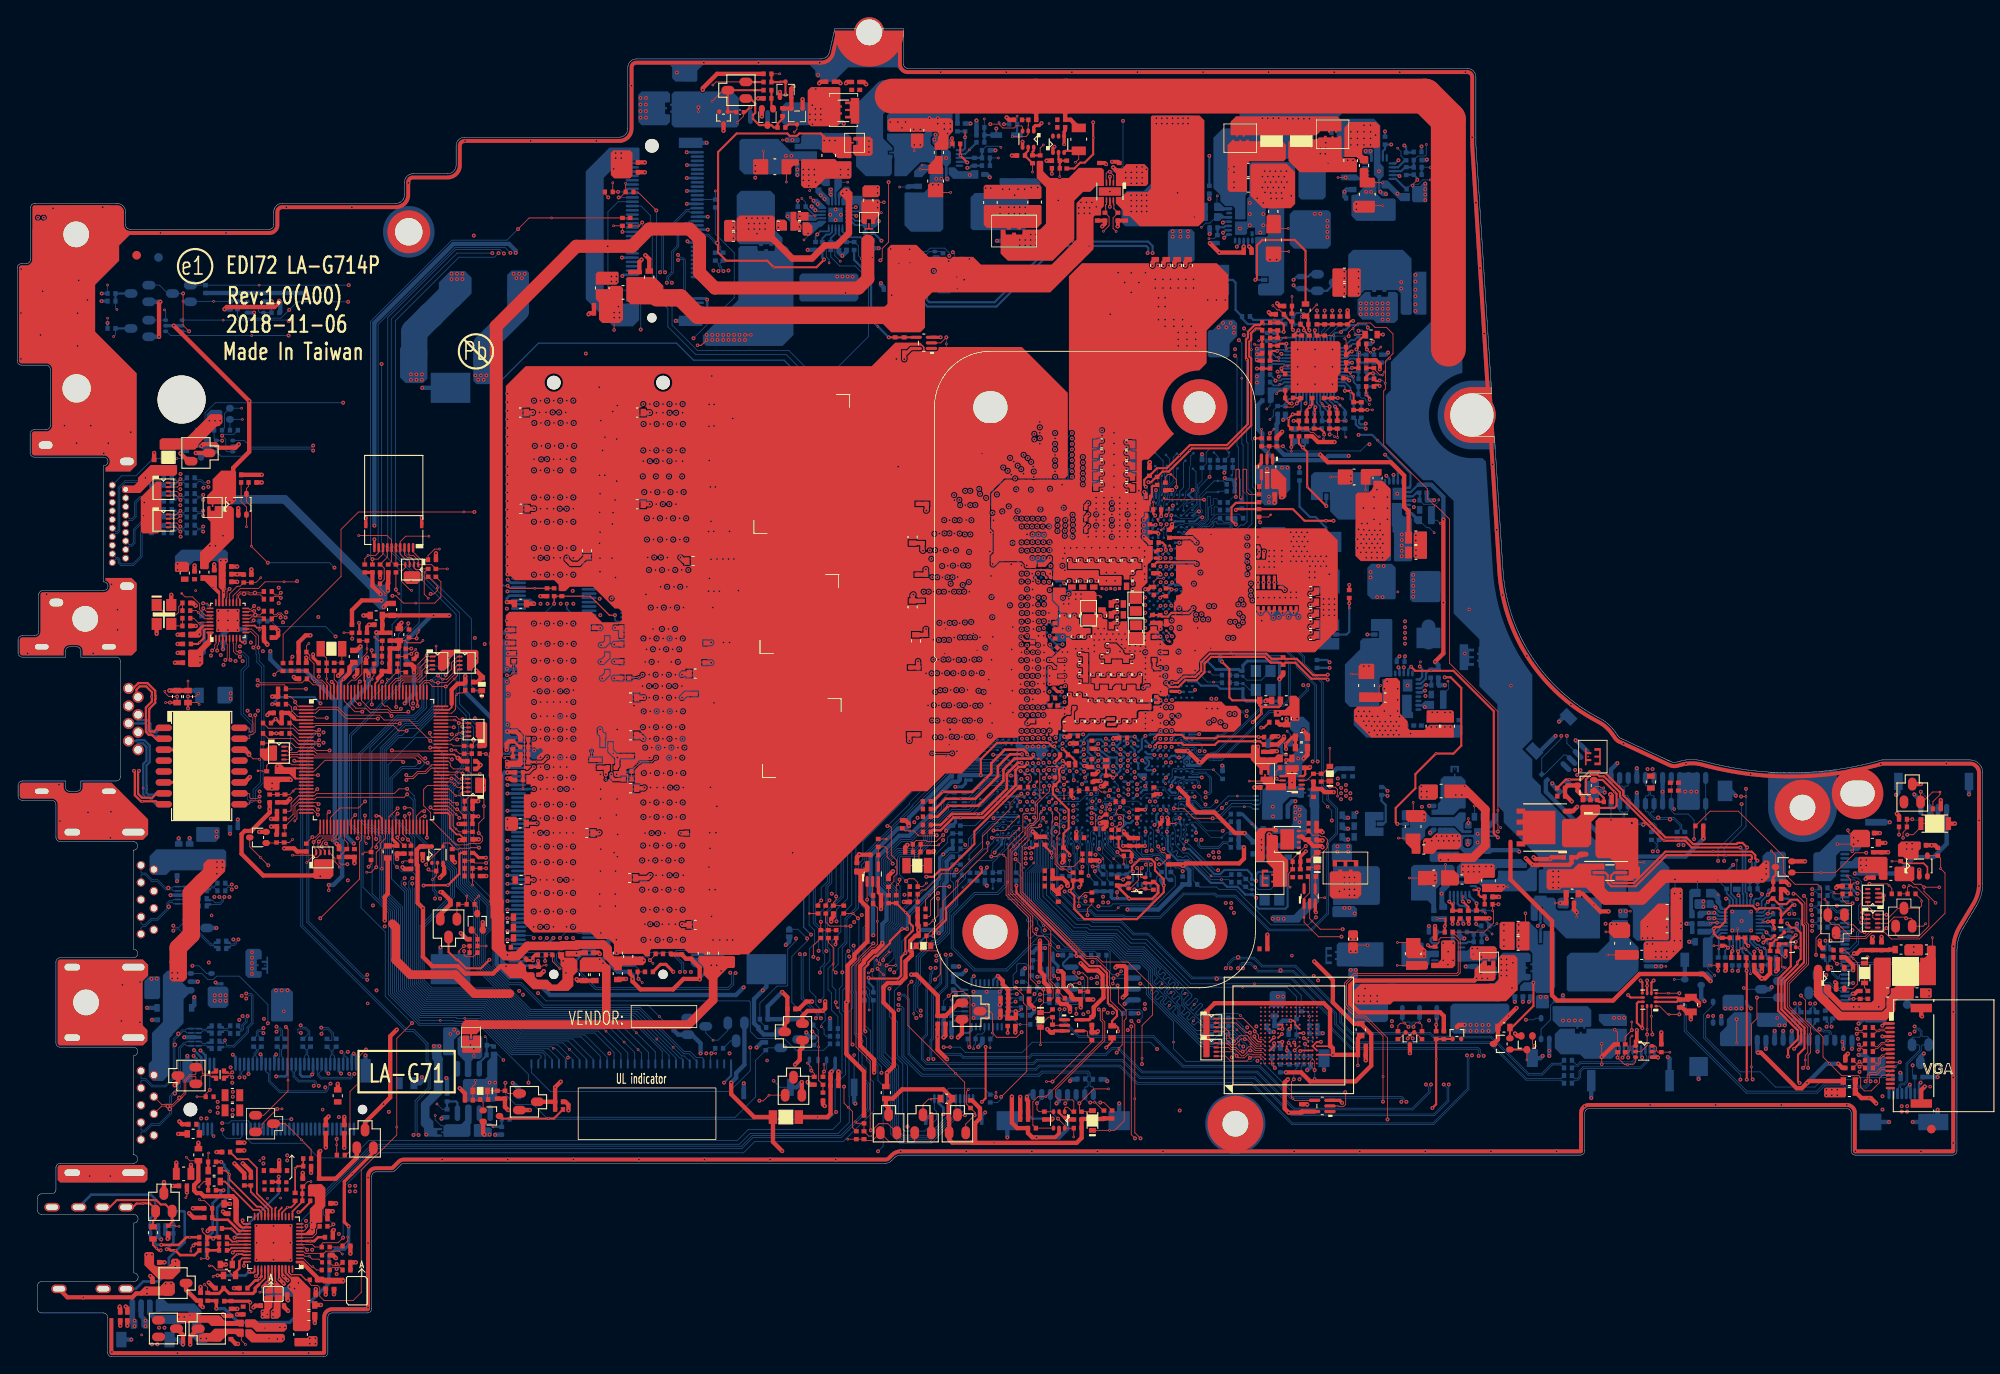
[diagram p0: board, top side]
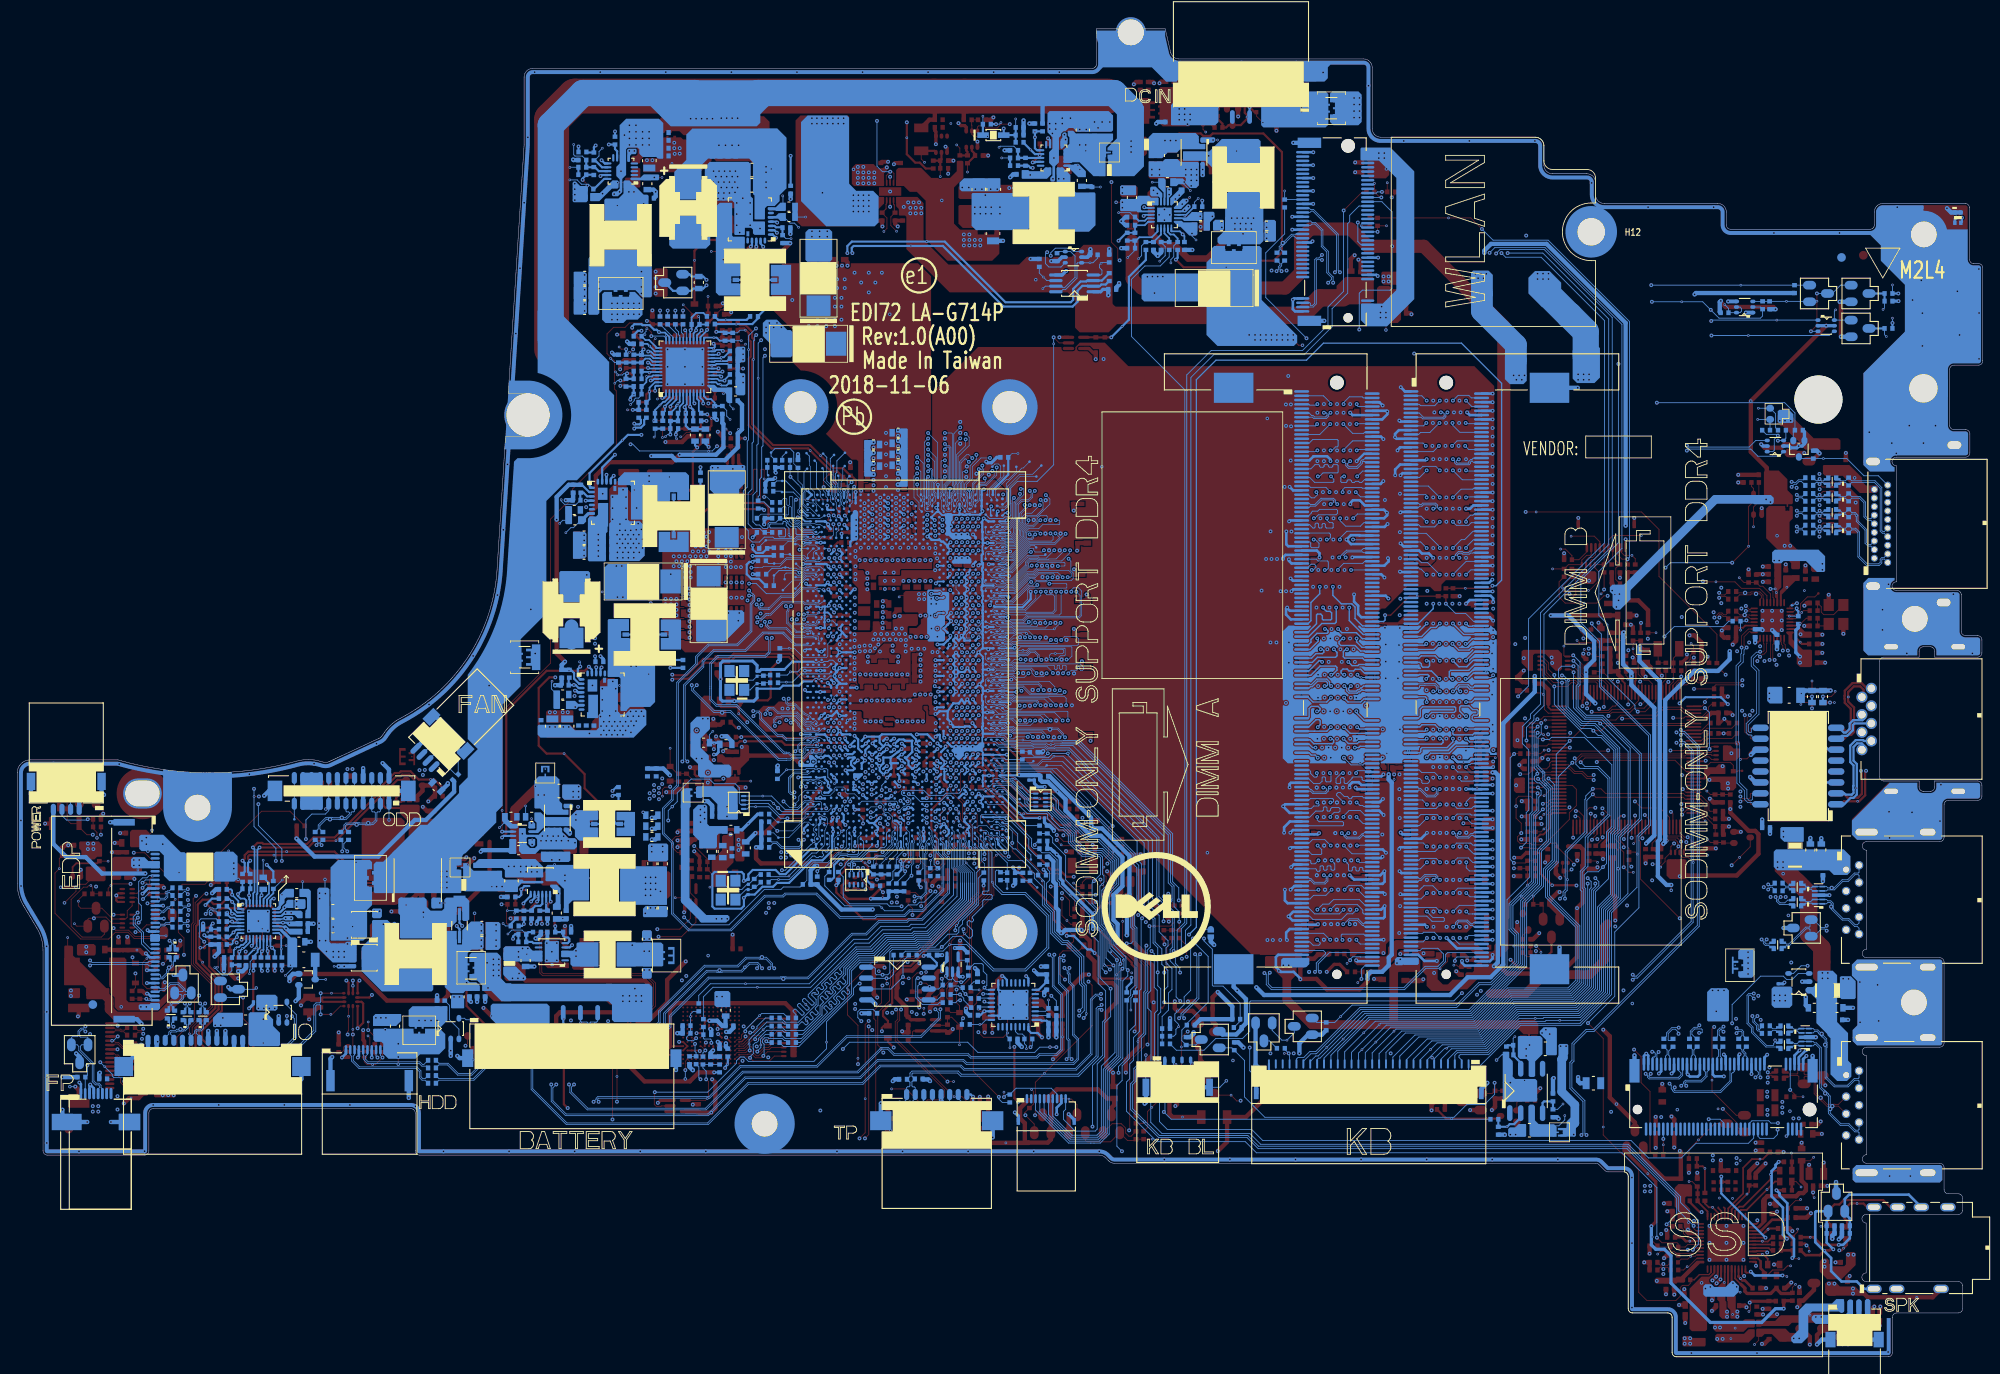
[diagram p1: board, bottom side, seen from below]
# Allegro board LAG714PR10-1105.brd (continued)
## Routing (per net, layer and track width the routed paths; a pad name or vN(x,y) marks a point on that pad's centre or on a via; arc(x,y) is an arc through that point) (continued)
PCIE_CTX_NVMERX_N11: length 182
  IN2 w0.122: v2(30.13,38.38) 30.39,38.13 30.67,38.13 31.02,37.78 31.02,32.2 34.02,29.19 38.09,29.19 39.41,27.87 44.52,27.87 45.03,28.37 49.56,28.37 50.61,27.33 55.9,27.33 56.55,26.68 86.88,26.68 87.54,27.33 98.28,27.33 98.62,27.67 102.46,27.67 103,28.2 105.17,28.2 105.71,27.67 112.65,27.67 113.34,28.37 131.36,28.37 139.8,36.8 139.8,38.73 141.64,40.58 144.16,40.58 148.03,44.45 148.03,47.38 151.36,50.71 151.36,57.38 150.15,58.59 150.15,65.35 148.32,67.18 147.55,67.18 144.88,69.85 144.27,69.85 142.94,71.18 142.94,71.96 141.45,73.45 141.45,74.1 141.16,74.39 141.16,74.45 141.04,74.56 141.04,74.57 v2(140.88,74.73)
  BOTTOM w0.076: 141,75.33 140.56,75.33 140.03,74.8 137.83,74.8 136.74,73.71 136.23,73.71 136.1,73.58 135.95,73.58 135.69,73.31 135.5,73.31 134.94,73.6 UC1.D24
  BOTTOM w0.097: v2(140.88,74.73) 141.2,75.05 141.2,75.14 141,75.33 ; CS20.1 30.83,37.24 30.83,37.97 30.58,38.22 30.3,38.22 v2(30.13,38.38)
PCIE_CTX_NVMERX_N12: length 187.5
  IN2 w0.122: v2(139.34,76.51) 139.09,76.27 139.09,76.17 139.2,76.07 141.36,76.07 142.38,75.05 142.38,73.84 143.49,72.72 144.54,72.72 145.77,71.49 147.62,71.49 148.3,70.81 148.3,68.71 151.08,65.93 151.08,59.05 152.29,57.83 152.29,50.33 148.96,47 148.96,42.62 145.99,39.65 142.03,39.65 140.72,38.35 140.72,36.42 131.75,27.44 126.67,27.44 126.18,26.95 120.1,26.95 119.61,27.44 113.72,27.44 113.03,26.75 104.9,26.75 104.4,27.24 103.34,27.24 102.85,26.75 99.02,26.75 98.68,26.41 87.92,26.41 87.26,25.75 56.17,25.75 55.52,26.41 49.32,26.41 48.48,27.24 45.2,27.24 44.89,26.93 34.68,26.93 29.42,32.19 29.42,37.63 29.27,37.78 28.76,37.78 28.61,37.64 v2(28.61,37.64)
  BOTTOM w0.076: UC1.A25 136.4,74.3 136.4,74.38 136.46,74.44 136.98,74.7 138.04,75.75 138.84,75.75 139.1,76.01 139.1,76.28 v2(139.34,76.51)
  BOTTOM w0.097: CS22.1 27.97,37.36 27.97,37.74 28.07,37.83 28.41,37.83 v2(28.61,37.64)
PCIE_CTX_NVMERX_P9: length 174.6
  IN2 w0.122: v2(139.82,73.78) 139.94,73.65 139.94,73.4 139.84,73.3 139.84,72.96 141.59,71.2 141.59,70.53 143.98,68.14 143.98,67.67 145.84,65.82 146.54,65.82 147.86,64.5 147.86,62.26 148.39,61.72 148.39,58.22 149.55,57.07 149.55,50.8 146.63,47.89 146.63,44.96 143.6,41.93 140.9,41.93 138.45,39.48 138.45,37.36 131.32,30.23 118.22,30.23 117.77,29.78 113.22,29.78 112.7,30.3 111.82,30.3 111.42,29.9 102.78,29.9 101.9,29.02 95.86,29.02 95.75,29.13 94.49,29.13 94.04,28.68 86.98,28.68 86.32,28.03 57.11,28.03 56.46,28.68 51.17,28.68 49.23,30.62 34.76,30.62 33.86,31.52 33.86,35.09 34.62,35.85 34.62,37.66 34.91,37.95 35.07,37.95 35.36,37.67 v2(35.36,37.56)
  BOTTOM w0.076: UC1.A23 136.55,72.99 136.49,72.94 136.25,72.94 136.19,72.99 136.19,73.17 136.33,73.31 136.81,73.31 137.91,74.42 139.51,74.42 139.65,74.28 140.12,74.28 140.37,74.03 140.37,73.78 140.3,73.71 139.88,73.71 v2(139.82,73.78)
  BOTTOM w0.097: CS17.1 36.19,36.77 36.5,36.77 36.56,36.83 36.56,37.59 36.06,38.09 35.72,38.09 35.36,37.72 v2(35.36,37.56)
PCIE_CTX_NVMERX_P10: length 179.7
  IN2 w0.122: v2(32.96,37.66) 33.34,37.66 33.51,37.83 33.51,37.96 33.34,38.12 32.53,38.12 32.27,37.86 32.27,31.91 34.25,29.93 48.96,29.93 50.89,28.01 56.18,28.01 56.83,27.35 86.6,27.35 87.26,28.01 97.42,28.01 97.76,28.35 102.18,28.35 102.81,28.98 112.1,28.98 112.2,29.08 112.9,29.08 112.94,29.04 131.08,29.04 139.12,37.08 139.12,39.2 141.18,41.25 143.88,41.25 147.31,44.68 147.31,47.61 150.22,50.52 150.22,57.35 149.07,58.5 149.07,60.19 149.44,60.57 149.44,64.34 147.27,66.51 146.11,66.51 144.66,67.95 144.66,68.42 142.27,70.81 142.27,71.66 140.78,73.15 140.78,73.81 140.17,74.41 139.49,74.41 139.33,74.57 138.95,74.57 138.69,74.32 138.69,74.21 138.88,74.02 v2(139.04,74.02)
  BOTTOM w0.076: UC1.C23 135.22,72.98 135.26,72.85 135.36,72.8 135.72,72.8 135.79,72.77 136.83,72.77 137.51,73.45 137.51,73.63 138.04,74.16 138.61,74.16 138.82,73.95 138.96,73.95 v2(139.04,74.02)
  BOTTOM w0.097: v2(32.96,37.66) 32.66,37.66 32.6,37.71 32.6,38.04 32.68,38.12 33.47,38.12 33.8,37.79 33.8,37.49 33.28,36.97 CS19.1
PCIE_CTX_NVMERX_P11: length 181.9
  IN2 w0.122: v2(141.46,74.73) 141.41,74.68 141.41,74.5 141.7,74.2 141.7,73.56 143.19,72.06 143.19,71.28 144.37,70.1 144.99,70.1 147.66,67.43 148.42,67.43 150.4,65.45 150.4,58.69 151.61,57.48 151.61,50.61 148.28,47.28 148.28,44.35 144.26,40.33 141.75,40.33 140.05,38.63 140.05,36.7 131.47,28.12 113.44,28.12 112.75,27.42 105.6,27.42 105.07,27.96 103.1,27.96 102.57,27.42 98.72,27.42 98.38,27.08 87.64,27.08 86.98,26.43 56.45,26.43 55.79,27.08 50.5,27.08 49.46,28.13 45.13,28.13 44.62,27.62 39.31,27.62 37.99,28.94 33.92,28.94 30.77,32.09 30.77,37.68 30.57,37.88 30.21,37.88 v2(30.13,37.8)
  BOTTOM w0.076: 141.1,75.5 141.09,75.5 141.08,75.51 140.93,75.51 140.92,75.5 140.5,75.5 139.96,74.96 137.76,74.96 136.67,73.87 136.16,73.87 136.03,73.74 135.9,73.74 135.69,73.95 135.6,73.95 135.43,73.78 135.43,73.73 UC1.C24
  BOTTOM w0.097: CS21.1 30.64,37.41 30.64,37.89 30.5,38.03 30.35,38.03 30.13,37.81 v2(30.13,37.8) ; 141.1,75.5 141.1,75.5 141.39,75.22 141.39,74.81 v2(141.46,74.73)
PCIE_CTX_NVMERX_P12: length 187.4
  IN2 w0.122: v2(138.75,76.51) 138.85,76.42 138.85,76.07 139.09,75.82 141.26,75.82 142.13,74.95 142.13,73.73 143.39,72.47 144.44,72.47 145.67,71.24 147.52,71.24 148.05,70.71 148.05,68.6 150.83,65.83 150.83,58.94 152.04,57.73 152.04,50.43 148.71,47.1 148.71,42.72 145.89,39.9 141.92,39.9 140.48,38.45 140.48,36.52 131.64,27.69 126.57,27.69 126.07,27.2 120.2,27.2 119.71,27.69 113.62,27.69 112.93,27 105,27 104.5,27.49 103.24,27.49 102.74,27 98.92,27 98.58,26.66 87.82,26.66 87.16,26 56.27,26 55.62,26.66 49.42,26.66 48.58,27.49 45.1,27.49 44.79,27.18 34.79,27.18 29.67,32.29 29.67,37.73 29.37,38.03 28.8,38.03 v2(28.61,38.22)
  BOTTOM w0.076: v2(138.75,76.51) 138.93,76.33 138.93,76.07 138.78,75.92 137.97,75.92 136.89,74.83 136.36,74.58 136.24,74.45 136.24,74.38 136.01,74.15 UC1.B25
  BOTTOM w0.097: CS23.1 27.79,37.29 27.79,37.81 27.99,38.02 28.41,38.02 v2(28.61,38.22)
PCIE_CTX_WLANRX_N6: length 126.7
  IN2 w0.122: v2(141.3,83.59) 141.13,83.76 141.13,84.07 140.53,84.67 140.53,89.58 140.98,90.03 140.98,111.86 138.86,113.98 130.55,113.98 119.56,124.97 113.54,124.97 112.9,124.33 105.29,124.33 104.66,124.96 101.08,124.96 100.44,124.33 88.99,124.33 87.6,125.71 81.98,125.71 81.87,125.82 81.87,126.04 v2(82.06,126.23)
  BOTTOM w0.076: 141.1,81.94 141.09,81.95 141.07,81.95 141.07,83.36 141.1,83.39 ; 139,70.11 138.98,70.11 138.97,70.12 138.79,70.12 138.54,69.87 137.2,69.87 136.85,70.23 136.85,70.66 136.63,70.87 135.89,70.87 135.85,70.82 135.39,70.82 135.35,70.86 135.28,70.86 135.03,71.11 UC1.D20
  BOTTOM w0.097: 139,70.11 139.33,70.11 144.85,75.64 147.18,75.64 147.92,76.38 147.92,77.71 147.92,77.94 147.92,80.65 147.03,81.53 141.51,81.53 141.1,81.94 ; v2(82.06,126.23) 81.86,126.43 81.86,126.73 81.66,126.92 81.66,127.11 CW1.1 ; 141.1,83.39 v2(141.3,83.59)
PCIE_CTX_WLANRX_P6: length 126.6
  IN2 w0.122: v2(140.71,83.59) 140.88,83.76 140.88,83.97 140.28,84.57 140.28,89.68 140.73,90.13 140.73,111.76 138.76,113.73 130.45,113.73 119.46,124.72 113.64,124.72 113,124.08 105.18,124.08 104.55,124.71 101.18,124.71 100.55,124.08 88.88,124.08 87.5,125.46 81.87,125.46 81.62,125.71 81.62,126.09 v2(81.48,126.23)
  BOTTOM w0.076: v2(140.71,83.59) 140.9,83.4 140.9,81.88 140.95,81.83 140.95,81.82 140.97,81.81 ; UC1.C20 135.49,71.03 135.35,71.03 135.28,71.11 135.28,71.32 135.36,71.41 135.77,71.41 135.92,71.26 135.92,71.11 135.99,71.04 136.7,71.04 137.01,70.72 137.01,70.3 137.27,70.04 138.47,70.04 138.72,70.29 138.98,70.29 138.99,70.3 139,70.3
  BOTTOM w0.097: 139,70.3 139.25,70.3 144.78,75.83 147.1,75.83 147.74,76.46 147.74,77.71 147.73,77.94 147.73,80.57 146.96,81.34 141.43,81.34 140.97,81.81 ; CW2.1 81.48,127.11 81.48,126.84 81.67,126.65 81.67,126.42 v2(81.48,126.23)
PCIE_RCOMPN: length 2.3
  TOP w0.127: v1(132.57,61.07) 132.57,61.55 132.83,61.81 RC65.1
  TOP w0.381: RC65.1 133,62.18 v2(133,62.7)
  BOTTOM w0.254: UC1.F5 133.17,62.53 133,62.7 133,62.7 v2(133,62.7)
PCIE_RCOMPP: length 2.2
  TOP w0.127: v1(134.68,62.01) RC65.2
  TOP w0.381: RC65.2 133.75,62.59 v2(133.64,62.7)
  BOTTOM w0.254: UC1.E5 133.64,62.44 133.64,62.7 v2(133.64,62.7)
PCIE_WAKE#: length 194.8
  TOP w0.102: v2(35.98,74.29) 35.94,74.26 34.75,74.26 34.57,74.43 UE1.4 32.6,74.43 31.88,75.14 31.88,75.52 31.53,75.88 RE12.2 ; UL1.21 24.28,88.19 24.38,88.29 24.38,88.99 v2(24.67,89.28)
  IN1 w0.127: v2(100.03,23.9) 99.51,24.41 57.6,24.41 54.5,27.52 52.92,27.52 49.9,30.53 39.4,30.53 36.36,27.49 34.37,27.49 33.49,26.6 24.04,26.6 v2(23.85,26.41)
  IN2 w0.127: v2(24.67,89.28) 27.27,89.28 28.99,87.56 28.99,85.19 30.89,83.29 30.89,79 35.34,74.54 35.72,74.54 v2(35.98,74.29) 36.57,73.69 36.57,71.78 33.69,68.9 33.69,63.47 30.08,59.87 23.39,59.87 20.23,56.7 20.23,55.35 19.66,54.77 19.66,44.14 18.1,42.58 18.1,32.49 23.35,27.24 23.35,26.91 v2(23.85,26.41)
  BOTTOM w0.102: v2(100.03,23.9) 100.62,24.48 100.62,31.52 100.01,32.13 100.01,33.84 99.17,34.68 99.17,37.88 98.46,38.59 RC99.1 ; v2(24.67,89.28) v1(24.12,89.28) ; JSSD1.54 26.12,25.63 25.89,25.4 24.3,25.4 23.85,25.85 v2(23.85,26.41)
PECI_EC: length 192.5
  TOP w0.102: RE23.2 53.93,77.5 DE1.1 53.98,76.81 v2(54,76.78)
  IN2 w0.127: v2(55.93,128.33) 56.37,128.77 62.35,128.77 62.84,128.29 72.25,128.29 72.68,128.71 78.39,128.71 78.67,128.43 87.72,128.43 89.82,126.34 94.36,126.34 95,126.98 106.48,126.98 107.12,126.34 112.07,126.34 112.71,126.98 120.48,126.98 131.47,115.99 139.7,115.99 143.03,112.65 143.03,102.91 144.94,101 144.94,95.31 143.88,94.25 143.88,90.93 143.35,90.4 v2(143.35,89.9)
  BOTTOM w0.102: v2(143.35,89.9) 142.52,89.9 141.35,88.73 138.13,88.73 137.26,89.6 137.26,89.91 136.8,90.37 UC1.A54 ; v2(54,76.78) 52.78,78.01 52.78,85.8 43.95,94.63 43.95,120.47 51.33,127.84 55.44,127.84 v2(55.93,128.33)
PHASE_CHG: length 11.6
  TOP w0.102: PRB22.1 v1(184.6,49.4)
  IN2 w0.762: 195.8,51.49 191.87,51.49 190.79,50.41 186.6,50.41
  vias: v2(185.26,50.29) v2(185.85,50.29) v2(196.57,51.62) v2(197.2,51.62)
PHASE_VCORE1:
  vias: v2(163.56,75.55)
PHASE_VCORE2: length 2.3
  BOTTOM w0.102: PCI29.2 162.91,97.25 163.76,96.4 164.07,96.4 v1(164.65,95.82)
PHASE_VGT1: length 1.3
  BOTTOM w0.102: v1(139.45,134.98) 139.42,134.95 PCG09.2
PLTRST#: length 358.8
  TOP w0.102: v2(114.33,30.22) 117.31,33.19 117.31,40.75 116.91,41.15 116.91,42.02 v2(116,42.92) ; UL1.19 25.08,88.49 25.93,89.34 28.04,89.34 28.8,90.1 v1(31.01,90.1) 32.44,90.1 v2(32.52,90.18)
  IN1 w0.127: v2(59.41,31.87) 61.7,29.58 64.3,29.58 65.44,28.43 92.09,28.43 93.38,29.72 96.78,29.72 97.78,30.73 113.83,30.73 v2(114.33,30.22)
  IN2 w0.127: v2(72.45,119.44) 66,119.44 65.43,118.87 45.77,118.87 v2(42.34,115.44) 41.79,115.44 32.52,106.17 v2(32.52,90.18) 32.52,86.2 31.14,84.82 31.14,79.1 35.32,74.93 36.55,74.93 37,74.47 37,71.85 33.94,68.8 33.94,63.37 30.19,59.61 23.5,59.61 20.48,56.6 20.48,55.24 19.91,54.67 19.91,44.03 18.35,42.47 18.35,32.59 23.77,27.17 v2(23.81,27.17)
  BOTTOM w0.102: JWLAN1.52 69.82,134.3 68.64,133.12 68.64,124.24 68.87,124.01 72.11,124.01 72.45,123.66 v2(72.45,119.44) ; v2(114.33,30.22) 114.33,29.98 113.93,29.57 RE65.1 ; v2(42.34,115.44) 42.34,94.66 46.71,90.29 46.71,85.36 44.55,83.21 44.55,77.91 38.83,72.19 38.83,61.9 40.18,60.55 40.18,54.59 43.15,51.62 43.15,42.1 46.71,38.54 53.7,38.54 59.41,32.84 v2(59.41,31.87) ; UX1.17 115.75,42.67 v2(116,42.92) 115.73,43.19 115.73,44.41 116.14,44.82 116.14,45.56 116.3,45.72 117.19,45.72 117.67,45.24 RC108.2 118,45.37 RC109.1 118.97,46.11 119.07,46.2 UC4.4 ; v2(23.81,27.17) 24.61,27.17 24.88,27.44 26.83,27.44 27.12,27.14 JSSD1.50
PME#: length 6
  BOTTOM w0.076: UC1.AU11 116.12,65.91 115.98,66.04 115.75,66.04 115.62,65.91 115.49,65.91 115.37,66.03 115.07,66.03 114.95,65.91 114.78,65.91 114.72,65.97 114.72,65.97 114.46,66.23 113.74,66.23 112.35,64.84 TP12.1
POK: length 308.1
  TOP w0.102: v2(172.12,52.61) PRH01.1 171.43,51.93 171.55,51.81 171.55,50.45 170.48,49.38 PR1801.1 167.67,48.51 167.67,44.64 167.36,44.32 155.42,44.32 154.47,43.37 154.47,40.87 155.71,39.62 156.68,39.62 159.23,37.08 v2(159.23,27.59) ; v2(99.2,26.33) 99.12,26.41 99.12,34.39 97.47,36.04 97.47,45.53 97.96,46.02 97.96,46.22 99.29,47.56 99.55,47.56 99.94,47.96 v1(99.94,50.63) 99.94,52.22 RC102.1 CC10.1 99.41,53.7 UC5.2
  TOP w0.254: v2(120.23,137.55) PR35.1 ; v2(108.62,141.69) 108.67,141.64 PR304.2
  IN1 w0.127: v2(159.23,27.59) 158.95,27.31 145.56,27.31 142.94,29.93 140.37,29.93 136.53,26.09 119.45,26.09 118.75,26.79 114.49,26.79 113.49,25.79 105.66,25.79 104.01,27.44 102.05,27.44 100.95,26.33 v2(99.2,26.33)
  IN1 w0.254: v2(172.12,52.61) 173.26,53.75 173.26,56.7 170.62,59.34 170.62,70.79 170.66,70.83 170.66,100.78 163.61,107.83 163.61,132.88 159.63,136.85 159.63,140.93 v2(159.66,140.95) 159.66,142.44 157.76,144.33 153.17,144.33 150.69,141.85 111.65,141.85 111.06,141.26 109.18,141.26 108.75,141.69 v2(108.62,141.69)
  IN2 w0.254: v2(120.23,137.55) 115.25,137.55 111.69,141.11 109.2,141.11 v2(108.62,141.69)
  BOTTOM w0.254: PU301.9 108.38,141.45 v2(108.62,141.69) ; v2(159.66,140.95) PR504.2 158.94,140.42 158.69,140.17 PU501.9
POWER_SW#_MB: length 261.2
  TOP w0.102: v2(31.98,81.4) 31.82,81.24 RE43.2 ; v2(219.62,60.7) 220.31,60.7 221.21,61.6 SW1.1 222.16,61.99 222.61,62.44 EC2901.1 222.61,64.54 223.43,65.36 TPS8.1 222.56,65.67 221.4,64.51 ED2901.3 221.17,65.67 v2(221.2,65.7)
  IN1 w0.127: v2(31.98,81.4) 31.98,80.63 33.18,79.43 34.1,79.43 39.12,74.41 39.12,64.92 40.96,63.08 40.96,61.75 42.14,60.57 42.14,55.25 45.87,51.52 45.87,45.12 56.35,34.64 60.36,34.64 62.26,32.74 95.63,32.74 96.73,33.84 101.35,33.84 102.33,32.86 144.15,32.86 146.27,30.74 153.07,30.74 153.9,31.57 162.04,31.57 162.62,30.99 179.64,30.99 181.32,32.67 192.73,32.67 194,33.93 206.18,33.93 208.92,36.67 208.92,38.25 210.68,40.01 215.18,40.01 218.54,43.37 218.54,59.62 v2(219.62,60.7)
  BOTTOM w0.102: JPWR1.2 222.2,64.7 v2(221.2,65.7)
POWER_SW_IN#: length 5.5
  TOP w0.102: RE43.1 RE41.2 CE33.1 34.23,79.13 34.23,78.82 v1(34.55,78.49) 34.6,78.45 35.31,78.45 35.6,78.15 UE1.127
PRIM_PWRGD: length 196.8
  TOP w0.102: PR1803.2 164.75,47.72 165.21,48.17 165.21,48.53 165.41,48.73 167.04,48.73 167.45,48.33 167.45,44.73 167.26,44.55 155.32,44.55 154.24,43.46 154.24,40.78 155.62,39.39 156.59,39.39 158.71,37.28 v1(158.71,32.6) v2(158.71,29.66) ; v2(34.96,63.62) 34.55,64.03 UE1.30
  TOP w0.254: PR1803.2 164.09,47.69 v2(163.93,47.86)
  IN1 w0.127: v2(34.96,63.62) 34.64,63.62 33.48,62.46 33.48,56.92 37.68,52.72 37.68,41.94 44.78,34.84 49.47,34.84 54.52,29.8 57.07,29.8 58.95,27.92 93.54,27.92 94.83,29.22 95.67,29.22 96.18,28.71 99.6,28.71 100.69,29.8 107.42,29.8 109.55,27.67 113.21,27.67 114.58,29.04 129.37,29.04 130.46,30.13 135.66,30.13 136.86,31.33 143.37,31.33 146.35,28.35 157.4,28.35 v2(158.71,29.66)
  BOTTOM w0.254: PU1801.4 164.19,47.6 v2(163.93,47.86)
PROCHOT: length 24.7
  TOP w0.102: RE53.2 48.83,56.62 UE2.2 ; RE53.2 48.69,55.92 v1(48.26,55.48) ; RE53.2 47.97,56.48 v2(47.79,56.66) ; UE1.83 48.18,70.43 48.18,70.43 43.62,70.43 v2(43.54,70.51)
  IN1 w0.127: v2(47.79,56.66) 47.96,56.83 47.96,59.36 46.01,61.31 46.01,63.44 43.54,65.91 v2(43.54,70.51)
PROG: length 3.2
  BOTTOM w0.203: PRB37.1 203.23,46.64 203.23,47.29 v1(203.02,47.5) 202.9,47.62 202.64,47.62 202.36,47.9 202.15,47.9 201.78,48.27 PUB01.9
PROH: length 3.8
  TOP w0.102: v2(203.44,50.6) v1(202.85,50.6)
  TOP w0.254: v2(203.44,50.6) PRB29.2 204.05,50.15 204.18,50.01 PQB05.2
  BOTTOM w0.203: PRB29.2 v2(203.44,50.6) 203.29,50.46 PUB01.5
PROJECT_ID0: length 26.6
  TOP w0.076: 115.36,64.03 115.36,64.35 v1(116.25,65.24) 116.37,65.24 116.52,65.08 117,65.08 v2(117.41,65.49)
  TOP w0.102: 115.36,64.03 115.36,63.7 112.18,60.52 112.18,59.1 109.25,56.17 107.45,56.17 105.57,54.29 105.11,54.29 104.63,53.81 RC53.2 RC54.1
  IN1 w0.102: v2(117.41,65.49) 117.9,65.01 118.37,65.01 118.46,64.91 118.46,63.88 119.06,63.27 121.1,63.27 v2(121.71,62.66)
  BOTTOM w0.076: v2(121.71,62.66) 121.56,62.66 UC1.AK6
PROJECT_ID1: length 11.7
  TOP w0.102: RC51.2 RC52.1 123.48,57.72 122.78,57.02 121.26,57.02 120.83,57.45 v1(120.83,60.26) 120.83,60.53 121.13,60.83 121.13,63.17 120.72,63.59 v2(120.72,63.7)
  BOTTOM w0.076: UC1.AK7 120.72,63.48 v2(120.72,63.7)
PS_ID: length 136.8
  TOP w0.102: v2(40.42,64.57) 39.66,63.81 37.5,63.81 36.4,62.72 UE1.36 ; PR5.1 v1(88.6,149.17)
  TOP w0.254: PR5.1 PR1.2 88.63,148.22 88.67,148.25 PD2.1 v2(89.28,146.74)
  IN1 w0.127: v2(40.42,64.57) 40.52,64.67 40.52,78.87 40.26,79.13 40.26,81.48 40.59,81.81 40.59,83.11 35.53,88.17 35.53,122.99 38.9,126.36 52.65,126.36 60.05,133.76 69.98,133.76 84.24,148.01 88.68,148.01 89.28,147.42 v2(89.28,146.74)
PSID: length 3.7
  TOP w0.102: PL3.1 84.41,144.26 v1(83.65,143.51)
  TOP w0.254: PL3.1 84.61,144.71 v2(85.2,145.31)
  BOTTOM w0.254: v2(85.2,145.31) PJPDC1.3
PSID-1: length 2.2
  TOP w0.254: PQ2.2 87.64,145.3 PR6.1 PR3.2
PSID-3: length 6
  TOP w0.102: PQ1.3 81.2,148.23 v1(80.84,147.87)
  TOP w0.254: PQ1.3 84.68,148.22 PR1.1
PTP_DIS#: length 133.1
  TOP w0.102: v2(50.73,73.2) 50.7,73.23 UE1.90 ; v2(127.86,43.17) 127.97,43.06 127.97,41.15 128.86,40.27 128.86,39.32 128.63,39.1 128.63,27.44 127.52,26.32 v1(126.92,26.32) D6.1
  IN1 w0.127: v2(127.86,43.17) 127.67,42.98 120.81,42.98 119.19,44.61 116.17,44.61 114.42,42.86 104.71,42.86 103.3,41.45 103.3,40.6 102.27,39.57 95.91,39.57 95.44,40.04 91.35,40.04 89.64,38.33 62.6,38.33 62.22,38.71 58.92,38.71 52.94,44.69 52.94,69.94 51.68,71.19 51.68,71.8 50.73,72.75 v2(50.73,73.2)
PWM1_2PH_CPU: length 48.7
  IN2 w0.254: v2(162.98,80.24) 163.61,80.88 163.61,101.09 159.33,105.36 155.99,105.36 151.75,109.61 151.75,110.88 151,111.63 147.58,111.63 146.95,112.26 146.95,113.61 v2(146.59,113.96)
  BOTTOM w0.102: v1(163.06,80.81) 162.98,80.72 v2(162.98,80.24)
  BOTTOM w0.203: PUZ01.16 146.74,114.1 v2(146.59,113.96)
  BOTTOM w0.254: v2(162.98,80.24) 163.25,79.96 163.25,79.05 162.96,78.75 PUI01.1
PWM2_2PH_CPU: length 25.4
  IN1 w0.254: v2(155.87,107.19) 154.59,108.47 154.59,111.02 153.52,112.09 149.09,112.09 147.81,113.38 147.81,113.97 147.34,114.44 146.55,114.44 v2(146.45,114.55)
  BOTTOM w0.203: v2(146.45,114.55) 146.5,114.55 146.58,114.47 147.1,114.47 147.14,114.5 PUZ01.17
  BOTTOM w0.254: v2(155.87,107.19) 157.44,107.19 v1(158.06,106.57) 161.9,102.74 161.9,101.26 161.68,101.04 PUI02.1
PWM_1A_CPU: length 27.7
  IN1 w0.254: v2(146.89,116.62) 147.45,116.62 149.39,118.55 150.91,118.55 151.42,119.06 151.42,119.95 149.01,122.36 149.01,127.76 147.42,129.34 144.12,129.34 143.29,128.52 141.13,128.52 140.24,129.41 v2(140.24,130.11)
  BOTTOM w0.203: PUZ01.22 147,116.5 v2(146.89,116.62)
  BOTTOM w0.254: v2(140.24,130.11) 140.62,130.48 PUG01.1
PWM_1B_CPU: length 73.8
  TOP w0.102: v2(172.06,61.06) v1(172.06,63.53) 172.06,75.02 166.43,80.65 166.43,97.39 164.88,98.94 164.73,98.94 163.87,99.8 163.87,100.9 158.78,105.98 158.78,112.3 158.99,112.5 158.99,115.77 159.86,116.64 159.86,118.93 159.1,119.69 157.77,119.69 157.26,120.2 155.8,120.2 154.72,119.12 v2(154.72,118.67)
  BOTTOM w0.102: PUZ01.36 153.01,118.44 153.24,118.67 v2(154.72,118.67)
  BOTTOM w0.254: PUA01.2 v2(172.06,61.06)
REGOUT:
  vias: v1(20.74,89.09)
RESET_OUT#: length 125.8
  TOP w0.102: UE1.73 47.68,66.43 47.23,65.98 47.23,64.08 48.04,63.27 48.04,62.48 50.38,60.14 50.38,60.14 51,59.53 52.4,59.53 52.55,59.68 53.75,59.68 54.06,59.98 54.06,60.46 v2(53.63,60.89) 53.63,62.03 54.23,62.64 v4(54.23,64.02) 54.23,64.86 53.91,65.18 52.57,65.18 CE31.1 RE16.1
  IN1 w0.127: v2(53.63,60.89) 53.5,60.89 53.19,60.58 53.19,44.8 59.03,38.96 62.33,38.96 62.7,38.58 89.53,38.58 91.47,40.52 92.17,40.52 93,41.36 v2(93.25,41.36)
  BOTTOM w0.076: 107.63,70.54 108.74,70.54 109.01,70.81 110.25,70.81 110.32,70.75 112.43,70.75 112.5,70.81 114.31,70.81 UC1.BA20
  BOTTOM w0.102: 107.63,70.54 106.2,70.54 96.68,61.02 96.68,61.01 95.98,60.31 95.98,53.45 94.18,51.65 94.18,47.6 94.43,47.34 94.43,46.04 93.73,45.34 93.73,41.84 v2(93.25,41.36)
RING2: length 1.2
  TOP w0.203: UA1.17 30.38,16.95 30.74,17.3 30.74,17.38
  vias: v1(30.6,18.46)
RING2_R: length 41.6
  TOP w0.508: 14.45,7.36 13.81,7.36 13.37,6.92 v1(7.68,6.92) 5.83,6.92 JHP1.4
  IN1 w0.508: JHP1.4 5.83,6.92 13.37,6.92 13.81,7.36 14.45,7.36
  IN2 w1.016: 30.96,21.9 29.88,21.9 28.23,20.25 23.64,20.25 22.77,19.38 22.77,16.52 19.59,13.34 19.59,10.03 18.64,9.08
  vias: v2(15.08,7.93) v2(15.08,7.35) v2(17.24,8.5) v2(17.88,8.5) v2(31.37,23.42) v2(31.37,22.84)
ROSC_COREGT_CPU: length 2.5
  BOTTOM w0.203: PRZ64.1 145.98,112.94 146.57,112.94 v1(146.71,113.07) 146.97,113.07 147.2,113.3 PUZ01.14
ROSC_SAUS_CPU: length 2.6
  BOTTOM w0.203: PUZ01.15 147.03,113.7 146.83,113.5 146.22,113.5 v2(146.21,113.5) 146.21,113.57 145.59,114.19 PRZ60.1
RTC_DET#: length 45.5
  TOP w0.102: v2(116.71,37.74) 116.11,37.14 113.83,37.14 v1(113.32,37.65) 113.32,39.87 113,40.19 Q1.1
  IN1 w0.127: v2(124.44,40.09) 124.44,39.44 122.68,37.68 116.77,37.68 v2(116.71,37.74)
  IN2 w0.127: v2(124.44,40.09) 124.36,40.17 124.36,43.08 124.49,43.21 124.49,50.22 125.64,51.37 v2(125.64,52.38)
  BOTTOM w0.102: v2(125.64,52.38) 127.03,52.38 127.32,52.67 131.65,52.67 132.41,53.43 132.41,55.8 RC46.1 132.13,57.21 132.13,57.38 131.51,58 130.54,58 129.06,59.48 UC1.P1
RTC_PWR: length 25.9
  TOP w0.508: v2(93.89,41.33) 93.89,40.51 v1(93.6,40.22) 91.83,40.22 91.25,39.63 D1.3 ; Q1.2 109.38,41.16 108.56,40.33 R2.1 R1.1 106.97,41.97 104.5,44.44 v2(103.88,44.44)
  IN1 w0.508: v2(103.88,44.44) 102.85,43.41 100.91,43.41 99.33,41.83 94.76,41.83 94.27,41.33 v2(93.89,41.33)
RTCRST_ON: length 96.1
  TOP w0.102: Q23.2 56.99,30.62 R75.1 ; R76.2 54.65,29.98 D7.1 55.77,30.92 C40.1 R75.1 ; v1(32.25,62.3) 32.51,62.56 32.51,63.47 32.67,63.63 UE1.31 34.35,63.63 v2(34.94,63.04) ; R75.1 56.68,31.81 v2(56.73,31.86)
  IN1 w0.127: v2(34.94,63.04) 34.94,63.03 33.73,61.82 33.73,58.2 39.41,52.52 39.41,41.74 44.61,36.54 49.28,36.54 52.87,32.95 54.36,31.45 56.32,31.45 v2(56.73,31.86)
  BOTTOM w0.102: v2(56.73,31.86) 56.73,30.5 57.91,29.32 59.98,29.32 61.45,27.85 83.42,27.85 85.78,30.21 85.78,34.45 RC164.1 87.26,35.92 QC2.2
RUNPWROK: length 4.1
  TOP w0.102: v1(40.15,58.45) 40.38,58.68 RE42.2 41.12,59.11 41.3,59.3 41.3,60.55 41.2,60.64 UE1.48
SATA3_CRX_C_HDDTX_N0: length 9.1
  BOTTOM w0.097: JHDD1.5 188.2,35.13 188.13,35.06 188.13,34.55 187.69,34.11 181.7,34.11 181.38,33.79 180.86,33.79 CS3.2
SATA3_CRX_C_HDDTX_P0: length 8.9
  BOTTOM w0.097: CS4.2 181.16,33.98 181.3,33.98 181.62,34.3 187.61,34.3 187.95,34.63 187.95,34.91 187.7,35.15 JHDD1.6
SATA3_CRX_HDDTX_N0: length 79
  IN2 w0.076: 135.14,70.79 135.12,70.8 135.09,70.8 134.42,71.47 133.9,71.47 133.64,71.21 133.64,71.04 133.51,70.91 v2(133.43,70.91)
  IN2 w0.122: 135.14,70.79 136.36,69.56 136.36,68.04 137.46,66.95 138.04,66.95 141.26,63.73 141.26,56.75 142.09,55.92 142.09,46.86 140.87,45.64 140.87,45.33 v2(141.02,45.18)
  BOTTOM w0.076: v2(133.43,70.91) 133.43,70.74 UC1.F20
  BOTTOM w0.097: v2(141.02,45.18) 140.81,45.38 140.81,45.64 141.4,46.23 142.16,46.23 142.2,46.27 143.68,46.27 144.61,45.33 148.48,45.33 153.69,40.12 153.69,38.87 155.04,37.52 164.12,37.52 164.56,37.08 171.24,37.08 175.57,32.75 177.22,32.75 178.41,33.94 179.39,33.94 CS3.1
SATA3_CRX_HDDTX_P0: length 78.9
  IN2 w0.076: v2(134.15,70.91) 133.93,70.91 133.8,71.04 133.8,71.14 133.97,71.31 134.35,71.31 134.95,70.71 134.95,70.62 134.96,70.61
  IN2 w0.122: 134.96,70.61 136.11,69.46 136.11,67.94 137.36,66.7 137.94,66.7 141.01,63.63 141.01,56.65 141.84,55.82 141.84,46.97 140.62,45.75 140.62,45.36 v2(140.44,45.18)
  BOTTOM w0.076: UC1.E20 133.82,70.59 134.15,70.91 v2(134.15,70.91)
  BOTTOM w0.097: v2(140.44,45.18) 140.63,45.36 140.63,45.72 141.36,46.45 v3(141.87,46.45) 143.76,46.45 144.69,45.52 148.55,45.52 153.88,40.2 153.88,38.95 155.12,37.71 164.2,37.71 164.64,37.27 171.32,37.27 175.65,32.94 177.14,32.94 178.33,34.13 179.39,34.13 CS4.1
SATA3_CTX_C_HDDRX_N0: length 11.4
  BOTTOM w0.097: JHDD1.3 189.2,35.11 189.36,34.96 189.36,34.45 188.61,33.71 181.96,33.71 181.49,33.24 181.49,32.55 181.28,32.35 181.01,32.35 CS2.2
SATA3_CTX_C_HDDRX_P0: length 11.7
  BOTTOM w0.097: CS1.2 181.01,32.16 181.36,32.16 181.67,32.47 181.67,33.16 182.03,33.52 188.69,33.52 189.54,34.38 189.54,34.95 189.7,35.1 JHDD1.2
SATA3_CTX_HDDRX_N0: length 75.1
  IN2 w0.122: v2(141.85,45.18) 142.03,45.35 142.03,45.88 142.51,46.37 142.51,56.1 141.68,56.93 141.68,63.91 137.9,67.7 137.9,69.63 137.56,69.96 137.56,70.27 v2(137.39,70.44)
  BOTTOM w0.076: v2(137.39,70.44) 137.58,70.62 137.58,71.01 137.36,71.22 136.26,71.22 136.09,71.4 136.09,71.59 136.08,71.59 UC1.B21
  BOTTOM w0.097: v2(141.85,45.18) 142.05,45.37 142.05,45.55 142.34,45.84 143.36,45.84 144.26,44.93 v3(146.8,44.93) 148.31,44.93 153.29,39.95 153.29,38.71 155.38,36.61 171.14,36.61 175.4,32.35 179.39,32.35 CS2.1
SATA3_CTX_HDDRX_P0: length 74.9
  IN2 w0.122: v2(142.43,45.18) 142.28,45.33 142.28,45.78 142.76,46.27 142.76,56.2 141.93,57.03 141.93,64.02 138.15,67.8 138.15,69.73 137.81,70.07 137.81,70.24 v2(137.98,70.41)
  BOTTOM w0.076: UC1.A21 136.36,71.68 136.25,71.57 136.25,71.47 136.29,71.43 136.29,71.43 136.33,71.39 136.93,71.39 136.93,71.39 137.43,71.39 137.74,71.08 137.74,70.64 v2(137.98,70.41)
  BOTTOM w0.097: v2(142.43,45.18) 142.23,45.37 142.23,45.47 142.41,45.65 143.28,45.65 144.19,44.74 146.47,44.74 146.5,44.71 147.09,44.71 147.12,44.74 148.23,44.74 153.1,39.88 153.1,38.63 155.3,36.42 171.06,36.42 175.32,32.16 179.39,32.16 CS1.1
SATA_CRX_C_ODDTX_N1: length 10.2
  BOTTOM w0.097: CS10.1 193.23,61.37 193.23,61.75 192.49,62.49 v3(192.06,62.49) 191.02,62.49 190.98,62.45 190.4,62.45 190.36,62.49 190.16,62.49 189.61,63.05 189.61,63.26 189.51,63.36 189.3,63.36 189.2,63.46 JODD1.9 189.2,65.15 189.3,65.24 189.51,65.24 189.61,65.34 189.61,66.26 189.51,66.36 189.3,66.36 189.2,66.46 JODD1.10
SATA_CRX_C_ODDTX_P1: length 10.2
  BOTTOM w0.097: JODD1.12 190.2,66.46 190.1,66.36 189.89,66.36 189.79,66.26 189.79,65.34 189.89,65.24 190.1,65.24 190.2,65.15 JODD1.11 190.2,63.46 190.1,63.36 189.89,63.36 189.79,63.26 189.79,63.13 190.24,62.68 v3(190.69,62.68) 191.73,62.68 191.77,62.72 192.4,62.72 192.44,62.68 192.57,62.68 193.42,61.83 193.42,61.37 CS9.1
SATA_CRX_ODDTX_N1: length 77.1
  IN2 w0.076: 133.85,77.46 133.61,77.46 133.07,76.92 132.51,76.92 132.21,76.63 132.21,72.5 132.47,72.23 132.97,72.23 133.04,72.16 133.04,72.07 v2(132.83,71.85)
  IN2 w0.122: v2(193.04,59.49) 193.27,59.26 193.27,59.08 193.11,58.92 192.57,58.92 191.32,60.17 182.1,60.17 175.14,67.14 155.64,67.14 150.84,71.94 149.46,71.94 147.76,73.64 146.02,73.64 145.1,74.56 144.81,74.56 143.56,75.81 142.7,75.81 141.31,77.19 137.3,77.19 137.18,77.07 136.27,77.07 135.32,78.01 134.64,78.01 134.41,77.78 134.17,77.78 133.85,77.46
  BOTTOM w0.097: v2(132.83,71.85) 132.83,71.7 UC1.G21 ; CS10.2 193.23,59.75 193.23,59.69 v2(193.04,59.49)
SATA_CRX_ODDTX_P1: length 77.2
  IN2 w0.076: 133.92,77.23 133.9,77.23 133.88,77.26 133.69,77.26 133.16,76.72 132.59,76.72 132.41,76.54 132.41,72.53 132.54,72.4 133.03,72.4 133.21,72.23 133.21,72.02 133.37,71.85 v2(133.49,71.85)
  IN2 w0.122: 133.92,77.23 134.26,77.57 134.5,77.57 134.69,77.76 135.22,77.76 136.17,76.82 137.28,76.82 137.41,76.94 141.21,76.94 142.59,75.56 143.46,75.56 144.71,74.31 145,74.31 145.92,73.39 147.65,73.39 149.35,71.69 150.73,71.69 155.54,66.89 175.03,66.89 182,59.92 191.22,59.92 192.47,58.67 193.21,58.67 193.52,58.98 193.52,59.39 v2(193.62,59.49)
  BOTTOM w0.097: v2(193.62,59.49) 193.42,59.69 193.42,59.75 CS9.2 ; UC1.F21 133.5,71.8 v2(133.49,71.85)
SATA_CTX_C_ODDRX_N1: length 10.6
  BOTTOM w0.097: CS11.1 190.44,61.37 190.44,61.83 190.2,62.06 189.29,62.06 189.25,62.1 188.67,62.1 188.63,62.06 v3(187.61,62.06) 187.13,62.06 186.79,62.4 186.79,63.26 186.89,63.36 187.1,63.36 187.2,63.46 JODD1.5 187.2,65.15 187.1,65.24 186.89,65.24 186.79,65.34 186.79,66.26 186.89,66.36 187.1,66.36 187.2,66.46 JODD1.6
SATA_CTX_C_ODDRX_P1: length 10.6
  BOTTOM w0.097: CS12.1 190.25,61.37 190.25,61.75 190.12,61.87 v3(188.96,61.87) 187.94,61.87 187.9,61.83 187.32,61.83 187.28,61.87 187.05,61.87 186.61,62.32 186.61,63.26 186.51,63.36 186.3,63.36 186.2,63.46 JODD1.3 186.2,65.15 186.3,65.24 186.51,65.24 186.61,65.34 186.61,66.26 186.51,66.36 186.3,66.36 186.2,66.46 JODD1.4
SATA_CTX_ODDRX_N1: length 66.3
  IN2 w0.122: v2(190.64,58.77) 190.56,58.85 190.56,59.29 190.36,59.49 181.82,59.49 174.86,66.46 155.36,66.46 150.85,70.97 149.33,70.97 147.42,72.88 145.83,72.88 144.82,73.89 144.53,73.89 143.46,74.95 143,74.95 v2(142.88,75.08)
  BOTTOM w0.076: 139,71.9 138.99,71.88 138.98,71.88 138.97,71.87 137.09,71.87 136.83,72.12 136.42,72.12 136.29,72.07 136.12,72.07 136.06,72.1 136,72.11 135.83,72.11 135.72,72.08 135.72,72.08 135.64,72.05 135.53,72.05 135.13,72 UC1.D21
  BOTTOM w0.097: CS11.2 190.64,59.95 v2(190.64,58.77) ; v2(142.88,75.08) 142.19,75.08 141.93,74.82 141.93,74.26 139.99,72.32 139.43,72.32 139,71.9
SATA_CTX_ODDRX_P1: length 66.3
  IN2 w0.122: v2(190.05,58.77) 190.31,59.03 190.31,59.19 190.25,59.25 181.72,59.25 174.75,66.21 155.26,66.21 150.75,70.72 149.22,70.72 147.31,72.63 145.72,72.63 144.72,73.64 144.43,73.64 143.36,74.7 143.06,74.7 v2(142.85,74.5)
  BOTTOM w0.076: 139,71.69 138.98,71.69 138.97,71.7 137.02,71.7 136.76,71.95 136.46,71.95 136.32,71.89 136.17,71.89 135.98,71.94 135.84,71.94 135.77,71.92 135.77,71.92 135.67,71.89 135.58,71.89 135.52,71.82 135.52,71.79 135.6,71.71 135.6,71.6 135.56,71.57 135.35,71.57 UC1.C21
  BOTTOM w0.097: v2(190.05,58.77) 190.45,59.17 190.45,59.65 189.99,60.1 CS12.2 ; v2(142.85,74.5) 142.46,74.89 142.27,74.89 142.12,74.74 142.12,74.19 140.07,72.13 139.51,72.13 139.07,71.69 139,71.69
SATA_LED#: length 306
  TOP w0.102: v2(40.52,35.72) 39.71,34.91 39.71,31.89 38.67,30.84 38.67,23.91 38.21,23.45 R77.2 ; v2(132.7,57.26) 132.98,57.26 133.77,58.04 RC69.1 133.3,58.64 133.02,58.64 132.79,58.88 132.79,59.13 132.59,59.33 v2(132.59,59.33)
  IN1 w0.127: v2(40.52,35.72) 40.52,37.67 36.57,41.62 36.57,52.39 28.65,60.31 28.65,66.2 28.13,66.72 28.13,72.71 26.27,74.57 26.27,78.01 28.96,80.7 28.96,82.28 28.63,82.61 28.63,87.76 26.77,89.63 26.77,104.29 25.08,105.98 25.08,115.2 v2(31.61,121.72) ; v2(38.45,122.66) 38.45,117.34 52.49,103.31 52.49,75.81 53.64,74.66 53.64,73.22 52.55,72.13 52.55,70.97 54.27,69.25 54.27,67.43 53.66,66.82 53.66,65.62 54.33,64.95 54.33,59.28 55.48,58.13 55.48,46.72 56.28,45.92 56.28,44.93 57.52,43.68 58.19,43.68 60.22,41.65 67.48,41.65 67.73,41.4 88.5,41.4 92.34,45.23 97.42,45.23 99.92,47.73 99.92,49.68 101.98,51.74 101.98,54 102.12,54.14 106.31,54.14 107.99,55.81 114.13,55.81 115.83,54.12 118.27,54.12 120.46,56.31 122.92,56.31 122.94,56.29 124.03,56.29 124.09,56.36 124.68,56.36 125.04,56 131.98,56 132.7,56.71 v2(132.7,57.26)
  BOTTOM w0.076: UC1.H1 132.37,59.54 132.58,59.33 v2(132.59,59.33)
  BOTTOM w0.102: Q25.2 25.84,122.06 R78.1 25.59,121.02 25.84,120.76 30.64,120.76 v2(31.61,121.72) 32.55,122.66 v1(34.98,122.66) v2(38.45,122.66)
SATA_LED#_R: length 6.6
  BOTTOM w0.102: Q25.3 25.6,122.71 R78.2 R80.2 v1(22.82,122.72) 20.18,122.72 Q22.3
SATA_ODD_DA#: length 4.8
  BOTTOM w0.102: JODD1.24 JODD1.23 196.2,62.82 196.2,62.82 TP46.1
SATA_ODD_PRSNT#: length 310.6
  TOP w0.102: RE81.2 30.9,84.01 37.63,90.74 37.63,96.2 39.66,98.23 v1(51.9,98.23) v2(53.12,98.23) ; v2(209.03,46.73) 209.03,48.7 209.67,49.35 209.67,54.48 209.22,54.94 206.59,54.94 205.25,56.27 205.25,58.17 200,63.43 196.71,63.43 RC194.1 194.85,61.58 v2(194.85,60.19)
  IN1 w0.127: v2(53.12,98.23) 53.88,97.47 53.88,82.48 55.13,81.24 55.13,70.92 55.51,70.53 55.51,59.35 56.36,58.5 56.36,47.57 56.79,47.15 57.15,47.15 61.76,42.54 67.85,42.54 68.1,42.29 85.46,42.29 90.69,47.52 92.78,47.52 94.02,48.76 97.06,48.76 99.76,51.47 99.76,52.67 101.74,54.64 105.57,54.64 107.03,56.1 107.03,56.38 108.35,57.7 114.42,57.7 115.48,56.64 118.91,56.64 121.13,58.86 122.72,58.86 122.95,58.62 125.05,58.62 v2(125.31,58.37) 126.03,58.37 126.75,57.64 128.55,57.64 129.22,58.32 132.67,58.32 133.12,57.87 137.35,57.87 139.1,56.13 140.43,56.13 140.76,56.46 148.16,56.46 148.94,55.67 148.94,47.11 150.5,45.55 151.05,45.55 155.94,40.66 169.62,40.66 173.68,36.6 175.43,36.6 175.93,37.09 182.88,37.09 183.1,37.31 188.59,37.31 189.42,38.13 191.35,38.13 191.68,37.8 200.83,37.8 209.03,46 v2(209.03,46.73)
  BOTTOM w0.076: v2(125.31,58.37) 125.13,58.37 124.98,58.51 124.98,59.25 125.08,59.34 UC1.AB1
  BOTTOM w0.102: JODD1.16 JODD1.15 192.2,63.49 192.59,63.1 194.17,63.1 194.85,62.42 v2(194.85,60.19)
SCLK_CPU: length 2.5
  BOTTOM w0.102: PUZ01.34 152.21,118.56 153.13,119.49 153.15,119.49 PRZ46.1
SD_RCOMP: length 2.9
  TOP w0.102: v2(124.84,63.22) 125.14,63.22 125.31,63.06 RC130.1
  BOTTOM w0.076: v2(124.84,63.22) 125.09,62.97 UC1.AB7
SDIO_CPU: length 2.1
  BOTTOM w0.102: PUZ01.32 151.41,118.71 151.55,118.85 151.55,119.17 151.93,119.55 PRZ48.1
SIO_EXT_WAKE#: length 146
  TOP w0.102: UE1.116 40,76.29 41.02,75.27 43.06,75.27 43.42,74.92 45.37,74.92 v2(45.45,75) ; RC47.1 123.64,56.83 v2(123.79,56.98) ; v2(123.07,39.87) 123.05,39.89 v1(123.05,40.52)
  IN1 w0.127: v2(123.07,39.87) 122.14,38.95 115.88,38.95 114.57,40.25 108.33,40.25 106.8,41.78 105.06,41.78 104.32,41.03 104.32,40.18 102.68,38.54 96.45,38.54 96.14,38.23 90.98,38.23 90.06,37.31 62.18,37.31 61.8,37.69 58.43,37.69 50.54,45.58 50.54,54.72 51.92,56.09 51.92,60.24 50.58,61.58 50.58,64.96 51,65.38 51,67.99 51.72,68.71 51.72,69.86 49.46,72.12 47.77,72.12 45.45,74.45 v2(45.45,75)
  IN2 w0.127: v2(123.79,56.98) 123.79,55.95 124.64,55.1 124.64,52.74 122.14,50.24 122.14,41.27 123.07,40.35 v2(123.07,39.87)
  BOTTOM w0.076: UC1.AD3 123.68,60.67 123.5,60.36 123.5,60.11 123.55,60.02 123.55,59.82 123.45,59.62 123.45,59.49 123.57,59.36 123.57,58.15 123.42,58 123.42,57.35 v2(123.79,56.98)
SIO_PWRBTN#: length 127.5
  TOP w0.102: UE1.52 42.8,60.29 42.23,59.72 42.23,59.17 41.72,58.66 v2(41.72,56.92) 41.13,56.33 v1(40.61,56.33)
  IN1 w0.127: v2(41.72,56.92) 41.72,55.25 45.62,51.35 45.62,45.01 56.24,34.39 60.25,34.39 62.15,32.49 95.73,32.49 96.83,33.59 99.86,33.59 v2(100.43,33.02)
  BOTTOM w0.076: 108.29,68.03 108.34,68.08 113.5,68.08 113.7,67.88 114.14,67.88 114.4,68.14 UC1.BA15
  BOTTOM w0.102: v2(100.43,33.02) 100.43,33.75 99.42,34.75 99.42,41.4 RC93.2 99.48,41.56 99.02,42.02 99.02,42.67 98.51,43.17 98.51,49.77 98.78,50.03 98.78,52.13 98.31,52.6 98.31,56.89 98.73,57.31 98.73,58.42 108.29,67.99 108.29,68.03
SIO_SLP_A#: length 1.4
  TOP w0.102: v2(119.25,69.05) 118.78,69.53 TPS6.1
  BOTTOM w0.102: UC1.AN16 119.63,68.65 v2(119.25,69.05)
SIO_SLP_LAN#: length 3.7
  TOP w0.102: RC88.1 117.46,66.62 117.83,66.99 117.83,67.5 117.61,67.72 TP10.1 116.77,68.1 v2(116.59,68.1)
  BOTTOM w0.076: v2(116.59,68.1) 116.51,68.18 UC1.AW15
SIO_SLP_S0#: length 173.1
  TOP w0.102: UC9.2 150.18,50.95 151.42,49.72 v2(154.02,49.72) ; v2(118.18,66.37) 118.18,66.45 118.5,66.77 TPS2.1 ; RE92.1 52.99,46.52 52.13,46.52 51.93,46.72 v2(51.93,47.18) ; v2(108.24,41.97) 108.75,42.48 109.95,42.48 110.71,41.71 110.71,36.06 v2(110.65,36)
  IN1 w0.127: v2(116.14,43.57) 116.59,43.11 119.67,43.11 120.3,42.48 128.73,42.48 129.23,42.98 133.02,42.98 134.06,44.02 150.4,44.02 v2(150.66,44.28) ; v2(108.24,41.97) 108.17,41.97 107.6,42.54 104.75,42.54 103.56,41.35 103.56,40.5 102.37,39.31 95.81,39.31 95.34,39.78 91.46,39.78 89.75,38.07 62.49,38.07 62.11,38.45 58.82,38.45 51.93,45.34 v2(51.93,47.18)
  IN2 w0.127: v2(150.66,44.28) 151.16,44.79 151.16,46.86 v2(154.02,49.72) ; v2(108.24,41.97) 108.75,41.46 109.54,41.46 109.93,41.85 114.17,41.85 115.66,43.34 115.91,43.34 v2(116.14,43.57) 116.24,43.67 116.24,45.92 117.77,47.45 117.77,52.11 125.89,60.23 125.89,61.58 126.18,61.87 126.18,63.11 v2(125.93,63.37)
  BOTTOM w0.076: v2(125.93,63.37) 125.93,63.46 125.45,63.94 125.27,63.94 125.01,64.21 124.74,64.21 124.56,64.38 124.56,64.7
  BOTTOM w0.102: 124.56,64.7 124.56,64.77 124.75,64.96 124.88,64.96 125.19,65.27 125.47,65.27 125.66,65.45 125.66,65.69 125.49,65.86 123.05,65.86 122.47,65.28 120.74,65.28 120.49,65.53 118.95,65.53 118.65,65.83 118.65,66.01 118.29,66.37 v2(118.18,66.37) 118.14,66.37 UC1.AT11 ; RX9.2 110.45,36.2 v2(110.65,36) ; v2(108.24,41.97) 107.65,41.38 RX10.2
SIO_SLP_S3#: length 327.8
  TOP w0.102: v2(153.88,48.84) 151.21,48.84 149.53,50.52 TPS3.1 149.53,51.1 UC9.1 149.53,53.29 150.18,53.94 150.18,55.64 RZ2.1 ; v2(118.61,68.2) 118.82,67.98 118.82,64.98 118.35,64.51 118.35,63.33 118.18,63.15 117,63.15 116.86,63.01 116.86,61.08 115.14,59.36 115.14,53.78 117.74,51.17 117.74,43.94 118.99,42.69 v2(119.25,42.69) 119.25,41.17 118.91,40.83 DZ4.1 119.93,40.02 RC103.1 ; UZ3.3 127.37,136.78 127.42,136.82 127.42,137.33 127.24,137.51 127.24,137.51 v2(126.96,137.79) 126.92,137.83 126.77,137.83 126.53,137.58 126.53,136.82 126.57,136.78 UZ3.5
  IN1 w0.127: v2(119.25,42.69) 119.72,42.22 128.88,42.22 129.37,42.72 133.12,42.72 134.17,43.77 v2(151.16,43.77) 151.4,43.77 155.52,39.64 163.52,39.64 v2(164.05,39.11)
  IN2 w0.127: v2(153.88,48.84) 151.67,46.64 151.67,44.28 v2(151.16,43.77) ; v2(200.88,66.04) 200.03,66.89 187.25,66.89 181.01,73.12 170.26,73.12 167.67,75.71 167.67,102.48 163.55,106.61 163.55,120.96 165.96,123.38 165.96,144.46 163.1,147.32 132.11,147.32 v2(128.49,143.7) ; v2(164.05,39.11) 167.12,39.11 167.95,39.94 183.05,39.94 183.87,40.76 189.41,40.76 191.64,42.98 203.17,42.98 204.89,44.7 204.89,53.46 203.36,54.99 201.01,54.99 v2(198.34,57.65)
  BOTTOM w0.102: v2(118.61,68.2) UC1.AP15 ; v2(128.49,143.7) 128.49,138.43 127.86,137.79 v2(126.96,137.79) ; v2(198.34,57.65) 198.34,59.11 200.88,61.65 v2(200.88,66.04)
SIO_SLP_S4#: length 281.4
  TOP w0.102: 152.53,66.29 DZ5.1 151.58,66.94 RZ1.1 ; 152.53,66.29 v2(152.53,66.28) ; 152.53,66.29 152.59,66.23 153.17,66.23 153.42,65.97 v1(153.42,65.18)
  IN1 w0.127: v2(135.08,28.63) 134.63,28.19 114.81,28.19 113.41,26.79 105.95,26.79 103.7,29.04 101.01,29.04 100.16,28.19 95.44,28.19 v2(95.16,28.47)
  IN2 w0.127: v2(152.53,66.28) 152.53,65.63 152.33,65.43 152.33,62.09 153.93,60.49 153.93,56.96 153.55,56.57 153.55,49.81 150.22,46.48 150.22,35.75 149.51,35.05 145.72,35.05 143.65,32.98 139.42,32.98 v2(135.08,28.63) ; v2(95.87,44.7) 95.48,45.1 94.56,45.1 94.14,44.68 v2(93.27,44.68)
  BOTTOM w0.076: UC1.BA16 114.71,68.58 108.96,68.58 TPS4.1 107.09,68.77 103.22,64.89
  BOTTOM w0.102: 103.22,64.89 98.27,59.94 98.27,57.82 97.76,57.31 97.76,52.2 96.41,50.85 96.41,48.12 95.87,47.57 v2(95.87,44.7) 95.87,43.14 95.53,42.79 95.53,40.09 95.84,39.77 95.84,33 95.03,32.18 95.03,28.6 v2(95.16,28.47) 94.31,27.62 PR2501.1 ; v2(93.27,44.68) 93.32,44.72 93.32,45.25 93.82,45.75 93.82,46.79 93.62,47 93.62,49.61 92.73,50.5 92.73,112.44 98.92,118.63 98.92,125.28 97.37,126.83 95.58,126.83 94.53,127.87 PRM08.1
SIO_SLP_S5#: length 135
  TOP w0.102: v2(176.31,36.16) 176.07,36.4 PQB07.2 ; v2(95.12,41.22) 95.12,40.8 TPS5.1
  IN1 w0.127: v2(176.31,36.16) 175.9,35.75 171.63,35.75 171.18,36.19 168.06,36.19 164.35,39.9 155.63,39.9 150.83,44.7 150.08,44.7 149.67,44.28 133.96,44.28 133.49,43.81 128.98,43.81 128.76,43.59 125.63,43.59 v2(125.49,43.45) ; v2(95.12,41.22) 95.77,40.57 100.24,40.57 102.34,42.66 103.97,42.66 104.43,43.12 114.32,43.12 117.18,45.98 119.86,45.98 120.19,45.65 122.84,45.65 123.41,46.22 124.62,46.22 v2(124.94,45.91)
  IN2 w0.127: v2(124.94,45.91) 124.94,44 v2(125.49,43.45)
  BOTTOM w0.076: UC1.AY16 115.26,69.04 114.78,69.04 114.48,68.74 109.74,68.74 109.28,69.2 106.9,69.2
  BOTTOM w0.102: 106.9,69.2 100.31,62.6 100.31,62.59 97.46,59.74 97.46,52.21 96.19,50.94 96.19,48.21 95.4,47.42 95.4,45.64 94.7,44.94 94.7,43.06 95.12,42.64 v2(95.12,41.22)
SIO_SLP_SUS#: length 2.3
  TOP w0.102: TP75.1 119.73,68.64 v2(119.27,68.18)
  BOTTOM w0.076: v2(119.27,68.18) 119.64,67.82 UC1.AN15
SIO_SLP_WLAN#: length 3.8
  BOTTOM w0.076: TP11.1 110.5,69.07 113.66,69.07 UC1.BB17
SLEEVE: length 1.1
  TOP w0.203: UA1.18 29.98,17.26 30.1,17.38
  vias: v1(29.08,18.42)
SLEEVE_R: length 33.8
  IN1 w1.016: 15.34,12.82 15.34,14.47 15.73,14.86 15.73,17.26 14.32,18.66 6.32,18.66 5.06,17.4 JHP1.3
  IN2 w1.016: 27.78,22.22 26.96,21.39 23.02,21.39 21.5,19.87 21.5,16.95 18.39,13.84 18.39,12
  vias: v1(28.19,22.82) v2(15.02,11.87) v2(15.66,11.87) v2(18.39,11.11) v2(18.39,10.47) v2(28.61,23.11) v2(28.61,22.47)
SM_RCOMP0: length 16.4
  TOP w0.305: RC10.1 106.94,62.8 v1(108.21,64.07) 111.68,64.07 114.6,66.99 114.6,68.28 115.88,69.56 117.86,69.56 118.06,69.76 v2(118.06,70.02)
  BOTTOM w0.254: UC1.AR18 118.16,69.74 118.16,69.92 v2(118.06,70.02)
SM_RCOMP1: length 15.3
  TOP w0.305: v2(117.35,70.04) 117.35,70.2 116.95,70.59 114.76,70.59 113.19,69.02 113.19,67.88 111.01,65.69 v1(107.53,65.69) 106.42,64.57 RC11.1
  BOTTOM w0.254: UC1.AT18 117.68,69.7 117.35,70.04 v2(117.35,70.04)
SM_RCOMP2: length 14.5
  TOP w0.305: v2(116.76,70.06) 115.37,70.06 113.95,68.64 113.95,67.49 111.34,64.88 v1(109.58,64.88) 107.87,64.88 106.68,63.69 RC12.1
  BOTTOM w0.254: UC1.AU18 116.76,69.84 v2(116.76,70.06)
SMB_ALERT#: length 14
  TOP w0.102: v2(127.8,54.01) 127.8,53.42 v1(127.85,53.37)
  IN2 w0.127: v2(127.8,54.01) 127.92,54.14 127.92,56.47 127.42,56.98 127.42,60.36 127.64,60.59 127.64,64.87 v2(128,65.23)
  BOTTOM w0.102: UC1.R10 128.26,65.23 v2(128,65.23) ; RC37.1 128.13,54.35 v2(127.8,54.01)
SML0_SMBCLK: length 9.7
  BOTTOM w0.076: RC33.1 127.13,57.53 126.09,58.57 126.09,59.22 125.97,59.33 125.97,59.71 126.08,60.06 126.09,60.1 126.09,61.7 126.35,61.95 126.45,61.95 126.71,62.21 126.71,62.79 127.22,63.3 127.58,63.3 127.78,63.51 127.78,63.74 127.67,63.85 127.67,64.05 128.02,64.4 128.44,64.4 UC1.R9
SML0_SMBDATA: length 4.1
  BOTTOM w0.076: UC1.W2 126.27,60.1 126.15,59.7 126.15,59.39 126.25,59.29 126.25,59.08 v1(127.43,57.91) 128.02,57.32 RC34.1
SML1_SMBCLK: length 307.9
  TOP w0.102: RE11.1 29.17,71.88 32.04,71.88 32.68,71.23 UE1.12 34.54,71.23 34.58,71.27 34.93,71.27 v2(35.09,71.11)
  IN2 w0.127: v2(131.15,57.23) 131.32,57.06 131.32,54.34 129.71,52.73 129.71,50.45 128.37,49.11 128.37,42.63 127.73,41.99 127.73,39.15 127.18,38.6 124.51,38.6 123.47,37.56 117.27,37.56 116.95,37.24 114.92,37.24 113.98,38.18 110.52,38.18 110.13,38.58 105.61,38.58 105.21,38.18 100.2,38.18 99.87,38.51 95.61,38.51 95.17,38.07 93.13,38.07 92.71,38.49 91.52,38.49 90.44,37.4 55.4,37.4 48.55,44.25 40.84,44.25 v2(40.67,44.42) ; v2(35.09,71.11) 34.98,71.22 34.54,71.22 33.82,71.94 33.82,75.35 30.38,78.79 30.38,82.76 28.25,84.89 26.9,84.89 26.36,85.44 26.36,86.58 25.74,87.21 24.46,87.21 17.82,93.84 17.82,102.48 19.05,103.7 21.11,103.7 22.81,105.41 23.3,105.41 24.25,106.36 24.25,106.76 42.83,125.34 48.13,125.34 49.65,126.87 52.13,126.87 55.63,130.37 78.42,130.37 79.17,129.62 88.22,129.62 90.28,127.57 92.19,127.57 93.39,128.76 97.67,128.76 98.08,128.35 106.21,128.35 106.37,128.52 108.34,128.52 108.43,128.43 v2(108.72,128.43)
  BOTTOM w0.076: UC1.W3 126.41,60.65 126.62,60.43 126.66,60.34 126.66,60.13 126.61,60.05 126.61,59.79 126.66,59.75 126.66,59.44 127.29,58.81 127.29,58.71 127.69,58.3 128.58,58.3 128.61,58.28
  BOTTOM w0.102: Q11.3 107.11,126.71 108.52,126.71 108.92,127.11 108.92,128.23 v2(108.72,128.43) ; RPC3.3 131.19,56.29 131.32,56.42 131.32,57.06 v2(131.15,57.23) 131.32,57.41 131.32,57.51 131.21,57.62 130.29,57.62 129.88,58.02 128.86,58.02 128.61,58.28 ; v2(40.67,44.42) 40.51,44.25 40.24,44.25 33.89,50.61 33.89,70.42 34.76,71.29 34.91,71.29 v2(35.09,71.11)
SML1_SMBDATA: length 304.9
  TOP w0.102: RE10.1 31.88,72.48 32.73,71.63 UE1.11 34.44,71.63 34.58,71.5 34.89,71.5 v2(35.09,71.69)
  IN2 w0.127: v2(35.09,71.69) 34.86,71.47 34.64,71.47 34.07,72.05 34.07,75.46 30.63,78.89 30.63,82.87 28.36,85.15 27.01,85.15 26.62,85.54 26.62,86.69 25.84,87.46 24.56,87.46 18.08,93.95 18.08,102.37 19.15,103.45 21.21,103.45 22.92,105.15 23.4,105.15 24.51,106.26 24.51,106.66 42.94,125.09 48.23,125.09 49.75,126.61 52.23,126.61 55.74,130.12 78.32,130.12 79.07,129.37 88.11,129.37 90.17,127.31 92.3,127.31 93.49,128.51 97.57,128.51 97.97,128.1 106.31,128.1 106.48,128.27 108.24,128.27 108.3,128.2 v2(108.3,128.01) ; v2(40.67,43.84) 40.84,44 48.44,44 55.29,37.15 90.54,37.15 91.62,38.23 92.61,38.23 93.02,37.82 95.28,37.82 95.72,38.26 99.76,38.26 100.09,37.93 105.32,37.93 105.72,38.33 110.02,38.33 110.42,37.93 113.88,37.93 114.82,36.99 117.06,36.99 117.37,37.31 123.58,37.31 124.62,38.35 127.29,38.35 127.98,39.04 127.98,41.89 128.62,42.52 128.62,49 129.97,50.35 129.97,52.62 131.57,54.23 131.57,57.08 v2(131.73,57.23)
  BOTTOM w0.102: v2(40.67,43.84) 40.48,44.03 40.15,44.03 33.66,50.52 33.66,70.51 34.66,71.52 34.91,71.52 v2(35.09,71.69) ; UC1.V3 127.38,60.9 127.38,59.46 127.66,59.19 128.08,59.19 128.53,58.74 129.49,58.74 130.43,57.81 131.29,57.81 131.51,57.59 131.51,57.45 v2(131.73,57.23) 131.55,57.06 131.55,56.44 131.69,56.3 RPC3.4 ; v2(108.3,128.01) 108.3,128.36 107.77,128.9 106.07,128.9 105.67,128.5 Q11.6
SNB_VCCSA: length 1.7
  TOP w0.102: PRA02.2 v1(160.49,60.3)
SNUB_+1VALW: length 1.6
  TOP w0.102: PRH07.2 v1(165.96,57.23)
SOC_XDP_TDI: length 17.8
  TOP w0.102: v2(144.43,97.02) 144.31,97.15 RC141.1 145.4,97.65 TPC5.1
  IN2 w0.127: v2(144.43,97.02) 144.43,96.8 143.38,95.74 143.38,92.26 143.09,91.97 v2(143.09,91.75)
  BOTTOM w0.076: UC1.D60 134.92,93.18 UC1.D59 135.15,92.48 135.22,92.48 135.59,92.48 135.59,92.48 135.6,92.48 135.76,92.43 136.76,92.43 137.06,92.73 138.97,92.73 139.79,91.91 141.68,91.91 141.83,91.75 142.31,91.75
  BOTTOM w0.102: 142.31,91.75 v2(143.09,91.75)
SOC_XDP_TDO: length 9.2
  IN2 w0.127: v2(137.49,91.18) v2(137.49,93.85)
  BOTTOM w0.076: v2(137.49,93.85) 137.36,93.98 UC1.A61 ; UC1.A56 136.63,91.41 136.96,91.41 137.19,91.18 v2(137.49,91.18)
  BOTTOM w0.102: RC142.1 140.48,90.52 140.46,90.54 TPC1.1 139.88,91.43 137.83,91.43 137.59,91.18 v2(137.49,91.18)
SOC_XDP_TMS: length 7.6
  BOTTOM w0.076: TPC4.1 139.7,92.24 139.04,92.9 136.99,92.9 136.7,92.6 135.79,92.6 135.63,92.65 135.62,92.65 135.62,92.65 135.29,92.65 135.25,92.7 UC1.C59 135.25,93.09 UC1.C60
  BOTTOM w0.102: TPC4.1 141.11,92.24 141.4,92.53 RC140.1
SOC_XDP_TRST#: length 4.6
  BOTTOM w0.076: TPC6.1 137.69,94.5 137.46,94.27 136.91,94.27 136.89,94.29 136.77,94.41 136.4,94.41 136.37,94.4 136.31,94.38 135.64,94.38 UC1.C61 135.5,93.73 135.65,93.73 135.9,93.49 UC1.B59
SPKR: length 128.5
  TOP w0.102: v1(30.77,28.82) v2(30.2,28.82) 28.44,27.06 28.44,26.63 27.96,26.14 DA3.3
  IN1 w0.127: v2(103.45,26.76) 102.13,25.44 100.14,25.44 99.87,25.18 57.92,25.18 54.82,28.28 53.23,28.28 50.22,31.29 39.41,31.29 36.94,28.82 v2(30.2,28.82)
  BOTTOM w0.076: 111.86,61.57 113.29,63.01 114.73,63.01 114.78,63.06 116.31,63.06 116.49,62.88 116.49,62.29 UC1.AW5
  BOTTOM w0.102: v2(103.45,26.76) 103.45,33.87 102.27,35.05 102.27,38.95 101.93,39.29 101.93,42.55 102.8,43.42 102.8,48.3 103.81,49.31 103.81,51.37 107.27,54.83 107.27,55.13 107.56,55.43 107.56,57.78 108.39,58.61 109.32,58.61 109.62,58.9 RC128.2 110.28,59.08 110.55,59.35 110.55,59.76 110.52,59.78 110.52,60.24 111.86,61.57
SRTCRST#: length 56
  IN2 w0.127: v2(90.5,48.64) 91,48.13 93.16,48.13 94.08,49.05 95.85,49.05 96.45,49.65 97.19,49.65 98.24,50.7 102.59,50.7 105.44,53.55 105.44,53.96 108.11,56.63 108.11,56.92 108.99,57.8 109.46,57.8 110.8,59.14 111.33,59.14 111.72,59.53 111.72,60.14 116.02,64.44 116.02,65.36 117.47,66.82 120.45,66.82 120.77,67.14 120.77,67.85 120.96,68.04 120.96,68.48 120.79,68.66 120.32,68.66 119.92,69.06 v2(119.92,69.11)
  BOTTOM w0.102: CC4.1 86.29,39.02 RC77.1 86.29,41.11 88.29,43.1 89.43,43.1 89.53,43.2 89.53,47.39 90.5,48.36 v2(90.5,48.64) ; v2(119.92,69.11) UC1.AN18
SSD_DEVSLP: length 146
  TOP w0.102: v2(130.53,25.4) 129.86,26.06 v1(129.86,30.01) 129.86,38.64 v2(129.45,39.05)
  IN1 w0.127: v2(31.85,27.63) 32.67,27.63 33.42,28.38 36.85,28.38 39.51,31.04 50.11,31.04 53.13,28.02 54.71,28.02 57.81,24.92 99.97,24.92 100.24,25.19 113.61,25.19 114.7,26.28 115.87,26.28 117.47,24.68 129.81,24.68 v2(130.53,25.4)
  IN2 w0.127: v2(131.23,58.81) 131.72,58.31 132.79,58.31 133.23,57.87 133.23,56.15 132.3,55.21 132.3,54.23 130.48,52.41 130.48,49.86 129.45,48.83 v2(129.45,39.05)
  BOTTOM w0.076: v2(131.23,58.81) 131.43,59.01 131.43,60.52 131.71,60.8 UC1.J3
  BOTTOM w0.102: JSSD1.38 30.12,27.23 30.51,27.62 31.84,27.62 v2(31.85,27.63)
SUSCLK: length 47.6
  BOTTOM w0.076: 106.49,69.46 106.86,69.83 v1(107.93,69.83) 107.96,69.83 108.33,69.46 109.27,69.46 109.83,68.91 114.14,68.91 UC1.BA17
  BOTTOM w0.102: 106.49,69.46 99.82,62.8 99.82,62.79 96.97,59.94 96.97,52.58 95.7,51.31 95.7,49.41 94.68,48.38 94.68,47.78 94.91,47.54 94.91,45.84 94.22,45.14 94.22,42.71 94.62,42.3 94.62,40.3 95.36,39.57 RC110.1 RC74.2 RC75.2
SUSCLK_EC: length 95.4
  TOP w0.102: RE45.2 v2(35.04,79.08)
  IN2 w0.127: v2(35.04,79.08) 36.79,77.33 46.27,77.33 48.61,74.99 53.43,74.99 54.92,73.5 54.92,54.35 55.41,53.86 55.41,47.4 60.52,42.29 v2(60.52,42.29)
  BOTTOM w0.102: v2(60.52,42.29) 60.55,42.29 61.46,41.38 85.05,41.38 85.19,41.25 85.19,37.84 86.01,37.02 89.12,37.02 90.5,35.64 93.71,35.64 RC75.1
SUSCLK_WLAN: length 113.9
  BOTTOM w0.102: RC74.1 94.01,37.27 93.76,37.52 93.76,38.07 v1(93.44,38.39) 93.44,38.65 93.89,39.1 93.89,39.86 92.81,40.94 92.81,41.84 92.05,42.6 92.05,47.43 92.65,48.03 92.65,49.58 92.02,50.2 92.02,113.86 89.36,116.52 78.85,116.52 75.61,119.76 75.61,121.86 73.8,123.67 73.8,131.76 73.57,131.99 73.57,132.71 72.48,133.8 JWLAN1.50
SYS_PWROK: length 160.1
  TOP w0.102: v2(45.31,65.4) 44.96,65.05 34.8,65.05 34.58,64.83 UE1.28 32.8,64.83 32.05,64.09 32.05,63.07 31.53,62.54 RE68.1 ; v2(107.65,36) v4(108.39,36)
  IN1 w0.127: v2(107.65,36) 107.33,35.68 87.75,35.68 87.01,36.42 61.81,36.42 61.43,36.8 58.06,36.8 49.63,45.24 49.63,47.87 49.18,48.32 49.18,52.45 48.55,53.08 v2(48.55,53.27)
  IN2 w0.127: v2(139.54,56.57) 139.04,56.07 139.04,53.12 141.1,51.06 141.1,47.65 135.13,41.69 135.13,38.69 132.46,36.02 v2(132.46,35.78)
  BOTTOM w0.076: UC1.B6 135.57,61.74 135.86,61.45 135.86,61.15 135.54,60.83 135.54,60.6 135.74,60.4 135.74,59.95 136.14,59.55
  BOTTOM w0.102: v2(48.55,53.27) 48.55,53.97 48.29,54.22 48.29,58.66 46.01,60.95 46.01,64.7 v2(45.31,65.4) ; v2(139.54,56.57) 139.15,56.57 136.18,59.55 136.14,59.55 ; v2(107.65,36) 109.56,36 110.17,35.4 116.78,35.4 117.95,36.57 131.67,36.57 v2(132.46,35.78)
SYS_RESET#: length 6.2
  BOTTOM w0.076: RC86.2 140.51,60.92 TPS1.1 138.74,60.36 136.93,62.17 136.43,62.17 136.12,61.86 UC1.B5
SYSPWR_PRES: length 8.1
  TOP w0.102: RE29.1 RE32.1 v1(40.64,82.32) 40.64,81.84 40.05,81.25 40.05,79.38 39.35,78.68 38.84,78.68 38.4,78.24 UE1.120
T_CRIT#: length 3.5
  BOTTOM w0.102: R29.2 102.36,127.24 v1(102.45,127.14) 102.64,126.96 102.64,126.63 102.35,126.34 102.35,125.91 102.48,125.78 U2.4
THM_SML1_CLK: length 7.9
  BOTTOM w0.102: R49.2 102.85,127.74 103.4,127.2 v1(103.74,127.2) Q11.4 105.17,127.2 105.25,127.12 105.25,125.41 106.59,124.07 106.9,124.07 107.15,123.83 U2.8
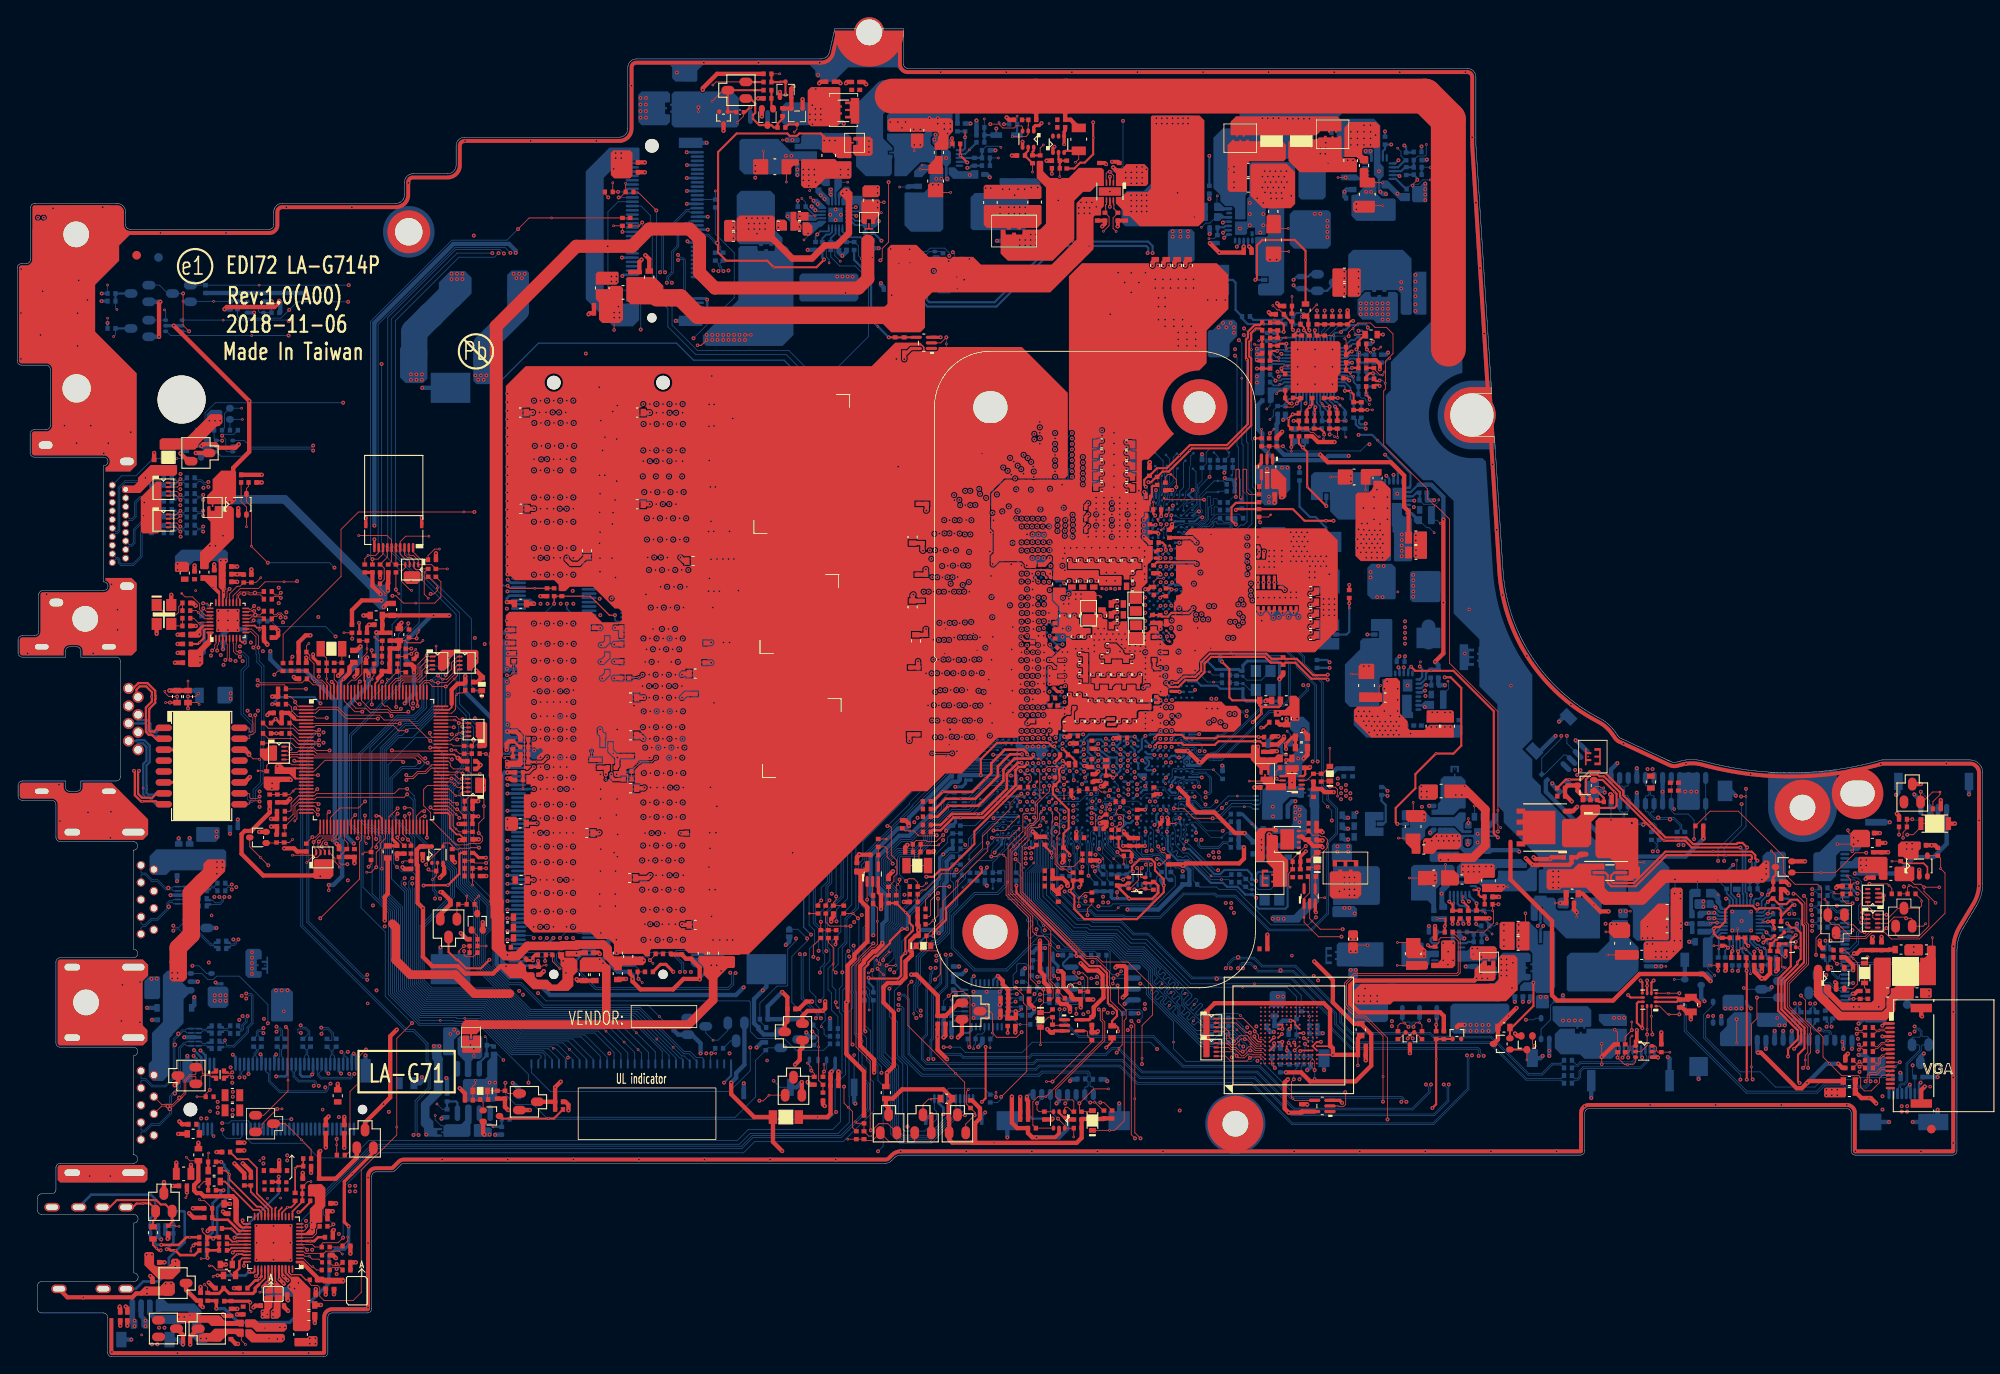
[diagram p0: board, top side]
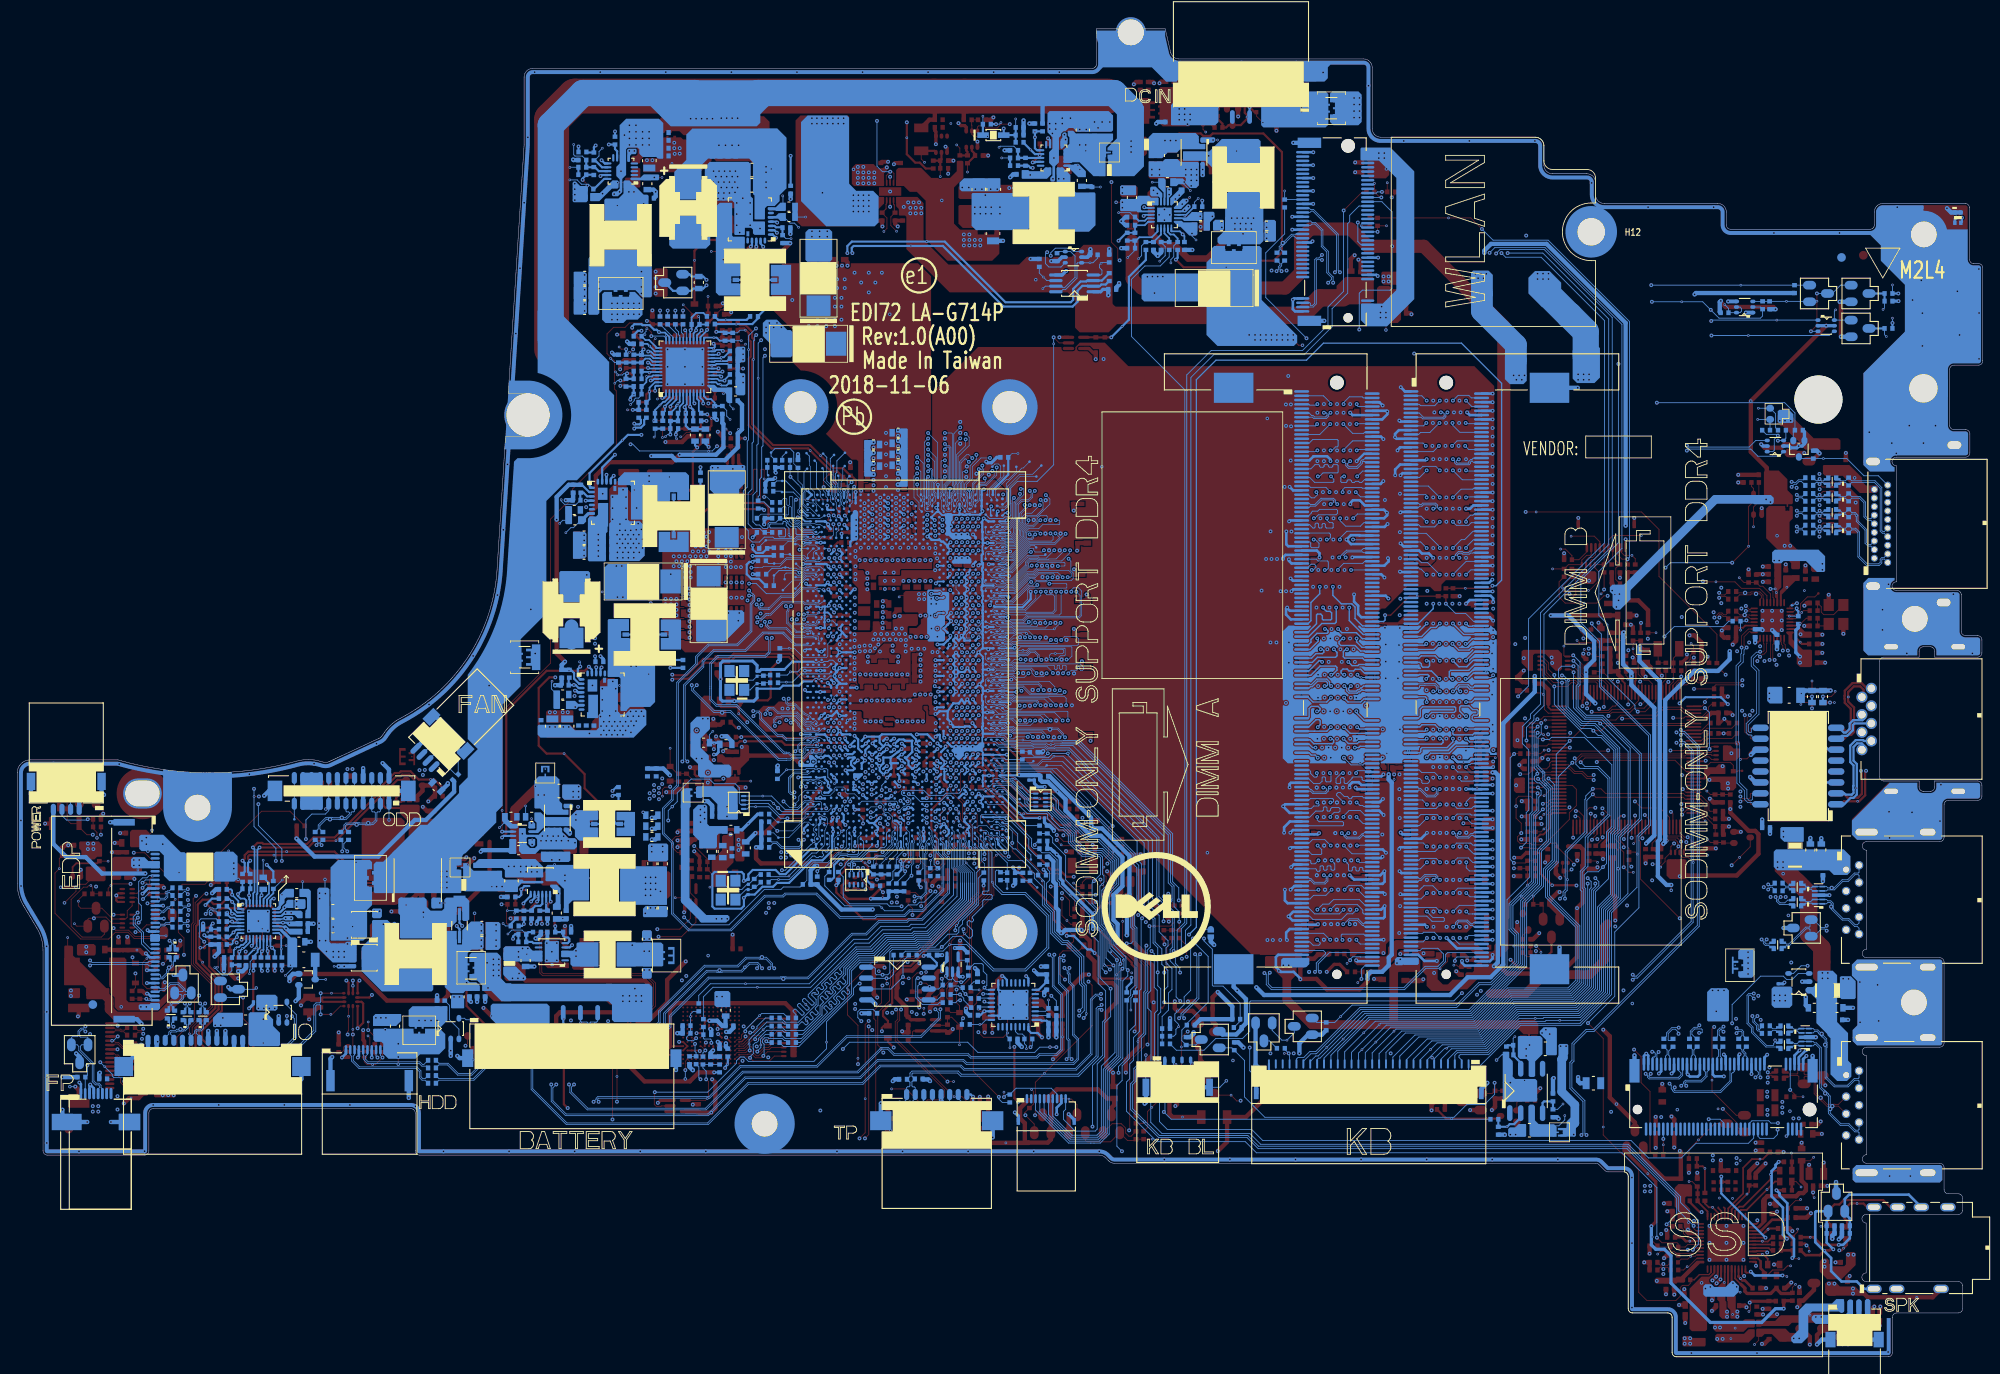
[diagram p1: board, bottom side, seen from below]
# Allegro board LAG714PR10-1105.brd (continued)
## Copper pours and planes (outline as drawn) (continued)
+19VB on TOP (solid shape): 99.41,141.54 99.41,139.89 99.16,139.63 97.38,139.63 97.13,139.89 97.13,140.9 97.7,140.9 97.7,141.41 97.13,141.41 97.13,141.73 97.25,141.85 99.09,141.85
+19VB on TOP (solid shape): 184.44,57.25 184.44,56.64 182.91,56.64 182.91,55.94 184.44,55.94 184.44,55.86 184.44,55.84 184.44,54.99 184.44,54.16 183.63,53.35 183.47,53.35 182.29,54.54 179.47,54.54 179.22,54.29 177.96,54.29 177.71,54.54 177.71,56.45 177.96,56.7 180.76,56.7 181.42,57.37 184.32,57.37
+19VB on BOTTOM (solid shape): 205.52,58.54 205.52,55.37 205.39,55.24 203.17,55.24 202.79,55.62 202.79,58.22 203.3,58.73 205.33,58.73
+19VB on BOTTOM (solid shape): 154.81,148.15 154.81,145.41 152.46,143.06 142.47,143.06 142.44,143.09 142.04,143.48 142.04,144.48 140.65,145.88 140.65,148.16 140.9,148.42 154.54,148.42
+19VB on BOTTOM (solid shape): 100.62,145.41 100.62,141.66 101.71,140.57 101.71,140.26 101.15,140.26 101.15,139.77 101.71,139.77 101.71,139.32 101.64,139.25 101.64,137.55 101.35,137.27 98.6,137.27 97.47,138.39 97.47,145.38 98.14,146.05 99.98,146.05
+19VB on BOTTOM (solid shape): 167.93,121.6 167.93,114.39 164.07,108.94 169.05,104.48 170.27,104.48 170.67,104.08 171.48,91.44 171.91,88.25 172.81,85.16 172.81,85.16 174.21,82.11 176.05,79.31 176.06,79.3 176.06,71.83 174.88,70.66 176.06,69.48 176.06,67.37 177.06,66.37 177.06,65.55 177.12,65.49 177.12,65.48 180.7,61.91 180.7,61.91 180.76,61.86 181.57,61.86 185.87,57.56 186.69,57.56 186.98,57.27 186.98,54.03 186.85,53.91 177.26,53.91 177.26,53.91 176.87,53.91 176.79,53.99 176.79,56.64 177.33,56.64 177.33,57.15 176.75,57.15 176.75,58.1 176.68,58.17 176.68,58.18 176.55,58.41 176.32,58.54 176.31,58.55 172.73,62.12 172.73,63.33 171.99,64.07 171.99,75.86 170.64,77.21 169.9,77.95 169.9,80.08 169.8,80.19 169.8,82.48 169.91,82.59 169.9,82.59 169.9,83.43 166.91,86.42 166.91,99.5 164.5,101.91 163.36,101.91 159.04,106.23 159.04,111.82 159.61,112.39 159.61,115.69 159.63,115.71 159.75,115.8 159.84,115.92 159.84,115.93 165.9,121.98 167.55,121.98
+19VB_1.2V on TOP (solid shape): 93.94,141.85 96.81,141.85 96.94,141.73 96.94,139.44 96.87,139.38 95.35,139.38 94.71,140.01 93.63,140.01 93.51,140.14 93.51,141.96 93.53,141.98 93.81,141.98
+19VB_1.2V on BOTTOM (solid shape): 96.94,141.79 96.94,139.42 96.88,139.37 95.36,139.37 94.71,140.01 93.63,140.01 93.25,140.39 90.39,140.39 90.33,140.46 90.33,140.97 90.39,141.03 90.97,141.03 91.09,141.16 91.09,141.92 91.47,142.3 96.43,142.3
+19VB_+1VALW on TOP (solid shape): 172.94,54.86 172.94,54.48 172.5,54.03 170.28,54.03 170.21,54.1 170.21,54.92 170.28,54.99 172.82,54.99
+19VB_+1VALW on BOTTOM (solid shape): 176.59,57.37 176.59,54.29 176.42,54.12 171.76,54.12 171.67,54.03 170.28,54.03 170.21,54.1 170.21,54.61 169.76,55.06 167.34,55.06 167.27,55.13 167.27,55.26 167.34,55.34 169.55,55.34 169.71,55.49 171.8,55.49 172.06,55.75 172.06,56.45 172.12,56.51 175.36,56.51 176.25,57.4 176.56,57.4
+19VB_CPU on TOP (solid shape): 166.95,74.98 166.95,73.8 166.9,73.74 163.8,73.74 163.76,73.78 163.76,75.07 163.87,75.18 166.75,75.18
+19VB_CPU on BOTTOM (solid shape): 160.92,97.92 161.13,97.7 161.83,97.7 162.09,97.45 162.09,92.62 161.96,92.49 160.08,92.49 159.99,92.58 159.99,95.74 159.8,95.93 159.8,99.23 160.92,99.23
+19VB_CPU on TOP: 159.23,92.37 159.99,93.13 159.99,96.01 160.18,96.2 161.27,96.2 161.44,96.36 161.87,96.36 162.09,96.15 162.09,92.18 161.83,91.93 161.83,82.86 161.51,82.55 159.67,82.55 159.23,82.99
+19VB_CPU on BOTTOM: 167.29,68.26 166.79,68.26 166.79,67.69 166.21,67.69 165.9,68 165.9,69.34 168.31,71.75 168.31,73.38 168.04,73.66 164.01,73.66 163.45,73.1 161.1,73.1 160.97,73.22 160.97,76.93 160.98,76.94 162.12,76.94 162.13,76.93 162.13,75.56 162.28,75.42 163.08,75.42 163.32,75.18 166.48,75.18 166.79,75.48 166.79,80.5 165.43,81.85 161.82,81.85 160.82,82.85 160.82,85.53 161.05,85.77 167.1,85.77 169.55,83.32 169.55,82.5 169.66,82.39 169.66,80.31 169.52,80.17 169.52,77.48 171.55,75.45 171.55,70.48 168.75,67.69 167.29,67.69
+VCC_CORE on TOP (solid shape): outline of 3017 points within 119.64,76.08 153.45,96.32
+VCC_CORE on BOTTOM: 119.92,79.46 119.92,79.75 119.72,79.95 119.72,80.13 119.84,80.25 119.84,80.35 119.91,80.59 119.76,80.79 119.75,80.8 119.68,80.88 119.68,81.08 119.92,81.31 119.92,81.43 120.99,82.51 122.56,82.51 122.64,82.43 122.64,78.27 122.47,78.09 121.02,78.09 120.55,77.62 120.21,77.62 119.73,78.1 119.73,78.45 119.72,78.46 119.72,79.26
+VCC_CORE on BOTTOM: 132.62,76.75 132.57,76.71 132.33,76.71 131.86,77.19 130.26,77.19 130.15,77.31 130.15,84.15 130.35,84.35 131.07,84.35 131.08,84.35 131.7,84.35 131.83,84.22 131.83,83.91 131.78,83.75 131.82,83.59 131.83,83.58 131.83,83.5 131.84,83.48 131.95,83.48 131.95,83.48 132.06,83.46 132.17,83.48 132.18,83.49 132.47,83.49 132.55,83.44 132.64,83.41 132.66,83.41 132.94,83.13 132.98,83.08 133.1,82.97 133.1,77.22
+VCC_CORE on BOTTOM: 151.68,94.88 152.56,94.88 152.56,96.07 152.82,96.32 153.83,96.32 154.21,95.94 154.21,84.77 153.83,84.39 152.69,84.39 152.69,83.56 153.64,83.56 153.83,83.37 153.83,82.37 153.51,82.05 151.3,82.05 149.7,83.65 149.7,86.36 149.01,87.05 144.75,87.05 143.93,87.88 143.93,95.94 144.81,96.83 151.16,96.83 151.68,96.32
+VCC_CORE on VCC: 122.59,76.13 122.59,76.87 121.42,78.04 119.77,78.04 119.67,78.14 119.67,83.9 120.18,84.41 120.18,88.45 136.66,88.45 137.83,89.62 137.83,96.09 138.06,96.32 150.04,96.32 153.45,92.92 153.45,76.13
+VCC_CORE on IN1: outline of 195 points within 119.64,75.78 153.41,96.32
+VCC_CORE_42 on TOP (solid shape): 121.83,89.42 121.83,88.82 121.82,88.73 121.82,88.66 121.78,88.57 121.68,88.56 121.25,88.47 121.23,88.03 121.65,87.9 121.87,88.29 121.92,88.38 122.02,88.39 122.43,88.47 122.49,88.88 122.49,88.98 122.57,89.03 125.18,89.03 125.41,88.8 125.41,86.73 125.24,86.56 123.77,86.56 123.67,86.46 123.67,86.43 123.67,86.05 123.56,85.94 123.32,85.94 123.22,86.05 123.22,86.11 123.22,86.24 123.22,86.33 123.02,86.53 122.71,86.53 122.52,86.44 122.49,86.24 122.3,85.96 122.04,86.17 122.04,86.24 122.01,86.44 121.82,86.53 121.68,86.54 121.61,86.53 121.17,86.53 121.1,86.61 121.1,87.21 120.35,87.96 120.35,89.39 120.41,89.44 121.8,89.44
+VCC_CORE_42 on BOTTOM (solid shape): outline of 287 points within 120.1,83.15 122.67,89.21
+VCC_CORE_42 on IN2: 121.29,83.47 122.13,83.47 122.29,83.63 122.29,84.09 124.02,85.81 124.02,88.88 123.85,89.05 122.69,89.05 122.56,88.92 122.56,88.51 122.41,88.36 122.1,88.36 121.57,87.82 121.12,87.82 120.91,87.61 120.91,83.85
+VCC_GT on TOP (solid shape): outline of 3785 points within 113.13,87.57 140.75,127.15
+VCC_GT on BOTTOM: outline of 192 points within 119.51,89.07 141,127.5
+VCC_GT on VCC: 120.18,88.96 120.18,99.27 122.34,101.43 122.34,126.8 140.9,126.8 144.31,123.4 144.31,96.83 136.14,96.83 134.53,95.22 134.53,89.64 133.85,88.96
+VCC_GT on IN1: outline of 116 points within 120.33,88.79 141.67,127.19
+VCC_GT_42 on TOP: 130.67,87.31 129.28,87.31 129.14,87.45 129.14,87.94 129.1,87.97 128.21,87.97 128.2,87.96 128.2,87.66 128.01,87.47 127.66,87.47 127.57,87.39 127.57,85.77 127.64,85.71 129.09,85.71 129.2,85.6 129.2,84.59 129.32,84.46 131.23,84.46 131.42,84.64 131.42,86.74 132.34,87.66 132.34,88.85 131.05,88.85 130.84,88.64 130.84,87.47
+VCC_GT_42 on BOTTOM: 132.15,89.43 132.26,89.32 132.26,84.58 132.17,84.49 130.31,84.49 130.16,84.64 130.16,89.37 130.23,89.43
+VCC_GT_42 on IN1: 136.84,90.13 134.75,90.13 134.5,89.88 133.42,89.88 133.16,89.62 133.16,88.1 133.03,87.97 132.21,87.97 131.64,88.55 130.43,88.55 129.54,87.66 127.89,87.66 127.7,87.47 127.7,85.81 127.89,85.62 129.73,85.62 130.88,84.48 131.22,84.48 132.53,85.79 134.47,85.79 135.54,86.86 137.13,86.86 137.23,86.96 137.23,89.75
+VCC_SA on TOP (solid shape): outline of 768 points within 121.48,72.67 142.21,76.2
+VCC_SA on BOTTOM: 130.39,72.61 130.15,72.84 130.15,76.89 130.33,77.06 131.71,77.06 133.08,75.69 133.08,73.56 132.13,72.61
+VCC_SA on BOTTOM: 157.7,67.05 157.7,64.68 158.78,63.61 158.78,62.4 157.83,62.4 157.83,61.51 158.72,61.51 158.72,60.56 158.47,60.3 157.13,60.3 156.77,59.94 154.59,59.94 154.4,60.13 154.4,63.75 153.58,64.57 153.58,65.97 153.07,66.48 153.07,67.43 153.39,67.75 157.01,67.75
+VCC_SA on BOTTOM: 121.05,74.18 121.17,74.31 121.93,74.31 122.06,74.18 122.06,72.78 121.84,72.57 121.3,72.57 121.05,72.82
+VCC_SA on VCC: 151.78,64.45 147.71,68.51 132.6,68.51 130.19,70.92 120.94,70.92 120.94,74.12 122.44,75.62 153.45,75.62 153.45,72.85 155.1,71.2 155.1,64.45
GND on TOP (solid shape): 11.1,108.9 4.06,108.9 4.06,115.65 11.1,115.65
GND on TOP (solid shape): 94.89,82.37 86.89,82.37 86.89,90.37 94.89,90.37
GND on TOP (solid shape): 95.17,67.94 87.17,67.94 87.17,75.94 95.17,75.94
GND on TOP (solid shape): 96.17,96.32 86.17,96.32 86.17,111.32 96.17,111.32
GND on TOP (solid shape): 10.75,127 3.85,127 3.85,133.89 10.75,133.89
GND on TOP (solid shape): 58.2,62.54 58.2,61.4 57.95,61.15 56.8,61.15 56.68,61.27 56.68,62.67 56.8,62.8 57.95,62.8
GND on TOP (solid shape): 154.47,126.3 154.47,123.5 154.21,123.25 152.94,123.25 152.82,123.38 152.82,126.42 152.94,126.55 154.21,126.55
GND on TOP (solid shape): 165.07,66.42 165.07,65.02 164.82,64.77 163.04,64.77 162.85,64.96 162.85,66.29 163.1,66.54 164.94,66.54
GND on TOP (solid shape): 83.47,132.08 83.47,129.79 83.35,129.66 82.27,129.66 82.14,129.79 82.14,132.01 82.32,132.19 83.36,132.19
GND on TOP (solid shape): 89.44,131.95 89.44,131 89.38,130.93 88.36,130.93 88.17,131.12 88.17,132.08 88.3,132.2 89.19,132.2
GND on TOP (solid shape): 119.03,136.01 119.03,134.78 118.87,134.62 112.37,134.62 112.3,134.68 112.3,136.08 112.49,136.27 118.78,136.27
GND on TOP (solid shape): 155.8,49.44 155.8,48.42 155.72,48.34 154.77,48.34 154.66,48.46 154.66,49.44 154.78,49.57 155.67,49.57
GND on TOP (solid shape): 167.1,48.24 167.1,45.51 166.79,45.19 164.31,45.19 164.31,45.83 165.07,45.83 165.45,46.21 165.45,48.24 165.64,48.43 166.91,48.43
GND on TOP (solid shape): 173.99,50.53 173.99,47.35 173.94,47.3 172.5,47.3 172.25,47.56 172.25,50.35 172.47,50.58 173.94,50.58
GND on TOP (solid shape): 148.5,137.74 148.5,134.04 147.99,133.54 144.74,133.54 143.29,134.98 143.29,138.53 143.51,138.74 147.49,138.74
GND on TOP (solid shape): 163.81,95.92 163.81,92.82 163.79,92.79 162.49,92.79 162.28,93.01 162.28,95.75 162.47,95.94 163.79,95.94
GND on TOP (solid shape): 193.52,54.35 193.52,47.56 192.12,46.16 189.2,46.16 189.01,46.35 189.01,48.13 189.2,48.32 191.93,48.32 192.12,48.51 192.12,54.32 192.34,54.54 193.33,54.54
GND on TOP (solid shape): 100.24,136.08 100.24,135.03 100.02,134.82 98.34,134.82 98.21,134.96 98.21,135.95 98.46,136.2 100.11,136.2
GND on TOP (solid shape): 153.77,117.86 153.77,114.34 153.45,114.02 153.45,112.31 153.23,112.09 148,112.09 147.98,112.11 147.98,118.05 148.01,118.09 153.54,118.09
GND on TOP (solid shape): 95.26,139 96.87,139 96.94,138.93 96.94,137.16 96.74,136.96 93.89,136.96 92.81,135.89 91.41,135.89 91.09,136.2 91.09,139.12 91.22,139.25 95,139.25
GND on TOP (solid shape): 167.8,60.57 167.8,59.37 167.42,58.99 165.07,58.99 164.56,58.48 163.53,58.48 163.36,58.66 163.36,60.08 163.58,60.31 164.3,60.31 164.82,60.83 167.55,60.83
GND on TOP (solid shape): 171.69,57.13 171.69,55.77 171.6,55.68 170.4,55.68 169.71,54.99 168.25,54.99 168.12,55.11 168.12,55.88 167.74,56.26 167.74,57.15 167.93,57.34 171.48,57.34
GND on TOP (solid shape): 66.32,47.18 66.32,46.79 66.23,46.7 65.55,46.7 65.36,46.52 64.78,46.52 64.76,46.54 63.75,46.54 63.7,46.6 63.7,47.15 63.74,47.2 65.21,47.2 65.23,47.22 65.58,47.22 65.63,47.27 66.23,47.27
GND on TOP (solid shape): 146.5,61.37 146.5,61.05 146.43,60.99 146.05,60.99 145.93,61.11 145.23,61.11 144.97,60.86 144.97,57.75 144.81,57.59 144.05,57.59 143.89,57.75 143.89,60.99 144.4,61.49 146.37,61.49
GND on TOP (solid shape): 58.74,68.82 58.49,68.57 57.34,68.57 57.15,68.38 56.83,68.38 56.71,68.51 56.71,69.33 56.77,69.4 57.09,69.4 57.15,69.33 58.04,69.33 58.23,69.52 58.23,70.28 58.74,70.28
GND on TOP (solid shape): 148.92,68.77 148.92,68.17 148.59,67.84 148.59,66 147.7,66 147.7,67.34 147.64,67.4 146.75,67.4 146.69,67.46 146.69,67.59 146.75,67.65 147.26,67.65 147.37,67.76 147.37,68.75 147.4,68.79 148.89,68.79
GND on TOP (solid shape): 159.61,100.9 159.61,93.16 158.96,92.51 156.12,92.51 155.51,93.12 155.51,100.23 155.77,100.5 157.07,100.5 157.58,101.01 157.58,101.79 157.64,101.85 158.66,101.85
GND on TOP (solid shape): 15.13,21.85 15.13,20.59 14.8,20.26 4.99,20.26 4.7,20.55 4.7,22 4.79,22.21 5,22.3 14.69,22.3
GND on TOP (solid shape): 32.03,67.17 32.03,66.93 31.93,66.83 30.61,66.83 30.48,66.7 30.48,66 30.31,65.83 29,65.83 28.64,66.19 28.64,67.41 28.7,67.46 31.74,67.46
GND on TOP (solid shape): 158.34,143.12 158.34,140.71 158.19,140.57 156.48,140.57 156.31,140.39 156.31,139.82 156.5,139.63 156.88,139.63 157.01,139.5 157.01,138.87 156.88,138.74 156.12,138.74 155.99,138.87 155.99,139.12 155.61,139.5 154.25,139.5 154.21,139.54 154.21,142.93 154.85,143.57 157.9,143.57
GND on TOP (solid shape): 160.69,78.54 160.69,74.78 161.58,73.89 161.58,73.13 161.83,72.88 163.48,72.88 164.08,73.48 166.67,73.48 166.92,73.22 166.92,72.04 166.87,71.99 157.34,71.99 155.36,73.97 155.36,75.24 155.74,75.62 158.28,75.62 158.72,76.07 158.72,78.61 159.04,78.93 160.31,78.93
GND on TOP (solid shape): 15.21,45.59 15.21,44.32 14.58,43.68 14.58,38.54 15.13,37.99 15.13,36.72 14.61,36.2 5,36.2 4.79,36.29 4.7,36.5 4.7,45.9 4.79,46.11 5,46.2 14.6,46.2
GND on TOP (solid shape): 108.75,143.7 108.75,142.49 108.24,141.98 108.24,140.52 108.05,140.33 106.65,140.33 106.59,140.39 106.59,141.03 106.97,141.41 106.97,141.84 107.01,142.29 106.59,142.43 101.44,142.43 101.13,142.74 101.13,143.76 101.38,144.01 108.43,144.01
GND on TOP (solid shape): 128.53,82.1 128.53,81.87 128.74,81.65 129.67,81.65 129.79,81.53 129.79,81.33 129.64,81.18 129.24,81.18 129.16,81.1 129.16,80.67 128.53,80.67 128.53,81.05 128.37,81.21 127.16,81.21 127.07,81.12 127.07,80.67 126.43,80.67 126.43,81.11 126.36,81.18 125.94,81.18 125.8,81.31 125.8,81.53 125.93,81.66 126.78,81.66 127.07,81.94 127.07,82.36 126.98,82.45 126.56,82.45 126.43,82.57 126.43,82.8 126.57,82.93 127.69,82.93
GND on TOP (solid shape): 5,41.25 8.07,44.2 13,44.2 13,38.2 7.96,38.2
GND on TOP (solid shape): 171.34,112 171.66,107 171.7,106.25 169.05,106.25 165.8,109.5 169.05,112.75 171.29,112.75
GND on TOP (solid shape): 5.4,66.25 5.6,65.75 6.1,65.55 6.9,65.55 7.4,65.75 7.6,66.25 7.6,66.75 10.97,66.75 15.21,62.5 15.21,60.7 14.61,60.1 5,60.1 4.79,60.19 4.7,60.4 4.7,64.2 4.5,64.7 4,64.9 0.6,64.9 0.39,64.99 0.3,65.2 0.3,66.45 0.39,66.66 0.6,66.75 5.4,66.75
GND on TOP (solid shape): 123.43,81.88 123.92,81.88 124.01,81.79 124.44,81.79 124.44,81.02 124.44,80.89 124.44,80.89 124.44,79.07 124.44,79.07 124.44,78.94 124.44,78.41 123.85,78.41 123.85,78.83 123.76,78.93 123.42,78.93 123.23,79.14 123.43,79.34 123.85,79.34 123.85,80.1 123.76,80.2 123.43,80.2 123.23,80.4 123.43,80.61 123.85,80.61 123.85,81.37 123.76,81.47 123.43,81.47 123.23,81.67 123.42,81.88
GND on TOP (solid shape): 13.88,89.97 13.88,82.1 13.33,81.55 7.6,81.55 7.6,82.05 7.4,82.55 6.9,82.75 6.1,82.75 5.6,82.55 5.4,82.05 5.4,81.55 0.6,81.55 0.39,81.64 0.3,81.85 0.3,83.35 0.39,83.56 0.6,83.65 2,83.65 2.5,83.85 2.7,84.35 2.7,88.6 2.79,88.81 3,88.9 10.05,88.9 10.75,89.5 10.25,90.27 10.25,90.55 13.3,90.55
GND on TOP (solid shape): 130.23,79.34 130.46,79.57 130.68,79.34 130.68,78.37 130.48,78.16 130.48,77.64 130.45,77.61 130.12,77.61 130.09,77.64 130.09,78.15 129.95,78.28 128.91,78.28 128.83,78.2 128.83,77.64 128.79,77.61 128.49,77.61 128.48,77.62 128.43,77.62 128.42,77.64 128.42,77.68 128.42,77.69 128.42,78.22 128.36,78.28 127.6,78.28 127.21,77.89 127.21,77.65 126.87,77.65 126.87,78.28 125.68,78.28 125.68,77.65 125.64,77.61 125.28,77.61 125.23,77.66 125.23,78.27 125.16,78.34 124.86,78.34 124.86,78.92 125.28,78.92 125.38,79.02 125.38,79.34 125.58,79.54 125.78,79.34 125.78,78.92 126.5,78.92 126.6,79.02 126.6,79.34 126.8,79.54 127,79.34 127,78.92 127.72,78.92 127.82,79.02 127.82,79.34 128.02,79.54 128.22,79.34 128.22,78.92 128.94,78.92 129.04,79.02 129.04,79.34 129.24,79.54 129.44,79.34 129.44,78.94 129.97,78.94 130.23,79.2
GND on TOP (solid shape): outline of 146 points within 120.29,83.47 124.72,86.41
GND on TOP (solid shape): outline of 238 points within 0.2,102.93 13.88,133.9
GND on TOP (solid shape): 130.17,92.74 130.16,92.71 130.16,92.56 130.22,92.42 130.35,92.3 130.52,92.27 130.6,92.23 130.62,92.17 130.62,91.59 130.04,91.59 129.85,91.4 129.85,91.04 129.71,90.91 129.31,90.91 129.22,90.83 129.22,90.39 128.59,90.39 128.59,90.75 128.41,90.92 125.86,90.92 125.82,90.96 125.82,91.47 125.7,91.59 122.11,91.59 122.08,91.62 122.08,92.4 122.02,92.47 122.02,92.72 122.15,92.85 122.45,92.85 122.53,92.81 122.55,92.72 122.89,92.27 123.23,92.72 123.25,92.81 123.33,92.85 123.72,92.85 123.8,92.81 123.82,92.72 124.16,92.27 124.5,92.72 124.52,92.81 124.6,92.85 124.99,92.85 125.07,92.81 125.09,92.72 125.43,92.27 125.77,92.72 125.79,92.81 125.87,92.85 126.26,92.85 126.34,92.81 126.36,92.72 126.7,92.27 127.04,92.72 127.06,92.81 127.14,92.85 127.53,92.85 127.61,92.81 127.63,92.72 127.97,92.27 128.31,92.72 128.33,92.81 128.41,92.85 128.8,92.85 128.88,92.81 128.9,92.72 129.24,92.27 129.58,92.72 129.6,92.81 129.68,92.85 129.84,92.85 129.85,92.86 130.05,92.86
GND on TOP (solid shape): outline of 230 points within 6.89,0.2 228.2,154.2
GND on TOP (solid shape): outline of 19872 points within 56.77,46.57 131.82,117.91
GND on BOTTOM (solid shape): 16.61,44.13 16.61,41.78 16.42,41.59 14.91,41.59 14.77,41.73 14.77,43.68 15.34,44.25 16.48,44.25
GND on BOTTOM (solid shape): 23.53,61.46 23.53,60.32 23.08,59.88 20.86,59.88 20.8,59.94 20.8,61.53 20.86,61.59 23.4,61.59
GND on BOTTOM (solid shape): 155.1,59.49 155.1,57.72 154.97,57.59 152.94,57.59 152.75,57.78 152.75,59.49 152.94,59.69 154.91,59.69
GND on BOTTOM (solid shape): 173.96,47.3 172.5,47.3 172.25,47.56 172.25,50.35 172.44,50.54 173.96,50.54
GND on BOTTOM (solid shape): 177.99,41.97 177.99,40.57 177.92,40.51 176.53,40.51 176.46,40.57 176.46,41.91 176.65,42.1 177.86,42.1
GND on BOTTOM (solid shape): 205.65,39.43 205.65,38.48 205.52,38.35 202.35,38.35 202.15,38.54 202.15,39.94 202.22,40 205.08,40
GND on BOTTOM (solid shape): 25.05,77.78 25.05,76.26 24.75,75.95 23.36,75.95 23.27,76.05 23.27,77.78 23.4,77.91 24.93,77.91
GND on BOTTOM (solid shape): 155.8,49.44 155.8,48.49 155.67,48.37 154.78,48.37 154.66,48.49 154.66,49.44 154.78,49.57 155.67,49.57
GND on BOTTOM (solid shape): 32.04,42.41 32.04,39.11 31.91,38.98 29.6,38.98 29.5,39.09 29.5,42.6 29.75,42.86 31.59,42.86
GND on BOTTOM (solid shape): 83.47,132.08 83.47,129.79 83.35,129.66 82.27,129.66 82.14,129.79 82.14,132.01 82.32,132.19 83.36,132.19
GND on BOTTOM (solid shape): 89.44,131.95 89.44,131 89.38,130.93 88.36,130.93 88.17,131.12 88.17,132.08 88.3,132.2 89.19,132.2
GND on BOTTOM (solid shape): 118.91,136.52 118.91,135.76 118.65,135.5 114.4,135.5 114.14,135.76 114.14,136.96 114.21,137.03 118.4,137.03
GND on BOTTOM (solid shape): 152.64,133.01 152.64,129.25 152.23,128.84 148.37,128.84 147.86,129.34 147.86,132.85 148.31,133.3 152.35,133.3
GND on BOTTOM (solid shape): 155.8,45.06 155.8,44.11 155.67,43.98 154.78,43.98 154.66,44.11 154.66,45.06 154.8,45.21 155.66,45.21
GND on BOTTOM (solid shape): 160.18,91.75 160.18,88.2 160.05,88.07 157.39,88.07 156.88,88.58 156.88,91.75 157.32,92.2 159.74,92.2
GND on BOTTOM (solid shape): 165.07,66.44 165.07,65.02 164.82,64.77 163.04,64.77 162.85,64.96 162.85,66.29 163.1,66.54 164.97,66.54
GND on BOTTOM (solid shape): 173.39,40.83 173.39,39.37 171.59,37.57 166.91,37.57 166.53,37.95 166.53,40.75 166.85,41.06 173.15,41.06
GND on BOTTOM (solid shape): 51.49,37.86 51.49,37.59 50.76,36.86 50.76,35.17 50.66,35.06 49.59,35.06 49.49,35.16 49.49,38.18 49.63,38.32 51.03,38.32
GND on BOTTOM (solid shape): 97.75,125.73 97.75,123.01 97.45,122.7 91.11,122.7 90.89,122.92 90.89,125.66 91.18,125.95 97.53,125.95
GND on BOTTOM (solid shape): 100.24,136.08 100.24,135.19 100.11,135.06 98.47,135.06 98.37,135.16 98.37,136.1 98.47,136.2 100.11,136.2
GND on BOTTOM (solid shape): 149.51,86.29 149.51,83.23 149.45,83.17 146.16,83.17 143.93,85.4 143.93,86.55 144.18,86.8 149.01,86.8
GND on BOTTOM (solid shape): 163.86,136.52 163.86,134.36 163.74,134.23 162.26,134.23 162.09,134.41 162.09,136.08 162.14,136.12 162.99,136.12 163.51,136.65 163.74,136.65
GND on BOTTOM (solid shape): 136.81,130.74 136.81,127.52 136.61,127.31 133.96,127.31 133.7,127.57 133.7,130.81 134.02,131.12 136.43,131.12
GND on BOTTOM (solid shape): 54.31,26.68 54.95,26.68 55.15,26.47 55.15,25.72 55.01,25.57 53.16,25.57 53.06,25.68 53.06,27 53.12,27.06 53.93,27.06
GND on BOTTOM (solid shape): 155.69,52.1 155.69,51.22 155.58,51.11 152.94,51.11 152.82,51.24 152.82,52.26 152.98,52.42 155.37,52.42
GND on BOTTOM (solid shape): 163.83,95.89 163.83,92.83 163.79,92.79 162.52,92.79 162.25,93.06 162.25,95.71 162.47,95.93 163.79,95.93
GND on BOTTOM (solid shape): 165.39,91.23 165.39,87.93 165.2,87.74 162.15,87.74 161.83,88.05 161.83,91.16 162.02,91.35 165.27,91.35
GND on BOTTOM (solid shape): 187.05,39.59 187.05,38.49 187.03,38.46 184.37,38.46 183.78,39.06 183.78,39.83 183.8,39.86 186.79,39.86
GND on BOTTOM (solid shape): 75.85,146.87 75.85,145.85 75.28,145.85 75.28,144.46 75.85,144.46 75.85,143.57 75.47,143.19 72.55,143.19 72.17,143.57 72.17,146.74 72.55,147.12 75.6,147.12
GND on BOTTOM (solid shape): 163.74,126.12 163.74,121.24 163.66,121.17 162.45,121.17 162.21,121.41 162.21,125.92 162.47,126.17 163.69,126.17
GND on BOTTOM (solid shape): 193.52,54.35 193.52,47.62 191.74,45.84 189.07,45.84 188.95,45.97 188.95,48 189.2,48.26 190.15,48.26 190.34,48.06 191.93,48.06 192.12,48.26 192.12,54.35 192.31,54.54 193.33,54.54
GND on BOTTOM (solid shape): 90.53,133.09 90.53,130.97 90.5,130.93 89.86,130.93 89.8,131 89.8,131.93 89.27,132.46 89.27,133 89.39,133.13 90.49,133.13
GND on BOTTOM (solid shape): 141.77,120.2 141.77,118.68 140.88,117.79 140.88,116.39 140.69,116.2 138.51,116.2 138.34,116.38 138.34,119.18 138.53,119.38 138.91,119.38 140.12,120.58 141.39,120.58
GND on BOTTOM (solid shape): 144.94,117.26 144.94,111.99 144.75,111.8 143.93,111.8 143.8,111.93 143.8,114.23 143.93,114.36 144.31,114.36 144.43,114.49 144.43,115.5 144.31,115.63 143.93,115.63 143.8,115.76 143.8,117.33 143.93,117.45 144.75,117.45
GND on BOTTOM (solid shape): 147.93,103.5 147.93,100.83 147.42,100.33 146.66,100.33 146.47,100.13 146.47,99.25 146.21,98.99 144.94,98.99 144.5,99.44 144.5,100.9 143.8,101.6 143.8,103.56 143.93,103.69 147.74,103.69
GND on BOTTOM (solid shape): 15.13,21.85 15.13,20.59 14.8,20.26 4.99,20.26 4.7,20.55 4.7,22 4.79,22.21 5,22.3 14.69,22.3
GND on BOTTOM (solid shape): 158.53,100.18 159.42,100.18 159.42,97.07 159.61,96.88 159.61,92.58 159.55,92.51 156.12,92.51 155.48,93.15 155.48,96.58 156.05,97.15 156.5,97.15 156.5,97.15 157.28,97.15 157.45,97.32 157.45,101.01 158.53,101.01
GND on BOTTOM (solid shape): 175.17,57.46 175.36,57.46 175.42,57.4 175.42,56.89 175.36,56.83 171.99,56.83 171.74,56.57 171.74,55.81 171.66,55.73 167.35,55.73 167.28,55.8 167.28,56.98 168.18,57.88 174.75,57.88
GND on BOTTOM (solid shape): 55.79,35.43 55.79,35.25 55.88,35.16 55.88,35.09 55.86,35.07 55.83,35.07 55.79,35.03 55.79,29.94 55.5,29.65 51.9,29.65 51.78,29.77 51.78,32.09 51.99,32.3 54.34,32.3 54.63,32.6 54.63,34.38 55.03,34.78 55.03,35.43 55.08,35.48 55.74,35.48
GND on BOTTOM (solid shape): 93.12,133.28 93.95,133.28 93.99,133.24 93.99,133.1 93.95,133.07 92.61,133.07 92.06,133.61 92.06,133.83 92.21,133.98 92.42,133.98
GND on BOTTOM (solid shape): 95.3,138.98 96.9,138.98 96.94,138.95 96.94,137.28 96.82,137.17 92.76,137.17 92.6,137.02 92.6,136.38 92.15,135.93 92.12,135.91 92.08,135.89 91.41,135.89 91.09,136.2 91.09,138.81 91.22,138.93 93.25,138.93 93.57,139.25 95.03,139.25
GND on BOTTOM (solid shape): 148.5,138.36 148.5,134.55 148.37,134.42 145.32,134.42 145.07,134.17 145.07,130.49 143.86,130.49 143.86,131.31 143.16,131.31 142.91,131.06 142.91,130.61 142.74,130.45 141.54,130.45 141.51,130.48 141.51,131.96 141.56,132.01 142.87,132.01 142.91,132.05 142.91,134.68 143.16,134.93 143.16,138.68 143.42,138.93 147.93,138.93
GND on BOTTOM (solid shape): 108.68,144.58 108.68,142.36 108.11,141.79 108.11,140.46 108.49,140.08 108.49,138.81 108.11,138.43 108.11,137.35 108.37,137.09 108.37,136.77 108.24,136.65 107.92,136.65 107.79,136.77 107.79,138.43 107.35,138.87 107.35,141.73 107.1,141.98 107.1,142.22 106.83,142.49 106.59,142.49 106.21,142.87 105.7,142.87 105.25,142.43 101.25,142.43 101.06,142.62 101.06,144.33 101.57,144.84 108.43,144.84
GND on BOTTOM (solid shape): 158.4,143.19 158.4,138.74 158.78,138.36 158.78,137.28 158.4,136.9 158.4,135.82 158.72,135.5 159.1,135.5 159.29,135.31 159.29,135.06 159.17,134.93 158.59,134.93 158.09,135.44 158.09,136.96 157.64,137.41 157.64,140.39 157.45,140.58 156.31,140.58 156.12,140.39 156.12,139.89 155.74,139.5 154.15,139.5 153.96,139.31 153.39,139.31 153.32,139.38 153.32,143.44 153.83,143.95 157.64,143.95
GND on BOTTOM (solid shape): 15.21,45.59 15.21,44.32 14.58,43.68 14.58,38.54 15.13,37.99 15.13,36.72 14.61,36.2 5,36.2 4.79,36.29 4.7,36.5 4.7,45.9 4.79,46.11 5,46.2 14.6,46.2
GND on BOTTOM (solid shape): 159.8,78.74 159.8,77.92 159.81,77.91 160.64,77.91 160.65,77.9 160.65,74.82 160.82,74.65 160.82,73.15 161.12,72.84 163.58,72.84 164.23,73.49 167.8,73.49 167.93,73.36 167.93,72.32 167.59,71.99 156.77,71.99 155.29,73.46 155.29,75.12 155.48,75.31 157.17,75.31 157.76,74.72 158.28,74.72 158.61,75.05 158.61,75.05 158.61,78.75 158.63,78.77 159.76,78.77
GND on BOTTOM (solid shape): 167.8,60.7 169.21,60.7 169.21,60.7 169.31,60.8 169.31,61.43 169.36,61.48 170.04,61.48 170.1,61.41 170.1,58.79 169.77,58.46 168.2,58.46 167.67,58.99 163.64,58.99 163.36,59.27 163.36,60.05 163.48,60.18 167.99,60.18 167.99,59.41 168.25,59.16 168.82,59.16 169.2,59.54 169.2,60.3 169.07,60.43 168.25,60.43 167.99,60.18 163.48,60.18 163.61,60.31 164.36,60.31 165.07,61.02 165.07,61.4 165.2,61.53 166.98,61.53
GND on BOTTOM (solid shape): 118.15,93.1 118.33,93.04 118.52,93.1 118.8,93.1 118.98,93.04 119.17,93.1 119.45,93.1 119.47,93.08 119.53,93.05 119.57,93.02 119.57,92.73 119.81,92.48 119.81,92.35 119.66,92.2 117.65,92.2 117.52,92.34 117.52,92.77 117.81,93.07 117.87,93.1
GND on BOTTOM (solid shape): 131.31,98.28 131.31,98.06 131.57,97.8 131.57,95.07 131.38,94.88 130.87,94.88 130.68,95.07 130.68,95.55 130.68,95.56 130.7,95.67 130.68,95.78 130.68,95.79 130.68,96.2 130.68,96.21 130.7,96.32 130.68,96.43 130.68,96.44 130.68,96.85 130.68,96.86 130.7,96.97 130.68,97.08 130.68,97.09 130.68,97.5 130.68,97.51 130.7,97.62 130.68,97.73 130.68,97.74 130.68,98.15 130.7,98.21 130.7,98.26 130.83,98.38 130.89,98.45 131.15,98.45
GND on BOTTOM (solid shape): 129.99,106.54 129.99,102.42 129.89,102.32 128.72,102.32 128.65,102.4 128.65,102.78 128.77,102.9 128.82,102.9 128.89,102.9 128.97,102.9 129.1,102.9 129.23,103.03 129.23,103.48 129.1,103.6 128.75,103.6 128.67,103.68 128.67,103.98 128.79,104.1 129.12,104.1 129.19,104.17 129.19,104.28 129.24,104.56 129.07,104.78 129.02,104.83 128.77,104.83 128.65,104.96 128.65,105.24 128.76,105.35 129.13,105.35 129.19,105.42 129.19,105.52 129.25,105.72 129.19,105.91 129.19,105.98 129.1,106.07 128.96,106.07 128.89,106.07 128.83,106.07 128.76,106.07 128.66,106.17 128.66,106.55 128.71,106.6 129.93,106.6
GND on BOTTOM (solid shape): 171.34,112 171.66,107 171.75,105.5 169.05,105.5 165.05,109.5 169.05,113.5 171.24,113.5
GND on BOTTOM (solid shape): 5.4,66.25 5.6,65.75 6.1,65.55 6.9,65.55 7.4,65.75 7.6,66.25 7.6,66.75 10.82,66.75 15.21,62.35 15.21,60.7 14.61,60.1 5,60.1 4.79,60.19 4.7,60.4 4.7,64.2 4.5,64.7 4,64.9 0.6,64.9 0.39,64.99 0.3,65.2 0.3,66.45 0.39,66.66 0.6,66.75 5.4,66.75
GND on BOTTOM (solid shape): 116.81,71.19 116.82,71.18 117.04,71.09 117.26,71.19 117.46,71.19 117.68,71.09 117.91,71.19 118.11,71.19 118.33,71.09 118.56,71.19 118.76,71.19 118.98,71.09 119.21,71.19 119.39,71.19 119.59,70.98 119.59,70.96 119.65,70.75 119.82,70.61 119.85,70.6 119.85,70.39 119.82,70.38 119.71,70.32 119.64,70.23 119.53,70.12 119.53,69.87 119.11,69.45 119.07,69.43 119.03,69.42 118.86,69.42 118.39,69.89 118.39,70.25 118.25,70.39 116.79,70.39 116.71,70.4 116.64,70.39 116.23,70.39 116.2,70.42 116.2,70.72 116.01,70.91 116.01,71.33 116.13,71.44 116.55,71.44
GND on BOTTOM (solid shape): 13.88,89.97 13.88,82.1 13.33,81.55 7.6,81.55 7.6,82.05 7.4,82.55 6.9,82.75 6.1,82.75 5.6,82.55 5.4,82.05 5.4,81.55 0.6,81.55 0.39,81.64 0.3,81.85 0.3,83.35 0.39,83.56 0.6,83.65 2,83.65 2.5,83.85 2.7,84.35 2.7,88.6 2.79,88.81 3,88.9 10.05,88.9 10.75,89.5 10.25,90.27 10.25,90.55 13.3,90.55
GND on BOTTOM (solid shape): 126.29,107.82 126.29,107.53 126.25,107.45 126.16,107.43 125.7,107.09 126.16,106.75 126.25,106.74 126.29,106.66 126.29,106.39 126.13,106.23 125.9,106.23 125.76,106.09 125.76,106.07 125.76,106.06 125.76,105.66 126.14,105.52 126.22,105.52 126.29,105.45 126.29,105.05 126.19,104.95 126.12,104.95 125.7,104.57 126.18,104.26 126.21,104.28 126.3,104.18 126.3,103.78 126.21,103.69 125.92,103.69 125.74,103.51 125.74,103.43 125.72,103.33 125.74,103.23 125.74,103.17 125.87,103.04 125.89,103.04 125.9,103.04 126.01,103 126.12,103 126.15,103.01 126.31,102.85 126.31,102.54 126.22,102.45 125.87,102.45 125.69,102.27 125.69,101.89 125.91,101.67 126.19,101.67 126.34,101.53 126.34,101.28 126.2,101.15 124.99,101.15 124.91,101.22 124.91,107.84 125,107.93 126.18,107.93
GND on BOTTOM (solid shape): 12.35,133.28 12.35,131.25 12.73,130.87 13.5,130.87 11.85,129.22 11.85,127.44 9.05,124.65 9.05,119.18 13.88,114.36 13.88,103.69 13.12,102.93 10.25,102.93 10.25,103.43 10.75,104.2 10.05,104.8 2,104.8 1.79,104.89 1.7,105.1 1.7,107.3 1.79,107.51 2,107.6 3.35,107.6 3.85,107.8 4.05,108.3 4.05,114.8 3.85,115.3 3.35,115.5 0.5,115.5 0.29,115.59 0.2,115.8 0.2,126.6 0.29,126.81 0.5,126.9 1.07,126.9 1.55,127.11 1.75,127.6 1.75,131.08 4.95,131.08 6.89,133.03 6.89,133.79 11.85,133.79
GND on BOTTOM (solid shape): 120.47,98.01 120.58,98.01 120.66,97.94 120.66,97.78 120.58,97.71 120.58,97.47 120.58,97.46 120.55,97.32 120.58,97.18 120.58,97.17 120.58,96.92 120.44,96.65 120.57,96.37 120.58,96.35 120.58,96.29 120.57,96.27 120.46,96.01 120.58,95.75 120.58,95.6 120.44,95.46 120.17,95.46 119.72,95 119.45,95 119.24,95.07 119.03,95 118.82,95 118.61,95.07 118.39,95 118.18,95 117.98,95.07 117.77,95.01 117.76,95 117.61,95 117.52,95.09 117.52,95.25 117.75,95.49 117.75,95.71 117.89,95.85 118.14,95.85 118.33,95.78 118.53,95.85 118.79,95.85 118.98,95.78 119.18,95.85 119.44,95.85 119.9,95.94 119.73,96.38 119.72,96.38 119.69,96.4 119.69,96.75 119.73,96.76 119.89,97 119.73,97.24 119.69,97.25 119.69,97.76 119.63,97.82 119.63,97.87 119.85,98.1 120.38,98.1
GND on BOTTOM (solid shape): outline of 240 points within 6.89,0.2 228.2,154.2
GND on IN1 (solid shape): 162.02,78.42 162.02,72.51 161.58,72.07 157.65,72.07 155.36,74.37 155.36,78.42 155.8,78.86 161.58,78.86
GND on IN1 (solid shape): 148.56,137.85 148.56,131.88 147.35,130.68 142.02,130.68 141.77,130.93 141.77,134.68 142.34,135.25 142.34,138.04 142.66,138.36 148.05,138.36
GND on IN1 (solid shape): 160.69,101.02 160.69,96.9 159.99,96.2 159.99,93.52 158.97,92.5 156.72,92.5 155.23,93.99 155.23,101.4 156.37,102.55 159.17,102.55
GND on IN1 (solid shape): 15.13,21.85 15.13,20.59 14.8,20.26 4.99,20.26 4.7,20.55 4.7,22 4.79,22.21 5,22.3 14.69,22.3
GND on IN1 (solid shape): 15.21,45.59 15.21,44.32 14.58,43.68 14.58,38.54 15.13,37.99 15.13,36.72 14.61,36.2 5,36.2 4.79,36.29 4.7,36.5 4.7,45.9 4.79,46.11 5,46.2 14.6,46.2
GND on IN1 (solid shape): 5.4,66.25 5.6,65.75 6.1,65.55 6.9,65.55 7.4,65.75 7.6,66.25 7.6,66.75 10.82,66.75 15.21,62.35 15.21,60.7 14.61,60.1 5,60.1 4.79,60.19 4.7,60.4 4.7,64.2 4.5,64.7 4,64.9 0.6,64.9 0.39,64.99 0.3,65.2 0.3,66.45 0.39,66.66 0.6,66.75 5.4,66.75
GND on IN1 (solid shape): 13.88,89.97 13.88,82.1 13.33,81.55 7.6,81.55 7.6,82.05 7.4,82.55 6.9,82.75 6.1,82.75 5.6,82.55 5.4,82.05 5.4,81.55 0.6,81.55 0.39,81.64 0.3,81.85 0.3,83.35 0.39,83.56 0.6,83.65 2,83.65 2.5,83.85 2.7,84.35 2.7,88.6 2.79,88.81 3,88.9 10.05,88.9 10.75,89.5 10.25,90.27 10.25,90.55 13.3,90.55
GND on IN1 (solid shape): 9.05,130.87 9.05,119.18 13.88,114.36 13.88,103.69 13.12,102.93 10.3,102.93 10.3,103.39 10.79,104.23 10.05,104.85 2,104.85 1.83,104.93 1.75,105.1 1.75,107.3 1.83,107.47 2,107.55 3.35,107.55 3.88,107.77 4.1,108.3 4.1,114.8 3.88,115.33 3.35,115.55 0.5,115.55 0.33,115.63 0.25,115.8 0.25,126.6 0.33,126.77 0.5,126.85 1.05,126.85 1.58,127.07 1.8,127.6 1.8,131.52 1.99,131.7 5.55,131.7 6.05,132.2 7.72,132.2
GND on IN1 (solid shape): outline of 228 points within 9.5,0.2 228.2,154.2
GND on IN2 (solid shape): 162.02,78.42 162.02,72.51 161.58,72.07 157.65,72.07 155.36,74.37 155.36,78.42 155.8,78.86 161.58,78.86
GND on IN2 (solid shape): 148.56,137.85 148.56,131.88 147.35,130.68 142.02,130.68 141.77,130.93 141.77,134.68 142.34,135.25 142.34,138.04 142.66,138.36 148.05,138.36
GND on IN2 (solid shape): 160.69,101.02 160.69,96.9 159.99,96.2 159.99,93.54 158.97,92.52 156.71,92.52 155.23,94 155.23,101.4 156.37,102.55 159.17,102.55
GND on IN2 (solid shape): 15.13,21.85 15.13,20.59 14.8,20.26 4.99,20.26 4.7,20.55 4.7,22 4.79,22.21 5,22.3 14.69,22.3
GND on IN2 (solid shape): 15.21,45.59 15.21,44.32 14.58,43.68 14.58,38.54 15.13,37.99 15.13,36.72 14.61,36.2 5,36.2 4.79,36.29 4.7,36.5 4.7,45.9 4.79,46.11 5,46.2 14.6,46.2
GND on IN2 (solid shape): 5.4,66.25 5.6,65.75 6.1,65.55 6.9,65.55 7.4,65.75 7.6,66.25 7.6,66.75 10.82,66.75 15.21,62.35 15.21,60.7 14.61,60.1 5,60.1 4.79,60.19 4.7,60.4 4.7,64.2 4.5,64.7 4,64.9 0.6,64.9 0.39,64.99 0.3,65.2 0.3,66.45 0.39,66.66 0.6,66.75 5.4,66.75
GND on IN2 (solid shape): 13.88,89.97 13.88,82.1 13.33,81.55 7.6,81.55 7.6,82.05 7.4,82.55 6.9,82.75 6.1,82.75 5.6,82.55 5.4,82.05 5.4,81.55 0.6,81.55 0.39,81.64 0.3,81.85 0.3,83.35 0.39,83.56 0.6,83.65 2,83.65 2.5,83.85 2.7,84.35 2.7,88.6 2.79,88.81 3,88.9 10.05,88.9 10.75,89.5 10.25,90.27 10.25,90.55 13.3,90.55
GND on IN2 (solid shape): 9.05,130.87 9.05,119.18 13.88,114.36 13.88,103.69 13.12,102.93 10.3,102.93 10.3,103.39 10.79,104.23 10.05,104.85 2,104.85 1.83,104.93 1.75,105.1 1.75,107.3 1.83,107.47 2,107.55 3.35,107.55 3.88,107.77 4.1,108.3 4.1,114.8 3.88,115.33 3.35,115.55 0.5,115.55 0.33,115.63 0.25,115.8 0.25,126.6 0.33,126.77 0.5,126.85 1.05,126.85 1.58,127.07 1.8,127.6 1.8,131.52 1.99,131.7 5.55,131.7 6.05,132.2 7.72,132.2
GND on IN2 (solid shape): outline of 228 points within 9.5,0.2 228.2,154.2
GND on TOP: 127.79,66.82 127.79,64.97 127.9,64.86 127.9,63.32 127.74,63.16 127.18,63.16 127.08,63.26 127.08,63.69 126.8,63.97 126.75,63.97 126.57,64.15 126.57,65.32 126.72,65.47 127.1,65.47 127.26,65.62 127.26,66.81 127.29,66.84 127.76,66.84
GND on TOP: 190.89,66.4 190.38,66.92 189.18,66.92 189.09,67.01 189.09,68.52 189.18,68.61 190.15,68.61 190.58,68.18 191.18,68.18 191.92,67.45 193.56,67.45 193.63,67.37 193.63,66.57 193.47,66.4
GND on TOP: 128.46,89.5 125.67,89.5 125.54,89.62 125.54,89.82 125.2,89.82 125.04,89.97 125.04,90.31 124.9,90.45 124.7,90.45 124.61,90.36 124.56,90.31 124.56,90 124.39,89.83 123.92,89.83 123.76,89.98 123.76,90.29 123.61,90.45 123.44,90.45 123.29,90.3 123.29,90.01 123.11,89.83 122.66,89.83 122.48,90.01 122.48,90.31 122.35,90.45 122.15,90.45 122.01,90.31 122.01,89.76 122.09,89.69 122.09,89.2 122.11,89.18 125.36,89.18 125.5,89.04 129.15,89.04 129.22,89.12 129.22,89.36 129.49,89.63 129.73,89.63 129.85,89.75 129.85,89.96 129.72,90.09 129.28,90.09 129.22,90.04 128.59,90.04 128.59,90.03 128.59,89.62
GND on TOP: 24.85,27.87 24.77,27.95 24.77,31.05 24.85,31.12 26.3,31.12 26.45,30.97 26.45,27.97 26.35,27.87
GND on TOP: 87.54,37.27 55.79,37.27 49.44,43.62 27.72,43.62 24.67,46.67 24.67,51.62 26.07,53.02 26.07,54.92 25.56,55.43 22.89,55.43 20.86,53.4 20.86,36.63 23.53,33.97 23.53,32.57 24.8,31.3 26.32,31.3 27.09,32.06 27.09,38.16 28.36,39.43 46.52,39.43 52.99,32.95 87.79,32.95 88.17,33.33 88.17,36.63
GND on TOP: 56.83,56.25 58.17,56.25 58.3,56.12 58.3,54.73 58.17,54.6 56.83,54.6 56.71,54.73 56.71,56.12
GND on TOP: 103.92,61.91 105.06,60.76 105.44,60.76 105.57,60.89 105.57,64.83 105.44,64.96 104.68,64.96 103.92,64.19
GND on TOP: 58.1,51.49 58.1,47.68 57.72,47.3 57.09,47.3 57.03,47.36 57.03,47.87 56.71,48.19 56.71,51.43 56.83,51.55 58.04,51.55
GND on BOTTOM: 121.17,56.2 122.58,56.2 122.61,56.17 122.61,54.88 122.1,54.37 121.26,54.37 121.08,54.54 121.08,56.11
GND on BOTTOM: 124.08,99.56 124.51,99.56 124.67,99.4 124.67,96.13 123.75,95.21 123.75,94.93 123.98,94.7 124.54,94.7 124.61,94.63 124.61,94.48 124.54,94.4 124,94.4 123.55,94.86 123.01,94.86 122.94,94.93 122.94,95.11 123.37,95.54 123.37,97.91 123.78,98.31 123.78,99.25
GND on BOTTOM: 123.6,68.67 123.26,68.41 123.52,68.07 123.54,68.06 123.63,67.99 123.63,67.97 123.66,67.87 123.73,67.78 123.73,67.63 123.62,67.53 123.32,67.53 122.87,67.97 122.49,67.97 122.3,67.78 122.3,66.76 122.24,66.7 122.05,66.7 121.73,67.02 121.73,67.84 122.04,68.16 122.04,68.76 122.19,69.02 122.04,69.28 122.04,69.35 121.92,69.48 121.8,69.48 121.79,69.51 121.47,69.7 121.15,69.51 121.14,69.48 120.95,69.48 120.86,69.56 120.86,69.73 121.19,70.05 121.2,70.05 121.74,70.05 121.75,70.05 122.18,70.23 121.93,70.62 121.92,70.62 121.82,70.72 121.79,70.8 121.79,71.16 121.81,71.22 121.83,71.3 121.87,71.34 121.89,71.34 122.03,71.38 122.13,71.48 122.14,71.49 122.31,71.63 122.33,71.63 122.48,71.68 122.58,71.79 123.11,71.79 123.23,71.68 123.23,69.6 123.28,69.56 123.28,69.55 123.39,69.42 123.54,69.37 123.56,69.36 123.63,69.29 123.63,69.28 123.68,69.15 123.76,69.05 123.76,68.98 123.66,68.84 123.63,68.67
GND on BOTTOM: 59.22,43.24 56.68,45.78 56.68,74.1 55.79,74.99 55.79,112.58 58.45,115.25 89.06,115.25 90.08,114.23 90.08,53.02 88.3,51.24 88.3,48.19 89.44,47.05 89.44,43.37 89.32,43.24 ; 3 cut-outs
GND on BOTTOM: 113.58,99.81 113.58,100.64 113.7,100.77 114.33,100.77 114.59,100.52 114.59,100.13 114.43,99.98 114.31,99.98 114.21,99.88 114.21,99.68 114.1,99.57 113.81,99.57
GND on BOTTOM: 144.34,60.45 144.46,60.57 146.19,60.57 146.88,59.88 146.88,59.11 146.45,58.68 144.48,58.68 144.34,58.83
GND on VCC: 11.67,1.17 11.67,4.5 12.84,4.5 12.99,4.65 12.99,6.23 13.17,6.41 13.68,6.41 14.06,6.79 14.53,6.79 14.66,6.66 27.7,6.66 29.37,8.34 29.37,10.71 28.97,11.11 27.74,11.11 27.34,10.71 27.34,9.82 26.34,8.82 23.19,8.82 23.02,8.99 23.02,11 23.13,11.11 25.03,11.11 25.54,11.62 27.19,11.62 27.59,12.02 27.59,15.32 27.7,15.43 32.27,15.43 35.19,18.35 40.03,18.35 40.03,6.27 36.6,6.27 35.42,5.78 34.93,4.6 34.93,1.17
GND on VCC: 135.71,88.96 135.04,89.64 135.04,95.01 136.35,96.32 137.09,96.32 137.32,96.09 137.32,89.83 136.45,88.96
GND on VCC: 215.53,31.05 213.5,33.08 211.62,33.08 211.62,37.16 213.63,39.17 219.11,39.17 219.11,31.41 218.75,31.05
GND on VCC: 160.54,61.65 160.31,61.89 160.31,63.83 160.67,64.19 163.63,64.19 163.86,63.96 163.86,62.01 163.5,61.65
GND on VCC: outline of 166 points within 1.17,18.6 130.72,153.23 ; 1 cut-out
GND on VCC: 184.54,48.45 182.13,50.86 187.13,50.86 187.74,50.25 187.74,48.81 187.38,48.45
GND on VCC: 146.19,32.06 145.17,33.08 134.15,33.08 134.15,37.93 137.05,40.83 151.95,40.83 153.45,39.32 153.45,32.93 152.58,32.06
GND on VCC: 43.85,54.41 43.85,58.46 43.45,58.86 41.54,58.86 41.31,59.09 41.31,63.33 42.18,64.19 47.3,64.19 48.04,63.45 48.04,54.9 47.55,54.41
GND on GND: outline of 276 points within 0.2,0.2 228.2,154.2
VCC_CPU on BOTTOM (solid shape): 148.22,112.94 148.22,112.86 147.54,112.18 146.27,112.18 146.02,111.93 146.02,111.1 145.83,110.91 145.32,110.91 145.32,112.69 147.04,112.69 147.35,113.01 148.15,113.01
VCCGT_B+ on TOP (solid shape): 147.42,140.93 147.42,139.25 147.16,139 143.2,139 142.91,138.7 142.91,135.57 142.78,135.44 140.89,135.44 140.63,135.7 140.63,140.9 141.07,141.34 147.01,141.34
VCCGT_B+ on BOTTOM (solid shape): 142.36,142.81 149.96,142.81 150.66,142.11 150.66,139.16 152.05,137.77 152.05,134.87 151.74,134.55 149.2,134.55 148.88,134.87 148.88,138.55 148.12,139.31 143.35,139.31 142.91,138.87 142.91,135.19 142.66,134.93 142.66,132.27 141.51,132.27 141.51,133.54 141.26,133.79 140.38,133.79 139.8,134.36 139.8,135.06 139,135.86 139,141.74 140.09,142.83 142.33,142.83
VCCSA_B+ on TOP (solid shape): 167.48,58.35 167.48,57.65 167.36,57.53 165.26,57.53 165.07,57.72 165.07,58.35 165.26,58.54 167.29,58.54
VCCSA_B+ on TOP (solid shape): 169.07,65.84 169.07,65.15 168.88,64.96 165.96,64.96 165.83,65.08 165.83,66.48 165.9,66.54 168.37,66.54
VCCSA_B+ on BOTTOM (solid shape): 167.55,58.71 167.55,57.78 167.29,57.53 164.31,57.53 164.12,57.72 164.12,58.67 164.18,58.73 167.52,58.73
VCCSA_B+ on BOTTOM (solid shape): 168.31,66.99 168.31,63.84 168.22,63.75 167.64,63.75 166.92,63.03 164.38,63.03 164.35,63.06 164.35,63.6 164.36,63.61 164.95,63.61 165.07,63.73 165.07,64.3 165.39,64.62 165.39,67.11 165.77,67.5 167.8,67.5
VDD10 on TOP (solid shape): 19.97,92.2 19.97,91.44 19.78,91.24 18.45,91.24 18.32,91.37 18.32,92.26 18.51,92.45 19.72,92.45
VDD10 on TOP (solid shape): 24.48,92.71 24.48,92.45 24.23,92.2 24.23,89.4 24.16,89.34 24.16,88.32 23.99,88.15 23.99,87.3 23.95,87.26 23.82,87.26 23.77,87.31 23.77,89.1 23.4,89.47 23.4,92.71 23.53,92.83 24.35,92.83
VDD10 on TOP (solid shape): 22.83,85.09 22.83,84.95 22.79,84.91 21.74,84.91 21.41,84.58 21.41,83.84 21.18,83.6 19.93,83.6 19.88,83.65 19.88,84.26 19.95,84.32 20.68,84.32 21.48,85.12 22.79,85.12
VDD10 on BOTTOM (solid shape): 24.48,93.53 24.48,92.45 24.29,92.26 23.4,92.26 23.15,92.51 20.54,92.51 19.27,91.24 18.45,91.24 18.32,91.37 18.32,93.09 19.08,93.85 24.16,93.85
VDD10 on IN1: 23.77,80.61 20.94,83.43 20.94,91.96 21.88,92.9 24.42,92.9 24.56,92.76 24.56,92.3 23,90.74 23,84.36 23.97,83.38 26.51,83.38 26.77,83.13 26.77,80.77 26.61,80.61 ; 1 cut-out
VDD_1.2V on TOP (solid shape): 92.42,131.47 92.42,130.74 92.05,130.36 91.42,130.36 91.26,130.53 91.26,131.86 91.28,131.88 92.01,131.88
VDD_1.2V on BOTTOM (solid shape): 94.01,132.01 94.01,131.94 93.45,131.38 93.22,131.38 92.2,130.36 91.42,130.36 91.26,130.52 91.26,130.61 91.26,130.61 91.26,130.79 91.26,130.79 91.26,131.86 91.3,131.9 92.9,131.9 93.08,132.08 93.94,132.08
VDD_CHG on BOTTOM (solid shape): 197.32,50.18 197.52,50.12 197.71,50.18 198.74,50.18 198.78,50.15 198.78,50 198.73,49.94 197.58,49.94 196.72,49.08 195.3,49.08 195.23,49.14 195.23,49.72 195.3,49.78 196.78,49.78 197.18,50.18
VDDP_CHG on BOTTOM (solid shape): 196.12,50.6 198.73,50.6 198.78,50.55 198.78,50.4 198.73,50.35 197.14,50.35 196.82,50.03 195.3,50.03 195.23,50.1 195.23,50.6 195.3,50.67 196.06,50.67
VDDREG on TOP (solid shape): 23.21,90.8 23.21,89.4 23.59,89.02 23.59,87.31 23.54,87.26 23.41,87.26 23.35,87.32 23.35,88.63 21.75,90.23 21.31,90.23 21.31,90.86 23.15,90.86
+DC_IN on TOP: 170.62,104.83 171.48,91.44 173.53,83.43 178.39,76.72 178.41,76.71 178.41,67.04 178.01,66.68 178.41,66.33 178.41,65.54 178.44,65.5 179.21,65.5 179.23,65.48 179.23,64.19 178.85,63.81 178.85,59.62 178.47,59.24 174.02,59.24 173.64,58.86 173.52,58.86 173.26,59.11 173.26,74.54 166.84,80.97 166.84,98.18 159.22,105.8 159.22,112 159.61,112.39 159.61,115.69 164.85,120.93 167.8,120.93 168.4,120.33 168.44,120.33 168.44,114.08 164.86,110.51 164.86,107.77 167.45,105.19 170.27,105.19
+DC_IN on TOP: 98.84,147.65 96.55,147.65 96.33,147.43 96.33,143.7 96.83,143.19 100.23,143.19 101.31,144.26 101.86,144.26 102.55,144.95 102.55,148.44 102.18,148.81 100,148.81
+DCBAT_LCD on TOP (solid shape): 215.3,61.02 215.3,59.37 215.17,59.24 213.27,59.24 213.01,59.49 213.01,60.89 213.39,61.27 215.05,61.27
+DCBAT_LCD on BOTTOM (solid shape): 214.22,60.51 214.22,59.06 213.95,58.79 211.88,58.79 211.37,58.29 211.36,58.29 211.36,55.94 210.73,55.3 208.82,55.3 208.7,55.43 208.7,58.42 208.95,58.67 209.39,58.67 211.43,60.7 214.03,60.7
+FP_VCC on BOTTOM: 217.54,32.68 217.54,32.57 217.15,32.19 217.15,30.36 216.86,30.07 215.53,30.07 215.34,29.88 215.34,29.07 215.48,28.93 217.81,28.93 218.16,29.28 218.16,31.79 218.26,31.88 218.26,32.64 218.17,32.74 217.6,32.74
+LAN_VDD33 on TOP (solid shape): 22.45,98.37 22.96,98.37 22.96,98.93 24.86,98.93 25.18,98.61 25.18,95.18 22.26,92.26 22.26,91.69 22.13,91.56 21.37,91.56 21.24,91.69 21.24,93.53 22.45,94.74 22.45,97.09 22.07,97.47 22.07,98.8 22.2,98.93 22.45,98.93
+LAN_VDD33 on TOP (solid shape): 22.83,84.27 22.83,84.14 22.58,83.89 22.58,82.91 21.62,81.96 21.62,80.58 21.24,80.2 19.97,80.2 19.85,80.32 19.85,82.1 19.97,82.23 20.91,82.23 22.12,83.43 22.12,84.04 21.99,84.17 21.99,84.27 22.04,84.32 22.78,84.32
+LAN_VDD33 on IN1 (solid shape): 23.53,94.38 23.53,93.4 23.28,93.15 21.75,93.15 20.86,92.26 20.83,92.29 20.27,92.11 20.64,91.65 20.72,91.63 20.75,91.55 20.75,87.73 20.73,87.7 20.7,87.68 20.38,87.33 20.7,86.97 20.73,86.96 20.75,86.92 20.75,85.34 20.7,85.33 20.39,84.98 20.7,84.63 20.75,84.62 20.75,82.34 21.62,81.47 21.62,80.7 21.37,80.45 20.23,80.45 19.34,81.34 19.34,88.58 18.89,89.02 18.89,91.25 19,91.5 18.89,91.75 18.89,91.95 19,92.2 18.89,92.45 18.89,94.06 19.59,94.76 23.15,94.76
+LAN_VDD33 on IN2 (solid shape): 21.75,82.35 21.75,80.58 21.62,80.45 21.12,80.45 20.99,80.58 20.99,82.35 21.12,82.48 21.62,82.48
+LCDVDD on TOP (solid shape): 220.44,56.87 220.44,55.48 220.25,55.29 218.28,55.29 218.16,55.41 218.16,56.87 218.28,57 220.32,57
+LCDVDD_LCD on TOP (solid shape): 217.33,57.95 217.33,55.54 217.27,55.48 216.44,55.48 216.32,55.6 216.32,56.11 216.19,56.24 214.09,56.24 213.9,56.43 213.9,57.95 214.09,58.14 217.14,58.14
+LCDVDD_LCD on BOTTOM (solid shape): 215.17,57.84 215.17,57.01 214.94,56.79 211.9,56.79 211.82,56.86 211.82,57.57 211.89,57.64 213.16,57.64 213.61,58.1 214.92,58.1
+TPAN_VDD on TOP (solid shape): 217.71,46.39 217.71,43.06 217.58,42.93 217.58,42.27 217.08,41.77 217.08,40.65 216.69,40.25 212.07,40.25 209.92,42.41 209.92,43.19 209.98,43.25 210.62,43.25 210.79,43.08 210.79,42.49 212.05,41.22 215.45,41.22 215.71,41.48 215.71,46.19 215.93,46.41 217.69,46.41
+TPAN_VDD on BOTTOM (solid shape): 213.01,41 214.16,41 214.28,40.87 214.28,40.49 214.09,40.3 212,40.3 211.81,40.49 211.81,41 211.93,41.13 212.89,41.13
+TPAN_VDD_F on TOP (solid shape): 222.93,47.72 222.93,43.23 222.91,43.2 220.74,43.2 220.38,42.84 220.38,41.68 220.27,41.57 218.49,41.57 218.23,41.3 218.23,40.89 218.2,40.86 217.31,40.86 217.31,40.87 217.25,40.87 217.21,40.9 217.21,41.7 217.71,42.2 217.71,42.22 217.71,42.83 217.74,42.86 218.04,42.86 221.14,45.96 221.14,46.38 221.16,46.4 221.65,46.4 221.9,46.65 221.9,47.67 222.03,47.79 222.86,47.79
+TPAN_VDD_F on TOP: 210.6,44.79 209.84,44.79 209.71,44.66 208.9,44.66 208.64,44.92 208.64,46.16 209.53,47.05 210.1,47.05 210.69,47.63 211.26,47.63 211.41,47.48 211.41,47 211.26,46.85 210.68,46.85 210.6,46.77 210.6,45.83 210.8,45.63 210.8,44.99
AUD_AGND on VCC: 11.62,5.01 11.02,5.92 10,6.27 3.52,6.27 3.52,7.58 13.55,7.58 15.1,8.62 14.72,10.44 14.72,14.86 15.1,16.68 13.55,17.72 3.52,17.72 3.52,17.78 4,17.78 5.18,18.27 5.67,19.45 5.67,19.74 15.04,19.74 16.69,18.09 18.05,18.09 19.59,19.64 19.59,22.69 20.21,23.3 21.48,23.3 22.49,24.32 26.73,24.32 27.23,23.81 32.57,23.81 33.44,22.94 33.44,18.62 33.71,18.35 34.2,18.35 34.2,18.07 32.06,15.93 27.49,15.93 27.09,15.53 27.09,12.23 26.98,12.12 25.33,12.12 24.82,11.62 22.92,11.62 22.51,11.21 22.51,8.78 22.98,8.31 26.56,8.31 27.85,9.61 27.85,10.49 27.95,10.6 28.76,10.6 28.86,10.49 28.86,8.55 27.49,7.17 14.66,7.17 14.53,7.04 13.95,7.04 13.57,6.66 13.06,6.66 12.73,6.33 12.73,5.01
AUD_AGND on GND: 10.58,5 10.33,5.22 10,5.3 2.85,5.3 2.64,5.39 2.55,5.6 2.55,8.25 2.64,8.46 2.85,8.55 13.55,8.55 14.25,9.15 13.75,9.92 13.75,15.38 14.25,16.15 13.55,16.75 2.85,16.75 2.64,16.84 2.55,17.05 2.55,18.45 2.64,18.66 2.85,18.75 4,18.75 4.5,18.95 4.7,19.45 4.7,19.74 15.04,19.74 16.69,18.09 18.05,18.09 19.59,19.64 19.59,22.69 20.21,23.3 21.48,23.3 22.49,24.32 26.73,24.32 27.23,23.81 32.57,23.81 33.44,22.94 33.44,18.62 33.71,18.35 34.2,18.35 34.2,18.07 32.06,15.93 27.49,15.93 27.09,15.53 27.09,12.23 26.98,12.12 25.33,12.12 24.82,11.62 22.92,11.62 22.51,11.21 22.51,8.84 23.04,8.31 26.56,8.31 27.85,9.61 27.85,10.49 27.95,10.6 28.76,10.6 28.86,10.49 28.86,8.55 27.49,7.17 14.66,7.17 14.53,7.04 13.95,7.04 13.57,6.66 13.06,6.66 12.73,6.33 12.73,5.01 10.6,5.01
AUD_SPK_L+ on TOP (solid shape): 29.72,10.58 29.72,7.45 29.64,7.37 28.87,7.37 28.83,7.41 28.83,7.84 29.47,8.47 29.47,10.6 29.51,10.65 29.65,10.65
AUD_SPK_L+_C on TOP (solid shape): 29.72,7.12 29.72,6.51 29.66,6.44 29.66,5.76 29.34,5.44 29.34,4.5 29.28,4.43 28.42,4.43 28.3,4.55 28.3,5.37 28.41,5.48 28.59,5.48 28.7,5.59 28.7,7.03 28.71,7.03 28.71,7.08 29.29,7.08 29.39,7.18 29.66,7.18
AUD_SPK_L+_C on BOTTOM (solid shape): 14.7,6.51 14.7,4.83 15.25,4.27 15.25,3.37 15.16,3.28 14.64,3.28 14.41,3.51 14.41,4.33 14.08,4.66 14.08,6.48 14.28,6.68 14.53,6.68
AUD_SPK_L+_C on IN2 (solid shape): 28.76,5.35 28.76,4.55 28.52,4.31 27.53,4.31 27.15,4.69 27.15,4.91 27.73,5.49 28.62,5.49
AUD_SPK_L+_C on TOP: 14.54,4.5 14.54,3.61 14.89,3.27 16.1,3.27 16.24,3.14 17.18,3.14 17.37,3.33 17.37,4.44 16.99,4.82 14.86,4.82
AUD_SPK_L+_C on IN2: 18.45,4.23 16.24,4.23 16.15,4.14 16.15,3.3 16.27,3.18 18.43,3.18 18.53,3.27 18.53,4.16
AUD_SPK_L- on TOP (solid shape): 30.09,10.59 30.09,8.84 30.86,8.07 30.86,7.46 30.78,7.38 29.97,7.38 29.87,7.48 29.87,10.62 29.9,10.65 30.04,10.65
AUD_SPK_L-_C on TOP (solid shape): 30.86,7.15 30.86,6.64 30.61,6.39 30.61,4.74 30.29,4.42 29.56,4.42 29.47,4.52 29.47,5.31 29.78,5.63 29.78,6.39 29.91,6.52 29.91,7.22 30.8,7.22
AUD_SPK_L-_C on BOTTOM (solid shape): 13.7,6.55 13.7,4.48 13.97,4.2 13.97,3.44 13.77,3.24 13.24,3.24 13.18,3.3 13.18,3.74 13.05,3.87 13.05,6.53 13.24,6.72 13.53,6.72
AUD_SPK_L-_C on IN2 (solid shape): 29.96,5.39 29.96,3.41 29.73,3.18 29.03,3.18 28.9,3.31 28.9,5.35 29.04,5.49 29.85,5.49
AUD_SPK_L-_C on TOP: 14.15,4.27 14.15,3.6 14.87,2.88 16.98,2.88 17.2,2.66 17.2,1.94 16.47,1.21 14.65,1.21 13.4,2.46 13.4,4.32 13.55,4.47 13.95,4.47
AUD_SPK_L-_C on IN2: 15.4,1.17 15.32,1.25 15.32,2.59 15.54,2.81 17.43,2.81 17.54,2.7 17.54,1.87 17.47,1.8 16.65,1.8 16.54,1.69 16.54,1.21 16.5,1.17
AUD_SPK_R+ on TOP (solid shape): 30.93,10.56 30.93,9.69 30.93,9.67 31.65,8.94 31.65,8.83 31.5,8.68 31.31,8.68 30.67,9.32 30.67,10.61 30.72,10.65 30.83,10.65
AUD_SPK_R+ on TOP (solid shape): 27.75,2.66 30.9,2.66 31.1,2.46 31.1,1.98 30.77,1.65 27.22,1.65 26.51,2.35 26.51,3.17 26.54,3.2 27.21,3.2
AUD_SPK_R+ on IN2 (solid shape): 32.45,2.5 32.45,1.93 32.2,1.68 30.16,1.68 29.97,1.87 29.97,2.44 30.16,2.63 32.32,2.63
AUD_SPK_R+ on IN2 (solid shape): 32.74,9.46 32.74,9.08 32.29,8.63 31.36,8.63 30.77,9.23 30.77,9.52 30.96,9.71 32.48,9.71
